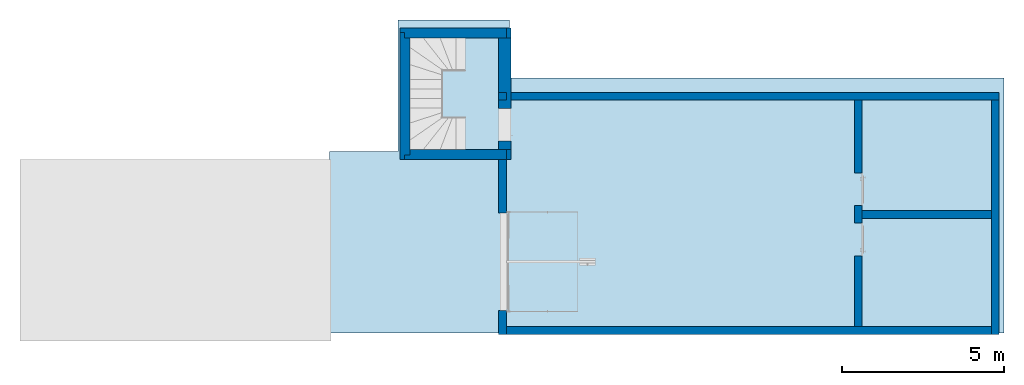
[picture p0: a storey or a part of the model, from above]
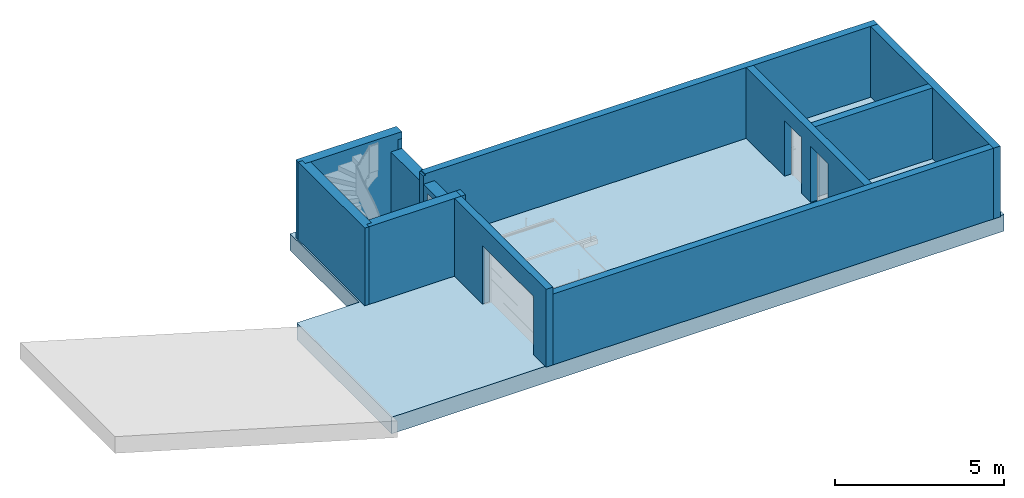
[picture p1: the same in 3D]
Properties of the parts of a building model (IFC4), part 1 of 13

# File
Description: ViewDefinition [Reference_View, SurfaceGeometryAddOnView, QuantityTakeOffAddOnView, SpaceBoundary2ndLevelAddOnView], Option [Drawing Scale: 100.000000], Option [Global Unique Identifiers (GUID): Keep existing], Option [Elements to export: Visible elements (on all stories)], Option [Partial Structure Display: Entire Model], Option [IFC Domain: All], Option [Structural Function: All Elements], Option [Convert Grid elements: On], Option [Convert IFC Annotations and ARCHICAD 2D elements: Off], Option [Convert 2D symbols of Doors and Windows: Off], Option [Explode Composite and Complex Profile elements into parts: Off], Option [Export geometries that Participates in Collision Detection only: On], Option [Triangulate Surfaces: On], Option [Use legacy geometric methods as in Coordination View 1.0: Off], Option [IFC Site Geometry: As boundary representation (BRep)], Option [IFC Site Location: At Project Origin], Option [Curtain Wall export mode: Single Element], Option [Railing export mode: Single Element], Option [Stair export mode: Single Element], Option [Properties To Export: All properties], Option [Space containment: On], Option [IFC Domain For Space Containment: All], Option [Bounding Box: Off], Option [Geometry to type objects: Off], Option [Element Properties: All], Option [Building Material Properties: On], Option [Element Parameters: All], Option [Component Parameters: All], Option [IFC Base Quantities: On], Option [Door Window Parameters: On], Option [IFC Space boundaries: On], Option [ARCHICAD Zone Categories as IFC Space classification data: On], Option [Element Classifications: On]
File name: C:\Users\andrev\sciebo\Research\Modelldummies CORE-RUB\2019-11-27_HVNL_Archicad_plaziert_AV_V15.ifc
Time: 2020-08-10T08:01:26
Author: Wegner L
Organization: Core architecture
Written by: The EXPRESS Data Manager Version 5.02.0100.09 : 26 Sep 2013
Made in: IFC file generated by GRAPHISOFT ARCHICAD-64 22.0.0 GER FULL Windows version (IFC add-on version: 7000 GER FULL).
Authorization: Wegner L

# IfcProject, Haus vom Nikolaus
Description: Büro Austauschprojekt
BauantragAllgemein - Bezeichnung des Bauvorhabens: Haus vom Nikolaus; Art des Gebäudes: 6122; Sonderbau: 23; Gebäudeklasse: 3; Art der Maßnahme: 1; Bauweise: 2

# IfcSite, Gelände
RefLatitude: 53, 33, 57, 464000; RefLongitude: 10, 5, 52, 995000; RefElevation: 16 m
BauantragGeokodierung - Flure: 0; Flurstücke: 0; Gemarkungen: keine
BaseQuantities - GrossPerimeter: 0 m; GrossArea: 0 m2

# IfcBuilding, Haus vom Nikolaus
Description: Zweifamilienhaus
BaseQuantities - GrossFloorArea: 2665.17 m2

# IfcBuildingStorey (3)
In: Haus vom Nikolaus
Name | Elevation (m) | NetHeight (m) = GrossHeight (m) = Height (m) | GrossFloorArea (m2)
-1. Geschoss | -2.8 | 2.8 | 1183.27
EG | 0 | 3.75 | 1047.56
1. OG | 3.75 | 2.55 | 434.338

# IfcSpace: Brutto-Grundfläche Regelfall (15)
Classification: Raum (ARCHICAD Klassifizierung); 0 BGFr Brutto-Grundfläche Regelfall
Pset_SpaceCommon - Category: Brutto-Grundfläche Regelfall
ArchiCADProperties - Bibliothekselement-Name: Raumstempel DIN 22; Geschützt: no; Typ: Raum; Oberfläche (Alle): Raumstempel; Deckschraffur: Misch-Schraffur 0%; Anzeigen auf Umbau-Filter: Alle relevanten Filter; Umbau-Status: Bestand; Oberfläche: Raumstempel; Einheitliche Oberfläche: yes; Raumkategorie: 0; Raumflächen-Code: 0 BGFr; ARCHICAD Klassifizierung - 22: Raum
AC_Pset_Raumstempel_DIN_22 - Textstil 1 (Grundeinstellung): 0; Markertext 1 Zeilenabstand (Standard): 1; Markertext 1 Zeichenbreite-Faktor (Standard): 1; Markertext 1 Textzeichenbreite-Faktor (Standard): 1; Schriftart 1: Arial Westlich; Wandabzugsfläche: 0; Fassaden- Abzugsfläche: 0; Stützenabzugsfläche: 0; Schraffurabzugsfläche: 0; Abzugsfläche unter Dach: 0; Gesamtabzugsfläche: 0; Raumfläche Faktor: 1; Dach Oberflächenbereich an der Oberseite: 0; Dach Oberflächenbereich an der Unterseite: 0; Decke Oberflächenbereich an der Oberseite: 0; Decke Oberflächenbereich an der Unterseite: 0; Unterzug Oberflächenbereich an der Oberseite: 0; Unterzugoberfläche unten: 0; Oberer Oberflächenbereich der Wandeinsätze: 0; Oberfläche Wandnischen hinten: 0; Seite Oberflächenbereich der Wandeinsätze: 0; Maßstab (displayScale): 1:100; Maßstab (iDisplayScale): 2; Raumname zeigen (bShowZoneNameLine1_50): yes; Raumnummer zeigen (bShowZoneNum_50): yes; Raumkategorie-Code zeigen (bShowZoneCatCode_50): no; 2. Raumnamen-Zeile zeigen (bShowZoneNameLine2_50): no; Einheitennummer zeigen (bShowApartmentID_50): yes; Einheitenname zeigen (bShowApartmentName_50): yes; Zeige Apartment Identifikation (bShowApartmentCode_50): no; Zeige Treppenhaus Identifikatoren (bShowStaircaseCode_50): no; Position zeigen (bShowPosition_50): no; Hausnummer zeigen (bShowHouseNumber_50): no; Funktion zeigen (bShowFunctions_50): no; ID zeigen (bShowID_50): no; Wandbelag zeigen (bShowWallFinish_50): no; Raumunterkante zeigen (bShowHeightZone_50): yes; Fertigfußbodenhöhe zeigen (bShowHeightFloor_50): yes; Abzugsflächen zeigen (bShowMeasuredArea_50): no; Gemessene Nettofläche zeigen (bShowMeasuredNetArea_50): yes; DIN Abzugsflächen zeigen (bShowVentArea_50): no; Reduzierte Fläche zeigen (bShowReducedArea_50): no; Berechnete Fläche (NRF) zeigen (bShowCalculatedArea_50): yes; Fensterflächen zeigen (bShowWindowArea_50): no; Raumumfang zeigen (bShowPerimeter_50): no; Raumhöhe zeigen (bShowCeilingHeight_50): yes; Raumvolumen zeigen (bShowVolume_50): no; Einordnung zeigen (bShowClassification_50): no; Eigenen Text zeigen 1 (bShowCustom1_50): no; Eigenen Text zeigen 2 (bShowCustom2_50): no; Eigenen Text zeigen 3 (bShowCustom3_50): no; Klassifizierung und Eigenschaften anzeigen (bShowAdditionalTags_50): yes; Parameter auswählen (iTnCSelectParams_50): 1; Daten darstellen nach (iTncDisplayData_50): 1; 1. Zeile Parameternamen zeigen als (iRow1CustomName_50): 1; 2. Zeile Parameternamen zeigen als (iRow2CustomName_50): 1; 3. Zeile Parameternamen zeigen als (iRow3CustomName_50): 1; 4. Zeile Parameternamen zeigen als (iRow4CustomName_50): 1; 5. Zeile Parameternamen zeigen als (iRow5CustomName_50): 1; 6. Zeile Parameternamen zeigen als (iRow6CustomName_50): 1; 7. Zeile Parameternamen zeigen als (iRow7CustomName_50): 1; 8. Zeile Parameternamen zeigen als (iRow8CustomName_50): 1; 9. Zeile Parameternamen zeigen als (iRow9CustomName_50): 1; 10. Zeile Parameternamen zeigen als (iRow10CustomName_50): 1; 11. Zeile Parameternamen zeigen als (iRow11CustomName_50): 1; 12. Zeile Parameternamen zeigen als (iRow12CustomName_50): 1; 13. Zeile Parameternamen zeigen als (iRow13CustomName_50): 1; 14. Zeile Parameternamen zeigen als (iRow14CustomName_50): 1; 15. Zeile Parameternamen zeigen als (iRow15CustomName_50): 1; 16. Zeile Parameternamen zeigen als (iRow16CustomName_50): 1; 17. Zeile Parameternamen zeigen als (iRow17CustomName_50): 1; 18. Zeile Parameternamen zeigen als (iRow18CustomName_50): 1; 19. Zeile Parameternamen zeigen als (iRow19CustomName_50): 1; 20. Zeile Parameternamen zeigen als (iRow20CustomName_50): 1; Inhalt zum Überschreiben (iContentToOverride_50): 1; Raumname Stift (penTitle_50): Elemente+Text; Raumname Stift (penTitle_50_int): 1; Überschreiben Titel 2 Textformat (bOverrideTitle2TextFormat_50): no; Raumnummer Font Größe (mm) (fontTitle2SizePaper_50): 2.5; Raumnummer Font-Stil (iTextStyleTitle2_50): 0; Raumnummer Stift (penTitle2_50_int): 1; Überschreiben Daten-Textformat (bOverrideDataTextFormat_50): no; Daten-Schrifttyp (iTextStyleData_50): 0; Daten-Stift (penData_50_int): 1; Schriftgröße (fontScaleType_50): Papiergröße; Schriftgröße (iFontScaleType_50): 2; Automat. Zeilenabstand (bAutomaticLineSpace_50): yes; Zeilenabstand in mm (lineSpacing_50): 4; Bemaßungseinheiten zeigen (bShowDimensionUnits_50): yes; Hochgestellt (bShowSuperScript_50): yes; Rahmen Stil (sFrameStyle_50): Stil 4; Rahmen Stil (iFrameStyle_50): 5; Feste Breite (bFixWidth_50): no; Breite in mm speichern (fixWidth_50): 50; Numerische Werte ausrichten (sAlignNumericalValues_50): Rechtsbündig; Numerische Werte ausrichten (iAlignNumericalValues_50): 4; Textwerte ausrichten (iAlignStringValues_50): 4; Raumnummer ausrichten (iAlignZoneNr_50): 1; Fester Radius (bFixRadius_50): no; Kreisrahmen Radius in mm (frameRadius_50): 3; Rahmen-Stift (framePen_50): Elemente+Text; Linientyp Rahmen (frameLineType_50): 1; Einheitennummer Rahmen (apartmentIdFrame_50): Oval; Einheitennummer Rahmen (iApartmentIdFrame_50): 2; Hintergrundschraffur (bBackFill_50): yes; Schraffur (fillType_50): Nur Hintergrund-Stift; Schraffur-Vordergrundstift (fillPen_50): Elemente+Text; Schraffur-Hintergrundstift (fillBackPen_50): Transparent; Einheitennummer Winkel in 1:50: 0 deg; Höhenwerte und Raumnummer Anzeigetyp (iDisplayType_50): 2; 1. (order_01_50): Raumname; 1. (iOrder_01_50): 2; 4. (order_04_50): Beläge; 4. (iOrder_04_50): 6; 12. (order_12_50): ** Leere Zeile; 12. (iOrder_12_50): 1; Raumname zeigen (bShowZoneNameLine1_100): yes; Raumnummer zeigen (bShowZoneNum_100): yes; Raumkategorie-Code zeigen (bShowZoneCatCode_100): no; Zeige Apartment Identifikation (bShowApartmentCode_100): no; Zeige Treppenhaus Identifikatoren (bShowStaircaseCode_100): no; Position zeigen (bShowPosition_100): no; Hausnummer zeigen (bShowHouseNumber_100): no; Funktion zeigen (bShowFunctions_100): no; ID zeigen (bShowID_100): no; Bodenbelag zeigen (bShowFloor_100): no; Wandbelag zeigen (bShowWallFinish_100): no; Deckenbelag zeigen (bShowCeiling_100): no; Raumunterkante zeigen (bShowHeightZone_100): no; Fertigfußbodenhöhe zeigen (bShowHeightFloor_100): no; Abzugsflächen zeigen (bShowMeasuredArea_100): no; Gemessene Nettofläche zeigen (bShowMeasuredNetArea_100): no; DIN Abzugsflächen zeigen (bShowVentArea_100): no; Reduzierte Fläche zeigen (bShowReducedArea_100): no; Berechnete Fläche (NRF) zeigen (bShowCalculatedArea_100): yes; Fensterflächen zeigen (bShowWindowArea_100): no; Raumumfang zeigen (bShowPerimeter_100): no; Raumhöhe zeigen (bShowCeilingHeight_100): no; Raumvolumen zeigen (bShowVolume_100): no; Einordnung zeigen (bShowClassification_100): no; Eigenen Text zeigen 1 (bShowCustom1_100): no; Eigenen Text zeigen 2 (bShowCustom2_100): no; Eigenen Text zeigen 3 (bShowCustom3_100): no; Parameter auswählen (iTnCSelectParams_100): 1; Daten darstellen nach (iTncDisplayData_100): 1; 1. Zeile Parameternamen zeigen als (iRow1CustomName_100): 1; 2. Zeile Parameternamen zeigen als (iRow2CustomName_100): 1; 3. Zeile Parameternamen zeigen als (iRow3CustomName_100): 1; 4. Zeile Parameternamen zeigen als (iRow4CustomName_100): 1; 5. Zeile Parameternamen zeigen als (iRow5CustomName_100): 1; 6. Zeile Parameternamen zeigen als (iRow6CustomName_100): 1; 7. Zeile Parameternamen zeigen als (iRow7CustomName_100): 1; 8. Zeile Parameternamen zeigen als (iRow8CustomName_100): 1; 9. Zeile Parameternamen zeigen als (iRow9CustomName_100): 1; 10. Zeile Parameternamen zeigen als (iRow10CustomName_100): 1; 11. Zeile Parameternamen zeigen als (iRow11CustomName_100): 1; 12. Zeile Parameternamen zeigen als (iRow12CustomName_100): 1; 13. Zeile Parameternamen zeigen als (iRow13CustomName_100): 1; 14. Zeile Parameternamen zeigen als (iRow14CustomName_100): 1; 15. Zeile Parameternamen zeigen als (iRow15CustomName_100): 1; 16. Zeile Parameternamen zeigen als (iRow16CustomName_100): 1; 17. Zeile Parameternamen zeigen als (iRow17CustomName_100): 1; 18. Zeile Parameternamen zeigen als (iRow18CustomName_100): 1; 19. Zeile Parameternamen zeigen als (iRow19CustomName_100): 1; 20. Zeile Parameternamen zeigen als (iRow20CustomName_100): 1; Inhalt zum Überschreiben (iContentToOverride_100): 1; Raumname Stift (penTitle_100): Elemente+Text; Raumname Stift (penTitle_100_int): 1; Überschreiben Titel 2 Textformat (bOverrideTitle2TextFormat_100): no; Raumnummer Font Typ (fontTitle2Type_100): Arial; Raumnummer Font Größe (mm) (fontTitle2SizePaper_100): 2.5; Raumnummer Font-Stil (iTextStyleTitle2_100): 0; Raumnummer Stift (penTitle2_100_int): 1; Überschreiben Daten-Textformat (bOverrideDataTextFormat_100): no; Daten-Schrifttyp (iTextStyleData_100): 0; Daten-Stift (penData_100_int): 1; Schriftgröße (fontScaleType_100): Papiergröße; Schriftgröße (iFontScaleType_100): 2; Automat. Zeilenabstand (bAutomaticLineSpace_100): yes; Zeilenabstand in mm (lineSpacing_100): 4; Bemaßungseinheiten zeigen (bShowDimensionUnits_100): yes; Hochgestellt (bShowSuperScript_100): yes; Rahmen Stil (sFrameStyle_100): Stil 4; Rahmen Stil (iFrameStyle_100): 5; Feste Breite (bFixWidth_100): no; Breite in mm speichern (fixWidth_100): 30; Numerische Werte ausrichten (sAlignNumericalValues_100): Rechtsbündig; Numerische Werte ausrichten (iAlignNumericalValues_100): 4; Textwerte ausrichten (iAlignStringValues_100): 4; Höhenwert ausrichten (iAlignHeightValue_100): 1; Raumnummer ausrichten (iAlignZoneNr_100): 1; Fester Radius (bFixRadius_100): no; Kreisrahmen Radius in mm (frameRadius_100): 3; Rahmen-Stift (framePen_100): Elemente+Text; Linientyp Rahmen (frameLineType_100): 1; Einheitennummer Rahmen (apartmentIdFrame_100): Oval; Einheitennummer Rahmen (iApartmentIdFrame_100): 2; Hintergrundschraffur (bBackFill_100): yes; Schraffur (fillType_100): Nur Hintergrund-Stift; Schraffur-Vordergrundstift (fillPen_100): Elemente+Text; Schraffur-Hintergrundstift (fillBackPen_100): Transparent; Einheitennummer Winkel in 1:100: 0 deg; 1. (order_01_100): Raumname; 1. (iOrder_01_100): 2; 11. (order_11_100): Klassifizierung und Eigenschaften; 11. (iOrder_11_100): 14; Raumname zeigen (bShowZoneNameLine1_200): yes; Raumnummer zeigen (bShowZoneNum_200): no; Raumkategorie-Code zeigen (bShowZoneCatCode_200): no; 2. Raumnamen-Zeile zeigen (bShowZoneNameLine2_200): no; Einheitennummer zeigen (bShowApartmentID_200): yes; Einheitenname zeigen (bShowApartmentName_200): no; Zeige Apartment Identifikation (bShowApartmentCode_200): no; Zeige Treppenhaus Identifikatoren (bShowStaircaseCode_200): no; Position zeigen (bShowPosition_200): no; Hausnummer zeigen (bShowHouseNumber_200): no; Funktion zeigen (bShowFunctions_200): no; ID zeigen (bShowID_200): no; Bodenbelag zeigen (bShowFloor_200): no; Wandbelag zeigen (bShowWallFinish_200): no; Deckenbelag zeigen (bShowCeiling_200): no; Raumunterkante zeigen (bShowHeightZone_200): no; Fertigfußbodenhöhe zeigen (bShowHeightFloor_200): no; Abzugsflächen zeigen (bShowMeasuredArea_200): no; Gemessene Nettofläche zeigen (bShowMeasuredNetArea_200): no; DIN Abzugsflächen zeigen (bShowVentArea_200): no; Reduzierte Fläche zeigen (bShowReducedArea_200): no; Berechnete Fläche (NRF) zeigen (bShowCalculatedArea_200): yes; Fensterflächen zeigen (bShowWindowArea_200): no; Raumumfang zeigen (bShowPerimeter_200): no; Raumhöhe zeigen (bShowCeilingHeight_200): no; Raumvolumen zeigen (bShowVolume_200): no; Einordnung zeigen (bShowClassification_200): no; Eigenen Text zeigen 1 (bShowCustom1_200): no; Eigenen Text zeigen 2 (bShowCustom2_200): no; Eigenen Text zeigen 3 (bShowCustom3_200): no; Klassifizierung und Eigenschaften anzeigen (bShowAdditionalTags_200): no; Parameter auswählen (iTnCSelectParams_200): 1; Daten darstellen nach (iTncDisplayData_200): 1; 1. Zeile Parameternamen zeigen als (iRow1CustomName_200): 1; 2. Zeile Parameternamen zeigen als (iRow2CustomName_200): 1; 3. Zeile Parameternamen zeigen als (iRow3CustomName_200): 1; 4. Zeile Parameternamen zeigen als (iRow4CustomName_200): 1; 5. Zeile Parameternamen zeigen als (iRow5CustomName_200): 1; 6. Zeile Parameternamen zeigen als (iRow6CustomName_200): 1; 7. Zeile Parameternamen zeigen als (iRow7CustomName_200): 1; 8. Zeile Parameternamen zeigen als (iRow8CustomName_200): 1; 9. Zeile Parameternamen zeigen als (iRow9CustomName_200): 1; 10. Zeile Parameternamen zeigen als (iRow10CustomName_200): 1; 11. Zeile Parameternamen zeigen als (iRow11CustomName_200): 1; 12. Zeile Parameternamen zeigen als (iRow12CustomName_200): 1; 13. Zeile Parameternamen zeigen als (iRow13CustomName_200): 1; 14. Zeile Parameternamen zeigen als (iRow14CustomName_200): 1; 15. Zeile Parameternamen zeigen als (iRow15CustomName_200): 1; 16. Zeile Parameternamen zeigen als (iRow16CustomName_200): 1; 17. Zeile Parameternamen zeigen als (iRow17CustomName_200): 1; 18. Zeile Parameternamen zeigen als (iRow18CustomName_200): 1; 19. Zeile Parameternamen zeigen als (iRow19CustomName_200): 1; 20. Zeile Parameternamen zeigen als (iRow20CustomName_200): 1; Inhalt zum Überschreiben (iContentToOverride_200): 1; Raumname Stift (penTitle_200): Elemente+Text; Raumname Stift (penTitle_200_int): 1; Raumnummer Font Typ (fontTitle2Type_200): Arial; Raumnummer Font-Stil (iTextStyleTitle2_200): 0; Raumnummer Stift (penTitle2_200_int): 1; Überschreiben Daten-Textformat (bOverrideDataTextFormat_200): no; Daten-Schrifttyp (iTextStyleData_200): 0; Daten-Stift (penData_200_int): 1; Schriftgröße (fontScaleType_200): Papiergröße; Schriftgröße (iFontScaleType_200): 2; Automat. Zeilenabstand (bAutomaticLineSpace_200): yes; Zeilenabstand in mm (lineSpacing_200): 4; Bemaßungseinheiten zeigen (bShowDimensionUnits_200): yes; Hochgestellt (bShowSuperScript_200): yes; Rahmen Stil (sFrameStyle_200): Keine; Rahmen Stil (iFrameStyle_200): 1; Feste Breite (bFixWidth_200): no; Breite in mm speichern (fixWidth_200): 30; Numerische Werte ausrichten (sAlignNumericalValues_200): Rechtsbündig; Numerische Werte ausrichten (iAlignNumericalValues_200): 4; Textwerte ausrichten (iAlignStringValues_200): 4; Höhenwert ausrichten (iAlignHeightValue_200): 1; Raumnummer ausrichten (iAlignZoneNr_200): 1; Fester Radius (bFixRadius_200): no; Kreisrahmen Radius in mm (frameRadius_200): 3; Rahmen-Stift (framePen_200): Elemente+Text; Linientyp Rahmen (frameLineType_200): 1; Einheitennummer Rahmen (apartmentIdFrame_200): Oval; Einheitennummer Rahmen (iApartmentIdFrame_200): 2; Hintergrundschraffur (bBackFill_200): yes; Schraffur (fillType_200): Nur Hintergrund-Stift; Schraffur-Vordergrundstift (fillPen_200): Elemente+Text; Schraffur-Hintergrundstift (fillBackPen_200): Transparent; Einheitennummer Winkel in 1:200: 0 deg; Höhenwerte und Raumnummer Anzeigetyp (iDisplayType_200): 1; 1. (order_01_200): Raumname; 1. (iOrder_01_200): 2; 11. (order_11_200): Klassifizierung und Eigenschaften; 11. (iOrder_11_200): 14; Raumname zeigen (bShowZoneNameLine1_0): yes; Raumkategorie-Code zeigen (bShowZoneCatCode_0): no; 2. Raumnamen-Zeile zeigen (bShowZoneNameLine2_0): no; Einheitennummer zeigen (bShowApartmentID_0): no; Einheitenname zeigen (bShowApartmentName_0): no; Zeige Apartment Identifikation (bShowApartmentCode_0): no; Zeige Treppenhaus Identifikatoren (bShowStaircaseCode_0): no; Position zeigen (bShowPosition_0): no; Hausnummer zeigen (bShowHouseNumber_0): no; Funktion zeigen (bShowFunctions_0): no; ID zeigen (bShowID_0): no; Bodenbelag zeigen (bShowFloor_0): no; Wandbelag zeigen (bShowWallFinish_0): no; Deckenbelag zeigen (bShowCeiling_0): no; Raumunterkante zeigen (bShowHeightZone_0): no; Fertigfußbodenhöhe zeigen (bShowHeightFloor_0): no; Abzugsflächen zeigen (bShowMeasuredArea_0): no; Gemessene Nettofläche zeigen (bShowMeasuredNetArea_0): no; DIN Abzugsflächen zeigen (bShowVentArea_0): no; Reduzierte Fläche zeigen (bShowReducedArea_0): no; Fensterflächen zeigen (bShowWindowArea_0): no; Raumumfang zeigen (bShowPerimeter_0): no; Raumvolumen zeigen (bShowVolume_0): no; Einordnung zeigen (bShowClassification_0): no; Eigenen Text zeigen 1 (bShowCustom1_0): no; Eigenen Text zeigen 2 (bShowCustom2_0): no; Eigenen Text zeigen 3 (bShowCustom3_0): no; Parameter auswählen (iTnCSelectParams_0): 1; Daten darstellen nach (iTncDisplayData_0): 1; 1. Zeile Parameternamen zeigen als (iRow1CustomName_0): 1; 2. Zeile Parameternamen zeigen als (iRow2CustomName_0): 1; 3. Zeile Parameternamen zeigen als (iRow3CustomName_0): 1; 4. Zeile Parameternamen zeigen als (iRow4CustomName_0): 1; 5. Zeile Parameternamen zeigen als (iRow5CustomName_0): 1; 6. Zeile Parameternamen zeigen als (iRow6CustomName_0): 1; 7. Zeile Parameternamen zeigen als (iRow7CustomName_0): 1; 8. Zeile Parameternamen zeigen als (iRow8CustomName_0): 1; 9. Zeile Parameternamen zeigen als (iRow9CustomName_0): 1; 10. Zeile Parameternamen zeigen als (iRow10CustomName_0): 1; 11. Zeile Parameternamen zeigen als (iRow11CustomName_0): 1; 12. Zeile Parameternamen zeigen als (iRow12CustomName_0): 1; 13. Zeile Parameternamen zeigen als (iRow13CustomName_0): 1; 14. Zeile Parameternamen zeigen als (iRow14CustomName_0): 1; 15. Zeile Parameternamen zeigen als (iRow15CustomName_0): 1; 16. Zeile Parameternamen zeigen als (iRow16CustomName_0): 1; 17. Zeile Parameternamen zeigen als (iRow17CustomName_0): 1; 18. Zeile Parameternamen zeigen als (iRow18CustomName_0): 1; 19. Zeile Parameternamen zeigen als (iRow19CustomName_0): 1; 20. Zeile Parameternamen zeigen als (iRow20CustomName_0): 1; Inhalt zum Überschreiben (iContentToOverride_0): 1; Raumname Schriftgröße (mm) (fontTitleSizePaper_0): 2.5; Raumnummer Font Größe (mm) (fontTitle2SizePaper_0): 2.5; Raumnummer Font-Stil (iTextStyleTitle2_0): 0; Raumnummer Stift (penTitle2_0_int): 1; Daten-Schrifttyp (iTextStyleData_0): 0; Daten-Stift (penData_0_int): 1; Schriftgröße (fontScaleType_0): Papiergröße; Schriftgröße (iFontScaleType_0): 2; Automat. Zeilenabstand (bAutomaticLineSpace_0): yes; Zeilenabstand in mm (lineSpacing_0): 4; Bemaßungseinheiten zeigen (bShowDimensionUnits_0): yes; Hochgestellt (bShowSuperScript_0): yes; Rahmen Stil (sFrameStyle_0): Stil 4; Rahmen Stil (iFrameStyle_0): 5; Feste Breite (bFixWidth_0): no; Numerische Werte ausrichten (iAlignNumericalValues_0): 4; Höhenwert ausrichten (iAlignHeightValue_0): 1; Raumnummer ausrichten (iAlignZoneNr_0): 1; Fester Radius (bFixRadius_0): no; Kreisrahmen Radius in mm (frameRadius_0): 3; Rahmen-Stift (framePen_0): Elemente+Text; Linientyp Rahmen (frameLineType_0): 1; Einheitennummer Rahmen (apartmentIdFrame_0): Oval; Einheitennummer Rahmen (iApartmentIdFrame_0): 2; Hintergrundschraffur (bBackFill_0): yes; Schraffur (fillType_0): Nur Hintergrund-Stift; Schraffur-Vordergrundstift (fillPen_0): Elemente+Text; Schraffur-Hintergrundstift (fillBackPen_0): Transparent; Einheitennummer Winkel: 0 deg; 1. (order_01_0): Raumname; 1. (iOrder_01_0): 2; 2. (order_02_0): Einheitennummer; 2. (iOrder_02_0): 4; 3. (order_03_0): Einheitenname; 3. (iOrder_03_0): 5; 4. (order_04_0): Beläge; 4. (iOrder_04_0): 6; 12. (order_12_0): ** Leere Zeile; 12. (iOrder_12_0): 1; Kategorie als Name verwenden: no; Position: <Position>; Hausnummer: <Hausnummer>; Bezeichnung Wandbelag: WB; Berechnet OK Fertigfußboden: yes; Eigene OK Fertigfußboden: ±0.00; Präfix OK Fertigfussboden (sPrefixFloorLevel): Marker; Präfix OK Fertigfussboden (iPrefixFloorLevel): 1; Fertigfußbodenhöhe Titel: FFB; Marker für Fertigfußboden: 1; Berechnet OK Rohfußboden: yes; Eigene Rohfußboden OK: -0.10; Höhenlage Raum Präfix (sPrefixZoneLevel): Marker; Höhenlage Raum Präfix (iPrefixZoneLevel): 1; Raumunterkante Betzeichnung: RUK; Marker für Unterboden: 3; Zeichen Schraffur: Nur Hintergrund-Stift; Zeichen Schraffur-Vordergrundstift: Elemente+Text; Untergeordneter Schraffur: Nur Vordergrund-Stift; Abzugsflächen Kürzel: AF; Reduzierte Fläche Kürzel: RF; Fensterfläche Kürzel: FF; Raumhöhe Kürzel: RH; Raumvolumen Kürzel: RV; Abzug gemäß WoFlV: no; Abzug in % (Balkone, Loggien): 0; Putzabzug: 0; Bereich: R; Flächencode Titel: Bereich; Einheiten Zuordnung: 1; Zeige Apartment Identifikation Präfix: no; Treppenhaus Zuordnung: 1; Haus Zuordnung (iHouseCode): 1; Haus Zuordnung (asAddOn_stHouseCode): <Hausnummer>; Position Zuordnung (iPositionCode): 1; Position Zuordnung (asAddOn_stPositionCode): <Position>; Preis per m2: 0; Preis per m3: 0; Preis berechnet aus gemessener Fläche: 0; Preis berechnet aus gemessener Nettofläche: 0; Preis berechnet aus Reduzierte Fläche: 0; Preis berechnet aus berechneter Fläche (NRF): 0; Preis berechnet aus Nettovolumen: 0; Preis berechnet aus Bruttovolumen: 0; Drehwinkel: 0 deg
ArchiCADQuantities - Grundriss-Durchbruch Umfang: 0 m; Anzahl der Stützen: 0; Anzahl der Lichtquelle: 0; Raumflächen Reduzierung: 1 m2; Stützenabzugsfläche: 0 m2; Schraffurabzugsfläche: 0 m2; Niedrige Abzugsfläche: 0 m2; Wandabzugsfläche: 0 m2; Gesamtabzugsfläche: 0 m2; Heizkörpernische Oberflächenbereich hinten: 0 m2; Heizkörpernische Oberflächenbereich seitlich: 0 m2; Heizkörpernische Oberflächenbereich oben: 0 m2
AC_Equantity_Raumstempel_DIN_22 - Gesamtlänge aller Bodenkanten: 0 m; Raumname Schriftgröße (modell) (fontTitleSizeModel_50): 0.25 m; X Distanz in 1:50: 0 m; Y Distanz in 1:50: 0 m; Einheitennummer Position (X) in 1:50: 0 m; Einheitennummer Position (Y) in 1:50: 0 m; Raumname Schriftgröße (modell) (fontTitleSizeModel_100): 0.25 m; X Distanz in 1:100: 0 m; Y Distanz in 1:100: 0 m; Einheitennummer Position (X) in 1:100: 0 m; Einheitennummer Position (Y) in 1:100: 0 m; Raumname Schriftgröße (modell) (fontTitleSizeModel_200): 0.25 m; X Distanz in 1:200: 0 m; Y Distanz in 1:200: 0 m; Einheitennummer Position (X) in 1:200: 0 m; Einheitennummer Position (Y) in 1:200: 0 m; Raumname Schriftgröße (modell) (fontTitleSizeModel_0): 0.25 m; X Abstand: 0 m; Y Abstand: 0 m; Einheitennummer Position (X): 0 m; Einheitennummer Position (Y): 0 m
Name | In | LongName = Zugehöriger Raumname = ArchiCADProperties, Raumname = AC_Pset_Raumstempel_DIN_22, Raumname | Element ID = Hotlink und Element-ID = Überobjekt-ID | Ebene | Kollidierende Räume | Zugehörige Raumnummer = ArchiCADProperties, Raumnummer = AC_Pset_Raumstempel_DIN_22, Raumnummer | Ursprungsgeschoss Name | Ursprungsgeschoss Nummer | Absolutes Geschoss für Oberkantenverknüpfung | Relatives Geschoss für Oberkantenverknüpfung | Geschoss für Oberkantenverknüpfung | Reduzierte Fläche = AC_Pset_Raumstempel_DIN_22, Gemessene Fläche = AC_Pset_Raumstempel_DIN_22, Gemessene Nettofläche = Reduzierte Fläche (ROOM_REDUCED_AREA) = AC_Pset_Raumstempel_DIN_22, Berechnete Fläche (NRF) = Oberer Oberflächenbereich = Unterer Oberflächenbereich = DIN berechnete Fläche = Reduzierte Fläche (room_calc_area_reduced) = GrossFloorArea (m2) = NetFloorArea (m2) = SpaceNetFloorAreaBOMA (m2) = SpaceUsableFloorAreaBOMA (m2) = GrossCeilingArea (m2) = NetCeilingArea (m2) = Fläche (m2) = ArchiCADQuantities, Berechnete Fläche (NRF) (m2) = ArchiCADQuantities, Gemessene Fläche (m2) = ArchiCADQuantities, Gemessene Nettofläche (m2) | Schriftgröße 1 (Grundeinstell.) = Raumname Schriftgröße (mm) (fontTitleSizePaper_50) = Raumname Schriftgröße (mm) (fontTitleSizePaper_100) = Raumname Schriftgröße (mm) (fontTitleSizePaper_200) | Markertext 1 Ausrichtung (Standard) = Höhenwerte und Raumnummer Anzeigetyp (iDisplayType_100) = Raumname Stift (penTitle_0_int) | Stift Text (Grundeinstellung) | Anzahl aller Raumecken = Anzahl der Ecken | Anzahl hereinragender Raumecken = Anzahl der konkaven Ecken | Oberfläche Umfassungswände | Fläche der Türen | Fläche der Fenster | Raumvolumen = GrossVolume (m3) | Begrenzung Oberflächenbereich | Maßstabsabhängig = Raumnummer zeigen (bShowZoneNum_0) | Bodenbelag zeigen (bShowFloor_50) = Deckenbelag zeigen (bShowCeiling_50) | Überschreiben Titel-Textformat (bOverrideTitleTextFormat_50) = 2. Raumnamen-Zeile zeigen (bShowZoneNameLine2_100) = Klassifizierung und Eigenschaften anzeigen (bShowAdditionalTags_100) = Überschreiben Titel-Textformat (bOverrideTitleTextFormat_100) = Überschreiben Titel-Textformat (bOverrideTitleTextFormat_200) = Überschreiben Titel 2 Textformat (bOverrideTitle2TextFormat_200) = Überschreiben Titel-Textformat (bOverrideTitleTextFormat_0) = Überschreiben Titel 2 Textformat (bOverrideTitle2TextFormat_0) = Überschreiben Daten-Textformat (bOverrideDataTextFormat_0) | Raumname Schriftart (fontTitleType_50) = Raumnummer Font Typ (fontTitle2Type_50) = Daten Schriftart (fontDataType_50) = Raumname Schriftart (fontTitleType_100) = Daten Schriftart (fontDataType_100) = Raumname Schriftart (fontTitleType_200) = Daten Schriftart (fontDataType_200) = Raumname Schriftart (fontTitleType_0) = Raumnummer Font Typ (fontTitle2Type_0) = Daten Schriftart (fontDataType_0) | Raumname Font-Stil (iTextStyleTitle_50) = Raumname Stil = Raumname Font-Stil (iTextStyleTitle_200) = Raumname Font-Stil (iTextStyleTitle_0) | Raumnummer Stift (penTitle2_50) = Daten-Stift (penData_50) = Raumnummer Stift (penTitle2_100) = Daten-Stift (penData_100) = Raumnummer Stift (penTitle2_200) = Daten-Stift (penData_200) = Raumname Stift (penTitle_0) = Raumnummer Stift (penTitle2_0) = Daten-Stift (penData_0) = Untergeordneter Schraffur-Vordergrundstift | Schriftgröße Daten (mm) (fontDataSizePaper_50) = Schriftgröße Daten (mm) (fontDataSizePaper_100) = Schriftgröße Daten (mm) (fontDataSizePaper_0) | Höhenwert ausrichten (iAlignHeightValue_50) | Anzahl der Reihen (nOrder_50) | 2. (order_02_50) | 2. (iOrder_02_50) | 3. (order_03_50) | 3. (iOrder_03_50) | 5. (order_05_50) | 5. (iOrder_05_50) | 6. (order_06_50) | 6. (iOrder_06_50) | 7. (order_07_50) | 7. (iOrder_07_50) | 8. (order_08_50) = 9. (order_09_100) = 9. (order_09_200) | 8. (iOrder_08_50) = 9. (iOrder_09_100) = 9. (iOrder_09_200) | 9. (order_09_50) = 10. (order_10_100) = 10. (order_10_200) | 9. (iOrder_09_50) = 10. (iOrder_10_100) = 10. (iOrder_10_200) | 10. (order_10_50) | 10. (iOrder_10_50) | 11. (order_11_50) = 12. (order_12_100) = 12. (order_12_200) | 11. (iOrder_11_50) = 12. (iOrder_12_100) = 12. (iOrder_12_200) | Einheitennummer zeigen (bShowApartmentID_100) | Einheitenname zeigen (bShowApartmentName_100) | 1. Zeile (sIDRow1_100) | Anzahl der Reihen (nOrder_100) | 2. (order_02_100) | 2. (iOrder_02_100) | 3. (order_03_100) | 3. (iOrder_03_100) | 4. (order_04_100) | 4. (iOrder_04_100) | 5. (order_05_100) = 5. (order_05_200) | 5. (iOrder_05_100) = 5. (iOrder_05_200) | 6. (order_06_100) = 6. (order_06_200) | 6. (iOrder_06_100) = 6. (iOrder_06_200) | 7. (order_07_100) = 7. (order_07_200) | 7. (iOrder_07_100) = 7. (iOrder_07_200) | 8. (order_08_100) = 8. (order_08_200) | 8. (iOrder_08_100) = 8. (iOrder_08_200) | Raumnummer Font Größe (mm) (fontTitle2SizePaper_200) | Schriftgröße Daten (mm) (fontDataSizePaper_200) | Anzahl der Reihen (nOrder_200) | 2. (order_02_200) | 2. (iOrder_02_200) | 3. (order_03_200) | 3. (iOrder_03_200) | 4. (order_04_200) | 4. (iOrder_04_200) | Berechnete Fläche (NRF) zeigen (bShowCalculatedArea_0) | Raumhöhe zeigen (bShowCeilingHeight_0) | Klassifizierung und Eigenschaften anzeigen (bShowAdditionalTags_0) | Breite in mm speichern (fixWidth_0) | Textwerte ausrichten (iAlignStringValues_0) | Anzahl der Reihen (nOrder_0) | Höhenwerte und Raumnummer Anzeigetyp (iDisplayType_0) | 5. (order_05_0) | 5. (iOrder_05_0) | 6. (order_06_0) | 6. (iOrder_06_0) | 7. (order_07_0) | 7. (iOrder_07_0) | 8. (order_08_0) | 8. (iOrder_08_0) | 9. (order_09_0) | 9. (iOrder_09_0) | 10. (order_10_0) | 10. (iOrder_10_0) | 11. (order_11_0) | 11. (iOrder_11_0) | ID zeigen als... | Einheitennummer = Eigene Einheiten Zuordnung | Einheitenname | Bezeichnung Erschließung = Eigene Treppenhaus Identifikation | Bodenbelag Titel | Bodenbelag | Wandbelag Material | Deckenbelag Titel | Deckenbelag | Gemessene Fläche Kürzel | Gemessene Nettofläche Kürzel | Berechnete Fläche (NRF) Kürzel | Raumumfang Kürzel | DIN abgezogene Fläche | DWG-Export Typ | Fenster/Raum (%) | Height (m) = FinishCeilingHeight (m) = ClearHeight (m) = Höhe (m) = Raumhöhe (m) | FinishFloorHeight (m) = Fußbodendicke (m) = Stärke Bodenaufbau (m) | GrossWallArea (m2) | NetWallArea (m2) = Wand-Oberflächenbereich (m2) | GrossPerimeter (m) = NetPerimeter (m) = Raumflächen Nettoumfang (m) = Raum Brutto-Umfang (m) = Raumumfang (m) = Nettoumfang (m) | NetVolume (m3) = Netto-Volumen (m3) | Höhenangabe zum Projekt-Nullpunkt (m) = Höhe zu 1. Referenzhöhe (m) = Höhe zu 2. Referenzhöhe (m) = Raum zu 0,00 (m) | Höhe zu Meereshöhe (m) | Höhe zu verknüpftem/Ursprungsgeschoss (m) = Abstand zu Ursprungsgeschoss (m) = Basislevel (m) = Höhenkote OK Rohdecke (m) | Abstand Oberkante (m) | Anzahl der Unterzüge | Anzahl der Türen | Anzahl der Objekte | Anzahl der Fenster | Anzahl der Wandelemente | Fenster-Oberflächenbereich (m2) | Türen-Oberflächenbereich (m2) | Türen Breite (m) | Fenster Breite (m) | Wand Umfang (m) = Gesamtlänge Raumumfassung (m) | Summe Öffnungsbreite Türen (m) | Summe Öffnungsbreite Fenster (m) | Raumnummer Font Größe (Modell) (fontTitle2SizeModel_50) (m) = Daten Schriftgröße (modell) (fontDataSizeModel_50) (m) = Raumnummer Font Größe (Modell) (fontTitle2SizeModel_100) (m) = Daten Schriftgröße (modell) (fontDataSizeModel_100) (m) = Raumnummer Font Größe (Modell) (fontTitle2SizeModel_200) (m) = Daten Schriftgröße (modell) (fontDataSizeModel_200) (m) = Raumnummer Font Größe (Modell) (fontTitle2SizeModel_0) (m) = Daten Schriftgröße (modell) (fontDataSizeModel_0) (m) | Kreis Temp Radius (m)
R-015 | -1. Geschoss | Fahrradstellplatz | Raum-015 | Raum Ausbauraum | Untergeschoss UG | R-015 | -1. Geschoss | -1 | Nicht verknüpft | Nicht verknüpft | Nicht verknüpft | 13.39 | 2 | 2 | Elemente+Text | 4 | 0 | 59.5059 | 2.0301 | 0 | 34.1445 | 37.4723 | yes | no | yes | Arial Westlich | 1 | Schichttrennlinien/Kontur | 2.5 | 3 | 7 | Einheitenname | 5 | Einheitennummer | 4 | Raumflächen | 9 | Umfang, Höhe, Volumen | 11 | Klassifizierung und Eigenschaften | 14 | ** Leere Zeile | 1 | ** Leere Zeile | 1 | ** Leere Zeile | 1 | ** Leere Zeile | 1 | yes | yes | IFC.PSet.Pset_BauantragRäume.istNGF | 4 | Einheitenname | 5 | Raumflächen | 9 | Klassifizierung und Eigenschaften | 14 | ** Leere Zeile | 1 | ** Leere Zeile | 1 | ** Leere Zeile | 1 | ** Leere Zeile | 1 | 1.5 | 1.5 | 2 | Raumflächen | 9 | ** Leere Zeile | 1 | ** Leere Zeile | 1 | yes | no | no | 30 | 4 | 9 | 2 | Höhenwerte und Raumnummer | 8 | Raumflächen | 9 | Fensterfläche | 10 | Umfang, Höhe, Volumen | 11 | Flächencode | 12 | ** Leere Zeile | 1 | Klassifizierung und Eigenschaften | 14 | 1 | -1.02 | Haus | <Treppenhaus> | FB | <Fertigboden> | <Wandmaterial> | DB | <Material Deckenbelag> | B | BF | NGF | RU | 3.55271e-15 | Standardraum | 0 | 2.55 | 0 | 37.4723 | 35.4421 | 14.695 | 34.1445 | -2.8 | 13.2 | 0 | -0.25 | 0 | 1 | 0 | 0 | 4 | 0 | 2.0301 | 1.01 | 0 | 25.39 | 1.01 | 0 | 0.25 | 0.3 | Pset_SpaceCommon - ConcealedCeiling: no; ConcealedFlooring: no; BauantragRäume - istNGF: yes; istNebenfläche: yes; Pset_SpaceParking - ParkingUse: Fahrradstellplatz; ParkingUnits: 6; BauantragStellplätze - Art: FAHRRAD; Anzahl: 6; ArchiCADProperties - Verbundene 3D Element(e): Raum-024; Tür-002
R-024 | -1. Geschoss | Untergeschoss UG | Raum-024 | Bauantrag | Fahrradstellplatz; Garage; Gelände; Keller; Stellplatz; Stellplatz; Tiefgaragenabfahrt; Treppenhaus | R-024 | -1. Geschoss | -1 | Nicht verknüpft | Nicht verknüpft | Nicht verknüpft | 123.479 | 2 | 2 | Elemente+Text | 7 | 1 | 12.6694 | 8.3511 | 0 | 345.742 | 131.934 | yes | no | yes | Arial Westlich | 1 | Schichttrennlinien/Kontur | 2.5 | 3 | 7 | Einheitenname | 5 | Einheitennummer | 4 | Raumflächen | 9 | Umfang, Höhe, Volumen | 11 | Klassifizierung und Eigenschaften | 14 | ** Leere Zeile | 1 | ** Leere Zeile | 1 | ** Leere Zeile | 1 | ** Leere Zeile | 1 | no | yes | IFC.PSet.Pset_BauantragRäume.istBGF | 4 | Einheitenname | 5 | Raumflächen | 9 | Klassifizierung und Eigenschaften | 14 | ** Leere Zeile | 1 | ** Leere Zeile | 1 | ** Leere Zeile | 1 | ** Leere Zeile | 1 | 1.5 | 1.5 | 2 | Raumflächen | 9 | ** Leere Zeile | 1 | ** Leere Zeile | 1 | yes | yes | no | 30 | 4 | 10 | 1 | Raumnummer | 3 | Höhenwerte | 7 | Raumflächen | 9 | Fensterfläche | 10 | Umfang, Höhe, Volumen | 11 | Flächencode | 12 | Klassifizierung und Eigenschaften | 14 | 1 | 01 | Wohnung 1 | <Treppenhaus> | FB | <Fertigboden> | <Wandmaterial> | DB | <Material Deckenbelag> | B | BF | NGF | RU | 0 | Standardraum | 0 | 2.8 | 0.1 | 21.0205 | 12.6694 | 47.1192 | 345.742 | -2.9 | 13.1 | -0.1 | 0 | 0 | 2 | 0 | 0 | 5 | 0 | 8.3511 | 4.02 | 0 | 7.985 | 4.02 | 0 | 0.25 | 0.3 | BauantragGeschoss - IstVollgeschoss: no; IstGF: yes; AC_Pset_Raumstempel_DIN_22 - 2. Zeile (sIDRow2_100): IFC.PSet.Pset_BauantragRäume.istVollgeschoss
R-023 | -1. Geschoss | Treppenhaus UG | Raum-023 | Bauantrag | Gelände; Treppenhaus | R-023 | -1. Geschoss | -1 | Nicht verknüpft | Nicht verknüpft | Nicht verknüpft | 13.192 | 2 | 2 | Elemente+Text | 7 | 1 | 30.5189 | 2.0301 | 0 | 29.0223 | 33.022 | yes | no | yes | Arial Westlich | 1 | Schichttrennlinien/Kontur | 2.5 | 3 | 7 | Einheitenname | 5 | Einheitennummer | 4 | Raumflächen | 9 | Umfang, Höhe, Volumen | 11 | Klassifizierung und Eigenschaften | 14 | ** Leere Zeile | 1 | ** Leere Zeile | 1 | ** Leere Zeile | 1 | ** Leere Zeile | 1 | no | yes | IFC.PSet.Pset_BauantragRäume.istBGF | 4 | Einheitenname | 5 | Raumflächen | 9 | Klassifizierung und Eigenschaften | 14 | ** Leere Zeile | 1 | ** Leere Zeile | 1 | ** Leere Zeile | 1 | ** Leere Zeile | 1 | 1.5 | 1.5 | 2 | Raumflächen | 9 | ** Leere Zeile | 1 | ** Leere Zeile | 1 | yes | yes | no | 30 | 4 | 10 | 1 | Raumnummer | 3 | Höhenwerte | 7 | Raumflächen | 9 | Fensterfläche | 10 | Umfang, Höhe, Volumen | 11 | Flächencode | 12 | Klassifizierung und Eigenschaften | 14 | 1 | 01 | Haus | <Treppenhaus> | FB | <Fertigboden> | <Wandmaterial> | DB | <Material Deckenbelag> | B | BF | NGF | RU | 0 | Standardraum | 0 | 2.2 | 0.1 | 32.549 | 30.5189 | 15.01 | 29.0223 | -2.9 | 13.1 | -0.1 | -0.6 | 0 | 1 | 0 | 0 | 9 | 0 | 2.0301 | 1.01 | 0 | 14.935 | 1.01 | 0 | 0.25 | 0.3 | ArchiCADProperties - Verbundene 3D Element(e): Geländer-001; Raum-003; Raum-010; Treppe-003; Wand-001; Wand-001; Wand-002; Wand-003; WandAbschl-017; BauantragGeschoss - IstVollgeschoss: no; IstGF: yes; Pset_SpaceFireSafetyRequirements - FireExit: yes
003 | -1. Geschoss | Gelände | Raum-003 | Räume | Rampe; Terrasse Wohnung2 EG; Tiefgaragenabfahrt; Treppenhaus UG; Untergeschoss UG | 003 | -1. Geschoss | -1 | EG | Ursprung + 1 | Ursprung + 1 (EG) | 740.846 | 2.5 | 1 | Schichttrennlinien/Kontur | 4 | 0 | 0 | 0 | 0 | 2963.38 | 445.4 | no | yes | no | Arial | 0 | Elemente+Text | 2 | 1 | 11 | Einheitennummer | 4 | Einheitenname | 5 | Beläge | 6 | Raumflächen | 9 | Fensterfläche | 10 | Umfang, Höhe, Volumen | 11 | Flächencode | 12 | Klassifizierung und Eigenschaften | 14 | Eigener Text | 15 | yes | no |  | 12 | Raumname | 2 | Einheitennummer | 4 | Einheitenname | 5 | Beläge | 6 | Höhenwerte | 7 | Raumflächen | 9 | Fensterfläche | 10 | 2.5 | 2 | 12 | Raumname | 2 | Einheitennummer | 4 | Einheitenname | 5 | yes | no | yes | 50 | 3 | 11 | 2 | Höhenwerte und Raumnummer | 8 | Raumflächen | 9 | Fensterfläche | 10 | Umfang, Höhe, Volumen | 11 | Flächencode | 12 | Klassifizierung und Eigenschaften | 14 | Eigener Text | 15 | 2 | <Einheitennummer> | <Einheitenname> | <Funktion> | B | <Bodenbelag> | <Wandbelag> | D | <Deckenbelag> | F | NF | NRF | U | 0 |  | 0 | 4 | 0.1 | 0 | 0 | 111.35 | 2278.41 | -4.1 | 11.9 | -1.3 | -4.44089e-16 | 0 | 0 | 0 | 0 | 0 | 0 | 0 | 0 | 0 | 0 | 0 | 0 | 0.2 | 0.15 | ArchiCADProperties - Verbundene 3D Element(e): Baum-001; Decke-012; Decke-013; Morph; Morph-020; Morph-020; Morph-020; Morph-023; Raum-016; Raum-017; Raum-020; Raum-023; Raum-024; Wand-001; Wand-003; Wand-004; Wand-004; Wand-005; WandAbschl-017; BauantragGrundstück - IstGrundstücksfläche: yes; AC_Pset_Raumstempel_DIN_22 - 1. Zeile (sIDRow1_0): IFC.Type; Raumname in 2. Zeile: <2. Raumnamen-Zeile>
EG | EG | Erdgeschoss | Raum-019 | Bauantrag | Bad; Bad; Bad; Bad; Bad; Bad; Grundfläche Gebäude Nachgezogen; Treppenhaus; Wohnen; Wohnen; Wohnen; Wohnen; Wohnen; Wohnen; Wohnen; Wohnen; Wohnen; Wohnen; Wohnen; Wohnen; Wohnung1 EG; Wohnung2 EG | EG | EG | 0 | Nicht verknüpft | Nicht verknüpft | Nicht verknüpft | 163.856 | 2 | 2 | Elemente+Text | 8 | 2 | 144.143 | 4.848 | 35.634 | 614.46 | 207.34 | yes | no | yes | Arial Westlich | 1 | Schichttrennlinien/Kontur | 2.5 | 3 | 7 | Einheitenname | 5 | Einheitennummer | 4 | Raumflächen | 9 | Umfang, Höhe, Volumen | 11 | Klassifizierung und Eigenschaften | 14 | ** Leere Zeile | 1 | ** Leere Zeile | 1 | ** Leere Zeile | 1 | ** Leere Zeile | 1 | no | no | IFC.PSet.Pset_BauantragRäume.istBGF | 4 | Einheitenname | 5 | Raumflächen | 9 | Klassifizierung und Eigenschaften | 14 | ** Leere Zeile | 1 | ** Leere Zeile | 1 | ** Leere Zeile | 1 | ** Leere Zeile | 1 | 1.5 | 1.5 | 2 | Raumflächen | 9 | ** Leere Zeile | 1 | ** Leere Zeile | 1 | no | yes | yes | 30 | 4 | 11 | 1 | Raumnummer | 3 | Höhenwerte | 7 | Raumflächen | 9 | Fensterfläche | 10 | Umfang, Höhe, Volumen | 11 | Flächencode | 12 | Klassifizierung und Eigenschaften | 14 | 1 | 01 | Wohnung 1 | <Treppenhaus> | FB | <Fertigboden> | <Wandmaterial> | DB | <Material Deckenbelag> | B | BF | NGF | RU | 2.84217e-14 | Standardraum | 21.7471 | 3.75 | 0.1 | 184.325 | 143.843 | 55.2908 | 614.46 | -0.1 | 15.9 | -0.1 | 0 | 0 | 2 | 36 | 11 | 10 | 35.634 | 4.848 | 2.02 | 15.1 | 49.8483 | 2.02 | 15.1 | 0.25 | 0.3 | BauantragGeschoss - IstVollgeschoss: yes; IstGF: yes; AC_Pset_Raumstempel_DIN_22 - 2. Zeile (sIDRow2_100): IFC.PSet.Pset_BauantragRäume.IstGebäudeHülle; 1. Zeile (sIDRow1_0): IFC.PSet.Pset_BauantragRäume.IstGebäudeHülle; 3. Zeile (sIDRow3_100): IFC.PSet.Pset_BauantragRäume.istVollgeschoss; 2. Zeile (sIDRow2_0): IFC.PSet.Pset_BauantragRäume.istBGF
R-021 | EG | Wohnung1 EG | Raum-021 | Bauantrag | Bad; Bad; Bad; Erdgeschoss; Grundfläche Gebäude Nachgezogen; Treppenhaus; Wohnen; Wohnen; Wohnen; Wohnen; Wohnen; Wohnen | R-021 | EG | 0 | Nicht verknüpft | Nicht verknüpft | Nicht verknüpft | 87.2979 | 2 | 2 | Elemente+Text | 4 | 0 | 47.1837 | 2.424 | 21.696 | 327.367 | 143.325 | yes | no | yes | Arial Westlich | 1 | Schichttrennlinien/Kontur | 2.5 | 3 | 7 | Einheitenname | 5 | Einheitennummer | 4 | Raumflächen | 9 | Umfang, Höhe, Volumen | 11 | Klassifizierung und Eigenschaften | 14 | ** Leere Zeile | 1 | ** Leere Zeile | 1 | ** Leere Zeile | 1 | ** Leere Zeile | 1 | no | yes | IFC.PSet.Pset_BauantragRäume.istBGF | 4 | Einheitenname | 5 | Raumflächen | 9 | Klassifizierung und Eigenschaften | 14 | ** Leere Zeile | 1 | ** Leere Zeile | 1 | ** Leere Zeile | 1 | ** Leere Zeile | 1 | 1.5 | 1.5 | 2 | Raumflächen | 9 | ** Leere Zeile | 1 | ** Leere Zeile | 1 | yes | yes | no | 30 | 4 | 10 | 1 | Raumnummer | 3 | Höhenwerte | 7 | Raumflächen | 9 | Fensterfläche | 10 | Umfang, Höhe, Volumen | 11 | Flächencode | 12 | Klassifizierung und Eigenschaften | 14 | 1 | 01 | Wohnung 1 | <Treppenhaus> | FB | <Fertigboden> | <Wandmaterial> | DB | <Material Deckenbelag> | B | BF | BGF | RU | 0 | Standardraum | 24.8528 | 3.75 | 0.1 | 71.3037 | 47.1837 | 38.22 | 327.367 | -0.1 | 15.9 | -0.1 | 0 | 0 | 1 | 19 | 5 | 3 | 21.696 | 2.424 | 1.01 | 9.04 | 19.11 | 1.01 | 9.04 | 0.25 | 0.3 | BauantragRäume - istGrundBA: yes; istGF: no; BauantragNutzungseinheiten - Nutzung: WOHNEINHEIT_EIGENTUMSWOHNUNG; Nutzungseinheit: Wohnung 1; BauantragBruttoflächen - IstBGF: yes; Raumumschließung: REGELFALL
R-024 | EG | Terrasse Wohnung1 EG | Raum-021 | Bauantrag | Grundfläche Gebäude Nachgezogen; Terrasse; Terrasse | R-024 | EG | 0 | Nicht verknüpft | Nicht verknüpft | Nicht verknüpft | 30.2163 | 2 | 2 | Elemente+Text | 4 | 0 | 15.6912 | 0 | 12 | 118.445 | 90.3117 | yes | no | yes | Arial Westlich | 1 | Schichttrennlinien/Kontur | 2.5 | 3 | 7 | Einheitenname | 5 | Einheitennummer | 4 | Raumflächen | 9 | Umfang, Höhe, Volumen | 11 | Klassifizierung und Eigenschaften | 14 | ** Leere Zeile | 1 | ** Leere Zeile | 1 | ** Leere Zeile | 1 | ** Leere Zeile | 1 | no | yes | IFC.PSet.Pset_BauantragRäume.istBGF | 4 | Einheitenname | 5 | Raumflächen | 9 | Klassifizierung und Eigenschaften | 14 | ** Leere Zeile | 1 | ** Leere Zeile | 1 | ** Leere Zeile | 1 | ** Leere Zeile | 1 | 1.5 | 1.5 | 2 | Raumflächen | 9 | ** Leere Zeile | 1 | ** Leere Zeile | 1 | yes | yes | no | 30 | 4 | 10 | 1 | Raumnummer | 3 | Höhenwerte | 7 | Raumflächen | 9 | Fensterfläche | 10 | Umfang, Höhe, Volumen | 11 | Flächencode | 12 | Klassifizierung und Eigenschaften | 14 | 1 | 01 | Wohnung 1 | <Treppenhaus> | FB | <Fertigboden> | <Wandmaterial> | DB | <Material Deckenbelag> | B | BF | BGF | RU | 0 | Standardraum | 39.7136 | 3.91991 | 0.1 | 27.6912 | 15.6912 | 23.0392 | 118.445 | -0.1 | 15.9 | -0.1 | 0.16991 | 0 | 0 | 1 | 1 | 3 | 12 | 0 | 0 | 5 | 7.48 | 0 | 5 | 0.25 | 0.3 | ArchiCADProperties - Verbundene 3D Element(e): Attika-Wand-005; Decke-008; Raum-002; Raum-002; Raum-002; BauantragRäume - istGrundBA: yes; istTerrasse: yes; BauantragBruttoflächen - IstBGF: yes; Raumumschließung: REGELFALL
R-000 | EG | Spielplatz | Raum-018 | Bauantrag |  | R-000 | EG | 0 | Nicht verknüpft | Nicht verknüpft | Nicht verknüpft | 100.008 | 2 | 2 | Elemente+Text | 4 | 0 | 0 | 0 | 0 | 250.02 | 100.025 | yes | no | yes | Arial Westlich | 1 | Schichttrennlinien/Kontur | 2.5 | 3 | 7 | Einheitenname | 5 | Einheitennummer | 4 | Raumflächen | 9 | Umfang, Höhe, Volumen | 11 | Klassifizierung und Eigenschaften | 14 | ** Leere Zeile | 1 | ** Leere Zeile | 1 | ** Leere Zeile | 1 | ** Leere Zeile | 1 | yes | yes | IFC.PSet.Pset_BauantragRäume.istNebenanlage | 4 | Einheitenname | 5 | Raumflächen | 9 | Klassifizierung und Eigenschaften | 14 | ** Leere Zeile | 1 | ** Leere Zeile | 1 | ** Leere Zeile | 1 | ** Leere Zeile | 1 | 1.5 | 1.5 | 2 | Raumflächen | 9 | ** Leere Zeile | 1 | ** Leere Zeile | 1 | yes | no | no | 30 | 4 | 9 | 2 | Höhenwerte und Raumnummer | 8 | Raumflächen | 9 | Fensterfläche | 10 | Umfang, Höhe, Volumen | 11 | Flächencode | 12 | ** Leere Zeile | 1 | Klassifizierung und Eigenschaften | 14 | 1 | S | Haus | <Treppenhaus> | FB | <Fertigboden> | <Wandmaterial> | DB | <Material Deckenbelag> | B | BF | NGF | RU | 0 | Standardraum | 0 | 2.5 | 0.1 | 0 | 0 | 40.0099 | 250.02 | -0.1 | 15.9 | -0.1 | 2.03 | 0 | 0 | 0 | 0 | 0 | 0 | 0 | 0 | 0 | 0 | 0 | 0 | 0.25 | 0.3 | BauantragGrundstücksflächen - IstSpielUndFreizeitfläche: yes; IstNebenanlage: yes; IstGemeinschaftsanlage: yes; IstVersiegelt: yes
R-023 | EG | Terrasse Wohnung2 EG | Raum-020 | Bauantrag | Gelände; Grundfläche Gebäude Nachgezogen; Terrasse; Terrasse | R-023 | EG | 0 | Nicht verknüpft | Nicht verknüpft | Nicht verknüpft | 11.7605 | 2 | 2 | Elemente+Text | 4 | 0 | 14.5395 | 0 | 7.272 | 48.4523 | 65.0122 | yes | no | yes | Arial Westlich | 1 | Schichttrennlinien/Kontur | 2.5 | 3 | 7 | Einheitenname | 5 | Einheitennummer | 4 | Raumflächen | 9 | Umfang, Höhe, Volumen | 11 | Klassifizierung und Eigenschaften | 14 | ** Leere Zeile | 1 | ** Leere Zeile | 1 | ** Leere Zeile | 1 | ** Leere Zeile | 1 | no | yes | IFC.PSet.Pset_BauantragRäume.istBGF | 4 | Einheitenname | 5 | Raumflächen | 9 | Klassifizierung und Eigenschaften | 14 | ** Leere Zeile | 1 | ** Leere Zeile | 1 | ** Leere Zeile | 1 | ** Leere Zeile | 1 | 1.5 | 1.5 | 2 | Raumflächen | 9 | ** Leere Zeile | 1 | ** Leere Zeile | 1 | yes | yes | no | 30 | 4 | 10 | 1 | Raumnummer | 3 | Höhenwerte | 7 | Raumflächen | 9 | Fensterfläche | 10 | Umfang, Höhe, Volumen | 11 | Flächencode | 12 | Klassifizierung und Eigenschaften | 14 | 1 | 01 | Wohnung 2 | <Treppenhaus> | FB | <Fertigboden> | <Wandmaterial> | DB | <Material Deckenbelag> | B | BF | BGF | RU | 0 | Standardraum | 61.834 | 4.11991 | 0.1 | 21.8115 | 14.5395 | 15.78 | 48.4523 | -0.3 | 15.7 | -0.3 | 0.16991 | 0 | 0 | 1 | 3 | 1 | 7.272 | 0 | 0 | 3.03 | 5.895 | 0 | 3.03 | 0.25 | 0.3 | ArchiCADProperties - Verbundene 3D Element(e): Decke-008; Decke-013; Hecke; Raum-002; Raum-003; Raum-011; Raum-011; BauantragRäume - istGrundBA: yes; istTerrasse: yes; BauantragBruttoflächen - IstBGF: yes; Raumumschließung: REGELFALL
R-000 | EG | Zuwegung | Raum-018 | Bauantrag |  | R-000 | EG | 0 | Nicht verknüpft | Nicht verknüpft | Nicht verknüpft | 38.8311 | 2 | 2 | Elemente+Text | 9 | 2 | 0 | 0 | 0 | 97.0778 | 128.809 | yes | no | yes | Arial Westlich | 1 | Schichttrennlinien/Kontur | 2.5 | 3 | 7 | Einheitenname | 5 | Einheitennummer | 4 | Raumflächen | 9 | Umfang, Höhe, Volumen | 11 | Klassifizierung und Eigenschaften | 14 | ** Leere Zeile | 1 | ** Leere Zeile | 1 | ** Leere Zeile | 1 | ** Leere Zeile | 1 | yes | yes | IFC.PSet.Pset_BauantragRäume.istNebenanlage | 4 | Einheitenname | 5 | Raumflächen | 9 | Klassifizierung und Eigenschaften | 14 | ** Leere Zeile | 1 | ** Leere Zeile | 1 | ** Leere Zeile | 1 | ** Leere Zeile | 1 | 1.5 | 1.5 | 2 | Raumflächen | 9 | ** Leere Zeile | 1 | ** Leere Zeile | 1 | yes | no | no | 30 | 4 | 9 | 2 | Höhenwerte und Raumnummer | 8 | Raumflächen | 9 | Fensterfläche | 10 | Umfang, Höhe, Volumen | 11 | Flächencode | 12 | ** Leere Zeile | 1 | Klassifizierung und Eigenschaften | 14 | 1 | S | Haus | <Treppenhaus> | FB | <Fertigboden> | <Wandmaterial> | DB | <Material Deckenbelag> | B | BF | NGF | RU | 0 | Standardraum | 0 | 2.5 | 0.1 | 5.90917 | 3.48517 | 51.5236 | 97.0778 | -0.1 | 15.9 | -0.1 | 2.03 | 0 | 1 | 0 | 0 | 1 | 0 | 2.424 | 1.01 | 0 | 0 | 0 | 0 | 0.25 | 0.3 | ArchiCADProperties - Verbundene 3D Element(e): Baum-001; Morph-023; BauantragGrundstücksflächen - IstNebenanlage: yes; IstGemeinschaftsanlage: yes; IstVersiegelt: yes
R-020 | EG | Wohnung2 EG | Raum-020 | Bauantrag | Bad; Bad; Bad; Erdgeschoss; Grundfläche Gebäude Nachgezogen; Treppenhaus; Wohnen; Wohnen; Wohnen; Wohnen; Wohnen; Wohnen | R-020 | EG | 0 | Nicht verknüpft | Nicht verknüpft | Nicht verknüpft | 63.882 | 2 | 2 | Elemente+Text | 6 | 1 | 103.454 | 4.20285 | 13.938 | 233.169 | 124.903 | yes | no | yes | Arial Westlich | 1 | Schichttrennlinien/Kontur | 2.5 | 3 | 7 | Einheitenname | 5 | Einheitennummer | 4 | Raumflächen | 9 | Umfang, Höhe, Volumen | 11 | Klassifizierung und Eigenschaften | 14 | ** Leere Zeile | 1 | ** Leere Zeile | 1 | ** Leere Zeile | 1 | ** Leere Zeile | 1 | no | yes | IFC.PSet.Pset_BauantragRäume.istBGF | 4 | Einheitenname | 5 | Raumflächen | 9 | Klassifizierung und Eigenschaften | 14 | ** Leere Zeile | 1 | ** Leere Zeile | 1 | ** Leere Zeile | 1 | ** Leere Zeile | 1 | 1.5 | 1.5 | 2 | Raumflächen | 9 | ** Leere Zeile | 1 | ** Leere Zeile | 1 | yes | yes | no | 30 | 4 | 10 | 1 | Raumnummer | 3 | Höhenwerte | 7 | Raumflächen | 9 | Fensterfläche | 10 | Umfang, Höhe, Volumen | 11 | Flächencode | 12 | Klassifizierung und Eigenschaften | 14 | 1 | 01 | Wohnung 2 | <Treppenhaus> | FB | <Fertigboden> | <Wandmaterial> | DB | <Material Deckenbelag> | B | BF | NGF | RU | 0 | Standardraum | 21.8183 | 3.65 | 0.1 | 81.0215 | 62.8807 | 34.22 | 233.169 | 0 | 16 | 0 | 0 | 0 | 2 | 16 | 6 | 9 | 13.938 | 4.20285 | 1.895 | 6.06 | 34.7668 | 1.895 | 6.06 | 0.25 | 0.3 | BauantragRäume - istGrundBA: yes; istGF: yes; BauantragNutzungseinheiten - Nutzung: WOHNEINHEIT_EIGENTUMSWOHNUNG; Nutzungseinheit: Wohnung 2; BauantragBruttoflächen - IstBGF: yes; Raumumschließung: REGELFALL
000 | EG | Grundfläche Gebäude Nachgezogen | Raum-002 | Räume |  | 000 | EG | 0 | Nicht verknüpft | Nicht verknüpft | Nicht verknüpft | 205.832 | 2.5 | 1 | Schichttrennlinien/Kontur | 16 | 6 | 141.637 | 4.848 | 30.3 | 1424.34 | 466.123 | yes | yes | no | Arial | 0 | Elemente+Text | 2 | 1 | 11 | Einheitennummer | 4 | Einheitenname | 5 | Beläge | 6 | Raumflächen | 9 | Fensterfläche | 10 | Umfang, Höhe, Volumen | 11 | Flächencode | 12 | Klassifizierung und Eigenschaften | 14 | Eigener Text | 15 | no | no |  | 12 | Raumname | 2 | Einheitennummer | 4 | Einheitenname | 5 | Beläge | 6 | Höhenwerte | 7 | Raumflächen | 9 | Fensterfläche | 10 | 2.5 | 2 | 12 | Raumname | 2 | Einheitennummer | 4 | Einheitenname | 5 | yes | no | no | 50 | 3 | 11 | 2 | Höhenwerte und Raumnummer | 8 | Raumflächen | 9 | Fensterfläche | 10 | Umfang, Höhe, Volumen | 11 | Flächencode | 12 | Klassifizierung und Eigenschaften | 14 | Eigener Text | 15 | 2 | <Einheitennummer> | <Einheitenname> | <Funktion> | B | <Bodenbelag> | <Wandbelag> | D | <Deckenbelag> | F | NF | NRF | U | 0 |  | 11.1878 | 6.91991 | 0.1 | 154.299 | 126.423 | 67.3597 | 1424.34 | -0.1 | 15.9 | -0.1 | 3.16991 | 0 | 2 | 38 | 10 | 9 | 23.028 | 4.848 | 2.02 | 10.1 | 47.7333 | 2.02 | 13.13 | 0.2 | 0.15 | AC_Pset_Raumstempel_DIN_22 - Raumname in 2. Zeile: <2. Raumnamen-Zeile>; BauantragGrundstücksflächen - IstVersiegelt: yes; BauantragGebäude - IstGebäudeBegrenzung: yes
OG | 1. OG | Obergeschoss | Raum-019 | Bauantrag | Dachterrasse; Dachterrasse; Grundfläche Gebäude Nachgezogen; Loft; Loft; Loft; Luftraum Dach; Wohnen; Wohnung1 OG; Wohnung2 OG | OG | 1. OG | 1 | Nicht verknüpft | Nicht verknüpft | Nicht verknüpft | 107.867 | 2 | 2 | Elemente+Text | 9 | 2 | 79.2695 | 0 | 26.4269 | 341.93 | 156.373 | yes | no | yes | Arial Westlich | 1 | Schichttrennlinien/Kontur | 2.5 | 3 | 7 | Einheitenname | 5 | Einheitennummer | 4 | Raumflächen | 9 | Umfang, Höhe, Volumen | 11 | Klassifizierung und Eigenschaften | 14 | ** Leere Zeile | 1 | ** Leere Zeile | 1 | ** Leere Zeile | 1 | ** Leere Zeile | 1 | no | no | IFC.PSet.Pset_BauantragRäume.istBGF | 4 | Einheitenname | 5 | Raumflächen | 9 | Klassifizierung und Eigenschaften | 14 | ** Leere Zeile | 1 | ** Leere Zeile | 1 | ** Leere Zeile | 1 | ** Leere Zeile | 1 | 1.5 | 1.5 | 2 | Raumflächen | 9 | ** Leere Zeile | 1 | ** Leere Zeile | 1 | no | yes | yes | 30 | 4 | 11 | 1 | Raumnummer | 3 | Höhenwerte | 7 | Raumflächen | 9 | Fensterfläche | 10 | Umfang, Höhe, Volumen | 11 | Flächencode | 12 | Klassifizierung und Eigenschaften | 14 | 1 | 01 | Haus | <Treppenhaus> | FB | <Fertigboden> | <Wandmaterial> | DB | <Material Deckenbelag> | B | BF | NGF | RU | 0 | Standardraum | 28.5044 | 3.16991 | 0.1 | 105.698 | 74.9515 | 49.3305 | 341.93 | 3.65 | 19.65 | -0.1 | 0 | 6 | 0 | 27 | 8 | 12 | 30.7469 | 0 | 0 | 13.343 | 42.9292 | 0 | 11.543 | 0.25 | 0.3 | BauantragGeschoss - IstVollgeschoss: no; IstGF: yes; AC_Pset_Raumstempel_DIN_22 - 2. Zeile (sIDRow2_100): IFC.PSet.Pset_BauantragRäume.IstGebäudeHülle; 1. Zeile (sIDRow1_0): IFC.PSet.Pset_BauantragRäume.IstGebäudeHülle; 3. Zeile (sIDRow3_100): IFC.PSet.Pset_BauantragRäume.istVollgeschoss; 2. Zeile (sIDRow2_0): IFC.PSet.Pset_BauantragRäume.istBGF
R-021 | 1. OG | Wohnung1 OG | Raum-021 | Bauantrag | Grundfläche Gebäude Nachgezogen; Luftraum Dach; Obergeschoss; Wohnen | R-021 | 1. OG | 1 | Nicht verknüpft | Nicht verknüpft | Nicht verknüpft | 42.7641 | 2 | 2 | Elemente+Text | 4 | 0 | 16.6719 | 0 | 4.68294 | 127.674 | 78.9098 | yes | no | yes | Arial Westlich | 1 | Schichttrennlinien/Kontur | 2.5 | 3 | 7 | Einheitenname | 5 | Einheitennummer | 4 | Raumflächen | 9 | Umfang, Höhe, Volumen | 11 | Klassifizierung und Eigenschaften | 14 | ** Leere Zeile | 1 | ** Leere Zeile | 1 | ** Leere Zeile | 1 | ** Leere Zeile | 1 | no | yes | IFC.PSet.Pset_BauantragRäume.istBGF | 4 | Einheitenname | 5 | Raumflächen | 9 | Klassifizierung und Eigenschaften | 14 | ** Leere Zeile | 1 | ** Leere Zeile | 1 | ** Leere Zeile | 1 | ** Leere Zeile | 1 | 1.5 | 1.5 | 2 | Raumflächen | 9 | ** Leere Zeile | 1 | ** Leere Zeile | 1 | yes | yes | no | 30 | 4 | 10 | 1 | Raumnummer | 3 | Höhenwerte | 7 | Raumflächen | 9 | Fensterfläche | 10 | Umfang, Höhe, Volumen | 11 | Flächencode | 12 | Klassifizierung und Eigenschaften | 14 | 1 | 01 | Wohnung 1 | <Treppenhaus> | FB | <Fertigboden> | <Wandmaterial> | DB | <Material Deckenbelag> | B | BF | BGF | RU | 0 | Standardraum | 10.9506 | 2.98553 | 0.1 | 21.3549 | 16.6719 | 26.4307 | 127.674 | 3.65 | 19.65 | -0.1 | 0 | 5 | 0 | 27 | 1 | 4 | 4.68294 | 0 | 0 | 2.483 | 13.1704 | 0 | 2.483 | 0.25 | 0.3
R-020 | 1. OG | Wohnung2 OG | Raum-020 | Bauantrag | Dachterrasse; Dachterrasse; Grundfläche Gebäude Nachgezogen; Loft; Loft; Loft; Obergeschoss | R-020 | 1. OG | 1 | Nicht verknüpft | Nicht verknüpft | Nicht verknüpft | 65.1017 | 2 | 2 | Elemente+Text | 8 | 1 | 57.3267 | 0 | 26.064 | 206.366 | 109.457 | yes | no | yes | Arial Westlich | 1 | Schichttrennlinien/Kontur | 2.5 | 3 | 7 | Einheitenname | 5 | Einheitennummer | 4 | Raumflächen | 9 | Umfang, Höhe, Volumen | 11 | Klassifizierung und Eigenschaften | 14 | ** Leere Zeile | 1 | ** Leere Zeile | 1 | ** Leere Zeile | 1 | ** Leere Zeile | 1 | no | yes | IFC.PSet.Pset_BauantragRäume.istBGF | 4 | Einheitenname | 5 | Raumflächen | 9 | Klassifizierung und Eigenschaften | 14 | ** Leere Zeile | 1 | ** Leere Zeile | 1 | ** Leere Zeile | 1 | ** Leere Zeile | 1 | 1.5 | 1.5 | 2 | Raumflächen | 9 | ** Leere Zeile | 1 | ** Leere Zeile | 1 | yes | yes | no | 30 | 4 | 10 | 1 | Raumnummer | 3 | Höhenwerte | 7 | Raumflächen | 9 | Fensterfläche | 10 | Umfang, Höhe, Volumen | 11 | Flächencode | 12 | Klassifizierung und Eigenschaften | 14 | 1 | 01 | Wohnung 2 | <Treppenhaus> | FB | <Fertigboden> | <Wandmaterial> | DB | <Material Deckenbelag> | B | BF | NGF | RU | -1.42109e-14 | Standardraum | 40.0358 | 3.16991 | 0.1 | 83.3927 | 57.3287 | 34.53 | 206.366 | 3.65 | 19.65 | -0.1 | 0 | 1 | 0 | 0 | 7 | 8 | 26.064 | 0 | 0 | 10.86 | 29.2432 | 0 | 10.86 | 0.25 | 0.3 | BauantragBruttoflächen - IstBGF: yes; Raumumschließung: REGELFALL

# IfcSpace: Verkehrsfläche (7)
Classification: Raum (ARCHICAD Klassifizierung); 9 VF Verkehrsfläche
BauantragNettoflächen - Art: VF; Raumumschließung: REGELFALL
Pset_SpaceCommon - Category: Verkehrsfläche
ArchiCADProperties - Bibliothekselement-Name: Raumstempel DIN 22; Geschützt: no; Typ: Raum; Absolutes Geschoss für Oberkantenverknüpfung: Nicht verknüpft; Relatives Geschoss für Oberkantenverknüpfung: Nicht verknüpft; Geschoss für Oberkantenverknüpfung: Nicht verknüpft; Oberfläche (Alle): Raumstempel; Deckschraffur: Misch-Schraffur 0%; Anzeigen auf Umbau-Filter: Alle relevanten Filter; Umbau-Status: Bestand; Oberfläche: Raumstempel; Einheitliche Oberfläche: yes; Raumkategorie: 0; Raumflächen-Code: 9 VF; ARCHICAD Klassifizierung - 22: Raum
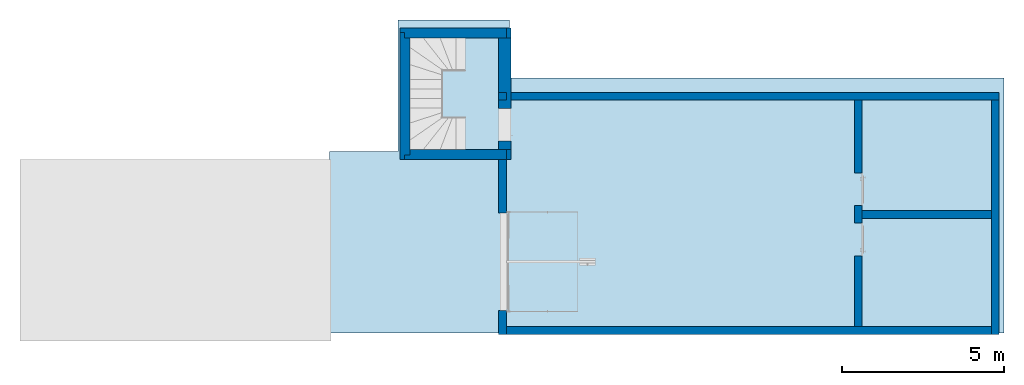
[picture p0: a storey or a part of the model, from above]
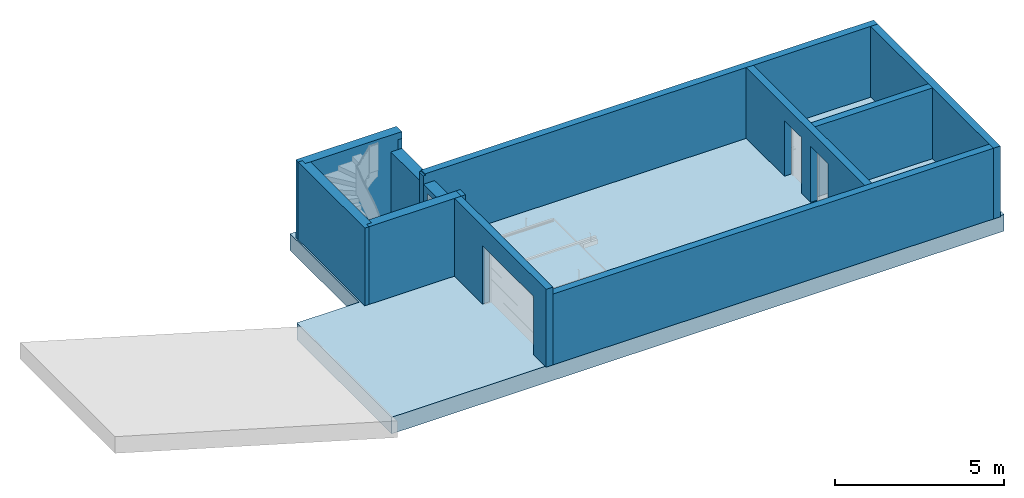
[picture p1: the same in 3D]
Properties of the parts of a building model (IFC4), part 2 of 13

# IfcSpace: Verkehrsfläche (7)
AC_Pset_Raumstempel_DIN_22 - Schriftgröße 1 (Grundeinstell.): 2; Textstil 1 (Grundeinstellung): 0; Markertext 1 Ausrichtung (Standard): 2; Markertext 1 Zeilenabstand (Standard): 1; Markertext 1 Zeichenbreite-Faktor (Standard): 1; Markertext 1 Textzeichenbreite-Faktor (Standard): 1; Schriftart 1: Arial Westlich; Stift Text (Grundeinstellung): Elemente+Text; Anzahl aller Raumecken: 4; Anzahl hereinragender Raumecken: 0; Fläche der Fenster: 0; Wandabzugsfläche: 0; Fassaden- Abzugsfläche: 0; Stützenabzugsfläche: 0; Schraffurabzugsfläche: 0; Abzugsfläche unter Dach: 0; Gesamtabzugsfläche: 0; Raumfläche Faktor: 1; Dach Oberflächenbereich an der Oberseite: 0; Dach Oberflächenbereich an der Unterseite: 0; Decke Oberflächenbereich an der Oberseite: 0; Decke Oberflächenbereich an der Unterseite: 0; Unterzug Oberflächenbereich an der Oberseite: 0; Unterzugoberfläche unten: 0; Oberer Oberflächenbereich der Wandeinsätze: 0; Oberfläche Wandnischen hinten: 0; Seite Oberflächenbereich der Wandeinsätze: 0; Maßstabsabhängig: yes; Maßstab (displayScale): 1:100; Maßstab (iDisplayScale): 2; Raumname zeigen (bShowZoneNameLine1_50): yes; Raumnummer zeigen (bShowZoneNum_50): yes; Raumkategorie-Code zeigen (bShowZoneCatCode_50): no; 2. Raumnamen-Zeile zeigen (bShowZoneNameLine2_50): no; Zeige Apartment Identifikation (bShowApartmentCode_50): no; Zeige Treppenhaus Identifikatoren (bShowStaircaseCode_50): no; Position zeigen (bShowPosition_50): no; Hausnummer zeigen (bShowHouseNumber_50): no; Funktion zeigen (bShowFunctions_50): no; ID zeigen (bShowID_50): no; Bodenbelag zeigen (bShowFloor_50): no; Wandbelag zeigen (bShowWallFinish_50): no; Deckenbelag zeigen (bShowCeiling_50): no; Raumunterkante zeigen (bShowHeightZone_50): yes; Fertigfußbodenhöhe zeigen (bShowHeightFloor_50): yes; Abzugsflächen zeigen (bShowMeasuredArea_50): no; Gemessene Nettofläche zeigen (bShowMeasuredNetArea_50): yes; DIN Abzugsflächen zeigen (bShowVentArea_50): no; Reduzierte Fläche zeigen (bShowReducedArea_50): no; Berechnete Fläche (NRF) zeigen (bShowCalculatedArea_50): yes; Fensterflächen zeigen (bShowWindowArea_50): no; Raumumfang zeigen (bShowPerimeter_50): no; Raumhöhe zeigen (bShowCeilingHeight_50): yes; Raumvolumen zeigen (bShowVolume_50): no; Einordnung zeigen (bShowClassification_50): no; Eigenen Text zeigen 1 (bShowCustom1_50): no; Eigenen Text zeigen 2 (bShowCustom2_50): no; Eigenen Text zeigen 3 (bShowCustom3_50): no; Klassifizierung und Eigenschaften anzeigen (bShowAdditionalTags_50): yes; Parameter auswählen (iTnCSelectParams_50): 1; Daten darstellen nach (iTncDisplayData_50): 1; 1. Zeile Parameternamen zeigen als (iRow1CustomName_50): 1; 2. Zeile Parameternamen zeigen als (iRow2CustomName_50): 1; 3. Zeile Parameternamen zeigen als (iRow3CustomName_50): 1; 4. Zeile Parameternamen zeigen als (iRow4CustomName_50): 1; 5. Zeile Parameternamen zeigen als (iRow5CustomName_50): 1; 6. Zeile Parameternamen zeigen als (iRow6CustomName_50): 1; 7. Zeile Parameternamen zeigen als (iRow7CustomName_50): 1; 8. Zeile Parameternamen zeigen als (iRow8CustomName_50): 1; 9. Zeile Parameternamen zeigen als (iRow9CustomName_50): 1; 10. Zeile Parameternamen zeigen als (iRow10CustomName_50): 1; 11. Zeile Parameternamen zeigen als (iRow11CustomName_50): 1; 12. Zeile Parameternamen zeigen als (iRow12CustomName_50): 1; 13. Zeile Parameternamen zeigen als (iRow13CustomName_50): 1; 14. Zeile Parameternamen zeigen als (iRow14CustomName_50): 1; 15. Zeile Parameternamen zeigen als (iRow15CustomName_50): 1; 16. Zeile Parameternamen zeigen als (iRow16CustomName_50): 1; 17. Zeile Parameternamen zeigen als (iRow17CustomName_50): 1; 18. Zeile Parameternamen zeigen als (iRow18CustomName_50): 1; 19. Zeile Parameternamen zeigen als (iRow19CustomName_50): 1; 20. Zeile Parameternamen zeigen als (iRow20CustomName_50): 1; Inhalt zum Überschreiben (iContentToOverride_50): 1; Überschreiben Titel-Textformat (bOverrideTitleTextFormat_50): yes; Raumname Schriftart (fontTitleType_50): Arial Westlich; Raumname Schriftgröße (mm) (fontTitleSizePaper_50): 2; Raumname Font-Stil (iTextStyleTitle_50): 1; Raumname Stift (penTitle_50): Elemente+Text; Raumname Stift (penTitle_50_int): 1; Überschreiben Titel 2 Textformat (bOverrideTitle2TextFormat_50): no; Raumnummer Font Typ (fontTitle2Type_50): Arial Westlich; Raumnummer Font Größe (mm) (fontTitle2SizePaper_50): 2.5; Raumnummer Font-Stil (iTextStyleTitle2_50): 0; Raumnummer Stift (penTitle2_50): Schichttrennlinien/Kontur; Raumnummer Stift (penTitle2_50_int): 1; Überschreiben Daten-Textformat (bOverrideDataTextFormat_50): no; Daten Schriftart (fontDataType_50): Arial Westlich; Schriftgröße Daten (mm) (fontDataSizePaper_50): 2.5; Daten-Schrifttyp (iTextStyleData_50): 0; Daten-Stift (penData_50): Schichttrennlinien/Kontur; Daten-Stift (penData_50_int): 1; Schriftgröße (fontScaleType_50): Papiergröße; Schriftgröße (iFontScaleType_50): 2; Automat. Zeilenabstand (bAutomaticLineSpace_50): yes; Zeilenabstand in mm (lineSpacing_50): 4; Bemaßungseinheiten zeigen (bShowDimensionUnits_50): yes; Hochgestellt (bShowSuperScript_50): yes; Rahmen Stil (sFrameStyle_50): Stil 4; Rahmen Stil (iFrameStyle_50): 5; Feste Breite (bFixWidth_50): no; Breite in mm speichern (fixWidth_50): 50; Numerische Werte ausrichten (sAlignNumericalValues_50): Rechtsbündig; Numerische Werte ausrichten (iAlignNumericalValues_50): 4; Textwerte ausrichten (iAlignStringValues_50): 4; Höhenwert ausrichten (iAlignHeightValue_50): 3; Raumnummer ausrichten (iAlignZoneNr_50): 1; Fester Radius (bFixRadius_50): no; Kreisrahmen Radius in mm (frameRadius_50): 3; Rahmen-Stift (framePen_50): Elemente+Text; Linientyp Rahmen (frameLineType_50): 1; Einheitennummer Rahmen (apartmentIdFrame_50): Oval; Einheitennummer Rahmen (iApartmentIdFrame_50): 2; Hintergrundschraffur (bBackFill_50): yes; Schraffur (fillType_50): Nur Hintergrund-Stift; Schraffur-Vordergrundstift (fillPen_50): Elemente+Text; Schraffur-Hintergrundstift (fillBackPen_50): Transparent; Einheitennummer Winkel in 1:50: 0 deg; Anzahl der Reihen (nOrder_50): 7; Höhenwerte und Raumnummer Anzeigetyp (iDisplayType_50): 2; 1. (order_01_50): Raumname; 1. (iOrder_01_50): 2; 2. (order_02_50): Einheitenname; 2. (iOrder_02_50): 5; 3. (order_03_50): Einheitennummer; 3. (iOrder_03_50): 4; 4. (order_04_50): Beläge; 4. (iOrder_04_50): 6; 5. (order_05_50): Raumflächen; 5. (iOrder_05_50): 9; 6. (order_06_50): Umfang, Höhe, Volumen; 6. (iOrder_06_50): 11; 7. (order_07_50): Klassifizierung und Eigenschaften; 7. (iOrder_07_50): 14; 8. (order_08_50): ** Leere Zeile; 8. (iOrder_08_50): 1; 9. (order_09_50): ** Leere Zeile; 9. (iOrder_09_50): 1; 10. (order_10_50): ** Leere Zeile; 10. (iOrder_10_50): 1; 11. (order_11_50): ** Leere Zeile; 11. (iOrder_11_50): 1; 12. (order_12_50): ** Leere Zeile; 12. (iOrder_12_50): 1; Raumname zeigen (bShowZoneNameLine1_100): yes; Raumnummer zeigen (bShowZoneNum_100): yes; Raumkategorie-Code zeigen (bShowZoneCatCode_100): no; 2. Raumnamen-Zeile zeigen (bShowZoneNameLine2_100): yes; Einheitennummer zeigen (bShowApartmentID_100): yes; Zeige Apartment Identifikation (bShowApartmentCode_100): no; Zeige Treppenhaus Identifikatoren (bShowStaircaseCode_100): no; Position zeigen (bShowPosition_100): no; Hausnummer zeigen (bShowHouseNumber_100): no; Funktion zeigen (bShowFunctions_100): no; ID zeigen (bShowID_100): no; Bodenbelag zeigen (bShowFloor_100): no; Wandbelag zeigen (bShowWallFinish_100): no; Deckenbelag zeigen (bShowCeiling_100): no; Raumunterkante zeigen (bShowHeightZone_100): no; Fertigfußbodenhöhe zeigen (bShowHeightFloor_100): no; Abzugsflächen zeigen (bShowMeasuredArea_100): no; Gemessene Nettofläche zeigen (bShowMeasuredNetArea_100): no; DIN Abzugsflächen zeigen (bShowVentArea_100): no; Reduzierte Fläche zeigen (bShowReducedArea_100): no; Berechnete Fläche (NRF) zeigen (bShowCalculatedArea_100): yes; Fensterflächen zeigen (bShowWindowArea_100): no; Raumumfang zeigen (bShowPerimeter_100): no; Raumhöhe zeigen (bShowCeilingHeight_100): no; Raumvolumen zeigen (bShowVolume_100): no; Einordnung zeigen (bShowClassification_100): no; Eigenen Text zeigen 1 (bShowCustom1_100): no; Eigenen Text zeigen 2 (bShowCustom2_100): no; Eigenen Text zeigen 3 (bShowCustom3_100): no; Klassifizierung und Eigenschaften anzeigen (bShowAdditionalTags_100): yes; Parameter auswählen (iTnCSelectParams_100): 1; Daten darstellen nach (iTncDisplayData_100): 1; 1. Zeile Parameternamen zeigen als (iRow1CustomName_100): 1; 2. Zeile Parameternamen zeigen als (iRow2CustomName_100): 1; 3. Zeile Parameternamen zeigen als (iRow3CustomName_100): 1; 4. Zeile Parameternamen zeigen als (iRow4CustomName_100): 1; 5. Zeile Parameternamen zeigen als (iRow5CustomName_100): 1; 6. Zeile Parameternamen zeigen als (iRow6CustomName_100): 1; 7. Zeile Parameternamen zeigen als (iRow7CustomName_100): 1; 8. Zeile Parameternamen zeigen als (iRow8CustomName_100): 1; 9. Zeile Parameternamen zeigen als (iRow9CustomName_100): 1; 10. Zeile Parameternamen zeigen als (iRow10CustomName_100): 1; 11. Zeile Parameternamen zeigen als (iRow11CustomName_100): 1; 12. Zeile Parameternamen zeigen als (iRow12CustomName_100): 1; 13. Zeile Parameternamen zeigen als (iRow13CustomName_100): 1; 14. Zeile Parameternamen zeigen als (iRow14CustomName_100): 1; 15. Zeile Parameternamen zeigen als (iRow15CustomName_100): 1; 16. Zeile Parameternamen zeigen als (iRow16CustomName_100): 1; 17. Zeile Parameternamen zeigen als (iRow17CustomName_100): 1; 18. Zeile Parameternamen zeigen als (iRow18CustomName_100): 1; 19. Zeile Parameternamen zeigen als (iRow19CustomName_100): 1; 20. Zeile Parameternamen zeigen als (iRow20CustomName_100): 1; Inhalt zum Überschreiben (iContentToOverride_100): 1; Überschreiben Titel-Textformat (bOverrideTitleTextFormat_100): yes; Raumname Schriftart (fontTitleType_100): Arial Westlich; Raumname Schriftgröße (mm) (fontTitleSizePaper_100): 2; Raumname Stil: 1; Raumname Stift (penTitle_100): Elemente+Text; Raumname Stift (penTitle_100_int): 1; Überschreiben Titel 2 Textformat (bOverrideTitle2TextFormat_100): no; Raumnummer Font Typ (fontTitle2Type_100): Arial; Raumnummer Font Größe (mm) (fontTitle2SizePaper_100): 2.5; Raumnummer Font-Stil (iTextStyleTitle2_100): 0; Raumnummer Stift (penTitle2_100): Schichttrennlinien/Kontur; Raumnummer Stift (penTitle2_100_int): 1; Überschreiben Daten-Textformat (bOverrideDataTextFormat_100): no; Daten Schriftart (fontDataType_100): Arial Westlich; Schriftgröße Daten (mm) (fontDataSizePaper_100): 2.5; Daten-Schrifttyp (iTextStyleData_100): 0; Daten-Stift (penData_100): Schichttrennlinien/Kontur; Daten-Stift (penData_100_int): 1; Schriftgröße (fontScaleType_100): Papiergröße; Schriftgröße (iFontScaleType_100): 2; Automat. Zeilenabstand (bAutomaticLineSpace_100): yes; Zeilenabstand in mm (lineSpacing_100): 4; Bemaßungseinheiten zeigen (bShowDimensionUnits_100): yes; Hochgestellt (bShowSuperScript_100): yes; Rahmen Stil (sFrameStyle_100): Stil 4; Rahmen Stil (iFrameStyle_100): 5; Feste Breite (bFixWidth_100): no; Breite in mm speichern (fixWidth_100): 30; Numerische Werte ausrichten (sAlignNumericalValues_100): Rechtsbündig; Numerische Werte ausrichten (iAlignNumericalValues_100): 4; Textwerte ausrichten (iAlignStringValues_100): 4; Höhenwert ausrichten (iAlignHeightValue_100): 1; Raumnummer ausrichten (iAlignZoneNr_100): 1; Fester Radius (bFixRadius_100): no; Kreisrahmen Radius in mm (frameRadius_100): 3; Rahmen-Stift (framePen_100): Elemente+Text; Linientyp Rahmen (frameLineType_100): 1; Einheitennummer Rahmen (apartmentIdFrame_100): Oval; Einheitennummer Rahmen (iApartmentIdFrame_100): 2; Hintergrundschraffur (bBackFill_100): yes; Schraffur (fillType_100): Nur Hintergrund-Stift; Schraffur-Vordergrundstift (fillPen_100): Elemente+Text; Schraffur-Hintergrundstift (fillBackPen_100): Transparent; Einheitennummer Winkel in 1:100: 0 deg; Anzahl der Reihen (nOrder_100): 4; Höhenwerte und Raumnummer Anzeigetyp (iDisplayType_100): 2; 1. (order_01_100): Raumname; 1. (iOrder_01_100): 2; 2. (order_02_100): Einheitenname; 2. (iOrder_02_100): 5; 3. (order_03_100): Raumflächen; 3. (iOrder_03_100): 9; 4. (order_04_100): Klassifizierung und Eigenschaften; 4. (iOrder_04_100): 14; 5. (order_05_100): ** Leere Zeile; 5. (iOrder_05_100): 1; 6. (order_06_100): ** Leere Zeile; 6. (iOrder_06_100): 1; 7. (order_07_100): ** Leere Zeile; 7. (iOrder_07_100): 1; 8. (order_08_100): ** Leere Zeile; 8. (iOrder_08_100): 1; 9. (order_09_100): ** Leere Zeile; 9. (iOrder_09_100): 1; 10. (order_10_100): ** Leere Zeile; 10. (iOrder_10_100): 1; 11. (order_11_100): Klassifizierung und Eigenschaften; 11. (iOrder_11_100): 14; 12. (order_12_100): ** Leere Zeile; 12. (iOrder_12_100): 1; Raumname zeigen (bShowZoneNameLine1_200): yes; Raumnummer zeigen (bShowZoneNum_200): no; Raumkategorie-Code zeigen (bShowZoneCatCode_200): no; 2. Raumnamen-Zeile zeigen (bShowZoneNameLine2_200): no; Einheitennummer zeigen (bShowApartmentID_200): yes; Einheitenname zeigen (bShowApartmentName_200): no; Zeige Apartment Identifikation (bShowApartmentCode_200): no; Zeige Treppenhaus Identifikatoren (bShowStaircaseCode_200): no; Position zeigen (bShowPosition_200): no; Hausnummer zeigen (bShowHouseNumber_200): no; Funktion zeigen (bShowFunctions_200): no; ID zeigen (bShowID_200): no; Bodenbelag zeigen (bShowFloor_200): no; Wandbelag zeigen (bShowWallFinish_200): no; Deckenbelag zeigen (bShowCeiling_200): no; Raumunterkante zeigen (bShowHeightZone_200): no; Fertigfußbodenhöhe zeigen (bShowHeightFloor_200): no; Abzugsflächen zeigen (bShowMeasuredArea_200): no; Gemessene Nettofläche zeigen (bShowMeasuredNetArea_200): no; DIN Abzugsflächen zeigen (bShowVentArea_200): no; Reduzierte Fläche zeigen (bShowReducedArea_200): no; Berechnete Fläche (NRF) zeigen (bShowCalculatedArea_200): yes; Fensterflächen zeigen (bShowWindowArea_200): no; Raumumfang zeigen (bShowPerimeter_200): no; Raumhöhe zeigen (bShowCeilingHeight_200): no; Raumvolumen zeigen (bShowVolume_200): no; Einordnung zeigen (bShowClassification_200): no; Eigenen Text zeigen 1 (bShowCustom1_200): no; Eigenen Text zeigen 2 (bShowCustom2_200): no; Eigenen Text zeigen 3 (bShowCustom3_200): no; Klassifizierung und Eigenschaften anzeigen (bShowAdditionalTags_200): no; Parameter auswählen (iTnCSelectParams_200): 1; Daten darstellen nach (iTncDisplayData_200): 1; 1. Zeile Parameternamen zeigen als (iRow1CustomName_200): 1; 2. Zeile Parameternamen zeigen als (iRow2CustomName_200): 1; 3. Zeile Parameternamen zeigen als (iRow3CustomName_200): 1; 4. Zeile Parameternamen zeigen als (iRow4CustomName_200): 1; 5. Zeile Parameternamen zeigen als (iRow5CustomName_200): 1; 6. Zeile Parameternamen zeigen als (iRow6CustomName_200): 1; 7. Zeile Parameternamen zeigen als (iRow7CustomName_200): 1; 8. Zeile Parameternamen zeigen als (iRow8CustomName_200): 1; 9. Zeile Parameternamen zeigen als (iRow9CustomName_200): 1; 10. Zeile Parameternamen zeigen als (iRow10CustomName_200): 1; 11. Zeile Parameternamen zeigen als (iRow11CustomName_200): 1; 12. Zeile Parameternamen zeigen als (iRow12CustomName_200): 1; 13. Zeile Parameternamen zeigen als (iRow13CustomName_200): 1; 14. Zeile Parameternamen zeigen als (iRow14CustomName_200): 1; 15. Zeile Parameternamen zeigen als (iRow15CustomName_200): 1; 16. Zeile Parameternamen zeigen als (iRow16CustomName_200): 1; 17. Zeile Parameternamen zeigen als (iRow17CustomName_200): 1; 18. Zeile Parameternamen zeigen als (iRow18CustomName_200): 1; 19. Zeile Parameternamen zeigen als (iRow19CustomName_200): 1; 20. Zeile Parameternamen zeigen als (iRow20CustomName_200): 1; Inhalt zum Überschreiben (iContentToOverride_200): 1; Überschreiben Titel-Textformat (bOverrideTitleTextFormat_200): yes; Raumname Schriftart (fontTitleType_200): Arial Westlich; Raumname Schriftgröße (mm) (fontTitleSizePaper_200): 2; Raumname Font-Stil (iTextStyleTitle_200): 1; Raumname Stift (penTitle_200): Elemente+Text; Raumname Stift (penTitle_200_int): 1; Überschreiben Titel 2 Textformat (bOverrideTitle2TextFormat_200): yes; Raumnummer Font Typ (fontTitle2Type_200): Arial; Raumnummer Font Größe (mm) (fontTitle2SizePaper_200): 1.5; Raumnummer Font-Stil (iTextStyleTitle2_200): 0; Raumnummer Stift (penTitle2_200): Schichttrennlinien/Kontur; Raumnummer Stift (penTitle2_200_int): 1; Überschreiben Daten-Textformat (bOverrideDataTextFormat_200): no; Daten Schriftart (fontDataType_200): Arial Westlich; Schriftgröße Daten (mm) (fontDataSizePaper_200): 1.5; Daten-Schrifttyp (iTextStyleData_200): 0; Daten-Stift (penData_200): Schichttrennlinien/Kontur; Daten-Stift (penData_200_int): 1; Schriftgröße (fontScaleType_200): Papiergröße; Schriftgröße (iFontScaleType_200): 2; Automat. Zeilenabstand (bAutomaticLineSpace_200): yes; Zeilenabstand in mm (lineSpacing_200): 4; Bemaßungseinheiten zeigen (bShowDimensionUnits_200): yes; Hochgestellt (bShowSuperScript_200): yes; Rahmen Stil (sFrameStyle_200): Keine; Rahmen Stil (iFrameStyle_200): 1; Feste Breite (bFixWidth_200): no; Breite in mm speichern (fixWidth_200): 30; Numerische Werte ausrichten (sAlignNumericalValues_200): Rechtsbündig; Numerische Werte ausrichten (iAlignNumericalValues_200): 4; Textwerte ausrichten (iAlignStringValues_200): 4; Höhenwert ausrichten (iAlignHeightValue_200): 1; Raumnummer ausrichten (iAlignZoneNr_200): 1; Fester Radius (bFixRadius_200): no; Kreisrahmen Radius in mm (frameRadius_200): 3; Rahmen-Stift (framePen_200): Elemente+Text; Linientyp Rahmen (frameLineType_200): 1; Einheitennummer Rahmen (apartmentIdFrame_200): Oval; Einheitennummer Rahmen (iApartmentIdFrame_200): 2; Hintergrundschraffur (bBackFill_200): yes; Schraffur (fillType_200): Nur Hintergrund-Stift; Schraffur-Vordergrundstift (fillPen_200): Elemente+Text; Schraffur-Hintergrundstift (fillBackPen_200): Transparent; Einheitennummer Winkel in 1:200: 0 deg; Anzahl der Reihen (nOrder_200): 2; Höhenwerte und Raumnummer Anzeigetyp (iDisplayType_200): 1; 1. (order_01_200): Raumname; 1. (iOrder_01_200): 2; 2. (order_02_200): Raumflächen; 2. (iOrder_02_200): 9; 3. (order_03_200): ** Leere Zeile; 3. (iOrder_03_200): 1; 4. (order_04_200): ** Leere Zeile; 4. (iOrder_04_200): 1; 5. (order_05_200): ** Leere Zeile; 5. (iOrder_05_200): 1; 6. (order_06_200): ** Leere Zeile; 6. (iOrder_06_200): 1; 7. (order_07_200): ** Leere Zeile; 7. (iOrder_07_200): 1; 8. (order_08_200): ** Leere Zeile; 8. (iOrder_08_200): 1; 9. (order_09_200): ** Leere Zeile; 9. (iOrder_09_200): 1; 10. (order_10_200): ** Leere Zeile; 10. (iOrder_10_200): 1; 11. (order_11_200): Klassifizierung und Eigenschaften; 11. (iOrder_11_200): 14; 12. (order_12_200): ** Leere Zeile; 12. (iOrder_12_200): 1; Raumname zeigen (bShowZoneNameLine1_0): yes; Raumnummer zeigen (bShowZoneNum_0): yes; Raumkategorie-Code zeigen (bShowZoneCatCode_0): no; 2. Raumnamen-Zeile zeigen (bShowZoneNameLine2_0): no; Einheitennummer zeigen (bShowApartmentID_0): no; Einheitenname zeigen (bShowApartmentName_0): no; Zeige Apartment Identifikation (bShowApartmentCode_0): no; Zeige Treppenhaus Identifikatoren (bShowStaircaseCode_0): no; Position zeigen (bShowPosition_0): no; Hausnummer zeigen (bShowHouseNumber_0): no; Funktion zeigen (bShowFunctions_0): no; ID zeigen (bShowID_0): no; Bodenbelag zeigen (bShowFloor_0): no; Wandbelag zeigen (bShowWallFinish_0): no; Deckenbelag zeigen (bShowCeiling_0): no; Raumunterkante zeigen (bShowHeightZone_0): no; Fertigfußbodenhöhe zeigen (bShowHeightFloor_0): no; Abzugsflächen zeigen (bShowMeasuredArea_0): no; Gemessene Nettofläche zeigen (bShowMeasuredNetArea_0): no; DIN Abzugsflächen zeigen (bShowVentArea_0): no; Reduzierte Fläche zeigen (bShowReducedArea_0): no; Berechnete Fläche (NRF) zeigen (bShowCalculatedArea_0): yes; Fensterflächen zeigen (bShowWindowArea_0): no; Raumumfang zeigen (bShowPerimeter_0): no; Raumhöhe zeigen (bShowCeilingHeight_0): no; Raumvolumen zeigen (bShowVolume_0): no; Einordnung zeigen (bShowClassification_0): no; Eigenen Text zeigen 1 (bShowCustom1_0): no; Eigenen Text zeigen 2 (bShowCustom2_0): no; Eigenen Text zeigen 3 (bShowCustom3_0): no; Klassifizierung und Eigenschaften anzeigen (bShowAdditionalTags_0): no; Parameter auswählen (iTnCSelectParams_0): 1; Daten darstellen nach (iTncDisplayData_0): 1; 1. Zeile Parameternamen zeigen als (iRow1CustomName_0): 1; 2. Zeile Parameternamen zeigen als (iRow2CustomName_0): 1; 3. Zeile Parameternamen zeigen als (iRow3CustomName_0): 1; 4. Zeile Parameternamen zeigen als (iRow4CustomName_0): 1; 5. Zeile Parameternamen zeigen als (iRow5CustomName_0): 1; 6. Zeile Parameternamen zeigen als (iRow6CustomName_0): 1; 7. Zeile Parameternamen zeigen als (iRow7CustomName_0): 1; 8. Zeile Parameternamen zeigen als (iRow8CustomName_0): 1; 9. Zeile Parameternamen zeigen als (iRow9CustomName_0): 1; 10. Zeile Parameternamen zeigen als (iRow10CustomName_0): 1; 11. Zeile Parameternamen zeigen als (iRow11CustomName_0): 1; 12. Zeile Parameternamen zeigen als (iRow12CustomName_0): 1; 13. Zeile Parameternamen zeigen als (iRow13CustomName_0): 1; 14. Zeile Parameternamen zeigen als (iRow14CustomName_0): 1; 15. Zeile Parameternamen zeigen als (iRow15CustomName_0): 1; 16. Zeile Parameternamen zeigen als (iRow16CustomName_0): 1; 17. Zeile Parameternamen zeigen als (iRow17CustomName_0): 1; 18. Zeile Parameternamen zeigen als (iRow18CustomName_0): 1; 19. Zeile Parameternamen zeigen als (iRow19CustomName_0): 1; 20. Zeile Parameternamen zeigen als (iRow20CustomName_0): 1; Inhalt zum Überschreiben (iContentToOverride_0): 1; Überschreiben Titel-Textformat (bOverrideTitleTextFormat_0): yes; Raumname Schriftart (fontTitleType_0): Arial Westlich; Raumname Schriftgröße (mm) (fontTitleSizePaper_0): 2.5; Raumname Font-Stil (iTextStyleTitle_0): 1; Raumname Stift (penTitle_0): Schichttrennlinien/Kontur; Raumname Stift (penTitle_0_int): 2; Überschreiben Titel 2 Textformat (bOverrideTitle2TextFormat_0): yes; Raumnummer Font Typ (fontTitle2Type_0): Arial Westlich; Raumnummer Font Größe (mm) (fontTitle2SizePaper_0): 2.5; Raumnummer Font-Stil (iTextStyleTitle2_0): 0; Raumnummer Stift (penTitle2_0): Schichttrennlinien/Kontur; Raumnummer Stift (penTitle2_0_int): 1; Überschreiben Daten-Textformat (bOverrideDataTextFormat_0): yes; Daten Schriftart (fontDataType_0): Arial Westlich; Schriftgröße Daten (mm) (fontDataSizePaper_0): 2.5; Daten-Schrifttyp (iTextStyleData_0): 0; Daten-Stift (penData_0): Schichttrennlinien/Kontur; Daten-Stift (penData_0_int): 1; Schriftgröße (fontScaleType_0): Papiergröße; Schriftgröße (iFontScaleType_0): 2; Automat. Zeilenabstand (bAutomaticLineSpace_0): yes; Zeilenabstand in mm (lineSpacing_0): 4; Bemaßungseinheiten zeigen (bShowDimensionUnits_0): yes; Hochgestellt (bShowSuperScript_0): yes; Rahmen Stil (sFrameStyle_0): Stil 4; Rahmen Stil (iFrameStyle_0): 5; Feste Breite (bFixWidth_0): no; Breite in mm speichern (fixWidth_0): 30; Numerische Werte ausrichten (iAlignNumericalValues_0): 4; Textwerte ausrichten (iAlignStringValues_0): 4; Höhenwert ausrichten (iAlignHeightValue_0): 1; Raumnummer ausrichten (iAlignZoneNr_0): 1; Fester Radius (bFixRadius_0): no; Kreisrahmen Radius in mm (frameRadius_0): 3; Rahmen-Stift (framePen_0): Elemente+Text; Linientyp Rahmen (frameLineType_0): 1; Einheitennummer Rahmen (apartmentIdFrame_0): Oval; Einheitennummer Rahmen (iApartmentIdFrame_0): 2; Hintergrundschraffur (bBackFill_0): yes; Schraffur (fillType_0): Nur Hintergrund-Stift; Schraffur-Vordergrundstift (fillPen_0): Elemente+Text; Schraffur-Hintergrundstift (fillBackPen_0): Transparent; Einheitennummer Winkel: 0 deg; Anzahl der Reihen (nOrder_0): 9; Höhenwerte und Raumnummer Anzeigetyp (iDisplayType_0): 2; 1. (order_01_0): Raumname; 1. (iOrder_01_0): 2; 2. (order_02_0): Einheitennummer; 2. (iOrder_02_0): 4; 3. (order_03_0): Einheitenname; 3. (iOrder_03_0): 5; 4. (order_04_0): Beläge; 4. (iOrder_04_0): 6; 5. (order_05_0): Höhenwerte und Raumnummer; 5. (iOrder_05_0): 8; 6. (order_06_0): Raumflächen; 6. (iOrder_06_0): 9; 7. (order_07_0): Fensterfläche; 7. (iOrder_07_0): 10; 8. (order_08_0): Umfang, Höhe, Volumen; 8. (iOrder_08_0): 11; 9. (order_09_0): Flächencode; 9. (iOrder_09_0): 12; 10. (order_10_0): ** Leere Zeile; 10. (iOrder_10_0): 1; 11. (order_11_0): Klassifizierung und Eigenschaften; 11. (iOrder_11_0): 14; 12. (order_12_0): ** Leere Zeile; 12. (iOrder_12_0): 1; Kategorie als Name verwenden: no; ID zeigen als...: 1; Position: <Position>; Hausnummer: <Hausnummer>; Bezeichnung Erschließung: <Treppenhaus>; Bodenbelag Titel: FB; Bodenbelag: <Fertigboden>; Bezeichnung Wandbelag: WB; Wandbelag Material: <Wandmaterial>; Deckenbelag Titel: DB; Deckenbelag: <Material Deckenbelag>; Berechnet OK Fertigfußboden: yes; Eigene OK Fertigfußboden: ±0.00; Präfix OK Fertigfussboden (sPrefixFloorLevel): Marker; Präfix OK Fertigfussboden (iPrefixFloorLevel): 1; Fertigfußbodenhöhe Titel: FFB; Marker für Fertigfußboden: 1; Berechnet OK Rohfußboden: yes; Eigene Rohfußboden OK: -0.10; Höhenlage Raum Präfix (sPrefixZoneLevel): Marker; Höhenlage Raum Präfix (iPrefixZoneLevel): 1; Raumunterkante Betzeichnung: RUK; Marker für Unterboden: 3; Zeichen Schraffur: Nur Hintergrund-Stift; Zeichen Schraffur-Vordergrundstift: Elemente+Text; Untergeordneter Schraffur: Nur Vordergrund-Stift; Untergeordneter Schraffur-Vordergrundstift: Schichttrennlinien/Kontur; Gemessene Fläche Kürzel: B; Gemessene Nettofläche Kürzel: BF; Abzugsflächen Kürzel: AF; Reduzierte Fläche Kürzel: RF; Berechnete Fläche (NRF) Kürzel: NGF; Fensterfläche Kürzel: FF; Raumumfang Kürzel: RU; Raumhöhe Kürzel: RH; Raumvolumen Kürzel: RV; Abzug gemäß WoFlV: no; Abzug in % (Balkone, Loggien): 0; Putzabzug: 0; Bereich: R; Flächencode Titel: Bereich; Einheiten Zuordnung: 1; Zeige Apartment Identifikation Präfix: no; Treppenhaus Zuordnung: 1; Eigene Treppenhaus Identifikation: <Treppenhaus>; Haus Zuordnung (iHouseCode): 1; Haus Zuordnung (asAddOn_stHouseCode): <Hausnummer>; Position Zuordnung (iPositionCode): 1; Position Zuordnung (asAddOn_stPositionCode): <Position>; Preis per m2: 0; Preis per m3: 0; Preis berechnet aus gemessener Fläche: 0; Preis berechnet aus gemessener Nettofläche: 0; Preis berechnet aus Reduzierte Fläche: 0; Preis berechnet aus berechneter Fläche (NRF): 0; Preis berechnet aus Nettovolumen: 0; Preis berechnet aus Bruttovolumen: 0; DWG-Export Typ: Standardraum; Drehwinkel: 0 deg
Räume - Fenster/Raum (%): 0
ArchiCADQuantities - Grundriss-Durchbruch Umfang: 0 m; Anzahl der Unterzüge: 0; Anzahl der Stützen: 0; Anzahl der Lichtquelle: 0; Anzahl der Objekte: 0; Anzahl der Fenster: 0; Fenster-Oberflächenbereich: 0 m2; Fenster Breite: 0 m; Raumflächen Reduzierung: 1 m2; Stützenabzugsfläche: 0 m2; Schraffurabzugsfläche: 0 m2; Niedrige Abzugsfläche: 0 m2; Wandabzugsfläche: 0 m2; Anzahl der konkaven Ecken: 0; Anzahl der Ecken: 4; Gesamtabzugsfläche: 0 m2; Heizkörpernische Oberflächenbereich hinten: 0 m2; Heizkörpernische Oberflächenbereich seitlich: 0 m2; Heizkörpernische Oberflächenbereich oben: 0 m2
AC_Equantity_Raumstempel_DIN_22 - Gesamtlänge aller Bodenkanten: 0 m; Summe Öffnungsbreite Fenster: 0 m; Raumname Schriftgröße (modell) (fontTitleSizeModel_50): 0.25 m; Raumnummer Font Größe (Modell) (fontTitle2SizeModel_50): 0.25 m; Daten Schriftgröße (modell) (fontDataSizeModel_50): 0.25 m; X Distanz in 1:50: 0 m; Y Distanz in 1:50: 0 m; Einheitennummer Position (X) in 1:50: 0 m; Einheitennummer Position (Y) in 1:50: 0 m; Raumname Schriftgröße (modell) (fontTitleSizeModel_100): 0.25 m; Raumnummer Font Größe (Modell) (fontTitle2SizeModel_100): 0.25 m; Daten Schriftgröße (modell) (fontDataSizeModel_100): 0.25 m; X Distanz in 1:100: 0 m; Y Distanz in 1:100: 0 m; Einheitennummer Position (X) in 1:100: 0 m; Einheitennummer Position (Y) in 1:100: 0 m; Raumname Schriftgröße (modell) (fontTitleSizeModel_200): 0.25 m; Raumnummer Font Größe (Modell) (fontTitle2SizeModel_200): 0.25 m; Daten Schriftgröße (modell) (fontDataSizeModel_200): 0.25 m; X Distanz in 1:200: 0 m; Y Distanz in 1:200: 0 m; Einheitennummer Position (X) in 1:200: 0 m; Einheitennummer Position (Y) in 1:200: 0 m; Raumname Schriftgröße (modell) (fontTitleSizeModel_0): 0.25 m; Raumnummer Font Größe (Modell) (fontTitle2SizeModel_0): 0.25 m; Daten Schriftgröße (modell) (fontDataSizeModel_0): 0.25 m; X Abstand: 0 m; Y Abstand: 0 m; Einheitennummer Position (X): 0 m; Einheitennummer Position (Y): 0 m; Kreis Temp Radius: 0.3 m
Name | In | LongName = Zugehöriger Raumname = ArchiCADProperties, Raumname = AC_Pset_Raumstempel_DIN_22, Raumname | Element ID = Hotlink und Element-ID = Überobjekt-ID | Ebene | Kollidierende Räume | Zugehörige Raumnummer = ArchiCADProperties, Raumnummer = AC_Pset_Raumstempel_DIN_22, Raumnummer | Ursprungsgeschoss Name | Ursprungsgeschoss Nummer | Reduzierte Fläche = AC_Pset_Raumstempel_DIN_22, Gemessene Nettofläche = Reduzierte Fläche (ROOM_REDUCED_AREA) = AC_Pset_Raumstempel_DIN_22, Berechnete Fläche (NRF) = Unterer Oberflächenbereich = DIN berechnete Fläche = Reduzierte Fläche (room_calc_area_reduced) = NetFloorArea (m2) = SpaceNetFloorAreaBOMA (m2) = SpaceUsableFloorAreaBOMA (m2) = NetCeilingArea (m2) = ArchiCADQuantities, Berechnete Fläche (NRF) (m2) = ArchiCADQuantities, Gemessene Nettofläche (m2) | Verbundene 3D Element(e) | AC_Pset_Raumstempel_DIN_22, Gemessene Fläche = Oberer Oberflächenbereich = GrossFloorArea (m2) = GrossCeilingArea (m2) = Fläche (m2) = ArchiCADQuantities, Gemessene Fläche (m2) | Oberfläche Umfassungswände | Fläche der Türen | Raumvolumen | Begrenzung Oberflächenbereich | Einheitennummer zeigen (bShowApartmentID_50) | Einheitenname zeigen (bShowApartmentName_50) = Einheitenname zeigen (bShowApartmentName_100) | Einheitennummer = Eigene Einheiten Zuordnung | Einheitenname | DIN abgezogene Fläche | Height (m) = FinishCeilingHeight (m) = ClearHeight (m) = Höhe (m) = Raumhöhe (m) | FinishFloorHeight (m) = Fußbodendicke (m) = Stärke Bodenaufbau (m) | GrossWallArea (m2) | NetWallArea (m2) = Wand-Oberflächenbereich (m2) | GrossPerimeter (m) = NetPerimeter (m) = Raumflächen Nettoumfang (m) = Raum Brutto-Umfang (m) = Raumumfang (m) = Nettoumfang (m) | GrossVolume (m3) | NetVolume (m3) = Netto-Volumen (m3) | Höhenangabe zum Projekt-Nullpunkt (m) = Höhe zu 1. Referenzhöhe (m) = Höhe zu 2. Referenzhöhe (m) = Raum zu 0,00 (m) | Höhe zu Meereshöhe (m) | Höhe zu verknüpftem/Ursprungsgeschoss (m) = Abstand zu Ursprungsgeschoss (m) = Basislevel (m) = Höhenkote OK Rohdecke (m) | Abstand Oberkante (m) | Anzahl der Türen | Anzahl der Wandelemente | Türen-Oberflächenbereich (m2) | Türen Breite (m) | Wand Umfang (m) = Gesamtlänge Raumumfassung (m) | Summe Öffnungsbreite Türen (m)
R-016 | -1. Geschoss | Tiefgaragenabfahrt | Raum-016 | Bauantrag | Garage; Gelände; Untergeschoss UG | R-016 | -1. Geschoss | -1 | 54.2586 | Decke-012; Raum-003; Raum-013; Raum-024; Tür-003; Wand-004; Wand-005 | 54.2586 | 30.8295 | 6.321 | 151.924 | 85.5982 | no | yes | 01 | Haus | 0 | 2.8 | 0 | 9.898 | 9.898 | 30.5708 | 151.924 | 151.924 | -2.8 | 13.2 | 0 | 0 | 0 | 2 | 0 | 0 | 13.845 | 3.01 | BauantragZufahrten - IstEinbahnstraße: no; BauantragGrundstücksflächen - IstGemeinschaftsanlage: yes; IstVersiegelt: yes
R-010 | -1. Geschoss | Treppenhaus | Raum-010 | Raum Ausbauraum | Treppenhaus UG | R-010 | -1. Geschoss | -1 | 9.4256 | Geländer-001; Raum-023; Treppe-003 | 9.4256 | 48.6459 | 2.0301 | 20.7363 | 27.192 | yes | yes | -1.04 | Haus | 2.20574e-07 | 2.2 | 0 | 27.72 | 25.6899 | 12.36 | 20.7363 | 20.7363 | -2.8 | 13.2 | 0 | -0.6 | 1 | 5 | 2.0301 | 1.01 | 27.46 | 1.01 | Pset_SpaceCommon - ConcealedCeiling: no; ConcealedFlooring: no; BauantragRäume - istNGF: yes; Pset_SpaceFireSafetyRequirements - FireExit: yes; AC_Pset_Raumstempel_DIN_22 - 1. Zeile (sIDRow1_100): IFC.PSet.Pset_BauantragRäume.istNGF; Brandschutz 4102-2 - Brandabschnitt: Fluchtweg
R-017 | -1. Geschoss | Rampe | Raum-017 | Bauantrag | Gelände | R-017 | -1. Geschoss | -1 | 0.00215475 | Raum-003 | 53.9299 | 0 | 0 | 63.0039 | 38.5116 | no | yes | 01 | Haus | 53.9278 | 2.8 | 0 | 0 | 0 | 11.2108 | 151.004 | 75.5079 | -2.8 | 13.2 | 0 | 0 | 0 | 0 | 0 | 0 | 0 | 0 | BauantragZufahrten - IstEinbahnstraße: no; BauantragGrundstücksflächen - IstGemeinschaftsanlage: yes; IstVersiegelt: yes; Pset_SpaceParkingAisle - IsOneWay: no; Räume - Bodenbelag: Estrich, unbehandelt
R-000 | -1. Geschoss | Stellplatz | Raum-018 | Bauantrag | Garage; Untergeschoss UG | R-000 | -1. Geschoss | -1 | 12.4982 | Raum-013; Raum-024 | 12.4982 | 0 | 0 | 24.9965 | 29.9978 | yes | yes | P3 | Wohnung 1 | 0 | 2 | 0.1 | 9.99921 | 9.99921 | 14.9989 | 24.9965 | 24.9965 | -2.9 | 13.1 | -0.1 | 2.03 | 0 | 1 | 0 | 0 | 0 | 0 | Pset_SpaceParking - ParkingUnits: 1; HandicapAccessible: yes; ParkingUse: PKW; BauantragStellplätze - Art: PKW; Anzahl: 1; Nutzungseinheit: Wohnung 1
R-0001 | -1. Geschoss | Stellplatz | Raum-018 | Bauantrag | Garage; Untergeschoss UG | R-0001 | -1. Geschoss | -1 | 12.4982 | Raum-013; Raum-024 | 12.4982 | 0 | 0 | 24.9965 | 29.9978 | yes | yes | P2 | Wohnung 2 | 0 | 2 | 0.1 | 9.99921 | 9.99921 | 14.9989 | 24.9965 | 24.9965 | -2.9 | 13.1 | -0.1 | 2.03 | 0 | 1 | 0 | 0 | 0 | 0 | Pset_SpaceParking - ParkingUnits: 1; HandicapAccessible: yes; ParkingUse: PKW; BauantragStellplätze - Art: PKW; Anzahl: 1; Nutzungseinheit: Wohnung 2
R-010 | EG | Treppenhaus | Raum-010 | Raum Ausbauraum | Erdgeschoss; Grundfläche Gebäude Nachgezogen; Untergeschoss UG; Wohnung1 EG; Wohnung2 EG | R-010 | EG | 0 | 9.65052 | Geländer-001; Geländer-004; Morph-014; Raum-002; Raum-019; Raum-020; Raum-021; Raum-024; Tür-001; Tür-001; Wand-001; Wand-001; Wand-002; Wand-002; Wand-003; Wand-004 | 9.65052 | 35.5373 | 1.77885 | 34.7419 | 44.9668 | yes | yes | 0.09 | Haus | 1.77636e-15 | 3.6 | 0 | 6.28218 | 4.50333 | 12.4908 | 34.7419 | 34.7419 | -0.3 | 15.7 | -0.3 | -0.45 | 1 | 2 | 1.77885 | 0.885 | 16.05 | 0.885 | Pset_SpaceCommon - ConcealedCeiling: no; ConcealedFlooring: no; BauantragRäume - istNGF: yes; Pset_SpaceFireSafetyRequirements - FireExit: yes; AC_Pset_Raumstempel_DIN_22 - 1. Zeile (sIDRow1_100): IFC.PSet.Pset_BauantragRäume.istNGF; Brandschutz 4102-2 - Brandabschnitt: Fluchtweg; Räume - Bodenbelag: Estrich, unbehandelt; Wandbelag: Farbe; Deckenbelag: Farbe
R-000 | EG | Parkplatz | Raum-018 | Bauantrag |  | R-000 | EG | 0 | 14.9981 |  | 14.9981 | 0 | 0 | 37.4952 | 42.4972 | yes | no | P1 | Haus | -3.55271e-15 | 2.5 | 0.1 | 0 | 0 | 16.9989 | 37.4952 | 37.4952 | -0.1 | 15.9 | -0.1 | 2.03 | 0 | 0 | 0 | 0 | 0 | 0 | BauantragGrundstücksflächen - IstGemeinschaftsanlage: yes; IstVersiegelt: yes; IstNebenanlage: yes; Pset_SpaceParking - ParkingUnits: 1; HandicapAccessible: yes; ParkingUse: PKW; BauantragStellplätze - Art: PKW; Anzahl: 1

# IfcSpace: Wohnen und Aufenthalt (14)
Classification: Raum (ARCHICAD Klassifizierung); 1 NUF Wohnen und Aufenthalt
Pset_SpaceCommon - Category: Wohnen und Aufenthalt
BauantragNettoflächen - Art: NUF1; Raumumschließung: REGELFALL
ArchiCADProperties - Bibliothekselement-Name: Raumstempel DIN 22; Geschützt: no; Typ: Raum; Absolutes Geschoss für Oberkantenverknüpfung: Nicht verknüpft; Relatives Geschoss für Oberkantenverknüpfung: Nicht verknüpft; Geschoss für Oberkantenverknüpfung: Nicht verknüpft; Oberfläche (Alle): Raumstempel; Deckschraffur: Misch-Schraffur 0%; Anzeigen auf Umbau-Filter: Alle relevanten Filter; Umbau-Status: Bestand; Oberfläche: Raumstempel; Einheitliche Oberfläche: yes; Raumkategorie: 0; Raumflächen-Code: 1 NUF; ARCHICAD Klassifizierung - 22: Raum
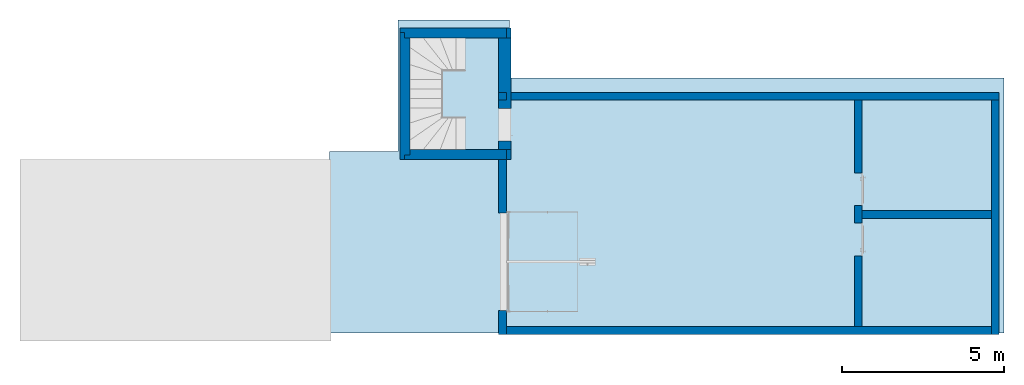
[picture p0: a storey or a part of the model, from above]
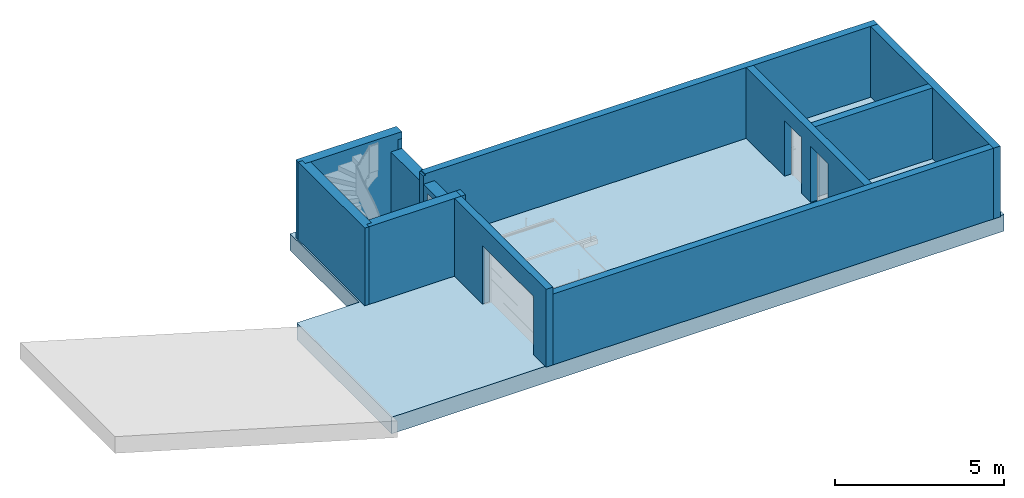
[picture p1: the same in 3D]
Properties of the parts of a building model (IFC4), part 3 of 13

# IfcSpace: Wohnen und Aufenthalt (14)
AC_Pset_Raumstempel_DIN_22 - Schriftgröße 1 (Grundeinstell.): 2; Textstil 1 (Grundeinstellung): 0; Markertext 1 Ausrichtung (Standard): 2; Markertext 1 Zeilenabstand (Standard): 1; Markertext 1 Zeichenbreite-Faktor (Standard): 1; Markertext 1 Textzeichenbreite-Faktor (Standard): 1; Schriftart 1: Arial Westlich; Stift Text (Grundeinstellung): Elemente+Text; Wandabzugsfläche: 0; Fassaden- Abzugsfläche: 0; Stützenabzugsfläche: 0; Schraffurabzugsfläche: 0; Raumfläche Faktor: 1; Dach Oberflächenbereich an der Oberseite: 0; Dach Oberflächenbereich an der Unterseite: 0; Decke Oberflächenbereich an der Oberseite: 0; Decke Oberflächenbereich an der Unterseite: 0; Unterzug Oberflächenbereich an der Oberseite: 0; Unterzugoberfläche unten: 0; Oberer Oberflächenbereich der Wandeinsätze: 0; Oberfläche Wandnischen hinten: 0; Seite Oberflächenbereich der Wandeinsätze: 0; Maßstabsabhängig: yes; Maßstab (displayScale): 1:100; Maßstab (iDisplayScale): 2; Raumname zeigen (bShowZoneNameLine1_50): yes; Raumnummer zeigen (bShowZoneNum_50): yes; Raumkategorie-Code zeigen (bShowZoneCatCode_50): no; 2. Raumnamen-Zeile zeigen (bShowZoneNameLine2_50): no; Einheitennummer zeigen (bShowApartmentID_50): yes; Einheitenname zeigen (bShowApartmentName_50): yes; Zeige Apartment Identifikation (bShowApartmentCode_50): no; Zeige Treppenhaus Identifikatoren (bShowStaircaseCode_50): no; Position zeigen (bShowPosition_50): no; Hausnummer zeigen (bShowHouseNumber_50): no; Funktion zeigen (bShowFunctions_50): no; ID zeigen (bShowID_50): no; Bodenbelag zeigen (bShowFloor_50): no; Wandbelag zeigen (bShowWallFinish_50): no; Deckenbelag zeigen (bShowCeiling_50): no; Raumunterkante zeigen (bShowHeightZone_50): yes; Fertigfußbodenhöhe zeigen (bShowHeightFloor_50): yes; Abzugsflächen zeigen (bShowMeasuredArea_50): no; Gemessene Nettofläche zeigen (bShowMeasuredNetArea_50): yes; DIN Abzugsflächen zeigen (bShowVentArea_50): no; Reduzierte Fläche zeigen (bShowReducedArea_50): no; Berechnete Fläche (NRF) zeigen (bShowCalculatedArea_50): yes; Fensterflächen zeigen (bShowWindowArea_50): no; Raumumfang zeigen (bShowPerimeter_50): no; Raumhöhe zeigen (bShowCeilingHeight_50): yes; Einordnung zeigen (bShowClassification_50): no; Eigenen Text zeigen 1 (bShowCustom1_50): no; Eigenen Text zeigen 2 (bShowCustom2_50): no; Eigenen Text zeigen 3 (bShowCustom3_50): no; Klassifizierung und Eigenschaften anzeigen (bShowAdditionalTags_50): yes; Parameter auswählen (iTnCSelectParams_50): 1; Daten darstellen nach (iTncDisplayData_50): 1; 1. Zeile Parameternamen zeigen als (iRow1CustomName_50): 1; 2. Zeile Parameternamen zeigen als (iRow2CustomName_50): 1; 3. Zeile Parameternamen zeigen als (iRow3CustomName_50): 1; 4. Zeile Parameternamen zeigen als (iRow4CustomName_50): 1; 5. Zeile Parameternamen zeigen als (iRow5CustomName_50): 1; 6. Zeile Parameternamen zeigen als (iRow6CustomName_50): 1; 7. Zeile Parameternamen zeigen als (iRow7CustomName_50): 1; 8. Zeile Parameternamen zeigen als (iRow8CustomName_50): 1; 9. Zeile Parameternamen zeigen als (iRow9CustomName_50): 1; 10. Zeile Parameternamen zeigen als (iRow10CustomName_50): 1; 11. Zeile Parameternamen zeigen als (iRow11CustomName_50): 1; 12. Zeile Parameternamen zeigen als (iRow12CustomName_50): 1; 13. Zeile Parameternamen zeigen als (iRow13CustomName_50): 1; 14. Zeile Parameternamen zeigen als (iRow14CustomName_50): 1; 15. Zeile Parameternamen zeigen als (iRow15CustomName_50): 1; 16. Zeile Parameternamen zeigen als (iRow16CustomName_50): 1; 17. Zeile Parameternamen zeigen als (iRow17CustomName_50): 1; 18. Zeile Parameternamen zeigen als (iRow18CustomName_50): 1; 19. Zeile Parameternamen zeigen als (iRow19CustomName_50): 1; 20. Zeile Parameternamen zeigen als (iRow20CustomName_50): 1; Inhalt zum Überschreiben (iContentToOverride_50): 1; Überschreiben Titel-Textformat (bOverrideTitleTextFormat_50): yes; Raumname Schriftart (fontTitleType_50): Arial Westlich; Raumname Schriftgröße (mm) (fontTitleSizePaper_50): 2; Raumname Font-Stil (iTextStyleTitle_50): 1; Raumname Stift (penTitle_50): Elemente+Text; Raumname Stift (penTitle_50_int): 1; Überschreiben Titel 2 Textformat (bOverrideTitle2TextFormat_50): no; Raumnummer Font Typ (fontTitle2Type_50): Arial Westlich; Raumnummer Font Größe (mm) (fontTitle2SizePaper_50): 2.5; Raumnummer Font-Stil (iTextStyleTitle2_50): 0; Raumnummer Stift (penTitle2_50): Schichttrennlinien/Kontur; Raumnummer Stift (penTitle2_50_int): 1; Überschreiben Daten-Textformat (bOverrideDataTextFormat_50): no; Daten Schriftart (fontDataType_50): Arial Westlich; Schriftgröße Daten (mm) (fontDataSizePaper_50): 2.5; Daten-Schrifttyp (iTextStyleData_50): 0; Daten-Stift (penData_50): Schichttrennlinien/Kontur; Daten-Stift (penData_50_int): 1; Schriftgröße (fontScaleType_50): Papiergröße; Schriftgröße (iFontScaleType_50): 2; Automat. Zeilenabstand (bAutomaticLineSpace_50): yes; Zeilenabstand in mm (lineSpacing_50): 4; Bemaßungseinheiten zeigen (bShowDimensionUnits_50): yes; Hochgestellt (bShowSuperScript_50): yes; Feste Breite (bFixWidth_50): no; Breite in mm speichern (fixWidth_50): 50; Numerische Werte ausrichten (sAlignNumericalValues_50): Rechtsbündig; Numerische Werte ausrichten (iAlignNumericalValues_50): 4; Textwerte ausrichten (iAlignStringValues_50): 4; Höhenwert ausrichten (iAlignHeightValue_50): 3; Raumnummer ausrichten (iAlignZoneNr_50): 1; Fester Radius (bFixRadius_50): no; Kreisrahmen Radius in mm (frameRadius_50): 3; Rahmen-Stift (framePen_50): Elemente+Text; Linientyp Rahmen (frameLineType_50): 1; Einheitennummer Rahmen (apartmentIdFrame_50): Oval; Einheitennummer Rahmen (iApartmentIdFrame_50): 2; Hintergrundschraffur (bBackFill_50): yes; Schraffur (fillType_50): Nur Hintergrund-Stift; Schraffur-Vordergrundstift (fillPen_50): Elemente+Text; Schraffur-Hintergrundstift (fillBackPen_50): Transparent; Einheitennummer Winkel in 1:50: 0 deg; Anzahl der Reihen (nOrder_50): 7; Höhenwerte und Raumnummer Anzeigetyp (iDisplayType_50): 2; 1. (order_01_50): Raumname; 1. (iOrder_01_50): 2; 2. (order_02_50): Einheitenname; 2. (iOrder_02_50): 5; 3. (order_03_50): Einheitennummer; 3. (iOrder_03_50): 4; 4. (order_04_50): Beläge; 4. (iOrder_04_50): 6; 5. (order_05_50): Raumflächen; 5. (iOrder_05_50): 9; 6. (order_06_50): Umfang, Höhe, Volumen; 6. (iOrder_06_50): 11; 7. (order_07_50): Klassifizierung und Eigenschaften; 7. (iOrder_07_50): 14; 8. (order_08_50): ** Leere Zeile; 8. (iOrder_08_50): 1; 9. (order_09_50): ** Leere Zeile; 9. (iOrder_09_50): 1; 10. (order_10_50): ** Leere Zeile; 10. (iOrder_10_50): 1; 11. (order_11_50): ** Leere Zeile; 11. (iOrder_11_50): 1; 12. (order_12_50): ** Leere Zeile; 12. (iOrder_12_50): 1; Raumname zeigen (bShowZoneNameLine1_100): yes; Raumnummer zeigen (bShowZoneNum_100): yes; Raumkategorie-Code zeigen (bShowZoneCatCode_100): no; 2. Raumnamen-Zeile zeigen (bShowZoneNameLine2_100): yes; Einheitennummer zeigen (bShowApartmentID_100): yes; Einheitenname zeigen (bShowApartmentName_100): yes; Zeige Apartment Identifikation (bShowApartmentCode_100): no; Zeige Treppenhaus Identifikatoren (bShowStaircaseCode_100): no; Position zeigen (bShowPosition_100): no; Hausnummer zeigen (bShowHouseNumber_100): no; Funktion zeigen (bShowFunctions_100): no; ID zeigen (bShowID_100): no; Bodenbelag zeigen (bShowFloor_100): no; Wandbelag zeigen (bShowWallFinish_100): no; Deckenbelag zeigen (bShowCeiling_100): no; Raumunterkante zeigen (bShowHeightZone_100): no; Fertigfußbodenhöhe zeigen (bShowHeightFloor_100): no; Abzugsflächen zeigen (bShowMeasuredArea_100): no; Gemessene Nettofläche zeigen (bShowMeasuredNetArea_100): no; DIN Abzugsflächen zeigen (bShowVentArea_100): no; Reduzierte Fläche zeigen (bShowReducedArea_100): no; Berechnete Fläche (NRF) zeigen (bShowCalculatedArea_100): yes; Fensterflächen zeigen (bShowWindowArea_100): no; Raumumfang zeigen (bShowPerimeter_100): no; Raumhöhe zeigen (bShowCeilingHeight_100): no; Raumvolumen zeigen (bShowVolume_100): no; Einordnung zeigen (bShowClassification_100): no; Eigenen Text zeigen 1 (bShowCustom1_100): no; Eigenen Text zeigen 2 (bShowCustom2_100): no; Eigenen Text zeigen 3 (bShowCustom3_100): no; Klassifizierung und Eigenschaften anzeigen (bShowAdditionalTags_100): yes; Parameter auswählen (iTnCSelectParams_100): 1; Daten darstellen nach (iTncDisplayData_100): 1; 1. Zeile Parameternamen zeigen als (iRow1CustomName_100): 1; 2. Zeile Parameternamen zeigen als (iRow2CustomName_100): 1; 3. Zeile Parameternamen zeigen als (iRow3CustomName_100): 1; 4. Zeile Parameternamen zeigen als (iRow4CustomName_100): 1; 5. Zeile Parameternamen zeigen als (iRow5CustomName_100): 1; 6. Zeile Parameternamen zeigen als (iRow6CustomName_100): 1; 7. Zeile Parameternamen zeigen als (iRow7CustomName_100): 1; 8. Zeile Parameternamen zeigen als (iRow8CustomName_100): 1; 9. Zeile Parameternamen zeigen als (iRow9CustomName_100): 1; 10. Zeile Parameternamen zeigen als (iRow10CustomName_100): 1; 11. Zeile Parameternamen zeigen als (iRow11CustomName_100): 1; 12. Zeile Parameternamen zeigen als (iRow12CustomName_100): 1; 13. Zeile Parameternamen zeigen als (iRow13CustomName_100): 1; 14. Zeile Parameternamen zeigen als (iRow14CustomName_100): 1; 15. Zeile Parameternamen zeigen als (iRow15CustomName_100): 1; 16. Zeile Parameternamen zeigen als (iRow16CustomName_100): 1; 17. Zeile Parameternamen zeigen als (iRow17CustomName_100): 1; 18. Zeile Parameternamen zeigen als (iRow18CustomName_100): 1; 19. Zeile Parameternamen zeigen als (iRow19CustomName_100): 1; 20. Zeile Parameternamen zeigen als (iRow20CustomName_100): 1; Inhalt zum Überschreiben (iContentToOverride_100): 1; Überschreiben Titel-Textformat (bOverrideTitleTextFormat_100): yes; Raumname Schriftart (fontTitleType_100): Arial Westlich; Raumname Schriftgröße (mm) (fontTitleSizePaper_100): 2; Raumname Stil: 1; Raumname Stift (penTitle_100): Elemente+Text; Raumname Stift (penTitle_100_int): 1; Überschreiben Titel 2 Textformat (bOverrideTitle2TextFormat_100): no; Raumnummer Font Typ (fontTitle2Type_100): Arial; Raumnummer Font Größe (mm) (fontTitle2SizePaper_100): 2.5; Raumnummer Font-Stil (iTextStyleTitle2_100): 0; Raumnummer Stift (penTitle2_100): Schichttrennlinien/Kontur; Raumnummer Stift (penTitle2_100_int): 1; Überschreiben Daten-Textformat (bOverrideDataTextFormat_100): no; Daten Schriftart (fontDataType_100): Arial Westlich; Schriftgröße Daten (mm) (fontDataSizePaper_100): 2.5; Daten-Schrifttyp (iTextStyleData_100): 0; Daten-Stift (penData_100): Schichttrennlinien/Kontur; Daten-Stift (penData_100_int): 1; Schriftgröße (fontScaleType_100): Papiergröße; Schriftgröße (iFontScaleType_100): 2; Automat. Zeilenabstand (bAutomaticLineSpace_100): yes; Zeilenabstand in mm (lineSpacing_100): 4; Bemaßungseinheiten zeigen (bShowDimensionUnits_100): yes; Hochgestellt (bShowSuperScript_100): yes; Rahmen Stil (sFrameStyle_100): Stil 4; Rahmen Stil (iFrameStyle_100): 5; Feste Breite (bFixWidth_100): no; Breite in mm speichern (fixWidth_100): 30; Numerische Werte ausrichten (sAlignNumericalValues_100): Rechtsbündig; Numerische Werte ausrichten (iAlignNumericalValues_100): 4; Textwerte ausrichten (iAlignStringValues_100): 4; Höhenwert ausrichten (iAlignHeightValue_100): 1; Raumnummer ausrichten (iAlignZoneNr_100): 1; Fester Radius (bFixRadius_100): no; Kreisrahmen Radius in mm (frameRadius_100): 3; Rahmen-Stift (framePen_100): Elemente+Text; Linientyp Rahmen (frameLineType_100): 1; Einheitennummer Rahmen (apartmentIdFrame_100): Oval; Einheitennummer Rahmen (iApartmentIdFrame_100): 2; Hintergrundschraffur (bBackFill_100): yes; Schraffur (fillType_100): Nur Hintergrund-Stift; Schraffur-Vordergrundstift (fillPen_100): Elemente+Text; Schraffur-Hintergrundstift (fillBackPen_100): Transparent; Einheitennummer Winkel in 1:100: 0 deg; Anzahl der Reihen (nOrder_100): 4; Höhenwerte und Raumnummer Anzeigetyp (iDisplayType_100): 2; 1. (order_01_100): Raumname; 1. (iOrder_01_100): 2; 2. (order_02_100): Einheitenname; 2. (iOrder_02_100): 5; 3. (order_03_100): Raumflächen; 3. (iOrder_03_100): 9; 4. (order_04_100): Klassifizierung und Eigenschaften; 4. (iOrder_04_100): 14; 5. (order_05_100): ** Leere Zeile; 5. (iOrder_05_100): 1; 6. (order_06_100): ** Leere Zeile; 6. (iOrder_06_100): 1; 7. (order_07_100): ** Leere Zeile; 7. (iOrder_07_100): 1; 8. (order_08_100): ** Leere Zeile; 8. (iOrder_08_100): 1; 9. (order_09_100): ** Leere Zeile; 9. (iOrder_09_100): 1; 10. (order_10_100): ** Leere Zeile; 10. (iOrder_10_100): 1; 11. (order_11_100): Klassifizierung und Eigenschaften; 11. (iOrder_11_100): 14; 12. (order_12_100): ** Leere Zeile; 12. (iOrder_12_100): 1; Raumname zeigen (bShowZoneNameLine1_200): yes; Raumnummer zeigen (bShowZoneNum_200): no; Raumkategorie-Code zeigen (bShowZoneCatCode_200): no; 2. Raumnamen-Zeile zeigen (bShowZoneNameLine2_200): no; Einheitennummer zeigen (bShowApartmentID_200): yes; Einheitenname zeigen (bShowApartmentName_200): no; Zeige Apartment Identifikation (bShowApartmentCode_200): no; Zeige Treppenhaus Identifikatoren (bShowStaircaseCode_200): no; Position zeigen (bShowPosition_200): no; Hausnummer zeigen (bShowHouseNumber_200): no; Funktion zeigen (bShowFunctions_200): no; ID zeigen (bShowID_200): no; Bodenbelag zeigen (bShowFloor_200): no; Wandbelag zeigen (bShowWallFinish_200): no; Deckenbelag zeigen (bShowCeiling_200): no; Raumunterkante zeigen (bShowHeightZone_200): no; Fertigfußbodenhöhe zeigen (bShowHeightFloor_200): no; Abzugsflächen zeigen (bShowMeasuredArea_200): no; Gemessene Nettofläche zeigen (bShowMeasuredNetArea_200): no; DIN Abzugsflächen zeigen (bShowVentArea_200): no; Reduzierte Fläche zeigen (bShowReducedArea_200): no; Berechnete Fläche (NRF) zeigen (bShowCalculatedArea_200): yes; Fensterflächen zeigen (bShowWindowArea_200): no; Raumumfang zeigen (bShowPerimeter_200): no; Raumhöhe zeigen (bShowCeilingHeight_200): no; Raumvolumen zeigen (bShowVolume_200): no; Einordnung zeigen (bShowClassification_200): no; Eigenen Text zeigen 1 (bShowCustom1_200): no; Eigenen Text zeigen 2 (bShowCustom2_200): no; Eigenen Text zeigen 3 (bShowCustom3_200): no; Klassifizierung und Eigenschaften anzeigen (bShowAdditionalTags_200): no; Parameter auswählen (iTnCSelectParams_200): 1; Daten darstellen nach (iTncDisplayData_200): 1; 1. Zeile Parameternamen zeigen als (iRow1CustomName_200): 1; 2. Zeile Parameternamen zeigen als (iRow2CustomName_200): 1; 3. Zeile Parameternamen zeigen als (iRow3CustomName_200): 1; 4. Zeile Parameternamen zeigen als (iRow4CustomName_200): 1; 5. Zeile Parameternamen zeigen als (iRow5CustomName_200): 1; 6. Zeile Parameternamen zeigen als (iRow6CustomName_200): 1; 7. Zeile Parameternamen zeigen als (iRow7CustomName_200): 1; 8. Zeile Parameternamen zeigen als (iRow8CustomName_200): 1; 9. Zeile Parameternamen zeigen als (iRow9CustomName_200): 1; 10. Zeile Parameternamen zeigen als (iRow10CustomName_200): 1; 11. Zeile Parameternamen zeigen als (iRow11CustomName_200): 1; 12. Zeile Parameternamen zeigen als (iRow12CustomName_200): 1; 13. Zeile Parameternamen zeigen als (iRow13CustomName_200): 1; 14. Zeile Parameternamen zeigen als (iRow14CustomName_200): 1; 15. Zeile Parameternamen zeigen als (iRow15CustomName_200): 1; 16. Zeile Parameternamen zeigen als (iRow16CustomName_200): 1; 17. Zeile Parameternamen zeigen als (iRow17CustomName_200): 1; 18. Zeile Parameternamen zeigen als (iRow18CustomName_200): 1; 19. Zeile Parameternamen zeigen als (iRow19CustomName_200): 1; 20. Zeile Parameternamen zeigen als (iRow20CustomName_200): 1; Inhalt zum Überschreiben (iContentToOverride_200): 1; Überschreiben Titel-Textformat (bOverrideTitleTextFormat_200): yes; Raumname Schriftart (fontTitleType_200): Arial Westlich; Raumname Schriftgröße (mm) (fontTitleSizePaper_200): 2; Raumname Font-Stil (iTextStyleTitle_200): 1; Raumname Stift (penTitle_200): Elemente+Text; Raumname Stift (penTitle_200_int): 1; Überschreiben Titel 2 Textformat (bOverrideTitle2TextFormat_200): yes; Raumnummer Font Typ (fontTitle2Type_200): Arial; Raumnummer Font Größe (mm) (fontTitle2SizePaper_200): 1.5; Raumnummer Font-Stil (iTextStyleTitle2_200): 0; Raumnummer Stift (penTitle2_200): Schichttrennlinien/Kontur; Raumnummer Stift (penTitle2_200_int): 1; Überschreiben Daten-Textformat (bOverrideDataTextFormat_200): no; Daten Schriftart (fontDataType_200): Arial Westlich; Schriftgröße Daten (mm) (fontDataSizePaper_200): 1.5; Daten-Schrifttyp (iTextStyleData_200): 0; Daten-Stift (penData_200): Schichttrennlinien/Kontur; Daten-Stift (penData_200_int): 1; Schriftgröße (fontScaleType_200): Papiergröße; Schriftgröße (iFontScaleType_200): 2; Automat. Zeilenabstand (bAutomaticLineSpace_200): yes; Zeilenabstand in mm (lineSpacing_200): 4; Bemaßungseinheiten zeigen (bShowDimensionUnits_200): yes; Hochgestellt (bShowSuperScript_200): yes; Rahmen Stil (sFrameStyle_200): Keine; Rahmen Stil (iFrameStyle_200): 1; Feste Breite (bFixWidth_200): no; Breite in mm speichern (fixWidth_200): 30; Numerische Werte ausrichten (sAlignNumericalValues_200): Rechtsbündig; Numerische Werte ausrichten (iAlignNumericalValues_200): 4; Textwerte ausrichten (iAlignStringValues_200): 4; Höhenwert ausrichten (iAlignHeightValue_200): 1; Raumnummer ausrichten (iAlignZoneNr_200): 1; Fester Radius (bFixRadius_200): no; Kreisrahmen Radius in mm (frameRadius_200): 3; Rahmen-Stift (framePen_200): Elemente+Text; Linientyp Rahmen (frameLineType_200): 1; Einheitennummer Rahmen (apartmentIdFrame_200): Oval; Einheitennummer Rahmen (iApartmentIdFrame_200): 2; Hintergrundschraffur (bBackFill_200): yes; Schraffur (fillType_200): Nur Hintergrund-Stift; Schraffur-Vordergrundstift (fillPen_200): Elemente+Text; Schraffur-Hintergrundstift (fillBackPen_200): Transparent; Einheitennummer Winkel in 1:200: 0 deg; Anzahl der Reihen (nOrder_200): 2; Höhenwerte und Raumnummer Anzeigetyp (iDisplayType_200): 1; 1. (order_01_200): Raumname; 1. (iOrder_01_200): 2; 2. (order_02_200): Raumflächen; 2. (iOrder_02_200): 9; 3. (order_03_200): ** Leere Zeile; 3. (iOrder_03_200): 1; 4. (order_04_200): ** Leere Zeile; 4. (iOrder_04_200): 1; 5. (order_05_200): ** Leere Zeile; 5. (iOrder_05_200): 1; 6. (order_06_200): ** Leere Zeile; 6. (iOrder_06_200): 1; 7. (order_07_200): ** Leere Zeile; 7. (iOrder_07_200): 1; 8. (order_08_200): ** Leere Zeile; 8. (iOrder_08_200): 1; 9. (order_09_200): ** Leere Zeile; 9. (iOrder_09_200): 1; 10. (order_10_200): ** Leere Zeile; 10. (iOrder_10_200): 1; 11. (order_11_200): Klassifizierung und Eigenschaften; 11. (iOrder_11_200): 14; 12. (order_12_200): ** Leere Zeile; 12. (iOrder_12_200): 1; Raumname zeigen (bShowZoneNameLine1_0): yes; Raumnummer zeigen (bShowZoneNum_0): yes; Raumkategorie-Code zeigen (bShowZoneCatCode_0): no; 2. Raumnamen-Zeile zeigen (bShowZoneNameLine2_0): no; Einheitennummer zeigen (bShowApartmentID_0): no; Einheitenname zeigen (bShowApartmentName_0): no; Zeige Apartment Identifikation (bShowApartmentCode_0): no; Zeige Treppenhaus Identifikatoren (bShowStaircaseCode_0): no; Position zeigen (bShowPosition_0): no; Hausnummer zeigen (bShowHouseNumber_0): no; Funktion zeigen (bShowFunctions_0): no; ID zeigen (bShowID_0): no; Bodenbelag zeigen (bShowFloor_0): no; Wandbelag zeigen (bShowWallFinish_0): no; Deckenbelag zeigen (bShowCeiling_0): no; Raumunterkante zeigen (bShowHeightZone_0): no; Fertigfußbodenhöhe zeigen (bShowHeightFloor_0): no; Abzugsflächen zeigen (bShowMeasuredArea_0): no; Gemessene Nettofläche zeigen (bShowMeasuredNetArea_0): no; DIN Abzugsflächen zeigen (bShowVentArea_0): no; Reduzierte Fläche zeigen (bShowReducedArea_0): no; Berechnete Fläche (NRF) zeigen (bShowCalculatedArea_0): yes; Fensterflächen zeigen (bShowWindowArea_0): no; Raumumfang zeigen (bShowPerimeter_0): no; Raumvolumen zeigen (bShowVolume_0): no; Einordnung zeigen (bShowClassification_0): no; Eigenen Text zeigen 1 (bShowCustom1_0): no; Eigenen Text zeigen 2 (bShowCustom2_0): no; Eigenen Text zeigen 3 (bShowCustom3_0): no; Klassifizierung und Eigenschaften anzeigen (bShowAdditionalTags_0): no; Parameter auswählen (iTnCSelectParams_0): 1; Daten darstellen nach (iTncDisplayData_0): 1; 1. Zeile Parameternamen zeigen als (iRow1CustomName_0): 1; 2. Zeile Parameternamen zeigen als (iRow2CustomName_0): 1; 3. Zeile Parameternamen zeigen als (iRow3CustomName_0): 1; 4. Zeile Parameternamen zeigen als (iRow4CustomName_0): 1; 5. Zeile Parameternamen zeigen als (iRow5CustomName_0): 1; 6. Zeile Parameternamen zeigen als (iRow6CustomName_0): 1; 7. Zeile Parameternamen zeigen als (iRow7CustomName_0): 1; 8. Zeile Parameternamen zeigen als (iRow8CustomName_0): 1; 9. Zeile Parameternamen zeigen als (iRow9CustomName_0): 1; 10. Zeile Parameternamen zeigen als (iRow10CustomName_0): 1; 11. Zeile Parameternamen zeigen als (iRow11CustomName_0): 1; 12. Zeile Parameternamen zeigen als (iRow12CustomName_0): 1; 13. Zeile Parameternamen zeigen als (iRow13CustomName_0): 1; 14. Zeile Parameternamen zeigen als (iRow14CustomName_0): 1; 15. Zeile Parameternamen zeigen als (iRow15CustomName_0): 1; 16. Zeile Parameternamen zeigen als (iRow16CustomName_0): 1; 17. Zeile Parameternamen zeigen als (iRow17CustomName_0): 1; 18. Zeile Parameternamen zeigen als (iRow18CustomName_0): 1; 19. Zeile Parameternamen zeigen als (iRow19CustomName_0): 1; 20. Zeile Parameternamen zeigen als (iRow20CustomName_0): 1; Inhalt zum Überschreiben (iContentToOverride_0): 1; Überschreiben Titel-Textformat (bOverrideTitleTextFormat_0): yes; Raumname Schriftart (fontTitleType_0): Arial Westlich; Raumname Schriftgröße (mm) (fontTitleSizePaper_0): 2.5; Raumname Font-Stil (iTextStyleTitle_0): 1; Raumname Stift (penTitle_0): Schichttrennlinien/Kontur; Raumname Stift (penTitle_0_int): 2; Überschreiben Titel 2 Textformat (bOverrideTitle2TextFormat_0): yes; Raumnummer Font Typ (fontTitle2Type_0): Arial Westlich; Raumnummer Font Größe (mm) (fontTitle2SizePaper_0): 2.5; Raumnummer Font-Stil (iTextStyleTitle2_0): 0; Raumnummer Stift (penTitle2_0): Schichttrennlinien/Kontur; Raumnummer Stift (penTitle2_0_int): 1; Überschreiben Daten-Textformat (bOverrideDataTextFormat_0): yes; Daten Schriftart (fontDataType_0): Arial Westlich; Schriftgröße Daten (mm) (fontDataSizePaper_0): 2.5; Daten-Schrifttyp (iTextStyleData_0): 0; Daten-Stift (penData_0): Schichttrennlinien/Kontur; Daten-Stift (penData_0_int): 1; Schriftgröße (fontScaleType_0): Papiergröße; Schriftgröße (iFontScaleType_0): 2; Automat. Zeilenabstand (bAutomaticLineSpace_0): yes; Zeilenabstand in mm (lineSpacing_0): 4; Bemaßungseinheiten zeigen (bShowDimensionUnits_0): yes; Hochgestellt (bShowSuperScript_0): yes; Rahmen Stil (sFrameStyle_0): Stil 4; Rahmen Stil (iFrameStyle_0): 5; Feste Breite (bFixWidth_0): no; Breite in mm speichern (fixWidth_0): 30; Numerische Werte ausrichten (iAlignNumericalValues_0): 4; Textwerte ausrichten (iAlignStringValues_0): 4; Höhenwert ausrichten (iAlignHeightValue_0): 1; Raumnummer ausrichten (iAlignZoneNr_0): 1; Fester Radius (bFixRadius_0): no; Kreisrahmen Radius in mm (frameRadius_0): 3; Rahmen-Stift (framePen_0): Elemente+Text; Linientyp Rahmen (frameLineType_0): 1; Einheitennummer Rahmen (apartmentIdFrame_0): Oval; Einheitennummer Rahmen (iApartmentIdFrame_0): 2; Hintergrundschraffur (bBackFill_0): yes; Schraffur (fillType_0): Nur Hintergrund-Stift; Schraffur-Vordergrundstift (fillPen_0): Elemente+Text; Schraffur-Hintergrundstift (fillBackPen_0): Transparent; Einheitennummer Winkel: 0 deg; 1. (order_01_0): Raumname; 1. (iOrder_01_0): 2; 2. (order_02_0): Einheitennummer; 2. (iOrder_02_0): 4; 3. (order_03_0): Einheitenname; 3. (iOrder_03_0): 5; 4. (order_04_0): Beläge; 4. (iOrder_04_0): 6; 11. (order_11_0): Klassifizierung und Eigenschaften; 11. (iOrder_11_0): 14; 12. (order_12_0): ** Leere Zeile; 12. (iOrder_12_0): 1; Kategorie als Name verwenden: no; ID zeigen als...: 1; Position: <Position>; Hausnummer: <Hausnummer>; Bezeichnung Erschließung: <Treppenhaus>; Bodenbelag Titel: FB; Bodenbelag: <Fertigboden>; Bezeichnung Wandbelag: WB; Wandbelag Material: <Wandmaterial>; Deckenbelag Titel: DB; Deckenbelag: <Material Deckenbelag>; Berechnet OK Fertigfußboden: yes; Eigene OK Fertigfußboden: ±0.00; Präfix OK Fertigfussboden (sPrefixFloorLevel): Marker; Präfix OK Fertigfussboden (iPrefixFloorLevel): 1; Fertigfußbodenhöhe Titel: FFB; Marker für Fertigfußboden: 1; Berechnet OK Rohfußboden: yes; Eigene Rohfußboden OK: -0.10; Höhenlage Raum Präfix (sPrefixZoneLevel): Marker; Höhenlage Raum Präfix (iPrefixZoneLevel): 1; Raumunterkante Betzeichnung: RUK; Marker für Unterboden: 3; Zeichen Schraffur: Nur Hintergrund-Stift; Zeichen Schraffur-Vordergrundstift: Elemente+Text; Untergeordneter Schraffur: Nur Vordergrund-Stift; Untergeordneter Schraffur-Vordergrundstift: Schichttrennlinien/Kontur; Gemessene Fläche Kürzel: B; Gemessene Nettofläche Kürzel: BF; Abzugsflächen Kürzel: AF; Reduzierte Fläche Kürzel: RF; Fensterfläche Kürzel: FF; Raumumfang Kürzel: RU; Raumhöhe Kürzel: RH; Raumvolumen Kürzel: RV; Abzug gemäß WoFlV: no; Abzug in % (Balkone, Loggien): 0; Putzabzug: 0; Bereich: R; Flächencode Titel: Bereich; Einheiten Zuordnung: 1; Zeige Apartment Identifikation Präfix: no; Treppenhaus Zuordnung: 1; Eigene Treppenhaus Identifikation: <Treppenhaus>; Haus Zuordnung (iHouseCode): 1; Haus Zuordnung (asAddOn_stHouseCode): <Hausnummer>; Position Zuordnung (iPositionCode): 1; Position Zuordnung (asAddOn_stPositionCode): <Position>; Preis per m2: 0; Preis per m3: 0; Preis berechnet aus gemessener Fläche: 0; Preis berechnet aus gemessener Nettofläche: 0; Preis berechnet aus Reduzierte Fläche: 0; Preis berechnet aus berechneter Fläche (NRF): 0; Preis berechnet aus Nettovolumen: 0; Preis berechnet aus Bruttovolumen: 0; DWG-Export Typ: Standardraum; Drehwinkel: 0 deg
ArchiCADQuantities - Grundriss-Durchbruch Umfang: 0 m; Anzahl der Stützen: 0; Anzahl der Lichtquelle: 0; Raumflächen Reduzierung: 1 m2; Stützenabzugsfläche: 0 m2; Schraffurabzugsfläche: 0 m2; Wandabzugsfläche: 0 m2; Heizkörpernische Oberflächenbereich hinten: 0 m2; Heizkörpernische Oberflächenbereich seitlich: 0 m2; Heizkörpernische Oberflächenbereich oben: 0 m2
AC_Equantity_Raumstempel_DIN_22 - Gesamtlänge aller Bodenkanten: 0 m; Raumname Schriftgröße (modell) (fontTitleSizeModel_50): 0.25 m; Raumnummer Font Größe (Modell) (fontTitle2SizeModel_50): 0.25 m; Daten Schriftgröße (modell) (fontDataSizeModel_50): 0.25 m; X Distanz in 1:50: 0 m; Y Distanz in 1:50: 0 m; Einheitennummer Position (X) in 1:50: 0 m; Einheitennummer Position (Y) in 1:50: 0 m; Raumname Schriftgröße (modell) (fontTitleSizeModel_100): 0.25 m; Raumnummer Font Größe (Modell) (fontTitle2SizeModel_100): 0.25 m; Daten Schriftgröße (modell) (fontDataSizeModel_100): 0.25 m; X Distanz in 1:100: 0 m; Y Distanz in 1:100: 0 m; Einheitennummer Position (X) in 1:100: 0 m; Einheitennummer Position (Y) in 1:100: 0 m; Raumname Schriftgröße (modell) (fontTitleSizeModel_200): 0.25 m; Raumnummer Font Größe (Modell) (fontTitle2SizeModel_200): 0.25 m; Daten Schriftgröße (modell) (fontDataSizeModel_200): 0.25 m; X Distanz in 1:200: 0 m; Y Distanz in 1:200: 0 m; Einheitennummer Position (X) in 1:200: 0 m; Einheitennummer Position (Y) in 1:200: 0 m; Raumname Schriftgröße (modell) (fontTitleSizeModel_0): 0.25 m; Raumnummer Font Größe (Modell) (fontTitle2SizeModel_0): 0.25 m; Daten Schriftgröße (modell) (fontDataSizeModel_0): 0.25 m; X Abstand: 0 m; Y Abstand: 0 m; Einheitennummer Position (X): 0 m; Einheitennummer Position (Y): 0 m; Kreis Temp Radius: 0.3 m
Name | In | LongName = Zugehöriger Raumname = ArchiCADProperties, Raumname = AC_Pset_Raumstempel_DIN_22, Raumname | ConcealedCeiling | ConcealedFlooring | istNGF | Element ID = Hotlink und Element-ID = Überobjekt-ID | Ebene | Kollidierende Räume | Zugehörige Raumnummer = ArchiCADProperties, Raumnummer = AC_Pset_Raumstempel_DIN_22, Raumnummer | Ursprungsgeschoss Name | Ursprungsgeschoss Nummer | Reduzierte Fläche = Reduzierte Fläche (ROOM_REDUCED_AREA) = AC_Pset_Raumstempel_DIN_22, Berechnete Fläche (NRF) = DIN berechnete Fläche = Reduzierte Fläche (room_calc_area_reduced) = NetFloorArea (m2) = SpaceNetFloorAreaBOMA (m2) = SpaceUsableFloorAreaBOMA (m2) = NetCeilingArea (m2) = ArchiCADQuantities, Berechnete Fläche (NRF) (m2) | Verbundene 3D Element(e) | AC_Pset_Raumstempel_DIN_22, Gemessene Fläche = AC_Pset_Raumstempel_DIN_22, Gemessene Nettofläche = Unterer Oberflächenbereich = GrossFloorArea (m2) = GrossCeilingArea (m2) = Fläche (m2) = ArchiCADQuantities, Gemessene Fläche (m2) = ArchiCADQuantities, Gemessene Nettofläche (m2) | Anzahl aller Raumecken = Anzahl der Ecken | Anzahl hereinragender Raumecken = Anzahl der konkaven Ecken | Oberfläche Umfassungswände | Fläche der Türen | Fläche der Fenster | Abzugsfläche unter Dach = AC_Pset_Raumstempel_DIN_22, Gesamtabzugsfläche = Niedrige Abzugsfläche (m2) = ArchiCADQuantities, Gesamtabzugsfläche (m2) | Raumvolumen | Begrenzung Oberflächenbereich | Oberer Oberflächenbereich | Raumvolumen zeigen (bShowVolume_50) | Rahmen Stil (sFrameStyle_50) | Rahmen Stil (iFrameStyle_50) | Raumhöhe zeigen (bShowCeilingHeight_0) | Anzahl der Reihen (nOrder_0) | Höhenwerte und Raumnummer Anzeigetyp (iDisplayType_0) | 5. (order_05_0) | 5. (iOrder_05_0) | 6. (order_06_0) | 6. (iOrder_06_0) | 7. (order_07_0) | 7. (iOrder_07_0) | 8. (order_08_0) | 8. (iOrder_08_0) | 9. (order_09_0) | 9. (iOrder_09_0) | 10. (order_10_0) | 10. (iOrder_10_0) | Einheitennummer = Eigene Einheiten Zuordnung | Einheitenname | Berechnete Fläche (NRF) Kürzel | DIN abgezogene Fläche | Fenster/Raum (%) | Height (m) = FinishCeilingHeight (m) = ClearHeight (m) = Höhe (m) = Raumhöhe (m) | FinishFloorHeight (m) = Fußbodendicke (m) = Stärke Bodenaufbau (m) | GrossWallArea (m2) | NetWallArea (m2) = Wand-Oberflächenbereich (m2) | GrossPerimeter (m) = NetPerimeter (m) = Raumflächen Nettoumfang (m) = Raum Brutto-Umfang (m) = Raumumfang (m) = Nettoumfang (m) | GrossVolume (m3) | NetVolume (m3) = Netto-Volumen (m3) | Höhenangabe zum Projekt-Nullpunkt (m) = Höhe zu 1. Referenzhöhe (m) = Höhe zu 2. Referenzhöhe (m) = Raum zu 0,00 (m) | Höhe zu Meereshöhe (m) | Höhe zu verknüpftem/Ursprungsgeschoss (m) = Abstand zu Ursprungsgeschoss (m) = Basislevel (m) = Höhenkote OK Rohdecke (m) | Abstand Oberkante (m) | Anzahl der Unterzüge | Anzahl der Türen | Anzahl der Objekte | Anzahl der Fenster | Anzahl der Wandelemente | Fenster-Oberflächenbereich (m2) | Türen-Oberflächenbereich (m2) | Türen Breite (m) | Fenster Breite (m) | Wand Umfang (m) = Gesamtlänge Raumumfassung (m) | Summe Öffnungsbreite Türen (m) | Summe Öffnungsbreite Fenster (m) | Nutzung | Nutzungseinheit | 1. Zeile (sIDRow1_100) | Bodenbelag
R-013 | -1. Geschoss | Garage | no | no | yes | Raum-013 | Raum Ausbauraum | Stellplatz; Stellplatz; Tiefgaragenabfahrt; Untergeschoss UG | R-013 | -1. Geschoss | -1 | 75.0631 | Raum-016; Raum-018; Raum-018; Raum-024; Tür-003 | 75.0631 | 6 | 1 | 136.847 | 12.4113 | 0 | 0 | 190.16 | 89.2448 | 71.4891 | no | Stil 4 | 5 | no | 9 | 2 | Höhenwerte und Raumnummer | 8 | Raumflächen | 9 | Fensterfläche | 10 | Umfang, Höhe, Volumen | 11 | Flächencode | 12 | ** Leere Zeile | 1 | -1.01 | Haus | NGF | 0 | 0 | 2.55 | 0 | 89.687 | 77.2757 | 35.52 | 191.411 | 190.16 | -2.8 | 13.2 | 0 | -0.25 | 0 | 4 | 0 | 0 | 7 | 0 | 12.4113 | 6.04 | 0 | 61.905 | 6.04 | 0 | BauantragRäume - istNebenanlage: no; istGarage: yes; Pset_SpaceFireSafetyRequirements - FireExit: yes
R-014 | -1. Geschoss | Keller | no | no |  | Raum-014 | Raum Ausbauraum | Untergeschoss UG | R-014 | -1. Geschoss | -1 | 13.65 | Raum-024; Tür-001 | 13.65 | 4 | 0 | 69.1299 | 2.0301 | 0 | 0 | 34.8075 | 37.8038 | 13.65 | no | Stil 4 | 5 | no | 9 | 2 | Höhenwerte und Raumnummer | 8 | Raumflächen | 9 | Fensterfläche | 10 | Umfang, Höhe, Volumen | 11 | Flächencode | 12 | ** Leere Zeile | 1 | -1.03 | Wohnung 1 | NGF | -3.55271e-15 | 0 | 2.55 | 0 | 37.8038 | 35.7737 | 14.825 | 34.8075 | 34.8075 | -2.8 | 13.2 | 0 | -0.25 | 0 | 1 | 0 | 0 | 4 | 0 | 2.0301 | 1.01 | 0 | 29.65 | 1.01 | 0 | WOHNEINHEIT_MIETWOHNUNG | Wohnung 1
R-004 | EG | Wohnen | no | no | yes | Raum-004 | Raum Ausbauraum | Erdgeschoss; Grundfläche Gebäude Nachgezogen; Wohnung2 EG | R-004 | EG | 0 | 28.386 | Küche-004; Küche-005; Küche-005; Küche-005; Küche-006; Küche-007; Küche-008; Küche-009; Küche-010; Küche-011; Raum-002; Raum-019; Raum-020 | 28.386 | 5 | 0 | 52.7049 | 3.0351 | 7.272 | 0 | 83.7387 | 63.012 | 28.386 | yes | Stil 4 | 5 | no | 9 | 2 | Höhenwerte und Raumnummer | 8 | Raumflächen | 9 | Fensterfläche | 10 | Umfang, Höhe, Volumen | 11 | Flächencode | 12 | ** Leere Zeile | 1 | 0.06 | Wohnung 2 | NGF | 0 | 25.6183 | 2.95 | 0.2 | 63.012 | 52.7049 | 21.36 | 83.7387 | 83.7387 | -2.77556e-17 | 16 | -2.77556e-17 | -0.6 | 0 | 1 | 10 | 3 | 5 | 7.272 | 3.0351 | 1.51 | 3.03 | 21.36 | 1.51 | 3.03 | WOHNEINHEIT_EIGENTUMSWOHNUNG | Wohnung 2 | IFC.PSet.Pset_BauantragRäume.istNGF | Parkett | ElevationWithFlooring: 3 m; Allgemeine Werte - Barrierefrei: yes; Räume - Wandbelag: Rauhputz; Deckenbelag: Farbe; Abgehängte Decke: 0.35 m; UK Abgehängte Decke: 2.6 m
R-002 | EG | Terrasse | no | no |  | Raum-002 | Raum Ausbauraum | Grundfläche Gebäude Nachgezogen; Terrasse Wohnung1 EG | R-002 | EG | 0 | 29.6912 | Raum-002; Raum-021 | 29.6912 | 4 | 0 | 14.0925 | 0 | 12 | 0 | 105.404 | 80.8663 | 29.6912 | no | Stil 4 | 5 | no | 9 | 2 | Höhenwerte und Raumnummer | 8 | Raumflächen | 9 | Fensterfläche | 10 | Umfang, Höhe, Volumen | 11 | Flächencode | 12 | ** Leere Zeile | 1 | 0.04 | Wohnung 1 | NGF | 0 | 40.4161 | 3.55 | 0.2 | 26.0925 | 14.0925 | 22.7792 | 105.404 | 105.404 | -5.55112e-17 | 16 | -5.55112e-17 | -1.09992e-11 | 0 | 0 | 0 | 1 | 1 | 12 | 0 | 0 | 5 | 7.35 | 0 | 5 | WOHNEINHEIT_MIETWOHNUNG | Wohnung 1 | IFC.PSet.Pset_BauantragRäume.istNGF | Parkett
R-005 | EG | Wohnen | no | no | yes | Raum-005 | Raum Ausbauraum | Erdgeschoss; Grundfläche Gebäude Nachgezogen; Wohnung1 EG | R-005 | EG | 0 | 39.786 | Küche-004; Küche-005; Küche-005; Küche-005; Küche-006; Küche-007; Küche-008; Küche-009; Küche-010; Küche-011; Raum-002; Raum-019; Raum-021 | 39.786 | 5 | 0 | 52.5049 | 3.0351 | 19.272 | 0 | 117.369 | 74.812 | 39.786 | no | Stil 4 | 5 | no | 9 | 2 | Höhenwerte und Raumnummer | 8 | Raumflächen | 9 | Fensterfläche | 10 | Umfang, Höhe, Volumen | 11 | Flächencode | 12 | ** Leere Zeile | 1 | 0.02 | Wohnung 1 | NGF | 0 | 48.4391 | 2.95 | 0.2 | 74.812 | 52.5049 | 25.36 | 117.369 | 117.369 | -2.77556e-17 | 16 | -2.77556e-17 | -0.6 | 0 | 1 | 10 | 4 | 5 | 19.272 | 3.0351 | 1.51 | 8.03 | 25.36 | 1.51 | 8.03 | WOHNEINHEIT_MIETWOHNUNG | Wohnung 1 | IFC.PSet.Pset_BauantragRäume.istNGF | Linoleum | Räume - Wandbelag: Farbe; Deckenbelag: Farbe; Abgehängte Decke: 0.35 m; UK Abgehängte Decke: 2.6 m
R-006 | EG | Wohnen | no | no | yes | Raum-006 | Raum Ausbauraum | Erdgeschoss; Grundfläche Gebäude Nachgezogen; Wohnung1 EG | R-006 | EG | 0 | 31.3955 | Geländer-003; Raum-002; Raum-019; Raum-021; Treppe-001; Tür-005 | 31.3955 | 8 | 2 | 53.7531 | 9.0168 | 9.09 | 0 | 92.6168 | 70.387 | 31.3955 | no | Stil 4 | 5 | no | 9 | 2 | Höhenwerte und Raumnummer | 8 | Raumflächen | 9 | Fensterfläche | 10 | Umfang, Höhe, Volumen | 11 | Flächencode | 12 | ** Leere Zeile | 1 | 0.01 | Wohnung 1 | NGF | 0 | 28.9532 | 2.95 | 0.2 | 65.962 | 49.634 | 23.86 | 92.6168 | 92.6168 | 1.38778e-16 | 16 | 1.38778e-16 | -0.6 | 0 | 3 | 1 | 4 | 7 | 9.09 | 7.23795 | 3.405 | 4.04 | 24.2092 | 4.29 | 4.04 | WOHNEINHEIT_MIETWOHNUNG | Wohnung 1 | IFC.PSet.Pset_BauantragRäume.istNGF | Linoleum | Pset_SpaceFireSafetyRequirements - FireExit: yes; Räume - Wandbelag: Farbe; Deckenbelag: Farbe; Abgehängte Decke: 0.35 m; UK Abgehängte Decke: 2.6 m; Pset_SpaceCommon - FloorCovering: Linoleum
R-007 | EG | Bad | no | no | yes | Raum-007 | Raum Ausbauraum | Erdgeschoss; Grundfläche Gebäude Nachgezogen; Wohnung1 EG | R-007 | EG | 0 | 2.7 | Objekt-002; Objekt-004; Objekt-006; Raum-002; Raum-019; Raum-021; Tür-001 | 2.7 | 4 | 0 | 17.6912 | 1.77885 | 0 | 0 | 7.965 | 19.47 | 2.7 | no | Stil 4 | 5 | no | 9 | 2 | Höhenwerte und Raumnummer | 8 | Raumflächen | 9 | Fensterfläche | 10 | Umfang, Höhe, Volumen | 11 | Flächencode | 12 | ** Leere Zeile | 1 | 0.03 | Wohnung 1 | NGF | -7.37115e-08 | 0 | 2.95 | 0.1 | 19.47 | 17.6912 | 6.6 | 7.965 | 7.965 | 0.1 | 16.1 | 0.1 | -0.6 | 0 | 1 | 3 | 0 | 4 | 0 | 1.77885 | 0.885 | 0 | 6.6 | 0.885 | 0 | WOHNEINHEIT_MIETWOHNUNG | Wohnung 1 | IFC.PSet.Pset_BauantragRäume.istNGF | Fliesen | Räume - Wandbelag: Farbe; Deckenbelag: Farbe; Abgehängte Decke: 0.35 m; UK Abgehängte Decke: 2.6 m
R-008 | EG | Bad | no | no | yes | Raum-008 | Raum Ausbauraum | Erdgeschoss; Grundfläche Gebäude Nachgezogen; Wohnung2 EG | R-008 | EG | 0 | 2.7 | Objekt-001; Objekt-003; Objekt-005; Raum-002; Raum-019; Raum-020; Tür-001 | 2.7 | 4 | 0 | 17.6911 | 1.77885 | 0 | 0 | 7.965 | 19.47 | 2.7 | no | Keine | 1 | no | 9 | 2 | Höhenwerte und Raumnummer | 8 | Raumflächen | 9 | Fensterfläche | 10 | Umfang, Höhe, Volumen | 11 | Flächencode | 12 | ** Leere Zeile | 1 | 0.07 | Wohnung 2 | NGF | -6.48842e-08 | 0 | 2.95 | 0.1 | 19.47 | 17.6911 | 6.6 | 7.965 | 7.965 | 0.1 | 16.1 | 0.1 | -0.6 | 0 | 1 | 3 | 0 | 4 | 0 | 1.77885 | 0.885 | 0 | 6.6 | 0.885 | 0 | WOHNEINHEIT_EIGENTUMSWOHNUNG | Wohnung 2 | IFC.PSet.Pset_BauantragRäume.istNGF | Fliesen | Räume - Wandbelag: Farbe; Deckenbelag: Farbe; Abgehängte Decke: 0.35 m; UK Abgehängte Decke: 2.6 m
R-009 | EG | Wohnen | no | no | yes | Raum-009 | Raum Ausbauraum | Erdgeschoss; Grundfläche Gebäude Nachgezogen; Wohnung2 EG | R-009 | EG | 0 | 21.5345 | Geländer-003; Raum-002; Raum-019; Raum-020; Treppe-001; Tür-005 | 21.5345 | 8 | 2 | 43.3469 | 9.0168 | 6.666 | 0 | 63.5268 | 58.587 | 21.5345 | no | Stil 4 | 5 | no | 9 | 2 | Höhenwerte und Raumnummer | 8 | Raumflächen | 9 | Fensterfläche | 10 | Umfang, Höhe, Volumen | 11 | Flächencode | 12 | ** Leere Zeile | 1 | 0.05 | Wohnung 2 | NGF | 0 | 30.9549 | 2.95 | 0.2 | 59.0297 | 43.3469 | 19.86 | 63.5268 | 63.5268 | -5.55112e-17 | 16 | -5.55112e-17 | -0.6 | 0 | 4 | 1 | 3 | 8 | 6.666 | 9.0168 | 4.29 | 3.03 | 19.86 | 4.29 | 3.03 | WOHNEINHEIT_EIGENTUMSWOHNUNG | Wohnung 2 | IFC.PSet.Pset_BauantragRäume.istNGF | Pset_SpaceFireSafetyRequirements - FireExit: yes; ElevationWithFlooring: 0 m; Räume - Abgehängte Decke: 0.35 m; UK Abgehängte Decke: 2.6 m
R-011 | EG | Terrasse |  | no | yes | Raum-011 | Raum Ausbauraum | Grundfläche Gebäude Nachgezogen; Terrasse Wohnung2 EG | R-011 | EG | 0 | 11.7605 | Hecke; Raum-002; Raum-020 | 11.7605 | 4 | 0 | 12.1815 | 0 | 7.272 | 0 | 38.8097 | 52.074 | 11.7605 | no | Stil 4 | 5 | no | 9 | 2 | Höhenwerte und Raumnummer | 8 | Raumflächen | 9 | Fensterfläche | 10 | Umfang, Höhe, Volumen | 11 | Flächencode | 12 | ** Leere Zeile | 1 | 0.08 | Wohnung 2 | NGF | 0 | 61.834 | 3.3 | 0.1 | 19.4535 | 12.1815 | 15.78 | 38.8097 | 38.8097 | 0.1 | 16.1 | 0.1 | -0.25 | 0 | 0 | 1 | 3 | 1 | 7.272 | 0 | 0 | 3.03 | 5.895 | 0 | 3.03 | WOHNEINHEIT_EIGENTUMSWOHNUNG | Wohnung 2 | IFC.PSet.Pset_BauantragRäume.istNGF | Parkett
R-001 | 1. OG | Dachterrasse |  |  |  | Raum-001 | Raum Ausbauraum | Grundfläche Gebäude Nachgezogen; Obergeschoss; Wohnung2 OG | R-001 | 1. OG | 1 | 36.2933 | Dach-008; Geländer-001; Raum-002; Raum-019; Raum-020; Sparren; Sparren; Sparren; Sparren; Sparren; Sparren; Sparren; Sparren; Unterzug-007; Unterzug-007; Unterzug-007; Unterzug-010; Unterzug-010; Wand-004 | 36.2933 | 4 | 0 | 3.35506 | 0 | 4.68294 | 0 | 85.2892 | 57.038 | 36.2933 | no | Stil 4 | 5 | no | 9 | 2 | Höhenwerte und Raumnummer | 8 | Raumflächen | 9 | Fensterfläche | 10 | Umfang, Höhe, Volumen | 11 | Flächencode | 12 | ** Leere Zeile | 1 | 1.02 | Wohnung 1 | NGF | 0 | 0 | 2.35 | 0.1 | 0 | 0 | 24.2715 | 85.2892 | 85.2892 | 3.8001 | 19.8001 | 0.0500993 | -0.2 | 6 | 0 | 0 | 0 | 0 | 0 | 0 | 0 | 0 | 5.71962 | 0 | 2.483 | WOHNEINHEIT_MIETWOHNUNG | Wohnung 1 | IFC.PSet.Pset_BauantragRäume.istNGF | Parkett
R-003 | 1. OG | Loft | no | no | yes | Raum-003 | Raum Ausbauraum | Grundfläche Gebäude Nachgezogen; Obergeschoss; Wohnung2 OG | R-003 | 1. OG | 1 | 53.5928 | Geländer-003; Raum-002; Raum-019; Raum-020 | 53.5928 | 5 | 0 | 55.5045 | 0 | 21.744 | 0 | 131.302 | 77.2485 | 53.5928 | no | Stil 4 | 5 | no | 9 | 2 | Höhenwerte und Raumnummer | 8 | Raumflächen | 9 | Fensterfläche | 10 | Umfang, Höhe, Volumen | 11 | Flächencode | 12 | ** Leere Zeile | 1 | 1.03 | Wohnung 2 | NGF | 0 | 48.6334 | 2.45 | 0.15 | 77.2485 | 51.1845 | 31.53 | 131.302 | 131.302 | 3.75 | 19.75 | 0 | -0.2 | 0 | 0 | 0 | 7 | 5 | 26.064 | 0 | 0 | 10.86 | 31.53 | 0 | 9.06 | WOHNEINHEIT_EIGENTUMSWOHNUNG | Wohnung 2 | IFC.PSet.Pset_BauantragRäume.istNGF | Linoleum | ElevationWithFlooring: 2 m; Räume - Abgehängte Decke: 0.15 m; UK Abgehängte Decke: 2.3 m; Pset_SpaceCommon - HandicapAccessible: no; SkirtingBoard: NO; WallCovering: Zementputz; BauantragRäume - istGK: yes
R-012 | 1. OG | Luftraum Dach | no | no | yes | Raum-012 | Raum Ausbauraum | Grundfläche Gebäude Nachgezogen; Obergeschoss; Wohnung1 OG | R-012 | 1. OG | 1 | 25.5174 |  | 35.0372 | 9 | 1 | 31.1782 | 0 | 4.68294 | 9.51978 | 68.1748 | 34.4987 | 5.9803 | no | Stil 4 | 5 | no | 9 | 2 | Höhenwerte und Raumnummer | 8 | Raumflächen | 9 | Fensterfläche | 10 | Umfang, Höhe, Volumen | 11 | Flächencode | 12 | ** Leere Zeile | 1 | 1.01 | Wohnung 1 | NGF | 9.51978 | 13.3656 | 2.67314 | 0.1 | 37.1623 | 32.4793 | 24.0915 | 93.6593 | 66.3643 | 3.8 | 19.8 | 0.05 | -0.2 | 5 | 0 | 21 | 1 | 8 | 4.68294 | 0 | 0 | 2.483 | 22.5757 | 0 | 2.483 | WOHNEINHEIT_MIETWOHNUNG | Wohnung 1 | IFC.PSet.Pset_BauantragRäume.istNGF | Parkett | Räume - Wandbelag: Farbe; Deckenbelag: Farbe; BauantragRäume - istGK: yes
R-023 | 1. OG | Balkon Wohnung2 |  |  |  | Raum-020 | Bauantrag |  | R-023 | 1. OG | 1 | 3.852 | Decke-017; Geländer-001 | 3.852 | 4 | 0 | 5.82061 | 0 | 0 | 0 | 11.2475 | 23.0089 | 3.852 | no | Stil 4 | 5 | yes | 10 | 1 | Raumnummer | 3 | Höhenwerte | 7 | Raumflächen | 9 | Fensterfläche | 10 | Umfang, Höhe, Volumen | 11 | Flächencode | 12 | 1,04 | Wohnung 2 | BGF | 0 | 112.15 | 2.75 | 0.1 | 5.564 | 1.244 | 7.88 | 10.593 | 10.593 | 3.5 | 19.5 | -0.25 | 0.16991 | 0 | 0 | 0 | 1 | 1 | 4.32 | 0 | 0 | 1.8 | 2.14 | 0 | 0 | WOHNEINHEIT_EIGENTUMSWOHNUNG | Wohnung 2 | IFC.PSet.Pset_BauantragRäume.istBGF | BauantragRäume - istGebäudeHülle: yes; istBbalkon: yes; BauantragGrundstücksflächen - IstNebenanlage: yes; BauantragBruttoflächen - IstBGF: yes; Raumumschließung: REGELFALL

# IfcBeam: Bauteil - Attika Mauerwerk 574 x 270 (9)
Classification: Balken / Unterzug (ARCHICAD Klassifizierung)
ArchiCADProperties - Ebene: Attika; Baustoff / Mehrschichtiger Aufbau / Profil / Schraffur: Bauteil - Attika Mauerwerk; Profil: Bauteil - Attika Mauerwerk; Geschützt: no; Typ: Wand; Absolutes Geschoss für Oberkantenverknüpfung: Nicht verknüpft; Relatives Geschoss für Oberkantenverknüpfung: Nicht verknüpft; Geschoss für Oberkantenverknüpfung: Nicht verknüpft; Struktur-Typ: Profil; Baustoffe (Alle): Holz, Brettschichtholz; MW Kalksandstein; Holz, Bauholz; Holz, Bauholz; Holz, Spanplatte; Metall, Stahl verzinkt; Dämmung, hart XPS; Dämmung, hart XPS; Verputz, Kalkzement; Neigungswinkel: 90 deg; Lage: Außen; Tragende Funktion: Tragende Elemente; Anzeigen auf Umbau-Filter: Alle relevanten Filter; Umbau-Status: Bestand; Wandkomplexität: gerade; Geometriemethode: Uni; Wand Innerer Neigungswinkel: 90 deg; Wand Äußerer Neigungswinkel: 90 deg; ARCHICAD Klassifizierung - 22: Balken / Unterzug
Brandschutz 4102-2 - Kennbuchstabe: F
Pset_BeamCommon - LoadBearing: yes; IsExternal: yes
Component Properties - Component 8, Komponenten-Typ: Andere; Component 4, Komponenten-Typ: Andere; Component 2, Komponenten-Typ: Andere; Component 1, Komponenten-Typ: Bekleidung; Component 3, Komponenten-Typ: Andere; Component 7, Komponenten-Typ: Andere; Component 9, Komponenten-Typ: Bekleidung
BaseQuantities - CrossSectionArea: 0.154806 m2
ArchiCADQuantities - Höhe: 0.269908 m; Breite: 0.573552 m; Abstand Oberkante: 0 m; Dicke: 0.573552 m; Dämmungsschichtdicke: 0 m; Anzahl der Türen: 0; Anzahl der Durchbrüche (Anzahl der leeren Öffnungen): 0; Anzahl der Fenster: 0; Anzahl der Stützen: 0; Volumen der Stützen: 0 m3; Maximale Höhe der Wandschicht an der Innenseite: 0 m; Minimale Höhe der Wandschicht an der Innenseite: 0 m; Maximale Höhe der Wand: 0.269908 m; Maximale Höhe der Wandschicht an der Außenseite: 0 m; Minimale Höhe der Wandschicht an der Außenseite: 0 m; Luftschichtdicke: 0 m; Fläche der Türen: 0 m2; Kombinierte Breite der Türen: 0 m; Wand-Schichtdicke an der Innenseite: 0 m; Wand-Schichtdicke an der Außenseite: 0 m; Fläche der Fenster: 0 m2; Kombinierte Breite der Fenster: 0 m; Analytische Oberfläche der Öffnungen an der Innenseite: 0 m2; Analytische Oberfläche der Öffnungen an der Außenseite: 0 m2; Analytisches Volumen der Öffnungen: 0 m3; Wandstärke am Ende: 0.573552 m; Oberflächenbereich der leeren Öffnungen in der Wand: 0 m2; Dämmung innen: 0.110283 m; Dämmung innen Höhe: 0.16 m; Dämmungsbreite: 0.16 m; Dämmungshöhe: 0.16 m; Höhe Außenbekleidung: 0.16 m; Höhe Wandaufbau: 0.16 m
Name | In | Material | Element ID = Hotlink und Element-ID = Überobjekt-ID | Kollidierende Räume | Zugehöriger Raumname | Zugehörige Raumnummer | Ursprungsgeschoss Name | Ursprungsgeschoss Nummer | Oberfläche (Alle) | Component 5, Enthaltenes CO2 | Component 5, Enthaltene Energie (MJ) | Component 5, Komponenten-Typ | Component 6, Enthaltenes CO2 | Component 6, Enthaltene Energie (MJ) | Component 6, Komponenten-Typ | Component 8, Enthaltenes CO2 | Component 8, Enthaltene Energie (MJ) | Component 4, Enthaltenes CO2 | Component 4, Enthaltene Energie (MJ) | Component 2, Enthaltenes CO2 | Component 2, Enthaltene Energie (MJ) | Component 1, Enthaltenes CO2 | Component 1, Enthaltene Energie (MJ) | Component 3, Enthaltenes CO2 | Component 3, Enthaltene Energie (MJ) | Component 7, Enthaltenes CO2 | Component 7, Enthaltene Energie (MJ) | Component 9, Enthaltenes CO2 | Component 9, Enthaltene Energie (MJ) | NetSurfaceAreaExtrudedSides (m2) = OuterSurfaceArea (m2) | Length (m) = Durchschnittliche Länge der Wand (m) = Länge der Wand in der Achse (m) | TotalSurfaceArea (m2) = GrossSurfaceArea (m2) | GrossVolume (m3) = NetVolume (m3) = Netto-Volumen (m3) = Konditionales Volumen (m3) | Fläche (m2) = Fläche der Wand (m2) | Höhenangabe zum Projekt-Nullpunkt (m) = Höhe zu 1. Referenzhöhe (m) = Höhe zu 2. Referenzhöhe (m) | Höhe zu Meereshöhe (m) | Höhe zu verknüpftem/Ursprungsgeschoss (m) = Abstand zu Ursprungsgeschoss (m) | Oberflächenbereich (m2) = Netto-Oberflächenbereich an der Außenseite (m2) = Konditionaler Oberflächenbereich an der Außenseite (m2) | 3D-Länge (m) | Brutto-Volumen (m3) | Grundriss-Umfang (m) | Minimale Höhe der Wand (m) | Netto-Oberflächenbereich an den Kanten (m2) | Netto-Oberflächenbereich an der Innenseite (m2) = Konditionaler Oberflächenbereich an der Innenseite (m2) | Länge der Referenzlinie (m) | Konditionale Länge an der Innenseite (m) = Wandlänge an der Innenseite (m) | Konditionale Länge an der Außenseite (m) = Wandlänge an der Außenseite (m) | Brutto-Wandoberflächenbereich an der Innenseite (m2) | Brutto-Wandoberflächenbereich an der Außenseite (m2) | Component 5, Masse (kg) | Component 5, Schicht/Komponente Oberflächenbereich (m2) | Component 5, Schicht/Komponente Querschnittsbereich (m2) | Component 5, Schicht/Komponente Volumen (m3) | Component 6, Masse (kg) | Component 6, Schicht/Komponente Oberflächenbereich (m2) | Component 6, Schicht/Komponente Querschnittsbereich (m2) | Component 6, Schicht/Komponente Volumen (m3) | Component 8, Masse (kg) | Component 8, Schicht/Komponente Querschnittsbereich (m2) | Component 8, Schicht/Komponente Volumen (m3) | Component 4, Masse (kg) | Component 4, Schicht/Komponente Querschnittsbereich (m2) | Component 4, Schicht/Komponente Volumen (m3) | Component 2, Masse (kg) | Component 2, Schicht/Komponente Querschnittsbereich (m2) | Component 2, Schicht/Komponente Volumen (m3) | Component 1, Masse (kg) | Component 1, Schicht/Komponente Querschnittsbereich (m2) | Component 1, Schicht/Komponente Volumen (m3) | Component 3, Masse (kg) | Component 3, Schicht/Komponente Höhe (rechteckig) (m) | Component 3, Schicht/Komponente Breite (rechteckig) (m) | Component 3, Schicht/Komponente Querschnittsbereich (m2) | Component 3, Schicht/Komponente Volumen (m3) | Component 7, Masse (kg) | Component 7, Schicht/Komponente Höhe (rechteckig) (m) | Component 7, Schicht/Komponente Breite (rechteckig) (m) | Component 7, Schicht/Komponente Querschnittsbereich (m2) | Component 7, Schicht/Komponente Volumen (m3) | Component 9, Masse (kg) | Component 9, Schicht/Komponente Querschnittsbereich (m2) | Component 9, Schicht/Komponente Volumen (m3) | Component 5, Schicht/Komponente Höhe (rechteckig) (m) | Component 5, Schicht/Komponente Breite (rechteckig) (m) | Component 4, Schicht/Komponente Oberflächenbereich (m2) | Component 8, Schicht/Komponente Oberflächenbereich (m2) | Component 9, Schicht/Komponente Oberflächenbereich (m2) | Component 7, Schicht/Komponente Oberflächenbereich (m2)
Attika-Wand-002 | EG | Metall, Stahl verzinkt, Holz, Spanplatte, Dämmung, hart XPS (2), Holz, Bauholz (2), Holz, Brettschichtholz, MW Kalksandstein, Verputz, Kalkzement | Attika-Wand-002 | Erdgeschoss; Grundfläche Gebäude Nachgezogen | Erdgeschoss | EG | EG | 0 | Holz Kiefer; Verputz, glatt, weiß; Metall Stahl, verzinkt; Farbe, weiß; Holzwerkstoff Spanplatte; Farbe, hellblau; Holz Brettschichtholz | 12.6384 (kgCO₂) | 289.225 | Andere | 14.4749 (kgCO₂) | 248.141 | Kern | 0.789596 (kgCO₂) | 18.9231 | 0.453947 (kgCO₂) | 10.8791 | 20.1268 (kgCO₂) | 308.271 | 44.7938 (kgCO₂) | 616.682 | 7.61994 (kgCO₂) | 194.732 | 9.68325 (kgCO₂) | 247.461 | 6.39112 (kgCO₂) | 42.1233 | 10.8801 | 3.65217 | 15.0695 | 0.449717 | 2.09471 | 3.52 | 19.52 | 3.52 | 4.06891 | 4.22572 | 0.51277 | 8.92659 | 0 | 3.13858 | 3.67262 | 3.79 | 4.22572 | 3.07862 | 4.27749 | 4.77452 | 24.3046 | 1.35051 | 0.0216038 | 0.0810154 | 206.784 | 0.5744 | 0.032 | 0.11488 | 2.72275 | 0.00137822 | 0.00544549 | 1.56533 | 0.000896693 | 0.00313067 | 25.477 | 0.0116182 | 0.0424616 | 30.6807 | 0.00107492 | 0.00393343 | 2.22805 | 0.22 | 0.110283 | 0.0242622 | 0.0795733 | 2.83136 | 0.16 | 0.16 | 0.0256 | 0.10112 | 29.0506 | 0.00439625 | 0.0181566 | Component Quantities - Component 6, Schicht/Komponente Höhe (rechteckig): 0.16 m; Component 6, Schicht/Komponente Breite (rechteckig): 0.2 m; Component 2, Schicht/Komponente Oberflächenbereich: 2.24546 m2; Component 1, Schicht/Komponente Oberflächenbereich: 2.12804 m2; Component 3, Schicht/Komponente Oberflächenbereich: 0.721538 m2
Attika-Wand-001 | EG | Metall, Stahl verzinkt, Holz, Spanplatte, Dämmung, hart XPS (2), Holz, Bauholz (2), MW Kalksandstein, Holz, Brettschichtholz, Verputz, Kalkzement | Attika-Wand-001 | Erdgeschoss; Grundfläche Gebäude Nachgezogen; Wohnung2 EG | Wohnung2 EG | R-020 | EG | 0 | Holz Kiefer; Verputz, glatt, weiß; Metall Stahl, verzinkt; Farbe, weiß; Holzwerkstoff Spanplatte; Farbe, hellblau; Holz Brettschichtholz | 11.3667 (kgCO₂) | 194.859 | Kern | 9.97725 (kgCO₂) | 228.326 | Andere | 8.09875 (kgCO₂) | 206.968 | 0.348505 (kgCO₂) | 8.3521 | 16.0981 (kgCO₂) | 246.566 | 33.6735 (kgCO₂) | 463.588 | 6.07329 (kgCO₂) | 155.206 | 0.581631 (kgCO₂) | 13.9391 | 5.00809 (kgCO₂) | 33.0079 | 8.48912 | 2.73147 | 11.6224 | 0.359726 | 1.56664 | 3.52 | 19.52 | 3.52 | 3.09189 | 3.39324 | 0.395173 | 6.84761 | 0 | 2.50932 | 2.88791 | 2.80038 | 3.01824 | 2.44469 | 3.11548 | 3.47041 | 162.382 | 0.451062 | 0.032 | 0.0902123 | 19.187 | 1.06615 | 0.0216038 | 0.0639568 | 2.36806 | 0.0256 | 0.0845735 | 1.20174 | 0.000896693 | 0.00240348 | 20.3774 | 0.0116182 | 0.0339623 | 23.0641 | 0.00107492 | 0.00295693 | 1.77582 | 0.22 | 0.110283 | 0.0242622 | 0.063422 | 2.00562 |  |  | 0.00137822 | 0.00401125 | 22.764 | 0.00439625 | 0.0142275 | 0.16 | 0.2 | Component Quantities - Component 2, Schicht/Komponente Oberflächenbereich: 1.72059 m2; Component 1, Schicht/Komponente Oberflächenbereich: 1.59817 m2; Component 3, Schicht/Komponente Oberflächenbereich: 0.575085 m2; Component 8, Schicht/Komponente Höhe (rechteckig): 0.16 m; Component 8, Schicht/Komponente Breite (rechteckig): 0.16 m
Attika-Wand-001 | EG | Verputz, Kalkzement, Holz, Bauholz (2), Dämmung, hart XPS (2), Holz, Brettschichtholz, MW Kalksandstein, Holz, Spanplatte, Metall, Stahl verzinkt | Attika-Wand-001 | Erdgeschoss; Grundfläche Gebäude Nachgezogen; Obergeschoss | Erdgeschoss | EG | EG | 0 | Holz Kiefer; Verputz, glatt, weiß; Metall Stahl, verzinkt; Farbe, weiß; Holzwerkstoff Spanplatte; Farbe, hellblau; Holz Brettschichtholz | 0.340879 (kgCO₂) | 8.16935 | Andere | 10.4847 (kgCO₂) | 179.739 | Kern | 13.9989 (kgCO₂) | 214.413 | 8.76378 (kgCO₂) | 200.556 | 0.569834 (kgCO₂) | 13.6564 | 4.58116 (kgCO₂) | 30.194 | 6.86502 (kgCO₂) | 175.439 | 5.78538 (kgCO₂) | 147.849 | 33.3363 (kgCO₂) | 458.946 | 8.097 | 2.73147 | 11.2303 | 0.323252 | 1.56664 | 3.52 | 19.52 | 3.52 | 3.03314 | 3.01824 | 0.367594 | 6.84761 | 2.50022e-13 | 2.38267 | 2.68119 | 2.80038 | 3.01824 | 2.44469 | 3.05849 | 3.41348 | 1.17545 |  | 0.000896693 | 0.00235089 | 149.782 | 0.416062 | 0.032 | 0.0832123 | 17.7201 | 0.0116182 | 0.0295335 | 16.8534 | 0.0216038 | 0.0561781 | 1.96494 | 0.00137822 | 0.00392989 | 20.8235 | 0.00439625 | 0.0130147 | 2.00732 | 0.16 | 0.16 | 0.0256 | 0.0716899 | 1.69163 | 0.22 | 0.110283 | 0.0242622 | 0.0604155 | 22.8331 | 0.00107492 | 0.00292732 |  |  | 0.936463 | 1.55764 | 1.57654 | 0.547822 | Component Quantities - Component 6, Schicht/Komponente Höhe (rechteckig): 0.16 m; Component 6, Schicht/Komponente Breite (rechteckig): 0.2 m
Attika-Wand-005 | R-024 | Verputz, Kalkzement, Holz, Bauholz (2), Dämmung, hart XPS (2), Holz, Brettschichtholz, MW Kalksandstein, Holz, Spanplatte, Metall, Stahl verzinkt | Attika-Wand-005 | Grundfläche Gebäude Nachgezogen; Terrasse Wohnung1 EG | Terrasse | R-002 | EG | 0 | Holz Kiefer; Verputz, glatt, weiß; Metall Stahl, verzinkt; Farbe, weiß; Holzwerkstoff Spanplatte; Farbe, hellblau; Holz Brettschichtholz | 29.111 (kgCO₂) | 499.046 | Kern | 0.923145 (kgCO₂) | 22.1237 | Andere | 40.4327 (kgCO₂) | 619.286 | 24.8722 (kgCO₂) | 569.19 | 1.46486 (kgCO₂) | 35.1061 | 11.4514 (kgCO₂) | 75.4749 | 18.0917 (kgCO₂) | 462.345 | 16.3099 (kgCO₂) | 416.81 | 87.8696 (kgCO₂) | 1209.71 | 21.7816 | 7.15108 | 29.9846 | 0.891744 | 4.10152 | 3.67 | 19.67 | 3.67 | 8.09772 | 7.43786 | 0.910456 | 15.6868 | 0 | 6.36323 | 7.32062 | 7.22 | 7.43786 | 6.86431 | 7.5482 | 8.42298 | 415.872 | 1.1552 | 0.032 | 0.23104 | 3.18326 |  | 0.000896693 | 0.00636652 | 51.1806 | 0.0116182 | 0.0853011 | 47.8311 | 0.0216038 | 0.159437 | 5.05123 | 0.00137822 | 0.0101025 | 52.0516 | 0.00439625 | 0.0325323 | 5.28998 | 0.16 | 0.16 | 0.0256 | 0.188928 | 4.76899 | 0.22 | 0.110283 | 0.0242622 | 0.170321 | 60.1847 | 0.00107492 | 0.00771599 | 0.16 | 0.2 | 2.65777 | 4.24131 | 4.14974 | 1.5444
Attika-Wand-005 | 000 | Verputz, Kalkzement, Holz, Bauholz (2), Dämmung, hart XPS (2), Holz, Brettschichtholz, MW Kalksandstein, Holz, Spanplatte, Metall, Stahl verzinkt | Attika-Wand-005 | Grundfläche Gebäude Nachgezogen | Wohnung1 EG | R-021 | EG | 0 | Holz Kiefer; Verputz, glatt, weiß; Metall Stahl, verzinkt; Farbe, weiß; Holzwerkstoff Spanplatte; Farbe, hellblau; Holz Brettschichtholz | 22.2349 (kgCO₂) | 381.17 | Kern | 0.719789 (kgCO₂) | 17.2501 | Andere | 30.0447 (kgCO₂) | 460.179 | 18.5853 (kgCO₂) | 425.317 | 1.15222 (kgCO₂) | 27.6136 | 9.09088 (kgCO₂) | 59.9172 | 14.0091 (kgCO₂) | 358.011 | 12.5562 (kgCO₂) | 320.88 | 69.0778 (kgCO₂) | 951.002 | 16.8685 | 5.6457 | 23.3447 | 0.681208 | 3.2381 | 3.67 | 19.67 | 3.67 | 6.33633 | 5.93248 | 0.72555 | 12.6761 | 1.09992e-11 | 4.89055 | 5.64164 | 5.71462 | 5.93248 | 5.35892 | 6.01894 | 6.71668 | 317.642 | 0.882338 | 0.032 | 0.176468 | 2.48203 |  | 0.000896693 | 0.00496406 | 38.0313 | 0.0116182 | 0.0633855 | 35.7409 | 0.0216038 | 0.119136 | 3.97318 | 0.00137822 | 0.00794635 | 41.3222 | 0.00439625 | 0.0258264 | 4.09624 | 0.16 | 0.16 | 0.0256 | 0.146294 | 3.6714 | 0.22 | 0.110283 | 0.0242622 | 0.131121 | 47.3135 | 0.00107492 | 0.00606584 | 0.16 | 0.2 | 1.98595 | 3.21976 | 3.2596 | 1.18895
Attika-Wand-009 | OG | Metall, Stahl verzinkt, Holz, Spanplatte, Dämmung, hart XPS (2), Holz, Bauholz (2), Holz, Brettschichtholz, MW Kalksandstein, Verputz, Kalkzement | Attika-Wand-009 | Grundfläche Gebäude Nachgezogen; Obergeschoss; Wohnung2 OG | Wohnung2 OG | R-020 | 1. OG | 1 | Holz Kiefer; Verputz, glatt, weiß; Metall Stahl, verzinkt; Farbe, weiß; Holzwerkstoff Spanplatte; Farbe, hellblau; Holz Brettschichtholz | 37.5946 (kgCO₂) | 860.339 | Andere | 44.3318 (kgCO₂) | 759.974 | Kern | 2.26943 (kgCO₂) | 54.3881 | 1.41675 (kgCO₂) | 33.9531 | 60.8991 (kgCO₂) | 932.758 | 135.612 (kgCO₂) | 1866.99 | 24.8244 (kgCO₂) | 634.401 | 27.8363 (kgCO₂) | 711.372 | 17.8502 (kgCO₂) | 117.649 | 33.1684 | 11.0572 | 45.8521 | 1.35927 | 6.34186 | 6.57 | 22.57 | 2.82 | 12.4622 | 11.6307 | 1.42233 | 23.7366 | 0 | 9.51107 | 11.1951 | 11.195 | 11.6307 | 10.4836 | 11.7999 | 13.1679 | 72.2974 | 4.01724 | 0.0216038 | 0.240991 | 633.312 | 1.7592 | 0.032 | 0.35184 | 7.82562 | 0.00137822 | 0.0156512 | 4.88534 | 0.000896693 | 0.00977068 | 77.0874 | 0.0116182 | 0.128479 | 92.885 | 0.00107492 | 0.0119083 | 7.25859 | 0.22 | 0.110283 | 0.0242622 | 0.259235 | 8.13926 | 0.16 | 0.16 | 0.0256 | 0.290688 | 81.1373 | 0.00439625 | 0.0507108 | Component Quantities - Component 6, Schicht/Komponente Höhe (rechteckig): 0.16 m; Component 6, Schicht/Komponente Breite (rechteckig): 0.2 m; Component 2, Schicht/Komponente Oberflächenbereich: 6.46888 m2; Component 1, Schicht/Komponente Oberflächenbereich: 6.40466 m2; Component 3, Schicht/Komponente Oberflächenbereich: 2.35064 m2
Attika-Wand-008 | OG | Metall, Stahl verzinkt, Holz, Spanplatte, Dämmung, hart XPS (2), Holz, Bauholz (2), Holz, Brettschichtholz, MW Kalksandstein, Verputz, Kalkzement | Attika-Wand-008 | Grundfläche Gebäude Nachgezogen; Obergeschoss; Wohnung1 OG; Wohnung2 OG | Wohnung2 OG | R-020 | 1. OG | 1 | Holz Kiefer; Verputz, glatt, weiß; Metall Stahl, verzinkt; Farbe, weiß; Holzwerkstoff Spanplatte; Metall, Fassade Edelstahl; Farbe, hellblau; Holz Brettschichtholz | 17.5252 (kgCO₂) | 401.057 | Andere | 20.7648 (kgCO₂) | 355.968 | Kern | 1.09393 (kgCO₂) | 26.2166 | 0.656779 (kgCO₂) | 15.74 | 28.7162 (kgCO₂) | 439.831 | 63.9264 (kgCO₂) | 880.082 | 11.2444 (kgCO₂) | 287.356 | 13.2379 (kgCO₂) | 338.301 | 8.63497 (kgCO₂) | 56.9123 | 15.5013 | 5.21217 | 21.4802 | 0.635605 | 2.98945 | 6.57 | 22.57 | 2.82 | 5.83624 | 5.78572 | 0.695269 | 12.0466 | 0 | 4.43266 | 5.2324 | 5.35 | 5.78572 | 4.63862 | 5.84007 | 6.52065 | 33.7023 | 1.87269 | 0.0216038 | 0.112341 | 296.64 | 0.824 | 0.032 | 0.1648 | 3.77217 | 0.00137822 | 0.00754434 | 2.26475 | 0.000896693 | 0.00452951 | 36.3497 | 0.0116182 | 0.0605828 | 43.7852 | 0.00107492 | 0.00561349 | 3.28783 | 0.22 | 0.110283 | 0.0242622 | 0.117422 | 3.87072 | 0.16 | 0.16 | 0.0256 | 0.13824 | 39.2499 | 0.00439625 | 0.0245312 | Component Quantities - Component 6, Schicht/Komponente Höhe (rechteckig): 0.16 m; Component 6, Schicht/Komponente Breite (rechteckig): 0.2 m; Component 2, Schicht/Komponente Oberflächenbereich: 3.1352 m2; Component 1, Schicht/Komponente Oberflächenbereich: 3.02899 m2; Component 3, Schicht/Komponente Oberflächenbereich: 1.06474 m2
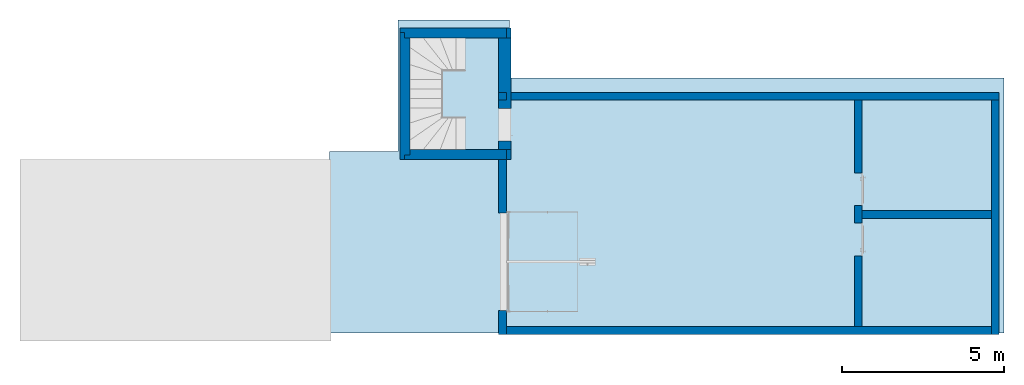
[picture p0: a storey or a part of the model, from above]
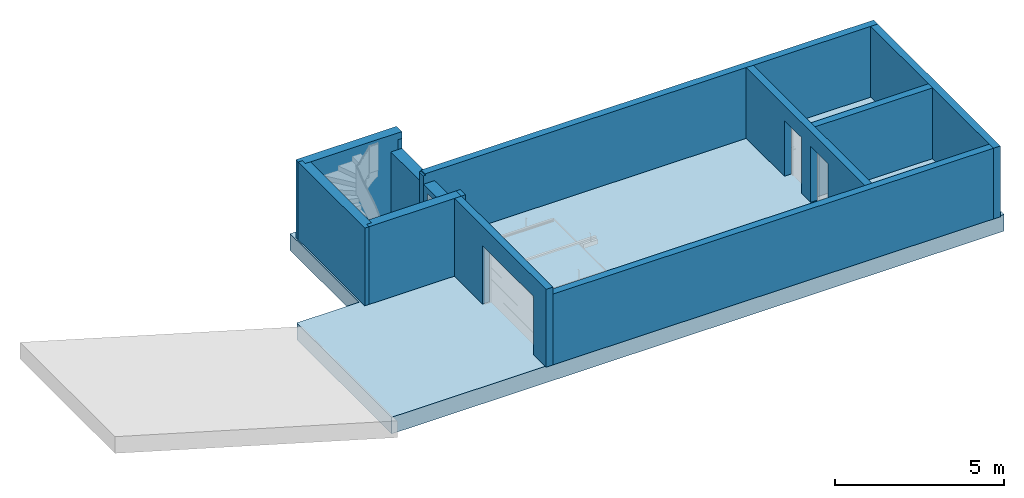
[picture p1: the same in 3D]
Properties of the parts of a building model (IFC4), part 4 of 13

# IfcBeam: Bauteil - Attika Mauerwerk 574 x 270 (9)
Name | In | Material | Element ID = Hotlink und Element-ID = Überobjekt-ID | Kollidierende Räume | Zugehöriger Raumname | Zugehörige Raumnummer | Ursprungsgeschoss Name | Ursprungsgeschoss Nummer | Oberfläche (Alle) | Component 5, Enthaltenes CO2 | Component 5, Enthaltene Energie (MJ) | Component 5, Komponenten-Typ | Component 6, Enthaltenes CO2 | Component 6, Enthaltene Energie (MJ) | Component 6, Komponenten-Typ | Component 8, Enthaltenes CO2 | Component 8, Enthaltene Energie (MJ) | Component 4, Enthaltenes CO2 | Component 4, Enthaltene Energie (MJ) | Component 2, Enthaltenes CO2 | Component 2, Enthaltene Energie (MJ) | Component 1, Enthaltenes CO2 | Component 1, Enthaltene Energie (MJ) | Component 3, Enthaltenes CO2 | Component 3, Enthaltene Energie (MJ) | Component 7, Enthaltenes CO2 | Component 7, Enthaltene Energie (MJ) | Component 9, Enthaltenes CO2 | Component 9, Enthaltene Energie (MJ) | NetSurfaceAreaExtrudedSides (m2) = OuterSurfaceArea (m2) | Length (m) = Durchschnittliche Länge der Wand (m) = Länge der Wand in der Achse (m) | TotalSurfaceArea (m2) = GrossSurfaceArea (m2) | GrossVolume (m3) = NetVolume (m3) = Netto-Volumen (m3) = Konditionales Volumen (m3) | Fläche (m2) = Fläche der Wand (m2) | Höhenangabe zum Projekt-Nullpunkt (m) = Höhe zu 1. Referenzhöhe (m) = Höhe zu 2. Referenzhöhe (m) | Höhe zu Meereshöhe (m) | Höhe zu verknüpftem/Ursprungsgeschoss (m) = Abstand zu Ursprungsgeschoss (m) | Oberflächenbereich (m2) = Netto-Oberflächenbereich an der Außenseite (m2) = Konditionaler Oberflächenbereich an der Außenseite (m2) | 3D-Länge (m) | Brutto-Volumen (m3) | Grundriss-Umfang (m) | Minimale Höhe der Wand (m) | Netto-Oberflächenbereich an den Kanten (m2) | Netto-Oberflächenbereich an der Innenseite (m2) = Konditionaler Oberflächenbereich an der Innenseite (m2) | Länge der Referenzlinie (m) | Konditionale Länge an der Innenseite (m) = Wandlänge an der Innenseite (m) | Konditionale Länge an der Außenseite (m) = Wandlänge an der Außenseite (m) | Brutto-Wandoberflächenbereich an der Innenseite (m2) | Brutto-Wandoberflächenbereich an der Außenseite (m2) | Component 5, Masse (kg) | Component 5, Schicht/Komponente Oberflächenbereich (m2) | Component 5, Schicht/Komponente Querschnittsbereich (m2) | Component 5, Schicht/Komponente Volumen (m3) | Component 6, Masse (kg) | Component 6, Schicht/Komponente Oberflächenbereich (m2) | Component 6, Schicht/Komponente Querschnittsbereich (m2) | Component 6, Schicht/Komponente Volumen (m3) | Component 8, Masse (kg) | Component 8, Schicht/Komponente Querschnittsbereich (m2) | Component 8, Schicht/Komponente Volumen (m3) | Component 4, Masse (kg) | Component 4, Schicht/Komponente Querschnittsbereich (m2) | Component 4, Schicht/Komponente Volumen (m3) | Component 2, Masse (kg) | Component 2, Schicht/Komponente Querschnittsbereich (m2) | Component 2, Schicht/Komponente Volumen (m3) | Component 1, Masse (kg) | Component 1, Schicht/Komponente Querschnittsbereich (m2) | Component 1, Schicht/Komponente Volumen (m3) | Component 3, Masse (kg) | Component 3, Schicht/Komponente Höhe (rechteckig) (m) | Component 3, Schicht/Komponente Breite (rechteckig) (m) | Component 3, Schicht/Komponente Querschnittsbereich (m2) | Component 3, Schicht/Komponente Volumen (m3) | Component 7, Masse (kg) | Component 7, Schicht/Komponente Höhe (rechteckig) (m) | Component 7, Schicht/Komponente Breite (rechteckig) (m) | Component 7, Schicht/Komponente Querschnittsbereich (m2) | Component 7, Schicht/Komponente Volumen (m3) | Component 9, Masse (kg) | Component 9, Schicht/Komponente Querschnittsbereich (m2) | Component 9, Schicht/Komponente Volumen (m3) | Component 5, Schicht/Komponente Höhe (rechteckig) (m) | Component 5, Schicht/Komponente Breite (rechteckig) (m) | Component 4, Schicht/Komponente Oberflächenbereich (m2) | Component 8, Schicht/Komponente Oberflächenbereich (m2) | Component 9, Schicht/Komponente Oberflächenbereich (m2) | Component 7, Schicht/Komponente Oberflächenbereich (m2)
Attika-Wand-004 | OG | Verputz, Kalkzement, Holz, Bauholz (2), Dämmung, hart XPS (2), Holz, Brettschichtholz, MW Kalksandstein, Holz, Spanplatte, Metall, Stahl verzinkt | Attika-Wand-004 | Grundfläche Gebäude Nachgezogen; Obergeschoss; Wohnung1 OG; Wohnung2 OG | Wohnung2 OG | R-020 | 1. OG | 1 | Holz Kiefer; Verputz, glatt, weiß; Metall Stahl, verzinkt; Farbe, weiß; Holzwerkstoff Spanplatte; Farbe, hellblau; Holz Brettschichtholz | 23.6663 (kgCO₂) | 405.708 | Kern | 0.765946 (kgCO₂) | 18.3563 | Andere | 31.9994 (kgCO₂) | 490.117 | 19.7817 (kgCO₂) | 452.696 | 1.22316 (kgCO₂) | 29.3138 | 9.64024 (kgCO₂) | 63.5379 | 14.8794 (kgCO₂) | 380.251 | 13.381 (kgCO₂) | 341.958 | 73.4316 (kgCO₂) | 1010.94 | 17.937 | 6.0007 | 24.8205 | 0.724812 | 3.44171 | 6.57 | 22.57 | 2.82 | 6.73871 | 6.28748 | 0.769154 | 13.3861 | 1.10019e-11 | 5.19605 | 6.00227 | 6.06962 | 6.28748 | 5.71392 | 6.37957 | 7.11906 | 338.09 | 0.939138 | 0.032 | 0.187828 | 2.64119 |  | 0.000896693 | 0.00528239 | 40.5056 | 0.0116182 | 0.0675093 | 38.0417 | 0.0216038 | 0.126806 | 4.21781 | 0.00137822 | 0.00843562 | 43.8193 | 0.00439625 | 0.027387 | 4.3507 | 0.16 | 0.16 | 0.0256 | 0.155382 | 3.91256 | 0.22 | 0.110283 | 0.0242622 | 0.139734 | 50.2956 | 0.00107492 | 0.00644816 | 0.16 | 0.2 | 2.1138 | 3.42224 | 3.46462 | 1.26705
Attika-Wand-004 | OG | Verputz, Kalkzement, Holz, Bauholz (2), Dämmung, hart XPS (2), Holz, Brettschichtholz, MW Kalksandstein, Holz, Spanplatte, Metall, Stahl verzinkt | Attika-Wand-004 | Grundfläche Gebäude Nachgezogen; Obergeschoss; Wohnung2 OG | Wohnung2 OG | R-020 | 1. OG | 1 | Holz Kiefer; Verputz, glatt, weiß; Metall Stahl, verzinkt; Farbe, weiß; Holzwerkstoff Spanplatte; Farbe, hellblau; Holz Brettschichtholz | 21.5712 (kgCO₂) | 369.792 | Kern | 0.664404 (kgCO₂) | 15.9228 | Andere | 30.8155 (kgCO₂) | 471.984 | 19.1094 (kgCO₂) | 437.311 | 1.11315 (kgCO₂) | 26.6772 | 8.83611 (kgCO₂) | 58.238 | 13.8998 (kgCO₂) | 355.216 | 11.5006 (kgCO₂) | 293.904 | 64.2554 (kgCO₂) | 884.613 | 15.9575 | 5.21217 | 21.9364 | 0.666962 | 2.98945 | 6.57 | 22.57 | 2.82 | 5.8922 | 5.78572 | 0.704386 | 12.0466 | 0 | 4.65826 | 5.40708 | 5.35 | 5.78572 | 4.63862 | 5.86223 | 6.54273 | 308.16 | 0.856 | 0.032 | 0.1712 | 2.29105 |  | 0.000896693 | 0.0045821 | 39.007 | 0.0116182 | 0.0650116 | 36.7488 | 0.0216038 | 0.122496 | 3.83844 | 0.00137822 | 0.00767688 | 40.1642 | 0.00439625 | 0.0251026 | 4.06426 | 0.16 | 0.16 | 0.0256 | 0.145152 | 3.36275 | 0.22 | 0.110283 | 0.0242622 | 0.120098 | 44.0106 | 0.00107492 | 0.00564238 | 0.16 | 0.2 | 2.042 | 3.29816 | 3.04973 | 1.089

# IfcBeam: Bauteil - Attika Mauerwerk Giebelwand 574 x 270, Attika-Wand-015
In: OG
Classification: Balken / Unterzug (ARCHICAD Klassifizierung); Material: Verputz, Kalkzement, Holz, Bauholz (2), Dämmung, hart XPS (2), Holz, Brettschichtholz, MW Kalksandstein, Holz, Spanplatte, Metall, Stahl verzinkt
ArchiCADProperties - Element ID: Attika-Wand-015; Hotlink und Element-ID: Attika-Wand-015; Ebene: Attika; Baustoff / Mehrschichtiger Aufbau / Profil / Schraffur: Bauteil - Attika Mauerwerk Giebelwand; Profil: Bauteil - Attika Mauerwerk Giebelwand; Kollidierende Räume: Grundfläche Gebäude Nachgezogen; Obergeschoss; Wohnung1 OG; Wohnung2 OG; Zugehöriger Raumname: Wohnung2 OG; Zugehörige Raumnummer: R-020; Geschützt: no; Ursprungsgeschoss Name: 1. OG; Ursprungsgeschoss Nummer: 1; Typ: Wand; Absolutes Geschoss für Oberkantenverknüpfung: Nicht verknüpft; Relatives Geschoss für Oberkantenverknüpfung: Nicht verknüpft; Geschoss für Oberkantenverknüpfung: Nicht verknüpft; Struktur-Typ: Profil; Überobjekt-ID: Attika-Wand-015; Baustoffe (Alle): Holz, Brettschichtholz; MW Kalksandstein; Holz, Bauholz; Holz, Bauholz; Holz, Spanplatte; Metall, Stahl verzinkt; Dämmung, hart XPS; Dämmung, hart XPS; Verputz, Kalkzement; Oberfläche (Alle): Holz Kiefer; Verputz, glatt, weiß; Metall Stahl, verzinkt; Farbe, weiß; Holzwerkstoff Spanplatte; Farbe, hellblau; Holz Brettschichtholz; Neigungswinkel: 90 deg; Lage: Außen; Tragende Funktion: Tragende Elemente; Anzeigen auf Umbau-Filter: Alle relevanten Filter; Umbau-Status: Bestand; Wandkomplexität: gerade; Geometriemethode: Uni; Wand Innerer Neigungswinkel: 90 deg; Wand Äußerer Neigungswinkel: 90 deg; ARCHICAD Klassifizierung - 22: Balken / Unterzug
Brandschutz 4102-2 - Kennbuchstabe: F
Pset_BeamCommon - LoadBearing: yes; IsExternal: yes
Component Properties - Component 4, Enthaltenes CO2: 11.5283 (kgCO₂); Component 4, Enthaltene Energie: 263.82 MJ; Component 4, Komponenten-Typ: Andere; Component 5, Enthaltenes CO2: 19.8592 (kgCO₂); Component 5, Enthaltene Energie: 340.443 MJ; Component 5, Komponenten-Typ: Kern; Component 2, Enthaltenes CO2: 0.969406 (kgCO₂); Component 2, Enthaltene Energie: 23.2323 MJ; Component 2, Komponenten-Typ: Andere; Component 6, Enthaltenes CO2: 0.643177 (kgCO₂); Component 6, Enthaltene Energie: 15.4141 MJ; Component 6, Komponenten-Typ: Andere; Component 8, Enthaltenes CO2: 26.8004 (kgCO₂); Component 8, Enthaltene Energie: 410.487 MJ; Component 8, Komponenten-Typ: Andere; Component 9, Enthaltenes CO2: 61.8512 (kgCO₂); Component 9, Enthaltene Energie: 851.513 MJ; Component 9, Komponenten-Typ: Bekleidung; Component 7, Enthaltenes CO2: 11.1872 (kgCO₂); Component 7, Enthaltene Energie: 285.895 MJ; Component 7, Komponenten-Typ: Andere; Component 3, Enthaltenes CO2: 3.92645 (kgCO₂); Component 3, Enthaltene Energie: 100.343 MJ; Component 3, Komponenten-Typ: Andere; Component 1, Enthaltenes CO2: 8.17906 (kgCO₂); Component 1, Enthaltene Energie: 53.9074 MJ; Component 1, Komponenten-Typ: Bekleidung
BaseQuantities - NetSurfaceAreaExtrudedSides: 13.9446 m2; Length: 5.05647 m; CrossSectionArea: 0.154806 m2; OuterSurfaceArea: 13.9446 m2; TotalSurfaceArea: 19.7449 m2; GrossSurfaceArea: 19.7449 m2; GrossVolume: 0.485669 m3; NetVolume: 0.485669 m3
ArchiCADQuantities - Fläche: 2.90015 m2; Höhe: 0.269908 m; Netto-Volumen: 0.485669 m3; Breite: 0.573552 m; Höhenangabe zum Projekt-Nullpunkt: 6.57 m; Höhe zu 1. Referenzhöhe: 6.57 m; Höhe zu 2. Referenzhöhe: 6.57 m; Höhe zu Meereshöhe: 22.57 m; Höhe zu verknüpftem/Ursprungsgeschoss: 2.82 m; Abstand zu Ursprungsgeschoss: 2.82 m; Abstand Oberkante: 0 m; Oberflächenbereich: 5.66123 m2; 3D-Länge: 5.34324 m; Dicke: 0.573552 m; Konditionales Volumen: 0.485669 m3; Brutto-Volumen: 0.524109 m3; Dämmungsschichtdicke: 0 m; Grundriss-Umfang: 11.4976 m; Anzahl der Türen: 0; Anzahl der Durchbrüche (Anzahl der leeren Öffnungen): 0; Anzahl der Fenster: 0; Anzahl der Stützen: 0; Volumen der Stützen: 0 m3; Maximale Höhe der Wandschicht an der Innenseite: 0 m; Minimale Höhe der Wandschicht an der Innenseite: 0 m; Maximale Höhe der Wand: 0.269908 m; Minimale Höhe der Wand: 2.19984e-11 m; Maximale Höhe der Wandschicht an der Außenseite: 0 m; Minimale Höhe der Wandschicht an der Außenseite: 0 m; Luftschichtdicke: 0 m; Fläche der Türen: 0 m2; Kombinierte Breite der Türen: 0 m; Wand-Schichtdicke an der Innenseite: 0 m; Wand-Schichtdicke an der Außenseite: 0 m; Fläche der Fenster: 0 m2; Kombinierte Breite der Fenster: 0 m; Analytische Oberfläche der Öffnungen an der Innenseite: 0 m2; Analytische Oberfläche der Öffnungen an der Außenseite: 0 m2; Durchschnittliche Länge der Wand: 5.05647 m; Netto-Oberflächenbereich an den Kanten: 3.24707 m2; Netto-Oberflächenbereich an der Innenseite: 5.03632 m2; Netto-Oberflächenbereich an der Außenseite: 5.66123 m2; Analytisches Volumen der Öffnungen: 0 m3; Länge der Referenzlinie: 5.12538 m; Konditionale Länge an der Innenseite: 5.34324 m; Konditionaler Oberflächenbereich an der Innenseite: 5.03632 m2; Konditionale Länge an der Außenseite: 4.76969 m; Konditionaler Oberflächenbereich an der Außenseite: 5.66123 m2; Brutto-Wandoberflächenbereich an der Innenseite: 5.4135 m2; Brutto-Wandoberflächenbereich an der Außenseite: 6.04134 m2; Wandstärke am Ende: 0.573552 m; Länge der Wand in der Achse: 5.05647 m; Wandlänge an der Innenseite: 5.34324 m; Wandlänge an der Außenseite: 4.76969 m; Fläche der Wand: 2.90015 m2; Oberflächenbereich der leeren Öffnungen in der Wand: 0 m2; Dämmung innen: 0.110283 m; Dämmung innen Höhe: 0.16 m; Dämmungsbreite: 0.05 m; Dämmungshöhe: 0.16 m; Höhe Außenbekleidung: 0.16 m; Höhe Wandaufbau: 0.16 m
Component Quantities - Component 4, Masse: 22.1698 kg; Component 4, Schicht/Komponente Oberflächenbereich: 1.23196 m2; Component 4, Schicht/Komponente Querschnittsbereich: 0.0150037 m2; Component 4, Schicht/Komponente Volumen: 0.0738992 m3; Component 5, Masse: 283.702 kg; Component 5, Schicht/Komponente Oberflächenbereich: 0.788062 m2; Component 5, Schicht/Komponente Höhe (rechteckig): 0.16 m; Component 5, Schicht/Komponente Breite (rechteckig): 0.2 m; Component 5, Schicht/Komponente Querschnittsbereich: 0.032 m2; Component 5, Schicht/Komponente Volumen: 0.157612 m3; Component 2, Masse: 3.34278 kg; Component 2, Schicht/Komponente Querschnittsbereich: 0.00129176 m2; Component 2, Schicht/Komponente Volumen: 0.00668556 m3; Component 6, Masse: 2.21785 kg; Component 6, Schicht/Komponente Querschnittsbereich: 0.000896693 m2; Component 6, Schicht/Komponente Volumen: 0.0044357 m3; Component 8, Masse: 33.9246 kg; Component 8, Schicht/Komponente Oberflächenbereich: 2.8837 m2; Component 8, Schicht/Komponente Querschnittsbereich: 0.0116182 m2; Component 8, Schicht/Komponente Volumen: 0.0565409 m3; Component 9, Masse: 42.3638 kg; Component 9, Schicht/Komponente Oberflächenbereich: 2.9193 m2; Component 9, Schicht/Komponente Querschnittsbereich: 0.00107492 m2; Component 9, Schicht/Komponente Volumen: 0.00543126 m3; Component 7, Masse: 3.27111 kg; Component 7, Schicht/Komponente Oberflächenbereich: 1.05932 m2; Component 7, Schicht/Komponente Höhe (rechteckig): 0.22 m; Component 7, Schicht/Komponente Breite (rechteckig): 0.110283 m; Component 7, Schicht/Komponente Querschnittsbereich: 0.0242622 m2; Component 7, Schicht/Komponente Volumen: 0.116825 m3; Component 3, Masse: 1.14809 kg; Component 3, Schicht/Komponente Höhe (rechteckig): 0.16 m; Component 3, Schicht/Komponente Breite (rechteckig): 0.05 m; Component 3, Schicht/Komponente Querschnittsbereich: 0.008 m2; Component 3, Schicht/Komponente Volumen: 0.0410031 m3; Component 1, Masse: 37.1775 kg; Component 1, Schicht/Komponente Querschnittsbereich: 0.00439625 m2; Component 1, Schicht/Komponente Volumen: 0.023236 m3

# IfcBeam: Schifter RM 22 (2)
In: OG
Classification: Balken / Unterzug (ARCHICAD Klassifizierung); Material: Holz, Bauholz
ArchiCADProperties - Element ID: Sparren; Hotlink und Element-ID: Sparren; Ebene: Dachkonstruktion; Bibliothekselement-Name: Schifter RM 22; Baustoff / Mehrschichtiger Aufbau / Profil / Schraffur: Nur Hintergrund-Stift; Schraffurtyp: Nur Hintergrund-Stift; Kollidierende Räume: Grundfläche Gebäude Nachgezogen; Luftraum Dach; Obergeschoss; Wohnung1 OG; Zugehöriger Raumname: Luftraum Dach; Zugehörige Raumnummer: R-012; Geschützt: no; Ursprungsgeschoss Name: 1. OG; Ursprungsgeschoss Nummer: 1; Typ: Objekt; Überobjekt-ID: Sparren; Baustoffe (Alle): Holz, Bauholz; Oberfläche (Alle): Holz Kiefer; Lage: Innen; Tragende Funktion: Tragende Elemente; Anzeigen auf Umbau-Filter: Alle relevanten Filter; Umbau-Status: Bestand; Drehwinkel: 180 deg; Oberfläche: Holz Brettschichtholz; ARCHICAD Klassifizierung - 22: Balken / Unterzug
AC_Pset_Schifter_RM_22 - 2D-Fixpunkte in 3D zeigen: no; Neigungswinkel: 36.8234 deg; Winkel zu First oder Querbalken: 90 deg; First oder Querbalken gedreht: no; Winkel zu vertikalem Sparren: 90 deg; Querbalken senkrecht: yes; Dachkantenwinkel (rm_iRoofEdgeAngle): 0; Unterschlag: no; Winkel des Unterschlags: 90 deg; Winkel zwischen verbundenen Elementen: 0 deg; Linientyp Achse: 6; Linienstift Achse: Elemente+Text; Sparren in 2D sichtbar: yes; Grundrissdarstellung (AC_symb_display_option): 3; Projektion zeigen (AC_symb_show_projection_to): 3; Grundrissdarstellung (gs_symb_display_option): Symbolische Darstellung; 3D Eigenschaften anwenden: no; Projektion zeigen (gs_symb_show_projection_to): Komplettes Element; Aufsichtslinien / Kontur: 1; Aufsichslinie / Konturstift: Elemente+Text; Schraffur: Nur Hintergrund-Stift; Schraffur-Vordergrundstift: Schraffurhintergrund; Schraffur-Hintergrundstift: Schraffurhintergrund; Schnittlinien: 1; Untersichtslinien: 21; Untersichtslinien-Stift: Konturstift; 2D-Symbol: no; 2D-Projektionstyp: 0; Stift in 3D: Schichttrennlinien/Kontur; Baustoff: Verband, Fischgrät, 5x15, 45°; Oberflächen überschreiben: no; Oberflächenmaterial: Holz Esche; Schnittschraffur-Stift überschreiben: 0; Schnittschraffur-Hintergrundstift: Gefahrenzeichen; Holzgröße zeigen: no; Größe für die Anzeige auswählen (displaySize): Elementlänge; Größe für die Anzeige auswählen (iDisplaySize): 1; Text-Stift: Elemente+Text; Schrifttyp: Arial; Schriftgröße: 10; Fett: no; Kursiv: no; Unterstrichen: no; Text-Ausrichtung am Symbol (typeTextRotation): Lesbar; Text-Ausrichtung am Symbol (typeTextRotation_m): 2; Lesbarer Winkel: 90 deg; Rundungswert (roundingValue): 50; Rundungswert (iRoundingValue): 3; Rundungswert (roundingValueUSA): 2; Rundungswert (iRoundingValueUSA): 5; Volumen in BDFT: 0; Preis: 0; Gruppe Typ (FM_Type): Andere; Gruppe Typ (iFMType): 25; Objektgewicht: 0; Objektgewichtseinheit: kg; Standard zeigen: 2
Brandschutz 4102-2 - Kennbuchstabe: F
Pset_BeamCommon - LoadBearing: yes; IsExternal: no
ArchiCADQuantities - Breite: 0.1 m; Höhe zu Meereshöhe: 22.417 m
AC_Equantity_Schifter_RM_22 - Profilbreite (B): 0.1 m; Obere Ebene: 0.249848 m; Profilbreite (rm_ProfileWidth): 0.1 m; Profilbreite (profileWidthHalf): 0.05 m; Profilhöhe: 0.2 m; Breite vom First oder Querbalken: 0 m; Breite vom vertikalen Sparren oder Querbalken: 0.08 m; Überstand: 0 m; Stärke der verbundenen Elemente: 0 m; Abstand des Schnitts zur Achse: 0 m; Höhe der Schnittebene: 0 m; Höhe der oberen Schnittebene: 0 m; Höhe der unteren Schnittebene: 0 m; Text Position X: 0 m; Text Position Y: 0 m; Rundungswert: 0 m; Aufgerundete Elementlänge: 0.85 m
Name | Component 1, Enthaltenes CO2 | Component 1, Enthaltene Energie (MJ) | Fläche (m2) | Höhe (m) = Absolute Höhe (m) | Netto-Volumen (m3) = Component 1, Schicht/Komponente Volumen (m3) | Höhenangabe zum Projekt-Nullpunkt (m) = Höhe zu 1. Referenzhöhe (m) = Höhe zu 2. Referenzhöhe (m) | Höhe zu verknüpftem/Ursprungsgeschoss (m) = Abstand zu Ursprungsgeschoss (m) | Oberflächenbereich (m2) | Länge (A) (m) = Horizontale Projektion (m) = Originallänge (m) | Untere Ebene (m) | Länge Struktural (rm_StructuralLength) (m) = Elementlänge (m) | Länge Struktural (structuralLength) (m) | Höhenunterschied (m) | Component 1, Masse (kg)
Sparren | 2.17192 (kgCO₂) | 52.0511 | 0.0634785 | 0.656282 | 0.0149787 | 6.41698 | 2.66698 | 0.492833 | 0.634785 | -0.406434 | 0.827871 | 0.792998 | 0.475283 | 7.48937
Sparren | 2.1773 (kgCO₂) | 52.1802 | 0.0636271 | 0.657395 | 0.0150159 | 6.41695 | 2.66695 | 0.493947 | 0.636271 | -0.407547 | 0.829727 | 0.794854 | 0.476396 | 7.50794

# IfcBeam: Sparren mit Dachkantenabschluss RM 22 (23)
In: OG
Classification: Balken / Unterzug (ARCHICAD Klassifizierung); Material: Holz, Bauholz
ArchiCADProperties - Element ID: Sparren; Hotlink und Element-ID: Sparren; Ebene: Dachkonstruktion; Bibliothekselement-Name: Sparren mit Dachkantenabschluss RM 22; Baustoff / Mehrschichtiger Aufbau / Profil / Schraffur: Nur Hintergrund-Stift; Schraffurtyp: Nur Hintergrund-Stift; Geschützt: no; Ursprungsgeschoss Name: 1. OG; Ursprungsgeschoss Nummer: 1; Typ: Objekt; Überobjekt-ID: Sparren; Baustoffe (Alle): Holz, Bauholz; Oberfläche (Alle): Holz Kiefer; Lage: Innen; Tragende Funktion: Tragende Elemente; Anzeigen auf Umbau-Filter: Alle relevanten Filter; Umbau-Status: Bestand; Oberfläche: Holz Brettschichtholz; ARCHICAD Klassifizierung - 22: Balken / Unterzug
AC_Pset_Sparren_mit_Dachkantenabschluss_RM_22 - 2D-Fixpunkte in 3D zeigen: no; Dachkantenwinkel (rm_RoofEdgeAngle): Vertikal; Dachkantenwinkel (rm_iRoofEdgeAngle): 2; Profil (rm_profileType): Rechteckig; Profil (rm_iProfileType): 1; Winkel zu verbundenen Elementen: 90 deg; Unterschlag: no; Unterschlag zu Holzgröße nutzen: no; Winkel des Unterschlags: 20 deg; Winkel zwischen verbundenen Elementen: 0 deg; Linientyp Achse: 6; Linienstift Achse: Elemente+Text; Sparren in 2D sichtbar: yes; Grundrissdarstellung (AC_symb_display_option): 3; Projektion zeigen (AC_symb_show_projection_to): 3; Grundrissdarstellung (gs_symb_display_option): Symbolische Darstellung; 3D Eigenschaften anwenden: no; Projektion zeigen (gs_symb_show_projection_to): Komplettes Element; Aufsichtslinien / Kontur: 1; Aufsichslinie / Konturstift: Elemente+Text; Schraffur: Nur Hintergrund-Stift; Schraffur-Vordergrundstift: Schraffurhintergrund; Schraffur-Hintergrundstift: Schraffurhintergrund; Schnittlinien: 1; Untersichtslinien: 21; Untersichtslinien-Stift: Konturstift; 2D-Symbol: no; 2D-Projektionstyp: 0; Stift in 3D: Schichttrennlinien/Kontur; Baustoff: Verband, Fischgrät, 5x15, 45°; Oberflächen überschreiben: no; Oberflächenmaterial: Holz Esche; Schnittschraffur-Stift überschreiben: 0; Schnittschraffur-Hintergrundstift: Gefahrenzeichen; Holzgröße zeigen: no; Größe für die Anzeige auswählen (displaySize): Elementlänge; Größe für die Anzeige auswählen (iDisplaySize): 1; Text-Stift: Elemente+Text; Schrifttyp: Arial; Schriftgröße: 10; Fett: no; Kursiv: no; Unterstrichen: no; Text-Ausrichtung am Symbol (typeTextRotation): Lesbar; Text-Ausrichtung am Symbol (typeTextRotation_m): 2; Lesbarer Winkel: 90 deg; Rundungswert (roundingValue): 50; Rundungswert (iRoundingValue): 3; Rundungswert (roundingValueUSA): 2; Rundungswert (iRoundingValueUSA): 5; Volumen in BDFT: 0; Preis: 0; Gruppe Typ (FM_Type): Andere; Gruppe Typ (iFMType): 25; Objektgewicht: 0; Objektgewichtseinheit: kg; Standard zeigen: 2
Brandschutz 4102-2 - Kennbuchstabe: F
Pset_BeamCommon - LoadBearing: yes; IsExternal: no
ArchiCADQuantities - Breite: 0.1 m
AC_Equantity_Sparren_mit_Dachkantenabschluss_RM_22 - Profilbreite (B): 0.1 m; Profilbreite (rm_ProfileWidth): 0.1 m; Profilbreite (profileWidthHalf): 0.05 m; Profilhöhe: 0.2 m; Profildicke: 0.005 m; Abstand des Schnitts zur Achse: 0 m; Höhe der Schnittebene: 0 m; Höhe der oberen Schnittebene: 0 m; Höhe der unteren Schnittebene: 0 m; Text Position X: 0 m; Text Position Y: 0 m; Rundungswert: 0 m
Name | Kollidierende Räume | Zugehöriger Raumname | Zugehörige Raumnummer | Drehwinkel (deg) | Neigungswinkel (deg) | First oder Querbalken gedreht | Fläche (m2) | Höhe (m) = Absolute Höhe (m) | Netto-Volumen (m3) | Höhenangabe zum Projekt-Nullpunkt (m) = Höhe zu 1. Referenzhöhe (m) = Höhe zu 2. Referenzhöhe (m) | Höhe zu Meereshöhe (m) | Höhe zu verknüpftem/Ursprungsgeschoss (m) = Abstand zu Ursprungsgeschoss (m) | Oberflächenbereich (m2) | Länge (A) (m) = Horizontale Projektion (m) | Untere Ebene (m) | Obere Ebene (m) | Reale Länge (rm_StructuralLength) (m) = Elementlänge (m) | Reale Länge (structuralLength) (m) | Projiziert Länge bis Drehpunkt (m) | Relative Sparrenhöhe (m) | Überstand (rm_OverHang) (m) | Überstand (overHang) (m) | Stärke der verbundenen Elemente (m) | Aufgerundete Elementlänge (m)
Sparren | Dachterrasse; Grundfläche Gebäude Nachgezogen; Luftraum Dach; Obergeschoss; Wohnung1 OG | Luftraum Dach | R-012 | 180 | 36.82 | no | 0.291 | 2.42838 | 0.0727025 | 4.23839 | 20.2384 | 0.488392 | 2.23104 | 2.91 | 0 | 2.42838 | 3.78486 | 3.63513 | 2.91 | 2.17854 | 0 | 0 | 0 | 3.8 | Component Properties - Component 1, Enthaltenes CO2: 10.5419 (kgCO₂); Component 1, Enthaltene Energie: 252.641 MJ; Component Quantities - Component 1, Masse: 36.3513 kg; Component 1, Schicht/Komponente Volumen: 0.0727025 m3
Sparren | Grundfläche Gebäude Nachgezogen; Obergeschoss; Wohnung1 OG | Wohnung1 OG | R-021 | 0 | 36.8234 | no | 0.291638 | 2.43344 | 0.0728652 | 4.31304 | 20.313 | 0.563044 | 2.23593 | 2.91638 | -0.0796519 | 2.35378 | 3.79301 | 3.51036 | 2.81 | 2.10394 | 0.106382 | 0.132897 | 0 | 3.8 | Component Properties - Component 1, Enthaltenes CO2: 10.5655 (kgCO₂); Component 1, Enthaltene Energie: 253.207 MJ; Component Quantities - Component 1, Masse: 36.4326 kg; Component 1, Schicht/Komponente Volumen: 0.0728652 m3
Sparren | Grundfläche Gebäude Nachgezogen; Obergeschoss; Wohnung1 OG | Wohnung1 OG | R-021 | 180 | 36.82 | no | 0.291 | 2.42838 | 0.0727025 | 4.23839 | 20.2384 | 0.488392 | 2.23104 | 2.91 | 0 | 2.42838 | 3.78486 | 3.63513 | 2.91 | 2.17854 | 0 | 0 | 0 | 3.8
Sparren | Grundfläche Gebäude Nachgezogen; Luftraum Dach; Obergeschoss; Wohnung1 OG | Luftraum Dach | R-012 | 180 | 36.82 | no | 0.0482424 | 0.610999 | 0.0120527 | 6.05583 | 22.0558 | 2.30583 | 0.411549 | 0.482424 | 0 | 0.610999 | 0.752364 | 0.602636 | 0.482424 | 0.361162 | 0 | 0 | 0 | 0.8 | Component Properties - Component 1, Enthaltenes CO2: 1.74765 (kgCO₂); Component 1, Enthaltene Energie: 41.8832 MJ; Component Quantities - Component 1, Masse: 6.02636 kg; Component 1, Schicht/Komponente Volumen: 0.0120527 m3
Sparren | Dachterrasse; Grundfläche Gebäude Nachgezogen; Luftraum Dach; Obergeschoss; Wohnung1 OG | Luftraum Dach | R-012 | 0 | 3.68 | no | 0.243114 | 0.356776 | 0.0487232 | 6.05575 | 22.0557 | 2.30575 | 1.50178 | 2.43114 | 0 | 0.356776 | 2.44902 | 2.43616 | 2.43114 | 0.156362 | 0 | 0 | 0 | 2.45 | Component Properties - Component 1, Enthaltenes CO2: 7.06486 (kgCO₂); Component 1, Enthaltene Energie: 169.313 MJ; Component Quantities - Component 1, Masse: 24.3616 kg; Component 1, Schicht/Komponente Volumen: 0.0487232 m3
Sparren | Dachterrasse; Grundfläche Gebäude Nachgezogen; Luftraum Dach; Obergeschoss; Wohnung1 OG | Luftraum Dach | R-012 | 0 | 3.68 | no | 0.243114 | 0.356776 | 0.0487232 | 6.05578 | 22.0558 | 2.30578 | 1.50178 | 2.43114 | 0 | 0.356776 | 2.44902 | 2.43616 | 2.43114 | 0.156362 | 0 | 0 | 0 | 2.45
Sparren | Dachterrasse; Grundfläche Gebäude Nachgezogen; Luftraum Dach; Obergeschoss; Wohnung1 OG | Luftraum Dach | R-012 | 0 | 3.68 | no | 0.241506 | 0.355741 | 0.0484009 | 6.05583 | 22.0558 | 2.30583 | 1.49211 | 2.41506 | 0 | 0.355741 | 2.43291 | 2.42005 | 2.41506 | 0.155328 | 0 | 0 | 0 | 2.45 | Component Properties - Component 1, Enthaltenes CO2: 7.01813 (kgCO₂); Component 1, Enthaltene Energie: 168.193 MJ; Component Quantities - Component 1, Masse: 24.2005 kg; Component 1, Schicht/Komponente Volumen: 0.0484009 m3
3 x Sparren | Dachterrasse; Grundfläche Gebäude Nachgezogen; Luftraum Dach; Obergeschoss; Wohnung1 OG | Luftraum Dach | R-012 | 180 | 36.82 | no | 0.291 | 2.42838 | 0.0727025 | 4.23839 | 20.2384 | 0.488392 | 2.23104 | 2.91 | 0 | 2.42838 | 3.78486 | 3.63513 | 2.91 | 2.17854 | 0 | 0 | 0 | 3.8
Sparren | Grundfläche Gebäude Nachgezogen; Luftraum Dach; Obergeschoss; Wohnung1 OG; Wohnung2 OG | Wohnung1 OG | R-021 | 180 | 36.82 | no | 0.291 | 2.42838 | 0.0727025 | 4.23839 | 20.2384 | 0.488392 | 2.23104 | 2.91 | 0 | 2.42838 | 3.78486 | 3.63513 | 2.91 | 2.17854 | 0 | 0 | 0 | 3.8
Sparren | Grundfläche Gebäude Nachgezogen; Luftraum Dach; Obergeschoss; Wohnung1 OG | Luftraum Dach | R-012 | 180 | 36.82 | no | 0.0482424 | 0.610999 | 0.0120527 | 6.05575 | 22.0557 | 2.30575 | 0.411549 | 0.482424 | 0 | 0.610999 | 0.752364 | 0.602636 | 0.482424 | 0.361162 | 0 | 0 | 0 | 0.8
Sparren | Grundfläche Gebäude Nachgezogen; Luftraum Dach; Obergeschoss; Wohnung1 OG | Luftraum Dach | R-012 | 180 | 36.82 | no | 0.0482424 | 0.610999 | 0.0120527 | 6.05578 | 22.0558 | 2.30578 | 0.411549 | 0.482424 | 0 | 0.610999 | 0.752364 | 0.602636 | 0.482424 | 0.361162 | 0 | 0 | 0 | 0.8
Sparren | Dachterrasse; Grundfläche Gebäude Nachgezogen; Luftraum Dach; Obergeschoss; Wohnung1 OG | Luftraum Dach | R-012 | 180 | 36.82 | no | 0.291 | 2.42838 | 0.0727025 | 4.23845 | 20.2384 | 0.488449 | 2.23104 | 2.91 | 0 | 2.42838 | 3.78486 | 3.63513 | 2.91 | 2.17854 | 0 | 0 | 0 | 3.8
6 x Sparren | Grundfläche Gebäude Nachgezogen; Luftraum Dach; Obergeschoss; Wohnung1 OG | Luftraum Dach | R-012 | 0 | 36.8234 | no | 0.291638 | 2.43344 | 0.0728652 | 4.31304 | 20.313 | 0.563044 | 2.23593 | 2.91638 | -0.0796519 | 2.35378 | 3.79301 | 3.51036 | 2.81 | 2.10394 | 0.106382 | 0.132897 | 0 | 3.8
Sparren | Grundfläche Gebäude Nachgezogen; Luftraum Dach; Obergeschoss; Wohnung1 OG; Wohnung2 OG | Wohnung1 OG | R-021 | 0 | 36.8234 | no | 0.291638 | 2.43344 | 0.0728652 | 4.31304 | 20.313 | 0.563044 | 2.23593 | 2.91638 | -0.0796519 | 2.35378 | 3.79301 | 3.51036 | 2.81 | 2.10394 | 0.106382 | 0.132897 | 0 | 3.8
Sparren | Grundfläche Gebäude Nachgezogen; Luftraum Dach; Obergeschoss; Wohnung1 OG | Wohnung1 OG | R-021 | 0 | 36.8234 | yes | 0.0865027 | 0.807771 | 0.0201151 | 4.31304 | 20.313 | 0.563044 | 0.648436 | 0.865027 | -0.0796519 | 0.728119 | 1.08063 | 0.912856 | 0.730729 | 0.54712 | 0.106382 | 0.132897 | 0.08 | 1.1 | Component Properties - Component 1, Enthaltenes CO2: 2.91668 (kgCO₂); Component 1, Enthaltene Energie: 69.8998 MJ; Component Quantities - Component 1, Masse: 10.0575 kg; Component 1, Schicht/Komponente Volumen: 0.0201151 m3
Sparren | Grundfläche Gebäude Nachgezogen; Luftraum Dach; Obergeschoss; Wohnung1 OG | Wohnung1 OG | R-021 | 0 | 36.8234 | yes | 0.0864203 | 0.807153 | 0.0200945 | 4.31304 | 20.313 | 0.563044 | 0.647819 | 0.864203 | -0.0796519 | 0.727502 | 1.0796 | 0.911826 | 0.729905 | 0.546503 | 0.106382 | 0.132897 | 0.08 | 1.1 | Component Properties - Component 1, Enthaltenes CO2: 2.9137 (kgCO₂); Component 1, Enthaltene Energie: 69.8282 MJ; Component Quantities - Component 1, Masse: 10.0472 kg; Component 1, Schicht/Komponente Volumen: 0.0200945 m3

# IfcBeam: Wechsel RM 22 (2)
In: OG
Classification: Balken / Unterzug (ARCHICAD Klassifizierung); Material: Holz, Bauholz
ArchiCADProperties - Element ID: Fette; Hotlink und Element-ID: Fette; Ebene: Dachkonstruktion; Bibliothekselement-Name: Wechsel RM 22; Baustoff / Mehrschichtiger Aufbau / Profil / Schraffur: Nur Hintergrund-Stift; Schraffurtyp: Nur Hintergrund-Stift; Kollidierende Räume: Grundfläche Gebäude Nachgezogen; Luftraum Dach; Obergeschoss; Wohnung1 OG; Zugehöriger Raumname: Luftraum Dach; Zugehörige Raumnummer: R-012; Geschützt: no; Ursprungsgeschoss Name: 1. OG; Ursprungsgeschoss Nummer: 1; Typ: Objekt; Überobjekt-ID: Fette; Baustoffe (Alle): Holz, Bauholz; Oberfläche (Alle): Holz Kiefer; Lage: Innen; Tragende Funktion: Tragende Elemente; Anzeigen auf Umbau-Filter: Alle relevanten Filter; Umbau-Status: Bestand; Drehwinkel: 0 deg; Oberfläche: Holz Brettschichtholz; ARCHICAD Klassifizierung - 22: Balken / Unterzug
AC_Pset_Wechsel_RM_22 - 2D-Fixpunkte in 3D zeigen: no; Neigungswinkel: 36.8234 deg; Position Pfette (rm_TrimmerPos): Senkrecht; Position Pfette (rm_iTrimmerPos): 1; Grundrissdarstellung (AC_symb_display_option): 3; Projektion zeigen (AC_symb_show_projection_to): 3; Grundrissdarstellung (gs_symb_display_option): Symbolische Darstellung; 3D Eigenschaften anwenden: no; Projektion zeigen (gs_symb_show_projection_to): Komplettes Element; Aufsichtslinien / Kontur: 1; Aufsichslinie / Konturstift: Elemente+Text; Schraffur: Nur Hintergrund-Stift; Schraffur-Vordergrundstift: Schraffurhintergrund; Schraffur-Hintergrundstift: Schraffurhintergrund; Schnittlinien: 1; Untersichtslinien: 21; Untersichtslinien-Stift: Konturstift; 2D-Symbol: no; 2D-Projektionstyp: 0; Stift in 3D: Schichttrennlinien/Kontur; Baustoff: Verband, Fischgrät, 5x15, 45°; Oberflächen überschreiben: no; Oberflächenmaterial: Holz Esche; Schnittschraffur-Stift überschreiben: 0; Schnittschraffur-Hintergrundstift: Gefahrenzeichen; Holzgröße zeigen: no; Größe für die Anzeige auswählen (displaySize): Elementlänge; Größe für die Anzeige auswählen (iDisplaySize): 1; Text-Stift: Elemente+Text; Schrifttyp: Arial; Schriftgröße: 10; Fett: no; Kursiv: no; Unterstrichen: no; Text-Ausrichtung am Symbol (typeTextRotation): Lesbar; Text-Ausrichtung am Symbol (typeTextRotation_m): 2; Lesbarer Winkel: 90 deg; Rundungswert (roundingValue): 50; Rundungswert (iRoundingValue): 3; Rundungswert (roundingValueUSA): 2; Rundungswert (iRoundingValueUSA): 5; Volumen in BDFT: 0; Preis: 0; Gruppe Typ (FM_Type): Andere; Gruppe Typ (iFMType): 25; Objektgewicht: 0; Objektgewichtseinheit: kg; Standard zeigen: 2
Brandschutz 4102-2 - Kennbuchstabe: F
Pset_BeamCommon - LoadBearing: yes; IsExternal: no
Component Properties - Component 1, Enthaltenes CO2: 4.41728 (kgCO₂); Component 1, Enthaltene Energie: 105.862 MJ
ArchiCADQuantities - Fläche: 0.380645 m2; Höhe: 0.176026 m; Netto-Volumen: 0.030464 m3; Breite: 2.38 m; Oberflächenbereich: 1.168 m2; Länge (A): 0.159935 m
AC_Equantity_Wechsel_RM_22 - Profilbreite (A): 0.159935 m; Länge Struktural (B): 2.38 m; Profilhöhe (ZZYZX): 0.176026 m; Profilbreite (rm_ProfileWidth): 0.08 m; Profilbreite (profileWidthHalf): 0.04 m; Profilhöhe (rm_ProfileHeight): 0.16 m; Profilhöhe (profileHeightHalf): 0.08 m; Länge Struktural (rm_StructuralLength): 2.38 m; Abstand der Sparren-Achsen (rm_ProjectedLength): 2.48 m; Abstand der Sparren-Achsen (projectedLengthHalf): 1.24 m; Höhe der Sparren: 0.2 m; Stärke Endsparren (rm_RafterWidth_1): 0.1 m; Stärke Endsparren (rafterWidth_1): 0.05 m; Stärke Anfangssparren (rm_RafterWidth_2): 0.1 m; Stärke Anfangssparren (rafterWidth_2): 0.05 m; Höhe der Schnittebene: 0 m; Höhe der oberen Schnittebene: 0 m; Höhe der unteren Schnittebene: 0 m; Text Position X: 0 m; Text Position Y: 0 m; Elementlänge: 2.38 m; Rundungswert: 0 m; Aufgerundete Elementlänge: 2.4 m
Component Quantities - Component 1, Masse: 15.232 kg; Component 1, Schicht/Komponente Volumen: 0.030464 m3
Name | Höhenangabe zum Projekt-Nullpunkt (m) = Höhe zu 1. Referenzhöhe (m) = Höhe zu 2. Referenzhöhe (m) | Höhe zu Meereshöhe (m) | Höhe zu verknüpftem/Ursprungsgeschoss (m) = Abstand zu Ursprungsgeschoss (m) | Untere Ebene (m) | Obere Ebene (m) | horizontaler Abstand zur Aufsetzkante (rm_PivotDistX) (m) | horizontaler Abstand zur Aufsetzkante (pivotDistX) (m) | vertikaler Abstand zur Aufsetzkante (m)
Fette | 4.02813 | 20.0281 | 0.278127 | 1.93302 | 2.10904 | 2.53243 | 2.58037 | 1.95699
Fette | 4.28638 | 20.2864 | 0.536383 | 0.59492 | 0.770946 | 0.745273 | 0.793221 | 0.618894

# IfcBuildingElementProxy: 1-Flügelfenster 22 (19)
Classification: Fenster (ARCHICAD Klassifizierung)
ArchiCADProperties - Ebene: Wand Aussen; Bibliothekselement-Name: 1-Flügelfenster 22; Baustoff / Mehrschichtiger Aufbau / Profil / Schraffur: Misch-Schraffur 0%; Schraffurtyp: Misch-Schraffur 0%; Geschützt: no; Typ: Fenster; Tragende Funktion: Nicht tragende Elemente; Anzeigen auf Umbau-Filter: Alle relevanten Filter; Umbau-Status: Bestand; Wandstruktur: WA | 2 Schichtig KS; Öffnung Bibliothekselementname: 1-Flügelfenster 22; Öffnungsseite Schraffurindex: Misch-Schraffur 0%; ARCHICAD Klassifizierung - 22: Fenster
AC_Pset_1-Flügelfenster_22 - Wandkontur (0-Keine,1-Voll,2-Seite,3-Länge): 0; Fixpunkte 0-Kein,1-2D,2-3D,3-Alle: 3; Darstellungseinstellung Grundr.: 3; Winkel Öffnungsposition: 0 deg; Loch übernimmt Oberflächenmaterial der Wandseite: yes; Öffnungsoberfläche ist gebogen in gebogenen Wänden: no; Wand-Typ: 1; Wandquerschnittstyp: 1; Eckfenster Debugfunktion: no; Einsetzmodus (1=CW,0=W): no; Eckfenster Funktion: yes; Eckwinkel: 90 deg; Unterschiedliche Wanddicken: no; Öffnungsrichtung: 0; Grundriss: 1; 3D: 8; Schnitt / Ansicht: 1; Anschlag im Grundriss zeigen: 1; Eck-Profil: no; Ecke 2: no; Eckwinkel 2: 90 deg; Unterschiedliche Wand Dicke 2: no; Ecke 1: no; Eckwinkel 1: 90 deg; Unterschiedliche Wand Dicke 1: no; Ecke Verbindungstyp 1: 1; Ecke Verbindungstyp 2: 1; Nominalmaß: 0; Rohbauöffnung als Nominalmaß einstellen: yes; Architekturlichte als Nominalmaß einstellen: no; Rahmen-Außenmaß als Nominalmaß einstellen: no; Baurichtmaß als Nominalmaß einstellen: no; Übertrage aktuelle Nominal Größe auf die Auswahl: no; Oberlicht: no; Oberlicht Geteilt: yes; Unteres Feld: no; Unteres Feld geteilt: yes; Unterschiedliche Breiten (gs_stockb): no; Unterschiedliche Breiten (gs_ver_r): no; Öffnungswinkel Hauptflügel 3D: 0 deg; Öffnungswinkel Sprossenfenster in 3D: 0 deg; Öffnungswinkel Unteres Feld in 3D: 0 deg; Hauptflügel Kategorie (gs_SashCat_1): Haupt; Hauptflügel Kategorie (gs_iSashCat_1): 1; Öffnungstyp Sprossenfenster: 1; Oberer Querriegel Kategorie (gs_SashCat_o1): Haupt; Oberer Querriegel Kategorie (gs_iSashCat_o1): 1; Öffnungstyp Unteres Feld: 1; Unterer Querriegel Kategorie (gs_SashCat_u1): Haupt; Unterer Querriegel Kategorie (gs_iSashCat_u1): 1; Öffnungswinkel Hauptflügel2 2D: 0 deg; Öffnungswinkel Hauptflügel 2D-Rechts: 0 deg; Modelldarstell. für symbolische 2D-Darstellung überschreiben: no; Öffnungslinien in 2D: yes; Öffnungslinien-Typ: 1; Nebenöffnung Linientyp in 2D: 4; Öffnungslinien-Form (or_SwingType): Gebogen; Öffnungslinien-Form (or_iSwingType): 1; Öffnungslinien-Form (or_iSlidingType): 0; 2D & 3D Öffnungslinien-Stift (or_opLinePen): Elemente+Text; 2D & 3D Öffnungslinien-Stift (or_iOpLinePen): 1; Modelldarstell. für 3D-Darstellung überschreiben: no; Öffnungslinie zeigen: yes; Linientyp Öffnungsseite (or_opLineType3dIn): Vollinie; Linientyp Öffnungsseite (or_iOpLineType3dIn): 0; Linientyp Gegenüberliegende Seite (or_opLineType3dOut): Strichlinie; Linientyp Gegenüberliegende Seite (or_iOpLineType3dOut): 1; Nebenflügel Linientyp in 3D: Strichlinie; Nebenflügel Linientyp: 1; Linien-Ausrichtung (or_oplineStyle): Griff; Linien-Ausrichtung (or_iOplineStyle): 1; Num. of Horiz.Gitter Main Sash: 0; Num. of Vert. Gitter Hauptflügel: 0; Num. of Horiz. Gitter oberes Feld: 0; Num. of Vert. Gitter oberes Feld: 0; Num. of Horiz. Gitter unteres Feld: 0; Num. of Vert. Gitter unteres Feld: 0; Bearbeitbares Gitter: no; Fensterklinke (gs_window_handle): no; Fenstergriff Typ (gs_handle_type_win): Stil 3; Fenstergriff Typ (gs_handle_type_win_m): 3; Fenstergriff Oberflächenmaterial: Metall Stahl, matt; Hauptflügel eigener Flügel: no; Oberlicht eigener Flügel: no; Unteres Feld eigener Flügel: no; Futter und Verkleidung außen: no; Futter Außen (gs_trimtype_out): Rechteckig; Futter Außen (gs_trimtype_out_int): 1; Gehäuse Kopftyp: 1; Querbalken oben: yes; Querbalken Typ oben: 1; Verkleidung (gs_trim_show_cover_out): yes; einheitliche Einfassungsbreiten (gs_trim_outside_uniform): yes; Futter Schnittlinienstift auf beiden Seiten: Elemente+Text; Schraffur Zarge außen: Nur Hintergrund-Stift; Außenverkleidung Oberflächenmaterial: Fensterrahmen; Futter und Verkleidung innen: no; Futter Innen (gs_trimtype_in): Rechteckig; Futter Innen (gs_trimtype_in_int): 1; Verkleidung (gs_trim_show_cover_in): yes; einheitliche Einfassungsbreiten (gs_trim_inside_uniform): yes; Schraffur Zarge innen: Nur Hintergrund-Stift; Innenverkleidung Oberflächenmaterial: Fensterrahmen; Fensterbank Außen: yes; Schwelle/Fenstereinfassung Übergröße: no; Fensterbank Winkel: 3 deg; Fensterbank ist gebogen in gebogenen Wänden: yes; Dämmung unter Fensterbank: yes; Wand-Dämmschicht benutzen: no; Detaillierungsgrad in 3D Rollsicht Fensterbank: 1; Fensterbank Linienstift 3D und Aufsicht (gs_sill_pen_3D): Elemente+Text; Schnittkontur-Stift Fensterbank Außen: Elemente+Text; Fensterbank Schnittschraffur: Nur Hintergrund-Stift; Kontur-Stift: Elemente+Text; Schraffur (gs_sill_fill_ins_fg): Luftschicht; Schraffur-Vordergrundstift (gs_sill_pen_ins_fg): Elemente+Text; Mauerwerksbrüstung Mörtel Oberflächenmaterial: Verputz, rauh, grau; Winkel Fensterbank Innen: 0 deg; Fensterbank Innen ist gebogen in gebogenen Wänden: yes; Fensterbank Innen in polygonalen Wänden: 2; Schnittkontur-Stift Fensterbank Innen: Elemente+Text; Fensterbank Linienstift 3D und Aufsicht (gs_board_pen_3D): Elemente+Text; Schnittschraffur Fensterbank innen: Nur Hintergrund-Stift; Rollschicht (bMasonryArch): no; Rollschicht (gs_masonry_arch_int): 2; Typ Sturz (gs_masonry_arch_structure): Verputzt; Typ Sturz (gs_masonry_arch_structure_int): 1; Sturz direkt über der Tür: yes; Nische unterm Bogen: yes; Neigungswinkel: 75 deg; Eigenes Nischen-Oberflächenmaterial: no; Bogen Schnittschraffur: Nur Hintergrund-Stift; Stift Ziegelsturz: Schichttrennlinien/Kontur; Mauerwerksbogen Stein Oberflächenmaterial: Farbe, grau; Mauerwerksbogen Mörtel Oberflächenmaterial: Verputz, rauh, grau; Mauerwerksbogen Schlusstein Oberflächenmaterial: Farbe, grau; Nischen-Oberflächenmaterial: Verputz, rauh, gelb; Oberfläche Eckstütze: Fensterrahmen; Faschen Links: no; Faschen Rechts: no; Faschen Oben: no; Faschen Unten: no; Typ Faschen: 1; Voreingestellte Faschen - rechts: yes; Voreingestellte Faschen - links: yes; Faschentiefe >= Anschlagstiefe: no; Schnittschraffur (gs_faschen_fill): Erde 1; Schnittschraffur-Vordergrundstift (gs_faschen_fg): Schichttrennlinien/Kontur; 3D-Konturstift: Konturstift; Putz Oberflächenmaterial: Verputz, rauh, grau; Stein Oberflächenmaterial: MW Ziegel, blaurot, DF, Läufer; Mörtel Oberflächenmaterial: Verputz, rauh, grau; Typ Anschlag (gs_reveal_type_new): ohne Anschlag; Typ Anschlag (gs_reveal_type_int): 2; Untere Laibung Typ (gs_reveal_type_bottom): Gleich; Untere Laibung Typ (gs_reveal_type_bottom_int): 1; Äußerer Laibungstyp: ohne Anschlag; Typ Anschlag (gs_reveal_doubleOuterTypeInt): 0; Laibungstyp Innen: ohne Anschlag; Typ Anschlag (gs_reveal_doubleInnerTypeInt): 0; Anschlagtiefe und Laibungswinkel gleich: yes; Laibung bearbeiten von (gs_reveal_angle_edit_by): Winkel und Tiefe; Laibung bearbeiten von (gs_reveal_angle_edit_by_int): 1; Winkel Seite 2: 20 deg; Winkel Seite: 20 deg; Winkel oben: 20 deg; Winkel unten: 20 deg; Außenwinkel Seite 2: 20 deg; Außenwinkel Seite: 20 deg; Außenwinkel obere Seite: 20 deg; Außenwinkel untere Seite: 20 deg; Einbaurahmen: no; Einbaurahmen Aufsichtslinien-Stift: Elemente+Text; Einbaurahmen Konturstift (gs_mountingFrame_pen_cont): Elemente+Text; Einbaurahmen Schraffur (gs_mountingFrame_fill): Nur Hintergrund-Stift; Einbaurahmen Oberflächenmaterial: Holz Esche; Schichteinzug (gs_closure_type): Kein Schichteinzug; Schichteinzug (gs_closure_type_int): 1; Schicht an Seite einziehen (gs_cavity_side): Beide; Schicht an Seite einziehen (iCavityClosureSide): 1; Einzuziehende Schichten: 1; Schichten von (gs_nTurnDir): Außenseite; Schichten von (iCavityClosureTurnDir): 1; Schichteinzug auf Seite 2: yes; Schichteinzug auf Seite 1: yes; Schichteinzug oben: no; Schichteinzug unten: no; Schichteinzug zu Schicht: 1; Schichteinzug von Seite (gs_cc_dutch_ClosureToSide): 1; Schicht einziehen zu Abschluss: no; Dichtungsband einfügen: yes; Dichtungsband zeigen: yes; Konturlinien-Typ (gs_ltJoint): 1; Schraffur (gs_fillJoint): Nur Hintergrund-Stift; Schraffur-Vordergrundstift (gs_penJointFg): Elemente+Text; Eigenes Oberflächenmaterial: no; Oberflächenmaterial: Holz Esche; Konturlinien-Typ (gs_ltPlug): 1; Schraffur (gs_fillPlug): Nur Hintergrund-Stift; Schraffur-Vordergrundstift (gs_penPlugFg): Elemente+Text; Editierte Anschlagseite: 1; Editierte Wandseite: 1; Schicht Nummer: 1; Schicht einziehen: no; Schicht als Putz ansehen: no; Einzugsdicke: 1; Ausrichtung Schraffur: 1; Trennlinie am Einzug: no; Stift Trennlinie: Elemente+Text; Letzte ausgewählte Seite: no; Abschlussart automatisch verändert: no; Wandbekleidung benutzen: no; automatischer Schichteinzug Putz innen: yes; Putzschicht innen einziehen: 0; automatischer Schichteinzug Putz außen: yes; Putzschicht außen einziehen: 0; Bemaßungsfangpunkte in 2D: no; in 3D zeigen: no; Anschluss Links: no; Anschluss Rechts: no; Anschluss Oben: no; Anschluss Unten: no; Heizkörpernische: no; Heizkörpernischen-Größe (gs_parapet_sizes_st): Automatisch; Heizkörpernischen-Größe (iParapetSize): 1; Automatische Breite und Höhe: yes; Heizkörpernische-UK zu (gs_parapet_bottom_st): Aktuelles Geschoss; Heizkörpernische-UK zu (iParapetBottom): 1; verdeckte Brüstung zeigen: yes; Linientyp verdeckte Brüstung: 1; Sturzbrett: no; Fensterbank innen ist gebogen: yes; Fensterbank in Polygonwänden: 2; 2D-Detaillierungsgrad: 2; Stift Grundriss: Elemente+Text; Linientyp Grundriss: 4; 3D Stift: Elemente+Text; Ansichts-Stift: Elemente+Text; Schnittschraffur (gs_lintelboard_fill): Misch-Schraffur 50 %; Schnittschraffur-Vordergrundstift (gs_lintelboard_pen_fg): Elemente+Text; Sturzbrett Oberflächenmaterial: Farbe, weiß; Sturzsystem: no; Hintersturz: no; autom. Hintersturzhöhe: no; Hinterer Sturz übernimmt Oberflächenmaterial der Wand: yes; Hinterer Sturz Oberflächenmaterial: Farbe, weiß; Hintersturz Schraffur (gs_hsturz_fillType): Nur Vordergrund-Stift; Schnittlinienstift Hintersturz: Konturstift; Typ (iTypeProfiledLintel): 1; Dämmung: no; Sturz übernimmt Oberflächenmaterial der Wand: yes; Sturz Oberflächenmaterial: Farbe, weiß; Schnittlinien Stift: Konturstift; Sturz Schraffur: Dämmung, hart 1; Sturz Schraffur-Vordergrundstift: Elemente+Text; Dämmung Schraffur 1: Dämmung, hart 1; Dämmung Schraffur 2: Dämmung, hart 1; Dämmung Schraffur-Vordergrundstift: Elemente+Text; Fenstereinfassung: no; 2D-Darstellung (bShowMounting2D): yes; Typ Fassung: 2; Falz: no; Pfosten: no; Befestigung Oberflächenmaterial: Fensterrahmen; Konturlinien-Stift: Elemente+Text; Kontur-Stift Sturz vorne: Elemente+Text; Kontur-Stift Sturz hinten: Elemente+Text; Schraffur-Vordergrundstift (gs_pen_sc): Elemente+Text; Schraffur Bedeckung: Nur Vordergrund-Stift; Fensterbank Schraffur: Nur Hintergrund-Stift; Schraffur (efsc2): Holz Schalung liegend, 10cm; Schraffur Sturz vorne: Nur Hintergrund-Stift; Schraffurtyp Dämmung: Dämmung, hart 1; Hintersturz Schraffur (efsc_h): Nur Vordergrund-Stift; Linientyp: 4; Sonnenschutz (bSunshade): no; Sonnenschutz-Typ: 1; Aktivierte Sonnenschutz-Typen: 254; Anzahl Lamellen: 2; Anzahl Paneelen 2: 1; Paneel-Position (gs_shutter_panelPos): Symmetrisch; Paneel-Position (gs_shutter_iPanelPos): 1; Automatische Höhenanpassung: yes; Extra Rahmen: no; Abdeckungstyp (gs_slidingShutter_cover): Z-Profil; Abdeckungstyp (gs_slidingShutter_iCover): 1; Stapelrichtung (gs_foldingShutter_stacking): Innen; Stapelrichtung (gs_foldingShutter_iStacking): 1; in 3D geöffnet: yes; 3D-Öffnungswinkel: 180 deg; 2D-Symbol zeigen: yes; Öffnungslinie im Symbol zeigen: yes; Sonnenschutz-Symbol-Linientyp: 1; Sonnenschutz-Schnittlinien-Stift: Elemente+Text; Sonnenschutz Aufsichtslinien-Stift: Elemente+Text; Sonnenschutz Schnittschraffur: Nur Hintergrund-Stift; Sonnenschutz Schnittschraffur-Vordergrundstift: Elemente+Text; Verschattung Dämmung Schraffur: Dämmung, weich; Verschattung Dämmung Schraffur-Vordergrundstift: Elemente+Text; Verschattung Dämmung Schraffur-Hintergrundstift: Elemente+Text; Fensterladen Oberflächenmaterial: Holz Esche; Fensterladenrahmen Oberflächenmaterial: Holz Esche; Rollladengehäuse Oberflächenmaterial: Metall Chrom; Rollladenlamellen Oberflächenmaterial: Lack schwarz; Rollladen Schiene Oberflächenmaterial: Lack schwarz; Jalousie Oberflächenmaterial: Metall Chrom; Jalousielamellen Oberflächenmaterial: Lack schwarz; Schiebladen Schiene Oberflächenmaterial: Metall Chrom; Paneeltyp (gs_shutPanel_iType): 1; Unterschiedliche Rahmen-Breite unten: no; Automatische Rollladenbreite: yes; Winkel Lamelle: 30 deg; Lochanzahl horizontal: 5; Lochanzahl vertikal: 8; Rollladen-Platzierung (gs_shutRoll_placement): Vor Fassade angebracht; Rollladen-Platzierung (gs_shutRoll_iPlacement): 1; Typ (gs_shutRoll_boxType): Rechteckig; Typ (gs_shutRoll_iBoxType): 1; Handlauf Position (gs_shutRoll_railPos): Auf Verkleidung; Handlauf Position (gs_shutRoll_iRailPos): 1; Verkleidung hinter Sonnenschutz zeigen (gs_shutRoll_showCasingBehind): yes; Wand hinter Kasten schneiden: yes; Höhe in Wandlochhöhe einschließen: no; Neigung Kastendach: 10 deg; Kasten–Breite (gs_shutRoll_boxDefaultSize): Architekturlichte Breite; Kasten–Breite (gs_shutRoll_iBoxDefaultSize): 1; Jalousien-Platzierung (gs_shutLam_placement): Vor Fassade angebracht; Jalousien-Platzierung (gs_shutLam_iPlacement): 1; Dämmung hinter Kasten: no; Geöffnetes Gehäuse: yes; Führungsschienen: yes; Handlauf Position (gs_shutLam_railPos): Auf Verkleidung; Handlauf Position (gs_shutLam_iRailPos): 1; Verkleidung hinter Sonnenschutz zeigen (gs_shutLam_showCasingBehind): yes; Kippwinkel (gs_shutLam_rotation): 45 deg; Kippwinkel (gs_shutLam2_rotation): 45 deg; seitliche Wandkontur (gs_wallcontour): Beide; seitliche Wandkontur (gs_wallcontour_id): 1; Wandkontur (gs_wcont_line): beide Seiten; Wandkontur (iWallContourLine): 4; Automatische Einstellungen: yes; Wandkonturlinie innen - 1:50 und tiefer: yes; Wandkonturlinie innen - 1:100 und höher: yes; Wandkonturlinien Typ innen - 1:100 und höher: 1; Wandkonturlinie außen - 1:50 und tiefer: yes; Wandkonturlinie außen - 1:100 und höher: yes; Wandkonturlinien Typ außen - 1:50 and tiefer: 4; Wandkonturlinien Typ außen - 1:100 und höher: 1; Wandkonturlinien Stift - 1:50 und tiefer: Elemente+Text; Wandkonturlinien Stift - 1:100 und höher: Elemente+Text; Konstruktionstyp: 8; Fensterrahmen Oberflächenmaterial außen: Fensterrahmen; Fensterrahmen Oberflächenmaterial innen: Fensterrahmen; Flügelrahmen Oberflächenmaterial außen: Fensterrahmen; Flügelrahmen Oberflächenmaterial innen: Fensterrahmen; Mittelpfosten - Außenfläche: Fensterrahmen; Mittelpfosten - Innenfläche: Fensterrahmen; Verglasung -Oberflächenmaterial: Glas Normalglas; Einheitliche Oberflächen Verkleidung: yes; Rahmen und Flügel - 3D und Aufsichtslinien-Stift: Schichttrennlinien/Kontur; Rahmen Schnittlinienstift: Schichttrennlinien/Kontur; Rahmen Schnittschraffur: Nur Hintergrund-Stift; Flügelrahmen-Stift: Schichttrennlinien/Kontur; Glas - 3D und Aufsichtslinien-Stift: Schichttrennlinien/Kontur; Glas Linienstift Kontur: Schichttrennlinien/Kontur; Glas Schnittschraffur: Nur Hintergrund-Stift; Rahmen Deckschraffur: Nur Hintergrund-Stift; Wandschraffur in der Öffnung: yes; Schraffur (gs_wallhole_fill): Nur Hintergrund-Stift; Schraffur-Vordergrundstift (gs_wallhole_pen_fg): Elemente+Text; Fensterbank Hintergrundschraffur: yes; Schraffur-Vordergrundstift (gs_sill_wallhole_pen_fg): Elemente+Text; Fensterbank Innen Hintergrundschraffur: no; Schraffur-Vordergrundstift (gs_board_wallhole_pen_fg): Elemente+Text; Zeige nur die Grundriss Info: yes; Grundriss Info: 3; Texteinstellung (gs_PlanViewInfos_scaleValues): Maßstababhängig (Modellgröße); Massstab (gs_PlanViewInfos_scaleValues_m): 2; Text Anschlag 1: yes; Text (gs_textll): RAF; Absatz horizontal (mm) (gs_PlanViewInfos_T1_xOffsetMM): 3; Absatz vertikal (mm) (gs_PlanViewInfos_T1_yOffsetMM): 2; Text drehen (gs_dr1): no; Text Anschlag 2: yes; Text (gs_textlr): FB; Absatz horizontal (mm) (gs_PlanViewInfos_T2_xOffsetMM): -1; Absatz vertikal (mm) (gs_PlanViewInfos_T2_yOffsetMM): 2; Text drehen (gs_dr2): no; Text Drehkippflügel: yes; Text (gs_textdrehkipp): DK; Text Drehkippflügel gespiegelt: yes; Absatz horizontal (mm) (gs_PlanViewInfos_T3_xOffsetMM): -1; Absatz vertikal (mm) (gs_PlanViewInfos_T3_yOffsetMM): 0; Text drehen (gs_dr3): no; Text Kurbel: yes; Text (gs_textkurbel): K; Text Kurbel gespiegelt: yes; Absatz horizontal (mm) (gs_PlanViewInfos_T4_xOffsetMM): 1; Absatz vertikal (mm) (gs_PlanViewInfos_T4_yOffsetMM): 0; Text drehen (gs_dr4): no; Text Elektro-Kurbel 2: no; Text (gs_PlanViewInfos_T5_customText): O; Absatz horizontal (mm) (gs_PlanViewInfos_T5_xOffsetMM): 0; Absatz vertikal (mm) (gs_PlanViewInfos_T5_yOffsetMM): -3; Text gespiegelt (gs_PlanViewInfos_T5_Mirrored): yes; Text drehen (gs_PlanViewInfos_T5_Rotate): no; Text Kurbel individuell: no; Text (gs_PlanViewInfos_T6_customText): Fest; Absatz horizontal (mm) (gs_PlanViewInfos_T6_xOffsetMM): 3; Absatz vertikal (mm) (gs_PlanViewInfos_T6_yOffsetMM): -3; Text gespiegelt (gs_PlanViewInfos_T6_Mirrored): yes; Text drehen (gs_PlanViewInfos_T6_Rotate): no; Schrifttyp (gs_zsgri): Arial; Schriftgröße (mm): 1.5; Text-Stift (gs_pengri): Elemente+Text; Stift Kurbel: Elemente+Text; Fensterkoten: yes; Sichtbarkeit Fensterbemaßung (gs_etikett): Modelldarstellungs-Optionen; Sichtbarkeit Fensterbemaßung (iEtikett): 3; Öffnung roh: 1; Text Öffnung roh: Öffnung roh; Sturz fertig: 1; Text Fertig Sturz: Sturz fertig; Brüstung fertig: 1; Text Brüstung fertig: Br. fertig; Platz für Fußboden: no; Brüstung roh: 1; Text Brüstung roh: Rohbrüstung Höhe; Texteinstellung (gs_Etikett_scaleValues): Maßstababhängig (Modellgröße); Massstab (gs_Etikett_scaleValues_m): 2; Schrifttyp (fontType): Arial; Schriftgröße (papier) (gs_Etikett_fontSize_mm): 1.5; Dimension Stift Text: Elemente+Text; X Position (m): 0; Position X (mm): 0; Y Position (m): 0; Position Y (mm): 8; Automat. Zeilenabstand: no; Zeilenabstand (papier): 1; Drehwinkel: 0 deg; Fenster-Befestigungstyp: 1; Zeige die ID im Grundriss: no; Beschriftung Fenstertyp: 1; autom. Fenster ID Nummer: yes; Eigener Text: Eigene ID; Marker spiegeln: yes; Zusätzliche Werte zeigen (Öffnungsmass 1.20/1.50): yes; Text Position X (mm): 0; Text Position Y (mm): 8; Texteinstellung (gs_IDText_scaleValues): Maßstababhängig (Modellgröße); Massstab (gs_IDText_scaleValues_m): 2; Schriftgröße (papier) (gs_IDText_fontSize_mm): 5; Schrifttyp (gs_IDText_fontType): Arial; Text-Stift (gs_IDText_fontPen): Elemente+Text; Darstellung als Oberlicht: no; Stift Wandendlinie: Elemente+Text; Linientyp Wandendlinie: 4; Sturztiefe im Grundriss zeigen: no; Sturztiefe Symbolstift: Konturstift; Typ Links: 0; Typ Rechts: 0; Automatische Maße: yes; Einbaurahmen Konturstift (gs_TolerBlin_contour_pen): Elemente+Text; Einbaurahmen Konturlinientyp: 1; Einbaurahmen Schraffur (gs_TolerBlin_fill_type): Nur Hintergrund-Stift; Einbaurahmen Schraffur-Vordergrundstift (gs_TolerBlin_fg_pen): Schichttrennlinien/Kontur; Schraffur-Stift Fugenausfüllung: Elemente+Text; Linientyp Kontur Fugenausfüllung: 1; Fugenausfüllung Schraffur: Nur Hintergrund-Stift; Fugenausfüllung Schraffur-Vordergrundstift: Schichttrennlinien/Kontur; IFC Betrieb (ifc_optypestr): Simpel; IFC Betrieb (ifc_optype): 1; Aussparung Flügelrahmen unten in Kämpferfeld: yes; Anzeige-Standards Code - 2:GER, 3:CHE, 4:AUT: 2; Preis: 0; Komplette Glasfläche: 0; Umfang der Glasfläche: 0; Selbstschließend: no; Selbstschließend Index: 2; Gruppe Typ (FM_Type): Fenster; Gruppe Typ (iFMType): 999; Objektgewicht: 0; Objektgewichtseinheit: kg; Fenster Ausrichtung Definition: 0; Breite Wert: Außen Anschlag Maß; Höhe Wert: Höhe Fensterlaibung
Brandschutz 4102-2 - Kennbuchstabe: F
ArchiCADQuantities - Wanddicke: 0.375 m; Rahmen-Stärke: 0.07 m
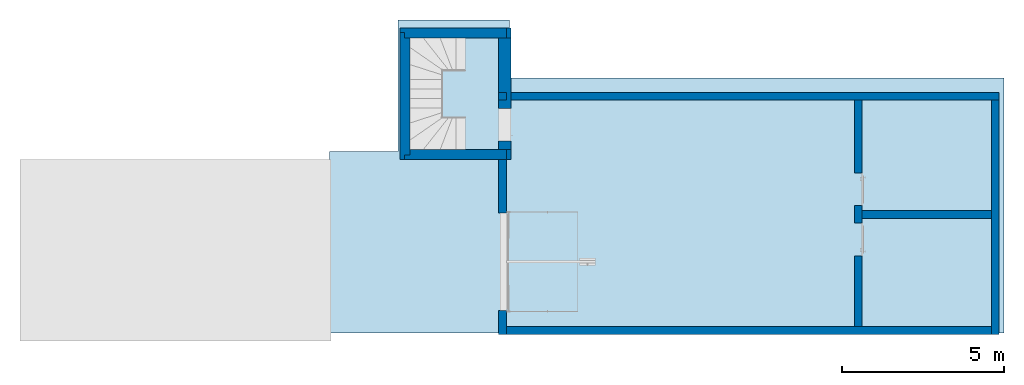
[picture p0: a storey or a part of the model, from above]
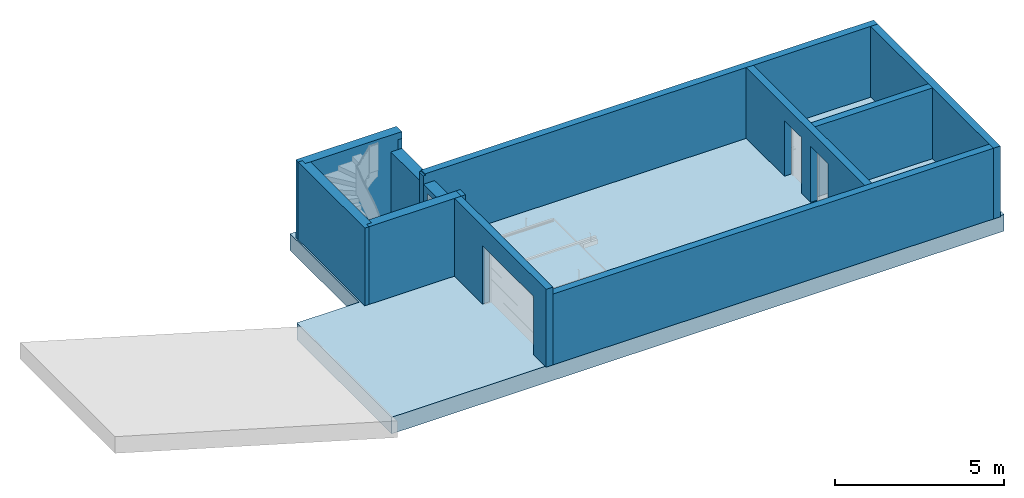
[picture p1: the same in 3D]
Properties of the parts of a building model (IFC4), part 5 of 13

# IfcBuildingElementProxy: 1-Flügelfenster 22 (19)
AC_Equantity_1-Flügelfenster_22 - Z Größe: 1 m; Untere Ebene: 1 m; Obere Ebene: 0 m; Anschließende Wanddicke: 0.3 m; Verbundene Wand Dicke 2: 0.375 m; Verbundene Wand Dicke 1: 0.375 m; Breite Eck-Profil: 0 m; Stärke Eck-Profil: 0.06 m; Versatz Eck-Profil: 0 m; Einbautoleranz links: 0 m; Einbautoleranz rechts: 0 m; Einbautoleranz oben: 0 m; Einbautoleranz unten: 0 m; Toleranz außen links: 0 m; Toleranz innen links: 0 m; Toleranz außen rechts: 0 m; Toleranz innen rechts: 0 m; Toleranz außen oben: 0 m; Toleranz innen oben: 0 m; Toleranz außen unten: 0 m; Toleranz innen unten: 0 m; Höhe Hauptflügel: 0.3 m; Rahmen-Breite: 0.08 m; Rahmen-Stärke 1:100: 0.05 m; Breite rechts: 0.08 m; Breite links: 0.08 m; Breite Oben (gs_stb_ob): 0.08 m; Breite Unten (gs_stb_u): 0.08 m; Rahmen-Stärke: 0.07 m; Flügelrahmen-Breite: 0.08 m; Breite Oben (gs_rab_ob): 0.08 m; Breite Unten (gs_rab_u): 0.08 m; Flügelrahmen-Stärke: 0.07 m; Falzbreite: 0.02 m; Falztiefe: 0.04 m; Glasstärke: 0.02 m; Gitter Breite: 0.025 m; Gitter Stärke: 0.025 m; Querbalken oben Breite: 0.02 m; Breite Seite 1 (gs_tw_right_out): 0.1 m; Breite Seite 2 (gs_tw_left_out): 0.1 m; Breite oben (gs_tw_top_out): 0.1 m; Breite unten (gs_tw_bottom_out): 0.1 m; Stärke an Wand (gs_trim_thk_out): 0.025 m; Stärke in Wandloch (gs_trim_width_out): 0.025 m; Abstand (gs_trim_offs_out): 0 m; Auskragung (gs_trim_jambext_nosing_out): 0.05 m; Oberer Überstand (gs_trimov_top_right_out): 0.1 m; Erweiterung unten (gs_trimov_bot_right_out): 0.1 m; Erweiterung unten (casingOverhangBottomSideOut): 0.05 m; Breite Seite 1 (gs_tw_right_in): 0.1 m; Breite Seite 2 (gs_tw_left_in): 0.1 m; Breite oben (gs_tw_top_in): 0.1 m; Breite unten (gs_tw_bottom_in): 0.1 m; Stärke an Wand (gs_trim_thk_in): 0.025 m; Stärke in Wandloch (gs_trim_width_in): 0.025 m; Abstand (gs_trim_offs_in): 0 m; Auskragung (gs_trim_jambext_nosing_in): 0.03 m; Oberer Überstand (gs_trimov_top_right_in): 0.1 m; Erweiterung unten (gs_trimov_bot_right_in): 0.1 m; Fensterbank Stärke (gs_sill_thk): 0.05 m; Stärke Fensterbank vorne: 0.03 m; Fensterbank Ansicht: 0 m; Stärke Fensterbankkante: 0.03 m; Fensterbank Überstand: 0.03 m; Fensterbank Stärke (gs_sill_element_thk): 0.02 m; Überhang Fensterbank Links: 0 m; Überhang Fensterbank Rechts: 0 m; Falztiefe Fensterbank: 0 m; Hintere Lochtiefe (gs_sill_holeDepthBehind): 0 m; Fensterbank obere Breite: 0.01 m; Fensterbank obere Höhe: 0.01 m; Steinbreite (gs_brick_sill_br_thk): 0.065 m; Fugenbreite (gs_brick_sill_mort_thk): 0.015 m; Stärke Fensterbank Innen: 0.025 m; Überstand Fensterbank Innen: 0.03 m; Überhang Fensterbank Innen Links: 0.03 m; Überhang Fensterbank Innen Rechts: 0.03 m; Brett Falztiefe: 0 m; Abstand zwischen Bogen und Fenster: 0 m; Sturz Überhang links: 0 m; Sturz Überhang rechts: 0 m; Sturz Bogenhöhe: 0.03 m; Projektion Sturz: 0 m; Höhe Sichtmauerwerk: 0.24 m; Tiefe Sichtmauerwerk: 0.15 m; Hintere Lochtiefe (gs_masonry_arch_rearHoleDepth): 0 m; Steinbreite (gs_masonry_arch_brick_thk): 0.065 m; Fugenbreite (gs_masonry_arch_mort_thk): 0.01 m; Keilsteinbreite: 0.1 m; Überhang Keilstein: 0 m; Projektion Keilstein: 0.01 m; Breite Links/Rechts: 0.12 m; Höhe oben: 0.25 m; Höhe unten: 0.25 m; Höhe Faschen rechts: 1.5 m; Höhe Faschen links: 1.5 m; Tiefe Faschen: 0.165 m; Steinbreite (gs_faschen_brick_thk): 0.065 m; Fugenbreite (gs_faschen_mort_thk): 0.01 m; Anschlagstiefe Seite 2: 0.05 m; Anschlagstiefe: 0.05 m; Innerer Anschlagstiefe Seite 2 (gs_reveal_splayed_innerLeft): 0.06 m; Innerer Anschlagstiefe (gs_reveal_splayed_innerRight): 0.06 m; Innerer Anschlagstiefe Seite 2 (gs_reveal_double_innerLeft): 0.06 m; Innerer Anschlagstiefe (gs_reveal_double_innerRight): 0.06 m; Tiefe des oberen Anschlags: 0.05 m; Tiefe des unteren Anschlags: 0.06 m; Tiefe Sturz Innen (gs_reveal_splayed_innerTop): 0.06 m; Tiefe Laibung Innen (gs_reveal_splayed_innerBottom): 0.06 m; Tiefe Sturz Innen (gs_reveal_double_innerTop): 0.06 m; Tiefe Laibung Innen (gs_reveal_double_innerBottom): 0 m; Tiefe äußerer Anschlag: 0.05 m; Seitenabschrägung Breite Seite 2: -1 m; Seitenabschrägung Breite Seite: -1 m; Obere Seitenabschrägung Breite: -1 m; Untere Seitenabschrägung Breite: -1 m; Außenabschrägung Breite Seite 2: -1 m; Außenabschrägung Breite Side: -1 m; Äußere Abschrägung Breite an oberer Seite: -1 m; Breite äußere Abschrägung an Unterseite: -1 m; Einbaurahmen-Stärke: 0.06 m; Einbaurahmen-Breite links: 0.06 m; Einbaurahmen-Breite rechts: 0.06 m; Einbaurahmen-Breite oben: 0.06 m; Einbaurahmen-Breite unten: 0.06 m; Abstand Schicht zu Abschluss: 0 m; Anschluss Breite: 0.038 m; Anschluss Stärke: 0.1 m; Streifen-Stärke: 0.025 m; Profilbreite: 0.075 m; Eigene Stärke: 0.015 m; Schichtüberlappung zu Rahmen-Tiefe: 0 m; Max. Putzdicke: 0.04 m; Tiefe Heizk.: 0.05 m; Breite Heizkörpernische: 1 m; Überstand Seite 1: 0 m; Überstand Seite 2: 0 m; Höhe Heizkörpernische: 0.9 m; Erweiterung unten (gs_parapet_botelev): 0 m; Sturzbrett Stärke: 0.025 m; Sturzbrett Überstand: 0.03 m; Verkleidungsbreite Links: 0 m; Verkleidungsbreite Rechts: 0 m; Verkleidungsstärke: 0.12 m; Höhe Hintersturz (gs_hsturz_height): 0.08 m; Höhe Hintersturz (gs_hhs): 0.2 m; Stärke vorne: 0.06 m; Tiefe von Wandebene: 0 m; Stärke Dämmung 1: 0.03 m; Stärke Dämmung 2: 0.03 m; Vorstand v. Fenster: 0 m; Stärke Metalplatte: 0.005 m; Breite: 0.07 m; Breite oben (efb_t1): 0.3 m; Stärke oben: 0.09 m; Breite Sturz außen: 0.06 m; Breite unten (efsu): 0.07 m; Fensterbank Breite: 0.07 m; Vorstand v. Fassade: 0.025 m; Vorstand v. Fassade Fensterbank: 0.05 m; Paneelhöhe: 1.5 m; Innerer Versatz: 0.02 m; Schließtiefe: 0 m; Extra Rahmen Breite: 0.04 m; Extra Rahmen Stärke: 0.03 m; Geländerbreite: 0.03 m; Türzapfen-Länge: 0.02 m; Türzapfen-Radius: 0.005 m; Paneel-Abstand: 0.006 m; Außen-Überhang: 0 m; Innere Paneel-Breite: 0.12 m; 3D-Öffnungslänge: 1.5 m; 3D geschlossene Länge: 0 m; 3D-Öffnungslänge 1 (gs_shutter_opLength_1): 0.56 m; 3D-Öffnungslänge 1 (gs_shutter_opLength_2): 0.14 m; 3D-Öffnungshöhe: 1.5 m; 3D geschlossene Höhe: 0 m; Paneeldicke: 0.05 m; Paneelrahmen-Breite: 0.05 m; Rahmen-Breite unten: 0.05 m; Paneel Breite: 0 m; Paneelfüllungs-Stärke: 0.01 m; Stärke Lamelle: 0.01 m; Breite Lamellen: 0.04 m; Horizontaler Rahmen Teiler-Breite: 0.05 m; Vertikaler Rahmen Teiler-Breite: 0.05 m; Durchmesser Öffnung: 0.01 m; Breite des vertikalen Bretts: 0.1 m; Z-Rahmen-Breite: 0.05 m; Z-Rahmen-Stärke: 0.025 m; Stärke der vertikalen Bretter: 0.025 m; Stärke der horizontalen Bretter: 0.025 m; Ungefähre Breite der vertikalen Bretter (gs_shutPanel_vertBoardW): 0.08 m; Ungefähre Breite der vertikalen Bretter (gs_shutPanel_horBoardW): 0.115 m; Kasten Höhe (gs_shutRoll_boxHeight): 0.2 m; Kasten Tiefe: 0.15 m; Kasten Abstand links: 0 m; Kasten Abstand recht: 0 m; Tiefe Schiene: 0.0725 m; Abstand von Wand: 0 m; Abstand oben (gs_shutRoll_distFromHead): 0 m; Rollladen-Lamellen-Höhe: 0.05 m; Kasten Höhe (gs_shutLam_boxHeight): 0.2 m; Kasten-Breite (gs_shutLam_boxWidth): 0.15 m; Abdeckungstiefe: 0.04 m; Vorstand v. Wand: 0 m; Abstand oben (gs_shutLam_distFromHead): -0.2 m; Breite einer Rollade (gs_shutLam_segmentWidth): 0.06 m; Kasten Höhe (gs_shutLam2_boxHeight): 0.06 m; Kasten-Breite (gs_shutLam2_boxWidth): 0.06 m; Abst. v. Fenster: 0.06 m; Abstand oben (gs_shutLam2_distFromHead): 0.06 m; Kasten-Achshöhe von OK: 0 m; Breite einer Rollade (gs_shutLam2_segmentWidth): 0.06 m; Horizontaler Vorsprung (gs_ah1): 0.05 m; Vertikaler Abstand (gs_av1): 0.045 m; Horizontaler Vorsprung (gs_ah2): -0.05 m; Vertikaler Abstand (gs_av2): 0.045 m; Horizontaler Vorsprung (gs_ah3): -0.05 m; Vertikaler Abstand (gs_av3): 0 m; Horizontaler Vorsprung (gs_ah4): 0.05 m; Vertikaler Abstand (gs_av4): 0 m; Horizontaler Vorsprung (gs_PlanViewInfos_T5_xOffset): 0 m; Vertikaler Abstand (gs_PlanViewInfos_T5_yOffset): -0.15 m; Horizontaler Vorsprung (gs_PlanViewInfos_T6_xOffset): 0.15 m; Vertikaler Abstand (gs_PlanViewInfos_T6_yOffset): -0.15 m; Schriftgröße (modell) (gs_sggri): 0.075 m; Eigene Kote Öffnung roh: 0 m; Eigene Kote Sturz fertig: 0 m; Eigene Koten Brüstung fertig: 0 m; Höhe Fußboden: 0.05 m; Eigene Koten Brüstung roh: 0 m; Schriftgröße (modell) (gs_lsize): 0.075 m; Position X: 0 m; Position Y: 0.4 m; Zeilenabstand (modell): 0.05 m; Feste breite in mm (0= autom.): 0 m; Text Position X: 0 m; Text Position Y: 0.4 m; Schriftgröße (modell) (gs_IDText_fontSize_model): 0.1 m; Position Links: 0 m; Position Rechts: 0 m; Breite Links: 0 m; Breite Rechts: 0 m; Tiefe Links: 0.01 m; Tiefe Rechts: 0.01 m; AC Linkes Öffnungsübermaß: 0 m; AC Rechtes Öffnungsübermaß: 0 m; AC Oberes Öffnungsübermaß: 0 m; AC Unteres Öffnungsübermaß: 0 m
Name | In | FireResistanceRating | Element ID = Hotlink und Element-ID | Kollidierende Räume | Zugehöriger Raumname = zu Raum | Zugehörige Raumnummer = Zu Raum-Nummer | Ursprungsgeschoss Name | Ursprungsgeschoss Nummer | Überobjekt-ID | Oberfläche (Alle) | Von Raum | Von Raum-Nummer | Lage | Anschlagsmaße = Größe Wandloch = Größe laut Eingabe = Nominale B x H | Nominale B x H x T | Ausrichtung = Fenster Ausrichtung = Öffnungsrichtung | 2D-Fixpunkte in 3D zeigen = Fensterbank Innen = Fenster gehört zum Raum, in den es öffnet | Wandrichtungstyp | Laibung Ankerposition | Öffnungstyp Hauptflügel | Öffnungslinien-Form (or_SlidingType) | Gehäuseunterseite außen | Typ Fensterbank | Außenkante | Fensterbank Oberflächenmaterial | Fensterbrett Oberflächenmaterial | Wärmedämmung Oberflächenmaterial | Paneeltyp (gs_shutPanel_type) | Wandkonturlinien Typ innen - 1:50 und tiefer | Rahmen Schraffur | Sturztiefe Symbol- Linientyp | AC_Pset_1-Flügelfenster_22, Breite | AC_Pset_1-Flügelfenster_22, Höhe | Wert ID Nummer | ID-Nummer | zu Raum ID innen Wert = zu Raum ID außen Wert | zu Raum ID innen | zu Raum ID außen | Fenster/Türnummer | ArchiCADQuantities, Höhe (m) = F/T Höhe der Öffnung auf der Anschlagseite (m) = F/T Höhe der Öffnung gegenüber der Anschlagseite (m) = Nominale F/T Höhe der Öffnung auf der Anschlagseite (m) = Nominale F/T Höhe der Öffnung gegenüber der Anschlagseite (m) = NominaleHöhe (m) = Rohbauöffnung Höhe (m) = Architekturlichte Höhe (m) = Rahmen Höhe (m) = Höhe Baurichtmaß (m) = Fenster/Türhöhe (m) | Netto-Volumen (m3) | ArchiCADQuantities, Breite (m) = F/T Öffnungsbreite auf der Anschlagseite (m) = F/T Öffnungsbreite gegenüber der Anschlagseite (m) = Nominale F/T Öffnungsbreite auf der Anschlagseite (m) = Nominale F/T Öffnungsbreite gegenüber der Anschlagseite (m) = NominaleBreite (m) = Rohbauöffnung Breite (m) = Architekturlichte Breite (m) = Rahmen Breite (m) = Breite Baurichtmaß (m) = Fenster/Türbreite (m) | Höhenangabe zum Projekt-Nullpunkt (m) = Höhe zu 1. Referenzhöhe (m) = Höhe zu 2. Referenzhöhe (m) | Höhe zu Meereshöhe (m) | Höhe zu verknüpftem/Ursprungsgeschoss (m) = Abstand zu Ursprungsgeschoss (m) = Brüstungshöhe zum aktuellen Geschoss (m) | Oberflächenbereich (m2) = F/T Oberfläche der Öffnung (m2) | F/T Volumen der Öffnung (m3) = F/T nominales Volumen der Öffnung (m3) | F/T Öffnung Nominaler Oberflächenbereich (m2) = F/T Oberfläche der Öffnung auf der Anschlagseite (m2) = F/T Oberfläche der Öffnung gegenüber der Anschlagseite (m2) = Nominale F/T Öffnungsoberfläche auf der Anschlagsseite (m2) = Nominale F/T Öffnungsoberfläche auf der Seite gegenüber der Anschlagsseite (m2) | Brüstungshöhe (m) = F/T nominale Brüstungs-/Schwellenhöhe (m) | F/T Brüstungs-/Schwellenhöhe auf der Anschlagseite (m) = F/T Brüstungs-/Schwellenhöhe gegenüber der Anschlagseite (m) | F/T nominale Sturzhöhe (m) | F/T Sturzhöhe auf der Anschlagseite (m) = F/T Sturzhöhe gegenüber der Anschlagseite (m) | Laibung zum Wandkern (m) | Höhe Kämpfer (m) | Überlappungshöhe Fensterbank (m) | Breite Fensterbank (m) | Rahmenbreite (m) | Anschlagtiefe (gs_wido_sill) (m) = Anschlagtiefe (AC_wido_sill) (m)
Fenster-007 | EG | F30 | Fenster-007 | Erdgeschoss; Grundfläche Gebäude Nachgezogen; Wohnung1 EG | Wohnen | R-006 | EG | 0 | Wand-004 | Glas Normalglas; Metall Stahl, verzinkt; Farbe, weiß; Fensterrahmen | Grundfläche Gebäude Nachgezogen | 000 | Nicht definiert | 1,010×1,800 | 1,010×1,800×0,375 | R | yes | 1 | 2 | 5 | Kein | no | 11 | Lotrecht | Metall Stahl, verzinkt | Farbe, weiß | Metall, Fassade Edelstahl | Typ 1 | 4 | Nur Hintergrund-Stift | 4 | 101,00 | 180,00 | 1 | Fenster-007 | Automatisch | 000 | R-006 | EG-R-006-Fenster-007 | 1.8 | 0.0686907 | 1.01 | 0.8 | 16.8 | 0.8 | 6.61808 | 0.68175 | 1.818 | 0.8 | 0.7 | 2.6 | 2.5 | 0 | 1.05 | 0.02 | 0.21 | 0.155 | 0.18 | Türen/Fenster - Schallschutzklasse: SK 3
Fenster-008 | EG |  | Fenster-008 | Erdgeschoss; Grundfläche Gebäude Nachgezogen; Wohnung1 EG | Wohnen | R-006 | EG | 0 | Wand-004 | Glas Normalglas; Metall Stahl, verzinkt; Farbe, weiß; Fensterrahmen | Grundfläche Gebäude Nachgezogen | 000 | Nicht definiert | 1,010×2,400 | 1,010×2,400×0,375 | R | yes | 1 | 2 | 5 | Kein | no | 11 | Lotrecht | Metall Stahl, verzinkt | Farbe, weiß | Metall, Fassade Edelstahl | Typ 1 | 4 | Nur Hintergrund-Stift | 4 | 101,00 | 240,00 | 1 | Fenster-008 | Automatisch | 000 | R-006 | EG-R-006-Fenster-008 | 2.4 | 0.0857907 | 1.01 | 0.2 | 16.2 | 0.2 | 8.37008 | 0.909 | 2.424 | 0.2 | 0.1 | 2.6 | 2.5 | 0 | 1.05 | 0.02 | 0.21 | 0.155 | 0.18 | Türen/Fenster - Schallschutzklasse: SK 3
Fenster-009 | EG |  | Fenster-009 | Erdgeschoss; Grundfläche Gebäude Nachgezogen; Wohnung1 EG | Wohnen | R-006 | EG | 0 | Wand-004 | Glas Normalglas; Metall Stahl, verzinkt; Farbe, weiß; Fensterrahmen | Grundfläche Gebäude Nachgezogen | 000 | Außen | 1,010×2,400 | 1,010×2,400×0,375 | L | yes | 1 | 2 | 5 | Kein | no | 11 | Lotrecht | Metall Stahl, verzinkt | Farbe, weiß | Metall, Fassade Edelstahl | Typ 1 | 4 | Nur Hintergrund-Stift | 4 | 101,00 | 240,00 | 1 | Fenster-009 | Automatisch | 000 | R-006 | EG-R-006-Fenster-009 | 2.4 | 0.0857907 | 1.01 | 0.2 | 16.2 | 0.2 | 8.37008 | 0.909 | 2.424 | 0.2 | 0.1 | 2.6 | 2.5 | 0 | 1.05 | 0.02 | 0.21 | 0.155 | 0.18 | Türen/Fenster - Schallschutzklasse: SK 3
Fenster-011 | EG |  | Fenster-011 | Erdgeschoss; Grundfläche Gebäude Nachgezogen; Wohnung1 EG | Wohnen | R-006 | EG | 0 | Wand-005 | Glas Normalglas; Metall Stahl, verzinkt; Farbe, weiß; Fensterrahmen | Wohnung1 EG | R-021 | Nicht definiert | 1,010×2,400 | 1,010×2,400×0,375 | R | yes | 1 | 1 | 5 | Kein | no | 11 | Lotrecht | Metall Stahl, verzinkt | Farbe, weiß | Metall, Fassade Edelstahl | Typ 1 | 4 | Nur Hintergrund-Stift | 4 | 101,00 | 240,00 | 1 | Fenster-011 | Automatisch | R-021 | R-006 | EG-R-006-Fenster-011 | 2.4 | 0.0857907 | 1.01 | 0.2 | 16.2 | 0.2 | 8.37008 | 0.909 | 2.424 | 0.2 | 0.1 | 2.6 | 2.5 | 0.18 | 1.05 | 0.02 | 0.21 | 0.155 | 0.18 | Türen/Fenster - Schallschutzklasse: SK 3
Fenster-012 | EG |  | Fenster-012 | Erdgeschoss; Grundfläche Gebäude Nachgezogen; Wohnung1 EG | Wohnen | R-005 | EG | 0 | Wand-005 | Glas Normalglas; Metall Stahl, verzinkt; Farbe, weiß; Fensterrahmen | Wohnung1 EG | R-021 | Nicht definiert | 1,010×2,400 | 1,010×2,400×0,375 | R | yes | 1 | 1 | 5 | Kein | no | 11 | Lotrecht | Metall Stahl, verzinkt | Farbe, weiß | Metall, Fassade Edelstahl | Typ 1 | 4 | Nur Hintergrund-Stift | 4 | 101,00 | 240,00 | 1 | Fenster-012 | Automatisch | R-021 | R-005 | EG-R-005-Fenster-012 | 2.4 | 0.0857907 | 1.01 | 0.2 | 16.2 | 0.2 | 8.37008 | 0.909 | 2.424 | 0.2 | 0.1 | 2.6 | 2.5 | 0.18 | 1.05 | 0.02 | 0.21 | 0.155 | 0.18 | Türen/Fenster - Schallschutzklasse: SK 3
Fenster-013 | EG |  | Fenster-013 | Erdgeschoss; Grundfläche Gebäude Nachgezogen; Wohnung1 EG | Wohnen | R-005 | EG | 0 | Wand-005 | Glas Normalglas; Metall Stahl, verzinkt; Farbe, weiß; Fensterrahmen | Wohnung1 EG | R-021 | Nicht definiert | 1,010×2,400 | 1,010×2,400×0,375 | R | yes | 1 | 1 | 5 | Kein | no | 11 | Lotrecht | Metall Stahl, verzinkt | Farbe, weiß | Metall, Fassade Edelstahl | Typ 1 | 4 | Nur Hintergrund-Stift | 4 | 101,00 | 240,00 | 1 | Fenster-013 | Automatisch | R-021 | R-005 | EG-R-005-Fenster-013 | 2.4 | 0.0857907 | 1.01 | 0.2 | 16.2 | 0.2 | 8.37008 | 0.909 | 2.424 | 0.2 | 0.1 | 2.6 | 2.5 | 0.18 | 1.05 | 0.02 | 0.21 | 0.155 | 0.18 | Türen/Fenster - Schallschutzklasse: SK 3
Fenster-014 | EG |  | Fenster-014 | Erdgeschoss; Grundfläche Gebäude Nachgezogen; Wohnung1 EG | Wohnen | R-005 | EG | 0 | Wand-005 | Glas Normalglas; Metall Stahl, verzinkt; Farbe, weiß; Fensterrahmen | Wohnung1 EG | R-021 | Außen | 1,010×2,400 | 1,010×2,400×0,375 | L | yes | 1 | 1 | 5 | Kein | no | 11 | Lotrecht | Metall Stahl, verzinkt | Farbe, weiß | Metall, Fassade Edelstahl | Typ 1 | 4 | Nur Hintergrund-Stift | 4 | 101,00 | 240,00 | 1 | Fenster-014 | Automatisch | R-021 | R-005 | EG-R-005-Fenster-014 | 2.4 | 0.0857907 | 1.01 | 0.2 | 16.2 | 0.2 | 8.37008 | 0.909 | 2.424 | 0.2 | 0.1 | 2.6 | 2.5 | 0.18 | 1.05 | 0.02 | 0.21 | 0.155 | 0.18 | Türen/Fenster - Schallschutzklasse: SK 3
Fenster-005 | EG | F30 | Fenster-005 | Erdgeschoss; Grundfläche Gebäude Nachgezogen; Wohnung2 EG | Wohnen | R-009 | EG | 0 | Wand-008 | Glas Normalglas; Metall Stahl, verzinkt; Farbe, weiß; Fensterrahmen | Wohnung2 EG | R-020 | Nicht definiert | 1,010×2,400 | 1,010×2,400×0,375 | R | yes | 0 | 2 | 5 | Kein | no | 11 | Lotrecht | Metall Stahl, verzinkt | Farbe, weiß | Metall, Fassade Edelstahl | Typ 1 | 4 | Nur Hintergrund-Stift | 4 | 101,00 | 240,00 | 1 | Fenster-005 | Automatisch | R-020 | R-009 | EG-R-009-Fenster-005 | 2.4 | 0.0857907 | 1.01 | 0.2 | 16.2 | 0.2 | 8.37008 | 0.909 | 2.424 | 0.2 | 0.1 | 2.6 | 2.5 | 0 | 1.05 | 0.02 | 0.21 | 0.155 | 0.18
Fenster-006 | EG | F30 | Fenster-006 | Erdgeschoss; Grundfläche Gebäude Nachgezogen; Wohnung2 EG | Wohnen | R-009 | EG | 0 | Wand-008 | Glas Normalglas; Metall Stahl, verzinkt; Farbe, weiß; Fensterrahmen | Wohnung2 EG | R-020 | Nicht definiert | 1,010×1,800 | 1,010×1,800×0,375 | R | yes | 0 | 2 | 5 | Kein | no | 11 | Lotrecht | Metall Stahl, verzinkt | Farbe, weiß | Metall, Fassade Edelstahl | Typ 1 | 4 | Nur Hintergrund-Stift | 4 | 101,00 | 180,00 | 1 | Fenster-006 | Automatisch | R-020 | R-009 | EG-R-009-Fenster-006 | 1.8 | 0.0686907 | 1.01 | 0.8 | 16.8 | 0.8 | 6.61808 | 0.68175 | 1.818 | 0.8 | 0.7 | 2.6 | 2.5 | 0 | 1.05 | 0.02 | 0.21 | 0.155 | 0.18
Fenster-015 | EG | F30 | Fenster-015 | Erdgeschoss; Grundfläche Gebäude Nachgezogen; Wohnung2 EG | Wohnen | R-009 | EG | 0 | Wand-009 | Glas Normalglas; Metall Stahl, verzinkt; Farbe, weiß; Fensterrahmen | Wohnung2 EG | R-020 | Nicht definiert | 1,010×2,400 | 1,010×2,400×0,375 | R | yes | 0 | 2 | 5 | Kein | no | 11 | Lotrecht | Metall Stahl, verzinkt | Farbe, weiß | Metall, Fassade Edelstahl | Typ 1 | 4 | Nur Hintergrund-Stift | 4 | 101,00 | 240,00 | 1 | Fenster-015 | Automatisch | R-020 | R-009 | EG-R-009-Fenster-015 | 2.4 | 0.0857907 | 1.01 | 0.2 | 16.2 | 0.2 | 8.37008 | 0.909 | 2.424 | 0.2 | 0.1 | 2.6 | 2.5 | 0 | 1.05 | 0.02 | 0.21 | 0.155 | 0.18
Fenster-002 | EG | F30 | Fenster-002 | Erdgeschoss; Grundfläche Gebäude Nachgezogen; Wohnung2 EG | Wohnen | R-004 | EG | 0 | Wand-009 | Glas Normalglas; Metall Stahl, verzinkt; Farbe, weiß; Fensterrahmen | Terrasse | R-011 | Nicht definiert | 1,010×2,400 | 1,010×2,400×0,375 | L | yes | 0 | 2 | 5 | Kein | no | 11 | Lotrecht | Metall Stahl, verzinkt | Farbe, weiß | Metall, Fassade Edelstahl | Typ 1 | 4 | Nur Hintergrund-Stift | 4 | 101,00 | 240,00 | 1 | Fenster-002 | Automatisch | R-011 | R-004 | EG-R-004-Fenster-002 | 2.4 | 0.0857907 | 1.01 | 0.2 | 16.2 | 0.2 | 8.37008 | 0.909 | 2.424 | 0.2 | 0.1 | 2.6 | 2.5 | 0 | 1.05 | 0.02 | 0.21 | 0.155 | 0.18 | Pset_DoorWindowGlazingType - IsCoated: yes
Fenster-003 | EG | F30 | Fenster-003 | Erdgeschoss; Grundfläche Gebäude Nachgezogen; Wohnung2 EG | Wohnen | R-004 | EG | 0 | Wand-009 | Glas Normalglas; Metall Stahl, verzinkt; Farbe, weiß; Fensterrahmen | Terrasse | R-011 | Nicht definiert | 1,010×2,400 | 1,010×2,400×0,375 | L | yes | 0 | 2 | 5 | Kein | no | 11 | Lotrecht | Metall Stahl, verzinkt | Farbe, weiß | Metall, Fassade Edelstahl | Typ 1 | 4 | Nur Hintergrund-Stift | 4 | 101,00 | 240,00 | 1 | Fenster-003 | Automatisch | R-011 | R-004 | EG-R-004-Fenster-003 | 2.4 | 0.0857907 | 1.01 | 0.2 | 16.2 | 0.2 | 8.37008 | 0.909 | 2.424 | 0.2 | 0.1 | 2.6 | 2.5 | 0 | 1.05 | 0.02 | 0.21 | 0.155 | 0.18
Fenster-004 | EG | F30 | Fenster-004 | Erdgeschoss; Grundfläche Gebäude Nachgezogen; Wohnung2 EG | Wohnen | R-004 | EG | 0 | Wand-009 | Glas Normalglas; Metall Stahl, verzinkt; Farbe, weiß; Fensterrahmen | Terrasse | R-011 | Außen | 1,010×2,400 | 1,010×2,400×0,375 | L | yes | 0 | 2 | 5 | Kein | no | 11 | Lotrecht | Metall Stahl, verzinkt | Farbe, weiß | Metall, Fassade Edelstahl | Typ 1 | 4 | Nur Hintergrund-Stift | 4 | 101,00 | 240,00 | 1 | Fenster-004 | Automatisch | R-011 | R-004 | EG-R-004-Fenster-004 | 2.4 | 0.0857907 | 1.01 | 0.2 | 16.2 | 0.2 | 8.37008 | 0.909 | 2.424 | 0.2 | 0.1 | 2.6 | 2.5 | 0 | 1.05 | 0.02 | 0.21 | 0.155 | 0.18
Fenster-005 | 1. OG | F30 | Fenster-005 | Grundfläche Gebäude Nachgezogen; Obergeschoss; Wohnung2 OG | Loft | R-003 | 1. OG | 1 | Wand-008 | Glas Normalglas; Metall Stahl, verzinkt; Farbe, weiß; Fensterrahmen | Wohnung2 OG | R-020 | Nicht definiert | 1,010×2,400 | 1,010×2,400×0,375 | R | yes | 0 | 2 | 5 | Kein | no | 11 | Lotrecht | Metall Stahl, verzinkt | Farbe, weiß | Metall, Fassade Edelstahl | Typ 1 | 4 | Nur Hintergrund-Stift | 4 | 101,00 | 240,00 | 1 | Fenster-005 | Automatisch | R-020 | R-003 | 1. OG-R-003-Fenster-005 | 2.4 | 0.0857907 | 1.01 | 3.9 | 19.9 | 0.15 | 8.37008 | 0.909 | 2.424 | 0.15 | 0.05 | 2.55 | 2.45 | 0 | 1.05 | 0.02 | 0.21 | 0.155 | 0.18
Fenster-015 | 1. OG | F30 | Fenster-015 | Grundfläche Gebäude Nachgezogen; Obergeschoss; Wohnung2 OG | Loft | R-003 | 1. OG | 1 | Wand-009 | Glas Normalglas; Metall Stahl, verzinkt; Farbe, weiß; Fensterrahmen | Wohnung2 OG | R-020 | Nicht definiert | 1,010×2,400 | 1,010×2,400×0,375 | R | yes | 0 | 2 | 5 | Kein | no | 11 | Lotrecht | Metall Stahl, verzinkt | Farbe, weiß | Metall, Fassade Edelstahl | Typ 1 | 4 | Nur Hintergrund-Stift | 4 | 101,00 | 240,00 | 1 | Fenster-015 | Automatisch | R-020 | R-003 | 1. OG-R-003-Fenster-015 | 2.4 | 0.0857907 | 1.01 | 3.9 | 19.9 | 0.15 | 8.37008 | 0.909 | 2.424 | 0.15 | 0.05 | 2.55 | 2.45 | 0 | 1.05 | 0.02 | 0.21 | 0.155 | 0.18
Fenster-002 | 1. OG | F30 | Fenster-002 | Grundfläche Gebäude Nachgezogen; Obergeschoss; Wohnung2 OG | Loft | R-003 | 1. OG | 1 | Wand-009 | Glas Normalglas; Metall Stahl, verzinkt; Farbe, weiß; Fensterrahmen | Wohnung2 OG | R-020 | Nicht definiert | 1,010×2,400 | 1,010×2,400×0,375 | L | yes | 0 | 2 | 5 | Kein | no | 11 | Lotrecht | Metall Stahl, verzinkt | Farbe, weiß | Metall, Fassade Edelstahl | Typ 1 | 4 | Nur Hintergrund-Stift | 4 | 101,00 | 240,00 | 1 | Fenster-002 | Automatisch | R-020 | R-003 | 1. OG-R-003-Fenster-002 | 2.4 | 0.0857907 | 1.01 | 3.9 | 19.9 | 0.15 | 8.37008 | 0.909 | 2.424 | 0.15 | 0.05 | 2.55 | 2.45 | 0 | 1.05 | 0.02 | 0.21 | 0.155 | 0.18
Fenster-003 | 1. OG | F30 | Fenster-003 | Grundfläche Gebäude Nachgezogen; Obergeschoss; Wohnung2 OG | Loft | R-003 | 1. OG | 1 | Wand-009 | Glas Normalglas; Metall Stahl, verzinkt; Farbe, weiß; Fensterrahmen | Wohnung2 OG | R-020 | Nicht definiert | 1,010×2,400 | 1,010×2,400×0,375 | L | yes | 0 | 2 | 5 | Kein | no | 11 | Lotrecht | Metall Stahl, verzinkt | Farbe, weiß | Metall, Fassade Edelstahl | Typ 1 | 4 | Nur Hintergrund-Stift | 4 | 101,00 | 240,00 | 1 | Fenster-003 | Automatisch | R-020 | R-003 | 1. OG-R-003-Fenster-003 | 2.4 | 0.0857907 | 1.01 | 3.9 | 19.9 | 0.15 | 8.37008 | 0.909 | 2.424 | 0.15 | 0.05 | 2.55 | 2.45 | 0 | 1.05 | 0.02 | 0.21 | 0.155 | 0.18
Fenster-004 | 1. OG | F30 | Fenster-004 | Grundfläche Gebäude Nachgezogen; Obergeschoss; Wohnung2 OG | Loft | R-003 | 1. OG | 1 | Wand-009 | Glas Normalglas; Metall Stahl, verzinkt; Farbe, weiß; Fensterrahmen | Wohnung2 OG | R-020 | Außen | 1,010×2,400 | 1,010×2,400×0,375 | L | yes | 0 | 2 | 5 | Kein | no | 11 | Lotrecht | Metall Stahl, verzinkt | Farbe, weiß | Metall, Fassade Edelstahl | Typ 1 | 4 | Nur Hintergrund-Stift | 4 | 101,00 | 240,00 | 1 | Fenster-004 | Automatisch | R-020 | R-003 | 1. OG-R-003-Fenster-004 | 2.4 | 0.0857907 | 1.01 | 3.9 | 19.9 | 0.15 | 8.37008 | 0.909 | 2.424 | 0.15 | 0.05 | 2.55 | 2.45 | 0 | 1.05 | 0.02 | 0.21 | 0.155 | 0.18
Fenster-011 | 1. OG | F30 | Fenster-011 | Grundfläche Gebäude Nachgezogen; Obergeschoss; Wohnung1 OG | Luftraum Dach | R-012 | 1. OG | 1 | Wand-012 | Naturstein Kalkstein; Glas Normalglas; Fensterrahmen | Luftraum Dach | R-012 | Nicht definiert | 1,970×0,600 | 1,970×0,600×0,375 |  | no | 0 | 2 | 7 | Keine | yes | 8 | Senkrecht | Naturstein Kalkstein | Holz Nussbaum | Verputz, glatt, weiß | Stil 1 | 1 | Luftschicht | 21 | 197,05 | 60,00 | 0 |  | Eigene |  |  | 1. OG-R-012-Fenster-011 | 0.6 | 0.0652012 | 1.97047 | 5.34795 | 21.348 | 1.59795 | 5.34466 | 0.443357 | 1.18228 | 1.44795 | 1.34795 | 2.04795 | 1.94795 | -0.05 | 0.89 | 0.01 | 0.16 | 0.205 | 0.13 | Türen/Fenster - Schallschutzklasse: SK 3

# IfcBuildingElementProxy: 2-Flügelfenster 22, Fenster-007
In: 1. OG
Classification: Fenster (ARCHICAD Klassifizierung)
ArchiCADProperties - Element ID: Fenster-007; Hotlink und Element-ID: Fenster-007; Ebene: Wand Aussen; Bibliothekselement-Name: 2-Flügelfenster 22; Baustoff / Mehrschichtiger Aufbau / Profil / Schraffur: Misch-Schraffur 0%; Schraffurtyp: Misch-Schraffur 0%; Kollidierende Räume: Grundfläche Gebäude Nachgezogen; Obergeschoss; Wohnung2 OG; Zugehöriger Raumname: Wohnung2 OG; Zugehörige Raumnummer: R-020; Geschützt: no; Ursprungsgeschoss Name: 1. OG; Ursprungsgeschoss Nummer: 1; Typ: Fenster; Überobjekt-ID: Wand-009; Oberfläche (Alle): Naturstein Kalkstein; Glas Normalglas; Fensterrahmen; Von Raum: Wohnung2 OG; Von Raum-Nummer: R-020; zu Raum: Loft; Zu Raum-Nummer: R-003; Lage: Nicht definiert; Tragende Funktion: Nicht definiert; Anzeigen auf Umbau-Filter: Alle relevanten Filter; Umbau-Status: Bestand; Anschlagsmaße: 1,800×2,400; Größe Wandloch: 1,800×2,400; Größe laut Eingabe: 1,800×2,400; Nominale B x H: 1,800×2,400; Nominale B x H x T: 1,800×2,400×0,375; Wandstruktur: WA | 2 Schichtig KS; Ausrichtung: L; Öffnung Bibliothekselementname: 2-Flügelfenster 22; Öffnungsseite Schraffurindex: Misch-Schraffur 0%; ARCHICAD Klassifizierung - 22: Fenster
AC_Pset_2-Flügelfenster_22 - Wandkontur (0-Keine,1-Voll,2-Seite,3-Länge): 0; Fixpunkte 0-Kein,1-2D,2-3D,3-Alle: 3; 2D-Fixpunkte in 3D zeigen: yes; Darstellungseinstellung Grundr.: 3; Winkel Öffnungsposition: 0 deg; Loch übernimmt Oberflächenmaterial der Wandseite: yes; Öffnungsoberfläche ist gebogen in gebogenen Wänden: no; Wand-Typ: 1; Wandrichtungstyp: 0; Laibung Ankerposition: 2; Wandquerschnittstyp: 1; Eckfenster Debugfunktion: no; Einsetzmodus (1=CW,0=W): no; Eckfenster Funktion: yes; Eckwinkel: 90 deg; Unterschiedliche Wanddicken: no; Öffnungsrichtung: 1; Grundriss: 1; 3D: 8; Schnitt / Ansicht: 1; Anschlag im Grundriss zeigen: 1; Eck-Profil: no; Ecke 2: no; Eckwinkel 2: 90 deg; Unterschiedliche Wand Dicke 2: no; Ecke 1: no; Eckwinkel 1: 90 deg; Unterschiedliche Wand Dicke 1: no; Ecke Verbindungstyp 1: 1; Ecke Verbindungstyp 2: 1; Nominalmaß: 0; Rohbauöffnung als Nominalmaß einstellen: yes; Architekturlichte als Nominalmaß einstellen: no; Rahmen-Außenmaß als Nominalmaß einstellen: no; Baurichtmaß als Nominalmaß einstellen: no; Übertrage aktuelle Nominal Größe auf die Auswahl: no; Oberlicht: no; Oberlicht Geteilt: yes; Unteres Feld: no; Unteres Feld geteilt: yes; Unterschiedliche Breiten (gs_stockb): no; Unterschiedliche Breiten (gs_ver_r): no; Öffnungswinkel Hauptflügel 3D: 0 deg; Öffnungswinkel Sprossenfenster in 3D: 0 deg; Öffnungswinkel Unteres Feld in 3D: 0 deg; Öffnungstyp Hauptflügel: 3; Hauptflügel Kategorie (gs_SashCat_1): Haupt; Hauptflügel Kategorie (gs_iSashCat_1): 1; Hauptflügel 2 Kategorie (gs_SashCat_2): Haupt; Hauptflügel 2 Kategorie (gs_iSashCat_2): 1; Öffnungstyp Sprossenfenster: 1; Oberer Querriegel Kategorie (gs_SashCat_o1): Haupt; Oberer Querriegel Kategorie (gs_iSashCat_o1): 1; Oberer Querriegel 2 Kategorie (gs_SashCat_o2): Haupt; Oberer Querriegel 2 Kategorie (gs_iSashCat_o2): 1; Öffnungstyp Unteres Feld: 1; Unterer Querriegel Kategorie (gs_SashCat_u1): Haupt; Unterer Querriegel Kategorie (gs_iSashCat_u1): 1; Unterer Querriegel 2 Kategorie (gs_SashCat_u2): Haupt; Unterer Querriegel 2 Kategorie (gs_iSashCat_u2): 1; Öffnungswinkel Hauptflügel 2D-Links: 0 deg; Öffnungswinkel Hauptflügel 2D-Rechts: 0 deg; Modelldarstell. für symbolische 2D-Darstellung überschreiben: no; Öffnungslinien in 2D: yes; Öffnungslinien-Typ: 1; Nebenöffnung Linientyp in 2D: 4; Öffnungslinien-Form (or_SwingType): Gebogen; Öffnungslinien-Form (or_iSwingType): 1; Öffnungslinien-Form (or_SlidingType): Keine; Öffnungslinien-Form (or_iSlidingType): 0; 2D & 3D Öffnungslinien-Stift (or_opLinePen): Elemente+Text; 2D & 3D Öffnungslinien-Stift (or_iOpLinePen): 1; Modelldarstell. für 3D-Darstellung überschreiben: no; Öffnungslinie zeigen: yes; Linientyp Öffnungsseite (or_opLineType3dIn): Vollinie; Linientyp Öffnungsseite (or_iOpLineType3dIn): 0; Linientyp Gegenüberliegende Seite (or_opLineType3dOut): Strichlinie; Linientyp Gegenüberliegende Seite (or_iOpLineType3dOut): 1; Nebenflügel Linientyp in 3D: Strichlinie; Nebenflügel Linientyp: 1; Linien-Ausrichtung (or_oplineStyle): Griff; Linien-Ausrichtung (or_iOplineStyle): 1; Num. of Horiz. Gitter Hauptflügel: 0; Num. of Vert. Gitter Hauptflügel: 0; Vertikales Gitter 2: 0; Num. of Horiz. Gitter oberes Feld: 0; Num. of Vert. Gitter oberes Feld: 0; Transom Vertikal Gitter 2: 0; Num. of Horiz. Gitter unteres Feld: 0; Num. of Vert. Gitter unteres Feld: 0; Unterer Querriegel Vertikales Gitter 2: 0; Bearbeitbares Gitter: no; Gleiche Flügelteilung: yes; Fensterklinke (gs_window_handle): no; Fenstergriff Typ (gs_handle_type_win): Stil 3; Fenstergriff Typ (gs_handle_type_win_m): 3; Fenstergriff Oberflächenmaterial: Metall Stahl, matt; Hauptflügel eigener Flügel: no; Oberlicht eigener Flügel: no; Unteres Feld eigener Flügel: no; Futter und Verkleidung außen: no; Futter Außen (gs_trimtype_out): Rechteckig; Futter Außen (gs_trimtype_out_int): 1; Gehäuse Kopftyp: 1; Querbalken oben: yes; Querbalken Typ oben: 1; Gehäuseunterseite außen: yes; Verkleidung (gs_trim_show_cover_out): yes; einheitliche Einfassungsbreiten (gs_trim_outside_uniform): yes; Futter Schnittlinienstift auf beiden Seiten: Elemente+Text; Schraffur Zarge außen: Nur Hintergrund-Stift; Außenverkleidung Oberflächenmaterial: Fensterrahmen; Futter und Verkleidung innen: no; Futter Innen (gs_trimtype_in): Rechteckig; Futter Innen (gs_trimtype_in_int): 1; Verkleidung (gs_trim_show_cover_in): yes; einheitliche Einfassungsbreiten (gs_trim_inside_uniform): yes; Schraffur Zarge innen: Nur Hintergrund-Stift; Innenverkleidung Oberflächenmaterial: Fensterrahmen; Fensterbank Außen: yes; Schwelle/Fenstereinfassung Übergröße: no; Typ Fensterbank: 8; Fensterbank Winkel: 3 deg; Außenkante: Senkrecht; Fensterbank ist gebogen in gebogenen Wänden: yes; Dämmung unter Fensterbank: yes; Wand-Dämmschicht benutzen: no; Detaillierungsgrad in 3D Rollsicht Fensterbank: 1; Fensterbank Linienstift 3D und Aufsicht (gs_sill_pen_3D): Elemente+Text; Schnittkontur-Stift Fensterbank Außen: Elemente+Text; Fensterbank Schnittschraffur: Nur Hintergrund-Stift; Kontur-Stift: Elemente+Text; Schraffur (gs_sill_fill_ins_fg): Luftschicht; Schraffur-Vordergrundstift (gs_sill_pen_ins_fg): Elemente+Text; Fensterbank Oberflächenmaterial: Naturstein Kalkstein; Mauerwerksbrüstung Mörtel Oberflächenmaterial: Verputz, rauh, grau; Fensterbank Innen: no; Winkel Fensterbank Innen: 0 deg; Fensterbank Innen ist gebogen in gebogenen Wänden: yes; Fensterbank Innen in polygonalen Wänden: 2; Schnittkontur-Stift Fensterbank Innen: Elemente+Text; Fensterbank Linienstift 3D und Aufsicht (gs_board_pen_3D): Elemente+Text; Schnittschraffur Fensterbank innen: Nur Hintergrund-Stift; Fensterbrett Oberflächenmaterial: Holz Nussbaum; Rollschicht (bMasonryArch): no; Rollschicht (gs_masonry_arch_int): 2; Typ Sturz (gs_masonry_arch_structure): Verputzt; Typ Sturz (gs_masonry_arch_structure_int): 1; Sturz direkt über der Tür: yes; Nische unterm Bogen: yes; Neigungswinkel: 75 deg; Eigenes Nischen-Oberflächenmaterial: no; Bogen Schnittschraffur: Nur Hintergrund-Stift; Stift Ziegelsturz: Schichttrennlinien/Kontur; Mauerwerksbogen Stein Oberflächenmaterial: Farbe, grau; Mauerwerksbogen Mörtel Oberflächenmaterial: Verputz, rauh, grau; Mauerwerksbogen Schlusstein Oberflächenmaterial: Farbe, grau; Nischen-Oberflächenmaterial: Verputz, rauh, gelb; Oberfläche Eckstütze: Fensterrahmen; Faschen Links: no; Faschen Rechts: no; Faschen Oben: no; Faschen Unten: no; Typ Faschen: 1; Voreingestellte Faschen - rechts: yes; Voreingestellte Faschen - links: yes; Faschentiefe >= Anschlagstiefe: no; Schnittschraffur (gs_faschen_fill): Erde 1; Schnittschraffur-Vordergrundstift (gs_faschen_fg): Schichttrennlinien/Kontur; 3D-Konturstift: Konturstift; Putz Oberflächenmaterial: Verputz, rauh, grau; Stein Oberflächenmaterial: MW Ziegel, blaurot, DF, Läufer; Mörtel Oberflächenmaterial: Verputz, rauh, grau; Typ Anschlag (gs_reveal_type_new): ohne Anschlag; Typ Anschlag (gs_reveal_type_int): 2; Untere Laibung Typ (gs_reveal_type_bottom): Gleich; Untere Laibung Typ (gs_reveal_type_bottom_int): 1; Äußerer Laibungstyp: ohne Anschlag; Typ Anschlag (gs_reveal_doubleOuterTypeInt): 0; Laibungstyp Innen: ohne Anschlag; Typ Anschlag (gs_reveal_doubleInnerTypeInt): 0; Anschlagtiefe und Laibungswinkel gleich: yes; Laibung bearbeiten von (gs_reveal_angle_edit_by): Winkel und Tiefe; Laibung bearbeiten von (gs_reveal_angle_edit_by_int): 1; Winkel Seite 2: 20 deg; Winkel Seite: 20 deg; Winkel oben: 20 deg; Winkel unten: 20 deg; Außenwinkel Seite 2: 20 deg; Außenwinkel Seite: 20 deg; Außenwinkel obere Seite: 20 deg; Außenwinkel untere Seite: 20 deg; Einbaurahmen: no; Einbaurahmen Aufsichtslinien-Stift: Elemente+Text; Einbaurahmen Konturstift (gs_mountingFrame_pen_cont): Elemente+Text; Einbaurahmen Schraffur (gs_mountingFrame_fill): Nur Hintergrund-Stift; Einbaurahmen Oberflächenmaterial: Holz Esche; Schichteinzug (gs_closure_type): Kein Schichteinzug; Schichteinzug (gs_closure_type_int): 1; Schicht an Seite einziehen (gs_cavity_side): Beide; Schicht an Seite einziehen (iCavityClosureSide): 1; Einzuziehende Schichten: 1; Schichten von (gs_nTurnDir): Außenseite; Schichten von (iCavityClosureTurnDir): 1; Schichteinzug auf Seite 2: yes; Schichteinzug auf Seite 1: yes; Schichteinzug oben: no; Schichteinzug unten: no; Schichteinzug zu Schicht: 1; Schichteinzug von Seite (gs_cc_dutch_ClosureToSide): 1; Schicht einziehen zu Abschluss: no; Dichtungsband einfügen: yes; Dichtungsband zeigen: yes; Konturlinien-Typ (gs_ltJoint): 1; Schraffur (gs_fillJoint): Nur Hintergrund-Stift; Schraffur-Vordergrundstift (gs_penJointFg): Elemente+Text; Eigenes Oberflächenmaterial: no; Oberflächenmaterial: Holz Esche; Konturlinien-Typ (gs_ltPlug): 1; Schraffur (gs_fillPlug): Nur Hintergrund-Stift; Schraffur-Vordergrundstift (gs_penPlugFg): Elemente+Text; Editierte Anschlagseite: 1; Editierte Wandseite: 1; Schicht Nummer: 1; Schicht einziehen: no; Schicht als Putz ansehen: no; Einzugsdicke: 1; Ausrichtung Schraffur: 1; Trennlinie am Einzug: no; Stift Trennlinie: Elemente+Text; Letzte ausgewählte Seite: no; Abschlussart automatisch verändert: no; Wandbekleidung benutzen: no; automatischer Schichteinzug Putz innen: yes; Putzschicht innen einziehen: 0; automatischer Schichteinzug Putz außen: yes; Putzschicht außen einziehen: 0; Bemaßungsfangpunkte in 2D: no; in 3D zeigen: no; Anschluss Links: no; Anschluss Rechts: no; Anschluss Oben: no; Anschluss Unten: no; Heizkörpernische: no; Heizkörpernischen-Größe (gs_parapet_sizes_st): Automatisch; Heizkörpernischen-Größe (iParapetSize): 1; Automatische Breite und Höhe: yes; Heizkörpernische-UK zu (gs_parapet_bottom_st): Aktuelles Geschoss; Heizkörpernische-UK zu (iParapetBottom): 1; verdeckte Brüstung zeigen: yes; Linientyp verdeckte Brüstung: 1; Sturzbrett: no; Fensterbank innen ist gebogen: yes; Fensterbank in Polygonwänden: 2; 2D-Detaillierungsgrad: 2; Stift Grundriss: Elemente+Text; Linientyp Grundriss: 4; 3D Stift: Elemente+Text; Ansichts-Stift: Elemente+Text; Schnittschraffur (gs_lintelboard_fill): Misch-Schraffur 50 %; Schnittschraffur-Vordergrundstift (gs_lintelboard_pen_fg): Elemente+Text; Sturzbrett Oberflächenmaterial: Farbe, weiß; Sturzsystem: no; Hintersturz: no; autom. Hintersturzhöhe: no; Hinterer Sturz übernimmt Oberflächenmaterial der Wand: yes; Hinterer Sturz Oberflächenmaterial: Farbe, weiß; Hintersturz Schraffur (gs_hsturz_fillType): Nur Vordergrund-Stift; Schnittlinienstift Hintersturz: Konturstift; Typ (iTypeProfiledLintel): 1; Dämmung: no; Sturz übernimmt Oberflächenmaterial der Wand: yes; Sturz Oberflächenmaterial: Farbe, weiß; Wärmedämmung Oberflächenmaterial: Verputz, glatt, weiß; Schnittlinien Stift: Konturstift; Sturz Schraffur: Dämmung, hart 1; Sturz Schraffur-Vordergrundstift: Elemente+Text; Dämmung Schraffur 1: Dämmung, hart 1; Dämmung Schraffur 2: Dämmung, hart 1; Dämmung Schraffur-Vordergrundstift: Elemente+Text; Fenstereinfassung: no; 2D-Darstellung (bShowMounting2D): yes; Typ Fassung: 2; Falz: no; Pfosten: no; Befestigung Oberflächenmaterial: Fensterrahmen; Konturlinien-Stift: Elemente+Text; Kontur-Stift Sturz vorne: Elemente+Text; Kontur-Stift Sturz hinten: Elemente+Text; Schraffur-Vordergrundstift (gs_pen_sc): Elemente+Text; Schraffur Bedeckung: Nur Vordergrund-Stift; Fensterbank Schraffur: Nur Hintergrund-Stift; Schraffur (efsc2): Holz Schalung liegend, 10cm; Schraffur Sturz vorne: Nur Hintergrund-Stift; Schraffurtyp Dämmung: Dämmung, hart 1; Hintersturz Schraffur (efsc_h): Nur Vordergrund-Stift; Linientyp: 4; Sonnenschutz (bSunshade): no; Sonnenschutz-Typ: 1; Aktivierte Sonnenschutz-Typen: 254; Anzahl Lamellen: 2; Anzahl Paneelen 2: 1; Paneel-Position (gs_shutter_panelPos): Symmetrisch; Paneel-Position (gs_shutter_iPanelPos): 1; Automatische Höhenanpassung: yes; Extra Rahmen: no; Abdeckungstyp (gs_slidingShutter_cover): Z-Profil; Abdeckungstyp (gs_slidingShutter_iCover): 1; Stapelrichtung (gs_foldingShutter_stacking): Innen; Stapelrichtung (gs_foldingShutter_iStacking): 1; in 3D geöffnet: yes; 3D-Öffnungswinkel: 180 deg; 2D-Symbol zeigen: yes; Öffnungslinie im Symbol zeigen: yes; Sonnenschutz-Symbol-Linientyp: 1; Sonnenschutz-Schnittlinien-Stift: Elemente+Text; Sonnenschutz Aufsichtslinien-Stift: Elemente+Text; Sonnenschutz Schnittschraffur: Nur Hintergrund-Stift; Sonnenschutz Schnittschraffur-Vordergrundstift: Elemente+Text; Verschattung Dämmung Schraffur: Dämmung, weich; Verschattung Dämmung Schraffur-Vordergrundstift: Elemente+Text; Verschattung Dämmung Schraffur-Hintergrundstift: Elemente+Text; Fensterladen Oberflächenmaterial: Holz Esche; Fensterladenrahmen Oberflächenmaterial: Holz Esche; Rollladengehäuse Oberflächenmaterial: Metall Chrom; Rollladenlamellen Oberflächenmaterial: Lack schwarz; Rollladen Schiene Oberflächenmaterial: Lack schwarz; Jalousie Oberflächenmaterial: Metall Chrom; Jalousielamellen Oberflächenmaterial: Lack schwarz; Schiebladen Schiene Oberflächenmaterial: Metall Chrom; Paneeltyp (gs_shutPanel_type): Stil 1; Paneeltyp (gs_shutPanel_iType): 1; Unterschiedliche Rahmen-Breite unten: no; Automatische Rollladenbreite: yes; Winkel Lamelle: 30 deg; Lochanzahl horizontal: 5; Lochanzahl vertikal: 8; Rollladen-Platzierung (gs_shutRoll_placement): Vor Fassade angebracht; Rollladen-Platzierung (gs_shutRoll_iPlacement): 1; Typ (gs_shutRoll_boxType): Rechteckig; Typ (gs_shutRoll_iBoxType): 1; Handlauf Position (gs_shutRoll_railPos): Auf Verkleidung; Handlauf Position (gs_shutRoll_iRailPos): 1; Verkleidung hinter Sonnenschutz zeigen (gs_shutRoll_showCasingBehind): yes; Wand hinter Kasten schneiden: yes; Höhe in Wandlochhöhe einschließen: no; Neigung Kastendach: 10 deg; Kasten–Breite (gs_shutRoll_boxDefaultSize): Architekturlichte Breite; Kasten–Breite (gs_shutRoll_iBoxDefaultSize): 1; Jalousien-Platzierung (gs_shutLam_placement): Vor Fassade angebracht; Jalousien-Platzierung (gs_shutLam_iPlacement): 1; Dämmung hinter Kasten: no; Geöffnetes Gehäuse: yes; Führungsschienen: yes; Handlauf Position (gs_shutLam_railPos): Auf Verkleidung; Handlauf Position (gs_shutLam_iRailPos): 1; Verkleidung hinter Sonnenschutz zeigen (gs_shutLam_showCasingBehind): yes; Kippwinkel (gs_shutLam_rotation): 45 deg; Kippwinkel (gs_shutLam2_rotation): 45 deg; seitliche Wandkontur (gs_wallcontour): Beide; seitliche Wandkontur (gs_wallcontour_id): 1; Wandkontur (gs_wcont_line): beide Seiten; Wandkontur (iWallContourLine): 4; Automatische Einstellungen: yes; Wandkonturlinie innen - 1:50 und tiefer: yes; Wandkonturlinie innen - 1:100 und höher: yes; Wandkonturlinien Typ innen - 1:50 und tiefer: 1; Wandkonturlinien Typ innen - 1:100 und höher: 1; Wandkonturlinie außen - 1:50 und tiefer: yes; Wandkonturlinie außen - 1:100 und höher: yes; Wandkonturlinien Typ außen - 1:50 and tiefer: 4; Wandkonturlinien Typ außen - 1:100 und höher: 1; Wandkonturlinien Stift - 1:50 und tiefer: Elemente+Text; Wandkonturlinien Stift - 1:100 und höher: Elemente+Text; Konstruktionstyp: 8; Fensterrahmen Oberflächenmaterial außen: Fensterrahmen; Fensterrahmen Oberflächenmaterial innen: Fensterrahmen; Flügelrahmen Oberflächenmaterial außen: Fensterrahmen; Flügelrahmen Oberflächenmaterial innen: Fensterrahmen; Mittelpfosten - Außenfläche: Fensterrahmen; Mittelpfosten - Innenfläche: Fensterrahmen; Verglasung -Oberflächenmaterial: Glas Normalglas; Einheitliche Oberflächen Verkleidung: yes; Rahmen und Flügel - 3D und Aufsichtslinien-Stift: Schichttrennlinien/Kontur; Rahmen Schnittlinienstift: Schichttrennlinien/Kontur; Rahmen Schnittschraffur: Nur Hintergrund-Stift; Flügelrahmen-Stift: Schichttrennlinien/Kontur; Rahmen Schraffur: Luftschicht; Glas - 3D und Aufsichtslinien-Stift: Schichttrennlinien/Kontur; Glas Linienstift Kontur: Schichttrennlinien/Kontur; Glas Schnittschraffur: Nur Hintergrund-Stift; Rahmen Deckschraffur: Nur Hintergrund-Stift; Wandschraffur in der Öffnung: yes; Schraffur (gs_wallhole_fill): Nur Hintergrund-Stift; Schraffur-Vordergrundstift (gs_wallhole_pen_fg): Elemente+Text; Fensterbank Hintergrundschraffur: yes; Schraffur-Vordergrundstift (gs_sill_wallhole_pen_fg): Elemente+Text; Fensterbank Innen Hintergrundschraffur: no; Schraffur-Vordergrundstift (gs_board_wallhole_pen_fg): Elemente+Text; Zeige nur die Grundriss Info: yes; Grundriss Info: 3; Texteinstellung (gs_PlanViewInfos_scaleValues): Maßstababhängig (Modellgröße); Massstab (gs_PlanViewInfos_scaleValues_m): 2; Text Anschlag 1: yes; Text (gs_textll): RAF; Absatz horizontal (mm) (gs_PlanViewInfos_T1_xOffsetMM): 3; Absatz vertikal (mm) (gs_PlanViewInfos_T1_yOffsetMM): 2; Text drehen (gs_dr1): no; Text Anschlag 2: yes; Text (gs_textlr): FB; Absatz horizontal (mm) (gs_PlanViewInfos_T2_xOffsetMM): -1; Absatz vertikal (mm) (gs_PlanViewInfos_T2_yOffsetMM): 2; Text drehen (gs_dr2): no; Text Drehkippflügel: yes; Text (gs_textdrehkipp): DK; Text Drehkippflügel gespiegelt: yes; Absatz horizontal (mm) (gs_PlanViewInfos_T3_xOffsetMM): -1; Absatz vertikal (mm) (gs_PlanViewInfos_T3_yOffsetMM): 0; Text drehen (gs_dr3): no; Text Kurbel: yes; Text (gs_textkurbel): K; Text Kurbel gespiegelt: yes; Absatz horizontal (mm) (gs_PlanViewInfos_T4_xOffsetMM): 1; Absatz vertikal (mm) (gs_PlanViewInfos_T4_yOffsetMM): 0; Text drehen (gs_dr4): no; Text Elektro-Kurbel 2: no; Text (gs_PlanViewInfos_T5_customText): O; Absatz horizontal (mm) (gs_PlanViewInfos_T5_xOffsetMM): 0; Absatz vertikal (mm) (gs_PlanViewInfos_T5_yOffsetMM): -3; Text gespiegelt (gs_PlanViewInfos_T5_Mirrored): yes; Text drehen (gs_PlanViewInfos_T5_Rotate): no; Text Kurbel individuell: no; Text (gs_PlanViewInfos_T6_customText): Fest; Absatz horizontal (mm) (gs_PlanViewInfos_T6_xOffsetMM): 3; Absatz vertikal (mm) (gs_PlanViewInfos_T6_yOffsetMM): -3; Text gespiegelt (gs_PlanViewInfos_T6_Mirrored): yes; Text drehen (gs_PlanViewInfos_T6_Rotate): no; Schrifttyp (gs_zsgri): Arial; Schriftgröße (mm): 1.5; Text-Stift (gs_pengri): Elemente+Text; Stift Kurbel: Elemente+Text; Fensterkoten: yes; Sichtbarkeit Fensterbemaßung (gs_etikett): Modelldarstellungs-Optionen; Sichtbarkeit Fensterbemaßung (iEtikett): 3; Öffnung roh: 1; Text Öffnung roh: Öffnung roh; Sturz fertig: 1; Text Fertig Sturz: Sturz fertig; Brüstung fertig: 1; Text Brüstung fertig: Br. fertig; Platz für Fußboden: no; Brüstung roh: 1; Text Brüstung roh: Rohbrüstung Höhe; Texteinstellung (gs_Etikett_scaleValues): Maßstababhängig (Modellgröße); Massstab (gs_Etikett_scaleValues_m): 2; Schrifttyp (fontType): Arial; Schriftgröße (papier) (gs_Etikett_fontSize_mm): 1.5; Dimension Stift Text: Elemente+Text; X Position (m): 0; Position X (mm): 0; Y Position (m): 0; Position Y (mm): 8; Automat. Zeilenabstand: no; Zeilenabstand (papier): 1; Drehwinkel: 0 deg; Fenster-Befestigungstyp: 1; Zeige die ID im Grundriss: no; Beschriftung Fenstertyp: 1; autom. Fenster ID Nummer: yes; Eigener Text: Eigene ID; Marker spiegeln: yes; Zusätzliche Werte zeigen (Öffnungsmass 1.20/1.50): yes; Text Position X (mm): 0; Text Position Y (mm): 8; Texteinstellung (gs_IDText_scaleValues): Maßstababhängig (Modellgröße); Massstab (gs_IDText_scaleValues_m): 2; Schriftgröße (papier) (gs_IDText_fontSize_mm): 5; Schrifttyp (gs_IDText_fontType): Arial; Text-Stift (gs_IDText_fontPen): Elemente+Text; Darstellung als Oberlicht: no; Stift Wandendlinie: Elemente+Text; Linientyp Wandendlinie: 4; Sturztiefe im Grundriss zeigen: no; Sturztiefe Symbol- Linientyp: 21; Sturztiefe Symbolstift: Konturstift; Typ Links: 0; Typ Rechts: 0; Automatische Maße: yes; Einbaurahmen Konturstift (gs_TolerBlin_contour_pen): Elemente+Text; Einbaurahmen Konturlinientyp: 1; Einbaurahmen Schraffur (gs_TolerBlin_fill_type): Nur Hintergrund-Stift; Einbaurahmen Schraffur-Vordergrundstift (gs_TolerBlin_fg_pen): Schichttrennlinien/Kontur; Schraffur-Stift Fugenausfüllung: Elemente+Text; Linientyp Kontur Fugenausfüllung: 1; Fugenausfüllung Schraffur: Nur Hintergrund-Stift; Fugenausfüllung Schraffur-Vordergrundstift: Schichttrennlinien/Kontur; IFC Betrieb (ifc_optypestr): Zweiflügelfenster - Vertikal; IFC Betrieb (ifc_optype): 2; Aussparung Flügelrahmen unten in Kämpferfeld: yes; Anzeige-Standards Code - 2:GER, 3:CHE, 4:AUT: 2; Fenster gehört zum Raum, in den es öffnet: no; Preis: 0; Komplette Glasfläche: 0; Umfang der Glasfläche: 0; Selbstschließend: no; Selbstschließend Index: 2; Gruppe Typ (FM_Type): Fenster; Gruppe Typ (iFMType): 999; Objektgewicht: 0; Objektgewichtseinheit: kg; Fenster Ausrichtung Definition: 0; Fenster Ausrichtung: L; Breite Wert: Außen Anschlag Maß; Breite: 180,00; Höhe Wert: Höhe Fensterlaibung; Höhe: 240,00; Wert ID Nummer: 0; zu Raum ID innen Wert: Eigene; zu Raum ID außen Wert: Eigene
Brandschutz 4102-2 - Kennbuchstabe: F
Türen/Fenster - Fenster/Türnummer: 1. OG-R-020-Fenster-007; Öffnungsrichtung: L; Fenster/Türbreite: 1.8 m; Fenster/Türhöhe: 2.4 m
ArchiCADQuantities - Höhe: 2.4 m; Netto-Volumen: 0.146548 m3; Breite: 1.8 m; Höhenangabe zum Projekt-Nullpunkt: 3.9 m; Höhe zu 1. Referenzhöhe: 3.9 m; Höhe zu 2. Referenzhöhe: 3.9 m; Höhe zu Meereshöhe: 19.9 m; Höhe zu verknüpftem/Ursprungsgeschoss: 0.15 m; Abstand zu Ursprungsgeschoss: 0.15 m; Oberflächenbereich: 14.4812 m2; F/T Volumen der Öffnung: 1.62 m3; F/T nominales Volumen der Öffnung: 1.62 m3; F/T Oberfläche der Öffnung: 14.4812 m2; F/T Öffnung Nominaler Oberflächenbereich: 4.32 m2; F/T Öffnungsbreite auf der Anschlagseite: 1.8 m; F/T Höhe der Öffnung auf der Anschlagseite: 2.4 m; F/T Öffnungsbreite gegenüber der Anschlagseite: 1.8 m; F/T Höhe der Öffnung gegenüber der Anschlagseite: 2.4 m; F/T Oberfläche der Öffnung auf der Anschlagseite: 4.32 m2; F/T Oberfläche der Öffnung gegenüber der Anschlagseite: 4.32 m2; Nominale F/T Öffnungsbreite auf der Anschlagseite: 1.8 m; Nominale F/T Höhe der Öffnung auf der Anschlagseite: 2.4 m; Nominale F/T Öffnungsbreite gegenüber der Anschlagseite: 1.8 m; Nominale F/T Höhe der Öffnung gegenüber der Anschlagseite: 2.4 m; Nominale F/T Öffnungsoberfläche auf der Anschlagsseite: 4.32 m2; Nominale F/T Öffnungsoberfläche auf der Seite gegenüber der Anschlagsseite: 4.32 m2; Brüstungshöhe: 0.15 m; F/T nominale Brüstungs-/Schwellenhöhe: 0.15 m; F/T Brüstungs-/Schwellenhöhe auf der Anschlagseite: 0.05 m; F/T Brüstungs-/Schwellenhöhe gegenüber der Anschlagseite: 0.05 m; F/T nominale Sturzhöhe: 2.55 m; F/T Sturzhöhe auf der Anschlagseite: 2.45 m; F/T Sturzhöhe gegenüber der Anschlagseite: 2.45 m; Wanddicke: 0.375 m; Rahmen-Stärke: 0.07 m
AC_Equantity_2-Flügelfenster_22 - NominaleBreite: 1.8 m; NominaleHöhe: 2.4 m; Z Größe: 1 m; Untere Ebene: 1 m; Obere Ebene: 0 m; Brüstungshöhe zum aktuellen Geschoss: 0.15 m; Laibung zum Wandkern: 0 m; Anschließende Wanddicke: 0.3 m; Verbundene Wand Dicke 2: 0.375 m; Verbundene Wand Dicke 1: 0.375 m; Breite Eck-Profil: 0 m; Stärke Eck-Profil: 0.06 m; Versatz Eck-Profil: 0 m; Einbautoleranz links: 0 m; Einbautoleranz rechts: 0 m; Einbautoleranz oben: 0 m; Einbautoleranz unten: 0 m; Toleranz außen links: 0 m; Toleranz innen links: 0 m; Toleranz außen rechts: 0 m; Toleranz innen rechts: 0 m; Toleranz außen oben: 0 m; Toleranz innen oben: 0 m; Toleranz außen unten: 0 m; Toleranz innen unten: 0 m; Rohbauöffnung Breite: 1.8 m; Rohbauöffnung Höhe: 2.4 m; Architekturlichte Breite: 1.8 m; Architekturlichte Höhe: 2.4 m; Rahmen Breite: 1.8 m; Rahmen Höhe: 2.4 m; Breite Baurichtmaß: 1.8 m; Höhe Baurichtmaß: 2.4 m; Höhe Kämpfer: 1.05 m; Höhe Hauptflügel: 0.3 m; Rahmen-Breite: 0.08 m; Rahmen-Stärke 1:100: 0.05 m; Breite rechts: 0.08 m; Breite links: 0.08 m; Breite Oben (gs_stb_ob): 0.08 m; Breite Unten (gs_stb_u): 0.08 m; Rahmen-Stärke: 0.07 m; Flügelrahmen-Breite: 0.08 m; Breite Oben (gs_rab_ob): 0.08 m; Breite Unten (gs_rab_u): 0.08 m; Flügelrahmen-Stärke: 0.07 m; Falzbreite: 0.02 m; Falztiefe: 0.04 m; Glasstärke: 0.02 m; Gitter Breite: 0.025 m; Gitter Stärke: 0.025 m; Breite Flügel 1: 0.6 m; Querbalken oben Breite: 0.02 m; Breite Seite 1 (gs_tw_right_out): 0.1 m; Breite Seite 2 (gs_tw_left_out): 0.1 m; Breite oben (gs_tw_top_out): 0.1 m; Breite unten (gs_tw_bottom_out): 0.1 m; Stärke an Wand (gs_trim_thk_out): 0.025 m; Stärke in Wandloch (gs_trim_width_out): 0.025 m; Abstand (gs_trim_offs_out): 0 m; Auskragung (gs_trim_jambext_nosing_out): 0.05 m; Oberer Überstand (gs_trimov_top_right_out): 0.1 m; Erweiterung unten (gs_trimov_bot_right_out): 0.1 m; Erweiterung unten (casingOverhangBottomSideOut): 0.05 m; Breite Seite 1 (gs_tw_right_in): 0.1 m; Breite Seite 2 (gs_tw_left_in): 0.1 m; Breite oben (gs_tw_top_in): 0.1 m; Breite unten (gs_tw_bottom_in): 0.1 m; Stärke an Wand (gs_trim_thk_in): 0.025 m; Stärke in Wandloch (gs_trim_width_in): 0.025 m; Abstand (gs_trim_offs_in): 0 m; Auskragung (gs_trim_jambext_nosing_in): 0.03 m; Oberer Überstand (gs_trimov_top_right_in): 0.1 m; Erweiterung unten (gs_trimov_bot_right_in): 0.1 m; Fensterbank Stärke (gs_sill_thk): 0.05 m; Stärke Fensterbank vorne: 0.03 m; Fensterbank Ansicht: 0 m; Überlappungshöhe Fensterbank: 0.01 m; Stärke Fensterbankkante: 0.03 m; Fensterbank Überstand: 0.03 m; Fensterbank Stärke (gs_sill_element_thk): 0.02 m; Überhang Fensterbank Links: 0 m; Überhang Fensterbank Rechts: 0 m; Falztiefe Fensterbank: 0 m; Hintere Lochtiefe (gs_sill_holeDepthBehind): 0 m; Breite Fensterbank: 0.21 m; Fensterbank obere Breite: 0.01 m; Fensterbank obere Höhe: 0.01 m; Steinbreite (gs_brick_sill_br_thk): 0.065 m; Fugenbreite (gs_brick_sill_mort_thk): 0.015 m; Stärke Fensterbank Innen: 0.025 m; Überstand Fensterbank Innen: 0.03 m; Überhang Fensterbank Innen Links: 0.03 m; Überhang Fensterbank Innen Rechts: 0.03 m; Brett Falztiefe: 0 m; Rahmenbreite: 0.155 m; Abstand zwischen Bogen und Fenster: 0 m; Sturz Überhang links: 0 m; Sturz Überhang rechts: 0 m; Sturz Bogenhöhe: 0.03 m; Projektion Sturz: 0 m; Höhe Sichtmauerwerk: 0.24 m; Tiefe Sichtmauerwerk: 0.15 m; Hintere Lochtiefe (gs_masonry_arch_rearHoleDepth): 0 m; Steinbreite (gs_masonry_arch_brick_thk): 0.065 m; Fugenbreite (gs_masonry_arch_mort_thk): 0.01 m; Keilsteinbreite: 0.1 m; Überhang Keilstein: 0 m; Projektion Keilstein: 0.01 m; Breite Links/Rechts: 0.12 m; Höhe oben: 0.25 m; Höhe unten: 0.25 m; Höhe Faschen rechts: 1.5 m; Höhe Faschen links: 1.5 m; Tiefe Faschen: 0.165 m; Steinbreite (gs_faschen_brick_thk): 0.065 m; Fugenbreite (gs_faschen_mort_thk): 0.01 m; Anschlagtiefe (gs_wido_sill): 0.18 m; Anschlagtiefe (AC_wido_sill): 0.18 m; Anschlagstiefe Seite 2: 0.05 m; Anschlagstiefe: 0.05 m; Innerer Anschlagstiefe Seite 2 (gs_reveal_splayed_innerLeft): 0.06 m; Innerer Anschlagstiefe (gs_reveal_splayed_innerRight): 0.06 m; Innerer Anschlagstiefe Seite 2 (gs_reveal_double_innerLeft): 0.06 m; Innerer Anschlagstiefe (gs_reveal_double_innerRight): 0.06 m; Tiefe des oberen Anschlags: 0.05 m; Tiefe des unteren Anschlags: 0.06 m; Tiefe Sturz Innen (gs_reveal_splayed_innerTop): 0.06 m; Tiefe Laibung Innen (gs_reveal_splayed_innerBottom): 0.06 m; Tiefe Sturz Innen (gs_reveal_double_innerTop): 0.06 m; Tiefe Laibung Innen (gs_reveal_double_innerBottom): 0 m; Tiefe äußerer Anschlag: 0.05 m; Seitenabschrägung Breite Seite 2: -1 m; Seitenabschrägung Breite Seite: -1 m; Obere Seitenabschrägung Breite: -1 m; Untere Seitenabschrägung Breite: -1 m; Außenabschrägung Breite Seite 2: -1 m; Außenabschrägung Breite Side: -1 m; Äußere Abschrägung Breite an oberer Seite: -1 m; Breite äußere Abschrägung an Unterseite: -1 m; Einbaurahmen-Stärke: 0.06 m; Einbaurahmen-Breite links: 0.06 m; Einbaurahmen-Breite rechts: 0.06 m; Einbaurahmen-Breite oben: 0.06 m; Einbaurahmen-Breite unten: 0.06 m; Abstand Schicht zu Abschluss: 0 m; Anschluss Breite: 0.038 m; Anschluss Stärke: 0.1 m; Streifen-Stärke: 0.025 m; Profilbreite: 0.075 m; Eigene Stärke: 0.015 m; Schichtüberlappung zu Rahmen-Tiefe: 0 m; Max. Putzdicke: 0.04 m; Tiefe Heizk.: 0.05 m; Breite Heizkörpernische: 1 m; Überstand Seite 1: 0 m; Überstand Seite 2: 0 m; Höhe Heizkörpernische: 0.9 m; Erweiterung unten (gs_parapet_botelev): 0 m; Sturzbrett Stärke: 0.025 m; Sturzbrett Überstand: 0.03 m; Verkleidungsbreite Links: 0 m; Verkleidungsbreite Rechts: 0 m; Verkleidungsstärke: 0.12 m; Höhe Hintersturz (gs_hsturz_height): 0.08 m; Höhe Hintersturz (gs_hhs): 0.2 m; Stärke vorne: 0.06 m; Tiefe von Wandebene: 0 m; Stärke Dämmung 1: 0.03 m; Stärke Dämmung 2: 0.03 m; Vorstand v. Fenster: 0 m; Stärke Metalplatte: 0.005 m; Breite: 0.07 m; Breite oben (efb_t1): 0.3 m; Stärke oben: 0.09 m; Breite Sturz außen: 0.06 m; Breite unten (efsu): 0.07 m; Fensterbank Breite: 0.07 m; Vorstand v. Fassade: 0.025 m; Vorstand v. Fassade Fensterbank: 0.05 m; Paneelhöhe: 1.5 m; Innerer Versatz: 0.02 m; Schließtiefe: 0 m; Extra Rahmen Breite: 0.04 m; Extra Rahmen Stärke: 0.03 m; Geländerbreite: 0.03 m; Türzapfen-Länge: 0.02 m; Türzapfen-Radius: 0.005 m; Paneel-Abstand: 0.006 m; Außen-Überhang: 0 m; Innere Paneel-Breite: 0.12 m; 3D-Öffnungslänge: 1.5 m; 3D geschlossene Länge: 0 m; 3D-Öffnungslänge 1 (gs_shutter_opLength_1): 0.56 m; 3D-Öffnungslänge 1 (gs_shutter_opLength_2): 0.14 m; 3D-Öffnungshöhe: 1.5 m; 3D geschlossene Höhe: 0 m; Paneeldicke: 0.05 m; Paneelrahmen-Breite: 0.05 m; Rahmen-Breite unten: 0.05 m; Paneel Breite: 0 m; Paneelfüllungs-Stärke: 0.01 m; Stärke Lamelle: 0.01 m; Breite Lamellen: 0.04 m; Horizontaler Rahmen Teiler-Breite: 0.05 m; Vertikaler Rahmen Teiler-Breite: 0.05 m; Durchmesser Öffnung: 0.01 m; Breite des vertikalen Bretts: 0.1 m; Z-Rahmen-Breite: 0.05 m; Z-Rahmen-Stärke: 0.025 m; Stärke der vertikalen Bretter: 0.025 m; Stärke der horizontalen Bretter: 0.025 m; Ungefähre Breite der vertikalen Bretter (gs_shutPanel_vertBoardW): 0.08 m; Ungefähre Breite der vertikalen Bretter (gs_shutPanel_horBoardW): 0.115 m; Kasten Höhe (gs_shutRoll_boxHeight): 0.2 m; Kasten Tiefe: 0.15 m; Kasten Abstand links: 0 m; Kasten Abstand recht: 0 m; Tiefe Schiene: 0.0725 m; Abstand von Wand: 0 m; Abstand oben (gs_shutRoll_distFromHead): 0 m; Rollladen-Lamellen-Höhe: 0.05 m; Kasten Höhe (gs_shutLam_boxHeight): 0.2 m; Kasten-Breite (gs_shutLam_boxWidth): 0.15 m; Abdeckungstiefe: 0.04 m; Vorstand v. Wand: 0 m; Abstand oben (gs_shutLam_distFromHead): -0.2 m; Breite einer Rollade (gs_shutLam_segmentWidth): 0.06 m; Kasten Höhe (gs_shutLam2_boxHeight): 0.06 m; Kasten-Breite (gs_shutLam2_boxWidth): 0.06 m; Abst. v. Fenster: 0.06 m; Abstand oben (gs_shutLam2_distFromHead): 0.06 m; Kasten-Achshöhe von OK: 0 m; Breite einer Rollade (gs_shutLam2_segmentWidth): 0.06 m; Horizontaler Vorsprung (gs_ah1): 0.05 m; Vertikaler Abstand (gs_av1): 0.045 m; Horizontaler Vorsprung (gs_ah2): -0.05 m; Vertikaler Abstand (gs_av2): 0.045 m; Horizontaler Vorsprung (gs_ah3): -0.05 m; Vertikaler Abstand (gs_av3): 0 m; Horizontaler Vorsprung (gs_ah4): 0.05 m; Vertikaler Abstand (gs_av4): 0 m; Horizontaler Vorsprung (gs_PlanViewInfos_T5_xOffset): 0 m; Vertikaler Abstand (gs_PlanViewInfos_T5_yOffset): -0.15 m; Horizontaler Vorsprung (gs_PlanViewInfos_T6_xOffset): 0.15 m; Vertikaler Abstand (gs_PlanViewInfos_T6_yOffset): -0.15 m; Schriftgröße (modell) (gs_sggri): 0.075 m; Eigene Kote Öffnung roh: 0 m; Eigene Kote Sturz fertig: 0 m; Eigene Koten Brüstung fertig: 0 m; Höhe Fußboden: 0.05 m; Eigene Koten Brüstung roh: 0 m; Schriftgröße (modell) (gs_lsize): 0.075 m; Position X: 0 m; Position Y: 0.4 m; Zeilenabstand (modell): 0.05 m; Feste breite in mm (0= autom.): 0 m; Text Position X: 0 m; Text Position Y: 0.4 m; Schriftgröße (modell) (gs_IDText_fontSize_model): 0.1 m; Position Links: 0 m; Position Rechts: 0 m; Breite Links: 0 m; Breite Rechts: 0 m; Tiefe Links: 0.01 m; Tiefe Rechts: 0.01 m; AC Linkes Öffnungsübermaß: 0 m; AC Rechtes Öffnungsübermaß: 0 m; AC Oberes Öffnungsübermaß: 0 m; AC Unteres Öffnungsübermaß: 0 m

# IfcBuildingElementProxy: 3-Flügelfenster 22, Fenster-011
In: 1. OG
Classification: Fenster (ARCHICAD Klassifizierung)
Pset_FireRatingProperties - FireResistanceRating: F30
ArchiCADProperties - Element ID: Fenster-011; Hotlink und Element-ID: Fenster-011; Ebene: Wand Aussen; Bibliothekselement-Name: 3-Flügelfenster 22; Baustoff / Mehrschichtiger Aufbau / Profil / Schraffur: Misch-Schraffur 0%; Schraffurtyp: Misch-Schraffur 0%; Kollidierende Räume: Grundfläche Gebäude Nachgezogen; Obergeschoss; Wohnung1 OG; Zugehöriger Raumname: Luftraum Dach; Zugehörige Raumnummer: R-012; Geschützt: no; Ursprungsgeschoss Name: 1. OG; Ursprungsgeschoss Nummer: 1; Typ: Fenster; Überobjekt-ID: Wand-012; Oberfläche (Alle): Holz Nussbaum; Glas Normalglas; Fensterrahmen; Von Raum: Luftraum Dach; Von Raum-Nummer: R-012; zu Raum: Wohnung1 OG; Zu Raum-Nummer: R-021; Lage: Nicht definiert; Tragende Funktion: Nicht tragende Elemente; Anzeigen auf Umbau-Filter: Alle relevanten Filter; Umbau-Status: Bestand; Anschlagsmaße: 2,483×1,886; Größe Wandloch: 2,483×1,886; Größe laut Eingabe: 2,483×1,886; Nominale B x H: 2,483×1,886; Nominale B x H x T: 2,483×1,886×0,375; Wandstruktur: WA | 2 Schichtig KS; Öffnung Bibliothekselementname: 3-Flügelfenster 22; Öffnungsseite Schraffurindex: Misch-Schraffur 0%; ARCHICAD Klassifizierung - 22: Fenster
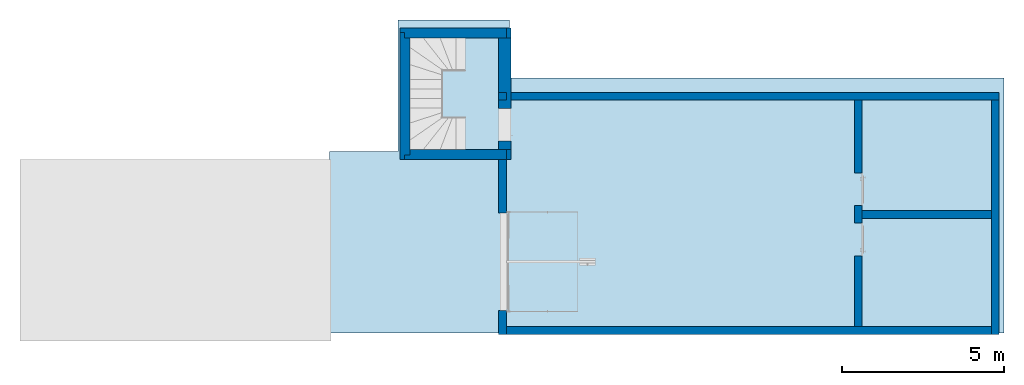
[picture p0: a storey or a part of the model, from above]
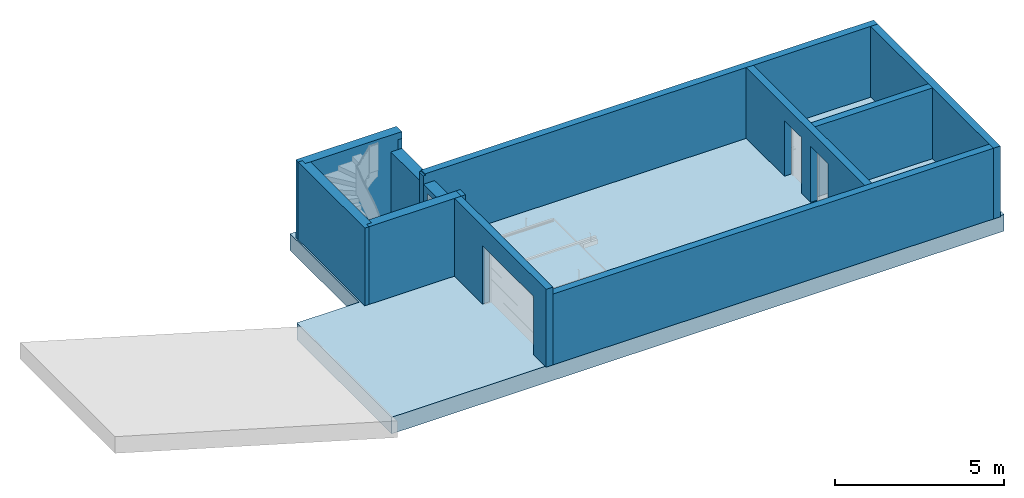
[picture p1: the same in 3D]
Properties of the parts of a building model (IFC4), part 7 of 13

# IfcBuildingElementProxy: 5-Flügelfenster 22 (2)
AC_Equantity_5-Flügelfenster_22 - NominaleHöhe: 2.4 m; Z Größe: 1 m; Untere Ebene: 1 m; Obere Ebene: 0 m; Laibung zum Wandkern: 0 m; Anschließende Wanddicke: 0.3 m; Verbundene Wand Dicke 2: 0.375 m; Verbundene Wand Dicke 1: 0.375 m; Breite Eck-Profil: 0 m; Stärke Eck-Profil: 0.06 m; Versatz Eck-Profil: 0 m; Einbautoleranz links: 0 m; Einbautoleranz rechts: 0 m; Einbautoleranz oben: 0 m; Einbautoleranz unten: 0 m; Toleranz außen links: 0 m; Toleranz innen links: 0 m; Toleranz außen rechts: 0 m; Toleranz innen rechts: 0 m; Toleranz außen oben: 0 m; Toleranz innen oben: 0 m; Toleranz außen unten: 0 m; Toleranz innen unten: 0 m; Rohbauöffnung Höhe: 2.4 m; Architekturlichte Höhe: 2.4 m; Rahmen Höhe: 2.4 m; Höhe Baurichtmaß: 2.4 m; Höhe Hauptflügel: 0.3 m; Rahmen-Breite: 0.08 m; Rahmen-Stärke 1:100: 0.05 m; Breite rechts: 0.08 m; Breite links: 0.08 m; Breite Oben (gs_stb_ob): 0.08 m; Breite Unten (gs_stb_u): 0.08 m; Rahmen-Stärke: 0.07 m; Flügelrahmen-Breite: 0.08 m; Breite Oben (gs_rab_ob): 0.08 m; Breite Unten (gs_rab_u): 0.08 m; Flügelrahmen-Stärke: 0.07 m; Falzbreite: 0.02 m; Falztiefe: 0.04 m; Glasstärke: 0.02 m; Gitter Breite: 0.025 m; Gitter Stärke: 0.025 m; Breite Flügel 1: 0.6 m; Breite Flügel 2: 0.6 m; Breite Flügel 3: 0.6 m; Flügel-Breite 4: 0.6 m; Querbalken oben Breite: 0.02 m; Breite Seite 1 (gs_tw_right_out): 0.1 m; Breite Seite 2 (gs_tw_left_out): 0.1 m; Breite oben (gs_tw_top_out): 0.1 m; Breite unten (gs_tw_bottom_out): 0.1 m; Stärke an Wand (gs_trim_thk_out): 0.025 m; Stärke in Wandloch (gs_trim_width_out): 0.025 m; Abstand (gs_trim_offs_out): 0 m; Auskragung (gs_trim_jambext_nosing_out): 0.05 m; Oberer Überstand (gs_trimov_top_right_out): 0.1 m; Erweiterung unten (gs_trimov_bot_right_out): 0.1 m; Erweiterung unten (casingOverhangBottomSideOut): 0.05 m; Breite Seite 1 (gs_tw_right_in): 0.1 m; Breite Seite 2 (gs_tw_left_in): 0.1 m; Breite oben (gs_tw_top_in): 0.1 m; Breite unten (gs_tw_bottom_in): 0.1 m; Stärke an Wand (gs_trim_thk_in): 0.025 m; Stärke in Wandloch (gs_trim_width_in): 0.025 m; Abstand (gs_trim_offs_in): 0 m; Auskragung (gs_trim_jambext_nosing_in): 0.03 m; Oberer Überstand (gs_trimov_top_right_in): 0.1 m; Erweiterung unten (gs_trimov_bot_right_in): 0.1 m; Fensterbank Stärke (gs_sill_thk): 0.05 m; Stärke Fensterbank vorne: 0.03 m; Fensterbank Ansicht: 0 m; Überlappungshöhe Fensterbank: 0.01 m; Stärke Fensterbankkante: 0.03 m; Fensterbank Überstand: 0.03 m; Fensterbank Stärke (gs_sill_element_thk): 0.02 m; Überhang Fensterbank Links: 0 m; Überhang Fensterbank Rechts: 0 m; Falztiefe Fensterbank: 0 m; Hintere Lochtiefe (gs_sill_holeDepthBehind): 0 m; Breite Fensterbank: 0.21 m; Fensterbank obere Breite: 0.01 m; Fensterbank obere Höhe: 0.01 m; Steinbreite (gs_brick_sill_br_thk): 0.065 m; Fugenbreite (gs_brick_sill_mort_thk): 0.015 m; Stärke Fensterbank Innen: 0.025 m; Überstand Fensterbank Innen: 0.03 m; Überhang Fensterbank Innen Links: 0.03 m; Überhang Fensterbank Innen Rechts: 0.03 m; Brett Falztiefe: 0 m; Rahmenbreite: 0.155 m; Abstand zwischen Bogen und Fenster: 0 m; Sturz Überhang links: 0 m; Sturz Überhang rechts: 0 m; Sturz Bogenhöhe: 0.03 m; Projektion Sturz: 0 m; Höhe Sichtmauerwerk: 0.24 m; Tiefe Sichtmauerwerk: 0.15 m; Hintere Lochtiefe (gs_masonry_arch_rearHoleDepth): 0 m; Steinbreite (gs_masonry_arch_brick_thk): 0.065 m; Fugenbreite (gs_masonry_arch_mort_thk): 0.01 m; Keilsteinbreite: 0.1 m; Überhang Keilstein: 0 m; Projektion Keilstein: 0.01 m; Breite Links/Rechts: 0.12 m; Höhe oben: 0.25 m; Höhe unten: 0.25 m; Höhe Faschen rechts: 1.5 m; Höhe Faschen links: 1.5 m; Tiefe Faschen: 0.165 m; Steinbreite (gs_faschen_brick_thk): 0.065 m; Fugenbreite (gs_faschen_mort_thk): 0.01 m; Anschlagtiefe (gs_wido_sill): 0.18 m; Anschlagtiefe (AC_wido_sill): 0.18 m; Anschlagstiefe Seite 2: 0.05 m; Anschlagstiefe: 0.05 m; Innerer Anschlagstiefe Seite 2 (gs_reveal_splayed_innerLeft): 0.06 m; Innerer Anschlagstiefe (gs_reveal_splayed_innerRight): 0.06 m; Innerer Anschlagstiefe Seite 2 (gs_reveal_double_innerLeft): 0.06 m; Innerer Anschlagstiefe (gs_reveal_double_innerRight): 0.06 m; Tiefe des oberen Anschlags: 0.05 m; Tiefe des unteren Anschlags: 0.06 m; Tiefe Sturz Innen (gs_reveal_splayed_innerTop): 0.06 m; Tiefe Laibung Innen (gs_reveal_splayed_innerBottom): 0.06 m; Tiefe Sturz Innen (gs_reveal_double_innerTop): 0.06 m; Tiefe Laibung Innen (gs_reveal_double_innerBottom): 0 m; Tiefe äußerer Anschlag: 0.05 m; Seitenabschrägung Breite Seite 2: -1 m; Seitenabschrägung Breite Seite: -1 m; Obere Seitenabschrägung Breite: -1 m; Untere Seitenabschrägung Breite: -1 m; Außenabschrägung Breite Seite 2: -1 m; Außenabschrägung Breite Side: -1 m; Äußere Abschrägung Breite an oberer Seite: -1 m; Breite äußere Abschrägung an Unterseite: -1 m; Einbaurahmen-Stärke: 0.06 m; Einbaurahmen-Breite links: 0.06 m; Einbaurahmen-Breite rechts: 0.06 m; Einbaurahmen-Breite oben: 0.06 m; Einbaurahmen-Breite unten: 0.06 m; Abstand Schicht zu Abschluss: 0 m; Anschluss Breite: 0.038 m; Anschluss Stärke: 0.1 m; Streifen-Stärke: 0.025 m; Profilbreite: 0.075 m; Eigene Stärke: 0.015 m; Schichtüberlappung zu Rahmen-Tiefe: 0 m; Max. Putzdicke: 0.04 m; Tiefe Heizk.: 0.05 m; Breite Heizkörpernische: 1 m; Überstand Seite 1: 0 m; Überstand Seite 2: 0 m; Höhe Heizkörpernische: 0.9 m; Erweiterung unten (gs_parapet_botelev): 0 m; Sturzbrett Stärke: 0.025 m; Sturzbrett Überstand: 0.03 m; Verkleidungsbreite Links: 0 m; Verkleidungsbreite Rechts: 0 m; Verkleidungsstärke: 0.12 m; Höhe Hintersturz (gs_hsturz_height): 0.08 m; Höhe Hintersturz (gs_hhs): 0.2 m; Stärke vorne: 0.06 m; Tiefe von Wandebene: 0 m; Stärke Dämmung 1: 0.03 m; Stärke Dämmung 2: 0.03 m; Vorstand v. Fenster: 0 m; Stärke Metalplatte: 0.005 m; Breite: 0.07 m; Breite oben (efb_t1): 0.3 m; Stärke oben: 0.09 m; Breite Sturz außen: 0.06 m; Breite unten (efsu): 0.07 m; Fensterbank Breite: 0.07 m; Vorstand v. Fassade: 0.025 m; Vorstand v. Fassade Fensterbank: 0.05 m; Paneelhöhe: 1.5 m; Innerer Versatz: 0.02 m; Schließtiefe: 0 m; Extra Rahmen Breite: 0.04 m; Extra Rahmen Stärke: 0.03 m; Geländerbreite: 0.03 m; Türzapfen-Länge: 0.02 m; Türzapfen-Radius: 0.005 m; Paneel-Abstand: 0.006 m; Außen-Überhang: 0 m; Innere Paneel-Breite: 0.12 m; 3D-Öffnungslänge: 1.5 m; 3D geschlossene Länge: 0 m; 3D-Öffnungslänge 1 (gs_shutter_opLength_1): 0.56 m; 3D-Öffnungslänge 1 (gs_shutter_opLength_2): 0.14 m; 3D-Öffnungshöhe: 1.5 m; 3D geschlossene Höhe: 0 m; Paneeldicke: 0.05 m; Paneelrahmen-Breite: 0.05 m; Rahmen-Breite unten: 0.05 m; Paneel Breite: 0 m; Paneelfüllungs-Stärke: 0.01 m; Stärke Lamelle: 0.01 m; Breite Lamellen: 0.04 m; Horizontaler Rahmen Teiler-Breite: 0.05 m; Vertikaler Rahmen Teiler-Breite: 0.05 m; Durchmesser Öffnung: 0.01 m; Breite des vertikalen Bretts: 0.1 m; Z-Rahmen-Breite: 0.05 m; Z-Rahmen-Stärke: 0.025 m; Stärke der vertikalen Bretter: 0.025 m; Stärke der horizontalen Bretter: 0.025 m; Ungefähre Breite der vertikalen Bretter (gs_shutPanel_vertBoardW): 0.08 m; Ungefähre Breite der vertikalen Bretter (gs_shutPanel_horBoardW): 0.115 m; Kasten Höhe (gs_shutRoll_boxHeight): 0.2 m; Kasten Tiefe: 0.15 m; Kasten Abstand links: 0 m; Kasten Abstand recht: 0 m; Tiefe Schiene: 0.0725 m; Abstand von Wand: 0 m; Abstand oben (gs_shutRoll_distFromHead): 0 m; Rollladen-Lamellen-Höhe: 0.05 m; Kasten Höhe (gs_shutLam_boxHeight): 0.2 m; Kasten-Breite (gs_shutLam_boxWidth): 0.15 m; Abdeckungstiefe: 0.04 m; Vorstand v. Wand: 0 m; Abstand oben (gs_shutLam_distFromHead): -0.2 m; Breite einer Rollade (gs_shutLam_segmentWidth): 0.06 m; Kasten Höhe (gs_shutLam2_boxHeight): 0.06 m; Kasten-Breite (gs_shutLam2_boxWidth): 0.06 m; Abst. v. Fenster: 0.06 m; Abstand oben (gs_shutLam2_distFromHead): 0.06 m; Kasten-Achshöhe von OK: 0 m; Breite einer Rollade (gs_shutLam2_segmentWidth): 0.06 m; Horizontaler Vorsprung (gs_ah1): 0.05 m; Vertikaler Abstand (gs_av1): 0.045 m; Horizontaler Vorsprung (gs_ah2): -0.05 m; Vertikaler Abstand (gs_av2): 0.045 m; Horizontaler Vorsprung (gs_ah3): -0.05 m; Vertikaler Abstand (gs_av3): 0 m; Horizontaler Vorsprung (gs_ah4): 0.05 m; Vertikaler Abstand (gs_av4): 0 m; Horizontaler Vorsprung (gs_PlanViewInfos_T5_xOffset): 0 m; Vertikaler Abstand (gs_PlanViewInfos_T5_yOffset): -0.15 m; Horizontaler Vorsprung (gs_PlanViewInfos_T6_xOffset): 0.15 m; Vertikaler Abstand (gs_PlanViewInfos_T6_yOffset): -0.15 m; Schriftgröße (modell) (gs_sggri): 0.075 m; Eigene Kote Öffnung roh: 0 m; Eigene Kote Sturz fertig: 0 m; Eigene Koten Brüstung fertig: 0 m; Höhe Fußboden: 0.05 m; Eigene Koten Brüstung roh: 0 m; Schriftgröße (modell) (gs_lsize): 0.075 m; Position X: 0 m; Position Y: 0.4 m; Zeilenabstand (modell): 0.05 m; Feste breite in mm (0= autom.): 0 m; Text Position X: 0 m; Text Position Y: 0.4 m; Schriftgröße (modell) (gs_IDText_fontSize_model): 0.1 m; Position Links: 0 m; Position Rechts: 0 m; Breite Links: 0 m; Breite Rechts: 0 m; Tiefe Links: 0.01 m; Tiefe Rechts: 0.01 m; AC Linkes Öffnungsübermaß: 0 m; AC Rechtes Öffnungsübermaß: 0 m; AC Oberes Öffnungsübermaß: 0 m; AC Unteres Öffnungsübermaß: 0 m
Name | In | Kollidierende Räume | Zugehöriger Raumname = Von Raum | Zugehörige Raumnummer = Von Raum-Nummer | Ursprungsgeschoss Name | Ursprungsgeschoss Nummer | Überobjekt-ID | zu Raum | Zu Raum-Nummer | Anschlagsmaße = Größe Wandloch = Größe laut Eingabe = Nominale B x H | Nominale B x H x T | Oberlicht | Oberlicht Geteilt | AC_Pset_5-Flügelfenster_22, Breite | Fenster/Türnummer | Netto-Volumen (m3) | ArchiCADQuantities, Breite (m) = F/T Öffnungsbreite auf der Anschlagseite (m) = F/T Öffnungsbreite gegenüber der Anschlagseite (m) = Nominale F/T Öffnungsbreite auf der Anschlagseite (m) = Nominale F/T Öffnungsbreite gegenüber der Anschlagseite (m) = NominaleBreite (m) = Rohbauöffnung Breite (m) = Architekturlichte Breite (m) = Rahmen Breite (m) = Breite Baurichtmaß (m) = Fenster/Türbreite (m) | Höhenangabe zum Projekt-Nullpunkt (m) = Höhe zu 1. Referenzhöhe (m) = Höhe zu 2. Referenzhöhe (m) | Höhe zu Meereshöhe (m) | Höhe zu verknüpftem/Ursprungsgeschoss (m) = Abstand zu Ursprungsgeschoss (m) = Brüstungshöhe (m) = F/T nominale Brüstungs-/Schwellenhöhe (m) = Brüstungshöhe zum aktuellen Geschoss (m) | Oberflächenbereich (m2) = F/T Oberfläche der Öffnung (m2) | F/T Volumen der Öffnung (m3) = F/T nominales Volumen der Öffnung (m3) | F/T Öffnung Nominaler Oberflächenbereich (m2) = F/T Oberfläche der Öffnung auf der Anschlagseite (m2) = F/T Oberfläche der Öffnung gegenüber der Anschlagseite (m2) = Nominale F/T Öffnungsoberfläche auf der Anschlagsseite (m2) = Nominale F/T Öffnungsoberfläche auf der Seite gegenüber der Anschlagsseite (m2) | F/T Brüstungs-/Schwellenhöhe auf der Anschlagseite (m) = F/T Brüstungs-/Schwellenhöhe gegenüber der Anschlagseite (m) | F/T nominale Sturzhöhe (m) | F/T Sturzhöhe auf der Anschlagseite (m) = F/T Sturzhöhe gegenüber der Anschlagseite (m) | Höhe Kämpfer (m)
Fenster-010 | EG | Erdgeschoss; Grundfläche Gebäude Nachgezogen; Wohnung1 EG | Terrasse | R-002 | EG | 0 | Wand-005 | Wohnen | R-005 | 5,000×2,400 | 5,000×2,400×0,375 | no | yes | 500,00 | EG-R-002-Fenster-010 | 0.359495 | 5 | 0.2 | 16.2 | 0.2 | 38.2492 | 4.5 | 12 | 0.1 | 2.6 | 2.5 | 1.05
Fenster-010 | 1. OG | Grundfläche Gebäude Nachgezogen; Obergeschoss; Wohnung2 OG | Wohnung2 OG | R-020 | 1. OG | 1 | Wand-004 | Loft | R-003 | 4,010×2,400 | 4,010×2,400×0,375 | yes | no | 401,00 | 1. OG-R-020-Fenster-010 | 0.343527 | 4.01 | 3.9 | 19.9 | 0.15 | 33.7674 | 3.609 | 9.624 | 0.05 | 2.55 | 2.45 | 1.8

# IfcBuildingElementProxy: Arbeitsplatte 22 (2)
In: EG
Classification: Möbel (ARCHICAD Klassifizierung)
ArchiCADProperties - Element ID: Küche-010; Hotlink und Element-ID: Küche-010; Ebene: Möblierung; Bibliothekselement-Name: Arbeitsplatte 22; Baustoff / Mehrschichtiger Aufbau / Profil / Schraffur: Nur Hintergrund-Stift; Schraffurtyp: Nur Hintergrund-Stift; Zugehöriger Raumname: Wohnen; Geschützt: no; Ursprungsgeschoss Name: EG; Ursprungsgeschoss Nummer: 0; Typ: Objekt; Überobjekt-ID: Küche-010; Oberfläche (Alle): Naturstein Schiefer; Metall Stahl, poliert; Farbe, weiß; Lage: Innen; Tragende Funktion: Nicht definiert; Anzeigen auf Umbau-Filter: Alle relevanten Filter; Umbau-Status: Bestand; Oberfläche: Kunststoff PE, weiss; ARCHICAD Klassifizierung - 22: Möbel
AC_Pset_Arbeitsplatte_22 - 2D-Fixpunkte in 3D zeigen: no; Vordefinierte Werte: 0; Programm einstellen: no; Schrank Höhe: 4; Schrank Tiefe: 7; Rechte Kante: 1; Rechter Kantenwinkel: 45 deg; Linke Kante: 1; Linker Kantenwinkel: 45 deg; Vordere Blende: yes; Außenseite hinten: no; Linke Blende: no; Rechte Blende: yes; Blenden-Querbalken: 1; Linker Spritzschutz: no; Rechter Spritzschutz: no; Spritzschutz (bBackSplash): yes; Anzahl Spülbecken: 1; Spülbecken Typ: 4; Spülenmontage: 1; Spülensymbol: 1; Spülen-Positionierung: 3; Hahn-Typ (tapGroup): Einhebelmischer; Hahn-Typ (iTapGroup): 1; Zapfentyp (gs_tap_type): Stil 3; Zapfentyp (gs_tap_type_m): 7; Typ Stopfen-Symbol (TapSymbol): Detailliert; Typ Stopfen-Symbol (TapSymbol_m): 2; 2D-Detaillierungsgrad: 1; Arbeistplatten-Linien an seitlichen Kanten: 4; Arbeistplatten Schraffur: yes; Spüle Konturlinien-Stift: Konturstift; Konturstift: Konturstift; Schraffur: Nur Hintergrund-Stift; Schraffur-Vordergrundstift: Fenster Hintergrund; Schraffur-Hintergrundstift: Transparent; 3D-Detaillierungsgrad: 1; Auflösung: 12; Schatten: yes; 3D-Konturstift: Konturstift; Arbeitsplatte: Naturstein Schiefer; Spritzschutz (splashSurface): Naturstein Schiefer; Blende: Naturstein Schiefer; Spüle: Farbe, weiß; Wasserhahn: Metall Stahl, poliert; Anschluss: Metall Stahl, poliert; System Oberflächenmaterial benutzen: no; System Oberflächenmaterial: 0; Warmwasseranschluss (ConStatus_1): yes; Werkzeug-Typ (ConToolType_1): 2; HKLSE System (ConSystem_1): Undefiniert; Form-Typ (ConType_1): Kreis; Kaltwasseranschluss 1: yes; Werkzeug-Typ (ConToolType_2): 2; HKLSE System (ConSystem_2): Undefiniert; Form-Typ (ConType_2): Kreis; Abwasseranschluss 1: yes; Werkzeug-Typ (ConToolType_3): 2; HKLSE System (ConSystem_3): Undefiniert; Form-Typ (ConType_3): Kreis; Warmwasseranschluss (ConStatus_4): yes; Werkzeug-Typ (ConToolType_4): 2; HKLSE System (ConSystem_4): Undefiniert; Form-Typ (ConType_4): Kreis; Kaltwasseranschluss 2: yes; Werkzeug-Typ (ConToolType_5): 2; HKLSE System (ConSystem_5): Undefiniert; Form-Typ (ConType_5): Kreis; Abwasseranschluss 2: yes; Werkzeug-Typ (ConToolType_6): 2; HKLSE System (ConSystem_6): Undefiniert; Form-Typ (ConType_6): Kreis; Anzahl Arbeistplatte: 1; Anzahl Blende: 2; Anzahl Spritzschut: 1; IFC-Subtype: 0; IFC vordefinierter Typ: 0; Fläche: 0; Volumen: 0; Preis: 0; Gruppe Typ (FM_Type): HKLSE Ausstattung; Gruppe Typ (iFMType): 12; Objektgewicht: 0; Objektgewichtseinheit: kg; Anschlussanzahl: 6
ArchiCADQuantities - Fläche: 2.27986 m2; Höhe: 0.2 m; Netto-Volumen: 0.0656046 m3; Breite: 0.6 m; Oberflächenbereich: 6.44047 m2; Länge (A): 3.79977 m
AC_Equantity_Arbeitsplatte_22 - Maß 1: 3.79977 m; Maß 2: 0.6 m; Höhe: 0.2 m; Untere Ebene: 0.7 m; Obere Ebene: 0.9 m; Schrank Höhe: 0.9 m; Tiefe Arbeitsplatte: 0.6 m; Breite Arbeitsplatte: 3.79977 m; Stärke Arbeitsplatte: 0.03 m; Abstand zu rechter Ecke: 0 m; Abstand zu linker Ecke: 0 m; Blende Höhe: 0.06 m; Blende Dicke: 0.02 m; Blende Versatz: 0.01 m; Spritzschutz Höhe: 0.05 m; Spritzschutz Dicke: 0.02 m; Becken-Breite: 0.8 m; Tiefe Spülbecken: 0.55 m; Abstand Spüle zur Mitte: 1.09988 m; Spülenabstand von rechter Ecke (sinkDistX_Right): 0.8 m; Spülenabstand von linker Ecke (sinkDistX_Left): 2.99977 m; Spülenabstand vertikal: -0.02 m; Spülenabstand von rechter Ecke (rightSink_XDist): 0.508 m; Spülenabstand von linker Ecke (leftSink_XDist): 0.508 m; Hahn-Höhe: 0.508 m; Nominale Tiefe (ConNominalDepth_1): 0.025 m; Außendurchmesser (ConWidth_1): 0.027 m; Außentiefe (ConDepth_1): 0.027 m; Wanddicke (ConWallThickness_1): 0.001 m; Anschluss-Länge (ConLength_1): 0.02 m; Anschluss Durchmesser (ConConnectorWidth_1): 0.04 m; Anschluss-Tiefe (ConConnectorDepth_1): 0 m; Anschluss-Breite (ConConnectorWidth2_1): 0.005 m; Anschluss-Position X (ConPosX_1): -0.1 m; Anschluss-Position Y (ConPosY_1): -0.0135 m; Anschluss-Position Z (ConPosZ_1): -0.025 m; Nominale Tiefe (ConNominalDepth_2): 0.025 m; Außendurchmesser (ConWidth_2): 0.027 m; Außentiefe (ConDepth_2): 0.027 m; Wanddicke (ConWallThickness_2): 0.001 m; Anschluss-Länge (ConLength_2): 0.02 m; Anschluss Durchmesser (ConConnectorWidth_2): 0.04 m; Anschluss-Tiefe (ConConnectorDepth_2): 0 m; Anschluss-Breite (ConConnectorWidth2_2): 0.005 m; Anschluss-Position X (ConPosX_2): 0.1 m; Anschluss-Position Y (ConPosY_2): -0.0135 m; Anschluss-Position Z (ConPosZ_2): -0.025 m; Nominale Tiefe (ConNominalDepth_3): 0.04 m; Außendurchmesser (ConWidth_3): 0.042 m; Außentiefe (ConDepth_3): 0.042 m; Wanddicke (ConWallThickness_3): 0.001 m; Anschluss-Länge (ConLength_3): 0.02 m; Anschluss Durchmesser (ConConnectorWidth_3): 0.042 m; Anschluss-Tiefe (ConConnectorDepth_3): 0 m; Anschluss-Breite (ConConnectorWidth2_3): 0.005 m; Anschluss-Position X (ConPosX_3): 0 m; Anschluss-Position Y (ConPosY_3): -0.158908 m; Anschluss-Position Z (ConPosZ_3): -0.167 m; Nominale Tiefe (ConNominalDepth_4): 0.025 m; Außendurchmesser (ConWidth_4): 0.027 m; Außentiefe (ConDepth_4): 0.027 m; Wanddicke (ConWallThickness_4): 0.001 m; Anschluss-Länge (ConLength_4): 0.02 m; Anschluss Durchmesser (ConConnectorWidth_4): 0.04 m; Anschluss-Tiefe (ConConnectorDepth_4): 0 m; Anschluss-Breite (ConConnectorWidth2_4): 0.005 m; Anschluss-Position X (ConPosX_4): -0.1 m; Anschluss-Position Y (ConPosY_4): -0.0135 m; Anschluss-Position Z (ConPosZ_4): -0.025 m; Nominale Tiefe (ConNominalDepth_5): 0.025 m; Außendurchmesser (ConWidth_5): 0.027 m; Außentiefe (ConDepth_5): 0.027 m; Wanddicke (ConWallThickness_5): 0.001 m; Anschluss-Länge (ConLength_5): 0.02 m; Anschluss Durchmesser (ConConnectorWidth_5): 0.04 m; Anschluss-Tiefe (ConConnectorDepth_5): 0 m; Anschluss-Breite (ConConnectorWidth2_5): 0.005 m; Anschluss-Position X (ConPosX_5): 0.1 m; Anschluss-Position Y (ConPosY_5): -0.0135 m; Anschluss-Position Z (ConPosZ_5): -0.025 m; Nominale Tiefe (ConNominalDepth_6): 0.04 m; Außendurchmesser (ConWidth_6): 0.042 m; Außentiefe (ConDepth_6): 0.042 m; Wanddicke (ConWallThickness_6): 0.001 m; Anschluss-Länge (ConLength_6): 0.02 m; Anschluss Durchmesser (ConConnectorWidth_6): 0.042 m; Anschluss-Tiefe (ConConnectorDepth_6): 0 m; Anschluss-Breite (ConConnectorWidth2_6): 0.005 m; Anschluss-Position X (ConPosX_6): 0 m; Anschluss-Position Y (ConPosY_6): -0.158908 m; Anschluss-Position Z (ConPosZ_6): -0.167 m
Component Quantities - Component 1, Schicht/Komponente Volumen: 0.0656046 m3
Name | Kollidierende Räume | Zugehörige Raumnummer | Drehwinkel (deg) | Zugehörigkeit | Höhenangabe zum Projekt-Nullpunkt (m) = Höhe zu 1. Referenzhöhe (m) = Höhe zu 2. Referenzhöhe (m) = Höhe zu verknüpftem/Ursprungsgeschoss (m) = Abstand zu Ursprungsgeschoss (m) | Höhe zu Meereshöhe (m)
Küche-010 | Erdgeschoss; Grundfläche Gebäude Nachgezogen; Wohnen; Wohnung2 EG | R-004 | 180 | EG-R-004-Wohnen | 0.2422 | 16.2422
Küche-010 | Erdgeschoss; Grundfläche Gebäude Nachgezogen; Wohnen; Wohnung1 EG | R-005 | 0 | EG-R-005-Wohnen | 0.241991 | 16.242

# IfcBuildingElementProxy: Baum detailliert 22, Baum-001
In: R-000
Classification: Geländegeometrie (ARCHICAD Klassifizierung)
ArchiCADProperties - Element ID: Baum-001; Hotlink und Element-ID: Baum-001; Ebene: Grundstück; Bibliothekselement-Name: Baum detailliert 22; Baustoff / Mehrschichtiger Aufbau / Profil / Schraffur: Nur Hintergrund-Stift; Schraffurtyp: Nur Hintergrund-Stift; Kollidierende Räume: Gelände; Zuwegung; Geschützt: no; Ursprungsgeschoss Name: EG; Ursprungsgeschoss Nummer: 0; Typ: Objekt; Überobjekt-ID: Baum-001; Oberfläche (Alle): Holz Nussbaum; Natur Gras 3; Lage: Außen; Tragende Funktion: Nicht definiert; Anzeigen auf Umbau-Filter: Alle relevanten Filter; Umbau-Status: Bestand; Drehwinkel: 180 deg; Oberfläche: Kunststoff PE, weiss; ARCHICAD Klassifizierung - 22: Geländegeometrie
AC_Pset_Baum_detailliert_22 - 2D-Fixpunkte in 3D zeigen: yes; 3D-Detaillierungsgrad: 1; Schatten: no; Standard Baumform: 1; Äste: yes; Allgemein Auflösung des Stamms: 3; Laubtyp: 1; Laubdichte in %: 50; Auflösung Laub: 8; Auflösung Blätter: 3; Laubtyp automatisch: yes; Stamm und Äste (trmat): Holz Nussbaum; Blätter - Laub detailiert: Natur Gras 3; Laub abstrakt: Natur Gras 3; Laub als Ellipsoid: Natur Gras 3; Symboltyp: 1; Individuelles Bild benutzen: no; Konturstift: Elemente+Text; Schraffur: Nur Vordergrund-Stift; Schraffur-Vordergrundstift: Schraffurhintergrund; Schraffur-Hintergrundstift: Schraffurhintergrund; Baumnamen zeigen: no; Text-Stift: Konturstift; Schrifttyp: Arial; Schriftgröße (mm): 7.8; Schriftgröße (Punkt): 221.102; Fett: no; Kursiv: no; Unterstrichen: no; Text-Ausrichtung am Symbol: 1; Preis: 0; Typ (FM_Type): Andere; Typ (iFMType): 25; Bezeichnung Wert: Bibliothekselementname; Zusätzliche Beschreibung (gs_onorm_name): Baum detailliert 23; DIM Durchmesser: 350,00; DIM Höhe: 700,00; ID-Nummer: Baum-001
ArchiCADQuantities - Fläche: 12.25 m2; Höhe: 7 m; Netto-Volumen: 10.2467 m3; Breite: 3.5 m; Höhenangabe zum Projekt-Nullpunkt: -0.0622597 m; Höhe zu 1. Referenzhöhe: -0.0622597 m; Höhe zu 2. Referenzhöhe: -0.0622597 m; Höhe zu Meereshöhe: 15.9377 m; Höhe zu verknüpftem/Ursprungsgeschoss: -0.0622597 m; Abstand zu Ursprungsgeschoss: -0.0622597 m; Oberflächenbereich: 75.7406 m2; Länge (A): 3.5 m
AC_Equantity_Baum_detailliert_22 - Maß 1: 3.5 m; Maß 2: 3.5 m; Höhe: 7 m; Untere Ebene: 1 m; Obere Ebene: 0 m; Halb A: 1.75 m; Halb B: 1.75 m; Höhe Stamm: 1 m; Stammdurchmesser in 3D: 0.34 m; Durchmesser Laubkugel Teile: 0.8 m; Durchmesser Blätter: 0.6 m; Reichweite Laub detailiert: 30 m; Reichweite Laub abstrakt: 70 m; Text Position X: 0 m; Text Position Y: 0 m
Component Quantities - Component 1, Schicht/Komponente Volumen: 10.2467 m3

# IfcBuildingElementProxy: Beton, Stahlbeton C20/25, Morph-022
In: -1. Geschoss
Classification: Rampe (ARCHICAD Klassifizierung); Material: Beton, Stahlbeton C20/25
ArchiCADProperties - Element ID: Morph-022; Hotlink und Element-ID: Morph-022; Ebene: Decken Roh; Baustoff / Mehrschichtiger Aufbau / Profil / Schraffur: Beton, Stahlbeton C20/25; Baustoff: Beton, Stahlbeton C20/25; Zugehöriger Raumname: Rampe; Zugehörige Raumnummer: R-017; Geschützt: no; Ursprungsgeschoss Name: -1. Geschoss; Ursprungsgeschoss Nummer: -1; Typ: Morph; Überobjekt-ID: Morph-022; Baustoffe (Alle): Beton, Stahlbeton C20/25; Oberfläche (Alle): Beton, Sichtbeton 2; Lage: Außen; Tragende Funktion: Tragende Elemente; Anzeigen auf Umbau-Filter: Alle relevanten Filter; Klassifizierung nach DIN 277: Nicht definiert; Umbau-Status: Bestand; wirft Schatten: yes; empfängt Schatten: yes; Oberfläche: Beton, Sichtbeton 2; ARCHICAD Klassifizierung - 22: Rampe
Brandschutz 4102-2 - Kennbuchstabe: F
Component Properties - Component 1, Enthaltenes CO2: 7312.9 (kgCO₂); Component 1, Enthaltene Energie: 50478.4 MJ; Component 1, Komponenten-Typ: Keine
ArchiCADQuantities - Fläche: 53.9299 m2; Netto-Volumen: 32.358 m3; Höhenangabe zum Projekt-Nullpunkt: -3.4 m; Höhe zu 1. Referenzhöhe: -3.4 m; Höhe zu 2. Referenzhöhe: -3.4 m; Höhe zu Meereshöhe: 12.6 m; Höhe zu verknüpftem/Ursprungsgeschoss: -0.6 m; Abstand zu Ursprungsgeschoss: -0.6 m; Oberflächenbereich: 130.606 m2; Grundriss-Umfang: 30.4535 m
Component Quantities - Component 1, Masse: 64715.9 kg; Component 1, Schicht/Komponente Volumen: 32.358 m3

# IfcBuildingElementProxy: Boden, Pflaster, Morph-023
In: R-000
Classification: Geländegeometrie (ARCHICAD Klassifizierung); Material: Boden, Pflaster
Pset_SiteCommon - TotalArea: 38.83 m2
ArchiCADProperties - Element ID: Morph-023; Hotlink und Element-ID: Morph-023; Ebene: Grundstück; Baustoff / Mehrschichtiger Aufbau / Profil / Schraffur: Boden, Pflaster; Baustoff: Boden, Pflaster; Kollidierende Räume: Gelände; Zuwegung; Zugehöriger Raumname: Spielplatz; Zugehörige Raumnummer: R-000; Geschützt: no; Ursprungsgeschoss Name: EG; Ursprungsgeschoss Nummer: 0; Typ: Morph; Überobjekt-ID: Morph-023; Baustoffe (Alle): Boden, Pflaster; Oberfläche (Alle): Pflaster, Betonstein; Lage: Nicht definiert; Tragende Funktion: Nicht definiert; Anzeigen auf Umbau-Filter: Alle relevanten Filter; Klassifizierung nach DIN 277: Nicht definiert; Umbau-Status: Bestand; wirft Schatten: yes; empfängt Schatten: yes; Oberfläche: Pflaster, Betonstein; ARCHICAD Klassifizierung - 22: Geländegeometrie
Component Properties - Component 1, Enthaltenes CO2: 917.38 (kgCO₂); Component 1, Enthaltene Energie: 7644.83 MJ; Component 1, Komponenten-Typ: Keine
ArchiCADQuantities - Fläche: 38.8311 m2; Netto-Volumen: 2.91232 m3; Höhenangabe zum Projekt-Nullpunkt: -0.0600045 m; Höhe zu 1. Referenzhöhe: -0.0600045 m; Höhe zu 2. Referenzhöhe: -0.0600045 m; Höhe zu Meereshöhe: 15.94 m; Höhe zu verknüpftem/Ursprungsgeschoss: -0.0600045 m; Abstand zu Ursprungsgeschoss: -0.0600045 m; Oberflächenbereich: 81.5265 m2; Grundriss-Umfang: 51.5236 m
Component Quantities - Component 1, Masse: 5096.55 kg; Component 1, Schicht/Komponente Volumen: 2.91232 m3

# IfcBuildingElementProxy: Duschwanne 1 22 (2)
In: EG
Classification: Möbel (ARCHICAD Klassifizierung)
ArchiCADProperties - Ebene: Möblierung; Bibliothekselement-Name: Duschwanne 1 22; Baustoff / Mehrschichtiger Aufbau / Profil / Schraffur: Nur Hintergrund-Stift; Schraffurtyp: Nur Hintergrund-Stift; Zugehöriger Raumname: Bad; Geschützt: no; Ursprungsgeschoss Name: EG; Ursprungsgeschoss Nummer: 0; Typ: Objekt; Oberfläche (Alle): Metall Chrom; Kunststoff PE, weiss; Lage: Nicht definiert; Tragende Funktion: Nicht definiert; Anzeigen auf Umbau-Filter: Alle relevanten Filter; Umbau-Status: Bestand; Oberfläche: Kunststoff PE, weiss; ARCHICAD Klassifizierung - 22: Möbel
AC_Pset_Duschwanne_1_22 - 2D-Fixpunkte in 3D zeigen: no; Programm einstellen: no; Stil (stStyle): Rechteck; Stil (iStyle): 1; 3D-Detaillierungsgrad: 1; Abwasser Anschluss: yes; Werkzeug-Typ: 2; HKLSE System: Undefiniert; Form-Typ: Kreis; Auflösung: 32; Schatten: yes; Symboltyp (gs_symbol_type): Typ 2; Symboltyp (iSymbolType): 2; 2D-Detaillierungsgrad: 1; Konturstift: Elemente+Text; Schraffur: Nur Hintergrund-Stift; Schraffur-Vordergrundstift: Schraffurhintergrund; Schraffur-Hintergrundstift: Schraffurhintergrund; Duschwanne: Kunststoff PE, weiss; Seite: Kunststoff PE, weiss; Abfluss: Metall Chrom; Anschluss: Metall Stahl, poliert; System Oberflächenmaterial benutzen: no; System Oberflächenmaterial: Farbe, grau; Anschlussanzahl: 1; Preis: 0; Gruppe Typ (FM_Type): Sanitäre Anlagen; Gruppe Typ (iFMType): 13; Fläche: 0; Volumen: 0; Objektgewicht: 0; Objektgewichtseinheit: kg; Dimensionen B/T/H: 80,00/80,00/10,00; Montagehöhe Wert: Automatisch; Montagehöhe: 20,00
ArchiCADQuantities - Fläche: 0.64 m2; Höhe: 0.1 m; Netto-Volumen: 0.00153268 m3; Breite: 0.8 m; Höhenangabe zum Projekt-Nullpunkt: 0.2 m; Höhe zu 1. Referenzhöhe: 0.2 m; Höhe zu 2. Referenzhöhe: 0.2 m; Höhe zu Meereshöhe: 16.2 m; Höhe zu verknüpftem/Ursprungsgeschoss: 0.2 m; Abstand zu Ursprungsgeschoss: 0.2 m; Oberflächenbereich: 2.1576 m2; Länge (A): 0.8 m
AC_Equantity_Duschwanne_1_22 - Breite: 0.8 m; Tiefe: 0.8 m; Höhe: 0.1 m; Untere Ebene: 1 m; Obere Ebene: 0 m; Ablage Höhe: 0.09 m; Seite 1: 0.45 m; Seite 2: 0.45 m; Nominale Tiefe: 0 m; Außendurchmesser: 0.042 m; Außentiefe: 0.042 m; Wanddicke: 0.001 m; Anschluss-Länge: 0.02 m; Anschluss Durchmesser: 0.042 m; Anschluss-Tiefe: 0 m; Anschluss-Breite: 0.002 m; Anschluss-Position X: 0.175 m; Anschluss-Position Y: 0.175 m; Anschluss-Position Z: 0 m; Min. Platzbedarf Breite (MSFront): 1.2 m; Min. Platzbedarf vorne: 1 m; Min. Platzbedarf Länge: 1 m; Min. Platzbedarf extra Länge: 0.3 m; Min. Platzbedarf Breite (MSWidth): 0.3 m
Name | Element ID = Hotlink und Element-ID = Überobjekt-ID = ID-Nummer | Kollidierende Räume | Zugehörige Raumnummer | Drehwinkel (deg) | Zugehörigkeit
Objekt-003 | Objekt-003 | Bad; Erdgeschoss; Grundfläche Gebäude Nachgezogen; Wohnung2 EG | R-008 | 90 | EG-R-008-Bad | Component Quantities - Component 1, Schicht/Komponente Volumen: 0.00153268 m3
Objekt-004 | Objekt-004 | Bad; Erdgeschoss; Grundfläche Gebäude Nachgezogen; Wohnung1 EG | R-007 | 180 | EG-R-007-Bad

# IfcBuildingElementProxy: Einbau Kochfeld 22 (2)
In: EG
Classification: Möbel (ARCHICAD Klassifizierung)
ArchiCADProperties - Element ID: Küche-011; Hotlink und Element-ID: Küche-011; Ebene: Möblierung; Bibliothekselement-Name: Einbau Kochfeld 22; Baustoff / Mehrschichtiger Aufbau / Profil / Schraffur: Nur Hintergrund-Stift; Schraffurtyp: Nur Hintergrund-Stift; Zugehöriger Raumname: Wohnen; Geschützt: no; Ursprungsgeschoss Name: EG; Ursprungsgeschoss Nummer: 0; Typ: Objekt; Überobjekt-ID: Küche-011; Oberfläche (Alle): Naturstein Schiefer; Farbe, blau; Metall Stahl, matt; Lage: Innen; Tragende Funktion: Nicht definiert; Anzeigen auf Umbau-Filter: Alle relevanten Filter; Umbau-Status: Bestand; Oberfläche: Kunststoff PE, weiss; ARCHICAD Klassifizierung - 22: Möbel
AC_Pset_Einbau_Kochfeld_22 - 3D-Detaillierungsgrad: 1; 2D-Fixpunkte in 3D zeigen: no; Kochplatte: Typ 7; Kochplattentyp: 7; Arbeitsplatte (gs_count_type): Rechteckig; Typ Arbeitsplatte: 1; Gedopp. Deckplatte: no; Spritzschutz (bBacksplash): no; Kanten sichtbar im 3D (side_vis): Keine; Kanten sichtbar im 3D (side_vis_m): 1; Kanten sichtbar im 3D (side_vis_mirror): Keine; 2D-Detaillierungsgrad: 1; Elektrisches Symbol 2D: no; Symboltyp: Stil 1; Symbol-Stift: Konturstift; Symbolschraffur: Nur Vordergrund-Stift; Kanten sichtbar im 2D (side_vis2D): Keine; Kanten sichtbar im 2D (side_vis2D_m): 1; Kanten sichtbar im 2D (side_vis2D_mirror): Keine; Konturstift: Elemente+Text; Schraffur: Nur Hintergrund-Stift; Schraffur-Vordergrundstift: Schraffurhintergrund; Schraffur-Hintergrundstift: Schraffurhintergrund; Auflösung: 12; Schatten: yes; Arbeitsplatte (count_mat): Naturstein Schiefer; Spritzschutz (bs_mat): Metall Chrom; Oben: Metall Stahl, matt; Kochelement: Farbe, blau; Brenner 1: Metall Chrom; Brenner 2: Metall Chrom; Schalter: Metall Chrom; Preis: 0; Volt: 0; Gruppe Typ (FM_Type): Elektrische Ausstattung; Gruppe Typ (iFMType): 8; Objektgewicht: 0; Objektgewichtseinheit: kg; Leistungsaufnahme in Watt: 0; Stromverbrauch in kWh: 0; Dimensionen B/T/H: 60,00/60,00/1,30; Montagehöhe Wert: Automatisch; ID-Nummer: Küche-011
ArchiCADQuantities - Fläche: 0.36 m2; Höhe: 0.013 m; Netto-Volumen: 0.0041731 m3; Breite: 0.6 m; Oberflächenbereich: 1.34658 m2; Länge (A): 0.6 m
AC_Equantity_Einbau_Kochfeld_22 - Breite Arbeitsplatte: 0.6 m; Tiefe Arbeitsplatte: 0.6 m; Höhe Arbeitsplatte (ZZYZX): 0.013 m; Höhe Arbeitsplatte (hCountertop): 0.9 m; Untere Ebene: 0.89 m; Obere Ebene: 0.903 m; Breite Kochplatte: 0.58 m; Tiefe Kochplatte: 0.49 m; Kochplatte X Abst. von Mitte: 0 m; Kochplatte Y Abst. von Mitte: 0 m; Stärke Arbeitsplatte: 0.01 m; Spritzschutz Höhe: 0.01 m; Min. Platzbedarf vorne: 0.9 m; Min. Platzbedarf auf Seite 1: 0 m; Min. Platzbedarf auf Seite 2: 0 m; Minimaler Platzbedarf: 0.9 m; Rückwärtiger minimaler Platzbedarf Seite 1: 0 m; Rückwärtiger minimaler Platzbedarf Seite 2: 0 m
Component Quantities - Component 1, Schicht/Komponente Volumen: 0.0041731 m3
Name | Kollidierende Räume | Zugehörige Raumnummer | Drehwinkel (deg) | Montagehöhe | Zugehörigkeit | Höhenangabe zum Projekt-Nullpunkt (m) = Höhe zu 1. Referenzhöhe (m) = Höhe zu 2. Referenzhöhe (m) = Höhe zu verknüpftem/Ursprungsgeschoss (m) = Abstand zu Ursprungsgeschoss (m) | Höhe zu Meereshöhe (m)
Küche-011 | Erdgeschoss; Grundfläche Gebäude Nachgezogen; Wohnen; Wohnung2 EG | R-004 | 180 | 24,22 | EG-R-004-Wohnen | 0.2422 | 16.2422
Küche-011 | Erdgeschoss; Grundfläche Gebäude Nachgezogen; Wohnen; Wohnung1 EG | R-005 | 0 | 24,20 | EG-R-005-Wohnen | 0.241991 | 16.242

# IfcBuildingElementProxy: Eingangstür 01 22 (2)
In: -1. Geschoss
Classification: Tür (ARCHICAD Klassifizierung)
Pset_ConcreteElementGeneral - FireRating: T 30
Pset_FireRatingProperties - FireResistanceRating: T 30
ArchiCADProperties - Ebene: Wand Innen; Bibliothekselement-Name: Eingangstür 01 22; Baustoff / Mehrschichtiger Aufbau / Profil / Schraffur: Misch-Schraffur 0%; Schraffurtyp: Misch-Schraffur 0%; Geschützt: no; Ursprungsgeschoss Name: -1. Geschoss; Ursprungsgeschoss Nummer: -1; Typ: Tür; Überobjekt-ID: Wand-006; Oberfläche (Alle): Metall Stahl, matt; Fensterrahmen; Von Raum: Garage; Von Raum-Nummer: R-013; Lage: Nicht definiert; Tragende Funktion: Nicht tragende Elemente; Anzeigen auf Umbau-Filter: Alle relevanten Filter; Umbau-Status: Bestand; Anschlagsmaße: 1,010×2,010; Größe Wandloch: 1,010×2,010; Größe laut Eingabe: 1,010×2,010; Größe Ausgang: 0,810×1,910; Türblatt-Maß: 0,870×1,940; Nominale B x H: 1,010×2,010; Nominale B x H x T: 1,010×2,010×0,240; Wandstruktur: WA | Stahlbeton 24cm; Öffnung Bibliothekselementname: Eingangstür 01 22; Öffnungsseite Schraffurindex: Misch-Schraffur 0%; ARCHICAD Klassifizierung - 22: Tür
AC_Pset_Eingangstür_01_22 - Wandkontur (0-Keine,1-Voll,2-Seite,3-Länge): 0; Fixpunkte 0-Kein,1-2D,2-3D,3-Alle: 3; 2D-Fixpunkte in 3D zeigen: yes; Darstellungseinstellung Grundr.: 3; Winkel Öffnungsposition: 0 deg; Loch übernimmt Oberflächenmaterial der Wandseite: yes; Öffnungsoberfläche ist gebogen in gebogenen Wänden: no; Wand-Typ: 1; Wandrichtungstyp: 0; Laibung Ankerposition: 2; Wandquerschnittstyp: 1; Öffnungsrichtung: 1; Heizkörpernische: 2; Spiegeln: no; Nominalmaß: 1; Rohbauöffnung als Nominalmaß einstellen: yes; Architekturlichte als Nominalmaß einstellen: no; Rahmen-Außenmaß als Nominalmaß einstellen: no; Baurichtmaß als Nominalmaß einstellen: no; Freies Öffnungsmaß als Nominalmaß einstellen: no; Türblattmaß als Nominalmaß einstellen: no; Übertrage aktuelle Nominal Größe auf die Auswahl: yes; Türblatt: 1; Sprossen - horizontal: 3; Sprossen - vertical: 2; Klinkentyp innen (gs_handle_type): Klinke 3; Klinkentyp innen (gs_handle_type_m): 10; Klinkentyp außen (gs_handle_type_out): Knopf 1; Klinkentyp außen (gs_handle_type_out_m): 2; Oberlicht (gs_kamp): no; Rahmentyp (gs_frame_type): Standard; Rahmentyp (iFrameType): 1; Unterschiedliche Breiten: no; Seite Laibung: yes; Rahmen: Fensterrahmen; Paneel: Fensterrahmen; Glas: Glas Normalglas; Metallteile: Metall Stahl, matt; Türfüllung: Farbe, grau; Sprossen: Fensterrahmen; Griff: Metall Stahl, matt; Griff Zubehör: Metall Stahl, matt; Schwelle Oberflächenmaterial: Holz Esche; Schwelle Metallmaterial: Metall Stahl, gebürstet; Blindschwelle Oberflächenmaterial: Holz Esche; Einheitliche Oberflächen Verkleidung: yes; Innenverkleidung Oberflächenmaterial: Fensterrahmen; Außenverkleidung Oberflächenmaterial: Fensterrahmen; Schwelle (bThreshold): no; Schwellentyp (thresholdType): Normal; Schwelle (iThresholdType): 1; Standard-Schwelle Typ: 1; Blindschwelle: no; Schwelle in 2D: no; Stift Schwelle: Elemente+Text; Linientyp Schwelle: 1; Wandöffnung unter Schwelle (holeUnderThreshold): Wandöffnung zu Wandunterkante; Wandöffnung unter Schwelle (iHoleUnderThreshold): 2; Schwellensymbol nach SIA (showSIASymbol): Maßstababhängig; Schwellensymbol nach SIA (iShowSIASymbol): 0; Editierbare Schwellenhöhe im Symbol: no; Schwellentyp (SIASymbolType): Typ 1; Schwellentyp (iSIASymbolType): 1; Position Schwellensymbol (SIASymbolSide): Rechts; Position Schwellensymbol (iSIASymbolSide): 1; Stift Text: Elemente+Text; Symbol-Stift: Elemente+Text; Marker-Text: Arial; Schriftgröße: 1; Außenverkleidung: no; Futter Außen (gs_trimtype_out): Rechteckig; Futter Außen (gs_trimtype_out_int): 1; Gehäuse Kopftyp: 1; Querbalken oben: yes; Querbalken Typ oben: 1; Verkleidung (gs_trim_show_cover_out): yes; einheitliche Einfassungsbreiten (gs_trim_outside_uniform): yes; Futter Schnittlinienstift auf beiden Seiten: Elemente+Text; Schraffur Zarge außen: Nur Hintergrund-Stift; Innenverkleidung: no; Futter Innen (gs_trimtype_in): Rechteckig; Futter Innen (gs_trimtype_in_int): 1; Verkleidung (gs_trim_show_cover_in): yes; einheitliche Einfassungsbreiten (gs_trim_inside_uniform): yes; Schraffur Zarge innen: Nur Hintergrund-Stift; Fensterbank Außen: no; Schwelle/Türeinfassung Übergröße: no; Fensterbanktyp: 8; Schwelle Winkel: 3 deg; Fensterbank ist gebogen in gebogenen Wänden: yes; Dämmung unter Fensterbank: yes; Wand-Dämmschicht benutzen: no; Rollschicht-Fensterbank 3D-Detaillierungsgrad: 1; Fensterbank Stift für 3D und Aufsicht: Elemente+Text; Fensterbank Schnitt Konturstift: Elemente+Text; Fensterbank Schnittschraffur: Nur Hintergrund-Stift; Dämmung Schnittlinien-Stift: Elemente+Text; Dämmung Schnittschraffur: Dämmung, hart 1; Dämmung Schnittschraffur-Vordergrundstift: Elemente+Text; Fensterbank Oberflächenmaterial: MW Ziegel, rotbraun, DF; Mauerwerksbrüstung Mörtel Oberflächenmaterial: Verputz, glatt, rot; Rollschicht (bMasonryArch): no; Rollschicht (gs_masonry_arch_int): 5; Typ Sturz (gs_masonry_arch_structure): Verputzt; Typ Sturz (gs_masonry_arch_structure_int): 1; Sturz direkt über der Tür: yes; Nische unterm Bogen: yes; Neigungswinkel: 75 deg; Eigenes Nischen-Oberflächenmaterial: no; Bogen Schnittschraffur: Erde 1; Bogen Schnittschraffur-Vordergrundstift: Konturstift; Bogen Schnittschraffur-Hintergrundstift: Schraffurhintergrund; Stift Ziegelsturz: Schraffur; Mauerwerksbogen Stein Oberflächenmaterial: MW Ziegel, blaurot, DF, Läufer; Mauerwerksbogen Mörtel Oberflächenmaterial: Verputz, rauh, grau; Mauerwerksbogen Schlusstein Oberflächenmaterial: Naturstein Kalkstein; Nischen-Oberflächenmaterial: Verputz, rauh, gelb; Typ Anschlag (gs_reveal_type_new): Anschlag; Typ Anschlag (gs_reveal_type_int): 3; Untere Laibung Typ (gs_reveal_type_bottom): ohne Anschlag; Untere Laibung Typ (gs_reveal_type_bottom_int): 2; Äußerer Laibungstyp: ohne Anschlag; Typ Anschlag (gs_reveal_doubleOuterTypeInt): 0; Laibungstyp Innen: ohne Anschlag; Typ Anschlag (gs_reveal_doubleInnerTypeInt): 0; Anschlagtiefe und Laibungswinkel gleich: yes; Laibung bearbeiten von (gs_reveal_angle_edit_by): Winkel und Tiefe; Laibung bearbeiten von (gs_reveal_angle_edit_by_int): 1; Winkel Seite 2: 20 deg; Winkel Seite: 20 deg; Winkel oben: 20 deg; Winkel unten: 0 deg; Außenwinkel Seite 2: 20 deg; Außenwinkel Seite: 20 deg; Außenwinkel obere Seite: 20 deg; Außenwinkel untere Seite: 0 deg; Einbaurahmen: no; Einbaurahmen Aufsichtslinien-Stift: Elemente+Text; Einbaurahmen Konturstift (gs_mountingFrame_pen_cont): Elemente+Text; Einbaurahmen Schraffur (gs_mountingFrame_fill): Nur Hintergrund-Stift; Einbaurahmen Oberflächenmaterial: Holz Esche; Wandbekleidung benutzen: no; automatischer Schichteinzug Putz innen: yes; Putzschicht innen einziehen: 0; automatischer Schichteinzug Putz außen: yes; Putzschicht außen einziehen: 0; Bemaßungsfangpunkte in 2D: no; in 3D zeigen: no; Schichteinzug (gs_closure_type): Kein Schichteinzug; Schichteinzug (gs_closure_type_int): 1; Schicht an Seite einziehen (gs_cavity_side): Beide; Schicht an Seite einziehen (iCavityClosureSide): 1; Einzuziehende Schichten: 1; Schichten von (gs_nTurnDir): Außenseite; Schichten von (iCavityClosureTurnDir): 1; Schichteinzug auf Seite 2: yes; Schichteinzug auf Seite 1: yes; Schichteinzug oben: no; Schichteinzug unten: no; Schichteinzug zu Schicht: 1; Schichteinzug von Seite (gs_cc_dutch_ClosureToSide): 1; Schicht einziehen zu Abschluss: no; Dichtungsband einfügen: yes; Dichtungsband zeigen: yes; Konturlinien-Typ (gs_ltJoint): 1; Schraffur (gs_fillJoint): Nur Hintergrund-Stift; Schraffur-Vordergrundstift (gs_penJointFg): Elemente+Text; Eigenes Oberflächenmaterial: no; Oberflächenmaterial: Holz Esche; Konturlinien-Typ (gs_ltPlug): 1; Schraffur (gs_fillPlug): Nur Hintergrund-Stift; Schraffur-Vordergrundstift (gs_penPlugFg): Elemente+Text; Editierte Anschlagseite: 1; Editierte Wandseite: 1; Schicht Nummer: 1; Schicht einziehen: no; Schicht als Putz ansehen: no; Einzugsdicke: 1; Ausrichtung Schraffur: 1; Trennlinie am Einzug: no; Stift Trennlinie: Elemente+Text; Letzte ausgewählte Seite: no; Abschlussart automatisch verändert: no; Anschluss Links: no; Anschluss Rechts: no; Anschluss Oben: no; Sturzbrett: no; Fensterbank innen ist gebogen in gebogenen Wänden: yes; Fensterbank in Polygonwänden: 2; 2D-Detaillierungsgrad: 2; Stift Grundriss: Elemente+Text; Linientyp Grundriss: 4; 3D Stift: Elemente+Text; Ansichts-Stift: Elemente+Text; Schnittschraffur: Misch-Schraffur 50 %; Schnittschraffur-Vordergrundstift: Elemente+Text; Sturzbrett Oberflächenmaterial: Farbe, weiß; Sturzsystem: no; Hintersturz: no; autom. Hintersturzhöhe: no; Hinterer Sturz übernimmt Oberflächenmaterial der Wand: yes; Hinterer Sturz Oberflächenmaterial: Farbe, weiß; Hintersturz Schraffur (gs_hsturz_fillType): Nur Hintergrund-Stift; Hintersturz Schraffur-Vordergrundstift: Elemente+Text; Schnittlinienstift Hintersturz: Elemente+Text; Typ (iTypeProfiledLintel): 1; Dämmung (gs_zd): yes; Sturz übernimmt Oberflächenmaterial der Wand: yes; Sturz Oberflächenmaterial: Farbe, weiß; Wärmedämmung Oberflächenmaterial: Farbe, weiß; Schnittlinien Stift: Konturstift; Sturz Schraffur: Nur Hintergrund-Stift; Sturz Schraffur-Vordergrundstift: Elemente+Text; Dämmung Schraffur 1: Nur Hintergrund-Stift; Dämmung Schraffur 2: Nur Hintergrund-Stift; Dämmung Schraffur-Vordergrundstift: Elemente+Text; Türeinfassung: no; 2D-Darstellung (bShowMounting2D): yes; Typ Fassung: 2; Falz: no; Pfosten: no; Befestigung Oberflächenmaterial: Fensterrahmen; Konturlinien-Stift: Elemente+Text; Kontur-Stift Sturz vorne: Elemente+Text; Kontur-Stift Sturz hinten: Elemente+Text; Schraffur-Vordergrundstift (gs_pen_sc): Elemente+Text; Schraffur-Hintergrundstift (gs_pen_h): Elemente+Text; Bedeckung Schraffur: Nur Vordergrund-Stift; Schwelle Schraffur: Nur Hintergrund-Stift; Schraffur (efsc2): Luftschicht; Schraffur Sturz vorne: Nur Hintergrund-Stift; Dämmung Schraffur: Nur Hintergrund-Stift; Hintersturz Schraffur (efsc_h): Nur Hintergrund-Stift; Linientyp: 1; Sonnenschutz: no; Sonnenschutz-Typ: 1; Aktivierte Sonnenschutz-Typen: 254; Anzahl Lamellen: 2; Anzahl Paneelen 2: 1; Paneel-Position (gs_shutter_panelPos): Symmetrisch; Paneel-Position (gs_shutter_iPanelPos): 1; Automatische Höhenanpassung: yes; Extra Rahmen: no; Abdeckungstyp (gs_slidingShutter_cover): Z-Profil; Abdeckungstyp (gs_slidingShutter_iCover): 1; Stapelrichtung (gs_foldingShutter_stacking): Innen; Stapelrichtung (gs_foldingShutter_iStacking): 1; in 3D geöffnet: yes; 3D-Öffnungswinkel: 180 deg; 2D-Symbol zeigen: yes; Öffnungslinie im Symbol zeigen: yes; Sonnenschutz-Symbol-Linientyp: 1; Sonnenschutz-Schnittlinien-Stift: Elemente+Text; Sonnenschutz Aufsichtslinien-Stift: Elemente+Text; Sonnenschutz Schnittschraffur: Nur Hintergrund-Stift; Sonnenschutz Schnittschraffur-Vordergrundstift: Elemente+Text; Verschattung Dämmung Schraffur: Dämmung, weich; Verschattung Dämmung Schraffur-Vordergrundstift: Elemente+Text; Verschattung Dämmung Schraffur-Hintergrundstift: Elemente+Text; Fensterladen Oberflächenmaterial: Holz Esche; Fensterladenrahmen Oberflächenmaterial: Holz Esche; Rollladengehäuse Oberflächenmaterial: Metall Chrom; Rollladenlamellen Oberflächenmaterial: Lack schwarz; Rollladen Schiene Oberflächenmaterial: Holz Parkett 1; Jalousie Oberflächenmaterial: Metall Chrom; Jalousielamellen Oberflächenmaterial: Lack schwarz; Schiebladen Schiene Oberflächenmaterial: Metall Chrom; Paneeltyp (gs_shutPanel_type): Typ 1; Paneeltyp (gs_shutPanel_iType): 1; Unterschiedliche Rahmen-Breite unten: no; Rollladen Breite: yes; Winkel Lamelle: 30 deg; Lochanzahl horizontal: 5; Lochanzahl vertikal: 8; Rollladen-Platzierung (gs_shutRoll_placement): Vor Fassade angebracht; Rollladen-Platzierung (gs_shutRoll_iPlacement): 1; Typ (gs_shutRoll_boxType): Rechteckig; Typ (gs_shutRoll_iBoxType): 1; Handlauf Position (gs_shutRoll_railPos): Auf Verkleidung; Handlauf Position (gs_shutRoll_iRailPos): 1; Verkleidung hinter Sonnenschutz zeigen (gs_shutRoll_showCasingBehind): yes; Wand hinter Kasten schneiden: yes; Höhe in Wandlochhöhe einschließen: no; Neigung Kastendach: 10 deg; Kasten–Breite (gs_shutRoll_boxDefaultSize): Architekturlichte Breite; Kasten–Breite (gs_shutRoll_iBoxDefaultSize): 1; Jalousien-Platzierung (gs_shutLam_placement): Vor Fassade angebracht; Jalousien-Platzierung (gs_shutLam_iPlacement): 1; Dämmung hinter Kasten: no; Geöffnetes Gehäuse: yes; Führungsschienen: yes; Handlauf Position (gs_shutLam_railPos): Auf Verkleidung; Handlauf Position (gs_shutLam_iRailPos): 1; Verkleidung hinter Sonnenschutz zeigen (gs_shutLam_showCasingBehind): yes; Kippwinkel (gs_shutLam_rotation): 45 deg; Kippwinkel (gs_shutLam2_rotation): 45 deg; Rahmen-Stift: Schichttrennlinien/Kontur; Rahmen Schnittschraffur: Nur Hintergrund-Stift; Türblatt-Stift: Schichttrennlinien/Kontur; Türblatt Schnittschraffur: Luftschicht; Glas Linienstift Kontur: Schichttrennlinien/Kontur; Glas Schnittschraffur: Nur Hintergrund-Stift; Glas Aufsichtslinien-Stift: Schichttrennlinien/Kontur; Rahmen Aufsichtslinien-Stift: Schichttrennlinien/Kontur; Rahmen Deckschraffur: Nur Hintergrund-Stift; Symbol ausrichten: 2; Öffnungswinkel in 2D: 90 deg; Öffnungswinkel in 3D: 0 deg; Modelldarstell. für symbolische 2D-Darstellung überschreiben: no; 2D-Öffnungslinien zeigen: yes; Öffnungslinien-Typ: 1; Nebenöffnung Linientyp in 2D: 4; Öffnungslinien-Form (or_SwingType): Gebogen; Öffnungslinien-Form (or_iSwingType): 1; Öffnungslinien-Form (or_SlidingType): Kein; Öffnungslinien-Form (or_iSlidingType): 0; 2D & 3D Öffnungslinien-Stift (or_opLinePen): Elemente+Text; 2D & 3D Öffnungslinien-Stift (or_iOpLinePen): 1; Modelldarstell. für 3D-Darstellung überschreiben: no; Öffnungslinie zeigen: yes; Linientyp Öffnungsseite (or_opLineType3dIn): Vollinie; Linientyp Öffnungsseite (or_iOpLineType3dIn): 0; Linientyp Gegenüberliegende Seite (or_opLineType3dOut): Strichlinie; Linientyp Gegenüberliegende Seite (or_iOpLineType3dOut): 1; Standflügel Linientyp in 3D: Strichlinie; Standflügel Linientyp: 1; Linien-Ausrichtung (or_oplineStyle): Griff; Linien-Ausrichtung (or_iOplineStyle): 1; Grundriss: 1; 3D: 8; Schnitt / Ansicht: 1; Anschlag im Grundriss zeigen: 1; Wandschraffur in der Öffnung: no; Schraffur (gs_wallhole_fill): Nur Hintergrund-Stift; Schraffur-Vordergrundstift (gs_wallhole_pen_fg): Elemente+Text; Schraffur-Hintergrundstift (gs_wallhole_pen_bg): Schraffurhintergrund; Türkoten: yes; Sichtbarkeit Türbemaßung (gs_etikett): Modelldarstellungs-Optionen; Sichtbarkeit Türbemaßung (iEtikett): 3; Öffnung roh: 1; Text Öffnung roh: Öffnung roh; Sturz fertig: 1; Text Fertig Sturz: Sturz fertig; OK Schwelle: 1; Text Schwelle Fertig: OK Schwelle; Schwelle (iDWDimRawParapet): 1; Text Schwelle: Schwelle; Texteinstellung (gs_Etikett_scaleValues): Maßstababhängig (Modellgröße); Massstab (gs_Etikett_scaleValues_m): 2; Schrifttyp (fontType): Arial; Schriftgröße (papier) (gs_Etikett_fontSize_mm): 0.75; Dimension Stift Text: Elemente+Text; X Position (m): 0; Position X (mm): 0; Y Position (m): 0; Position Y (mm): 4; Automat. Zeilenabstand: no; Zeilenabstand (papier): 0.5; Drehwinkel: 0 deg; Zeige die ID im Grundriss: no; Beschriftung Türtyp: 1; Automatische Tür ID: yes; Eigener Text: Eigene ID; Marker spiegeln: yes; Zusätzliche Werte zeigen (Öffnungsmass 1.20/1.50): yes; Text Position X (mm): 0; Text Position Y (mm): 4; Texteinstellung (gs_IDText_scaleValues): Maßstababhängig (Modellgröße); Massstab (gs_IDText_scaleValues_m): 2; Schriftgröße (papier) (gs_IDText_fontSize_mm): 1; Schrifttyp (gs_IDText_fontType): Arial; Text-Stift: Elemente+Text; Sturztiefe im Grundriss zeigen: no; Sturztiefe Symbol- Linientyp: 4; Sturztiefe Symbolstift: Konturstift; Öffnungstyp: 0; seitliche Wandkontur (gs_wallcontour): Beide; seitliche Wandkontur (gs_wallcontour_id): 1; Wandkontur (gs_wcont_line): beide Seiten; Wandkontur (iWallContourLine): 4; Automatische Einstellungen: yes; Wandkonturlinie innen - 1:50 und tiefer: yes; Wandkonturlinie innen - 1:100 und höher: yes; Wandkonturlinien Typ innen - 1:50 und tiefer: 1; Wandkonturlinien Typ innen - 1:100 und höher: 1; Wandkonturlinie außen - 1:50 und tiefer: yes; Wandkonturlinie außen - 1:100 und höher: yes; Wandkonturlinien Typ außen - 1:50 and tiefer: 1; Wandkonturlinien Typ außen - 1:100 und höher: 1; Wandkonturlinien Stift - 1:50 und tiefer: Elemente+Text; Wandkonturlinien Stift - 1:100 und höher: Elemente+Text; Typ Links: 0; Typ Rechts: 0; Automatische Maße: yes; Einbaurahmen Konturstift (gs_TolerBlin_contour_pen): Elemente+Text; Einbaurahmen Konturlinientyp: 1; Einbaurahmen Schraffur (gs_TolerBlin_fill_type): Nur Hintergrund-Stift; Einbaurahmen Schraffur-Vordergrundstift (gs_TolerBlin_fg_pen): Schichttrennlinien/Kontur; Schraffur-Stift Fugenausfüllung: Elemente+Text; Linientyp Kontur Fugenausfüllung: 1; Fugenausfüllung Schraffur: Nur Vordergrund-Stift; Fugenausfüllung Schraffur-Vordergrundstift: Schichttrennlinien/Kontur; Bearbeitende Fixpunkte zeigen: yes; IFC Betrieb (ifc_optypestr): Einflügeltür; IFC Betrieb (ifc_optype): 1; Linkes Seitenfeld: no; Rechtes Seitenfeld: no; Oberlicht (gs_door_transom): no; Bilder: 2; Tür gehört zum Raum, in den sie öffnet: yes; Preis: 0; Komplette Glasfläche: 0; Umfang der Glasfläche: 0; Dämmung (gs_list_bInsulation): no; Selbstschließend: no; Rauchschutz Tür: no; Rauchprobe Temperatur: 200; Dämmung Index: 2; Gruppe Typ (FM_Type): Türe; Gruppe Typ (iFMType): 999; Objektgewicht: 0; Objektgewichtseinheit: kg; Türausrichtungsdefinition: 0; Breite Wert: Durchgangslichte Breite; Breite: 81,00; Höhe Wert: Durchgangslichte Höhe; Höhe: 191,00; Wert ID Nummer: 1; zu Raum ID innen Wert: Eigene; zu Raum ID außen Wert: Eigene
Brandschutz 4102-2 - Feuerwiderstand 4102-2: T 30; Minuten (4102-2): 30; Baustoffklasse: A; Kennbuchstabe: T
Türen/Fenster - Schallschutzklasse: SK 3; Fenster/Türbreite: 1.01 m; Fenster/Türhöhe: 2.01 m
ArchiCADQuantities - Höhe: 2.01 m; Netto-Volumen: 0.0886408 m3; Breite: 1.01 m; Höhenangabe zum Projekt-Nullpunkt: -2.8 m; Höhe zu 1. Referenzhöhe: -2.8 m; Höhe zu 2. Referenzhöhe: -2.8 m; Höhe zu Meereshöhe: 13.2 m; Höhe zu verknüpftem/Ursprungsgeschoss: 0 m; Abstand zu Ursprungsgeschoss: 0 m; Oberflächenbereich: 5.95 m2; F/T Volumen der Öffnung: 0.487224 m3; F/T nominales Volumen der Öffnung: 0.487224 m3; F/T Oberfläche der Öffnung: 5.95 m2; F/T Öffnung Nominaler Oberflächenbereich: 2.0301 m2; F/T Öffnungsbreite auf der Anschlagseite: 1.01 m; F/T Höhe der Öffnung auf der Anschlagseite: 2.01 m; F/T Öffnungsbreite gegenüber der Anschlagseite: 1.01 m; F/T Höhe der Öffnung gegenüber der Anschlagseite: 2.01 m; F/T Oberfläche der Öffnung auf der Anschlagseite: 2.0301 m2; F/T Oberfläche der Öffnung gegenüber der Anschlagseite: 2.0301 m2; Nominale F/T Öffnungsbreite auf der Anschlagseite: 1.01 m; Nominale F/T Höhe der Öffnung auf der Anschlagseite: 2.01 m; Nominale F/T Öffnungsbreite gegenüber der Anschlagseite: 1.01 m; Nominale F/T Höhe der Öffnung gegenüber der Anschlagseite: 2.01 m; Nominale F/T Öffnungsoberfläche auf der Anschlagsseite: 2.0301 m2; Nominale F/T Öffnungsoberfläche auf der Seite gegenüber der Anschlagsseite: 2.0301 m2; Brüstungshöhe: 0 m; F/T nominale Brüstungs-/Schwellenhöhe: 0 m; F/T Brüstungs-/Schwellenhöhe auf der Anschlagseite: 0 m; F/T Brüstungs-/Schwellenhöhe gegenüber der Anschlagseite: 0 m; F/T nominale Sturzhöhe: 2.01 m; F/T Sturzhöhe auf der Anschlagseite: 2.01 m; F/T Sturzhöhe gegenüber der Anschlagseite: 2.01 m; Wanddicke: 0.24 m; Rahmen-Stärke: 0.05 m
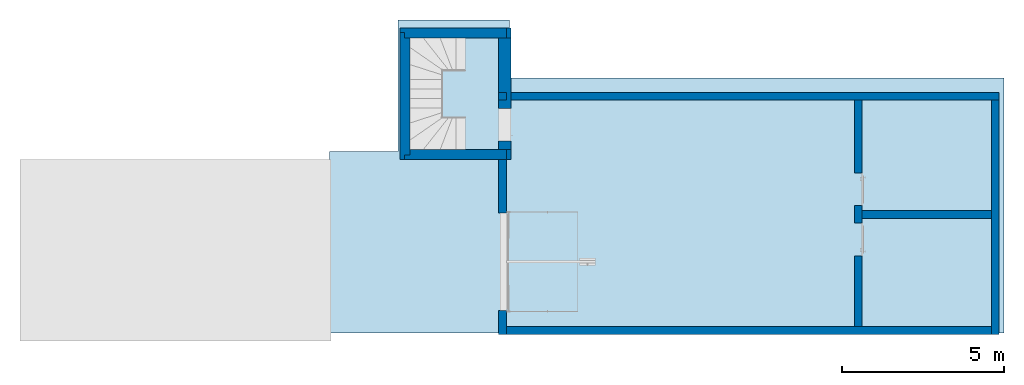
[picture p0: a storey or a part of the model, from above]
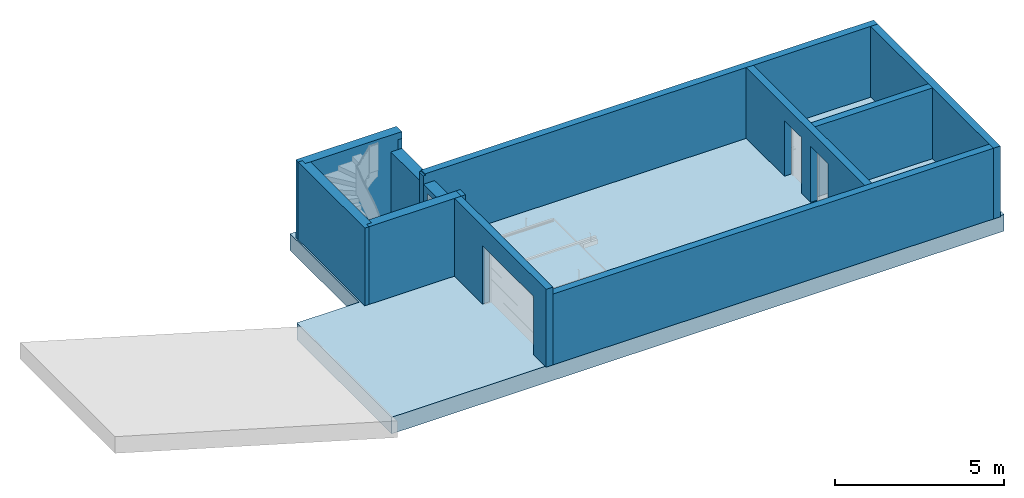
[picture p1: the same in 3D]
Properties of the parts of a building model (IFC4), part 8 of 13

# IfcBuildingElementProxy: Eingangstür 01 22 (2)
AC_Equantity_Eingangstür_01_22 - NominaleBreite: 1.01 m; NominaleHöhe: 2.01 m; Z-Achse: 1 m; Untere Ebene: 1 m; Obere Ebene: 0 m; Brüstungshöhe zum aktuellen Geschoss: 0 m; Laibung zum Wandkern: -0.03 m; Einbautoleranz links: 0 m; Einbautoleranz rechts: 0 m; Einbautoleranz oben: 0 m; Einbautoleranz unten: 0 m; Toleranz außen links: 0 m; Toleranz innen links: 0 m; Toleranz außen rechts: 0 m; Toleranz innen rechts: 0 m; Toleranz außen oben: 0 m; Toleranz innen oben: 0 m; Toleranz außen unten: 0 m; Toleranz innen unten: 0 m; Rohbauöffnung Breite: 1.01 m; Rohbauöffnung Höhe (ac_wallhole_height): 2.01 m; Rohbauöffnung Höhe (ac_wallhole_height_original): 2.01 m; Architekturlichte Breite: 1.01 m; Architekturlichte Höhe (ac_reveal_height): 2.01 m; Architekturlichte Höhe (ac_reveal_height_original): 2.01 m; Rahmen Breite: 1.01 m; Rahmen Höhe: 2.01 m; Breite Baurichtmaß: 1.01 m; Höhe Baurichtmaß: 2.01 m; Durchgangslichte Breite: 0.81 m; Durchgangslichte Höhe: 1.91 m; Nominale Türblatt Breite: 0.87 m; Nominale Türblatt Höhe: 1.94 m; Spalt unter Türblatt: 0 m; Türblatt Stärke: 0.04 m; Falzbreite: 0.03 m; Falztiefe: 0.03 m; Stärke Türfüllung: 0.02 m; Rahmen-Breite links: 0.1 m; Rahmen-Breite rechts: 0.1 m; Rahmen-Breite unten (leafFrWidthBottom): 0.9 m; Rahmen-Breite oben: 0.1 m; Sprossenbreite: 0.025 m; Sprossentiefe: 0.025 m; Radius Türfüllung: 0.2 m; Abstand Mittelpunkt - links: 0.3 m; Abstand Mittelpunkt - rechts: 1.02 m; Abstand Mittelpunkt - unten: 1.4 m; Abstand Mittelpunkt - oben: 0.61 m; Blatt Thk - Unten Extra: 0 m; Griff-Höhe: 1.05 m; Klinkeposition: 0.06 m; Höhe Kämpfer (gs_am): 0.76 m; Rahmen-Breite: 0.1 m; Rahmenbreite Seite 1: 0.1 m; Rahmenbreite Seite 2: 0.1 m; Mittlerer Rahmen Seite 1: 0.1 m; Mittlerer Rahmen Seite 2: 0.1 m; Oberer Rahmen Breite: 0.1 m; Querbalkenrahmen Breite: 0.1 m; Seitenfeld Querbalkenrahmen Breite: 0.1 m; Seitenfeld oberer Rahmen Breite: 0.1 m; Untere Rahmenbreite: 0.1 m; Rahmen-Stärke: 0.05 m; Block Breite: 0.04 m; Block Stärke: 0.05 m; Mörtel: 0.01 m; Überstand 1: 0.01 m; Überstand 2: 0.01 m; Schwellenhöhe (thresholdHeight3D): 0.02 m; Schwellenhöhe (thresholdHeight1): 0.02 m; Schwellenhöhe (b): 0.02 m; Schwellenhöhe (c): 0.02 m; Eigene Wandöffnung Übergröße: 0.05 m; Position Schwelle (thresholdPos1): 0 m; Position Schwelle (thresholdPos2): 0 m; Position Schwelle (thresholdPos3): 0 m; Querbalken oben Breite: 0.02 m; Breite Seite 1 (gs_tw_right_out): 0.05 m; Breite Seite 2 (gs_tw_left_out): 0.05 m; Breite oben (gs_tw_top_out): 0.05 m; Stärke der Wand (gs_trim_thk_out): 0.019 m; Stärke des Wandlochs (gs_trim_width_out): 0.025 m; Abstand (gs_trim_offs_out): 0 m; Auskragung (gs_trim_jambext_nosing_out): 0.05 m; Oberer Überstand (gs_trimov_top_right_out): 0.1 m; Breite Seite 1 (gs_tw_right_in): 0.05 m; Breite Seite 2 (gs_tw_left_in): 0.05 m; Breite oben (gs_tw_top_in): 0.05 m; Stärke der Wand (gs_trim_thk_in): 0.019 m; Stärke des Wandlochs (gs_trim_width_in): 0.025 m; Abstand (gs_trim_offs_in): 0 m; Auskragung (gs_trim_jambext_nosing_in): 0.03 m; Oberer Überstand (gs_trimov_top_right_in): 0.1 m; Fensterbankbreite: 0 m; Fensterbank obere Breite: 0.01 m; Fensterbank obere Höhe: 0.01 m; Schwellendicke: 0.025 m; Fensterbank Vorderseite Stärke: 0.015 m; Schwelle Ansicht: 0.005 m; Fensterbank Tropfüberhang: 0.02 m; Stärke Fensterbankkante: 0.03 m; Schwelle Überstand: 0.03 m; Fensterbank Überhang links: 0 m; Fensterbank Überhang rechts: 0 m; Fensterbank Einschub Tiefe: 0.02 m; Fensterbank Einschub von Wand: 0 m; Hintere Lochtiefe (gs_sill_holeDepthBehind): 0 m; Steinbreite (gs_brick_sill_br_thk): 0.065 m; Fugenbreite (gs_brick_sill_mort_thk): 0.015 m; Distanz zwischen Bogen und Tür: 0 m; Sturz Überhang links: 0 m; Sturz Überhang rechts: 0 m; Sturz Bogenhöhe: 0.03 m; Projektion Sturz: 0 m; Höhe Sichtmauerwerk: 0.24 m; Tiefe Sichtmauerwerk: 0.115 m; Hintere Lochtiefe (gs_masonry_arch_rearHoleDepth): 0 m; Steinbreite (gs_masonry_arch_brick_thk): 0.052 m; Fugenbreite (gs_masonry_arch_mort_thk): 0.01 m; Keilsteinbreite: 0.1 m; Überhang Keilstein: 0 m; Projektion Keilstein: 0.01 m; Anschlagtiefe (gs_wido_sill): -0.03 m; Anschlagtiefe (AC_wido_sill): -0.03 m; Anschlagstiefe Seite 2: 0.05 m; Anschlagstiefe: 0.05 m; Innerer Anschlagstiefe Seite 2 (gs_reveal_splayed_innerLeft): 0.06 m; Innerer Anschlagstiefe (gs_reveal_splayed_innerRight): 0.06 m; Innerer Anschlagstiefe Seite 2 (gs_reveal_double_innerLeft): 0.06 m; Innerer Anschlagstiefe (gs_reveal_double_innerRight): 0.06 m; Tiefe des oberen Anschlags: 0.05 m; Tiefe des unteren Anschlags: 0.06 m; Tiefe Sturz Innen (gs_reveal_splayed_innerTop): 0.06 m; Tiefe Laibung Innen (gs_reveal_splayed_innerBottom): 0 m; Tiefe Sturz Innen (gs_reveal_double_innerTop): 0.06 m; Tiefe Laibung Innen (gs_reveal_double_innerBottom): 0 m; Tiefe äußerer Anschlag: 0.05 m; Seitenabschrägung Breite Seite 2: -1 m; Seitenabschrägung Breite Seite: -1 m; Obere Seitenabschrägung Breite: -1 m; Untere Seitenabschrägung Breite: -1 m; Außenabschrägung Breite Seite 2: -1 m; Außenabschrägung Breite Seite: -1 m; Äußere Abschrägung Breite an oberer Seite: -1 m; Breite äußere Abschrägung an Unterseite: -1 m; Einbaurahmen-Stärke: 0.06 m; Einbaurahmen-Breite links: 0.06 m; Einbaurahmen-Breite rechts: 0.06 m; Einbaurahmen-Breite oben: 0.06 m; Einbaurahmen-Breite unten: 0.06 m; Max. Putzdicke: 0.04 m; Abstand Schicht zu Abschluss: 0 m; Anschluss Breite: 0.038 m; Anschluss Stärke: 0.1 m; Streifen-Stärke: 0.025 m; Profilbreite: 0.075 m; Eigene Stärke: 0.015 m; Schichtüberlappung zu Rahmen-Tiefe: 0 m; Sturzbrett Stärke: 0.025 m; Sturzbrett Überstand: 0.03 m; Verkleidungsbreite Links: 0 m; Verkleidungsbreite Rechts: 0 m; Verkleidungsdicke: 0.28 m; Höhe Hintersturz (gs_hsturz_height): 0.08 m; Höhe Hintersturz (gs_hhs): 0.2 m; Stärke vorne: 0.06 m; Tiefe von Wandebene: 0 m; Stärke Dämmung 1: 0.03 m; Stärke Dämmung 2: 0.03 m; Versatz vom Fensterrahmen: 0 m; Stärke Metalplatte: 0.005 m; Breite: 0.07 m; Breite oben (efb_t1): 0.3 m; Stärke oben: 0.06 m; Breite Sturz außen: 0.06 m; Breite unten: 0.07 m; Schwellenbreite: 0.07 m; Vorstand v. Fassade: 0.025 m; Vorstand v. Fassade Fensterbank Außen: 0.05 m; Paneelhöhe: 1.5 m; Innerer Versatz: 0.02 m; Schließtiefe: 0 m; Extra Rahmen Breite: 0.04 m; Extra Rahmen Stärke: 0.03 m; Geländerbreite: 0.03 m; Türzapfen-Länge: 0.02 m; Türzapfen-Radius: 0.005 m; Paneel-Abstand: 0.006 m; Außen-Überhang: 0 m; Innere Paneel-Breite: 0.12 m; 3D-Öffnungslänge: 1.5 m; 3D geschlossene Länge: 0 m; 3D-Öffnungslänge 1 (gs_shutter_opLength_1): 0.56 m; 3D-Öffnungslänge 1 (gs_shutter_opLength_2): 0.14 m; 3D-Öffnungshöhe: 1.5 m; 3D geschlossene Höhe: 0 m; Paneeldicke: 0.05 m; Paneelrahmen-Breite: 0.05 m; Rahmen-Breite unten (gs_shutPanel_frameWidthBottom): 0.05 m; Paneelbreite: 0 m; Paneelfüllungs-Stärke: 0.01 m; Stärke Lamelle: 0.01 m; Breite Lamellen: 0.04 m; Horizontaler Rahmen Teiler-Breite: 0.05 m; Vertikaler Rahmen Teiler-Breite: 0.05 m; Durchmesser Öffnung: 0.01 m; Breite des vertikalen Bretts: 0.1 m; Z-Rahmen-Breite: 0.05 m; Z-Rahmen-Stärke: 0.025 m; Stärke der vertikalen Bretter: 0.025 m; Stärke der horizontalen Bretter: 0.025 m; Ungefähre Breite der vertikalen Bretter (gs_shutPanel_vertBoardW): 0.08 m; Ungefähre Breite der vertikalen Bretter (gs_shutPanel_horBoardW): 0.115 m; Kasten Höhe (gs_shutRoll_boxHeight): 0.2 m; Kasten Tiefe: 0.15 m; Kasten Abstand links: 0 m; Kasten Abstand recht: 0 m; Tiefe Schiene: 0.0725 m; Abstand von Wand: 0 m; Abstand oben (gs_shutRoll_distFromHead): 0 m; Rollladen-Lamellen-Höhe: 0.05 m; Kasten Höhe (gs_shutLam_boxHeight): 0.2 m; Kasten-Breite (gs_shutLam_boxWidth): 0.15 m; Abdeckungstiefe: 0.04 m; Vorstand v. Wand: 0 m; Abstand oben (gs_shutLam_distFromHead): -0.2 m; Breite einer Rollade (gs_shutLam_segmentWidth): 0.06 m; Kasten Höhe (gs_shutLam2_boxHeight): 0.06 m; Kasten-Breite (gs_shutLam2_boxWidth): 0.06 m; Abst. v. Fenster: 0.06 m; Abstand oben (gs_shutLam2_distFromHead): 0.06 m; Kasten-Achshöhe von OK: 0 m; Breite einer Rollade (gs_shutLam2_segmentWidth): 0.06 m; Eigene Kote Öffnung roh: 0 m; Eigene Kote Brüstung fertig: 0 m; Eigene Kote Schwelle fertig: 0 m; Eigene Kote Schwelle: 0 m; Schriftgröße (modell) (gs_lsize): 0.075 m; Position X: 0 m; Position Y: 0.4 m; Zeilenabstand (modell): 0.05 m; Feste breite in mm (0= autom.): 0 m; Text Position X: 0 m; Text Position Y: 0.4 m; Schriftgröße (modell) (gs_IDText_fontSize_model): 0.1 m; Öffnungsseite Breite 2: 0.1 m; Öffnungsseite Breite 1: 0.1 m; Öffnungsseite Tiefe: 2 m; Gegenüberliegende Seite Breite 2: 0.1 m; Gegenüberliegende Seite Breite 1: 0.1 m; Gegenüberliegende Seite Tiefe: 1.2 m; Position Links: 0 m; Position Rechts: 0 m; Breite Links: 0 m; Breite Rechts: 0 m; Tiefe Links: 0.01 m; Tiefe Rechts: 0.01 m; AC Linkes Öffnungsübermaß: 0 m; AC Rechtes Öffnungsübermaß: 0 m; AC Oberes Öffnungsübermaß: 0 m; AC Unteres Öffnungsübermaß: 0 m; Seitenfeld Breite (gs_sidelight_width_left): 0 m; Seitenfeld Breite (gs_sidelight_width_right): 0 m; Höhe Kämpfer (gs_transom_height): 0 m
Name | Element ID = Hotlink und Element-ID = ID-Nummer | Kollidierende Räume | Zugehöriger Raumname = zu Raum | Zugehörige Raumnummer = Zu Raum-Nummer | Ausrichtung = Türausrichtung = Öffnungsrichtung | Fenster/Türnummer
Tür-001 | Tür-001 | Keller; Untergeschoss UG | Keller | R-014 | L | -1. Geschoss-R-014-Tür-001
Tür-002 | Tür-002 | Fahrradstellplatz; Untergeschoss UG | Fahrradstellplatz | R-015 | R | -1. Geschoss-R-015-Tür-002

# IfcBuildingElementProxy: Eingangstür 02 1 22 (3)
Classification: Tür (ARCHICAD Klassifizierung)
ArchiCADProperties - Ebene: Wand Aussen; Bibliothekselement-Name: Eingangstür 02 1 22; Baustoff / Mehrschichtiger Aufbau / Profil / Schraffur: Misch-Schraffur 0%; Schraffurtyp: Misch-Schraffur 0%; Geschützt: no; Typ: Tür; Tragende Funktion: Nicht tragende Elemente; Anzeigen auf Umbau-Filter: Alle relevanten Filter; Umbau-Status: Bestand; Öffnung Bibliothekselementname: Eingangstür 02 1 22; Öffnungsseite Schraffurindex: Misch-Schraffur 0%; ARCHICAD Klassifizierung - 22: Tür
AC_Pset_Eingangstür_02_1_22 - Wandkontur (0-Keine,1-Voll,2-Seite,3-Länge): 0; Fixpunkte 0-Kein,1-2D,2-3D,3-Alle: 3; 2D-Fixpunkte in 3D zeigen: yes; Darstellungseinstellung Grundr.: 3; Winkel Öffnungsposition: 0 deg; Loch übernimmt Oberflächenmaterial der Wandseite: yes; Öffnungsoberfläche ist gebogen in gebogenen Wänden: no; Wand-Typ: 1; Wandquerschnittstyp: 1; Öffnungsrichtung: 0; Heizkörpernische: 3; Nominalmaß: 0; Rohbauöffnung als Nominalmaß einstellen: no; Architekturlichte als Nominalmaß einstellen: yes; Rahmen-Außenmaß als Nominalmaß einstellen: no; Baurichtmaß als Nominalmaß einstellen: no; Freies Öffnungsmaß als Nominalmaß einstellen: no; Türblattmaß als Nominalmaß einstellen: no; Übertrage aktuelle Nominal Größe auf die Auswahl: yes; Türblatt: 1; Sprossen - horizontal: 3; Sprossen - vertical: 2; Klinketyp (gs_handle_type): Vertikaler Stab 1; Klinketyp (gs_handle_type_m): 20; Oberlicht (gs_kamp): yes; Rahmentyp (gs_frame_type): Standard; Rahmentyp (iFrameType): 1; Unterschiedliche Breiten: no; Seite Laibung: yes; Rahmen: Fensterrahmen; Paneel: Fensterrahmen; Glas: Glas Normalglas; Metallteile: Metall Stahl, matt; Türfüllung: Farbe, grau; Sprossen: Fensterrahmen; Griff: Metall Stahl, matt; Griff Zubehör: Metall Stahl, matt; Schwelle Oberflächenmaterial: Holz Esche; Schwelle Metallmaterial: Metall Stahl, gebürstet; Blindschwelle Oberflächenmaterial: Holz Esche; Einheitliche Oberflächen Verkleidung: yes; Innenverkleidung Oberflächenmaterial: Fensterrahmen; Außenverkleidung Oberflächenmaterial: Fensterrahmen; Standard-Schwelle Typ: 1; Blindschwelle: no; Schwelle in 2D: no; Stift Schwelle: Elemente+Text; Linientyp Schwelle: 1; Schwellensymbol nach SIA (showSIASymbol): Maßstabsabhängig; Schwellensymbol nach SIA (iShowSIASymbol): 0; Editierbare Schwellenhöhe im Symbol: no; Schwellentyp (SIASymbolType): Typ 1; Schwellentyp (iSIASymbolType): 1; Position Schwellensymbol (SIASymbolSide): Rechts; Position Schwellensymbol (iSIASymbolSide): 1; Stift Text: Elemente+Text; Symbol-Stift: Elemente+Text; Marker-Text: Arial; Schriftgröße: 1; Außenverkleidung: no; Futter Außen (gs_trimtype_out): Rechteckig; Futter Außen (gs_trimtype_out_int): 1; Gehäuse Kopftyp: 1; Querbalken oben: yes; Querbalken Typ oben: 1; Verkleidung (gs_trim_show_cover_out): yes; einheitliche Einfassungsbreiten (gs_trim_outside_uniform): yes; Futter Schnittlinienstift auf beiden Seiten: Elemente+Text; Schraffur Zarge außen: Nur Hintergrund-Stift; Innenverkleidung: no; Futter Innen (gs_trimtype_in): Rechteckig; Futter Innen (gs_trimtype_in_int): 1; Verkleidung (gs_trim_show_cover_in): yes; einheitliche Einfassungsbreiten (gs_trim_inside_uniform): yes; Schraffur Zarge innen: Nur Hintergrund-Stift; Fensterbank Außen: no; Schwelle/Türeinfassung Übergröße: no; Fensterbanktyp: 2; Schwelle Winkel: 3 deg; Fensterbank ist gebogen in gebogenen Wänden: yes; Dämmung unter Fensterbank: yes; Wand-Dämmschicht benutzen: no; Rollschicht-Fensterbank 3D-Detaillierungsgrad: 1; Fensterbank Stift für 3D und Aufsicht: Elemente+Text; Fensterbank Schnitt Konturstift: Elemente+Text; Fensterbank Schnittschraffur: Nur Hintergrund-Stift; Dämmung Schnittlinien-Stift: Elemente+Text; Dämmung Schnittschraffur: Dämmung, hart 1; Dämmung Schnittschraffur-Vordergrundstift: Elemente+Text; Fensterbank Oberflächenmaterial: MW Ziegel, rotbraun, DF; Mauerwerksbrüstung Mörtel Oberflächenmaterial: Verputz, glatt, rot; Rollschicht (bMasonryArch): no; Rollschicht (gs_masonry_arch_int): 2; Typ Sturz (gs_masonry_arch_structure): Verputzt; Typ Sturz (gs_masonry_arch_structure_int): 1; Sturz direkt über der Tür: yes; Nische unterm Bogen: yes; Neigungswinkel: 75 deg; Eigenes Nischen-Oberflächenmaterial: no; Bogen Schnittschraffur: Erde 1; Bogen Schnittschraffur-Vordergrundstift: Konturstift; Bogen Schnittschraffur-Hintergrundstift: Schraffurhintergrund; Stift Ziegelsturz: Schraffur; Mauerwerksbogen Stein Oberflächenmaterial: MW Ziegel, blaurot, DF, Läufer; Mauerwerksbogen Mörtel Oberflächenmaterial: Verputz, rauh, grau; Mauerwerksbogen Schlusstein Oberflächenmaterial: Naturstein Kalkstein; Nischen-Oberflächenmaterial: Verputz, rauh, gelb; Typ Anschlag (gs_reveal_type_new): ohne Anschlag; Typ Anschlag (gs_reveal_type_int): 2; Untere Laibung Typ (gs_reveal_type_bottom): Gleich; Untere Laibung Typ (gs_reveal_type_bottom_int): 1; Laibungstyp Innen: ohne Anschlag; Anschlagtiefe und Laibungswinkel gleich: yes; Laibung bearbeiten von (gs_reveal_angle_edit_by): Winkel und Tiefe; Laibung bearbeiten von (gs_reveal_angle_edit_by_int): 1; Winkel Seite 2: 20 deg; Winkel Seite: 20 deg; Winkel oben: 20 deg; Winkel unten: 0 deg; Außenwinkel Seite 2: 20 deg; Außenwinkel Seite: 20 deg; Außenwinkel obere Seite: 20 deg; Außenwinkel untere Seite: 0 deg; Einbaurahmen: no; Einbaurahmen Aufsichtslinien-Stift: Elemente+Text; Einbaurahmen Konturstift (gs_mountingFrame_pen_cont): Elemente+Text; Einbaurahmen Schraffur (gs_mountingFrame_fill): Nur Hintergrund-Stift; Einbaurahmen Oberflächenmaterial: Holz Esche; Wandbekleidung benutzen: no; Putzschicht innen einziehen: 0; Putzschicht außen einziehen: 0; Bemaßungsfangpunkte in 2D: no; in 3D zeigen: no; Schichteinzug (gs_closure_type): Kein Schichteinzug; Schichteinzug (gs_closure_type_int): 1; Schicht an Seite einziehen (gs_cavity_side): Beide; Schicht an Seite einziehen (iCavityClosureSide): 1; Schichten von (gs_nTurnDir): Außenseite; Schichten von (iCavityClosureTurnDir): 1; Schichteinzug auf Seite 2: yes; Schichteinzug auf Seite 1: yes; Schichteinzug oben: no; Schichteinzug unten: no; Schichteinzug zu Schicht: 1; Schicht einziehen zu Abschluss: no; Dichtungsband zeigen: yes; Konturlinien-Typ (gs_ltJoint): 1; Schraffur (gs_fillJoint): Nur Hintergrund-Stift; Schraffur-Vordergrundstift (gs_penJointFg): Elemente+Text; Eigenes Oberflächenmaterial: no; Oberflächenmaterial: Holz Esche; Konturlinien-Typ (gs_ltPlug): 1; Schraffur (gs_fillPlug): Nur Hintergrund-Stift; Schraffur-Vordergrundstift (gs_penPlugFg): Elemente+Text; Editierte Anschlagseite: 1; Editierte Wandseite: 1; Schicht Nummer: 1; Schicht als Putz ansehen: no; Ausrichtung Schraffur: 1; Trennlinie am Einzug: no; Stift Trennlinie: Elemente+Text; Letzte ausgewählte Seite: no; Abschlussart automatisch verändert: no; Anschluss Links: no; Anschluss Rechts: no; Anschluss Oben: no; Sturzbrett: no; Fensterbank innen ist gebogen in gebogenen Wänden: yes; Fensterbank in Polygonwänden: 2; 2D-Detaillierungsgrad: 2; Stift Grundriss: Elemente+Text; Linientyp Grundriss: 4; 3D Stift: Elemente+Text; Ansichts-Stift: Elemente+Text; Schnittschraffur: Misch-Schraffur 50 %; Schnittschraffur-Vordergrundstift: Elemente+Text; Sturzbrett Oberflächenmaterial: Farbe, weiß; Sturzsystem: no; Hintersturz: no; autom. Hintersturzhöhe: no; Hinterer Sturz übernimmt Oberflächenmaterial der Wand: yes; Hinterer Sturz Oberflächenmaterial: Farbe, weiß; Hintersturz Schraffur (gs_hsturz_fillType): Nur Hintergrund-Stift; Hintersturz Schraffur-Vordergrundstift: Elemente+Text; Schnittlinienstift Hintersturz: Elemente+Text; Typ (iTypeProfiledLintel): 1; Dämmung (gs_zd): no; Sturz übernimmt Oberflächenmaterial der Wand: yes; Sturz Oberflächenmaterial: Farbe, weiß; Wärmedämmung Oberflächenmaterial: Farbe, weiß; Schnittlinien Stift: Konturstift; Sturz Schraffur: Nur Hintergrund-Stift; Sturz Schraffur-Vordergrundstift: Elemente+Text; Dämmung Schraffur 1: Nur Hintergrund-Stift; Dämmung Schraffur 2: Nur Hintergrund-Stift; Dämmung Schraffur-Vordergrundstift: Elemente+Text; 2D-Darstellung (bShowMounting2D): yes; Typ Fassung: 2; Falz: no; Pfosten: no; Befestigung Oberflächenmaterial: Fensterrahmen; Konturlinien-Stift: Elemente+Text; Kontur-Stift Sturz vorne: Elemente+Text; Kontur-Stift Sturz hinten: Elemente+Text; Schraffur-Vordergrundstift (gs_pen_sc): Elemente+Text; Schraffur-Hintergrundstift (gs_pen_h): Elemente+Text; Bedeckung Schraffur: Nur Vordergrund-Stift; Schwelle Schraffur: Nur Hintergrund-Stift; Schraffur (efsc2): Luftschicht; Schraffur Sturz vorne: Nur Hintergrund-Stift; Dämmung Schraffur: Nur Hintergrund-Stift; Hintersturz Schraffur (efsc_h): Nur Hintergrund-Stift; Linientyp: 1; Sonnenschutz: no; Sonnenschutz-Typ: 1; Aktivierte Sonnenschutz-Typen: 254; Anzahl Lamellen: 2; Anzahl Paneelen 2: 1; Paneel-Position (gs_shutter_panelPos): Symmetrisch; Paneel-Position (gs_shutter_iPanelPos): 1; Automatische Höhenanpassung: yes; Extra Rahmen: no; Abdeckungstyp (gs_slidingShutter_cover): Z-Profil; Abdeckungstyp (gs_slidingShutter_iCover): 1; Stapelrichtung (gs_foldingShutter_stacking): Innen; Stapelrichtung (gs_foldingShutter_iStacking): 1; in 3D geöffnet: yes; 3D-Öffnungswinkel: 180 deg; 2D-Symbol zeigen: yes; Öffnungslinie im Symbol zeigen: yes; Sonnenschutz-Symbol-Linientyp: 1; Sonnenschutz-Schnittlinien-Stift: Elemente+Text; Sonnenschutz Aufsichtslinien-Stift: Elemente+Text; Sonnenschutz Schnittschraffur: Nur Hintergrund-Stift; Sonnenschutz Schnittschraffur-Vordergrundstift: Elemente+Text; Verschattung Dämmung Schraffur: Dämmung, weich; Verschattung Dämmung Schraffur-Vordergrundstift: Elemente+Text; Verschattung Dämmung Schraffur-Hintergrundstift: Elemente+Text; Fensterladen Oberflächenmaterial: Holz Esche; Fensterladenrahmen Oberflächenmaterial: Holz Esche; Rollladengehäuse Oberflächenmaterial: Metall Chrom; Rollladenlamellen Oberflächenmaterial: Lack schwarz; Rollladen Schiene Oberflächenmaterial: Holz Parkett 1; Jalousie Oberflächenmaterial: Lack schwarz; Jalousielamellen Oberflächenmaterial: Lack schwarz; Schiebladen Schiene Oberflächenmaterial: Metall Chrom; Paneeltyp (gs_shutPanel_type): Stil 1; Paneeltyp (gs_shutPanel_iType): 1; Unterschiedliche Rahmen-Breite unten: no; Rollladen Breite: yes; Winkel Lamelle: 30 deg; Lochanzahl horizontal: 5; Lochanzahl vertikal: 8; Rollladen-Platzierung (gs_shutRoll_placement): Vor Fassade angebracht; Rollladen-Platzierung (gs_shutRoll_iPlacement): 1; Typ (gs_shutRoll_boxType): Rechteckig; Typ (gs_shutRoll_iBoxType): 1; Handlauf Position (gs_shutRoll_railPos): Auf Verkleidung; Handlauf Position (gs_shutRoll_iRailPos): 1; Verkleidung hinter Sonnenschutz zeigen (gs_shutRoll_showCasingBehind): yes; Wand hinter Kasten schneiden: yes; Höhe in Wandlochhöhe einschließen: no; Neigung Kastendach: 10 deg; Kasten–Breite (gs_shutRoll_boxDefaultSize): Architekturlichte Breite; Kasten–Breite (gs_shutRoll_iBoxDefaultSize): 1; Jalousien-Platzierung (gs_shutLam_placement): Vor Fassade angebracht; Jalousien-Platzierung (gs_shutLam_iPlacement): 1; Dämmung hinter Kasten: no; Geöffnetes Gehäuse: yes; Führungsschienen: yes; Handlauf Position (gs_shutLam_railPos): Auf Verkleidung; Handlauf Position (gs_shutLam_iRailPos): 1; Verkleidung hinter Sonnenschutz zeigen (gs_shutLam_showCasingBehind): yes; Kippwinkel (gs_shutLam_rotation): 45 deg; Kippwinkel (gs_shutLam2_rotation): 45 deg; Rahmen-Stift: Schichttrennlinien/Kontur; Rahmen Schnittschraffur: Nur Hintergrund-Stift; Türblatt-Stift: Schichttrennlinien/Kontur; Türblatt Schnittschraffur: Luftschicht; Glas Linienstift Kontur: Schichttrennlinien/Kontur; Glas Schnittschraffur: Nur Hintergrund-Stift; Glas Aufsichtslinien-Stift: Schichttrennlinien/Kontur; Rahmen Aufsichtslinien-Stift: Schichttrennlinien/Kontur; Rahmen Deckschraffur: Nur Hintergrund-Stift; Symbol ausrichten: 2; Öffnungswinkel in 2D: 90 deg; Öffnungswinkel in 3D: 0 deg; Modelldarstell. für symbolische 2D-Darstellung überschreiben: no; 2D-Öffnungslinien zeigen: yes; Öffnungslinien-Typ: 1; Nebenöffnung Linientyp in 2D: 4; Öffnungslinien-Form (or_SwingType): Gebogen; Öffnungslinien-Form (or_iSwingType): 1; Öffnungslinien-Form (or_SlidingType): Keine; Öffnungslinien-Form (or_iSlidingType): 0; 2D & 3D Öffnungslinien-Stift (or_opLinePen): Elemente+Text; 2D & 3D Öffnungslinien-Stift (or_iOpLinePen): 1; Modelldarstell. für 3D-Darstellung überschreiben: no; Öffnungslinie zeigen: yes; Linientyp Öffnungsseite (or_opLineType3dIn): Vollinie; Linientyp Öffnungsseite (or_iOpLineType3dIn): 0; Linientyp Gegenüberliegende Seite (or_opLineType3dOut): Strichlinie; Linientyp Gegenüberliegende Seite (or_iOpLineType3dOut): 1; Standflügel Linientyp in 3D: Strichlinie; Standflügel Linientyp: 1; Linien-Ausrichtung (or_oplineStyle): Griff; Linien-Ausrichtung (or_iOplineStyle): 1; Grundriss: 1; 3D: 8; Schnitt / Ansicht: 1; Anschlag im Grundriss zeigen: 1; Wandschraffur in der Öffnung: no; Schraffur (gs_wallhole_fill): Nur Hintergrund-Stift; Schraffur-Vordergrundstift (gs_wallhole_pen_fg): Elemente+Text; Schraffur-Hintergrundstift (gs_wallhole_pen_bg): Schraffurhintergrund; Türkoten: yes; Sichtbarkeit Türbemaßung (gs_etikett): Modelldarstellungs-Optionen; Sichtbarkeit Türbemaßung (iEtikett): 3; Öffnung roh: 1; Text Öffnung roh: Öffnung roh; Sturz fertig: 1; Text Fertig Sturz: Sturz fertig; OK Schwelle: 1; Text Schwelle Fertig: OK Schwelle; Schwelle (iDWDimRawParapet): 1; Text Schwelle: Schwelle; Texteinstellung (gs_Etikett_scaleValues): Maßstababhängig (Modellgröße); Massstab (gs_Etikett_scaleValues_m): 2; Schrifttyp (fontType): Arial; Schriftgröße (papier) (gs_Etikett_fontSize_mm): 0.75; Dimension Stift Text: Elemente+Text; X Position (m): 0; Position X (mm): 0; Y Position (m): 0; Position Y (mm): 4; Automat. Zeilenabstand: no; Zeilenabstand (papier): 0.5; Drehwinkel: 0 deg; Zeige die ID im Grundriss: no; Beschriftung Türtyp: 1; Automatische Tür ID: yes; Eigener Text: Eigene ID; Marker spiegeln: yes; Zusätzliche Werte zeigen (Öffnungsmass 1.20/1.50): yes; Text Position X (mm): 0; Text Position Y (mm): 4; Texteinstellung (gs_IDText_scaleValues): Maßstababhängig (Modellgröße); Massstab (gs_IDText_scaleValues_m): 2; Schriftgröße (papier) (gs_IDText_fontSize_mm): 1; Schrifttyp (gs_IDText_fontType): Arial; Text-Stift: Elemente+Text; Sturztiefe im Grundriss zeigen: no; Sturztiefe Symbol- Linientyp: 21; Sturztiefe Symbolstift: Konturstift; Öffnungstyp: 0; seitliche Wandkontur (gs_wallcontour): Beide; seitliche Wandkontur (gs_wallcontour_id): 1; Wandkontur (gs_wcont_line): beide Seiten; Wandkontur (iWallContourLine): 4; Automatische Einstellungen: yes; Wandkonturlinie innen - 1:50 und tiefer: yes; Wandkonturlinie innen - 1:100 und höher: yes; Wandkonturlinien Typ innen - 1:50 und tiefer: 1; Wandkonturlinien Typ innen - 1:100 und höher: 1; Wandkonturlinie außen - 1:50 und tiefer: yes; Wandkonturlinie außen - 1:100 und höher: yes; Wandkonturlinien Typ außen - 1:50 and tiefer: 1; Wandkonturlinien Typ außen - 1:100 und höher: 1; Wandkonturlinien Stift - 1:50 und tiefer: Elemente+Text; Wandkonturlinien Stift - 1:100 und höher: Elemente+Text; Typ Links: 0; Typ Rechts: 0; Automatische Maße: yes; Einbaurahmen Konturstift (gs_TolerBlin_contour_pen): Elemente+Text; Einbaurahmen Konturlinientyp: 1; Einbaurahmen Schraffur (gs_TolerBlin_fill_type): Nur Hintergrund-Stift; Einbaurahmen Schraffur-Vordergrundstift (gs_TolerBlin_fg_pen): Schichttrennlinien/Kontur; Schraffur-Stift Fugenausfüllung: Elemente+Text; Linientyp Kontur Fugenausfüllung: 1; Fugenausfüllung Schraffur: Nur Vordergrund-Stift; Fugenausfüllung Schraffur-Vordergrundstift: Schichttrennlinien/Kontur; Bearbeitende Fixpunkte zeigen: yes; IFC Betrieb (ifc_optypestr): Einflügeltür; IFC Betrieb (ifc_optype): 1; Linkes Seitenfeld: no; Rechtes Seitenfeld: no; Oberlicht (gs_door_transom): no; Bilder: 2; Tür gehört zum Raum, in den sie öffnet: yes; Preis: 0; Komplette Glasfläche: 0; Umfang der Glasfläche: 0; Dämmung (gs_list_bInsulation): no; Selbstschließend: no; Rauchschutz Tür: no; Rauchprobe Temperatur: 200; Dämmung Index: 2; Gruppe Typ (FM_Type): Türe; Gruppe Typ (iFMType): 999; Objektgewicht: 0; Objektgewichtseinheit: kg; Türausrichtungsdefinition: 0; Breite Wert: Durchgangslichte Breite; Breite: 81,00; Höhe Wert: Durchgangslichte Höhe; Wert ID Nummer: 0; zu Raum ID innen Wert: Eigene; zu Raum ID außen Wert: Eigene
Brandschutz 4102-2 - Kennbuchstabe: T
ArchiCADQuantities - Breite: 1.01 m; F/T Öffnungsbreite auf der Anschlagseite: 1.01 m; F/T Öffnungsbreite gegenüber der Anschlagseite: 1.01 m; Nominale F/T Öffnungsbreite auf der Anschlagseite: 1.01 m; Nominale F/T Öffnungsbreite gegenüber der Anschlagseite: 1.01 m; Rahmen-Stärke: 0.05 m
AC_Equantity_Eingangstür_02_1_22 - NominaleBreite: 1.01 m; Z-Achse: 1 m; Untere Ebene: 1 m; Obere Ebene: 0 m; Einbautoleranz links: 0 m; Einbautoleranz rechts: 0 m; Einbautoleranz oben: 0 m; Einbautoleranz unten: 0 m; Toleranz außen links: 0 m; Toleranz innen links: 0 m; Toleranz außen rechts: 0 m; Toleranz innen rechts: 0 m; Toleranz außen oben: 0 m; Toleranz innen oben: 0 m; Toleranz außen unten: 0 m; Toleranz innen unten: 0 m; Rohbauöffnung Breite: 1.01 m; Architekturlichte Breite: 1.01 m; Rahmen Breite: 1.01 m; Breite Baurichtmaß: 1.01 m; Durchgangslichte Breite: 0.81 m; Nominale Türblatt Breite: 0.81 m; Spalt unter Türblatt: 0 m; Türblatt Stärke: 0.04 m; Falzbreite: 0.01 m; Falztiefe: 0.02 m; Stärke Türfüllung: 0.02 m; Rahmen-Breite links: 0.1 m; Rahmen-Breite rechts: 0.1 m; Rahmen-Breite unten (leafFrWidthBottom): 0.9 m; Rahmen-Breite oben: 0.1 m; Sprossenbreite: 0.025 m; Sprossentiefe: 0.025 m; Radius Türfüllung: 0.2 m; Abstand Mittelpunkt - links: 0.5 m; Abstand Mittelpunkt - rechts: 0.4 m; Abstand Mittelpunkt - unten: 1.4 m; Abstand Mittelpunkt - oben: 0.6 m; Blatt Thk - Unten Extra: 0 m; Griff-Höhe: 1.05 m; Klinkeposition: 0.06 m; Höhe Kämpfer (gs_am): 0.5 m; Rahmen-Breite: 0.1 m; Rahmenbreite Seite 1: 0.1 m; Rahmenbreite Seite 2: 0.1 m; Mittlerer Rahmen Seite 1: 0.1 m; Mittlerer Rahmen Seite 2: 0.1 m; Oberer Rahmen Breite: 0.1 m; Querbalkenrahmen Breite: 0.1 m; Seitenfeld Querbalkenrahmen Breite: 0.1 m; Seitenfeld oberer Rahmen Breite: 0.1 m; Untere Rahmenbreite: 0.1 m; Rahmen-Stärke: 0.05 m; Block Breite: 0.04 m; Block Stärke: 0.05 m; Mörtel: 0.01 m; Überstand 1: 0.01 m; Überstand 2: 0.01 m; Schwellenhöhe (thresholdHeight3D): 0.02 m; Schwellenhöhe (thresholdHeight1): 0.02 m; Schwellenhöhe (b): 0.02 m; Schwellenhöhe (c): 0.02 m; Eigene Wandöffnung Übergröße: 0.05 m; Position Schwelle (thresholdPos1): 0 m; Position Schwelle (thresholdPos2): 0 m; Position Schwelle (thresholdPos3): 0 m; Querbalken oben Breite: 0.02 m; Breite Seite 1 (gs_tw_right_out): 0.05 m; Breite Seite 2 (gs_tw_left_out): 0.05 m; Breite oben (gs_tw_top_out): 0.05 m; Stärke der Wand (gs_trim_thk_out): 0.019 m; Stärke des Wandlochs (gs_trim_width_out): 0.025 m; Abstand (gs_trim_offs_out): 0 m; Auskragung (gs_trim_jambext_nosing_out): 0.05 m; Oberer Überstand (gs_trimov_top_right_out): 0.1 m; Breite Seite 1 (gs_tw_right_in): 0.05 m; Breite Seite 2 (gs_tw_left_in): 0.05 m; Breite oben (gs_tw_top_in): 0.05 m; Stärke der Wand (gs_trim_thk_in): 0.019 m; Stärke des Wandlochs (gs_trim_width_in): 0.025 m; Abstand (gs_trim_offs_in): 0 m; Auskragung (gs_trim_jambext_nosing_in): 0.03 m; Oberer Überstand (gs_trimov_top_right_in): 0.1 m; Fensterbankbreite: 0 m; Fensterbank obere Breite: 0.01 m; Fensterbank obere Höhe: 0.01 m; Schwellendicke: 0.025 m; Fensterbank Vorderseite Stärke: 0.015 m; Schwelle Ansicht: 0.005 m; Fensterbank Tropfüberhang: 0.02 m; Stärke Fensterbankkante: 0.03 m; Schwelle Überstand: 0.03 m; Fensterbank Überhang links: 0 m; Fensterbank Überhang rechts: 0 m; Fensterbank Einschub Tiefe: 0.02 m; Fensterbank Einschub von Wand: 0 m; Hintere Lochtiefe (gs_sill_holeDepthBehind): 0 m; Steinbreite (gs_brick_sill_br_thk): 0.065 m; Fugenbreite (gs_brick_sill_mort_thk): 0.015 m; Distanz zwischen Bogen und Tür: 0 m; Sturz Überhang links: 0 m; Sturz Überhang rechts: 0 m; Sturz Bogenhöhe: 0.03 m; Projektion Sturz: 0 m; Höhe Sichtmauerwerk: 0.24 m; Tiefe Sichtmauerwerk: 0.115 m; Hintere Lochtiefe (gs_masonry_arch_rearHoleDepth): 0 m; Steinbreite (gs_masonry_arch_brick_thk): 0.052 m; Fugenbreite (gs_masonry_arch_mort_thk): 0.01 m; Keilsteinbreite: 0.1 m; Überhang Keilstein: 0 m; Projektion Keilstein: 0.01 m; Innerer Anschlagstiefe Seite 2 (gs_reveal_splayed_innerLeft): 0.06 m; Innerer Anschlagstiefe (gs_reveal_splayed_innerRight): 0.06 m; Tiefe Sturz Innen (gs_reveal_splayed_innerTop): 0.06 m; Tiefe Laibung Innen (gs_reveal_splayed_innerBottom): 0 m; Tiefe Laibung Innen (gs_reveal_double_innerBottom): 0 m; Tiefe äußerer Anschlag: 0.05 m; Seitenabschrägung Breite Seite 2: -1 m; Seitenabschrägung Breite Seite: -1 m; Obere Seitenabschrägung Breite: -1 m; Untere Seitenabschrägung Breite: -1 m; Außenabschrägung Breite Seite 2: -1 m; Außenabschrägung Breite Seite: -1 m; Äußere Abschrägung Breite an oberer Seite: -1 m; Breite äußere Abschrägung an Unterseite: -1 m; Einbaurahmen-Stärke: 0.06 m; Einbaurahmen-Breite links: 0.06 m; Einbaurahmen-Breite rechts: 0.06 m; Einbaurahmen-Breite oben: 0.06 m; Einbaurahmen-Breite unten: 0.06 m; Max. Putzdicke: 0.04 m; Anschluss Breite: 0.038 m; Anschluss Stärke: 0.1 m; Streifen-Stärke: 0.025 m; Profilbreite: 0.075 m; Schichtüberlappung zu Rahmen-Tiefe: 0 m; Sturzbrett Stärke: 0.025 m; Sturzbrett Überstand: 0.03 m; Verkleidungsbreite Links: 0 m; Verkleidungsbreite Rechts: 0 m; Verkleidungsdicke: 0.28 m; Höhe Hintersturz (gs_hsturz_height): 0.08 m; Höhe Hintersturz (gs_hhs): 0.2 m; Stärke vorne: 0.06 m; Tiefe von Wandebene: 0 m; Stärke Dämmung 1: 0.03 m; Stärke Dämmung 2: 0.03 m; Versatz vom Fensterrahmen: 0 m; Stärke Metalplatte: 0.005 m; Breite: 0.07 m; Breite oben (efb_t1): 0.3 m; Stärke oben: 0.06 m; Breite Sturz außen: 0.06 m; Breite unten: 0.07 m; Schwellenbreite: 0.07 m; Vorstand v. Fassade Fensterbank Außen: 0.05 m; Paneelhöhe: 1.5 m; Innerer Versatz: 0.02 m; Schließtiefe: 0 m; Extra Rahmen Breite: 0.04 m; Extra Rahmen Stärke: 0.03 m; Geländerbreite: 0.03 m; Türzapfen-Länge: 0.02 m; Türzapfen-Radius: 0.005 m; Paneel-Abstand: 0.006 m; Außen-Überhang: 0 m; Innere Paneel-Breite: 0.12 m; 3D-Öffnungslänge: 1.5 m; 3D geschlossene Länge: 0 m; 3D-Öffnungslänge 1 (gs_shutter_opLength_1): 0.56 m; 3D-Öffnungslänge 1 (gs_shutter_opLength_2): 0.14 m; 3D-Öffnungshöhe: 1.5 m; 3D geschlossene Höhe: 0 m; Paneeldicke: 0.05 m; Paneelrahmen-Breite: 0.05 m; Rahmen-Breite unten (gs_shutPanel_frameWidthBottom): 0.05 m; Paneelbreite: 0 m; Paneelfüllungs-Stärke: 0.01 m; Stärke Lamelle: 0.01 m; Breite Lamellen: 0.04 m; Horizontaler Rahmen Teiler-Breite: 0.05 m; Vertikaler Rahmen Teiler-Breite: 0.05 m; Durchmesser Öffnung: 0.01 m; Breite des vertikalen Bretts: 0.1 m; Z-Rahmen-Breite: 0.05 m; Z-Rahmen-Stärke: 0.025 m; Stärke der vertikalen Bretter: 0.025 m; Stärke der horizontalen Bretter: 0.025 m; Ungefähre Breite der vertikalen Bretter (gs_shutPanel_vertBoardW): 0.08 m; Ungefähre Breite der vertikalen Bretter (gs_shutPanel_horBoardW): 0.115 m; Kasten Höhe (gs_shutRoll_boxHeight): 0.2 m; Kasten Tiefe: 0.15 m; Kasten Abstand links: 0 m; Kasten Abstand recht: 0 m; Tiefe Schiene: 0.0725 m; Abstand von Wand: 0 m; Abstand oben (gs_shutRoll_distFromHead): 0 m; Rollladen-Lamellen-Höhe: 0.05 m; Kasten Höhe (gs_shutLam_boxHeight): 0.2 m; Kasten-Breite (gs_shutLam_boxWidth): 0.15 m; Abdeckungstiefe: 0.04 m; Vorstand v. Wand: 0 m; Abstand oben (gs_shutLam_distFromHead): -0.2 m; Breite einer Rollade (gs_shutLam_segmentWidth): 0.06 m; Kasten Höhe (gs_shutLam2_boxHeight): 0.06 m; Kasten-Breite (gs_shutLam2_boxWidth): 0.06 m; Abst. v. Fenster: 0.06 m; Abstand oben (gs_shutLam2_distFromHead): 0.06 m; Kasten-Achshöhe von OK: 0 m; Breite einer Rollade (gs_shutLam2_segmentWidth): 0.06 m; Eigene Kote Öffnung roh: 0 m; Eigene Kote Brüstung fertig: 0 m; Eigene Kote Schwelle fertig: 0 m; Eigene Kote Schwelle: 0 m; Schriftgröße (modell) (gs_lsize): 0.075 m; Position X: 0 m; Position Y: 0.4 m; Zeilenabstand (modell): 0.05 m; Feste breite in mm (0= autom.): 0 m; Text Position X: 0 m; Text Position Y: 0.4 m; Schriftgröße (modell) (gs_IDText_fontSize_model): 0.1 m; Öffnungsseite Breite 2: 0.3 m; Öffnungsseite Breite 1: 0.1 m; Öffnungsseite Tiefe: 2 m; Gegenüberliegende Seite Breite 2: 0.25 m; Gegenüberliegende Seite Breite 1: 0.1 m; Gegenüberliegende Seite Tiefe: 1.2 m; Position Links: 0 m; Position Rechts: 0 m; Breite Rechts: 0 m; Tiefe Links: 0.01 m; Tiefe Rechts: 0.01 m; AC Linkes Öffnungsübermaß: 0 m; AC Rechtes Öffnungsübermaß: 0 m; AC Oberes Öffnungsübermaß: 0 m; AC Unteres Öffnungsübermaß: 0 m; Seitenfeld Breite (gs_sidelight_width_left): 0 m; Seitenfeld Breite (gs_sidelight_width_right): 0 m; Höhe Kämpfer (gs_transom_height): 0 m
Türen/Fenster - Fenster/Türbreite: 1.01 m
Name | In | FireRating = Feuerwiderstand 4102-2 | FireResistanceRating | Element ID = Hotlink und Element-ID | Kollidierende Räume | Zugehöriger Raumname = zu Raum | Zugehörige Raumnummer = Zu Raum-Nummer | Ursprungsgeschoss Name | Ursprungsgeschoss Nummer | Überobjekt-ID | Oberfläche (Alle) | Von Raum | Von Raum-Nummer | Lage | Anschlagsmaße = Größe Wandloch = Größe laut Eingabe = Nominale B x H | Größe Ausgang = Türblatt-Maß | Nominale B x H x T | Wandstruktur | Ausrichtung = Türausrichtung | Wandrichtungstyp | Laibung Ankerposition | Schwelle (bThreshold) = automatischer Schichteinzug Putz innen = automatischer Schichteinzug Putz außen = Dichtungsband einfügen | Schwellentyp (thresholdType) | Schwelle (iThresholdType) | Wandöffnung unter Schwelle (holeUnderThreshold) | Wandöffnung unter Schwelle (iHoleUnderThreshold) | Äußerer Laibungstyp | Typ Anschlag (gs_reveal_doubleOuterTypeInt) | Typ Anschlag (gs_reveal_doubleInnerTypeInt) | Einzuziehende Schichten | Schichteinzug von Seite (gs_cc_dutch_ClosureToSide) = Einzugsdicke | Schicht einziehen = Türeinfassung | AC_Pset_Eingangstür_02_1_22, Höhe | Minuten (4102-2) | Baustoffklasse | Schallschutzklasse | Fenster/Türnummer | Öffnungsrichtung | ArchiCADQuantities, Höhe (m) = F/T Höhe der Öffnung auf der Anschlagseite (m) = F/T Höhe der Öffnung gegenüber der Anschlagseite (m) = Nominale F/T Höhe der Öffnung auf der Anschlagseite (m) = Nominale F/T Höhe der Öffnung gegenüber der Anschlagseite (m) = NominaleHöhe (m) = Rohbauöffnung Höhe (ac_wallhole_height) (m) = Rohbauöffnung Höhe (ac_wallhole_height_original) (m) = Architekturlichte Höhe (ac_reveal_height) (m) = Architekturlichte Höhe (ac_reveal_height_original) (m) = Rahmen Höhe (m) = Höhe Baurichtmaß (m) = Fenster/Türhöhe (m) | Netto-Volumen (m3) | Höhenangabe zum Projekt-Nullpunkt (m) = Höhe zu 1. Referenzhöhe (m) = Höhe zu 2. Referenzhöhe (m) | Höhe zu Meereshöhe (m) | Höhe zu verknüpftem/Ursprungsgeschoss (m) = Abstand zu Ursprungsgeschoss (m) = Brüstungshöhe (m) = F/T nominale Brüstungs-/Schwellenhöhe (m) = F/T Brüstungs-/Schwellenhöhe auf der Anschlagseite (m) = F/T Brüstungs-/Schwellenhöhe gegenüber der Anschlagseite (m) = Brüstungshöhe zum aktuellen Geschoss (m) | Oberflächenbereich (m2) = F/T Oberfläche der Öffnung (m2) | F/T Volumen der Öffnung (m3) = F/T nominales Volumen der Öffnung (m3) | F/T Öffnung Nominaler Oberflächenbereich (m2) = F/T Oberfläche der Öffnung auf der Anschlagseite (m2) = F/T Oberfläche der Öffnung gegenüber der Anschlagseite (m2) = Nominale F/T Öffnungsoberfläche auf der Anschlagsseite (m2) = Nominale F/T Öffnungsoberfläche auf der Seite gegenüber der Anschlagsseite (m2) | F/T nominale Sturzhöhe (m) = F/T Sturzhöhe auf der Anschlagseite (m) = F/T Sturzhöhe gegenüber der Anschlagseite (m) | Wanddicke (m) | Laibung zum Wandkern (m) | Durchgangslichte Höhe (m) = Nominale Türblatt Höhe (m) | Anschlagtiefe (gs_wido_sill) (m) = Anschlagtiefe (AC_wido_sill) (m) | Anschlagstiefe Seite 2 (m) = Anschlagstiefe (m) = Tiefe des oberen Anschlags (m) | Innerer Anschlagstiefe Seite 2 (gs_reveal_double_innerLeft) (m) = Innerer Anschlagstiefe (gs_reveal_double_innerRight) (m) = Tiefe Sturz Innen (gs_reveal_double_innerTop) (m) | Tiefe des unteren Anschlags (m) | Abstand Schicht zu Abschluss (m) | Eigene Stärke (m) | Vorstand v. Fassade (m) | Breite Links (m)
Tür-004 | -1. Geschoss | T 30 | T 30 | Tür-004 | Untergeschoss UG | Garage | R-013 | -1. Geschoss | -1 | Wand-003 | Metall Stahl, matt; Fensterrahmen; Farbe, hellblau | Treppenhaus | R-010 | Innen | 1,010×2,010 | 0,810×1,910 | 1,010×2,010×0,380 | WA / StB Kellerwand + WD | R | 0 | 1 | no | Normal | 1 | Wandöffnung zum aktuellen Geschoss | 1 | Anschlag | 3 | 2 | 0 | 2 | yes | 191,00 | 30 | A | SK 3 | -1. Geschoss-R-013-Tür-004 | R | 2.01 | 0.199947 | -2.8 | 13.2 | 0 | 13.5796 | 0.771438 | 2.0301 | 2.01 | 0.38 | 0.33 | 1.91 | 0.33 | 0.065 | 0 | 0.065 | 0.012 | 0.025 | 0 | 0.05 | AC_Pset_Eingangstür_02_1_22 - Schichteinzug von Seite (gs_cc_dutch_ClosureToSide_str): Innenseite
Tür-003 | EG | T 30 | F60 | Tür-003 | Erdgeschoss; Grundfläche Gebäude Nachgezogen; Wohnung1 EG | Wohnen | R-006 | EG | 0 | Wand-005 | Holz Esche; Metall Stahl, matt; Metall Stahl, gebürstet; Fensterrahmen | Wohnung1 EG | R-021 | Außen | 1,010×2,400 | 0,810×2,300 | 1,010×2,400×0,375 | WA / 2 Schichtig KS | R | 1 | 1 | yes | Schwellenbreite = Wandstärke | 5 | Keine Wandöffnung | 0 | ohne Anschlag | 0 | 0 | 1 | 1 | no | 230,00 | 30 | A | SK 3 | EG-R-006-Tür-003 | R | 2.4 | 0.11046 | 0.2 | 16.2 | 0.2 | 7.90518 | 0.909 | 2.424 | 2.6 | 0.375 | 0.18 | 2.3 | 0.18 | 0.05 | 0.06 | 0.06 | 0 | 0.015 | 0.025 | 0
Tür-003 | EG |  | F60 | Tür-003 | Erdgeschoss; Grundfläche Gebäude Nachgezogen; Wohnung2 EG | Wohnen | R-009 | EG | 0 | Wand-009 | Holz Esche; Metall Stahl, matt; Metall Stahl, gebürstet; Fensterrahmen | Wohnung2 EG | R-020 | Außen | 1,010×2,400 | 0,810×2,300 | 1,010×2,400×0,375 | WA / 2 Schichtig KS | L | 0 | 2 | yes | Bis Türblatt | 2 | Keine Wandöffnung | 0 | ohne Anschlag | 0 | 0 | 1 | 1 | no | 230,00 |  |  |  | EG-R-009-Tür-003 | Links | 2.4 | 0.107178 | 0.2 | 16.2 | 0.2 | 7.53133 | 0.909 | 2.424 | 2.6 | 0.375 | 0 | 2.3 | 0.18 | 0.05 | 0.06 | 0.06 | 0 | 0.015 | 0.025 | 0

# IfcBuildingElementProxy: Eingangstür 02 2 22 (2)
In: EG
Classification: Tür (ARCHICAD Klassifizierung)
ArchiCADProperties - Element ID: Tür-005; Hotlink und Element-ID: Tür-005; Ebene: Wand Innen; Bibliothekselement-Name: Eingangstür 02 2 22; Baustoff / Mehrschichtiger Aufbau / Profil / Schraffur: Misch-Schraffur 0%; Schraffurtyp: Misch-Schraffur 0%; Zugehöriger Raumname: Wohnen; Geschützt: no; Ursprungsgeschoss Name: EG; Ursprungsgeschoss Nummer: 0; Typ: Tür; Überobjekt-ID: Wand-006; Oberfläche (Alle): Metall Stahl, matt; Fensterrahmen; Von Raum: Wohnen; zu Raum: Wohnen; Lage: Innen; Tragende Funktion: Nicht tragende Elemente; Anzeigen auf Umbau-Filter: Alle relevanten Filter; Umbau-Status: Bestand; Anschlagsmaße: 1,510×2,010; Größe Wandloch: 1,510×2,010; Größe laut Eingabe: 1,510×2,010; Größe Ausgang: 1,410×1,960; Türblatt-Maß: 1,410×1,960; Nominale B x H: 1,510×2,010; Nominale B x H x T: 1,510×2,010×0,175; Wandstruktur: WI | MW_tr; Öffnung Bibliothekselementname: Eingangstür 02 2 22; Öffnungsseite Schraffurindex: Misch-Schraffur 0%; ARCHICAD Klassifizierung - 22: Tür
AC_Pset_Eingangstür_02_2_22 - Wandkontur (0-Keine,1-Voll,2-Seite,3-Länge): 0; Fixpunkte 0-Kein,1-2D,2-3D,3-Alle: 3; 2D-Fixpunkte in 3D zeigen: yes; Darstellungseinstellung Grundr.: 3; Winkel Öffnungsposition: 0 deg; Loch übernimmt Oberflächenmaterial der Wandseite: yes; Öffnungsoberfläche ist gebogen in gebogenen Wänden: no; Wand-Typ: 1; Laibung Ankerposition: 1; Wandquerschnittstyp: 1; Öffnungsrichtung: 1; Heizkörpernische: 2; Nominalmaß: 0; Rohbauöffnung als Nominalmaß einstellen: no; Architekturlichte als Nominalmaß einstellen: yes; Rahmen-Außenmaß als Nominalmaß einstellen: no; Baurichtmaß als Nominalmaß einstellen: no; Freies Öffnungsmaß als Nominalmaß einstellen: no; Türblattmaß als Nominalmaß einstellen: no; Übertrage aktuelle Nominal Größe auf die Auswahl: yes; Einheitliche Panele pro Blatt 1: no; Einheitliche Panele pro Blatt 2: no; Türblatt: 1; Türblatt 2: 1; Sprossen - horizontal: 3; Sprossen - horizontal 2: 3; Sprossen - vertical: 2; Sprossen - vertikal 2: 2; Symmetrische Teilung: yes; Klinketyp (gs_handle_type): Vertikaler Stab 1; Klinketyp (gs_handle_type_m): 20; Klinkentyp 2: 20; Oberlicht (gs_kamp): yes; Rahmentyp (gs_frame_type): Umfassungszarge; Rahmentyp (iFrameType): 4; Unterschiedliche Breiten: no; Seite Laibung: yes; Rahmen: Fensterrahmen; Paneel: Fensterrahmen; Glas: Glas Normalglas; Metallteile: Metall Stahl, matt; Türfüllung: Farbe, grau; Sprossen: Fensterrahmen; Griff: Metall Stahl, matt; Griff Zubehör: Metall Stahl, matt; Schwelle Oberflächenmaterial: Holz Esche; Schwelle Metallmaterial: Metall Stahl, gebürstet; Blindschwelle Oberflächenmaterial: Holz Esche; Einheitliche Oberflächen Verkleidung: yes; Innenverkleidung Oberflächenmaterial: Fensterrahmen; Außenverkleidung Oberflächenmaterial: Fensterrahmen; Schwelle (bThreshold): no; Standard-Schwelle Typ: 1; Blindschwelle: no; Schwelle in 2D: no; Stift Schwelle: Elemente+Text; Linientyp Schwelle: 1; Wandöffnung unter Schwelle (holeUnderThreshold): Keine Wandöffnung; Wandöffnung unter Schwelle (iHoleUnderThreshold): 0; Schwellensymbol nach SIA (showSIASymbol): Maßstabsabhängig; Schwellensymbol nach SIA (iShowSIASymbol): 0; Editierbare Schwellenhöhe im Symbol: no; Schwellentyp (SIASymbolType): Typ 1; Schwellentyp (iSIASymbolType): 1; Position Schwellensymbol (SIASymbolSide): Rechts; Position Schwellensymbol (iSIASymbolSide): 1; Stift Text: Elemente+Text; Symbol-Stift: Elemente+Text; Marker-Text: Arial; Schriftgröße: 1; Außenverkleidung: no; Futter Außen (gs_trimtype_out): Rechteckig; Futter Außen (gs_trimtype_out_int): 1; Gehäuse Kopftyp: 1; Querbalken oben: yes; Querbalken Typ oben: 1; Verkleidung (gs_trim_show_cover_out): yes; einheitliche Einfassungsbreiten (gs_trim_outside_uniform): yes; Futter Schnittlinienstift auf beiden Seiten: Elemente+Text; Schraffur Zarge außen: Nur Hintergrund-Stift; Innenverkleidung: no; Futter Innen (gs_trimtype_in): Rechteckig; Futter Innen (gs_trimtype_in_int): 1; Verkleidung (gs_trim_show_cover_in): yes; einheitliche Einfassungsbreiten (gs_trim_inside_uniform): yes; Schraffur Zarge innen: Nur Hintergrund-Stift; Fensterbank Außen: no; Schwelle/Türeinfassung Übergröße: no; Schwelle Winkel: 3 deg; Fensterbank ist gebogen in gebogenen Wänden: yes; Dämmung unter Fensterbank: yes; Wand-Dämmschicht benutzen: no; Rollschicht-Fensterbank 3D-Detaillierungsgrad: 1; Fensterbank Stift für 3D und Aufsicht: Elemente+Text; Fensterbank Schnitt Konturstift: Elemente+Text; Fensterbank Schnittschraffur: Nur Hintergrund-Stift; Dämmung Schnittlinien-Stift: Elemente+Text; Dämmung Schnittschraffur: Dämmung, hart 1; Dämmung Schnittschraffur-Vordergrundstift: Elemente+Text; Fensterbank Oberflächenmaterial: MW Ziegel, rotbraun, DF; Mauerwerksbrüstung Mörtel Oberflächenmaterial: Verputz, glatt, rot; Rollschicht (bMasonryArch): no; Rollschicht (gs_masonry_arch_int): 2; Typ Sturz (gs_masonry_arch_structure): Verputzt; Typ Sturz (gs_masonry_arch_structure_int): 1; Sturz direkt über der Tür: yes; Nische unterm Bogen: yes; Neigungswinkel: 75 deg; Eigenes Nischen-Oberflächenmaterial: no; Bogen Schnittschraffur: Erde 1; Bogen Schnittschraffur-Vordergrundstift: Konturstift; Bogen Schnittschraffur-Hintergrundstift: Schraffurhintergrund; Stift Ziegelsturz: Schraffur; Mauerwerksbogen Stein Oberflächenmaterial: MW Ziegel, blaurot, DF, Läufer; Mauerwerksbogen Mörtel Oberflächenmaterial: Verputz, rauh, grau; Mauerwerksbogen Schlusstein Oberflächenmaterial: Naturstein Kalkstein; Nischen-Oberflächenmaterial: Verputz, rauh, gelb; Typ Anschlag (gs_reveal_type_new): Keine Laibung - Ecke; Typ Anschlag (gs_reveal_type_int): 1; Untere Laibung Typ (gs_reveal_type_bottom): ohne Anschlag; Untere Laibung Typ (gs_reveal_type_bottom_int): 2; Äußerer Laibungstyp: ohne Anschlag; Typ Anschlag (gs_reveal_doubleOuterTypeInt): 0; Laibungstyp Innen: ohne Anschlag; Typ Anschlag (gs_reveal_doubleInnerTypeInt): 0; Anschlagtiefe und Laibungswinkel gleich: yes; Laibung bearbeiten von (gs_reveal_angle_edit_by): Winkel und Tiefe; Laibung bearbeiten von (gs_reveal_angle_edit_by_int): 1; Winkel Seite 2: 20 deg; Winkel Seite: 20 deg; Winkel oben: 20 deg; Winkel unten: 0 deg; Außenwinkel Seite 2: 20 deg; Außenwinkel Seite: 20 deg; Außenwinkel obere Seite: 20 deg; Außenwinkel untere Seite: 0 deg; Einbaurahmen: no; Einbaurahmen Aufsichtslinien-Stift: Elemente+Text; Einbaurahmen Konturstift (gs_mountingFrame_pen_cont): Elemente+Text; Einbaurahmen Schraffur (gs_mountingFrame_fill): Nur Hintergrund-Stift; Einbaurahmen Oberflächenmaterial: Holz Esche; Wandbekleidung benutzen: no; automatischer Schichteinzug Putz innen: yes; Putzschicht innen einziehen: 0; automatischer Schichteinzug Putz außen: yes; Putzschicht außen einziehen: 0; Bemaßungsfangpunkte in 2D: no; in 3D zeigen: no; Schichteinzug (gs_closure_type): Kein Schichteinzug; Schichteinzug (gs_closure_type_int): 1; Schicht an Seite einziehen (gs_cavity_side): Beide; Schicht an Seite einziehen (iCavityClosureSide): 1; Einzuziehende Schichten: 1; Schichten von (gs_nTurnDir): Außenseite; Schichten von (iCavityClosureTurnDir): 1; Schichteinzug auf Seite 2: yes; Schichteinzug auf Seite 1: yes; Schichteinzug oben: no; Schichteinzug unten: no; Schichteinzug zu Schicht: 1; Schichteinzug von Seite (gs_cc_dutch_ClosureToSide): 1; Schicht einziehen zu Abschluss: no; Dichtungsband einfügen: yes; Dichtungsband zeigen: yes; Konturlinien-Typ (gs_ltJoint): 1; Schraffur (gs_fillJoint): Nur Hintergrund-Stift; Schraffur-Vordergrundstift (gs_penJointFg): Elemente+Text; Eigenes Oberflächenmaterial: no; Oberflächenmaterial: Holz Esche; Konturlinien-Typ (gs_ltPlug): 1; Schraffur (gs_fillPlug): Nur Hintergrund-Stift; Schraffur-Vordergrundstift (gs_penPlugFg): Elemente+Text; Editierte Anschlagseite: 1; Editierte Wandseite: 1; Schicht Nummer: 1; Schicht einziehen: no; Schicht als Putz ansehen: no; Einzugsdicke: 1; Ausrichtung Schraffur: 1; Trennlinie am Einzug: no; Stift Trennlinie: Elemente+Text; Letzte ausgewählte Seite: no; Abschlussart automatisch verändert: no; Anschluss Links: no; Anschluss Rechts: no; Anschluss Oben: no; Sturzbrett: no; Fensterbank innen ist gebogen in gebogenen Wänden: yes; Fensterbank in Polygonwänden: 2; 2D-Detaillierungsgrad: 2; Stift Grundriss: Elemente+Text; Linientyp Grundriss: 4; 3D Stift: Elemente+Text; Ansichts-Stift: Elemente+Text; Schnittschraffur: Misch-Schraffur 50 %; Schnittschraffur-Vordergrundstift: Elemente+Text; Sturzbrett Oberflächenmaterial: Farbe, weiß; Sturzsystem: no; Hintersturz: no; autom. Hintersturzhöhe: no; Hinterer Sturz übernimmt Oberflächenmaterial der Wand: yes; Hinterer Sturz Oberflächenmaterial: Farbe, weiß; Hintersturz Schraffur (gs_hsturz_fillType): Nur Hintergrund-Stift; Hintersturz Schraffur-Vordergrundstift: Elemente+Text; Schnittlinienstift Hintersturz: Elemente+Text; Typ (iTypeProfiledLintel): 1; Dämmung (gs_zd): no; Sturz übernimmt Oberflächenmaterial der Wand: yes; Sturz Oberflächenmaterial: Farbe, weiß; Wärmedämmung Oberflächenmaterial: Farbe, weiß; Schnittlinien Stift: Konturstift; Sturz Schraffur: Nur Hintergrund-Stift; Sturz Schraffur-Vordergrundstift: Elemente+Text; Dämmung Schraffur 1: Nur Hintergrund-Stift; Dämmung Schraffur 2: Nur Hintergrund-Stift; Dämmung Schraffur-Vordergrundstift: Elemente+Text; Türeinfassung: no; 2D-Darstellung (bShowMounting2D): yes; Typ Fassung: 2; Falz: no; Pfosten: no; Befestigung Oberflächenmaterial: Fensterrahmen; Konturlinien-Stift: Elemente+Text; Kontur-Stift Sturz vorne: Elemente+Text; Kontur-Stift Sturz hinten: Elemente+Text; Schraffur-Vordergrundstift (gs_pen_sc): Elemente+Text; Schraffur-Hintergrundstift (gs_pen_h): Elemente+Text; Bedeckung Schraffur: Nur Vordergrund-Stift; Schwelle Schraffur: Nur Hintergrund-Stift; Schraffur (efsc2): Luftschicht; Schraffur Sturz vorne: Nur Hintergrund-Stift; Dämmung Schraffur: Nur Hintergrund-Stift; Hintersturz Schraffur (efsc_h): Nur Hintergrund-Stift; Linientyp: 1; Sonnenschutz: no; Sonnenschutz-Typ: 1; Aktivierte Sonnenschutz-Typen: 254; Anzahl Lamellen: 2; Anzahl Paneelen 2: 1; Paneel-Position (gs_shutter_panelPos): Symmetrisch; Paneel-Position (gs_shutter_iPanelPos): 1; Automatische Höhenanpassung: yes; Extra Rahmen: no; Abdeckungstyp (gs_slidingShutter_cover): Z-Profil; Abdeckungstyp (gs_slidingShutter_iCover): 1; Stapelrichtung (gs_foldingShutter_stacking): Innen; Stapelrichtung (gs_foldingShutter_iStacking): 1; in 3D geöffnet: yes; 3D-Öffnungswinkel: 180 deg; 2D-Symbol zeigen: yes; Öffnungslinie im Symbol zeigen: yes; Sonnenschutz-Symbol-Linientyp: 1; Sonnenschutz-Schnittlinien-Stift: Elemente+Text; Sonnenschutz Aufsichtslinien-Stift: Elemente+Text; Sonnenschutz Schnittschraffur: Nur Hintergrund-Stift; Sonnenschutz Schnittschraffur-Vordergrundstift: Elemente+Text; Verschattung Dämmung Schraffur: Dämmung, weich; Verschattung Dämmung Schraffur-Vordergrundstift: Elemente+Text; Verschattung Dämmung Schraffur-Hintergrundstift: Elemente+Text; Fensterladen Oberflächenmaterial: Holz Esche; Fensterladenrahmen Oberflächenmaterial: Holz Esche; Rollladengehäuse Oberflächenmaterial: Metall Chrom; Rollladenlamellen Oberflächenmaterial: Lack schwarz; Rollladen Schiene Oberflächenmaterial: Holz Parkett 1; Jalousie Oberflächenmaterial: Lack schwarz; Jalousielamellen Oberflächenmaterial: Lack schwarz; Schiebladen Schiene Oberflächenmaterial: Metall Chrom; Paneeltyp (gs_shutPanel_type): Stil 1; Paneeltyp (gs_shutPanel_iType): 1; Unterschiedliche Rahmen-Breite unten: no; Rollladen Breite: yes; Winkel Lamelle: 30 deg; Lochanzahl horizontal: 5; Lochanzahl vertikal: 8; Rollladen-Platzierung (gs_shutRoll_placement): Vor Fassade angebracht; Rollladen-Platzierung (gs_shutRoll_iPlacement): 1; Typ (gs_shutRoll_boxType): Rechteckig; Typ (gs_shutRoll_iBoxType): 1; Handlauf Position (gs_shutRoll_railPos): Auf Verkleidung; Handlauf Position (gs_shutRoll_iRailPos): 1; Verkleidung hinter Sonnenschutz zeigen (gs_shutRoll_showCasingBehind): yes; Wand hinter Kasten schneiden: yes; Höhe in Wandlochhöhe einschließen: no; Neigung Kastendach: 10 deg; Kasten–Breite (gs_shutRoll_boxDefaultSize): Architekturlichte Breite; Kasten–Breite (gs_shutRoll_iBoxDefaultSize): 1; Jalousien-Platzierung (gs_shutLam_placement): Vor Fassade angebracht; Jalousien-Platzierung (gs_shutLam_iPlacement): 1; Dämmung hinter Kasten: no; Geöffnetes Gehäuse: yes; Führungsschienen: yes; Handlauf Position (gs_shutLam_railPos): Auf Verkleidung; Handlauf Position (gs_shutLam_iRailPos): 1; Verkleidung hinter Sonnenschutz zeigen (gs_shutLam_showCasingBehind): yes; Kippwinkel (gs_shutLam_rotation): 45 deg; Kippwinkel (gs_shutLam2_rotation): 45 deg; Rahmen-Stift: Schichttrennlinien/Kontur; Rahmen Schnittschraffur: Nur Hintergrund-Stift; Türblatt-Stift: Schichttrennlinien/Kontur; Türblatt Schnittschraffur: Luftschicht; Glas Linienstift Kontur: Schichttrennlinien/Kontur; Glas Schnittschraffur: Nur Hintergrund-Stift; Glas Aufsichtslinien-Stift: Schichttrennlinien/Kontur; Rahmen Aufsichtslinien-Stift: Schichttrennlinien/Kontur; Rahmen Deckschraffur: Nur Hintergrund-Stift; Symbol ausrichten: 2; Öffnungswinkel für Durchgangsflügel in 2D: 90 deg; Öffnungswinkel für Standflügel in 2D: 90 deg; Öffnungswinkel für Durchgangsflügel in 3D: 90 deg; Öffnungswinkel für Standflügel in 3D: 90 deg; Gleicher Linientyp für Türblätter: yes; Modelldarstell. für symbolische 2D-Darstellung überschreiben: no; 2D-Öffnungslinien zeigen: yes; Öffnungslinien-Typ: 1; Nebenöffnung Linientyp in 2D: 4; Öffnungslinien-Form (or_SwingType): Gebogen; Öffnungslinien-Form (or_iSwingType): 1; Öffnungslinien-Form (or_SlidingType): Keine; Öffnungslinien-Form (or_iSlidingType): 0; 2D & 3D Öffnungslinien-Stift (or_opLinePen): Elemente+Text; 2D & 3D Öffnungslinien-Stift (or_iOpLinePen): 1; Modelldarstell. für 3D-Darstellung überschreiben: no; Öffnungslinie zeigen: yes; Linientyp Öffnungsseite (or_opLineType3dIn): Vollinie; Linientyp Öffnungsseite (or_iOpLineType3dIn): 0; Linientyp Gegenüberliegende Seite (or_opLineType3dOut): Strichlinie; Linientyp Gegenüberliegende Seite (or_iOpLineType3dOut): 1; Standflügel Linientyp in 3D: Strichlinie; Standflügel Linientyp: 1; Linien-Ausrichtung (or_oplineStyle): Griff; Linien-Ausrichtung (or_iOplineStyle): 1; Grundriss: 1; 3D: 8; Schnitt / Ansicht: 1; Anschlag im Grundriss zeigen: 1; Wandschraffur in der Öffnung: no; Schraffur (gs_wallhole_fill): Nur Hintergrund-Stift; Schraffur-Vordergrundstift (gs_wallhole_pen_fg): Elemente+Text; Schraffur-Hintergrundstift (gs_wallhole_pen_bg): Schraffurhintergrund; Türkoten: yes; Sichtbarkeit Türbemaßung (gs_etikett): Modelldarstellungs-Optionen; Sichtbarkeit Türbemaßung (iEtikett): 3; Öffnung roh: 1; Text Öffnung roh: Öffnung roh; Sturz fertig: 1; Text Fertig Sturz: Sturz fertig; OK Schwelle: 1; Text Schwelle Fertig: OK Schwelle; Schwelle (iDWDimRawParapet): 1; Text Schwelle: Schwelle; Texteinstellung (gs_Etikett_scaleValues): Maßstababhängig (Modellgröße); Massstab (gs_Etikett_scaleValues_m): 2; Schrifttyp (fontType): Arial; Schriftgröße (papier) (gs_Etikett_fontSize_mm): 0.75; Dimension Stift Text: Elemente+Text; X Position (m): 0; Position X (mm): 0; Y Position (m): 0; Position Y (mm): 4; Automat. Zeilenabstand: no; Zeilenabstand (papier): 0.5; Drehwinkel: 0 deg; Zeige die ID im Grundriss: no; Beschriftung Türtyp: 1; Automatische Tür ID: yes; Eigener Text: Eigene ID; Marker spiegeln: yes; Zusätzliche Werte zeigen (Öffnungsmass 1.20/1.50): yes; Text Position X (mm): 0; Text Position Y (mm): 4; Texteinstellung (gs_IDText_scaleValues): Maßstababhängig (Modellgröße); Massstab (gs_IDText_scaleValues_m): 2; Schriftgröße (papier) (gs_IDText_fontSize_mm): 1; Schrifttyp (gs_IDText_fontType): Arial; Text-Stift: Elemente+Text; Sturztiefe im Grundriss zeigen: no; Sturztiefe Symbol- Linientyp: 21; Sturztiefe Symbolstift: Konturstift; Öffnungstyp: 0; seitliche Wandkontur (gs_wallcontour): Beide; seitliche Wandkontur (gs_wallcontour_id): 1; Wandkontur (gs_wcont_line): beide Seiten; Wandkontur (iWallContourLine): 4; Automatische Einstellungen: yes; Wandkonturlinie innen - 1:50 und tiefer: yes; Wandkonturlinie innen - 1:100 und höher: yes; Wandkonturlinien Typ innen - 1:50 und tiefer: 1; Wandkonturlinien Typ innen - 1:100 und höher: 1; Wandkonturlinie außen - 1:50 und tiefer: yes; Wandkonturlinie außen - 1:100 und höher: yes; Wandkonturlinien Typ außen - 1:50 and tiefer: 1; Wandkonturlinien Typ außen - 1:100 und höher: 1; Wandkonturlinien Stift - 1:50 und tiefer: Elemente+Text; Wandkonturlinien Stift - 1:100 und höher: Elemente+Text; Typ Links: 0; Typ Rechts: 0; Automatische Maße: yes; Einbaurahmen Konturstift (gs_TolerBlin_contour_pen): Elemente+Text; Einbaurahmen Konturlinientyp: 1; Einbaurahmen Schraffur (gs_TolerBlin_fill_type): Nur Hintergrund-Stift; Einbaurahmen Schraffur-Vordergrundstift (gs_TolerBlin_fg_pen): Schichttrennlinien/Kontur; Schraffur-Stift Fugenausfüllung: Elemente+Text; Linientyp Kontur Fugenausfüllung: 1; Fugenausfüllung Schraffur: Nur Vordergrund-Stift; Fugenausfüllung Schraffur-Vordergrundstift: Schichttrennlinien/Kontur; Bearbeitende Fixpunkte zeigen: yes; IFC Betrieb (ifc_optypestr): Zweiflügeltür - Öffnungsflügel; IFC Betrieb (ifc_optype): 2; Linkes Seitenfeld: no; Rechtes Seitenfeld: no; Oberlicht (gs_door_transom): no; Bilder: 2; Tür gehört zum Raum, in den sie öffnet: yes; Preis: 0; Komplette Glasfläche: 0; Umfang der Glasfläche: 0; Dämmung (gs_list_bInsulation): no; Selbstschließend: no; Rauchschutz Tür: no; Rauchprobe Temperatur: 200; Dämmung Index: 2; Gruppe Typ (FM_Type): Türe; Gruppe Typ (iFMType): 999; Objektgewicht: 0; Objektgewichtseinheit: kg; Türausrichtungsdefinition: 0; Breite Wert: Durchgangslichte Breite; Breite: 141,00; Höhe Wert: Durchgangslichte Höhe; Höhe: 196,00; Wert ID Nummer: 0; zu Raum ID innen Wert: Eigene; zu Raum ID außen Wert: Eigene
Brandschutz 4102-2 - Kennbuchstabe: T
ArchiCADQuantities - Höhe: 2.01 m; Netto-Volumen: 0.166561 m3; Breite: 1.51 m; Höhenangabe zum Projekt-Nullpunkt: 0.2 m; Höhe zu 1. Referenzhöhe: 0.2 m; Höhe zu 2. Referenzhöhe: 0.2 m; Höhe zu Meereshöhe: 16.2 m; Höhe zu verknüpftem/Ursprungsgeschoss: 0.2 m; Abstand zu Ursprungsgeschoss: 0.2 m; Oberflächenbereich: 10.0784 m2; F/T Volumen der Öffnung: 0.531142 m3; F/T nominales Volumen der Öffnung: 0.531142 m3; F/T Oberfläche der Öffnung: 10.0784 m2; F/T Öffnung Nominaler Oberflächenbereich: 3.0351 m2; F/T Öffnungsbreite auf der Anschlagseite: 1.51 m; F/T Höhe der Öffnung auf der Anschlagseite: 2.01 m; F/T Öffnungsbreite gegenüber der Anschlagseite: 1.51 m; F/T Höhe der Öffnung gegenüber der Anschlagseite: 2.01 m; F/T Oberfläche der Öffnung auf der Anschlagseite: 3.0351 m2; F/T Oberfläche der Öffnung gegenüber der Anschlagseite: 3.0351 m2; Nominale F/T Öffnungsbreite auf der Anschlagseite: 1.51 m; Nominale F/T Höhe der Öffnung auf der Anschlagseite: 2.01 m; Nominale F/T Öffnungsbreite gegenüber der Anschlagseite: 1.51 m; Nominale F/T Höhe der Öffnung gegenüber der Anschlagseite: 2.01 m; Nominale F/T Öffnungsoberfläche auf der Anschlagsseite: 3.0351 m2; Nominale F/T Öffnungsoberfläche auf der Seite gegenüber der Anschlagsseite: 3.0351 m2; Brüstungshöhe: 0.2 m; F/T nominale Brüstungs-/Schwellenhöhe: 0.2 m; F/T Brüstungs-/Schwellenhöhe auf der Anschlagseite: 0.2 m; F/T Brüstungs-/Schwellenhöhe gegenüber der Anschlagseite: 0.2 m; F/T nominale Sturzhöhe: 2.21 m; F/T Sturzhöhe auf der Anschlagseite: 2.21 m; F/T Sturzhöhe gegenüber der Anschlagseite: 2.21 m; Wanddicke: 0.175 m; Rahmen-Stärke: 0.195 m
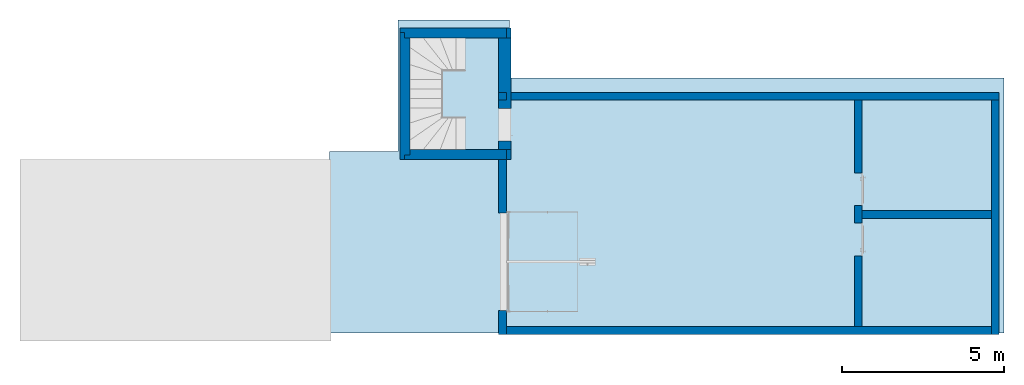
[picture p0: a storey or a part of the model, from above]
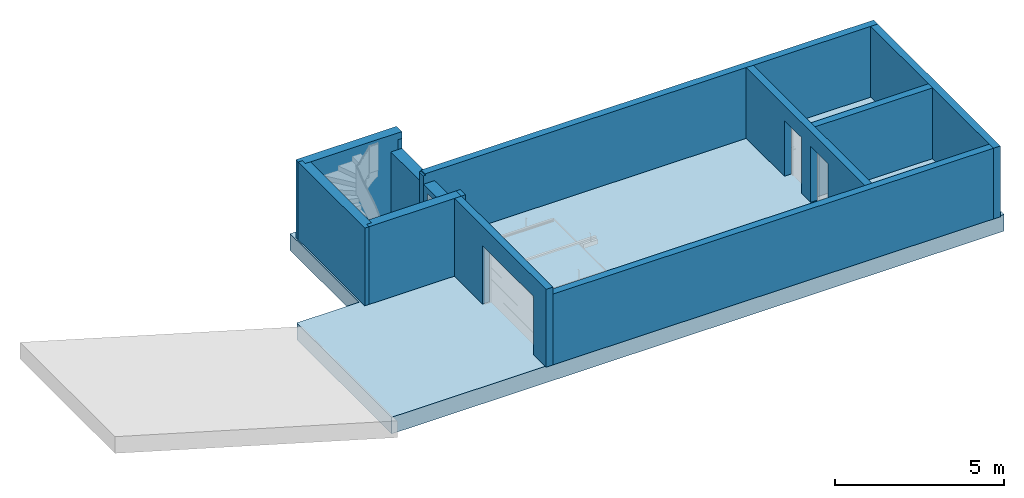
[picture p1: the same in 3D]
Properties of the parts of a building model (IFC4), part 9 of 13

# IfcBuildingElementProxy: Eingangstür 02 2 22 (2)
AC_Equantity_Eingangstür_02_2_22 - NominaleBreite: 1.51 m; NominaleHöhe: 2.01 m; Z-Achse: 1 m; Untere Ebene: 1 m; Obere Ebene: 0 m; Brüstungshöhe zum aktuellen Geschoss: 0.2 m; Laibung zum Wandkern: 0 m; Einbautoleranz links: 0 m; Einbautoleranz rechts: 0 m; Einbautoleranz oben: 0 m; Einbautoleranz unten: 0 m; Toleranz außen links: 0 m; Toleranz innen links: 0 m; Toleranz außen rechts: 0 m; Toleranz innen rechts: 0 m; Toleranz außen oben: 0 m; Toleranz innen oben: 0 m; Toleranz außen unten: 0 m; Toleranz innen unten: 0 m; Rohbauöffnung Breite: 1.51 m; Rohbauöffnung Höhe (ac_wallhole_height): 2.01 m; Rohbauöffnung Höhe (ac_wallhole_height_original): 2.01 m; Architekturlichte Breite: 1.51 m; Architekturlichte Höhe (ac_reveal_height): 2.01 m; Architekturlichte Höhe (ac_reveal_height_original): 2.01 m; Rahmen Breite: 1.51 m; Rahmen Höhe: 2.01 m; Breite Baurichtmaß: 1.51 m; Höhe Baurichtmaß: 2.01 m; Durchgangslichte Breite: 1.41 m; Durchgangslichte Höhe: 1.96 m; Nominale Türblatt Breite: 1.41 m; Nominale Türblatt Höhe: 1.96 m; Spalt unter Türblatt: 0 m; Türblatt Stärke: 0.04 m; Falzbreite: 0.01 m; Falztiefe: 0.02 m; Stärke Türfüllung: 0.02 m; Stärke Türfüllung 2: 0.02 m; Rahmen-Breite links: 0.1 m; Rahmen-Breite links 2: 0.1 m; Rahmen-Breite rechts: 0.1 m; Rahmenbreite rechts 2: 0.1 m; Rahmen-Breite unten (leafFrWidthBottom): 0.9 m; Rahmen-Breite unten 2: 0.9 m; Rahmen-Breite oben: 0.1 m; Rahmenbreite oben 2: 0.1 m; Sprossenbreite: 0.025 m; Sprossenbreite 2: 0.025 m; Sprossentiefe: 0.025 m; Sprossentiefe 2: 0.025 m; Radius Türfüllung: 0.2 m; Radius Türfüllung Radius 2: 0.2 m; Abstand Mittelpunkt - links: 0.5 m; Abstand Mittelpunkt - links 2: 0.5 m; Abstand Mittelpunkt - rechts: 1.3 m; Abstand Mittelpunkt - rechts 2: 1.3 m; Abstand Mittelpunkt - unten: 1.4 m; Abstand Mittelpunkt - unten 2: 1.4 m; Abstand Mittelpunkt - oben: 0.6 m; Abstand Mittelpunkt - oben 2: 0.6 m; Blatt Thk - Unten Extra: 0 m; Türblatt-Breite 1: 0.755 m; Griff-Höhe: 1.05 m; Klinkenhöhe 2: 1.05 m; Klinkeposition: 0.06 m; Klinkeposition 2: 0.06 m; Höhe Kämpfer (gs_am): 0.5 m; Rahmen-Breite: 0.05 m; Rahmenbreite Seite 1: 0.1 m; Rahmenbreite Seite 2: 0.1 m; Mittlerer Rahmen Seite 1: 0.1 m; Mittlerer Rahmen Seite 2: 0.1 m; Oberer Rahmen Breite: 0.1 m; Querbalkenrahmen Breite: 0.1 m; Seitenfeld Querbalkenrahmen Breite: 0.1 m; Seitenfeld oberer Rahmen Breite: 0.1 m; Untere Rahmenbreite: 0.1 m; Rahmen-Stärke: 0.195 m; Block Breite: 0.04 m; Block Stärke: 0.05 m; Mörtel: 0.01 m; Überstand 1: 0.01 m; Überstand 2: 0.01 m; Schwellenhöhe (thresholdHeight3D): 0.02 m; Schwellenhöhe (thresholdHeight1): 0.02 m; Schwellenhöhe (b): 0.02 m; Schwellenhöhe (c): 0.02 m; Eigene Wandöffnung Übergröße: 0.05 m; Position Schwelle (thresholdPos1): 0 m; Position Schwelle (thresholdPos2): 0 m; Position Schwelle (thresholdPos3): 0 m; Querbalken oben Breite: 0.02 m; Breite Seite 1 (gs_tw_right_out): 0.05 m; Breite Seite 2 (gs_tw_left_out): 0.05 m; Breite oben (gs_tw_top_out): 0.05 m; Stärke der Wand (gs_trim_thk_out): 0.019 m; Stärke des Wandlochs (gs_trim_width_out): 0.025 m; Abstand (gs_trim_offs_out): 0 m; Auskragung (gs_trim_jambext_nosing_out): 0.05 m; Oberer Überstand (gs_trimov_top_right_out): 0.1 m; Breite Seite 1 (gs_tw_right_in): 0.05 m; Breite Seite 2 (gs_tw_left_in): 0.05 m; Breite oben (gs_tw_top_in): 0.05 m; Stärke der Wand (gs_trim_thk_in): 0.019 m; Stärke des Wandlochs (gs_trim_width_in): 0.025 m; Abstand (gs_trim_offs_in): 0 m; Auskragung (gs_trim_jambext_nosing_in): 0.03 m; Oberer Überstand (gs_trimov_top_right_in): 0.1 m; Fensterbankbreite: 0 m; Fensterbank obere Breite: 0.01 m; Fensterbank obere Höhe: 0.01 m; Schwellendicke: 0.025 m; Fensterbank Vorderseite Stärke: 0.015 m; Schwelle Ansicht: 0.005 m; Fensterbank Tropfüberhang: 0.02 m; Stärke Fensterbankkante: 0.03 m; Schwelle Überstand: 0.03 m; Fensterbank Überhang links: 0 m; Fensterbank Überhang rechts: 0 m; Fensterbank Einschub Tiefe: 0.02 m; Fensterbank Einschub von Wand: 0 m; Hintere Lochtiefe (gs_sill_holeDepthBehind): 0 m; Steinbreite (gs_brick_sill_br_thk): 0.065 m; Fugenbreite (gs_brick_sill_mort_thk): 0.015 m; Distanz zwischen Bogen und Tür: 0 m; Sturz Überhang links: 0 m; Sturz Überhang rechts: 0 m; Sturz Bogenhöhe: 0.03 m; Projektion Sturz: 0 m; Höhe Sichtmauerwerk: 0.24 m; Tiefe Sichtmauerwerk: 0.115 m; Hintere Lochtiefe (gs_masonry_arch_rearHoleDepth): 0 m; Steinbreite (gs_masonry_arch_brick_thk): 0.052 m; Fugenbreite (gs_masonry_arch_mort_thk): 0.01 m; Keilsteinbreite: 0.1 m; Überhang Keilstein: 0 m; Projektion Keilstein: 0.01 m; Anschlagtiefe (gs_wido_sill): 0 m; Anschlagtiefe (AC_wido_sill): 0 m; Anschlagstiefe Seite 2: 0.05 m; Anschlagstiefe: 0.05 m; Innerer Anschlagstiefe Seite 2 (gs_reveal_splayed_innerLeft): 0.06 m; Innerer Anschlagstiefe (gs_reveal_splayed_innerRight): 0.06 m; Innerer Anschlagstiefe Seite 2 (gs_reveal_double_innerLeft): 0.06 m; Innerer Anschlagstiefe (gs_reveal_double_innerRight): 0.06 m; Tiefe des oberen Anschlags: 0.05 m; Tiefe des unteren Anschlags: 0.06 m; Tiefe Sturz Innen (gs_reveal_splayed_innerTop): 0.06 m; Tiefe Laibung Innen (gs_reveal_splayed_innerBottom): 0 m; Tiefe Sturz Innen (gs_reveal_double_innerTop): 0.06 m; Tiefe Laibung Innen (gs_reveal_double_innerBottom): 0 m; Tiefe äußerer Anschlag: 0.05 m; Seitenabschrägung Breite Seite 2: -1 m; Seitenabschrägung Breite Seite: -1 m; Obere Seitenabschrägung Breite: -1 m; Untere Seitenabschrägung Breite: -1 m; Außenabschrägung Breite Seite 2: -1 m; Außenabschrägung Breite Seite: -1 m; Äußere Abschrägung Breite an oberer Seite: -1 m; Breite äußere Abschrägung an Unterseite: -1 m; Einbaurahmen-Stärke: 0.06 m; Einbaurahmen-Breite links: 0.06 m; Einbaurahmen-Breite rechts: 0.06 m; Einbaurahmen-Breite oben: 0.06 m; Einbaurahmen-Breite unten: 0.06 m; Max. Putzdicke: 0.04 m; Abstand Schicht zu Abschluss: 0 m; Anschluss Breite: 0.038 m; Anschluss Stärke: 0.1 m; Streifen-Stärke: 0.025 m; Profilbreite: 0.075 m; Eigene Stärke: 0.015 m; Schichtüberlappung zu Rahmen-Tiefe: 0 m; Sturzbrett Stärke: 0.025 m; Sturzbrett Überstand: 0.03 m; Verkleidungsbreite Links: 0 m; Verkleidungsbreite Rechts: 0 m; Verkleidungsdicke: 0.28 m; Höhe Hintersturz (gs_hsturz_height): 0.08 m; Höhe Hintersturz (gs_hhs): 0.2 m; Stärke vorne: 0.06 m; Tiefe von Wandebene: 0 m; Stärke Dämmung 1: 0.03 m; Stärke Dämmung 2: 0.03 m; Versatz vom Fensterrahmen: 0 m; Stärke Metalplatte: 0.005 m; Breite: 0.07 m; Breite oben (efb_t1): 0.3 m; Stärke oben: 0.06 m; Breite Sturz außen: 0.06 m; Breite unten: 0.07 m; Schwellenbreite: 0.07 m; Vorstand v. Fassade: 0.025 m; Vorstand v. Fassade Fensterbank Außen: 0.05 m; Paneelhöhe: 1.5 m; Innerer Versatz: 0.02 m; Schließtiefe: 0 m; Extra Rahmen Breite: 0.04 m; Extra Rahmen Stärke: 0.03 m; Geländerbreite: 0.03 m; Türzapfen-Länge: 0.02 m; Türzapfen-Radius: 0.005 m; Paneel-Abstand: 0.006 m; Außen-Überhang: 0 m; Innere Paneel-Breite: 0.12 m; 3D-Öffnungslänge: 1.5 m; 3D geschlossene Länge: 0 m; 3D-Öffnungslänge 1 (gs_shutter_opLength_1): 0.56 m; 3D-Öffnungslänge 1 (gs_shutter_opLength_2): 0.14 m; 3D-Öffnungshöhe: 1.5 m; 3D geschlossene Höhe: 0 m; Paneeldicke: 0.05 m; Paneelrahmen-Breite: 0.05 m; Rahmen-Breite unten (gs_shutPanel_frameWidthBottom): 0.05 m; Paneelbreite: 0 m; Paneelfüllungs-Stärke: 0.01 m; Stärke Lamelle: 0.01 m; Breite Lamellen: 0.04 m; Horizontaler Rahmen Teiler-Breite: 0.05 m; Vertikaler Rahmen Teiler-Breite: 0.05 m; Durchmesser Öffnung: 0.01 m; Breite des vertikalen Bretts: 0.1 m; Z-Rahmen-Breite: 0.05 m; Z-Rahmen-Stärke: 0.025 m; Stärke der vertikalen Bretter: 0.025 m; Stärke der horizontalen Bretter: 0.025 m; Ungefähre Breite der vertikalen Bretter (gs_shutPanel_vertBoardW): 0.08 m; Ungefähre Breite der vertikalen Bretter (gs_shutPanel_horBoardW): 0.115 m; Kasten Höhe (gs_shutRoll_boxHeight): 0.2 m; Kasten Tiefe: 0.15 m; Kasten Abstand links: 0 m; Kasten Abstand recht: 0 m; Tiefe Schiene: 0.0725 m; Abstand von Wand: 0 m; Abstand oben (gs_shutRoll_distFromHead): 0 m; Rollladen-Lamellen-Höhe: 0.05 m; Kasten Höhe (gs_shutLam_boxHeight): 0.2 m; Kasten-Breite (gs_shutLam_boxWidth): 0.15 m; Abdeckungstiefe: 0.04 m; Vorstand v. Wand: 0 m; Abstand oben (gs_shutLam_distFromHead): -0.2 m; Breite einer Rollade (gs_shutLam_segmentWidth): 0.06 m; Kasten Höhe (gs_shutLam2_boxHeight): 0.06 m; Kasten-Breite (gs_shutLam2_boxWidth): 0.06 m; Abst. v. Fenster: 0.06 m; Abstand oben (gs_shutLam2_distFromHead): 0.06 m; Kasten-Achshöhe von OK: 0 m; Breite einer Rollade (gs_shutLam2_segmentWidth): 0.06 m; Eigene Kote Öffnung roh: 0 m; Eigene Kote Brüstung fertig: 0 m; Eigene Kote Schwelle fertig: 0 m; Eigene Kote Schwelle: 0 m; Schriftgröße (modell) (gs_lsize): 0.075 m; Position X: 0 m; Position Y: 0.4 m; Zeilenabstand (modell): 0.05 m; Feste breite in mm (0= autom.): 0 m; Text Position X: 0 m; Text Position Y: 0.4 m; Schriftgröße (modell) (gs_IDText_fontSize_model): 0.1 m; Öffnungsseite Breite 2: 0.1 m; Öffnungsseite Breite 1: 0.1 m; Öffnungsseite Tiefe: 2 m; Gegenüberliegende Seite Breite 2: 0.1 m; Gegenüberliegende Seite Breite 1: 0.1 m; Gegenüberliegende Seite Tiefe: 1.2 m; Position Links: 0 m; Position Rechts: 0 m; Breite Links: 0 m; Breite Rechts: 0 m; Tiefe Links: 0.01 m; Tiefe Rechts: 0.01 m; AC Linkes Öffnungsübermaß: 0 m; AC Rechtes Öffnungsübermaß: 0 m; AC Oberes Öffnungsübermaß: 0 m; AC Unteres Öffnungsübermaß: 0 m; Seitenfeld Breite (gs_sidelight_width_left): 0 m; Seitenfeld Breite (gs_sidelight_width_right): 0 m; Höhe Kämpfer (gs_transom_height): 0 m
Türen/Fenster - Fenster/Türbreite: 1.51 m; Fenster/Türhöhe: 2.01 m
Name | Kollidierende Räume | Zugehörige Raumnummer = Zu Raum-Nummer | Von Raum-Nummer | Ausrichtung = Türausrichtung | Wandrichtungstyp | Schwellentyp (thresholdType) | Schwelle (iThresholdType) | Fensterbanktyp | Fenster/Türnummer | Öffnungsrichtung
Tür-005 | Erdgeschoss; Grundfläche Gebäude Nachgezogen; Wohnen; Wohnung2 EG | R-004 | R-009 | R | 0 | Normal | 1 | 2 | EG-R-004-Tür-005 | Links
Tür-005 | Erdgeschoss; Grundfläche Gebäude Nachgezogen; Wohnen; Wohnung1 EG | R-005 | R-006 | L | 1 | Schwellenbreite = Wandstärke | 5 | 8 | EG-R-005-Tür-005 | L | Pset_ConcreteElementGeneral - FireRating: T 30; Pset_FireRatingProperties - FireResistanceRating: T 30; Brandschutz 4102-2 - Feuerwiderstand 4102-2: T 30; Minuten (4102-2): 30; Baustoffklasse: A; Türen/Fenster - Schallschutzklasse: SK 3

# IfcBuildingElementProxy: Hecke 22, Hecke
In: EG
Classification: Geländegeometrie (ARCHICAD Klassifizierung)
ArchiCADProperties - Element ID: Hecke; Hotlink und Element-ID: Hecke; Ebene: Möblierung; Bibliothekselement-Name: Hecke 22; Baustoff / Mehrschichtiger Aufbau / Profil / Schraffur: Nur Hintergrund-Stift; Schraffurtyp: Nur Hintergrund-Stift; Kollidierende Räume: Erdgeschoss; Grundfläche Gebäude Nachgezogen; Terrasse; Terrasse; Terrasse Wohnung2 EG; Wohnung2 EG; Zugehöriger Raumname: Terrasse; Zugehörige Raumnummer: R-011; Geschützt: no; Ursprungsgeschoss Name: EG; Ursprungsgeschoss Nummer: 0; Typ: Objekt; Überobjekt-ID: Hecke; Oberfläche (Alle): Natur Gras 3; Lage: Außen; Tragende Funktion: Nicht definiert; Anzeigen auf Umbau-Filter: Alle relevanten Filter; Umbau-Status: Bestand; Drehwinkel: 270 deg; Oberfläche: Kunststoff PE, weiss; ARCHICAD Klassifizierung - 22: Geländegeometrie
AC_Pset_Hecke_22 - Hecken-Elementtyp: 1; Krümmungswinkel: 90 deg; Winkel (>0): 5; Polygon Blätter zufällig: no; Kippwinkel Blätter: 20 deg; Anzahl Blätter: 1200; 3D-Detaillierungsgrad: 1; Schatten: yes; 2D-Fixpunkte in 3D zeigen: yes; Konturstift: Elemente+Text; Schraffur: Nur Vordergrund-Stift; Schraffur-Vordergrundstift: Schraffurhintergrund; Schraffur-Hintergrundstift: Schraffurhintergrund; Blätter: Natur Gras 3; Preis: 0; Gruppe Typ (FM_Type): Andere; Gruppe Typ (iFMType): 25; Bezeichnung Wert: Bibliothekselementname; Zusätzliche Beschreibung (gs_onorm_name): Hecke 23; DIM Durchmesser: 199,50; DIM Höhe: 240,00; ID-Nummer: Hecke
ArchiCADQuantities - Fläche: 0.9975 m2; Höhe: 2.4 m; Netto-Volumen: 0 m3; Breite: 0.5 m; Höhenangabe zum Projekt-Nullpunkt: 0.2 m; Höhe zu 1. Referenzhöhe: 0.2 m; Höhe zu 2. Referenzhöhe: 0.2 m; Höhe zu Meereshöhe: 16.2 m; Höhe zu verknüpftem/Ursprungsgeschoss: 0.2 m; Abstand zu Ursprungsgeschoss: 0.2 m; Oberflächenbereich: 16.0498 m2; Länge (A): 1.995 m
AC_Equantity_Hecke_22 - Höhe: 2.4 m; Breite Hecke: 0.5 m; Radius innen (>0): 1 m; Durchmesser Blätter: 0.15 m; Untere Ebene: 1 m; Obere Ebene: 0 m
Component Quantities - Component 1, Schicht/Komponente Volumen: 0 m3

# IfcBuildingElementProxy: Hochschrank Einzeltür 22 (2)
In: EG
Classification: Möbel (ARCHICAD Klassifizierung)
ArchiCADProperties - Element ID: Küche-009; Hotlink und Element-ID: Küche-009; Ebene: Möblierung; Bibliothekselement-Name: Hochschrank Einzeltür 22; Baustoff / Mehrschichtiger Aufbau / Profil / Schraffur: Nur Hintergrund-Stift; Schraffurtyp: Nur Hintergrund-Stift; Zugehöriger Raumname: Wohnen; Geschützt: no; Ursprungsgeschoss Name: EG; Ursprungsgeschoss Nummer: 0; Typ: Objekt; Überobjekt-ID: Küche-009; Oberfläche (Alle): Metall Chrom; Farbe, weiß; Lage: Innen; Tragende Funktion: Nicht definiert; Anzeigen auf Umbau-Filter: Alle relevanten Filter; Umbau-Status: Bestand; Oberfläche: Kunststoff PE, weiss; ARCHICAD Klassifizierung - 22: Möbel
AC_Pset_Hochschrank_Einzeltür_22 - 3D-Detaillierungsgrad: 1; Oberschrank: yes; Fuß (bToeOn): yes; Sockel/Fußtyp (gs_toe_type): Komplett; Sockel/Fußtyp (gs_toe_type_m): 1; Anzahl Fachböden: 2; Arbeitsplattenkante sichtbar in 3D (side_vis): Beide; Seiten sichtbar: 3; Arbeitsplattenkante sichtbar in 3D (side_vis_mirror): Beide; Tür: Stil 1; Fronttyp: 1; Obere Tür: yes; Untere Tür: yes; Eckfase: no; Tür-Öffnungswinkel: 0 deg; Anz. der vertikalen unteren Türaufteilungen: 1; Anz. der horizontalen unteren Türaufteilungen: 2; Anz. der vertikalen oberen Türaufteilungen: 1; Anz. der horizontalen oberen Türaufteilungen: 1; Knöpfe (bKnob): yes; Knöpfe (gs_knob_type): Stil 1; Knopftyp: 1; Einbau: 0; Fuß und Paneel abhängig: 0; Linkes Abschlusspaneel (left_panel): no; Linkes Abschlusspaneel hat Unterschrankgröße: yes; Rechtes Abschlusspaneel (right_panel): no; Rechtes Abschlusspaneel hat Unterschrankgröße: yes; Linkes Abschlusspaneel (left_panel_mirror): no; Rechtes Abschlusspaneel (right_panel_mirror): no; Hinteres Abschlusspaneel: no; Hinteres Abschlusspaneel hat Unterschrankgröße: yes; Abschlusspaneel-Typ: Stil 1; 2D-Symbol Typ: Typ 1; Kanten sichtbar im 2D (side_vis2D): Beide; Kanten sichtbar im 2D (side_vis2D_m): 3; Kanten sichtbar im 2D (side_vis2D_mirror): Beide; Verdeckte 2D Kanten: 0; Konturstift: Konturstift; Schraffur: Nur Hintergrund-Stift; Auflösung: 16; Schatten: yes; Extra Fixpunkte verwenden: yes; Schrank (gs_cabinet_mat): Farbe, weiß; Fuß (toe_mat): Metall Chrom; Tür (Rahmen): Farbe, weiß; Tür (Verglasung): Glas Normalglas; Abschlusspaneel: Farbe, weiß; Knöpfe (gs_knob_mat): Metall Chrom; Fachböden: Farbe, weiß; 2D-Fixpunkte in 3D zeigen: no; Preis: 0; Gruppe Typ (FM_Type): Möbel; Gruppe Typ (iFMType): 16; Objektgewicht: 0; Objektgewichtseinheit: kg
ArchiCADQuantities - Fläche: 0.36 m2; Höhe: 2.1 m; Netto-Volumen: 0.155774 m3; Breite: 0.6 m; Höhenangabe zum Projekt-Nullpunkt: 0.2 m; Höhe zu 1. Referenzhöhe: 0.2 m; Höhe zu 2. Referenzhöhe: 0.2 m; Höhe zu Meereshöhe: 16.2 m; Höhe zu verknüpftem/Ursprungsgeschoss: 0.2 m; Abstand zu Ursprungsgeschoss: 0.2 m; Oberflächenbereich: 13.8614 m2; Länge (A): 0.6 m
AC_Equantity_Hochschrank_Einzeltür_22 - Schrank Breite: 0.6 m; Schrank Tiefe: 0.6 m; Schrank Höhe: 2.1 m; Höhe obere Tür: 0.6 m; Höhe unterer Schrank: 1.5 m; Fußhöhe: 0.09 m; Fuß Rücksprung: 0 m; Türdicke: 0.02 m; Türrahmen Breite (doorframe_w): 0.09 m; Oberer Knopf Horizontale Position: 0.05 m; Oberer Knopf Vertikale Position: 0.05 m; Unterer Knopf Horizontale Position: 0.05 m; Unterer Knopff Vertikale Position: 0.75 m; Knopfgröße: 0.1 m; Individueller Griff Länge: 0.1 m; Individueller Griff Höhe: 0.015 m; Individueller Griff Tiefe: 0.02 m; Linkes Abschlusspaneel Dicke: 0.02 m; Rechtes Abschlusspaneel Dicke: 0.02 m; Hinteres Abschlusspaneel Dicke: 0.02 m; Türrahmen Breite (doorframe_w_end): 0.09 m; Min. Platzbedarf vorne: 0.9 m; Untere Ebene: 1 m; Obere Ebene: 0 m; Höhe Türblatt: 0 m
Component Quantities - Component 1, Schicht/Komponente Volumen: 0.155774 m3
Name | Kollidierende Räume | Zugehörige Raumnummer | Drehwinkel (deg) | Zugehörigkeit
Küche-009 | Erdgeschoss; Grundfläche Gebäude Nachgezogen; Wohnen; Wohnung2 EG | R-004 | 180 | EG-R-004-Wohnen
Küche-009 | Erdgeschoss; Grundfläche Gebäude Nachgezogen; Wohnen; Wohnung1 EG | R-005 | 0 | EG-R-005-Wohnen

# IfcBuildingElementProxy: Hochschrank Einzeltür mit Backofen 22 (2)
In: EG
Classification: Möbel (ARCHICAD Klassifizierung)
ArchiCADProperties - Element ID: Küche-008; Hotlink und Element-ID: Küche-008; Ebene: Möblierung; Bibliothekselement-Name: Hochschrank Einzeltür mit Backofen 22; Baustoff / Mehrschichtiger Aufbau / Profil / Schraffur: Nur Hintergrund-Stift; Schraffurtyp: Nur Hintergrund-Stift; Zugehöriger Raumname: Wohnen; Geschützt: no; Ursprungsgeschoss Name: EG; Ursprungsgeschoss Nummer: 0; Typ: Objekt; Überobjekt-ID: Küche-008; Oberfläche (Alle): Metall Chrom; Glas Normalglas; Metall Stahl, matt; Farbe, weiß; Lage: Innen; Tragende Funktion: Nicht definiert; Anzeigen auf Umbau-Filter: Alle relevanten Filter; Umbau-Status: Bestand; Oberfläche: Kunststoff PE, weiss; ARCHICAD Klassifizierung - 22: Möbel
AC_Pset_Hochschrank_Einzeltür_mit_Backofen_22 - 3D-Detaillierungsgrad: 1; Oberschrank: yes; Fuß (bToeOn): yes; Sockel/Fußtyp (gs_toe_type): Komplett; Sockel/Fußtyp (gs_toe_type_m): 1; Anzahl Fachböden: 2; Arbeitsplattenkante sichtbar in 3D (side_vis): Beide; Seiten sichtbar: 3; Arbeitsplattenkante sichtbar in 3D (side_vis_mirror): Beide; Vorrichtungen: yes; Gerät-Typ (ApplType): Einfacher Ofen; Gerät-Typ (ApplType_m): 2; Stil Ofentür (OvenDoorStyle): Stil 1; Stil Ofentür (ApplStyle_m): 1; Tür: Stil 1; Fronttyp: 1; Obere Tür: yes; Untere Tür: yes; Eckfase: no; Tür-Öffnungswinkel: 0 deg; Anz. der vertikalen unteren Türaufteilungen: 1; Anz. der horizontalen unteren Türaufteilungen: 2; Anz. der vertikalen oberen Türaufteilungen: 1; Anz. der horizontalen oberen Türaufteilungen: 1; Knöpfe (bKnob): yes; Knöpfe (gs_knob_type): Stil 1; Knopftyp: 1; Einbau: 0; Fuß und Paneel abhängig: 0; Linkes Abschlusspaneel (left_panel): no; Linkes Abschlusspaneel hat Unterschrankgröße: yes; Rechtes Abschlusspaneel (right_panel): no; Rechtes Abschlusspaneel hat Unterschrankgröße: yes; Linkes Abschlusspaneel (left_panel_mirror): no; Rechtes Abschlusspaneel (right_panel_mirror): no; Hinteres Abschlusspaneel: no; Hinteres Abschlusspaneel hat Unterschrankgröße: yes; Abschlusspaneel-Typ: Stil 1; Gerät in 2D: no; Geräte-Linientyp: 21; Kanten sichtbar im 2D (side_vis2D): Beide; Kanten sichtbar im 2D (side_vis2D_m): 3; Kanten sichtbar im 2D (side_vis2D_mirror): Beide; Verdeckte 2D Kanten: 0; Konturstift: Konturstift; Schraffur: Nur Hintergrund-Stift; Auflösung: 16; Schatten: yes; Extra Fixpunkte verwenden: yes; Schrank (gs_cabinet_mat): Farbe, weiß; Fuß (toe_mat): Metall Chrom; Tür (Rahmen): Farbe, weiß; Tür (Verglasung): Glas Normalglas; Abschlusspaneel: Farbe, weiß; Knöpfe (gs_knob_mat): Metall Chrom; Fachböden: Farbe, weiß; Ofentür 1: Metall Chrom; Ofentür 2: Metall Stahl, matt; Ofenfenster: Glas Normalglas; Griff: Metall Chrom; Schalter: Metall Stahl, matt; 2D-Fixpunkte in 3D zeigen: no; Preis: 0; Gruppe Typ (FM_Type): Möbel; Gruppe Typ (iFMType): 16; Objektgewicht: 0; Objektgewichtseinheit: kg
ArchiCADQuantities - Fläche: 0.36 m2; Höhe: 2.1 m; Netto-Volumen: 0.162311 m3; Breite: 0.6 m; Höhenangabe zum Projekt-Nullpunkt: 0.2 m; Höhe zu 1. Referenzhöhe: 0.2 m; Höhe zu 2. Referenzhöhe: 0.2 m; Höhe zu Meereshöhe: 16.2 m; Höhe zu verknüpftem/Ursprungsgeschoss: 0.2 m; Abstand zu Ursprungsgeschoss: 0.2 m; Oberflächenbereich: 14.8551 m2; Länge (A): 0.6 m
AC_Equantity_Hochschrank_Einzeltür_mit_Backofen_22 - Schrank Breite: 0.6 m; Schrank Tiefe: 0.6 m; Schrank Höhe: 2.1 m; Höhe obere Tür: 0.7 m; Höhe unterer Schrank: 0.9 m; Fußhöhe: 0.09 m; Fuß Rücksprung: 0 m; Höhe: 0.5 m; Türdicke: 0.02 m; Türrahmen Breite (doorframe_w): 0.09 m; Oberer Knopf Horizontale Position: 0.05 m; Oberer Knopf Vertikale Position: 0.05 m; Unterer Knopf Horizontale Position: 0.05 m; Unterer Knopff Vertikale Position: 0.75 m; Knopfgröße: 0.1 m; Individueller Griff Länge: 0.1 m; Individueller Griff Höhe: 0.015 m; Individueller Griff Tiefe: 0.02 m; Linkes Abschlusspaneel Dicke: 0.02 m; Rechtes Abschlusspaneel Dicke: 0.02 m; Hinteres Abschlusspaneel Dicke: 0.02 m; Türrahmen Breite (doorframe_w_end): 0.09 m; Min. Platzbedarf vorne: 0.9 m; Min. Platzbedarf auf Seite 1: 0 m; Min. Platzbedarf auf Seite 2: 0 m; Untere Ebene: 1 m; Obere Ebene: 0 m; Höhe Türblatt: 0 m
Component Quantities - Component 1, Schicht/Komponente Volumen: 0.162311 m3
Name | Kollidierende Räume | Zugehörige Raumnummer | Drehwinkel (deg) | Zugehörigkeit
Küche-008 | Erdgeschoss; Grundfläche Gebäude Nachgezogen; Wohnen; Wohnung1 EG | R-005 | 0 | EG-R-005-Wohnen
Küche-008 | Erdgeschoss; Grundfläche Gebäude Nachgezogen; Wohnen; Wohnung2 EG | R-004 | 180 | EG-R-004-Wohnen

# IfcBuildingElementProxy: Sektionaltor 22, Tür-003
In: -1. Geschoss
Classification: Tür (ARCHICAD Klassifizierung)
Pset_FireRatingProperties - FireResistanceRating: F60
ArchiCADProperties - Element ID: Tür-003; Hotlink und Element-ID: Tür-003; Ebene: Wand Aussen; Bibliothekselement-Name: Sektionaltor 22; Baustoff / Mehrschichtiger Aufbau / Profil / Schraffur: Misch-Schraffur 0%; Schraffurtyp: Misch-Schraffur 0%; Kollidierende Räume: Garage; Tiefgaragenabfahrt; Untergeschoss UG; Zugehöriger Raumname: Garage; Zugehörige Raumnummer: R-013; Geschützt: no; Ursprungsgeschoss Name: -1. Geschoss; Ursprungsgeschoss Nummer: -1; Typ: Tür; Überobjekt-ID: Wand-004; Oberfläche (Alle): Metall Stahl, poliert; Metall Aluminium, matt; Von Raum: Untergeschoss UG; Von Raum-Nummer: R-024; zu Raum: Garage; Zu Raum-Nummer: R-013; Lage: Außen; Tragende Funktion: Nicht tragende Elemente; Anzeigen auf Umbau-Filter: Alle relevanten Filter; Umbau-Status: Bestand; Anschlagsmaße: 3,010×2,100; Größe Wandloch: 3,010×2,100; Größe laut Eingabe: 3,130×2,160; Größe Ausgang: 2,890×2,040; Türblatt-Maß: 2,950×2,160; Nominale B x H: 3,010×2,100; Nominale B x H x T: 3,010×2,100×0,240; Wandstruktur: Beton, WU-Beton; Ausrichtung: L; Öffnung Bibliothekselementname: Sektionaltor 22; Öffnungsseite Schraffurindex: Misch-Schraffur 0%; ARCHICAD Klassifizierung - 22: Tür
AC_Pset_Sektionaltor_22 - Wandkontur (0-Keine,1-Voll,2-Seite,3-Länge): 0; Fixpunkte 0-Kein,1-2D,2-3D,3-Alle: 3; 2D-Fixpunkte in 3D zeigen: yes; Darstellungseinstellung Grundr.: 3; Winkel Öffnungsposition: 0 deg; Loch übernimmt Oberflächenmaterial der Wandseite: yes; Öffnungsoberfläche ist gebogen in gebogenen Wänden: no; Wand-Typ: 1; Wandrichtungstyp: 1; Laibung Ankerposition: 2; Wandquerschnittstyp: 1; Öffnungsrichtung: 0; Heizkörpernische: 1; Spiegeln (ac_wido_flip_once): no; Spiegeln (ac_wido_flip_disable): 1; Einbaumethode (installMethod): Auf der Innenseite der Wand; Einbaumethode (iInstallMethod): 1; Wandverbindung (connectElement): Einfach im Wandloch; Wandverbindung (iConnectElement): 1; Nominalmaß: 0; Rohbauöffnung als Nominalmaß einstellen: no; Architekturlichte als Nominalmaß einstellen: yes; Rahmen-Außenmaß als Nominalmaß einstellen: no; Baurichtmaß als Nominalmaß einstellen: no; Freies Öffnungsmaß als Nominalmaß einstellen: no; Türblattmaß als Nominalmaß einstellen: no; Übertrage aktuelle Nominal Größe auf die Auswahl: yes; Geneigte Decke: no; Decke Winkel: 30 deg; Oberlicht (gs_kamp): no; Rohrmontiert: yes; Fassadenpaneel auf Blatt: no; Abdeckung Toleranzspalt: no; Rahmentyp (gs_frame_type): Standard; Seite Laibung: yes; Anzahl der Paneele vertikal: 7; Motor Position (stMotorPosition): Unten; Motor Position (iMotorPosition): 2; Halterung: yes; Türblatttyp: 1; Anzahl der Paneele horizontal: 1; Sprossen - horizontal: 3; Sprossen - vertical: 2; Rahmen: Metall Aluminium, matt; Türblatt (gs_leaf_mat): Metall Aluminium, matt; Bodenabschluss: Metall Stahl, poliert; Fassadenpaneel: Holz Esche; Abdeckungsprofil: Verputz, rauh, grau; Glas: Glas Normalglas; Metallteile: Metall Stahl, matt; Türfüllung: Farbe, grau; Sprossen: Fensterrahmen; Griff: Metall Stahl, matt; Griff Zubehör: Metall Stahl, matt; Schwelle Oberflächenmaterial: Holz Esche; Schwelle Metallmaterial: Metall Stahl, gebürstet; Blindschwelle Oberflächenmaterial: Holz Esche; Einheitliche Oberflächen Verkleidung: yes; Innenverkleidung Oberflächenmaterial: Fensterrahmen; Außenverkleidung Oberflächenmaterial: Fensterrahmen; Schwelle (bThreshold): no; Schwellentyp (thresholdType): Schwellenbreite = Wandstärke; Schwelle (iThresholdType): 5; Standard-Schwelle Typ: 1; Blindschwelle: no; Schwelle in 2D: no; Stift Schwelle: Elemente+Text; Linientyp Schwelle: 1; Wandöffnung unter Schwelle (holeUnderThreshold): Wandöffnung zum aktuellen Geschoss; Wandöffnung unter Schwelle (iHoleUnderThreshold): 1; Schwellensymbol nach SIA (showSIASymbol): Maßstabsabhängig; Schwellensymbol nach SIA (iShowSIASymbol): 0; Editierbare Schwellenhöhe im Symbol: no; Schwellentyp (SIASymbolType): Typ 1; Schwellentyp (iSIASymbolType): 1; Position Schwellensymbol (SIASymbolSide): Rechts; Position Schwellensymbol (iSIASymbolSide): 1; Stift Text: Elemente+Text; Symbol-Stift: Elemente+Text; Marker-Text: Arial; Schriftgröße: 1; Außenverkleidung: no; Futter Außen (gs_trimtype_out): Einfach; Futter Außen (gs_trimtype_out_int): 1; Gehäuse Kopftyp: 1; Querbalken oben: yes; Querbalken Typ oben: 1; Verkleidung (gs_trim_show_cover_out): yes; einheitliche Einfassungsbreiten (gs_trim_outside_uniform): yes; Futter Schnittlinienstift auf beiden Seiten: Elemente+Text; Schraffur Zarge außen: Nur Hintergrund-Stift; Innenverkleidung: no; Futter Innen (gs_trimtype_in): Einfach; Futter Innen (gs_trimtype_in_int): 1; Verkleidung (gs_trim_show_cover_in): yes; einheitliche Einfassungsbreiten (gs_trim_inside_uniform): yes; Schraffur Zarge innen: Nur Hintergrund-Stift; Fensterbank Außen: no; Übergröße Fensterbank Außen: no; Fensterbanktyp: 1; Schwelle Winkel: 3 deg; Fensterbank ist gebogen in gebogenen Wänden: yes; Dämmung unter Fensterbank: yes; Wand-Dämmschicht benutzen: no; Rollschicht-Fensterbank 3D-Detaillierungsgrad: 1; Fensterbank Stift für 3D und Aufsicht: Elemente+Text; Fensterbank Schnitt Konturstift: Elemente+Text; Fensterbank Schnittschraffur: Nur Hintergrund-Stift; Dämmung Schnittlinien-Stift: Elemente+Text; Dämmung Schnittschraffur: Dämmung, hart 1; Dämmung Schnittschraffur-Vordergrundstift: Elemente+Text; Fensterbank Oberflächenmaterial: MW Ziegel, rotbraun, DF; Mauerwerksbrüstung Mörtel Oberflächenmaterial: Verputz, glatt, rot; Rollschicht (bMasonryArch): no; Rollschicht (gs_masonry_arch_int): 2; Typ Sturz (gs_masonry_arch_structure): Verputzt; Typ Sturz (gs_masonry_arch_structure_int): 1; Sturz direkt über der Tür: yes; Nische unterm Bogen: yes; Neigungswinkel: 75 deg; Eigenes Nischen-Oberflächenmaterial: no; Bogen Schnittschraffur: Erde 1; Bogen Schnittschraffur-Vordergrundstift: Schichttrennlinien/Kontur; Bogen Schnittschraffur-Hintergrundstift: Schraffurhintergrund; Stift Ziegelsturz: Schraffur; Mauerwerksbogen Stein Oberflächenmaterial: MW Ziegel, blaurot, DF, Läufer; Mauerwerksbogen Mörtel Oberflächenmaterial: Verputz, rauh, grau; Mauerwerksbogen Schlusstein Oberflächenmaterial: Naturstein Kalkstein; Nischen-Oberflächenmaterial: Verputz, rauh, gelb; Typ Anschlag (gs_reveal_type_new): Keine Laibung - Ecke; Typ Anschlag (gs_reveal_type_int): 1; Untere Laibung Typ (gs_reveal_type_bottom): ohne Anschlag; Untere Laibung Typ (gs_reveal_type_bottom_int): 2; Äußerer Laibungstyp: ohne Anschlag; Typ Anschlag (gs_reveal_doubleOuterTypeInt): 0; Laibungstyp Innen: ohne Anschlag; Typ Anschlag (gs_reveal_doubleInnerTypeInt): 0; Anschlagtiefe und Laibungswinkel gleich: no; Laibung bearbeiten von (gs_reveal_angle_edit_by): Winkel und Tiefe; Laibung bearbeiten von (gs_reveal_angle_edit_by_int): 1; Winkel Seite 2: 20 deg; Winkel Seite: 20 deg; Winkel oben: 20 deg; Winkel unten: 0 deg; Außenwinkel Seite 2: 20 deg; Außenwinkel Seite: 20 deg; Außenwinkel obere Seite: 20 deg; Außenwinkel untere Seite: 0 deg; Wandbekleidung benutzen: no; automatischer Schichteinzug Putz innen: yes; Putzschicht innen einziehen: 0; automatischer Schichteinzug Putz außen: yes; Putzschicht außen einziehen: 0; Bemaßungsfangpunkte in 2D: no; in 3D zeigen: no; Schichteinzug (gs_closure_type): Kein Schichteinzug; Schichteinzug (gs_closure_type_int): 1; Schicht an Seite einziehen (gs_cavity_side): Beide; Schicht an Seite einziehen (iCavityClosureSide): 1; Einzuziehende Schichten: 1; Schichten von (gs_nTurnDir): Außenseite; Schichten von (iCavityClosureTurnDir): 1; Schichteinzug auf Seite 2: yes; Schichteinzug auf Seite 1: yes; Schichteinzug oben: no; Schichteinzug unten: no; Schichteinzug zu Schicht: 1; Schichteinzug von Seite (gs_cc_dutch_ClosureToSide): 1; Schicht einziehen zu Abschluss: no; Dichtungsband einfügen: yes; Dichtungsband zeigen: yes; Konturlinien-Typ (gs_ltJoint): 1; Schraffur (gs_fillJoint): Nur Hintergrund-Stift; Schraffur-Vordergrundstift (gs_penJointFg): Elemente+Text; Eigenes Oberflächenmaterial: no; Oberflächenmaterial: Holz Esche; Konturlinien-Typ (gs_ltPlug): 1; Schraffur (gs_fillPlug): Nur Hintergrund-Stift; Schraffur-Vordergrundstift (gs_penPlugFg): Elemente+Text; Editierte Anschlagseite: 1; Editierte Wandseite: 1; Schicht Nummer: 1; Schicht einziehen: no; Schicht als Putz ansehen: no; Einzugsdicke: 1; Ausrichtung Schraffur: 1; Trennlinie am Einzug: no; Stift Trennlinie: Elemente+Text; Letzte ausgewählte Seite: no; Abschlussart automatisch verändert: no; Anschluss Links: no; Anschluss Rechts: no; Anschluss Oben: no; Sturzbrett: no; Fensterbank innen ist gebogen in gebogenen Wänden: yes; Fensterbank in Polygonwänden: 2; 2D-Detaillierungsgrad (iLintelBoardDetail2D): 2; Stift Grundriss: Elemente+Text; Linientyp Grundriss: 4; 3D Stift: Elemente+Text; Ansichts-Stift: Elemente+Text; Schnittschraffur: Misch-Schraffur 50 %; Schnittschraffur-Vordergrundstift: Elemente+Text; Sturzbrett Oberflächenmaterial: Farbe, weiß; Sturzsystem: no; Hintersturz: no; autom. Hintersturzhöhe: yes; Hinterer Sturz übernimmt Oberflächenmaterial der Wand: yes; Hinterer Sturz Oberflächenmaterial: Farbe, weiß; Hintersturz Schraffur (gs_hsturz_fillType): Nur Hintergrund-Stift; Hintersturz Schraffur-Vordergrundstift: Elemente+Text; Schnittlinienstift Hintersturz: Elemente+Text; Typ (iTypeProfiledLintel): 1; Dämmung (gs_zd): yes; Sturz übernimmt Oberflächenmaterial der Wand: yes; Sturz Oberflächenmaterial: Farbe, weiß; Wärmedämmung Oberflächenmaterial: Farbe, weiß; Schnittlinien Stift: Konturstift; Sturz Schraffur: Nur Hintergrund-Stift; Sturz Schraffur-Vordergrundstift: Elemente+Text; Dämmung Schraffur 1: Nur Hintergrund-Stift; Dämmung Schraffur 2: Nur Hintergrund-Stift; Dämmung Schraffur-Vordergrundstift: Elemente+Text; Türeinfassung: no; 2D-Darstellung (bShowMounting2D): yes; Typ Fassung: 2; Falz: no; Pfosten: no; Befestigung Oberflächenmaterial: Fensterrahmen; Konturlinien-Stift: Elemente+Text; Kontur-Stift Sturz vorne: Elemente+Text; Kontur-Stift Sturz hinten: Elemente+Text; Schraffur-Vordergrundstift (gs_pen_sc): Elemente+Text; Bedeckung Schraffur: Nur Vordergrund-Stift; Schwelle Schraffur: Nur Hintergrund-Stift; Schraffur (efsc2): Luftschicht; Schraffur Sturz vorne: Nur Hintergrund-Stift; Dämmung Schraffur: Nur Hintergrund-Stift; Hintersturz Schraffur (efsc_h): Nur Hintergrund-Stift; Linientyp: 4; Sonnenschutz: no; Sonnenschutz-Typ: -1; Aktivierte Sonnenschutz-Typen: 0; Anzahl Lamellen: 2; Anzahl Paneelen 2: 1; Paneel-Position (gs_shutter_panelPos): Symmetrisch; Paneel-Position (gs_shutter_iPanelPos): 1; Automatische Höhenanpassung: yes; Extra Rahmen: no; Abdeckungstyp (gs_slidingShutter_cover): Z-Profil; Abdeckungstyp (gs_slidingShutter_iCover): 1; Stapelrichtung (gs_foldingShutter_stacking): Innen; Stapelrichtung (gs_foldingShutter_iStacking): 1; in 3D geöffnet: yes; 3D-Öffnungswinkel: 180 deg; 2D-Symbol zeigen: yes; Öffnungslinie im Symbol zeigen: yes; Sonnenschutz-Symbol-Linientyp: 1; Sonnenschutz-Schnittlinien-Stift: Elemente+Text; Sonnenschutz Aufsichtslinien-Stift: Elemente+Text; Sonnenschutz Schnittschraffur: Nur Hintergrund-Stift; Sonnenschutz Schnittschraffur-Vordergrundstift: Elemente+Text; Verschattung Dämmung Schraffur: Dämmung, weich; Verschattung Dämmung Schraffur-Vordergrundstift: Elemente+Text; Verschattung Dämmung Schraffur-Hintergrundstift: Elemente+Text; Fensterladen Oberflächenmaterial: Holz Esche; Fensterladenrahmen Oberflächenmaterial: Holz Esche; Rollladengehäuse Oberflächenmaterial: Metall Chrom; Rollladenlamellen Oberflächenmaterial: Lack schwarz; Rollladen Schiene Oberflächenmaterial: Holz Parkett 1; Jalousie Oberflächenmaterial: Lack schwarz; Jalousielamellen Oberflächenmaterial: Lack schwarz; Schiebladen Schiene Oberflächenmaterial: Metall Chrom; Paneeltyp (gs_shutPanel_type): Stil 1; Paneeltyp (gs_shutPanel_iType): 1; Unterschiedliche Rahmen-Breite unten: no; Rollladen Breite: yes; Winkel Lamelle: 30 deg; Lochanzahl horizontal: 5; Lochanzahl vertikal: 8; Rollladen-Platzierung (gs_shutRoll_placement): Vor Fassade angebracht; Rollladen-Platzierung (gs_shutRoll_iPlacement): 1; Typ (gs_shutRoll_boxType): Rechteckig; Typ (gs_shutRoll_iBoxType): 1; Handlauf Position (gs_shutRoll_railPos): Auf Verkleidung; Handlauf Position (gs_shutRoll_iRailPos): 1; Verkleidung hinter Sonnenschutz zeigen (gs_shutRoll_showCasingBehind): yes; Wand hinter Kasten schneiden: yes; Neigung Kastendach: 10 deg; Kasten–Breite (gs_shutRoll_boxDefaultSize): Architekturlichte Breite; Kasten–Breite (gs_shutRoll_iBoxDefaultSize): 1; Jalousien-Platzierung (gs_shutLam_placement): Vor Fassade angebracht; Jalousien-Platzierung (gs_shutLam_iPlacement): 1; Dämmung hinter Kasten: no; Geöffnetes Gehäuse: yes; Führungsschienen: yes; Handlauf Position (gs_shutLam_railPos): Auf Verkleidung; Handlauf Position (gs_shutLam_iRailPos): 1; Verkleidung hinter Sonnenschutz zeigen (gs_shutLam_showCasingBehind): yes; Kippwinkel (gs_shutLam_rotation): 45 deg; Kippwinkel (gs_shutLam2_rotation): 45 deg; Rahmen-Stift: Schichttrennlinien/Kontur; Rahmen Schnittschraffur: Nur Hintergrund-Stift; Türblatt-Stift: Schichttrennlinien/Kontur; Türblatt Schnittschraffur: Luftschicht; Fassadenpaneel Stift: Elemente+Text; Fassadenpaneel Schraffur: Luftschicht; Glas Linienstift Kontur: Schichttrennlinien/Kontur; Glas Schnittschraffur: Nur Hintergrund-Stift; Glas Aufsichtslinien-Stift: Schichttrennlinien/Kontur; Rahmen Aufsichtslinien-Stift: Schichttrennlinien/Kontur; Rahmen Deckschraffur: Nur Hintergrund-Stift; Symbol ausrichten: 2; Geschlossen: yes; Öffnungslinien-Typ (gs_opline_type_2D): 4; Öffnungswinkel in 2D: 90 deg; Öffnungswinkel in 3D: 0 deg; Modelldarstell. für symbolische 2D-Darstellung überschreiben: no; 2D-Öffnungslinien zeigen: yes; Öffnungslinien-Typ (or_swingLineType): 1; Nebenöffnung Linientyp in 2D: 4; Öffnungslinien-Form (or_SwingType): Gebogen; Öffnungslinien-Form (or_iSwingType): 1; Öffnungslinien-Form (or_SlidingType): Keine; Öffnungslinien-Form (or_iSlidingType): 0; 2D & 3D Öffnungslinien-Stift (or_opLinePen): Elemente+Text; 2D & 3D Öffnungslinien-Stift (or_iOpLinePen): 1; Modelldarstell. für 3D-Darstellung überschreiben: no; Öffnungslinie zeigen: yes; Linientyp Öffnungsseite (or_opLineType3dIn): Vollinie; Linientyp Öffnungsseite (or_iOpLineType3dIn): 0; Linientyp Gegenüberliegende Seite (or_opLineType3dOut): Strichlinie; Linientyp Gegenüberliegende Seite (or_iOpLineType3dOut): 1; Standflügel Linientyp in 3D: Strichlinie; Standflügel Linientyp: 1; Linien-Ausrichtung (or_oplineStyle): Griff; Linien-Ausrichtung (or_iOplineStyle): 1; Klinketyp: Griff 1; 2D-Detaillierungsgrad (iDWDet2D): 1; 3D-Detaillierungsgrad: 8; Schnitt / Ansicht: 1; Anschlag im Grundriss zeigen: 1; Wandschraffur in der Öffnung: no; Schraffur (gs_wallhole_fill): Nur Hintergrund-Stift; Schraffur-Vordergrundstift (gs_wallhole_pen_fg): Elemente+Text; Schraffur-Hintergrundstift (gs_wallhole_pen_bg): Schraffurhintergrund; Türkoten: yes; Sichtbarkeit Türbemaßung (gs_etikett): Modelldarstellungs-Optionen; Sichtbarkeit Türbemaßung (iEtikett): 3; Öffnung roh: 1; Text Öffnung roh: Öffnung roh; Sturz fertig: 1; Text Fertig Sturz: Sturz fertig; OK Schwelle: 1; Text Schwelle Fertig: OK Schwelle; Schwelle (iDWDimRawParapet): 1; Text Schwelle: Schwelle; Texteinstellung (gs_Etikett_scaleValues): Maßstababhängig (Modellgröße); Massstab (gs_Etikett_scaleValues_m): 2; Schrifttyp (fontType): Arial; Schriftgröße (papier) (gs_Etikett_fontSize_mm): 1.5; Dimension Stift Text: Elemente+Text; X Position (m): 0; Position X (mm): 0; Y Position (m): 0; Position Y (mm): 2; Automat. Zeilenabstand: no; Zeilenabstand (papier): 1; Drehwinkel: 0 deg; Zeige die ID im Grundriss: no; Beschriftung Türtyp: 1; Automatische Tür ID: yes; Eigener Text: Eigene ID; Marker spiegeln: yes; Zusätzliche Werte zeigen (Öffnungsmass 1.20/1.50): yes; Text Position X (mm): 0; Text Position Y (mm): 8; Texteinstellung (gs_IDText_scaleValues): Maßstababhängig (Modellgröße); Massstab (gs_IDText_scaleValues_m): 2; Schriftgröße (papier) (gs_IDText_fontSize_mm): 2; Schrifttyp (gs_IDText_fontType): Arial; Text-Stift: Elemente+Text; Sturztiefe im Grundriss zeigen: no; Sturztiefe Symbol- Linientyp: 21; Sturztiefe Symbolstift: Konturstift; Ladebrücke: no; Ladebrücke in 2D zeigen: yes; Plattform-Drehung: 0 deg; Ladebrücken-Rahmenmaterial: 1; Dock Leveler Oberflächenmaterial: Metall Stahl, gebürstet; Ladebrücken-Stift: Elemente+Text; Ladebrücken-Linientyp: 1; Puffer: no; Puffer in 2D zeigen: yes; Puffer Oberflächenmaterial: Verputz, glatt, gelb; Puffer-Stift: Elemente+Text; Puffer-Linientyp: 1; Ladeplattformschutzdach: no; Ladeplattformschutzdach in 2D zeigen: yes; Dock Schutzwand Oberflächenmaterial: Verputz, glatt, weiß; Schutzdach-Stift: Elemente+Text; Schutzdach-Vorhänge: yes; Dock Schutzvorhang Oberflächenmaterial: Asphalt; Schutzdach Wandschraffur: MW Kalksandstein; Schutzdach Wandschraffur-Vordergrundstift: Elemente+Text; Schutzdach WandsSchraffur-Hintergrundstift: Transparent; Wandlinie des Kastens: 1; 2D-Öffnungslinien-Typ des Kastens: 4; Schutzdach-Vorhang Linientyp 2D: 2; Öffnungstyp: 0; seitliche Wandkontur (gs_wallcontour): Beide; seitliche Wandkontur (gs_wallcontour_id): 1; Wandkontur (gs_wcont_line): beide Seiten; Wandkontur (iWallContourLine): 4; Automatische Einstellungen: yes; Wandkonturlinie innen - 1:50 und tiefer: yes; Wandkonturlinie innen - 1:100 und höher: yes; Wandkonturlinien Typ innen - 1:50 und tiefer: 1; Wandkonturlinien Typ innen - 1:100 und höher: 1; Wandkonturlinie außen - 1:50 und tiefer: yes; Wandkonturlinie außen - 1:100 und höher: yes; Wandkonturlinien Typ außen - 1:50 and tiefer: 1; Wandkonturlinien Typ außen - 1:100 und höher: 1; Wandkonturlinien Stift - 1:50 und tiefer: Elemente+Text; Wandkonturlinien Stift - 1:100 und höher: Elemente+Text; Typ Links: 0; Typ Rechts: 0; Automatische Maße: yes; Einbaurahmen Konturstift: Elemente+Text; Einbaurahmen Konturlinientyp: 1; Einbaurahmen Schraffur: Nur Hintergrund-Stift; Einbaurahmen Schraffur-Vordergrundstift: Schichttrennlinien/Kontur; Schraffur-Stift Fugenausfüllung: Elemente+Text; Linientyp Kontur Fugenausfüllung: 1; Fugenausfüllung Schraffur: Nur Vordergrund-Stift; Fugenausfüllung Schraffur-Vordergrundstift: Schichttrennlinien/Kontur; Bearbeitende Fixpunkte zeigen: yes; IFC Betrieb (ifc_optypestr): Andere; IFC Betrieb (ifc_optype): 12; Linkes Seitenfeld: no; Rechtes Seitenfeld: no; Oberlicht (gs_door_transom): no; Bilder: 6; Rahmentyp (iFrameType): 0; Tür gehört zum Raum, in den sie öffnet: yes; Preis: 0; Komplette Glasfläche: 0; Umfang der Glasfläche: 0; Dämmung (gs_list_bInsulation): no; Selbstschließend: no; Rauchschutz Tür: no; Rauchprobe Temperatur: 200; Dämmung Index: 2; Gruppe Typ (FM_Type): Türe; Gruppe Typ (iFMType): 999; Objektgewicht: 0; Objektgewichtseinheit: kg; Türausrichtungsdefinition: 1; Türausrichtung: L; Breite Wert: Durchgangslichte Breite; Breite: 289,00; Höhe Wert: Durchgangslichte Höhe; Höhe: 204,00; Wert ID Nummer: 0; zu Raum ID innen Wert: Eigene; zu Raum ID außen Wert: Eigene
Brandschutz 4102-2 - Kennbuchstabe: T
Türen/Fenster - Fenster/Türnummer: -1. Geschoss-R-013-Tür-003; Öffnungsrichtung: L; Fenster/Türbreite: 3.01 m; Fenster/Türhöhe: 2.1 m
ArchiCADQuantities - Höhe: 2.1 m; Netto-Volumen: 0.435466 m3; Breite: 3.01 m; Höhenangabe zum Projekt-Nullpunkt: -2.8 m; Höhe zu 1. Referenzhöhe: -2.8 m; Höhe zu 2. Referenzhöhe: -2.8 m; Höhe zu Meereshöhe: 13.2 m; Höhe zu verknüpftem/Ursprungsgeschoss: 0 m; Abstand zu Ursprungsgeschoss: 0 m; Oberflächenbereich: 27.3181 m2; F/T Volumen der Öffnung: 1.51704 m3; F/T nominales Volumen der Öffnung: 1.51704 m3; F/T Oberfläche der Öffnung: 27.3181 m2; F/T Öffnung Nominaler Oberflächenbereich: 6.321 m2; F/T Öffnungsbreite auf der Anschlagseite: 3.01 m; F/T Höhe der Öffnung auf der Anschlagseite: 2.1 m; F/T Öffnungsbreite gegenüber der Anschlagseite: 3.01 m; F/T Höhe der Öffnung gegenüber der Anschlagseite: 2.1 m; F/T Oberfläche der Öffnung auf der Anschlagseite: 6.321 m2; F/T Oberfläche der Öffnung gegenüber der Anschlagseite: 6.321 m2; Nominale F/T Öffnungsbreite auf der Anschlagseite: 3.01 m; Nominale F/T Höhe der Öffnung auf der Anschlagseite: 2.1 m; Nominale F/T Öffnungsbreite gegenüber der Anschlagseite: 3.01 m; Nominale F/T Höhe der Öffnung gegenüber der Anschlagseite: 2.1 m; Nominale F/T Öffnungsoberfläche auf der Anschlagsseite: 6.321 m2; Nominale F/T Öffnungsoberfläche auf der Seite gegenüber der Anschlagsseite: 6.321 m2; Brüstungshöhe: 0 m; F/T nominale Brüstungs-/Schwellenhöhe: 0 m; F/T Brüstungs-/Schwellenhöhe auf der Anschlagseite: 0 m; F/T Brüstungs-/Schwellenhöhe gegenüber der Anschlagseite: 0 m; F/T nominale Sturzhöhe: 2.1 m; F/T Sturzhöhe auf der Anschlagseite: 2.1 m; F/T Sturzhöhe gegenüber der Anschlagseite: 2.1 m; Wanddicke: 0.24 m; Rahmen-Stärke: 0.12 m
AC_Equantity_Sektionaltor_22 - NominaleBreite: 3.01 m; NominaleHöhe: 2.1 m; Z-Achse: 1 m; Untere Ebene: 1 m; Obere Ebene: 0 m; Brüstungshöhe zum aktuellen Geschoss: 0 m; Laibung zum Wandkern: 0 m; Einbautoleranz links: 0 m; Einbautoleranz rechts: 0 m; Einbautoleranz oben: 0 m; Einbautoleranz unten: 0 m; Toleranz außen links: 0 m; Toleranz innen links: 0 m; Toleranz außen rechts: 0 m; Toleranz innen rechts: 0 m; Toleranz außen oben: 0 m; Toleranz innen oben: 0 m; Toleranz außen unten: 0 m; Toleranz innen unten: 0 m; Rohbauöffnung Breite: 3.01 m; Rohbauöffnung Höhe (ac_wallhole_height): 2.1 m; Rohbauöffnung Höhe (ac_wallhole_height_original): 2.1 m; Architekturlichte Breite: 3.01 m; Architekturlichte Höhe (ac_reveal_height): 2.1 m; Architekturlichte Höhe (ac_reveal_height_original): 2.1 m; Rahmen Breite: 3.13 m; Rahmen Höhe: 2.16 m; Breite Baurichtmaß: 3.01 m; Höhe Baurichtmaß: 2.1 m; Durchgangslichte Breite: 2.89 m; Durchgangslichte Höhe: 2.04 m; Nominale Türblatt Breite: 2.95 m; Nominale Türblatt Höhe: 2.16 m; Abstand von der Laibung zu max. inneren Höhe: 0.32 m; Kopfraum: 0.22 m; Konstruktionshöhe: 2.32 m; Lichte Durchgangshöhe: 2.1 m; Höhe Kämpfer (gs_am): 0.5 m; Rohrbreite: 0.06 m; Rohrdicke: 0.2 m; Rahmen-Breite: 0.12 m; Rahmen-Stärke: 0.12 m; Anschlagtiefe (AC_wido_sill): 0 m; Anschlagtiefe (gs_wido_sill): 0 m; Alte Laibungstiefe: 0.16 m; Seitliche Einfassung Breite Seite 1: 0.05 m; Seitliche Einfassung Breite Seite 2: 0.05 m; Einfassungshöhe oben: 0.2 m; Fassadenpaneel Stärke: 0.04 m; Spalt zwischen Laibung und Fassadenpaneel: 0.025 m; Abdeckungsprofil Höhe: 0.3 m; Abdeckungsprofil Überhang: 0.1 m; Flächenbündig Paneelhöhe: 0.25 m; Flächenbündig Paneelüberhang: 0.05 m; Paneeldicke (ps): 0.05 m; Block Breite: 0.06 m; Block Stärke: 0.08 m; Mörtel: 0.01 m; Überstand 1: 0.01 m; Überstand 2: 0.02 m; Raumhöhe: 2.55 m; Dist. zw. Decke u. Halterung: 0.68 m; Abstand von Elementoberkante zu Deckenunterkante: 0.23 m; Türblatt Stärke: 0.05 m; Spalt unter Türblatt: 0 m; Falzbreite: 0.03 m; Falztiefe: 0.02 m; Stärke Türfüllung: 0.02 m; Rahmen-Breite links: 0.1 m; Rahmen-Breite rechts: 0.1 m; Rahmen-Breite unten (leafFrWidthBottom): 0.9 m; Rahmen-Breite oben: 0.1 m; Sprossenbreite: 0.025 m; Sprossentiefe: 0.025 m; Radius Türfüllung: 0.2 m; Abstand Mittelpunkt - links: 0.5 m; Abstand Mittelpunkt - rechts: 0 m; Abstand Mittelpunkt - unten: 1.4 m; Abstand Mittelpunkt - oben: 0 m; Schwellenhöhe (thresholdHeight3D): 0.02 m; Schwellenhöhe (thresholdHeight1): 0.02 m; Schwellenhöhe (b): 0.02 m; Schwellenhöhe (c): 0.02 m; Eigene Wandöffnung Übergröße: 0.05 m; Position Schwelle (thresholdPos1): 0 m; Position Schwelle (thresholdPos2): 0 m; Position Schwelle (thresholdPos3): 0 m; Querbalken oben Breite: 0.02 m; Breite Seite 1 (gs_tw_right_out): 0.05 m; Breite Seite 2 (gs_tw_left_out): 0.05 m; Breite oben (gs_tw_top_out): 0.05 m; Stärke der Wand (gs_trim_thk_out): 0.019 m; Stärke des Wandlochs (gs_trim_width_out): 0.025 m; Abstand (gs_trim_offs_out): 0 m; Auskragung (gs_trim_jambext_nosing_out): 0.05 m; Oberer Überstand (gs_trimov_top_right_out): 0.1 m; Breite Seite 1 (gs_tw_right_in): 0.05 m; Breite Seite 2 (gs_tw_left_in): 0.05 m; Breite oben (gs_tw_top_in): 0.05 m; Stärke der Wand (gs_trim_thk_in): 0.019 m; Stärke des Wandlochs (gs_trim_width_in): 0.025 m; Abstand (gs_trim_offs_in): 0 m; Auskragung (gs_trim_jambext_nosing_in): 0.03 m; Oberer Überstand (gs_trimov_top_right_in): 0.1 m; Fensterbankbreite: 0 m; Fensterbank obere Breite: 0.01 m; Fensterbank obere Höhe: 0.01 m; Schwellendicke: 0.025 m; Fensterbank Vorderseite Stärke: 0.015 m; Schwelle Ansicht: 0.005 m; Fensterbank Tropfüberhang: 0.02 m; Stärke Fensterbankkante: 0.03 m; Schwelle Überstand: 0.03 m; Fensterbank Überhang links: 0 m; Fensterbank Überhang rechts: 0 m; Fensterbank Einschub Tiefe: 0.02 m; Fensterbank Einschub von Wand: 0 m; Hintere Lochtiefe (gs_sill_holeDepthBehind): 0 m; Steinbreite (gs_brick_sill_br_thk): 0.065 m; Fugenbreite (gs_brick_sill_mort_thk): 0.015 m; Distanz zwischen Bogen und Tür: 0 m; Sturz Überhang links: 0 m; Sturz Überhang rechts: 0 m; Sturz Bogenhöhe: 0.03 m; Projektion Sturz: 0 m; Höhe Sichtmauerwerk: 0.24 m; Tiefe Sichtmauerwerk: 0.115 m; Hintere Lochtiefe (gs_masonry_arch_rearHoleDepth): 0 m; Steinbreite (gs_masonry_arch_brick_thk): 0.0525 m; Fugenbreite (gs_masonry_arch_mort_thk): 0.01 m; Keilsteinbreite: 0.1 m; Überhang Keilstein: 0 m; Projektion Keilstein: 0.01 m; Innerer Anschlagstiefe Seite 2 (gs_reveal_splayed_innerLeft): 0.06 m; Innerer Anschlagstiefe (gs_reveal_splayed_innerRight): 0.06 m; Innerer Anschlagstiefe Seite 2 (gs_reveal_double_innerLeft): 0.06 m; Innerer Anschlagstiefe (gs_reveal_double_innerRight): 0.06 m; Tiefe des unteren Anschlags: 0.06 m; Tiefe Sturz Innen (gs_reveal_splayed_innerTop): 0.06 m; Tiefe Laibung Innen (gs_reveal_splayed_innerBottom): 0 m; Tiefe Sturz Innen (gs_reveal_double_innerTop): 0.06 m; Tiefe Laibung Innen (gs_reveal_double_innerBottom): 0 m; Tiefe äußerer Anschlag: 0.05 m; Seitenabschrägung Breite Seite 2: -1 m; Seitenabschrägung Breite Seite: -1 m; Obere Seitenabschrägung Breite: -1 m; Untere Seitenabschrägung Breite: -1 m; Außenabschrägung Breite Seite 2: -1 m; Außenabschrägung Breite Seite: -1 m; Äußere Abschrägung Breite an oberer Seite: -1 m; Breite äußere Abschrägung an Unterseite: -1 m; Max. Putzdicke: 0.04 m; Abstand Schicht zu Abschluss: 0 m; Anschluss Breite: 0.038 m; Anschluss Stärke: 0.1 m; Streifen-Stärke: 0.025 m; Profilbreite: 0.075 m; Eigene Stärke: 0.015 m; Schichtüberlappung zu Rahmen-Tiefe: 0 m; Sturzbrett Stärke: 0.025 m; Sturzbrett Überstand: 0.03 m; Verkleidungsbreite Links: 0 m; Verkleidungsbreite Rechts: 0 m; Verkleidungsdicke: 0.33 m; Höhe Hintersturz (gs_hsturz_height): 0.08 m; Höhe Hintersturz (gs_hhs): 0.2 m; Stärke vorne: 0.06 m; Tiefe von Wandebene: 0 m; Stärke Dämmung 1: 0.03 m; Stärke Dämmung 2: 0.03 m; Versatz vom Fensterrahmen: 0 m; Stärke Metalplatte: 0.005 m; Breite: 0.07 m; Breite oben (efb_t1): 0.3 m; Stärke oben: 0.06 m; Breite Sturz außen: 0.06 m; Breite unten: 0.07 m; Schwellenbreite: 0.07 m; Vorstand v. Fassade: 0.025 m; Vorstand v. Fassade Fensterbank Außen: 0.05 m; Paneelhöhe: 1.5 m; Innerer Versatz: 0.02 m; Schließtiefe: 0 m; Extra Rahmen Breite: 0.04 m; Extra Rahmen Stärke: 0.03 m; Geländerbreite: 0.03 m; Türzapfen-Länge: 0.02 m; Türzapfen-Radius: 0.005 m; Paneel-Abstand: 0.006 m; Außen-Überhang: 0 m; Innere Paneel-Breite: 0.12 m; 3D-Öffnungslänge: 1.5 m; 3D geschlossene Länge: 0 m; 3D-Öffnungslänge 1 (gs_shutter_opLength_1): 0.56 m; 3D-Öffnungslänge 1 (gs_shutter_opLength_2): 0.14 m; 3D-Öffnungshöhe: 1.5 m; 3D geschlossene Höhe: 0 m; Paneeldicke (gs_shutPanel_Thk): 0.05 m; Paneelrahmen-Breite: 0.05 m; Rahmen-Breite unten (gs_shutPanel_frameWidthBottom): 0.05 m; Paneelbreite: 0 m; Paneelfüllungs-Stärke: 0.01 m; Stärke Lamelle: 0.01 m; Breite Lamellen: 0.04 m; Horizontaler Rahmen Teiler-Breite: 0.05 m; Vertikaler Rahmen Teiler-Breite: 0.05 m; Durchmesser Öffnung: 0.01 m; Breite des vertikalen Bretts: 0.1 m; Z-Rahmen-Breite: 0.05 m; Z-Rahmen-Stärke: 0.025 m; Stärke der vertikalen Bretter: 0.025 m; Stärke der horizontalen Bretter: 0.025 m; Ungefähre Breite der vertikalen Bretter (gs_shutPanel_vertBoardW): 0.08 m; Ungefähre Breite der vertikalen Bretter (gs_shutPanel_horBoardW): 0.115 m; Kasten Höhe (gs_shutRoll_boxHeight): 0.2 m; Kasten Tiefe: 0.15 m; Kasten Abstand links: 0 m; Kasten Abstand recht: 0 m; Tiefe Schiene: 0.0725 m; Abstand von Wand: 0 m; Abstand oben (gs_shutRoll_distFromHead): 0 m; Rollladen-Lamellen-Höhe: 0.05 m; Kasten Höhe (gs_shutLam_boxHeight): 0.2 m; Kasten-Breite (gs_shutLam_boxWidth): 0.15 m; Abdeckungstiefe: 0.04 m; Vorstand v. Wand: 0 m; Abstand oben (gs_shutLam_distFromHead): -0.2 m; Breite einer Rollade (gs_shutLam_segmentWidth): 0.06 m; Kasten Höhe (gs_shutLam2_boxHeight): 0.06 m; Kasten-Breite (gs_shutLam2_boxWidth): 0.06 m; Abst. v. Fenster: 0.06 m; Abstand oben (gs_shutLam2_distFromHead): 0.06 m; Kasten-Achshöhe von OK: 0 m; Breite einer Rollade (gs_shutLam2_segmentWidth): 0.06 m; Öffnung: 0 m; Eigene Kote Öffnung roh: 0 m; Eigene Kote Brüstung fertig: 0 m; Eigene Kote Schwelle fertig: 0 m; Eigene Kote Schwelle: 0 m; Schriftgröße (modell) (gs_lsize): 0.075 m; Position X: 0 m; Position Y: 0.4 m; Zeilenabstand (modell): 0.05 m; Feste breite in mm (0= autom.): 0 m; Text Position X: 0 m; Text Position Y: 0.4 m; Schriftgröße (modell) (gs_IDText_fontSize_model): 0.1 m; Ladebrücken-Breite: 2.26 m; Ladebrücken-Länge: 2.5 m; Ladebrücken-Höhe: 0.7 m; Puffer-Breite: 0.25 m; Puffer-Tiefe: 0.4 m; Puffer-Höhe: 0.5 m; Innere Breite des Kastens: 3.45 m; Innere Tiefe des Kastens: 0.95 m; Innere Höhe des Kastens: 4.5 m; Versatz des Kastens: 0.02 m; Schutzdach-Wanddicke: 0.2 m; Schutzdach untere Wandübergröße: 1.16 m; Vorhang-Höhe: 3.6 m; Seitenvorhang-Breite: 0.6 m; Oberer Vorhang Länge: 1 m; Öffnungsseite Breite 2: 0.1 m; Öffnungsseite Breite 1: 0.1 m; Öffnungsseite Tiefe: 1.2 m; Gegenüberliegende Seite Breite 2: 0.1 m; Gegenüberliegende Seite Breite 1: 0.1 m; Gegenüberliegende Seite Tiefe: 1.8 m; Position Links: 0 m; Position Rechts: 0 m; Breite Links: 0 m; Breite Rechts: 0 m; Tiefe Links: 0.01 m; Tiefe Rechts: 0.01 m; AC Linkes Öffnungsübermaß: 0 m; AC Rechtes Öffnungsübermaß: 0 m; AC Oberes Öffnungsübermaß: 0 m; AC Unteres Öffnungsübermaß: 0 m; Seitenfeld Breite (gs_sidelight_width_left): 0 m; Seitenfeld Breite (gs_sidelight_width_right): 0 m; Höhe Kämpfer (gs_transom_height): 0 m

# IfcBuildingElementProxy: Treppentyp (3)
Classification: Treppe (ARCHICAD Klassifizierung)
ArchiCADProperties - Ebene: Treppen; Geschützt: no; Typ: Treppen; Absolutes Geschoss für Oberkantenverknüpfung: Nicht verknüpft; Relatives Geschoss für Oberkantenverknüpfung: Nicht verknüpft; Geschoss für Oberkantenverknüpfung: Nicht verknüpft; Lage: Innen; Anzeigen auf Umbau-Filter: Alle relevanten Filter; Umbau-Status: Bestand; Standard-Setzstufen-Neigungswinkel: 90 deg; ARCHICAD Klassifizierung - 22: Treppe
ArchiCADQuantities - Erforderliche Kopffreiheit Höhe: 2.2 m; Maximaler Auftritt (nach Regel): 0.35 m; Minimale Steigungshöhe (nach Regel): 0.15 m
Name | In | Material | Element ID = Hotlink und Element-ID = Überobjekt-ID | Kollidierende Räume | Zugehöriger Raumname | Zugehörige Raumnummer | Ursprungsgeschoss Name | Ursprungsgeschoss Nummer | Baustoffe (Alle) | Oberfläche (Alle) | Tragende Funktion | Treppenneigung (deg) | Fläche (m2) | Höhe (m) | Netto-Volumen (m3) | Höhenangabe zum Projekt-Nullpunkt (m) = Höhe zu 1. Referenzhöhe (m) = Höhe zu 2. Referenzhöhe (m) | Höhe zu Meereshöhe (m) | Höhe zu verknüpftem/Ursprungsgeschoss (m) = Abstand zu Ursprungsgeschoss (m) | Abstand Oberkante (m) | Standard-Auftrittstiefe (m) | Standard-Steigungshöhe (m) | Standard-Treppenbreite (m) | Treppe Oberfläche Front (m2) | Anzahl der Trittstufen nach Treppenläufen = Anzahl der Trittstufen (gesamt) | Anzahl der Setzstufen nach Treppenläufen = Anzahl der Setzstufen (gesamt) | Lauflinien-Länge (m) | Component 1 in Trittstufe-007, Enthaltenes CO2 = Component 1 in Trittstufe-011, Enthaltenes CO2 | Component 1 in Trittstufe-007, Enthaltene Energie (MJ) = Component 1 in Trittstufe-011, Enthaltene Energie (MJ) | Component 1 in Lauf-001, Enthaltenes CO2 | Component 1 in Lauf-001, Enthaltene Energie (MJ) | Component 1 in Trittstufe-007, Masse (kg) = Component 1 in Trittstufe-011, Masse (kg) | Component 1 in Trittstufe-007, Schicht/Komponente Volumen (m3) = Component 1 in Trittstufe-011, Schicht/Komponente Volumen (m3) | Component 1 in Lauf-001, Masse (kg) | Component 1 in Lauf-001, Schicht/Komponente Volumen (m3)
Treppe-003 | R-010 | ALLGEMEIN - BAUTEIL | Treppe-003 | Treppenhaus; Treppenhaus UG | Treppenhaus | R-010 | -1. Geschoss | -1 | ALLGEMEIN - BAUTEIL | Farbe, weiß | Tragende Elemente | 29.3228 | 4.88 | 2.5 | 1.54684 | -2.8 | 13.2 | 0 | 0 | 0.29672 | 0.166667 | 1 | 3.36695 | 15 | 15 | 4.4508 | Component Properties - Component 1, Enthaltenes CO2: 494.987 (kgCO₂); Component 1, Enthaltene Energie: 10131.8 MJ; ArchiCADQuantities - Minimaler Auftritt (nach Regel): 0.25 m; Maximale Steigungshöhe (nach Regel): 0.2 m; Component Quantities - Component 1, Masse: 773.418 kg; Component 1, Schicht/Komponente Volumen: 1.54684 m3
Treppe-001 | EG | Metall, Stahl lackiert, Holz, Treppenstufe (16) | Treppe-001 | Erdgeschoss; Grundfläche Gebäude Nachgezogen; Wohnen; Wohnen; Wohnen; Wohnung2 EG | Wohnen | R-009 | EG | 0 | Holz, Treppenstufe; Metall, Stahl lackiert | Holz Eiche; Lack schwarz; Metall Stahl, lackiert | Nicht tragende Elemente | 48.8604 | 3.98354 | 3.7 | 0.333915 | 0.2 | 16.2 | 0.2 | 0.15 | 0.190131 | 0.217647 | 1.2 | 4.6762 | 16 | 17 | 3.04209 | 2.36487 (kgCO₂) | 54.1191 | 814.231 (kgCO₂) | 11209.6 | 4.54783 | 0.0151594 | 557.693 | 0.071499
Treppe-001 | EG | Metall, Stahl lackiert, Holz, Treppenstufe (16) | Treppe-001 | Erdgeschoss; Grundfläche Gebäude Nachgezogen; Wohnen; Wohnen; Wohnen; Wohnung1 EG | Wohnen | R-006 | EG | 0 | Holz, Treppenstufe; Metall, Stahl lackiert | Holz Eiche; Lack schwarz; Metall Stahl, lackiert | Nicht tragende Elemente | 48.8604 | 3.98354 | 3.7 | 0.333915 | 0.2 | 16.2 | 0.2 | 0.15 | 0.190131 | 0.217647 | 1.2 | 4.6762 | 16 | 17 | 3.04209 | 2.36487 (kgCO₂) | 54.1191 | 814.231 (kgCO₂) | 11209.6 | 4.54783 | 0.0151594 | 557.693 | 0.071499

# IfcBuildingElementProxy: Tür Ol 1-Fl 22 (4)
In: EG
Classification: Tür (ARCHICAD Klassifizierung)
Pset_ConcreteElementGeneral - FireRating: T 30
Pset_FireRatingProperties - FireResistanceRating: T 30
ArchiCADProperties - Element ID: Tür-001; Hotlink und Element-ID: Tür-001; Bibliothekselement-Name: Tür Ol 1-Fl 22; Baustoff / Mehrschichtiger Aufbau / Profil / Schraffur: Misch-Schraffur 0%; Schraffurtyp: Misch-Schraffur 0%; Geschützt: no; Ursprungsgeschoss Name: EG; Ursprungsgeschoss Nummer: 0; Typ: Tür; Lage: Innen; Tragende Funktion: Nicht tragende Elemente; Anzeigen auf Umbau-Filter: Alle relevanten Filter; Umbau-Status: Bestand; Größe laut Eingabe: 0,885×2,010; Größe Ausgang: 0,845×1,990; Türblatt-Maß: 0,875×2,000; Nominale B x H: 0,885×2,010; Öffnung Bibliothekselementname: Tür Ol 1-Fl 22; Öffnungsseite Schraffurindex: Misch-Schraffur 0%; ARCHICAD Klassifizierung - 22: Tür
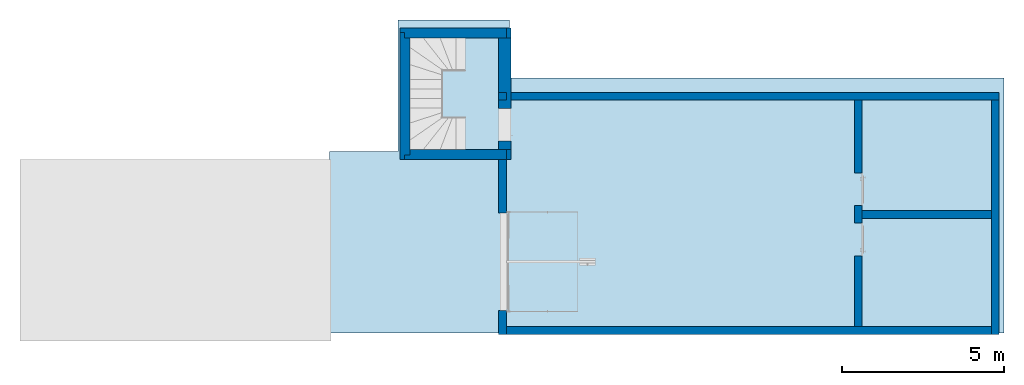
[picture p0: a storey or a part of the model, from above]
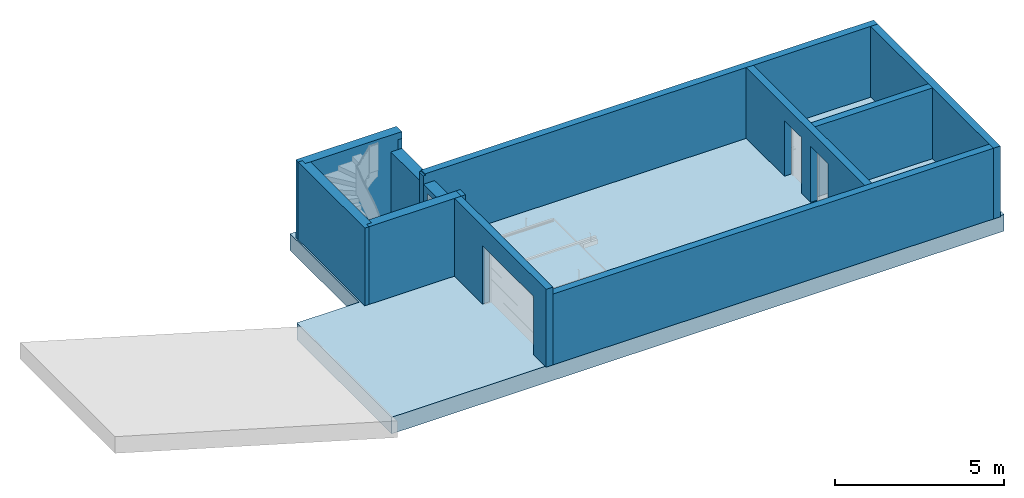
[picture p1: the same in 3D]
Properties of the parts of a building model (IFC4), part 10 of 13

# IfcBuildingElementProxy: Tür Ol 1-Fl 22 (4)
AC_Pset_Tür_Ol_1-Fl_22 - Wandkontur (0-Keine,1-Voll,2-Seite,3-Länge): 0; Fixpunkte 0-Kein,1-2D,2-3D,3-Alle: 3; 2D-Fixpunkte in 3D zeigen: yes; Darstellungseinstellung Grundr.: 3; Winkel Öffnungsposition: 0 deg; Loch übernimmt Oberflächenmaterial der Wandseite: yes; Öffnungsoberfläche ist gebogen in gebogenen Wänden: no; Wand-Typ: 1; Laibung Ankerposition: 2; Wandquerschnittstyp: 1; Nominalmaß: 0; Rohbauöffnung als Nominalmaß einstellen: no; Architekturlichte als Nominalmaß einstellen: yes; Rahmen-Außenmaß als Nominalmaß einstellen: no; Baurichtmaß als Nominalmaß einstellen: no; Freies Öffnungsmaß als Nominalmaß einstellen: no; Türblattmaß als Nominalmaß einstellen: no; Übertrage aktuelle Nominal Größe auf die Auswahl: yes; Sprossen horizontal: 3; Sprossen vertical: 2; Klinketyp (gs_handle_type): Klinke 3; Klinketyp (gs_handle_type_m): 10; Oberlicht (gs_kamp): no; Rahmentyp (gs_frame_type): Umfassungszarge; Rahmentyp (iFrameType): 4; Unterschiedliche Breiten: no; Seite Laibung: yes; Rahmen: Fensterrahmen; Paneel: Fensterrahmen; Glas: Glas Normalglas; Metallteile: Metall Kupfer; Türfüllung: Farbe, grau; Sprossen: Fensterrahmen; Griff: Metall Kupfer; Griff Zubehör: Metall Stahl, matt; Schwelle Oberflächenmaterial: Holz Esche; Schwelle Metallmaterial: Metall Stahl, gebürstet; Blindschwelle Oberflächenmaterial: Holz Esche; Einheitliche Oberflächen Verkleidung: yes; Innenverkleidung Oberflächenmaterial: Fensterrahmen; Außenverkleidung Oberflächenmaterial: Fensterrahmen; Schwelle (bThreshold): no; Schwellentyp (thresholdType): Normal; Schwelle (iThresholdType): 1; Standard-Schwelle Typ: 1; Blindschwelle: no; Schwelle in 2D: no; Stift Schwelle: Elemente+Text; Linientyp Schwelle: 1; Schwellensymbol nach SIA (showSIASymbol): Maßstababhängig; Schwellensymbol nach SIA (iShowSIASymbol): 0; Editierbare Schwellenhöhe im Symbol: no; Schwellentyp (SIASymbolType): Typ 1; Schwellentyp (iSIASymbolType): 1; Position Schwellensymbol (SIASymbolSide): Rechts; Position Schwellensymbol (iSIASymbolSide): 1; Stift Text: Elemente+Text; Symbol-Stift: Elemente+Text; Marker-Text: Arial; Schriftgröße: 1; Außenverkleidung: no; Türfutter außen (gs_trimtype_out): Rechteckig; Türfutter außen (gs_trimtype_out_int): 1; Gehäuse Kopftyp: 1; Querbalken oben: yes; Querbalken Typ oben: 1; Verkleidung (gs_trim_show_cover_out): yes; einheitliche Einfassungsbreiten (gs_trim_outside_uniform): yes; Futter Schnittlinienstift auf beiden Seiten: Elemente+Text; Schraffur Zarge außen: Nur Hintergrund-Stift; Innenverkleidung: no; Türfutter innen (gs_trimtype_in): Rechteckig; Türfutter innen (gs_trimtype_in_int): 1; Verkleidung (gs_trim_show_cover_in): yes; einheitliche Einfassungsbreiten (gs_trim_inside_uniform): yes; Schraffur Zarge innen: Nur Hintergrund-Stift; Fensterbank Außen: no; Übergröße Fensterbank Außen: no; Fensterbanktyp: 8; Schwelle Winkel: 3 deg; Fensterbank ist gebogen in gebogenen Wänden: yes; Dämmung unter Fensterbank: yes; Wand-Dämmschicht benutzen: no; Rollschicht 3D Detaillierungsgrad: 1; Fensterbank Stift für 3D und Aufsicht: Elemente+Text; Fensterbank Schnitt Konturstift: Elemente+Text; Fensterbank Schnittschraffur: Nur Hintergrund-Stift; Dämmung Schnittlinien-Stift: Elemente+Text; Dämmung Schnittschraffur: Dämmung, hart 1; Dämmung Schnittschraffur-Vordergrundstift: Elemente+Text; Fensterbank Oberflächenmaterial: MW Ziegel, rotbraun, DF; Mauerwerksbrüstung Mörtel Oberflächenmaterial: Verputz, glatt, rot; Rollschicht (bMasonryArch): no; Rollschicht (gs_masonry_arch_int): 2; Typ Sturz (gs_masonry_arch_structure): Verputzt; Typ Sturz (gs_masonry_arch_structure_int): 1; Sturz direkt über der Tür: yes; Nische unterm Bogen: yes; Neigungswinkel: 75 deg; Eigenes Nischen-Oberflächenmaterial: no; Bogen Schnittschraffur: Erde 1; Bogen Schnittschraffur-Vordergrundstift: Konturstift; Bogen Schnittschraffur-Hintergrundstift: Schraffurhintergrund; Stift Ziegelsturz: Schraffur; Mauerwerksbogen Stein Oberflächenmaterial: MW Ziegel, blaurot, DF, Läufer; Mauerwerksbogen Mörtel Oberflächenmaterial: Verputz, rauh, grau; Mauerwerksbogen Schlusstein Oberflächenmaterial: Naturstein Kalkstein; Nischen-Oberflächenmaterial: Verputz, rauh, gelb; Typ Anschlag (gs_reveal_type_new): Keine Laibung - Ecke; Typ Anschlag (gs_reveal_type_int): 1; Äußerer Laibungstyp: ohne Anschlag; Typ Anschlag (gs_reveal_doubleOuterTypeInt): 0; Laibungstyp Innen: ohne Anschlag; Typ Anschlag (gs_reveal_doubleInnerTypeInt): 0; Anschlagtiefe und Laibungswinkel gleich: yes; Laibung bearbeiten von (gs_reveal_angle_edit_by): Winkel und Tiefe; Laibung bearbeiten von (gs_reveal_angle_edit_by_int): 1; Winkel Seite 2: 20 deg; Winkel Seite: 20 deg; Winkel oben: 20 deg; Winkel unten: 0 deg; Außenwinkel Seite 2: 20 deg; Außenwinkel Seite: 20 deg; Außenwinkel obere Seite: 20 deg; Außenwinkel untere Seite: 0 deg; Wandbekleidung benutzen: no; automatischer Schichteinzug Putz innen: yes; Putzschicht innen einziehen: 0; automatischer Schichteinzug Putz außen: yes; Putzschicht außen einziehen: 0; Bemaßungsfangpunkte in 2D: no; in 3D zeigen: no; Schichteinzug (gs_closure_type): Kein Schichteinzug; Schichteinzug (gs_closure_type_int): 1; Schicht an Seite einziehen (gs_cavity_side): Beide; Schicht an Seite einziehen (iCavityClosureSide): 1; Einzuziehende Schichten: 1; Schichten von (gs_nTurnDir): Außenseite; Schichten von (iCavityClosureTurnDir): 1; Schichteinzug auf Seite 2: yes; Schichteinzug auf Seite 1: yes; Schichteinzug oben: no; Schichteinzug unten: no; Schichteinzug zu Schicht: 1; Schichteinzug von Seite (gs_cc_dutch_ClosureToSide): 1; Schicht einziehen zu Abschluss: no; Dichtungsband einfügen: yes; Dichtungsband zeigen: yes; Konturlinien-Typ (gs_ltJoint): 1; Schraffur (gs_fillJoint): Nur Hintergrund-Stift; Schraffur-Vordergrundstift (gs_penJointFg): Elemente+Text; Eigenes Oberflächenmaterial: no; Oberflächenmaterial: Holz Esche; Konturlinien-Typ (gs_ltPlug): 1; Schraffur (gs_fillPlug): Nur Hintergrund-Stift; Schraffur-Vordergrundstift (gs_penPlugFg): Elemente+Text; Editierte Anschlagseite: 1; Editierte Wandseite: 1; Schicht Nummer: 1; Schicht einziehen: no; Schicht als Putz ansehen: no; Einzugsdicke: 1; Ausrichtung Schraffur: 1; Trennlinie am Einzug: no; Stift Trennlinie: Elemente+Text; Letzte ausgewählte Seite: no; Abschlussart automatisch verändert: no; Anschluss Links: no; Anschluss Rechts: no; Anschluss Oben: no; Rahmen Aufsichtslinien-Stift: Schichttrennlinien/Kontur; Rahmen-Stift: Schichttrennlinien/Kontur; Rahmen Schnittschraffur: Nur Hintergrund-Stift; Türblatt-Stift: Schichttrennlinien/Kontur; Türblatt Schnittschraffur: Luftschicht; Glas Linienstift Kontur: Schichttrennlinien/Kontur; Glas Schnittschraffur: Nur Hintergrund-Stift; Glas Aufsichtslinien-Stift: Schichttrennlinien/Kontur; Rahmen Deckschraffur: Nur Hintergrund-Stift; Symbol ausrichten: 2; Öffnungswinkel in 2D: 90 deg; Öffnungswinkel in 3D: 0 deg; Modelldarstell. für symbolische 2D-Darstellung überschreiben: no; Öffnungslinien in 2D: yes; Öffnungslinien-Typ: 1; Nebenöffnung Linientyp in 2D: 4; Öffnungslinien-Form (or_SwingType): Gebogen; Öffnungslinien-Form (or_iSwingType): 1; Öffnungslinien-Form (or_SlidingType): Kein; Öffnungslinien-Form (or_iSlidingType): 0; 2D & 3D Öffnungslinien-Stift (or_opLinePen): Elemente+Text; 2D & 3D Öffnungslinien-Stift (or_iOpLinePen): 1; Modelldarstell. für 3D-Darstellung überschreiben: no; Öffnungslinie zeigen: yes; Linientyp Öffnungsseite (or_opLineType3dIn): Vollinie; Linientyp Öffnungsseite (or_iOpLineType3dIn): 0; Linientyp Gegenüberliegende Seite (or_opLineType3dOut): Strichlinie; Linientyp Gegenüberliegende Seite (or_iOpLineType3dOut): 1; Standflügel Linientyp in 3D: Strichlinie; Standflügel Linientyp: 1; Linien-Ausrichtung (or_oplineStyle): Griff; Linien-Ausrichtung (or_iOplineStyle): 1; Grundriss: 1; 3D: 8; Schnitt / Ansicht: 1; Anschlag im Grundriss zeigen: 1; Wandschraffur in der Öffnung: no; Schraffur (gs_wallhole_fill): Nur Hintergrund-Stift; Schraffur-Vordergrundstift (gs_wallhole_pen_fg): Elemente+Text; Schraffur-Hintergrundstift (gs_wallhole_pen_bg): Schraffurhintergrund; Türkoten: no; Sichtbarkeit Türbemaßung (gs_etikett): Modelldarstellungs-Optionen; Sichtbarkeit Türbemaßung (iEtikett): 3; Öffnung roh: 1; Text Öffnung roh: Öffnung roh; Sturz fertig: 1; Text Fertig Sturz: Sturz fertig; OK Schwelle: 1; Text Schwelle Fertig: OK Schwelle; Schwelle (iDWDimRawParapet): 1; Text Schwelle: Schwelle; Texteinstellung (gs_Etikett_scaleValues): Maßstababhängig (Modellgröße); Massstab (gs_Etikett_scaleValues_m): 2; Schrifttyp (fontType): Arial; Schriftgröße (papier) (gs_Etikett_fontSize_mm): 1.5; Dimension Stift Text: Elemente+Text; X Position (m): 0; Position X (mm): 0; Y Position (m): 0; Position Y (mm): 2; Automat. Zeilenabstand: no; Zeilenabstand (papier): 1; Drehwinkel: 0 deg; Zeige die ID im Grundriss: no; Beschriftung Türtyp: 1; Automatische Tür ID: yes; Eigener Text: Eigene ID; Marker spiegeln: yes; Zusätzliche Werte zeigen (Öffnungsmass 1.20/1.50): yes; Text Position X (mm): 0; Text Position Y (mm): 8; Texteinstellung (gs_IDText_scaleValues): Maßstababhängig (Modellgröße); Massstab (gs_IDText_scaleValues_m): 2; Schriftgröße (papier) (gs_IDText_fontSize_mm): 2; Schrifttyp (gs_IDText_fontType): Arial; Text-Stift: Elemente+Text; Sturztiefe im Grundriss zeigen: no; Sturztiefe Symbol- Linientyp: 4; Sturztiefe Symbolstift: Konturstift; Öffnungstyp: 0; seitliche Wandkontur (gs_wallcontour): Beide; seitliche Wandkontur (gs_wallcontour_id): 1; Wandkontur (gs_wcont_line): beide Seiten; Wandkontur (iWallContourLine): 4; Automatische Einstellungen: yes; Wandkonturlinie innen - 1:50 und tiefer: yes; Wandkonturlinie innen - 1:100 und höher: yes; Wandkonturlinien Typ innen - 1:50 und tiefer: 1; Wandkonturlinien Typ innen - 1:100 und höher: 1; Wandkonturlinie außen - 1:50 und tiefer: yes; Wandkonturlinie außen - 1:100 und höher: yes; Wandkonturlinien Typ außen - 1:50 and tiefer: 1; Wandkonturlinien Typ außen - 1:100 und höher: 1; Wandkonturlinien Stift - 1:50 und tiefer: Elemente+Text; Wandkonturlinien Stift - 1:100 und höher: Elemente+Text; Typ Links: 0; Typ Rechts: 0; Automatische Maße: yes; Konturlinie-Stift Einbaurahmen: Elemente+Text; Linientyp Kontur Einbaurahmen: 1; Einbaurahmen Schraffur: Nur Hintergrund-Stift; Einbaurahmen Schraffur-Vordergrundstift: Schichttrennlinien/Kontur; Schraffur-Stift Fugenausfüllung: Elemente+Text; Linientyp Kontur Fugenausfüllung: 1; Fugenausfüllung Schraffur: Nur Vordergrund-Stift; Fugenausfüllung Schraffur-Vordergrundstift: Schichttrennlinien/Kontur; Bearbeitende Fixpunkte: yes; IFC Betrieb (ifc_optypestr): Einflügeltür; IFC Betrieb (ifc_optype): 1; Linkes Seitenfeld: no; Rechtes Seitenfeld: no; Oberlicht (gs_door_transom): no; Bilder: 2; Tür gehört zum Raum, in den sie öffnet: yes; Preis: 0; Komplette Glasfläche: 0; Umfang der Glasfläche: 0; Dämmung: no; Selbstschließend: no; Rauchschutz Tür: no; Rauchprobe Temperatur: 200; Dämmung Index: 2; Gruppe Typ (FM_Type): Türe; Gruppe Typ (iFMType): 999; Objektgewicht: 0; Objektgewichtseinheit: kg; Türausrichtungsdefinition: 0; Breite Wert: Durchgangslichte Breite; Breite: 84,50; Höhe Wert: Durchgangslichte Höhe; Höhe: 199,00; Wert ID Nummer: 1; ID-Nummer: Tür-001; zu Raum ID innen Wert: Automatisch; zu Raum ID außen Wert: Automatisch
Brandschutz 4102-2 - Feuerwiderstand 4102-2: T 30; Minuten (4102-2): 30; Baustoffklasse: A; Kennbuchstabe: T
Türen/Fenster - Schallschutzklasse: SK 3; Fenster/Türbreite: 0.885 m; Fenster/Türhöhe: 2.01 m
ArchiCADQuantities - Höhe: 2.01 m; Breite: 0.885 m; F/T Öffnung Nominaler Oberflächenbereich: 1.77885 m2; F/T Öffnungsbreite auf der Anschlagseite: 0.885 m; F/T Öffnungsbreite gegenüber der Anschlagseite: 0.885 m; Nominale F/T Öffnungsbreite auf der Anschlagseite: 0.885 m; Nominale F/T Höhe der Öffnung auf der Anschlagseite: 2.01 m; Nominale F/T Öffnungsbreite gegenüber der Anschlagseite: 0.885 m; Nominale F/T Höhe der Öffnung gegenüber der Anschlagseite: 2.01 m; Nominale F/T Öffnungsoberfläche auf der Anschlagsseite: 1.77885 m2; Nominale F/T Öffnungsoberfläche auf der Seite gegenüber der Anschlagsseite: 1.77885 m2
AC_Equantity_Tür_Ol_1-Fl_22 - NominaleBreite: 0.885 m; NominaleHöhe: 2.01 m; Z-Achse: 1 m; Untere Ebene: 1 m; Obere Ebene: 0 m; Laibung zum Wandkern: 0 m; Einbautoleranz links: 0 m; Einbautoleranz rechts: 0 m; Einbautoleranz oben: 0 m; Einbautoleranz unten: 0 m; Toleranz außen links: 0 m; Toleranz innen links: 0 m; Toleranz außen rechts: 0 m; Toleranz innen rechts: 0 m; Toleranz außen oben: 0 m; Toleranz innen oben: 0 m; Toleranz außen unten: 0 m; Toleranz innen unten: 0 m; Rohbauöffnung Breite: 0.885 m; Rohbauöffnung Höhe (ac_wallhole_height_original): 2.01 m; Architekturlichte Breite: 0.885 m; Architekturlichte Höhe (ac_reveal_height_original): 2.01 m; Rahmen Breite: 0.885 m; Rahmen Höhe: 2.01 m; Breite Baurichtmaß: 0.885 m; Durchgangslichte Breite: 0.845 m; Durchgangslichte Höhe: 1.99 m; Nominale Türblatt Breite: 0.875 m; Nominale Türblatt Höhe: 2 m; Spalt unter Türblatt: 0.005 m; Türblatt Stärke: 0.04 m; Falzbreite: 0.015 m; Falztiefe: 0.02 m; Stärke Türfüllung: 0.02 m; Rahmenbreite links: 0.1 m; Rahmenbreite rechts: 0.1 m; Rahmenbreite unten: 0.9 m; Rahmenbreite oben: 0.1 m; Sprossenbreite: 0.025 m; Sprossentiefe: 0.025 m; Radius Türfüllung: 0.2 m; Abstand Mittelpunkt - links: 0.4 m; Abstand Mittelpunkt - rechts: 0.6 m; Abstand Mittelpunkt - unten: 1.4 m; Abstand Mittelpunkt - oben: 1.1 m; Griff-Höhe: 1.05 m; Klinkeposition: 0.06 m; Höhe Kämpfer (gs_am): 0.5 m; Rahmen-Breite: 0.02 m; Rahmenbreite Seite 1: 0.1 m; Rahmenbreite Seite 2: 0.1 m; Mittlerer Rahmen Seite 1: 0.1 m; Mittlerer Rahmen Seite 2: 0.1 m; Oberer Rahmen Breite: 0.1 m; Querbalkenrahmen Breite: 0.1 m; Seitenfeld Querbalkenrahmen Breite: 0.1 m; Seitenfeld oberer Rahmen Breite: 0.1 m; Untere Rahmenbreite: 0.1 m; Block Breite: 0.05 m; Block Stärke: 0.06 m; Mörtel: 0.01 m; Überstand 1: 0.01 m; Überstand 2: 0.01 m; Schwellenhöhe (thresholdHeight3D): 0.02 m; Schwellenhöhe (thresholdHeight1): 0.02 m; Schwellenhöhe (b): 0.02 m; Schwellenhöhe (c): 0.02 m; Eigene Wandöffnung Übergröße: 0.05 m; Position Schwelle (thresholdPos1): 0 m; Position Schwelle (thresholdPos2): 0 m; Position Schwelle (thresholdPos3): 0 m; Querbalken oben Breite: 0.02 m; Breite Seite 1 (gs_tw_right_out): 0.05 m; Breite Seite 2 (gs_tw_left_out): 0.05 m; Breite oben (gs_tw_top_out): 0.05 m; Stärke der Wand (gs_trim_thk_out): 0.019 m; Stärke des Wandlochs (gs_trim_width_out): 0.025 m; Abstand (gs_trim_offs_out): 0 m; Auskragung (gs_trim_jambext_nosing_out): 0.05 m; Oberer Überstand (gs_trimov_top_right_out): 0.1 m; Breite Seite 1 (gs_tw_right_in): 0.05 m; Breite Seite 2 (gs_tw_left_in): 0.05 m; Breite oben (gs_tw_top_in): 0.05 m; Stärke der Wand (gs_trim_thk_in): 0.019 m; Stärke des Wandlochs (gs_trim_width_in): 0.025 m; Abstand (gs_trim_offs_in): 0 m; Auskragung (gs_trim_jambext_nosing_in): 0.03 m; Oberer Überstand (gs_trimov_top_right_in): 0.1 m; Fensterbankbreite: 0 m; Fensterbank obere Breite: 0.01 m; Fensterbank obere Höhe: 0.01 m; Schwellendicke: 0.025 m; Fensterbank Vorderseite Stärke: 0.015 m; Schwelle Ansicht: 0.005 m; Fensterbank Tropfüberhang: 0.02 m; Stärke Fensterbankkante: 0.03 m; Schwelle Überstand: 0.03 m; Fensterbank Überhang links: 0 m; Fensterbank Überhang rechts: 0 m; Fensterbank Einschub Tiefe: 0.02 m; Fensterbank Einschub von Wand: 0 m; Hintere Lochtiefe (gs_sill_holeDepthBehind): 0 m; Steinbreite (gs_brick_sill_br_thk): 0.065 m; Fugenbreite (gs_brick_sill_mort_thk): 0.015 m; Distanz zwischen Bogen und Tür: 0 m; Sturz Überhang links: 0 m; Sturz Überhang rechts: 0 m; Sturz Bogenhöhe: 0.03 m; Projektion Sturz: 0 m; Höhe Sichtmauerwerk: 0.24 m; Tiefe Sichtmauerwerk: 0.115 m; Hintere Lochtiefe (gs_masonry_arch_rearHoleDepth): 0 m; Steinbreite (gs_masonry_arch_brick_thk): 0.052 m; Fugenbreite (gs_masonry_arch_mort_thk): 0.01 m; Keilsteinbreite: 0.1 m; Überhang Keilstein: 0 m; Projektion Keilstein: 0.01 m; Anschlagtiefe (gs_wido_sill): 0 m; Anschlagtiefe (AC_wido_sill): 0 m; Anschlagstiefe Seite 2: 0.05 m; Anschlagstiefe: 0.05 m; Innerer Anschlagstiefe Seite 2 (gs_reveal_splayed_innerLeft): 0.06 m; Innerer Anschlagstiefe (gs_reveal_splayed_innerRight): 0.06 m; Innerer Anschlagstiefe Seite 2 (gs_reveal_double_innerLeft): 0.06 m; Innerer Anschlagstiefe (gs_reveal_double_innerRight): 0.06 m; Tiefe des oberen Anschlags: 0.05 m; Tiefe des unteren Anschlags: 0.06 m; Tiefe Sturz Innen (gs_reveal_splayed_innerTop): 0.06 m; Tiefe Laibung Innen (gs_reveal_splayed_innerBottom): 0 m; Tiefe Sturz Innen (gs_reveal_double_innerTop): 0.06 m; Tiefe Laibung Innen (gs_reveal_double_innerBottom): 0 m; Tiefe äußerer Anschlag: 0.05 m; Seitenabschrägung Breite Seite 2: -1 m; Seitenabschrägung Breite Seite: -1 m; Obere Seitenabschrägung Breite: -1 m; Untere Seitenabschrägung Breite: -1 m; Außenabschrägung Breite Seite 2: -1 m; Außenabschrägung Breite Seite: -1 m; Äußere Abschrägung Breite an oberer Seite: -1 m; Breite äußere Abschrägung an Unterseite: -1 m; Max. Putzdicke: 0.04 m; Abstand Schicht zu Abschluss: 0 m; Anschluss Breite: 0.038 m; Anschluss Stärke: 0.1 m; Streifen-Stärke: 0.025 m; Profilbreite: 0.075 m; Eigene Stärke: 0.015 m; Schichtüberlappung zu Rahmen-Tiefe: 0 m; Eigene Kote Rohöffnung: 0 m; Eigene Kote Schwelle fertig (gs_n): 0 m; Eigene Kote Schwelle fertig (gs_q): 0 m; Eigene Kote Schwelle: 0 m; Schriftgröße (modell) (gs_lsize): 0.075 m; Position X: 0 m; Position Y: 0.4 m; Zeilenabstand (modell): 0.05 m; Feste breite in mm (0= autom.): 0 m; Text Position X: 0 m; Text Position Y: 0.4 m; Schriftgröße (modell) (gs_IDText_fontSize_model): 0.1 m; Öffnungsseite Breite 2: 0.3 m; Öffnungsseite Breite 1: 0.1 m; Öffnungsseite Tiefe: 1.8 m; Gegenüberliegende Seite Breite 2: 0.25 m; Gegenüberliegende Seite Breite 1: 0.1 m; Gegenüberliegende Seite Tiefe: 1.2 m; Position Links: 0 m; Position Rechts: 0 m; Breite Links: 0 m; Breite Rechts: 0 m; Tiefe Links: 0.01 m; Tiefe Rechts: 0.01 m; AC Linkes Öffnungsübermaß: 0 m; AC Rechtes Öffnungsübermaß: 0 m; AC Oberes Öffnungsübermaß: 0 m; AC Unteres Öffnungsübermaß: 0 m; Seitenfeld Breite (gs_sidelight_width_left): 0 m; Seitenfeld Breite (gs_sidelight_width_right): 0 m; Höhe Kämpfer (gs_transom_height): 0 m
Name | Ebene | Kollidierende Räume | Zugehöriger Raumname = zu Raum | Zugehörige Raumnummer = Zu Raum-Nummer = zu Raum ID innen | Überobjekt-ID | Oberfläche (Alle) | Von Raum | Von Raum-Nummer = zu Raum ID außen | Anschlagsmaße = Größe Wandloch | Nominale B x H x T | Wandstruktur | Ausrichtung = Türausrichtung = Türen/Fenster, Öffnungsrichtung | Wandrichtungstyp | AC_Pset_Tür_Ol_1-Fl_22, Öffnungsrichtung | Heizkörpernische | Türblatt = Untere Laibung Typ (gs_reveal_type_bottom_int) | Wandöffnung unter Schwelle (holeUnderThreshold) | Wandöffnung unter Schwelle (iHoleUnderThreshold) | Untere Laibung Typ (gs_reveal_type_bottom) | Fenster/Türnummer | Netto-Volumen (m3) | Höhenangabe zum Projekt-Nullpunkt (m) = Höhe zu 1. Referenzhöhe (m) = Höhe zu 2. Referenzhöhe (m) = Höhe zu verknüpftem/Ursprungsgeschoss (m) = Abstand zu Ursprungsgeschoss (m) | Höhe zu Meereshöhe (m) | Oberflächenbereich (m2) = F/T Oberfläche der Öffnung (m2) | F/T Volumen der Öffnung (m3) | F/T nominales Volumen der Öffnung (m3) | F/T Höhe der Öffnung auf der Anschlagseite (m) = F/T Höhe der Öffnung gegenüber der Anschlagseite (m) = Rohbauöffnung Höhe (ac_wallhole_height) (m) = Architekturlichte Höhe (ac_reveal_height) (m) = Höhe Baurichtmaß (m) | F/T Oberfläche der Öffnung auf der Anschlagseite (m2) = F/T Oberfläche der Öffnung gegenüber der Anschlagseite (m2) | Brüstungshöhe (m) = F/T nominale Brüstungs-/Schwellenhöhe (m) = F/T Brüstungs-/Schwellenhöhe auf der Anschlagseite (m) = F/T Brüstungs-/Schwellenhöhe gegenüber der Anschlagseite (m) | F/T nominale Sturzhöhe (m) = F/T Sturzhöhe auf der Anschlagseite (m) = F/T Sturzhöhe gegenüber der Anschlagseite (m) | Wanddicke (m) | ArchiCADQuantities, Rahmen-Stärke (m) = AC_Equantity_Tür_Ol_1-Fl_22, Rahmen-Stärke (m) | Brüstungshöhe zum aktuellen Geschoss (m)
Tür-001 | Wand Innen | Erdgeschoss; Grundfläche Gebäude Nachgezogen; Treppenhaus; Wohnung2 EG | Wohnen | R-009 | Wand-003 | Metall Kupfer; Glas Normalglas; Fensterrahmen | Treppenhaus | R-010 | 0,885×2,210 | 0,885×2,010×0,175 | WI / MW_tr | L | 0 | 1 | 2 | 2 | Wandöffnung zu Wandunterkante | 2 | ohne Anschlag | EG-R-009-Tür-001 | 0.0543956 | -0.3002 | 15.6998 | 6.53592 | 0.342243 | 0.311299 | 2.2098 | 1.95567 | 0.1998 | 2.2098 | 0.175 | 0.195 | 2.4998
Tür-001 | Wand Innen | Erdgeschoss; Grundfläche Gebäude Nachgezogen; Treppenhaus; Untergeschoss UG; Wohnung1 EG | Treppenhaus | R-010 | Wand-003 | Metall Kupfer; Glas Normalglas; Fensterrahmen | Treppenhaus | R-010 | 0,885×2,210 | 0,885×2,010×0,175 | WI / MW_tr | R | 0 | 1 | 2 | 2 | Wandöffnung zu Wandunterkante | 2 | ohne Anschlag | EG-R-010-Tür-001 | 0.0543956 | -0.3002 | 15.6998 | 6.53592 | 0.342243 | 0.311299 | 2.2098 | 1.95567 | 0.1998 | 2.2098 | 0.175 | 0.195 | 2.4998
Tür-001 | Wand Innen Ausbau | Bad; Erdgeschoss; Grundfläche Gebäude Nachgezogen; Wohnung2 EG | Bad | R-008 | Wand-013 | Metall Kupfer; Fensterrahmen | Wohnen | R-009 | 0,885×2,010 | 0,885×2,010×0,125 | WI / GK 12 2-lagig | L | 1 | 0 | 3 | 1 | Keine Wandöffnung | 0 | Gleich | EG-R-008-Tür-001 | 0.0836873 | 0.2 | 16.2 | 5.83451 | 0.222356 | 0.222356 | 2.01 | 1.77885 | 0.2 | 2.21 | 0.125 | 0.145 | 0.2
Tür-001 | Wand Innen Ausbau | Bad; Erdgeschoss; Grundfläche Gebäude Nachgezogen; Wohnung1 EG | Bad | R-007 | Wand-013 | Metall Kupfer; Fensterrahmen | Wohnen | R-006 | 0,885×2,010 | 0,885×2,010×0,125 | WI / GK 12 2-lagig | R | 0 | 0 | 3 | 1 | Keine Wandöffnung | 0 | Gleich | EG-R-007-Tür-001 | 0.0836873 | 0.2 | 16.2 | 5.83451 | 0.222356 | 0.222356 | 2.01 | 1.77885 | 0.2 | 2.21 | 0.125 | 0.145 | 0.2

# IfcBuildingElementProxy: Unterschrank Einzeltür mit Spüle 22 (2)
In: EG
Classification: Möbel (ARCHICAD Klassifizierung)
ArchiCADProperties - Element ID: Küche-004; Hotlink und Element-ID: Küche-004; Ebene: Möblierung; Bibliothekselement-Name: Unterschrank Einzeltür mit Spüle 22; Baustoff / Mehrschichtiger Aufbau / Profil / Schraffur: Nur Hintergrund-Stift; Schraffurtyp: Nur Hintergrund-Stift; Zugehöriger Raumname: Wohnen; Geschützt: no; Ursprungsgeschoss Name: EG; Ursprungsgeschoss Nummer: 0; Typ: Objekt; Überobjekt-ID: Küche-004; Oberfläche (Alle): Metall Chrom; Farbe, weiß; Lage: Innen; Tragende Funktion: Nicht definiert; Anzeigen auf Umbau-Filter: Alle relevanten Filter; Umbau-Status: Bestand; Oberfläche: Kunststoff PE, weiss; ARCHICAD Klassifizierung - 22: Möbel
AC_Pset_Unterschrank_Einzeltür_mit_Spüle_22 - 3D-Detaillierungsgrad: 1; 2D-Fixpunkte in 3D zeigen: no; Programm einstellen: no; 'A' 'B' Größe =: Arbeitsplatte; 'A' 'B' Größe=Schrankgröße: no; Fuß (bToeOn): yes; Sockel/Fußtyp (gs_toe_type): Komplett; Sockel/Fußtyp (gs_toe_type_m): 1; Anzahl Böden: 1; Arbeitsplattenkante sichtbar in 3D (side_vis): Keine; Arbeitsplattenkante sichtbar in 3D (side_vis_mirror): Keine; Seiten sichtbar: 0; Tür (bDoor): yes; Tür (gs_door_type): Stil 1; Fronttyp: 1; Eckfase: no; Tür-Öffnungswinkel: 0 deg; Anz. der vertikalen Türaufteilung: 1; Anz. der horizontalen Türaufteilung: 2; Schublade (bDrawer): yes; Gleiche Schubladenfront wie Tür: yes; Knopf (bKnob): yes; Knopf (gs_knob_type): Stil 1; Knopftyp: 1; Einbau: 0; Doppelseitig: no; Fuß und Paneel abhängig: 0; Linkes Abschlusspaneel (left_panel): no; Linkes Abschlusspaneel hat Unterschrankgröße: yes; Rechtes Abschlusspaneel (right_panel): no; Rechtes Abschlusspaneel hat Unterschrankgröße: yes; Linkes Abschlusspaneel (left_panel_mirror): no; Rechtes Abschlusspaneel (right_panel_mirror): no; Hinteres Abschlusspaneel: no; Hinteres Abschlusspaneel hat Unterschrankgröße: yes; Abschlusspaneel-Typ: Stil 1; Arbeitsplatte (bCounter): no; Typ Counter (gs_count_type): Rechteckig; Typ Counter (gs_count_type_m): 1; Spüle (bSink): yes; Spülbecken Typ: Stil 1; Spülbeckentyp: 1; Becken untergebaut: no; Wasserhahn (bTap): yes; Hahn-Typ: Stil 1; Zapfentyp: 1; Warmwasseranschluss: yes; Werkzeug-Typ (ConToolType_1): 2; HKLSE System (ConSystem_1): Undefiniert; Form-Typ (ConType_1): Kreis; Kaltwasseranschluss: yes; Werkzeug-Typ (ConToolType_2): 2; HKLSE System (ConSystem_2): Undefiniert; Form-Typ (ConType_2): Kreis; Abwasser Anschluss: yes; Werkzeug-Typ (ConToolType_3): 2; HKLSE System (ConSystem_3): Undefiniert; Form-Typ (ConType_3): Kreis; 2D-Detaillierungsgrad: 1; Schrank Symboltyp: Typ 1; Kanten sichtbar im 2D (side_vis2D): Keine; Kanten sichtbar im 2D (side_vis2D_m): 0; Kanten sichtbar im 2D (side_vis2D_mirror): Keine; Verdeckte 2D Kanten: 0; Überstand Linien-Stift: Konturstift; Überstand Line: 4; Spühlbecken-Symboltyp (SinkSymbol): Detailliert; Spühlbecken-Symboltyp (SinkSymbol_m): 2; Typ Stopfen-Symbol (TapSymbol): Detailliert; Typ Stopfen-Symbol (TapSymbol_m): 2; Konturstift: Konturstift; Schraffur: Nur Hintergrund-Stift; Auflösung: 16; Schatten: yes; Extra Fixpunkte verwenden: yes; Schrank (gs_cabinet_mat): Farbe, weiß; Arbeitsplatte (count_mat): Holzwerkstoff MDF, schwarz; Spritzschutz: Metall Chrom; Fuß (toe_mat): Metall Chrom; Tür (Rahmen): Farbe, weiß; Tür (Verglasung): Glas Normalglas; Schublade (DrawerMat): Farbe, weiß; Abschlusspaneel: Farbe, weiß; Knopf (gs_knob_mat): Metall Chrom; Fachböden: Farbe, weiß; Spüle (gs_sink_mat): Metall Chrom; Wasserhahn (gs_tap_mat): Metall Chrom; Anschluss: Metall Stahl, poliert; System Oberflächenmaterial benutzen: no; System Oberflächenmaterial: Farbe, grau; Anschlussanzahl: 3; Preis: 0; Fläche: 0; Volumen: 0; Gruppe Typ (FM_Type): HKLSE Ausstattung; Gruppe Typ (iFMType): 12; Objektgewicht: 0; Objektgewichtseinheit: kg
ArchiCADQuantities - Fläche: 0.36 m2; Höhe: 0.9 m; Netto-Volumen: 0.0873338 m3; Breite: 0.6 m; Höhenangabe zum Projekt-Nullpunkt: 0.2 m; Höhe zu 1. Referenzhöhe: 0.2 m; Höhe zu 2. Referenzhöhe: 0.2 m; Höhe zu Meereshöhe: 16.2 m; Höhe zu verknüpftem/Ursprungsgeschoss: 0.2 m; Abstand zu Ursprungsgeschoss: 0.2 m; Oberflächenbereich: 7.06561 m2; Länge (A): 0.6 m
AC_Equantity_Unterschrank_Einzeltür_mit_Spüle_22 - Schrank Breite: 0.6 m; Schrank Tiefe: 0.6 m; Höhe Arbeitsplatte: 0.9 m; Untere Ebene: 1 m; Obere Ebene: 0 m; Fuß Rücksprung: 0 m; Fußhöhe: 0.09 m; Breite Tür: 0.6 m; Türdicke: 0.02 m; Türrahmen Breite (doorframe_w): 0.09 m; Schubladenhöhe: 0.13 m; Horizontale Knopfposition: 0.05 m; Vertikale Knopfposition: 0.55 m; Knopfgröße: 0.1 m; Individueller Griff Länge: 0.1 m; Individueller Griff Höhe: 0.015 m; Individueller Griff Tiefe: 0.02 m; Linkes Abschlusspaneel Dicke: 0.02 m; Rechtes Abschlusspaneel Dicke: 0.02 m; Hinteres Abschlusspaneel Dicke: 0.02 m; Türrahmen Breite (doorframe_w_end): 0.09 m; Stärke Arbeitsplatte: 0.05 m; Höhe Spritzschutz 0-keine: 0 m; Überhang zur Front des Schranks: 0.05 m; Überhang zur Rückseite des Schranks: 0 m; Überhang zur linken Seite des Schranks (left_cab): 0 m; Überhang zur rechten Seite des Schranks (right_cab): 0 m; Überhang zur linken Seite des Schranks (left_cab_mirror): 0 m; Überhang zur rechten Seite des Schranks (right_cab_mirror): 0 m; Spüle X Abstand zur Mitte: 0 m; Spüle Y Abstand zur Mitte: 0 m; Armatur Versatz X: 0 m; Nominale Tiefe (ConNominalDepth_1): 0.025 m; Außendurchmesser (ConWidth_1): 0.027 m; Außentiefe (ConDepth_1): 0.027 m; Wanddicke (ConWallThickness_1): 0.001 m; Anschluss-Länge (ConLength_1): 0.02 m; Anschluss Durchmesser (ConConnectorWidth_1): 0.04 m; Anschluss-Tiefe (ConConnectorDepth_1): 0 m; Anschluss-Breite (ConConnectorWidth2_1): 0.005 m; Anschluss-Position X (ConPosX_1): 0.2 m; Anschluss-Position Y (ConPosY_1): 0.6 m; Anschluss-Position Z (ConPosZ_1): 0.8 m; Nominale Tiefe (ConNominalDepth_2): 0.025 m; Außendurchmesser (ConWidth_2): 0.027 m; Außentiefe (ConDepth_2): 0.027 m; Wanddicke (ConWallThickness_2): 0.001 m; Anschluss-Länge (ConLength_2): 0.02 m; Anschluss Durchmesser (ConConnectorWidth_2): 0.04 m; Anschluss-Tiefe (ConConnectorDepth_2): 0 m; Anschluss-Breite (ConConnectorWidth2_2): 0.005 m; Anschluss-Position X (ConPosX_2): 0.40005 m; Anschluss-Position Y (ConPosY_2): 0.6 m; Anschluss-Position Z (ConPosZ_2): 0.8 m; Nominale Tiefe (ConNominalDepth_3): 0.04 m; Außendurchmesser (ConWidth_3): 0.042 m; Außentiefe (ConDepth_3): 0.042 m; Wanddicke (ConWallThickness_3): 0.001 m; Anschluss-Länge (ConLength_3): 0.02 m; Anschluss Durchmesser (ConConnectorWidth_3): 0.042 m; Anschluss-Tiefe (ConConnectorDepth_3): 0 m; Anschluss-Breite (ConConnectorWidth2_3): 0.005 m; Anschluss-Position X (ConPosX_3): 0.3 m; Anschluss-Position Y (ConPosY_3): 0.6 m; Anschluss-Position Z (ConPosZ_3): 0.6 m; Min. Platzbedarf vorne: 0.9 m; Min. Platzbedarf auf Seite 1: 0 m; Min. Platzbedarf auf Seite 2: 0 m; Minimaler Platzbedarf: 0.9 m; Rückwärtiger minimaler Platzbedarf Seite 1: 0 m; Rückwärtiger minimaler Platzbedarf Seite 2: 0 m; Höhe Türblatt: 0.68 m
Component Quantities - Component 1, Schicht/Komponente Volumen: 0.0873338 m3
Name | Kollidierende Räume | Zugehörige Raumnummer | Drehwinkel (deg) | Zugehörigkeit
Küche-004 | Erdgeschoss; Grundfläche Gebäude Nachgezogen; Wohnen; Wohnung2 EG | R-004 | 180 | EG-R-004-Wohnen
Küche-004 | Erdgeschoss; Grundfläche Gebäude Nachgezogen; Wohnen; Wohnung1 EG | R-005 | 0 | EG-R-005-Wohnen

# IfcBuildingElementProxy: Unterschrank Mehrfach-Schublade 22 (8)
In: EG
Classification: Möbel (ARCHICAD Klassifizierung)
ArchiCADProperties - Ebene: Möblierung; Bibliothekselement-Name: Unterschrank Mehrfach-Schublade 22; Baustoff / Mehrschichtiger Aufbau / Profil / Schraffur: Nur Hintergrund-Stift; Schraffurtyp: Nur Hintergrund-Stift; Zugehöriger Raumname: Wohnen; Geschützt: no; Ursprungsgeschoss Name: EG; Ursprungsgeschoss Nummer: 0; Typ: Objekt; Oberfläche (Alle): Metall Chrom; Farbe, weiß; Lage: Innen; Tragende Funktion: Nicht definiert; Anzeigen auf Umbau-Filter: Alle relevanten Filter; Umbau-Status: Bestand; Oberfläche: Kunststoff PE, weiss; ARCHICAD Klassifizierung - 22: Möbel
AC_Pset_Unterschrank_Mehrfach-Schublade_22 - 3D-Detaillierungsgrad: 1; 'A' 'B' Größe=: Arbeitsplatte; 'A' 'B' Größe=Schrankgröße: no; Fuß (bToeOn): yes; Sockel/Fußtyp (gs_toe_type): Komplett; Sockel/Fußtyp (gs_toe_type_m): 1; Arbeitsplattenkante sichtbar in 3D (side_vis): Keine; Seiten sichtbar: 0; Arbeitsplattenkante sichtbar in 3D (side_vis_mirror): Keine; Schubladenfront: yes; Schema (gs_drawerScheme): Schema 1; Schema (gs_drawerScheme_m): 1; Anzahl Schubladen: 4; Schubladentyp (gs_door_type): Stil 1; Schubladentyp (gs_door_type_m): 1; Eckfase: no; Anz. der vertikalen Schubladen-Aufteilungen: 1; Anz. der horizontalen Schubladen-Aufteilungen: 1; Knöpfe (bKnob): yes; Knöpfe (gs_knob_type): Stil 1; Knopftyp: 1; Doppelgriff an Schubladen: no; Vertikale Knopfposition (sKnobVertPos): Oben; Vertikale Knopfposition (iKnobVertPos): 1; Fuß und Paneel abhängig: 0; Linkes Abschlusspaneel (left_panel): no; Linkes Abschlusspaneel hat Unterschrankgröße: yes; Rechtes Abschlusspaneel (right_panel): no; Rechtes Abschlusspaneel hat Unterschrankgröße: yes; Linkes Abschlusspaneel (left_panel_mirror): no; Rechtes Abschlusspaneel (right_panel_mirror): no; Hinteres Abschlusspaneel: no; Hinteres Abschlusspaneel hat Unterschrankgröße: yes; Abschlusspaneel-Typ: Stil 1; Arbeitsplatte (bCounter): no; Typ Arbeitsplatte (gs_count_type): Rechteckig; Typ Arbeitsplatte (gs_count_type_m): 1; Schubladen in 2D: no; Schubladen-Linienlänge verringern: no; Kanten sichtbar im 2D (side_vis2D): Keine; Kanten sichtbar im 2D (side_vis2D_m): 0; Kanten sichtbar im 2D (side_vis2D_mirror): Keine; Verdeckte 2D Kanten: 0; Überstand Linien-Stift: Konturstift; Überstand Line: 4; Konturstift: Konturstift; Schraffur: Nur Hintergrund-Stift; Auflösung: 16; Schatten: yes; Extra Fixpunkte verwenden: no; Fuß (toe_mat): Metall Chrom; Arbeitsplatte (count_mat): Holzwerkstoff MDF, schwarz; Spritzschutz: Metall Chrom; Schrank (gs_cabinet_mat): Farbe, weiß; Obere Schublade: Farbe, weiß; Schublade (doorframe_mat): Farbe, weiß; Glas: Glas Normalglas; Abschlusspaneel: Farbe, weiß; Knöpfe (gs_knob_mat): Metall Chrom; 2D-Fixpunkte in 3D zeigen: no; Keine Spüle: 0; Keine Armatur: 0; Türwinkel: 0 deg; Preis: 0; Gruppe Typ (FM_Type): Möbel; Gruppe Typ (iFMType): 16; Objektgewicht: 0; Objektgewichtseinheit: kg
ArchiCADQuantities - Höhe: 0.9 m; Breite: 0.6 m; Höhenangabe zum Projekt-Nullpunkt: 0.2 m; Höhe zu 1. Referenzhöhe: 0.2 m; Höhe zu 2. Referenzhöhe: 0.2 m; Höhe zu Meereshöhe: 16.2 m; Höhe zu verknüpftem/Ursprungsgeschoss: 0.2 m; Abstand zu Ursprungsgeschoss: 0.2 m
AC_Equantity_Unterschrank_Mehrfach-Schublade_22 - Schrank Tiefe: 0.6 m; Höhe Arbeitsplatte: 0.9 m; Fußhöhe: 0.09 m; Fuß Rücksprung: 0 m; Schubladendicke: 0.02 m; Schubladenhöhe oben: 0.04 m; Höhe Untere Schublade: 0.04 m; Schubladenhöhe 1: 0.132 m; Schubladenhöhe 2: 0.132 m; Schubladenhöhe 3: 0.132 m; Schubladenhöhe 4: 0.133 m; Schubladenhöhe 5: 0 m; Schubladenhöhe 6: 0 m; Breite Rahmen Füße: 0.03 m; Breite Tür: 0.6 m; Knopfgröße: 0.1 m; Griffabstand zur Seite: 0.2 m; Horizontale Knopfposition: 0 m; Individueller Griff Länge: 0.1 m; Individueller Griff Höhe: 0.015 m; Individueller Griff Tiefe: 0.02 m; Linkes Abschlusspaneel Dicke: 0.02 m; Rechtes Abschlusspaneel Dicke: 0.02 m; Hinteres Abschlusspaneel Dicke: 0.02 m; Abschlusspaneel Rahmenbreite: 0.09 m; Stärke Arbeitsplatte: 0.05 m; Höhe Spritzschutz 0-keine: 0 m; Überhang zur Front des Schranks: 0.05 m; Überhang zur Rückseite des Schranks: 0 m; Überhang zur linken Seite des Schranks (left_cab): 0 m; Überhang zur rechten Seite des Schranks (right_cab): 0 m; Überhang zur linken Seite des Schranks (left_cab_mirror): 0 m; Überhang zur rechten Seite des Schranks (right_cab_mirror): 0 m; Min. Platzbedarf vorne: 0.9 m; Untere Ebene: 1 m; Obere Ebene: 0 m; Keine Spüle: 0 m
Name | Element ID = Hotlink und Element-ID = Überobjekt-ID | Kollidierende Räume | Zugehörige Raumnummer | Drehwinkel (deg) | Zugehörigkeit | Fläche (m2) | Netto-Volumen (m3) | Oberflächenbereich (m2) | Länge (A) (m) = Schrank Breite (m) | Höhe Türblatt (m)
Küche-005 | Küche-005 | Erdgeschoss; Grundfläche Gebäude Nachgezogen; Wohnen; Wohnung1 EG | R-005 | 0 | EG-R-005-Wohnen | 0.36 | 0.0929962 | 7.72547 | 0.6 | 0.68 | Component Quantities - Component 1, Schicht/Komponente Volumen: 0.0929962 m3
Küche-005 | Küche-005 | Erdgeschoss; Grundfläche Gebäude Nachgezogen; Wohnen; Wohnung2 EG | R-004 | 180 | EG-R-004-Wohnen | 0.36 | 0.0929962 | 7.72547 | 0.6 | 0.68 | Component Quantities - Component 1, Schicht/Komponente Volumen: 0.0929962 m3
Küche-005 | Küche-005 | Erdgeschoss; Grundfläche Gebäude Nachgezogen; Wohnen; Wohnung2 EG | R-004 | 180 | EG-R-004-Wohnen | 0.48 | 0.119168 | 9.71667 | 0.8 | 0.635 | Component Quantities - Component 1, Schicht/Komponente Volumen: 0.119168 m3
Küche-006 | Küche-006 | Erdgeschoss; Grundfläche Gebäude Nachgezogen; Wohnen; Wohnung1 EG | R-005 | 0 | EG-R-005-Wohnen | 0.36 | 0.0929962 | 7.72547 | 0.6 | 0.68
Küche-006 | Küche-006 | Erdgeschoss; Grundfläche Gebäude Nachgezogen; Wohnen; Wohnung2 EG | R-004 | 180 | EG-R-004-Wohnen | 0.36 | 0.0929962 | 7.72547 | 0.6 | 0.68
Küche-005 | Küche-005 | Erdgeschoss; Grundfläche Gebäude Nachgezogen; Wohnen; Wohnung1 EG | R-005 | 0 | EG-R-005-Wohnen | 0.36 | 0.0929962 | 7.72547 | 0.6 | 0.635
Küche-005 | Küche-005 | Erdgeschoss; Grundfläche Gebäude Nachgezogen; Wohnen; Wohnung2 EG | R-004 | 180 | EG-R-004-Wohnen | 0.36 | 0.0929962 | 7.72547 | 0.6 | 0.635
Küche-005 | Küche-005 | Erdgeschoss; Grundfläche Gebäude Nachgezogen; Wohnen; Wohnung1 EG | R-005 | 0 | EG-R-005-Wohnen | 0.48 | 0.119168 | 9.71667 | 0.8 | 0.635 | Component Quantities - Component 1, Schicht/Komponente Volumen: 0.119168 m3

# IfcBuildingElementProxy: Unterschrank Spülmaschine 22 (2)
In: EG
Classification: Möbel (ARCHICAD Klassifizierung)
ArchiCADProperties - Element ID: Küche-007; Hotlink und Element-ID: Küche-007; Ebene: Möblierung; Bibliothekselement-Name: Unterschrank Spülmaschine 22; Baustoff / Mehrschichtiger Aufbau / Profil / Schraffur: Nur Hintergrund-Stift; Schraffurtyp: Nur Hintergrund-Stift; Zugehöriger Raumname: Wohnen; Geschützt: no; Ursprungsgeschoss Name: EG; Ursprungsgeschoss Nummer: 0; Typ: Objekt; Überobjekt-ID: Küche-007; Oberfläche (Alle): Metall Chrom; Farbe, weiß; Lage: Innen; Tragende Funktion: Nicht definiert; Anzeigen auf Umbau-Filter: Alle relevanten Filter; Umbau-Status: Bestand; Oberfläche: Kunststoff PE, weiss; ARCHICAD Klassifizierung - 22: Möbel
AC_Pset_Unterschrank_Spülmaschine_22 - 2D-Fixpunkte in 3D zeigen: no; Programm einstellen: no; 3D-Detaillierungsgrad: 1; 'A' 'B' Größe=: Arbeitsplatte; 'A' 'B' Größe=Schrankgröße: no; Fuß (bToeOn): yes; Sockel/Fußtyp (gs_toe_type): Komplett; Sockel/Fußtyp (gs_toe_type_m): 1; Arbeitsplattenkante sichtbar in 3D (side_vis): Keine; Seiten sichtbar: 0; Arbeitsplattenkante sichtbar in 3D (side_vis_mirror): Keine; Paneel (bControl): yes; Bedienfeld-Typ: 1; Tür: Stil 1; Fronttyp: 1; Eckfase: no; Schublade: yes; Tür-Öffnungswinkel: 0 deg; Anz. der vertikalen Türaufteilung: 1; Anz. der horizontalen Türaufteilung: 2; Knopf (bKnob): yes; Knopf (gs_knob_type): Stil 1; Knopftyp: 1; Doppelseitig: no; Fuß und Paneel abhängig: 0; Linkes Abschlusspaneel (left_panel): no; Linkes Abschlusspaneel hat Unterschrankgröße: yes; Rechtes Abschlusspaneel (right_panel): no; Rechtes Abschlusspaneel hat Unterschrankgröße: yes; Linkes Abschlusspaneel (left_panel_mirror): no; Rechtes Abschlusspaneel (right_panel_mirror): no; Hinteres Abschlusspaneel: no; Hinteres Abschlusspaneel hat Unterschrankgröße: yes; Abschlusspaneel-Typ: Stil 1; Arbeitsplatte (bCounter): no; Arbeitsplatte (gs_count_type): Rechteckig; Kaltwasseranschluss: yes; Werkzeug-Typ (ConToolType_1): 2; HKLSE System (ConSystem_1): Undefiniert; Form-Typ (ConType_1): Kreis; Abwasser Anschluss: yes; Werkzeug-Typ (ConToolType_2): 2; HKLSE System (ConSystem_2): Undefiniert; Form-Typ (ConType_2): Kreis; Kanten sichtbar im 2D (side_vis2D): Keine; Kanten sichtbar im 2D (side_vis2D_m): 0; Kanten sichtbar im 2D (side_vis2D_mirror): Keine; Verdeckte 2D Kanten: 0; Überstand Linien-Stift: Konturstift; Überstand Line: 4; Symbolisch 2D: no; Symboltyp (gs_dw_symbol_type): Stil 2; Symboltyp (iDwSymbolType): 2; Symbol-Stift: Elemente+Text; Spülmaschine Symbolschraffur: Nur Vordergrund-Stift; Konturstift: Konturstift; Schraffur: Nur Hintergrund-Stift; Darstellung Text: yes; Text: GS; Text-Stift: Elemente+Text; Schrifttyp: Arial; Schriftgröße (mm): 12; Schriftgröße (Punkt): 34.0157; Fett: no; Kursiv: no; Unterstrichen: no; Text-Ausrichtung am Symbol (typeTextRotation): Lesbar; Text-Ausrichtung am Symbol (typeTextRotation_m): 2; Auflösung: 10; Schatten: yes; Extra Fixpunkte verwenden: yes; Schrank (gs_cabinet_mat): Farbe, weiß; Arbeitsplatte (count_mat): Holzwerkstoff MDF, schwarz; Spritzschutz: Metall Chrom; Fuß (toe_mat): Metall Chrom; Tür (Rahmen): Farbe, weiß; Tür (Einsatz ): Metall Stahl, matt; Abschlusspaneel: Farbe, weiß; Knopf (gs_knob_mat): Metall Chrom; Paneel (ControlPanelMat): Metall Chrom; Griff 1: Metall Chrom; Griff 2: Metall Chrom; Schalter: Metall Chrom; Anschluss: Metall Stahl, poliert; System Oberflächenmaterial benutzen: no; System Oberflächenmaterial: Farbe, grau; Typ Counter: 1; Anschlussanzahl: 2; Preis: 0; Fläche: 0; Volumen: 0; Gruppe Typ (FM_Type): HKLSE Ausstattung; Gruppe Typ (iFMType): 12; Objektgewicht: 0; Objektgewichtseinheit: kg
ArchiCADQuantities - Fläche: 0.36 m2; Höhe: 0.9 m; Netto-Volumen: 0.0758868 m3; Breite: 0.6 m; Höhenangabe zum Projekt-Nullpunkt: 0.2 m; Höhe zu 1. Referenzhöhe: 0.2 m; Höhe zu 2. Referenzhöhe: 0.2 m; Höhe zu Meereshöhe: 16.2 m; Höhe zu verknüpftem/Ursprungsgeschoss: 0.2 m; Abstand zu Ursprungsgeschoss: 0.2 m; Oberflächenbereich: 5.91937 m2; Länge (A): 0.6 m
AC_Equantity_Unterschrank_Spülmaschine_22 - Schrank Breite: 0.6 m; Schrank Tiefe: 0.6 m; Höhe Arbeitsplatte: 0.9 m; Untere Ebene: 1 m; Obere Ebene: 0 m; Fußhöhe: 0.09 m; Fuß Rücksprung: 0 m; Türdicke: 0.02 m; Türrahmen Breite (doorframe_w): 0.09 m; Horizontale Position: 0.3 m; Vertikale Position: 0.8 m; Knopfgröße: 0.1 m; Individueller Griff Länge: 0.1 m; Individueller Griff Höhe: 0.015 m; Individueller Griff Tiefe: 0.02 m; Linkes Abschlusspaneel Dicke: 0.02 m; Rechtes Abschlusspaneel Dicke: 0.02 m; Hinteres Abschlusspaneel Dicke: 0.02 m; Türrahmen Breite (doorframe_w_end): 0.09 m; Stärke Arbeitsplatte: 0.05 m; Höhe Spritzschutz 0-keine: 0 m; Überhang zur Front des Schranks: 0.05 m; Überhang zur Rückseite des Schranks: 0 m; Überhang zur linken Seite des Schranks (left_cab): 0 m; Überhang zur rechten Seite des Schranks (right_cab): 0 m; Überhang zur linken Seite des Schranks (left_cab_mirror): 0 m; Überhang zur rechten Seite des Schranks (right_cab_mirror): 0 m; Nominale Tiefe (ConNominalDepth_1): 0.025 m; Außendurchmesser (ConWidth_1): 0.027 m; Außentiefe (ConDepth_1): 0.027 m; Wanddicke (ConWallThickness_1): 0.001 m; Anschluss-Länge (ConLength_1): 0.02 m; Anschluss Durchmesser (ConConnectorWidth_1): 0.04 m; Anschluss-Tiefe (ConConnectorDepth_1): 0 m; Anschluss-Breite (ConConnectorWidth2_1): 0.005 m; Anschluss-Position X (ConPosX_1): 0.2 m; Anschluss-Position Y (ConPosY_1): 0.6 m; Anschluss-Position Z (ConPosZ_1): 0.68 m; Nominale Tiefe (ConNominalDepth_2): 0.04 m; Außendurchmesser (ConWidth_2): 0.042 m; Außentiefe (ConDepth_2): 0.042 m; Wanddicke (ConWallThickness_2): 0.001 m; Anschluss-Länge (ConLength_2): 0.02 m; Anschluss Durchmesser (ConConnectorWidth_2): 0.042 m; Anschluss-Tiefe (ConConnectorDepth_2): 0 m; Anschluss-Breite (ConConnectorWidth2_2): 0.005 m; Anschluss-Position X (ConPosX_2): 0.4 m; Anschluss-Position Y (ConPosY_2): 0.6 m; Anschluss-Position Z (ConPosZ_2): 0.68 m; Text Position X: 0 m; Text Position Y: 0 m; Min. Platzbedarf vorne: 0.9 m; Min. Platzbedarf auf Seite 1: 0 m; Min. Platzbedarf auf Seite 2: 0 m; Minimaler Platzbedarf: 0.9 m; Rückwärtiger minimaler Platzbedarf Seite 1: 0 m; Rückwärtiger minimaler Platzbedarf Seite 2: 0 m; Höhe Türblatt: 0.68 m; Breite Tür: 0.6 m
Component Quantities - Component 1, Schicht/Komponente Volumen: 0.0758868 m3
Name | Kollidierende Räume | Zugehörige Raumnummer | Drehwinkel (deg) | Zugehörigkeit
Küche-007 | Erdgeschoss; Grundfläche Gebäude Nachgezogen; Wohnen; Wohnung1 EG | R-005 | 0 | EG-R-005-Wohnen
Küche-007 | Erdgeschoss; Grundfläche Gebäude Nachgezogen; Wohnen; Wohnung2 EG | R-004 | 180 | EG-R-004-Wohnen

# IfcBuildingElementProxy: Wand WC 22 (2)
In: EG
Classification: Möbel (ARCHICAD Klassifizierung)
ArchiCADProperties - Ebene: Möblierung; Bibliothekselement-Name: Wand WC 22; Baustoff / Mehrschichtiger Aufbau / Profil / Schraffur: Nur Hintergrund-Stift; Schraffurtyp: Nur Hintergrund-Stift; Zugehöriger Raumname: Bad; Geschützt: no; Ursprungsgeschoss Name: EG; Ursprungsgeschoss Nummer: 0; Typ: Objekt; Oberfläche (Alle): Kunststoff PE, weiss; Lage: Nicht definiert; Tragende Funktion: Nicht definiert; Anzeigen auf Umbau-Filter: Alle relevanten Filter; Umbau-Status: Bestand; Drehwinkel: 270 deg; Oberfläche: Kunststoff PE, weiss; ARCHICAD Klassifizierung - 22: Möbel
AC_Pset_Wand_WC_22 - 2D Hotspots in 3D zeigen: yes; Programm einstellen: no; 3D-Detaillierungsgrad: 1; Produkt: Typ 2; WC-Sitze: yes; WC-Sitze offen: no; Wasser Anschluss: yes; Werkzeug Typ (ConToolType_1): 2; HKLSE System (ConSystem_1): Undefiniert; Form Typ (ConType_1): Kreis; Anschlusstyp (ConConnectorType_1): Geschweißt; Abwasser Anschluss: yes; Werkzeug Typ (ConToolType_2): 2; HKLSE System (ConSystem_2): Undefiniert; Form Typ (ConType_2): Kreis; Anschlusstyp (ConConnectorType_2): Geschweißt; 2D-Detaillierungsgrad: 1; Stift Kontur: Elemente+Text; Grundschraffur: yes; Ausfüllmuster: Nur Hintergrund-Stift; Stift Schraffur: Schraffurhintergrund; Stift Hintergrundschraffur: Schraffurhintergrund; 3D Linien: yes; System-Material anwenden: no; Material System: Fliesen, terrakotta; Zeige in 3D: yes; Becken: Kunststoff PE, weiss; Metall: Metall Kupfer; Sitze: Kunststoff PE, weiss; Anschluss: Metall Stahl, poliert; IFC Subtype: 33; IFC Enumeration: 9; Aktueller Anschluss auf dem UI: 1; Aktuelle UI Seite: 1; Version: 4; Anzahl Anschlüsse: 2; Preis: 0; Gruppe (FM_Type): HLS Ausstattung; Gruppe (iFMType): 999; Fläche: 0; Volumen: 0; ERP Code: 0; Bestellnummer: 0; Gewicht: 0; Gewichteinheit: Kg; Dimensionen B/T/H: 38,00/56,50/40,00; Montagehöhe Wert: Automatisch; Montagehöhe: 20,00
ArchiCADQuantities - Fläche: 0.2147 m2; Höhe: 0.4 m; Netto-Volumen: 0.00471106 m3; Breite: 0.565 m; Höhenangabe zum Projekt-Nullpunkt: 0.2 m; Höhe zu 1. Referenzhöhe: 0.2 m; Höhe zu 2. Referenzhöhe: 0.2 m; Höhe zu Meereshöhe: 16.2 m; Höhe zu verknüpftem/Ursprungsgeschoss: 0.2 m; Abstand zu Ursprungsgeschoss: 0.2 m; Oberflächenbereich: 2.10876 m2; Länge (A): 0.38 m
AC_Equantity_Wand_WC_22 - Höhe: 0.4 m; Untere Ebene: 1 m; Obere Ebene: 0 m; Nominal Tiefe (ConNominalDepth_1): 0 m; Durchmesser Außen (ConWidth_1): 0.032 m; Tiefe Außen (ConDepth_1): 0.032 m; Wandstärke (ConWallThickness_1): 0.001 m; Anschlusslänge (ConLength_1): 0.02 m; Anschluss Durchmesser (ConConnectorWidth_1): 0.04 m; Anschluss Tiefe (ConConnectorDepth_1): 0 m; Anschluss Breite (ConConnectorWidth2_1): 0.005 m; Anschluss Position X (ConPosX_1): 0 m; Anschluss Position Y (ConPosY_1): 0 m; Anschluss Position Z (ConPosZ_1): 0.35 m; Nominal Tiefe (ConNominalDepth_2): 0 m; Durchmesser Außen (ConWidth_2): 0.114 m; Tiefe Außen (ConDepth_2): 0.114 m; Wandstärke (ConWallThickness_2): 0.002 m; Anschlusslänge (ConLength_2): 0.02 m; Anschluss Durchmesser (ConConnectorWidth_2): 0.12 m; Anschluss Tiefe (ConConnectorDepth_2): 0 m; Anschluss Breite (ConConnectorWidth2_2): 0.005 m; Anschluss Position X (ConPosX_2): 0 m; Anschluss Position Y (ConPosY_2): 0 m; Anschluss Position Z (ConPosZ_2): 0.195 m; Min. Platzbedarf vorne: 1.2 m; Min. Platzbedarf auf Seite 1: 0.2 m; Min. Platzbedarf auf Seite 2: 0.6 m
Name | Element ID = Hotlink und Element-ID = Überobjekt-ID = ID-Nummer | Kollidierende Räume | Zugehörige Raumnummer | Zugehörigkeit
Objekt-005 | Objekt-005 | Bad; Erdgeschoss; Grundfläche Gebäude Nachgezogen; Wohnung2 EG | R-008 | EG-R-008-Bad | Component Quantities - Component 1, Schicht/Komponente Volumen: 0.00471106 m3
Objekt-006 | Objekt-006 | Bad; Erdgeschoss; Grundfläche Gebäude Nachgezogen; Wohnung1 EG | R-007 | EG-R-007-Bad

# IfcBuildingElementProxy: Waschbecken 1 22 (2)
In: EG
Classification: Möbel (ARCHICAD Klassifizierung)
ArchiCADProperties - Ebene: Möblierung; Bibliothekselement-Name: Waschbecken 1 22; Baustoff / Mehrschichtiger Aufbau / Profil / Schraffur: Nur Hintergrund-Stift; Schraffurtyp: Nur Hintergrund-Stift; Zugehöriger Raumname: Bad; Geschützt: no; Ursprungsgeschoss Name: EG; Ursprungsgeschoss Nummer: 0; Typ: Objekt; Oberfläche (Alle): Farbe, grau; Farbe, weiß; Lage: Nicht definiert; Tragende Funktion: Nicht definiert; Anzeigen auf Umbau-Filter: Alle relevanten Filter; Umbau-Status: Bestand; Oberfläche: Kunststoff PE, weiss; ARCHICAD Klassifizierung - 22: Möbel
AC_Pset_Waschbecken_1_22 - Becken-Typ (stStyle): Rechteckig; Becken-Typ (iStyle): 6; 2D-Fixpunkte in 3D zeigen: no; Programm einstellen: no; 3D-Detaillierungsgrad: 1; Befestigung (suptyp): Keine; Befestigung (iSuptyp): 0; Hahn-Typ (tapGroup): Einhebelmischer; Hahn-Typ (iTapGroup): 1; Zapfentyp (gs_tap_type): Stil 1; Zapfentyp (gs_tap_type_m): 1; Warmwasseranschluss: yes; Werkzeug-Typ (ConToolType_1): 2; HKLSE System (ConSystem_1): Undefiniert; Form-Typ (ConType_1): Kreis; Anschluss-Typ (ConConnectorType_1): Schweissverbindung; Kaltwasseranschluss: yes; Werkzeug-Typ (ConToolType_2): 2; HKLSE System (ConSystem_2): Undefiniert; Form-Typ (ConType_2): Kreis; Anschluss-Typ (ConConnectorType_2): Schweissverbindung; Abwasser Anschluss: yes; Werkzeug-Typ (ConToolType_3): 2; HKLSE System (ConSystem_3): Undefiniert; Form-Typ (ConType_3): Kreis; Anschluss-Typ (ConConnectorType_3): Schweissverbindung; Auflösung: 12; Anschluss-Auflösung: 8; Schatten: yes; Symboltyp (gs_symbol_type): Projiziert; Symboltyp (iSymbolType): 1; Aktiviere Symboltypen: no; 2D-Detaillierungsgrad: 1; Typ Stopfen-Symbol (TapSymbol): Detailliert; Typ Stopfen-Symbol (TapSymbol_m): 2; Konturstift: Elemente+Text; Schraffur: Nur Hintergrund-Stift; Schraffur-Vordergrundstift: Schraffurhintergrund; Schraffur-Hintergrundstift: Schraffurhintergrund; Waschbecken: Farbe, weiß; Wasserhahn: Farbe, weiß; Abfluss: Farbe, grau; Anschluss: Metall Stahl, poliert; System Oberflächenmaterial benutzen: no; System Oberflächenmaterial: Farbe, grau; Anschlussanzahl: 3; Preis: 0; Gruppe Typ (FM_Type): Sanitäre Anlagen; Gruppe Typ (iFMType): 13; Fläche: 0; Volumen: 0; Objektgewicht: 0; Objektgewichtseinheit: kg; Dimensionen B/T/H: 36,50/26,00/13,50; Montagehöhe Wert: Automatisch; Montagehöhe: 20,00
ArchiCADQuantities - Fläche: 0.0949 m2; Höhe: 0.135 m; Netto-Volumen: 0.0109962 m3; Breite: 0.26 m; Höhenangabe zum Projekt-Nullpunkt: 0.2 m; Höhe zu 1. Referenzhöhe: 0.2 m; Höhe zu 2. Referenzhöhe: 0.2 m; Höhe zu Meereshöhe: 16.2 m; Höhe zu verknüpftem/Ursprungsgeschoss: 0.2 m; Abstand zu Ursprungsgeschoss: 0.2 m; Oberflächenbereich: 0.619963 m2; Länge (A): 0.365 m
AC_Equantity_Waschbecken_1_22 - Breite Waschbecke: 0.365 m; Tiefe Waschbecke: 0.26 m; Höhe: 0.135 m; Obere Höhe: 1 m; Untere Ebene: 0.865 m; Obere Ebene: 1 m; Hahn-Höhe: 1.1 m; Hahn X-Position: 0 m; Hahn Y-Position: 0 m; Hahn Z-Position: 0 m; Nominale Tiefe (ConNominalDepth_1): 0.025 m; Außendurchmesser (ConWidth_1): 0.027 m; Außentiefe (ConDepth_1): 0.027 m; Wanddicke (ConWallThickness_1): 0.001 m; Anschluss-Länge (ConLength_1): 0.02 m; Anschluss Durchmesser (ConConnectorWidth_1): 0.04 m; Anschluss-Tiefe (ConConnectorDepth_1): 0 m; Anschluss-Breite (ConConnectorWidth2_1): 0.005 m; Anschluss-Position X (ConPosX_1): -0.1 m; Anschluss-Position Y (ConPosY_1): 0 m; Anschluss-Position Z (ConPosZ_1): 0.093 m; Nominale Tiefe (ConNominalDepth_2): 0.025 m; Außendurchmesser (ConWidth_2): 0.027 m; Außentiefe (ConDepth_2): 0.027 m; Wanddicke (ConWallThickness_2): 0.001 m; Anschluss-Länge (ConLength_2): 0.02 m; Anschluss Durchmesser (ConConnectorWidth_2): 0.04 m; Anschluss-Tiefe (ConConnectorDepth_2): 0 m; Anschluss-Breite (ConConnectorWidth2_2): 0.005 m; Anschluss-Position X (ConPosX_2): 0.1 m; Anschluss-Position Y (ConPosY_2): 0 m; Anschluss-Position Z (ConPosZ_2): 0.093 m; Nominale Tiefe (ConNominalDepth_3): 0.04 m; Außendurchmesser (ConWidth_3): 0.042 m; Außentiefe (ConDepth_3): 0.042 m; Wanddicke (ConWallThickness_3): 0.001 m; Anschluss-Länge (ConLength_3): 0.02 m; Anschluss Durchmesser (ConConnectorWidth_3): 0.042 m; Anschluss-Tiefe (ConConnectorDepth_3): 0 m; Anschluss-Breite (ConConnectorWidth2_3): 0.005 m; Anschluss-Position X (ConPosX_3): 0 m; Anschluss-Position Y (ConPosY_3): -0.215 m; Anschluss-Position Z (ConPosZ_3): 0 m; Min. Platzbedarf vorne: 1.2 m; Min. Platzbedarf auf Seite 1: 0.25 m; Min. Platzbedarf auf Seite 2: 0.35 m
Name | Element ID = Hotlink und Element-ID = Überobjekt-ID = ID-Nummer | Kollidierende Räume | Zugehörige Raumnummer | Drehwinkel (deg) | Zugehörigkeit
Objekt-002 | Objekt-002 | Bad; Erdgeschoss; Grundfläche Gebäude Nachgezogen; Wohnung1 EG | R-007 | 0 | EG-R-007-Bad | Component Quantities - Component 1, Schicht/Komponente Volumen: 0.0109962 m3
Objekt-001 | Objekt-001 | Bad; Erdgeschoss; Grundfläche Gebäude Nachgezogen; Wohnung2 EG | R-008 | 180 | EG-R-008-Bad

# IfcCovering: Belag, Fliesen weiß 50 (2)
In: EG
Type - PredefinedType: FLOORING
Classification: Fußbodenaufbau (ARCHICAD Klassifizierung); Material: Belag, Fliesen weiß
Pset_CoveringCommon - Material: Belag, Fliesen weiß
ArchiCADProperties - Element ID: Decke-008; Hotlink und Element-ID: Decke-008; Ebene: Decken Ausbau; Baustoff / Mehrschichtiger Aufbau / Profil / Schraffur: Belag, Fliesen weiß; Baustoff: Belag, Fliesen weiß; Geschützt: no; Ursprungsgeschoss Name: EG; Ursprungsgeschoss Nummer: 0; Typ: Decke; Struktur-Typ: Einfach; Überobjekt-ID: Decke-008; Baustoffe (Alle): Belag, Fliesen weiß; Oberfläche (Alle): Fliesen, weiß; Deckschraffur: Misch-Schraffur 25 %; Lage: Innen; Tragende Funktion: Nicht tragende Elemente; Anzeigen auf Umbau-Filter: Alle relevanten Filter; Umbau-Status: Bestand; Oberfläche unten: Fliesen, weiß; Oberfläche Kante: Fliesen, weiß; Lage der Referenzebene: Oben; Oberfläche oben: Fliesen, weiß; ARCHICAD Klassifizierung - 22: Fußbodenaufbau
Brandschutz 4102-2 - Kennbuchstabe: F
Component Properties - Component 1, Enthaltenes CO2: 42.525 (kgCO₂); Component 1, Enthaltene Energie: 354.375 MJ; Component 1, Komponenten-Typ: Keine
BaseQuantities - GrossArea: 2.7 m2; NetArea: 2.7 m2
ArchiCADQuantities - Fläche: 2.7 m2; Höhe: 0.05 m; Netto-Volumen: 0.135 m3; Höhenangabe zum Projekt-Nullpunkt: 0.2 m; Höhe zu 1. Referenzhöhe: 0.2 m; Höhe zu 2. Referenzhöhe: 0.2 m; Höhe zu Meereshöhe: 16.2 m; Höhe zu verknüpftem/Ursprungsgeschoss: 0.2 m; Abstand zu Ursprungsgeschoss: 0.2 m; Oberflächenbereich: 2.7 m2; Dicke: 0.05 m; Konditionales Volumen: 0.135 m3; Brutto-Volumen: 0.135 m3; Grundriss-Umfang: 6.6 m; Grundriss-Durchbruch Umfang: 0 m; Höhenwert Unterkante: 0.15 m; Oberflächenbereich Unterseite: 2.7 m2; Konditionaler Oberflächenbereich der Unterseite: 2.7 m2; Konditionaler Oberflächenbereich der Oberseite: 2.7 m2; Kante Oberflächenbereich: 0.33 m2; Brutto-Oberflächenbereich der Deckenunterseite: 2.7 m2; Brutto-Oberflächenbereich der Deckenunterseite mit Löchern: 2.7 m2; Brutto-Oberflächenbereich der Deckenkanten: 0.33 m2; Brutto-Oberflächenbereich der Deckenkanten mit Löchern: 0.33 m2; Brutto-Oberfläche der Deckenoberseite: 2.7 m2; Brutto-Oberflächenbereich der Deckenoberseite mit Löchern: 2.7 m2; Löcher Oberflächenbereich: 0 m2; Höhenwert Oberkante: 0.2 m; Oberflächenbereich Oberseite: 2.7 m2
Component Quantities - Component 1, Masse: 236.25 kg; Component 1, Schicht/Komponente Oberflächenbereich: 2.7 m2; Component 1, Schichtdicke: 0.05 m; Component 1, Schicht/Komponente Volumen: 0.135 m3
Name | Kollidierende Räume
Decke-008 | Bad; Erdgeschoss; Grundfläche Gebäude Nachgezogen; Wohnung2 EG
Decke-008 | Bad; Erdgeschoss; Grundfläche Gebäude Nachgezogen; Wohnung1 EG

# IfcCovering: Belag, Kunststoff 50, Decke-008
In: EG
Type - PredefinedType: FLOORING
Classification: Fußbodenaufbau (ARCHICAD Klassifizierung); Material: Belag, Kunststoff
Pset_CoveringCommon - TotalThickness: 0.2 m; Material: Belag, Kunststoff
ArchiCADProperties - Element ID: Decke-008; Hotlink und Element-ID: Decke-008; Ebene: Decken Ausbau; Baustoff / Mehrschichtiger Aufbau / Profil / Schraffur: Belag, Kunststoff; Baustoff: Belag, Kunststoff; Kollidierende Räume: Erdgeschoss; Grundfläche Gebäude Nachgezogen; Wohnen; Wohnen; Wohnung1 EG; Geschützt: no; Ursprungsgeschoss Name: EG; Ursprungsgeschoss Nummer: 0; Typ: Decke; Struktur-Typ: Einfach; Überobjekt-ID: Decke-008; Baustoffe (Alle): Belag, Kunststoff; Oberfläche (Alle): Farbe, weiß; Deckschraffur: Misch-Schraffur 25 %; Lage: Innen; Tragende Funktion: Nicht tragende Elemente; Anzeigen auf Umbau-Filter: Alle relevanten Filter; Umbau-Status: Bestand; Oberfläche unten: Farbe, weiß; Oberfläche Kante: Farbe, weiß; Lage der Referenzebene: Oben; Oberfläche oben: Farbe, weiß; ARCHICAD Klassifizierung - 22: Fußbodenaufbau
Brandschutz 4102-2 - Kennbuchstabe: F
Component Properties - Component 1, Enthaltenes CO2: 14732.1 (kgCO₂); Component 1, Enthaltene Energie: 366877 MJ; Component 1, Komponenten-Typ: Keine
BaseQuantities - GrossArea: 71.7095 m2; NetArea: 68.3782 m2
ArchiCADQuantities - Fläche: 68.3782 m2; Höhe: 0.05 m; Netto-Volumen: 3.41891 m3; Höhenangabe zum Projekt-Nullpunkt: 0.2 m; Höhe zu 1. Referenzhöhe: 0.2 m; Höhe zu 2. Referenzhöhe: 0.2 m; Höhe zu Meereshöhe: 16.2 m; Höhe zu verknüpftem/Ursprungsgeschoss: 0.2 m; Abstand zu Ursprungsgeschoss: 0.2 m; Oberflächenbereich: 68.3782 m2; Dicke: 0.05 m; Konditionales Volumen: 3.58547 m3; Brutto-Volumen: 3.73433 m3; Grundriss-Umfang: 43.39 m; Grundriss-Durchbruch Umfang: 7.35 m; Höhenwert Unterkante: 0.15 m; Oberflächenbereich Unterseite: 68.3782 m2; Konditionaler Oberflächenbereich der Unterseite: 68.3782 m2; Konditionaler Oberflächenbereich der Oberseite: 68.3782 m2; Kante Oberflächenbereich: 0.423483 m2; Brutto-Oberflächenbereich der Deckenunterseite: 74.6866 m2; Brutto-Oberflächenbereich der Deckenunterseite mit Löchern: 71.3554 m2; Brutto-Oberflächenbereich der Deckenkanten: 1.802 m2; Brutto-Oberflächenbereich der Deckenkanten mit Löchern: 2.1695 m2; Brutto-Oberfläche der Deckenoberseite: 74.6866 m2; Brutto-Oberflächenbereich der Deckenoberseite mit Löchern: 71.3554 m2; Löcher Oberflächenbereich: 3.33125 m2; Höhenwert Oberkante: 0.2 m; Oberflächenbereich Oberseite: 68.3782 m2
Component Quantities - Component 1, Masse: 4752.29 kg; Component 1, Schicht/Komponente Oberflächenbereich: 68.3782 m2; Component 1, Schichtdicke: 0.05 m; Component 1, Schicht/Komponente Volumen: 3.41891 m3

# IfcCovering: Belag, Parkett 50 (2)
In: OG
PredefinedType: FLOORING; Classification: Abgehängte Decke (ARCHICAD Klassifizierung); Material: Belag, Parkett
Pset_CoveringCommon - TotalThickness: 0.15 m; Material: Belag, Parkett
ArchiCADProperties - Ebene: Decken Ausbau; Baustoff / Mehrschichtiger Aufbau / Profil / Schraffur: Belag, Parkett; Baustoff: Belag, Parkett; Geschützt: no; Ursprungsgeschoss Name: 1. OG; Ursprungsgeschoss Nummer: 1; Typ: Decke; Struktur-Typ: Einfach; Baustoffe (Alle): Belag, Parkett; Oberfläche (Alle): Holz Parkett 2; Deckschraffur: Misch-Schraffur 25 %; Lage: Innen; Tragende Funktion: Nicht tragende Elemente; Anzeigen auf Umbau-Filter: Alle relevanten Filter; Umbau-Status: Bestand; Oberfläche unten: Holz Parkett 2; Oberfläche Kante: Holz Parkett 2; Lage der Referenzebene: Oben; Oberfläche oben: Holz Parkett 2; ARCHICAD Klassifizierung - 22: Abgehängte Decke
Brandschutz 4102-2 - Kennbuchstabe: F
Component Properties - Component 1, Komponenten-Typ: Keine
ArchiCADQuantities - Höhe: 0.05 m; Höhenangabe zum Projekt-Nullpunkt: 3.9 m; Höhe zu 1. Referenzhöhe: 3.9 m; Höhe zu 2. Referenzhöhe: 3.9 m; Höhe zu Meereshöhe: 19.9 m; Höhe zu verknüpftem/Ursprungsgeschoss: 0.15 m; Abstand zu Ursprungsgeschoss: 0.15 m; Dicke: 0.05 m; Grundriss-Durchbruch Umfang: 0 m; Höhenwert Unterkante: 3.85 m; Löcher Oberflächenbereich: 0 m2; Höhenwert Oberkante: 3.9 m
Component Quantities - Component 1, Schichtdicke: 0.05 m
Name | Element ID = Hotlink und Element-ID = Überobjekt-ID | Kollidierende Räume | Component 1, Enthaltenes CO2 | Component 1, Enthaltene Energie (MJ) | GrossArea (m2) = NetArea (m2) = Fläche (m2) = Oberflächenbereich (m2) = Oberflächenbereich Unterseite (m2) = Konditionaler Oberflächenbereich der Unterseite (m2) = Konditionaler Oberflächenbereich der Oberseite (m2) = Oberflächenbereich Oberseite (m2) = Component 1, Schicht/Komponente Oberflächenbereich (m2) | Netto-Volumen (m3) = Konditionales Volumen (m3) = Component 1, Schicht/Komponente Volumen (m3) | Brutto-Volumen (m3) | Grundriss-Umfang (m) | Kante Oberflächenbereich (m2) | Brutto-Oberflächenbereich der Deckenunterseite (m2) = Brutto-Oberflächenbereich der Deckenunterseite mit Löchern (m2) = Brutto-Oberfläche der Deckenoberseite (m2) = Brutto-Oberflächenbereich der Deckenoberseite mit Löchern (m2) | Brutto-Oberflächenbereich der Deckenkanten (m2) = Brutto-Oberflächenbereich der Deckenkanten mit Löchern (m2) | Component 1, Masse (kg)
Decke-014 | Decke-014 | Grundfläche Gebäude Nachgezogen; Loft; Obergeschoss; Wohnung2 OG | 1449.35 (kgCO₂) | 24155.8 | 49.5503 | 2.47751 | 2.49936 | 31.6476 | 0.478269 | 49.9871 | 1.58238 | 1610.38
Decke-008 | Decke-008 | Grundfläche Gebäude Nachgezogen; Obergeschoss; Wohnen; Wohnung1 OG | 901.462 (kgCO₂) | 15024.4 | 30.8192 | 1.54096 | 1.56012 | 24.2485 | 0.231762 | 31.2024 | 1.21243 | 1001.62

# IfcCovering: Belag, Parkett 50, Decke-008
In: EG
Type - PredefinedType: FLOORING
Classification: Fußbodenaufbau (ARCHICAD Klassifizierung); Material: Belag, Parkett
Pset_CoveringCommon - TotalThickness: 0.2 m; Material: Belag, Parkett
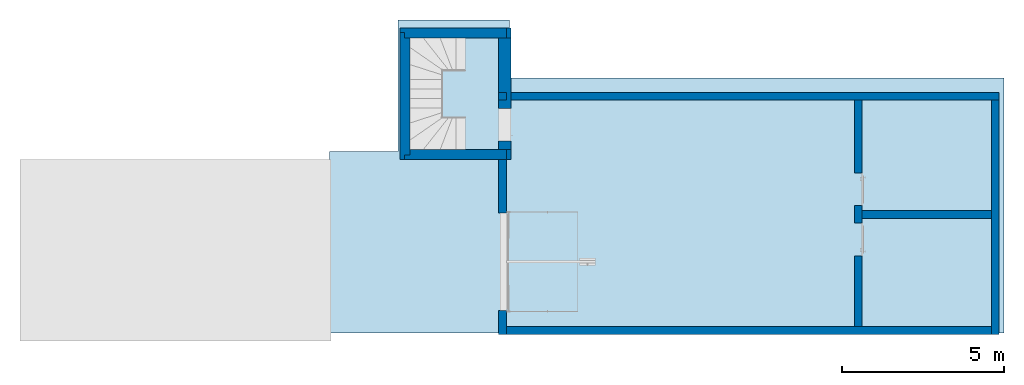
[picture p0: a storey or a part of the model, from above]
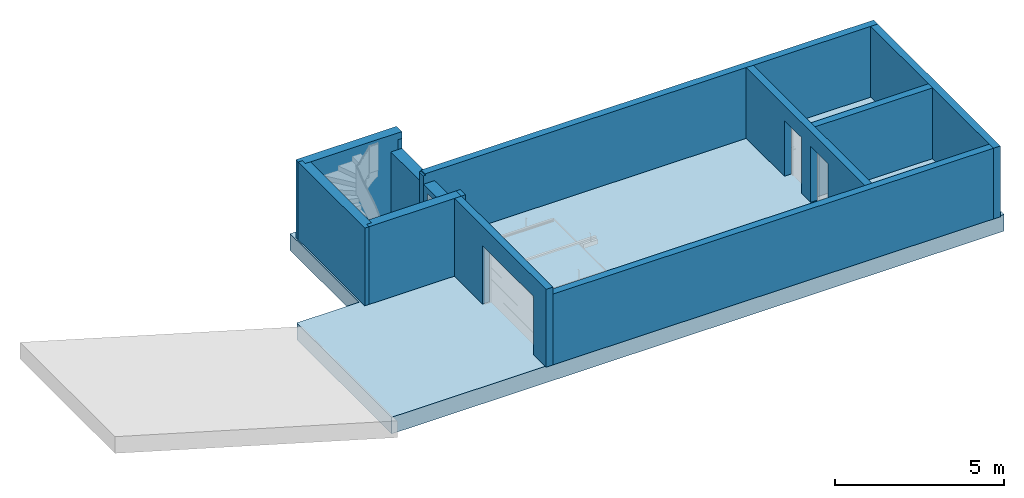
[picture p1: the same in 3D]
Properties of the parts of a building model (IFC4), part 11 of 13

# IfcCovering: Belag, Parkett 50, Decke-008
ArchiCADProperties - Element ID: Decke-008; Hotlink und Element-ID: Decke-008; Ebene: Decken Ausbau; Baustoff / Mehrschichtiger Aufbau / Profil / Schraffur: Belag, Parkett; Baustoff: Belag, Parkett; Kollidierende Räume: Erdgeschoss; Grundfläche Gebäude Nachgezogen; Wohnen; Wohnen; Wohnung2 EG; Geschützt: no; Ursprungsgeschoss Name: EG; Ursprungsgeschoss Nummer: 0; Typ: Decke; Struktur-Typ: Einfach; Überobjekt-ID: Decke-008; Baustoffe (Alle): Belag, Parkett; Oberfläche (Alle): Holz Parkett 2; Deckschraffur: Misch-Schraffur 25 %; Lage: Innen; Tragende Funktion: Nicht tragende Elemente; Anzeigen auf Umbau-Filter: Alle relevanten Filter; Umbau-Status: Bestand; Oberfläche unten: Holz Parkett 2; Oberfläche Kante: Holz Parkett 2; Lage der Referenzebene: Oben; Oberfläche oben: Holz Parkett 2; ARCHICAD Klassifizierung - 22: Fußbodenaufbau
Brandschutz 4102-2 - Kennbuchstabe: F
Component Properties - Component 1, Enthaltenes CO2: 1378.19 (kgCO₂); Component 1, Enthaltene Energie: 22969.8 MJ; Component 1, Komponenten-Typ: Keine
BaseQuantities - GrossArea: 47.1175 m2; NetArea: 47.1175 m2
ArchiCADQuantities - Fläche: 47.1175 m2; Höhe: 0.05 m; Netto-Volumen: 2.35587 m3; Höhenangabe zum Projekt-Nullpunkt: 0.2 m; Höhe zu 1. Referenzhöhe: 0.2 m; Höhe zu 2. Referenzhöhe: 0.2 m; Höhe zu Meereshöhe: 16.2 m; Höhe zu verknüpftem/Ursprungsgeschoss: 0.2 m; Abstand zu Ursprungsgeschoss: 0.2 m; Oberflächenbereich: 47.1175 m2; Dicke: 0.05 m; Konditionales Volumen: 2.35587 m3; Brutto-Volumen: 2.40451 m3; Grundriss-Umfang: 34.94 m; Grundriss-Durchbruch Umfang: 0 m; Höhenwert Unterkante: 0.15 m; Oberflächenbereich Unterseite: 47.1175 m2; Konditionaler Oberflächenbereich der Unterseite: 47.1175 m2; Konditionaler Oberflächenbereich der Oberseite: 47.1175 m2; Kante Oberflächenbereich: 0.77 m2; Brutto-Oberflächenbereich der Deckenunterseite: 48.0903 m2; Brutto-Oberflächenbereich der Deckenunterseite mit Löchern: 48.0903 m2; Brutto-Oberflächenbereich der Deckenkanten: 1.747 m2; Brutto-Oberflächenbereich der Deckenkanten mit Löchern: 1.747 m2; Brutto-Oberfläche der Deckenoberseite: 48.0903 m2; Brutto-Oberflächenbereich der Deckenoberseite mit Löchern: 48.0903 m2; Löcher Oberflächenbereich: 0 m2; Höhenwert Oberkante: 0.2 m; Oberflächenbereich Oberseite: 47.1175 m2
Component Quantities - Component 1, Masse: 1531.32 kg; Component 1, Schicht/Komponente Oberflächenbereich: 47.1175 m2; Component 1, Schichtdicke: 0.05 m; Component 1, Schicht/Komponente Volumen: 2.35587 m3

# IfcCovering: Dachrandabschluss 50 x 280 (12)
Type - PredefinedType: ROOFING
Classification: Dachdeckung (ARCHICAD Klassifizierung); Material: Metall, Stahl verzinkt
Pset_CoveringCommon - Material: Dachrandabschluss
ArchiCADProperties - Ebene: Dach; Baustoff / Mehrschichtiger Aufbau / Profil / Schraffur: Dachrandabschluss; Profil: Dachrandabschluss; Geschützt: no; Ursprungsgeschoss Name: 1. OG; Ursprungsgeschoss Nummer: 1; Typ: Unterzug; Struktur-Typ: Profil; Baustoffe (Alle): Metall, Stahl verzinkt; Lage: Außen; Tragende Funktion: Nicht tragende Elemente; Anzeigen auf Umbau-Filter: Alle relevanten Filter; Umbau-Status: Bestand; Unterzug Querschnitt: Profiliert; ARCHICAD Klassifizierung - 22: Dachdeckung
Brandschutz 4102-2 - Kennbuchstabe: F
Component Properties - Component 1, Komponenten-Typ: Kern
ArchiCADQuantities - Höhe: 0.28 m; Breite: 0.05 m; Anzahl Durchbruch: 0; Oberflächenbereich der Lochkanten: 0 m2; Löcher Oberflächenbereich: 0 m2; Durchbruch Volumen: 0 m3; Versatz: 0 m; Absatzhöhe: 0.27 m; Kopfplattenbreite: 0.04 m
Component Quantities - Component 1, Schicht/Komponente Querschnittsbereich: 0.0032 m2
Name | In | Element ID = Hotlink und Element-ID = Überobjekt-ID | Kollidierende Räume | Zugehöriger Raumname | Zugehörige Raumnummer | Oberfläche (Alle) | Neigungswinkel (deg) = Unterzug Neigungswinkel (deg) | Component 1, Enthaltenes CO2 | Component 1, Enthaltene Energie (MJ) | GrossArea (m2) = NetArea (m2) = Oberflächenbereich Unterseite (m2) | Fläche (m2) | Netto-Volumen (m3) = Konditionales Volumen (m3) = Component 1, Schicht/Komponente Volumen (m3) | Höhenangabe zum Projekt-Nullpunkt (m) = Höhe zu 1. Referenzhöhe (m) = Höhe zu 2. Referenzhöhe (m) | Höhe zu Meereshöhe (m) | Höhe zu verknüpftem/Ursprungsgeschoss (m) = Abstand zu Ursprungsgeschoss (m) | Oberflächenbereich (m2) | 3D-Länge (m) | Ende Oberflächenbereich (m2) | Linke Seite Oberflächenbereich (m2) | Länge Links (m) = Länge Rechts (m) | Rechet Seite Oberflächenbereich (m2) | Oberflächenbereich Oberseite (m2) | Component 1, Masse (kg)
Unterzug-010 | OG | Unterzug-010 | Dachterrasse; Grundfläche Gebäude Nachgezogen; Obergeschoss; Wohnung1 OG | Dachterrasse | R-001 | Metall Stahl, verzinkt; Beton, Sichtbeton 2 | 3.62894 | 82.114 (kgCO₂) | 1130.47 | 0.115933 | 0.118894 | 0.00721057 | 6.34844 | 22.3484 | 2.59844 | 1.49438 | 2.384 | 0.00382008 | 0.625751 | 2.38265 | 0.625751 | 0.119133 | 56.2424
Unterzug-007 | OG | Unterzug-007 | Dachterrasse; Grundfläche Gebäude Nachgezogen; Obergeschoss; Wohnung2 OG | Dachterrasse | R-001 | Metall Stahl, verzinkt | 0 | 80.0643 (kgCO₂) | 1102.25 | 0.109853 | 0.109853 | 0.00703058 | 4.55699 | 20.557 | 0.806991 | 1.45646 | 2.19706 | 0.0064 | 0.615176 | 2.19706 | 0.615176 | 0.109853 | 54.8386
Unterzug-010 | OG | Unterzug-010 | Dachterrasse; Grundfläche Gebäude Nachgezogen; Obergeschoss; Wohnung1 OG | Dachterrasse | R-001 | Metall Stahl, verzinkt; Beton, Sichtbeton 2 | 3.62353 | 82.2429 (kgCO₂) | 1132.25 | 0.116111 | 0.119072 | 0.00722189 | 6.34844 | 22.3484 | 2.59844 | 1.49671 | 2.38755 | 0.00382006 | 0.626741 | 2.3862 | 0.626741 | 0.11931 | 56.3308
Unterzug-010 | OG | Unterzug-010 | Grundfläche Gebäude Nachgezogen; Obergeschoss; Wohnung1 OG | Luftraum Dach | R-012 | Metall Stahl, verzinkt; Beton, Sichtbeton 2 | -3.41 | 40.3011 (kgCO₂) | 554.83 | 0.059611 | 0.0638529 | 0.00353891 | 6.17426 | 22.1743 | 2.42426 | 0.738056 | 1.29601 | 0.00341569 | 0.302816 | 1.27932 | 0.302816 | 0.0639662 | 27.6035
Unterzug-007 | OG | Unterzug-007 | Grundfläche Gebäude Nachgezogen; Obergeschoss; Wohnung1 OG | Luftraum Dach | R-012 | Metall Stahl, verzinkt | 0 | 86.3478 (kgCO₂) | 1188.76 | 0.119071 | 0.119071 | 0.00758235 | 6.09795 | 22.098 | 2.34795 | 1.57601 | 2.4 | 9.57218e-07 | 0.665608 | 2.3 | 0.66585 | 0.115 | 59.1423
Unterzug-010 | OG | Unterzug-010 | Grundfläche Gebäude Nachgezogen; Obergeschoss; Wohnung1 OG | Luftraum Dach | R-012 | Metall Stahl, verzinkt; Beton, Sichtbeton 2 | -3.41141 | 40.2914 (kgCO₂) | 554.697 | 0.059597 | 0.0638529 | 0.00353806 | 6.17406 | 22.1741 | 2.42406 | 0.737893 | 1.29602 | 0.00340609 | 0.302738 | 1.27933 | 0.302738 | 0.0639663 | 27.5969
Unterzug-002 | 1. OG | Unterzug-002 |  |  |  | Metall Stahl, verzinkt | -36.7598 | 132.488 (kgCO₂) | 1823.99 | 0.181175 | 0.145819 | 0.011634 | 6.73305 | 22.7331 | 2.98305 | 2.41025 | 3.8494 | 0.00618376 | 1.01923 | 3.64024 | 1.01704 | 0.182012 | 90.7455
Unterzug-007 | 1. OG | Unterzug-007 | Grundfläche Gebäude Nachgezogen | Dachterrasse | R-001 | Metall Stahl, verzinkt | 0 | 27.3645 (kgCO₂) | 376.73 | 0.0119687 | 0.0119686 | 0.00240292 | 6.5344 | 22.5344 | 2.7844 | 1.31038 | 3.2 | 0 | 0.642073 | 3.12 | 0 | 0 | 18.7428
Unterzug-002 | 1. OG | Unterzug-002 |  |  |  | Metall Stahl, verzinkt | -36.82 | 132.436 (kgCO₂) | 1823.27 | 0.181212 | 0.145502 | 0.0116295 | 6.73304 | 22.733 | 2.98304 | 2.40702 | 3.84475 | 0.00758558 | 1.01777 | 3.63513 | 1.01787 | 0.181756 | 90.7098
Unterzug-007 | 1. OG | Unterzug-007 | Grundfläche Gebäude Nachgezogen |  |  | Metall Stahl, verzinkt | 0 | 301.176 (kgCO₂) | 4146.32 | 0.413231 | 0.41323 | 0.0264468 | 4.55699 | 20.557 | 0.806991 | 5.46104 | 8.26461 | 0.0064 | 2.31409 | 8.26461 | 2.31409 | 0.413231 | 206.285
Unterzug-007 | R-001 | Unterzug-007 | Dachterrasse; Grundfläche Gebäude Nachgezogen | Dachterrasse | R-001 | Metall Stahl, verzinkt | 0 | 49.3302 (kgCO₂) | 679.135 | 0.067684 | 0.067684 | 0.00433177 | 4.55699 | 20.557 | 0.806991 | 0.899828 | 1.35368 | 0.0064 | 0.37903 | 1.35368 | 0.37903 | 0.067684 | 33.7878
Unterzug-007 | R-001 | Unterzug-007 | Dachterrasse; Grundfläche Gebäude Nachgezogen | Dachterrasse | R-001 | Metall Stahl, verzinkt | 0 | 48.5328 (kgCO₂) | 668.157 | 0.0665934 | 0.0665934 | 0.00426175 | 4.55699 | 20.557 | 0.806991 | 0.88539 | 1.33198 | 0.0032 | 0.372908 | 1.33202 | 0.372895 | 0.0665934 | 33.2416

# IfcCovering: Holz, Brettschichtholz 50 (3)
Type - PredefinedType: FLOORING
Classification: Fußbodenaufbau (ARCHICAD Klassifizierung); Material: Holz, Brettschichtholz
Pset_CoveringCommon - Material: Holz, Brettschichtholz
ArchiCADProperties - Element ID: Decke-008; Hotlink und Element-ID: Decke-008; Ebene: Decken Ausbau; Baustoff / Mehrschichtiger Aufbau / Profil / Schraffur: Holz, Brettschichtholz; Baustoff: Holz, Brettschichtholz; Geschützt: no; Typ: Decke; Struktur-Typ: Einfach; Überobjekt-ID: Decke-008; Baustoffe (Alle): Holz, Brettschichtholz; Oberfläche (Alle): Holz Brettschichtholz; Deckschraffur: Misch-Schraffur 25 %; Lage: Außen; Tragende Funktion: Nicht tragende Elemente; Anzeigen auf Umbau-Filter: Alle relevanten Filter; Umbau-Status: Bestand; Oberfläche unten: Holz Brettschichtholz; Oberfläche Kante: Holz Brettschichtholz; Lage der Referenzebene: Oben; Oberfläche oben: Holz Brettschichtholz; ARCHICAD Klassifizierung - 22: Fußbodenaufbau
Brandschutz 4102-2 - Kennbuchstabe: F
Component Properties - Component 1, Komponenten-Typ: Keine
ArchiCADQuantities - Höhe: 0.05 m; Dicke: 0.05 m; Grundriss-Durchbruch Umfang: 0 m; Löcher Oberflächenbereich: 0 m2
Component Quantities - Component 1, Schichtdicke: 0.05 m
Name | In | Kollidierende Räume | Ursprungsgeschoss Name | Ursprungsgeschoss Nummer | Component 1, Enthaltenes CO2 | Component 1, Enthaltene Energie (MJ) | GrossArea (m2) = NetArea (m2) = Fläche (m2) = Oberflächenbereich (m2) = Oberflächenbereich Unterseite (m2) = Konditionaler Oberflächenbereich der Unterseite (m2) = Konditionaler Oberflächenbereich der Oberseite (m2) = Oberflächenbereich Oberseite (m2) = Component 1, Schicht/Komponente Oberflächenbereich (m2) | Netto-Volumen (m3) = Konditionales Volumen (m3) = Component 1, Schicht/Komponente Volumen (m3) | Höhenangabe zum Projekt-Nullpunkt (m) = Höhe zu 1. Referenzhöhe (m) = Höhe zu 2. Referenzhöhe (m) = Höhenwert Oberkante (m) | Höhe zu Meereshöhe (m) | Höhe zu verknüpftem/Ursprungsgeschoss (m) = Abstand zu Ursprungsgeschoss (m) | Brutto-Volumen (m3) | Grundriss-Umfang (m) | Höhenwert Unterkante (m) | Kante Oberflächenbereich (m2) | Brutto-Oberflächenbereich der Deckenunterseite (m2) = Brutto-Oberflächenbereich der Deckenunterseite mit Löchern (m2) = Brutto-Oberfläche der Deckenoberseite (m2) = Brutto-Oberflächenbereich der Deckenoberseite mit Löchern (m2) | Brutto-Oberflächenbereich der Deckenkanten (m2) = Brutto-Oberflächenbereich der Deckenkanten mit Löchern (m2) | Component 1, Masse (kg) | TotalThickness (m)
Decke-008 | EG | Erdgeschoss; Grundfläche Gebäude Nachgezogen; Terrasse; Terrasse Wohnung2 EG; Wohnung2 EG | EG | 0 | 92.6517 (kgCO₂) | 2120.3 | 11.8784 | 0.593921 | 0.2 | 16.2 | 0.2 | 0.593921 | 15.82 | 0.15 | 0.791 | 11.8784 | 0.791 | 178.176
Decke-008 | EG | Erdgeschoss; Grundfläche Gebäude Nachgezogen; Terrasse; Terrasse Wohnung1 EG; Wohnung1 EG | EG | 0 | 232.71 (kgCO₂) | 5325.49 | 29.8347 | 1.49173 | 0.2 | 16.2 | 0.2 | 1.49191 | 22.8192 | 0.15 | 1.13121 | 29.8382 | 1.14096 | 447.52 | 0.2
Decke-008 | 1. OG | Dachterrasse; Grundfläche Gebäude Nachgezogen | 1. OG | 1 | 282.254 (kgCO₂) | 6459.28 | 36.1864 | 1.80932 | 3.9001 | 19.9001 | 0.150099 | 1.80932 | 24.2315 | 3.8501 | 1.21157 | 36.1864 | 1.21157 | 542.796 | 0.15

# IfcCovering: Verputz, Kalkzement 50 (7)
PredefinedType: CEILING; Classification: Abgehängte Decke (ARCHICAD Klassifizierung); Material: Verputz, Kalkzement
Pset_CoveringCommon - Material: Verputz, Kalkzement
ArchiCADProperties - Ebene: Decken Ausbau; Baustoff / Mehrschichtiger Aufbau / Profil / Schraffur: Verputz, Kalkzement; Baustoff: Verputz, Kalkzement; Geschützt: no; Typ: Decke; Struktur-Typ: Einfach; Baustoffe (Alle): Verputz, Kalkzement; Oberfläche (Alle): Verputz, glatt, weiß; Deckschraffur: Misch-Schraffur 25 %; Lage: Innen; Tragende Funktion: Nicht tragende Elemente; Anzeigen auf Umbau-Filter: Alle relevanten Filter; Umbau-Status: Bestand; Oberfläche unten: Verputz, glatt, weiß; Oberfläche Kante: Verputz, glatt, weiß; Oberfläche oben: Verputz, glatt, weiß; ARCHICAD Klassifizierung - 22: Abgehängte Decke
Brandschutz 4102-2 - Kennbuchstabe: F
Component Properties - Component 1, Komponenten-Typ: Keine
ArchiCADQuantities - Höhe: 0.05 m; Dicke: 0.05 m; Grundriss-Durchbruch Umfang: 0 m; Löcher Oberflächenbereich: 0 m2
Component Quantities - Component 1, Schichtdicke: 0.05 m
Name | In | TotalThickness (m) | Element ID = Hotlink und Element-ID = Überobjekt-ID | Kollidierende Räume | Ursprungsgeschoss Name | Ursprungsgeschoss Nummer | Lage der Referenzebene | Component 1, Enthaltenes CO2 | Component 1, Enthaltene Energie (MJ) | GrossArea (m2) = NetArea (m2) = Fläche (m2) = Oberflächenbereich (m2) = Oberflächenbereich Unterseite (m2) = Konditionaler Oberflächenbereich der Unterseite (m2) = Konditionaler Oberflächenbereich der Oberseite (m2) = Oberflächenbereich Oberseite (m2) = Component 1, Schicht/Komponente Oberflächenbereich (m2) | Netto-Volumen (m3) = Konditionales Volumen (m3) = Component 1, Schicht/Komponente Volumen (m3) | Höhenangabe zum Projekt-Nullpunkt (m) = Höhe zu 1. Referenzhöhe (m) = Höhe zu 2. Referenzhöhe (m) | Höhe zu Meereshöhe (m) | Höhe zu verknüpftem/Ursprungsgeschoss (m) = Abstand zu Ursprungsgeschoss (m) | Brutto-Volumen (m3) | Grundriss-Umfang (m) | Höhenwert Unterkante (m) | Kante Oberflächenbereich (m2) | Brutto-Oberflächenbereich der Deckenunterseite (m2) = Brutto-Oberflächenbereich der Deckenunterseite mit Löchern (m2) = Brutto-Oberfläche der Deckenoberseite (m2) = Brutto-Oberflächenbereich der Deckenoberseite mit Löchern (m2) | Brutto-Oberflächenbereich der Deckenkanten (m2) = Brutto-Oberflächenbereich der Deckenkanten mit Löchern (m2) | Höhenwert Oberkante (m) | Component 1, Masse (kg)
Decke-014 | EG | 0.35 | Decke-014 | Erdgeschoss; Grundfläche Gebäude Nachgezogen; Wohnen; Wohnung1 EG | EG | 0 | Unten | 704.704 (kgCO₂) | 4644.64 | 40.04 | 2.002 | 3.15 | 19.15 | 3.15 | 2.002 | 25.44 | 3.15 | 1.272 | 40.04 | 1.272 | 3.2 | 3203.2
Decke-008 | EG | 0.35 | Decke-008 | Erdgeschoss; Grundfläche Gebäude Nachgezogen; Wohnen; Wohnung2 EG | EG | 0 | Unten | 309.217 (kgCO₂) | 2038.02 | 17.5691 | 0.878456 | 3.15 | 19.15 | 3.15 | 0.878502 | 19.9008 | 3.15 | 0.87725 | 17.57 | 0.995038 | 3.2 | 1405.53
Decke-008 | EG | 0.35 | Decke-008 | Bad; Erdgeschoss; Grundfläche Gebäude Nachgezogen; Wohnung2 EG | EG | 0 | Unten | 47.52 (kgCO₂) | 313.2 | 2.7 | 0.135 | 3.15 | 19.15 | 3.15 | 0.135 | 6.6 | 3.15 | 0.33 | 2.7 | 0.33 | 3.2 | 216
Decke-014 | EG | 0.35 | Decke-014 | Erdgeschoss; Grundfläche Gebäude Nachgezogen; Wohnen; Wohnung2 EG | EG | 0 | Oben | 503.36 (kgCO₂) | 3317.6 | 28.6 | 1.43 | 3.2 | 19.2 | 3.2 | 1.43 | 21.44 | 3.15 | 1.072 | 28.6 | 1.072 | 3.2 | 2288
Decke-008 | EG | 0.35 | Decke-008 | Bad; Erdgeschoss; Grundfläche Gebäude Nachgezogen; Wohnung1 EG | EG | 0 | Unten | 47.52 (kgCO₂) | 313.2 | 2.7 | 0.135 | 3.15 | 19.15 | 3.15 | 0.135 | 6.6 | 3.15 | 0.33 | 2.7 | 0.33 | 3.2 | 216
Decke-008 | EG | 0.35 | Decke-008 | Erdgeschoss; Grundfläche Gebäude Nachgezogen; Wohnen; Wohnung1 EG | EG | 0 | Unten | 486.43 (kgCO₂) | 3206.02 | 27.6381 | 1.3819 | 3.15 | 19.15 | 3.15 | 1.38197 | 23.8985 | 3.15 | 0.969955 | 27.6393 | 1.19493 | 3.2 | 2211.05
Decke-014 | OG | 0.15 | Decke-014 | Grundfläche Gebäude Nachgezogen; Loft; Obergeschoss; Wohnung2 OG | 1. OG | 1 | Unten | 954.36 (kgCO₂) | 6290.1 | 54.225 | 2.71125 | 6.35 | 22.35 | 2.6 | 2.71125 | 31.69 | 6.35 | 1.5845 | 54.225 | 1.5845 | 6.4 | 4338

# IfcRailing: Geländerart (6)
Classification: Geländer (ARCHICAD Klassifizierung)
ArchiCADProperties - Ebene: Geländer; Geschützt: no; Typ: Geländer; Anzeigen auf Umbau-Filter: Alle relevanten Filter; Umbau-Status: Bestand; ARCHICAD Klassifizierung - 22: Geländer
ArchiCADQuantities - Höhe: 1 m; Anzahl der zweiten Handläufe: 0
Name | In | Material | Height (m) | Element ID = Hotlink und Element-ID = Überobjekt-ID | Kollidierende Räume | Zugehöriger Raumname | Zugehörige Raumnummer | Ursprungsgeschoss Name | Ursprungsgeschoss Nummer | Baustoffe (Alle) | Oberfläche (Alle) | Lage | Tragende Funktion | Component 1 in Geländer-Pfosten-001, Enthaltenes CO2 | Component 1 in Geländer-Pfosten-001, Enthaltene Energie (MJ) | Component 1 in Geländer-Handlauf-001, Enthaltenes CO2 | Component 1 in Geländer-Handlauf-001, Enthaltene Energie (MJ) | Component 1 in Geländer-Paneel-001, Enthaltenes CO2 | Component 1 in Geländer-Paneel-001, Enthaltene Energie (MJ) | GrossVolume (m3) = NetVolume (m3) = Netto-Volumen (m3) | Length (m) = 3D-Länge (m) | Fläche (m2) | Höhenangabe zum Projekt-Nullpunkt (m) = Höhe zu 1. Referenzhöhe (m) = Höhe zu 2. Referenzhöhe (m) | Höhe zu Meereshöhe (m) | Höhe zu verknüpftem/Ursprungsgeschoss (m) = Abstand zu Ursprungsgeschoss (m) | Anzahl der Geländerstäbe | Anzahl der Innenpfosten | Anzahl der Paneele | Anzahl der Pfosten | Anzahl der Gurte | Anzahl der oberen Handläufe | Referenzlinie Horizontale Länge (m) | Component 1 in Geländer-Pfosten-001, Masse (kg) | Component 1 in Geländer-Pfosten-001, Schicht/Komponente Volumen (m3) | Component 1 in Geländer-Handlauf-001, Masse (kg) | Component 1 in Geländer-Handlauf-001, Schicht/Komponente Volumen (m3) | Component 1 in Geländer-Paneel-001, Masse (kg) | Component 1 in Geländer-Paneel-001, Schicht/Komponente Volumen (m3)
Geländer-001 | R-010 | Metall, Stahl lackiert (9), Glas, Normalglas (4) | 1 | Geländer-001 | Erdgeschoss; Grundfläche Gebäude Nachgezogen; Treppenhaus; Treppenhaus; Treppenhaus UG | Treppenhaus | R-010 | -1. Geschoss | -1 | Glas, Normalglas; Metall, Stahl lackiert | Glas Normalglas; Metall Stahl, lackiert | Nicht definiert | Nicht definiert | 7.6869 (kgCO₂) | 105.826 | 6.29718 (kgCO₂) | 86.6941 | 0.257197 (kgCO₂) | 10.9309 | 0.0675242 | 3.98749 | 0.146116 | -2.8 | 13.2 | 0 | 0 | 0 | 4 | 5 | 0 | 5 | 2.88 | 5.265 | 0.000675 | 4.31314 | 0.000552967 | 12.8598 | 0.00584538
Geländer-003 | EG | Metall, Stahl lackiert (5), Glas, Normalglas (2) | 1 | Geländer-003 | Erdgeschoss; Grundfläche Gebäude Nachgezogen; Loft; Loft; Obergeschoss; Wohnen; Wohnen; Wohnung2 EG; Wohnung2 OG | Wohnen | R-009 | EG | 0 | Glas, Normalglas; Metall, Stahl lackiert | Glas Normalglas; Metall Stahl, lackiert | Nicht definiert | Nicht tragende Elemente | 7.6869 (kgCO₂) | 105.826 | 17.5778 (kgCO₂) | 241.996 | 1.12684 (kgCO₂) | 47.8907 | 0.0461696 | 4.3066 | 0.0951979 | 0.2 | 16.2 | 0.2 | 0 | 0 | 2 | 3 | 0 | 3 | 2.09962 | 5.265 | 0.000675 | 12.0396 | 0.00154354 | 56.342 | 0.02561
Geländer-004 | EG | Metall, Stahl lackiert (3), Glas, Normalglas | 1 | Geländer-004 | Erdgeschoss; Grundfläche Gebäude Nachgezogen; Treppenhaus | Treppenhaus | R-010 | EG | 0 | Glas, Normalglas; Metall, Stahl lackiert | Glas Normalglas; Metall Stahl, lackiert | Innen | Nicht tragende Elemente | 7.6869 (kgCO₂) | 105.826 | 18.756 (kgCO₂) | 258.217 | 2.11499 (kgCO₂) | 89.8872 | 0.051065 | 2.44 | 0.110475 | -0.3 | 15.7 | -0.3 | 0 | 0 | 1 | 2 | 0 | 1 | 2.44 | 5.265 | 0.000675 | 12.8466 | 0.001647 | 105.75 | 0.048068 | Pset_RailingCommon - IsExternal: no
Geländer-003 | EG | Metall, Stahl lackiert (5), Glas, Normalglas (2) | 1 | Geländer-003 | Erdgeschoss; Grundfläche Gebäude Nachgezogen; Luftraum Dach; Obergeschoss; Wohnen; Wohnen; Wohnen; Wohnung1 EG; Wohnung1 OG | Wohnen | R-006 | EG | 0 | Glas, Normalglas; Metall, Stahl lackiert | Glas Normalglas; Metall Stahl, lackiert | Nicht definiert | Nicht tragende Elemente | 7.6869 (kgCO₂) | 105.826 | 17.5778 (kgCO₂) | 241.996 | 1.12684 (kgCO₂) | 47.8907 | 0.0465414 | 4.3066 | 0.095206 | 0.2 | 16.2 | 0.2 | 0 | 0 | 2 | 3 | 0 | 3 | 2.09962 | 5.265 | 0.000675 | 12.0396 | 0.00154354 | 56.342 | 0.02561
Geländer-001 | OG | Metall, Stahl lackiert (68), Holz, Geländer (5), Metall, Aluminium (3), Metall, Edelstahl (4) | 1.15 | Geländer-001 | Balkon Wohnung2; Erdgeschoss; Grundfläche Gebäude Nachgezogen; Obergeschoss; Wohnung2 EG; Wohnung2 OG | Balkon Wohnung2 | R-023 | 1. OG | 1 | Metall, Aluminium; Metall, Edelstahl; Metall, Stahl lackiert; Holz, Geländer | Holz Eiche; Metall Aluminium, matt; Metall, Fassade Edelstahl; Metall Stahl, lackiert | Außen | Nicht tragende Elemente | 8.75538 (kgCO₂) | 120.536 | 0.540936 (kgCO₂) | 12.3791 |  |  | 0.0649121 | 5.46 | 0.282675 | 3.85 | 19.85 | 0.1 | 57 | 4 | 0 | 4 | 3 | 3 | 5.46 | 5.99683 | 0.000768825 | 1.04026 | 0.00346754 | Pset_RailingCommon - IsExternal: yes; PredefinedType: BALUSTRADE; Component Properties - Component 2 in Geländer-Handlauf-001, Enthaltenes CO2: 0.25648 (kgCO₂); Component 2 in Geländer-Handlauf-001, Enthaltene Energie: 4.34 MJ; Component 1 in Geländer-Gurt-001, Enthaltenes CO2: 12.6892 (kgCO₂); Component 1 in Geländer-Gurt-001, Enthaltene Energie: 174.693 MJ; Component 1 in Geländer-Innenpfosten-001, Enthaltenes CO2: 4.12973 (kgCO₂); Component 1 in Geländer-Innenpfosten-001, Enthaltene Energie: 38.074 MJ; Component 2 in Geländer-Innenpfosten-001, Enthaltenes CO2: 8.75538 (kgCO₂); Component 2 in Geländer-Innenpfosten-001, Enthaltene Energie: 120.536 MJ; Component, Enthaltenes CO2: 8.75538 (kgCO₂); Component, Enthaltene Energie: 120.536 MJ; Component Quantities - Component 2 in Geländer-Handlauf-001, Masse: 0.028 kg; Component 2 in Geländer-Handlauf-001, Schicht/Komponente Volumen: 0.00001 m3; Component 1 in Geländer-Gurt-001, Masse: 8.6912 kg; Component 1 in Geländer-Gurt-001, Schicht/Komponente Volumen: 0.00111426 m3; Component 1 in Geländer-Innenpfosten-001, Masse: 0.6715 kg; Component 1 in Geländer-Innenpfosten-001, Schicht/Komponente Volumen: 0.000085 m3; Component 2 in Geländer-Innenpfosten-001, Masse: 5.99683 kg; Component 2 in Geländer-Innenpfosten-001, Schicht/Komponente Volumen: 0.000768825 m3; Component, Masse: 5.99683 kg; Component, Schicht/Komponente Volumen: 0.000768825 m3
Geländer-001 | OG | Metall, Stahl lackiert (133), Holz, Geländer (4), Metall, Aluminium (2), Metall, Edelstahl (11) | 1.15 | Geländer-001 | Dachterrasse; Dachterrasse; Grundfläche Gebäude Nachgezogen; Obergeschoss; Wohnung2 OG | Dachterrasse | R-001 | 1. OG | 1 | Metall, Aluminium; Metall, Edelstahl; Metall, Stahl lackiert; Holz, Geländer | Holz Eiche; Metall Aluminium, matt; Metall, Fassade Edelstahl; Metall Stahl, lackiert | Außen | Nicht tragende Elemente | 8.75538 (kgCO₂) | 120.536 | 1.59035 (kgCO₂) | 36.3945 |  |  | 0.132571 | 12.0359 | 0.597969 | 4.05 | 20.05 | 0.3 | 117 | 11 | 0 | 3 | 2 | 2 | 12.0359 | 5.99683 | 0.000768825 | 3.05836 | 0.0101945 | Pset_RailingCommon - IsExternal: yes; PredefinedType: BALUSTRADE; Component Properties - Component 2 in Geländer-Handlauf-001, Enthaltenes CO2: 0.769682 (kgCO₂); Component 2 in Geländer-Handlauf-001, Enthaltene Energie: 13.0241 MJ; Component 1 in Geländer-Gurt-001, Enthaltenes CO2: 37.4326 (kgCO₂); Component 1 in Geländer-Gurt-001, Enthaltene Energie: 515.339 MJ; Component 1 in Geländer-Innenpfosten-001, Enthaltenes CO2: 4.12978 (kgCO₂); Component 1 in Geländer-Innenpfosten-001, Enthaltene Energie: 38.0746 MJ; Component 2 in Geländer-Innenpfosten-001, Enthaltenes CO2: 8.75538 (kgCO₂); Component 2 in Geländer-Innenpfosten-001, Enthaltene Energie: 120.536 MJ; Component, Enthaltenes CO2: 8.75538 (kgCO₂); Component, Enthaltene Energie: 120.536 MJ; Component Quantities - Component 2 in Geländer-Handlauf-001, Masse: 0.0840265 kg; Component 2 in Geländer-Handlauf-001, Schicht/Komponente Volumen: 0.0000300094 m3; Component 1 in Geländer-Gurt-001, Masse: 25.6388 kg; Component 1 in Geländer-Gurt-001, Schicht/Komponente Volumen: 0.00328702 m3; Component 1 in Geländer-Innenpfosten-001, Masse: 0.671509 kg; Component 1 in Geländer-Innenpfosten-001, Schicht/Komponente Volumen: 0.0000850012 m3; Component 2 in Geländer-Innenpfosten-001, Masse: 5.99683 kg; Component 2 in Geländer-Innenpfosten-001, Schicht/Komponente Volumen: 0.000768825 m3; Component, Masse: 5.99683 kg; Component, Schicht/Komponente Volumen: 0.000768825 m3

# IfcSlab: Beton, Stahlbeton C20/25 150, Decke-005
In: OG
Type - PredefinedType: FLOOR
Classification: Decke (ARCHICAD Klassifizierung); Material: Beton, Stahlbeton C20/25
ArchiCADProperties - Element ID: Decke-005; Hotlink und Element-ID: Decke-005; Ebene: Decken Roh; Baustoff / Mehrschichtiger Aufbau / Profil / Schraffur: Beton, Stahlbeton C20/25; Baustoff: Beton, Stahlbeton C20/25; Kollidierende Räume: Grundfläche Gebäude Nachgezogen; Obergeschoss; Wohnung2 OG; Geschützt: no; Ursprungsgeschoss Name: 1. OG; Ursprungsgeschoss Nummer: 1; Typ: Decke; Struktur-Typ: Einfach; Überobjekt-ID: Decke-005; Baustoffe (Alle): Beton, Stahlbeton C20/25; Oberfläche (Alle): Beton, Sichtbeton 2; Deckschraffur: Misch-Schraffur 25 %; Lage: Außen; Tragende Funktion: Tragende Elemente; Anzeigen auf Umbau-Filter: Alle relevanten Filter; Umbau-Status: Bestand; Oberfläche unten: Beton, Sichtbeton 2; Oberfläche Kante: Beton, Sichtbeton 2; Lage der Referenzebene: Unten; Oberfläche oben: Beton, Sichtbeton 2; ARCHICAD Klassifizierung - 22: Decke
Brandschutz 4102-2 - Kennbuchstabe: F
Pset_SlabCommon - LoadBearing: yes; IsExternal: yes
Component Properties - Component 1, Enthaltenes CO2: 2030.38 (kgCO₂); Component 1, Enthaltene Energie: 14015 MJ; Component 1, Komponenten-Typ: Keine
BaseQuantities - Width: 0.15 m; Perimeter: 33.0908 m; GrossArea: 59.8933 m2; NetArea: 59.8933 m2; GrossVolume: 8.98399 m3; NetVolume: 8.98399 m3
ArchiCADQuantities - Fläche: 59.8933 m2; Höhe: 0.15 m; Netto-Volumen: 8.98399 m3; Höhenangabe zum Projekt-Nullpunkt: 6.5 m; Höhe zu 1. Referenzhöhe: 6.5 m; Höhe zu 2. Referenzhöhe: 6.5 m; Höhe zu Meereshöhe: 22.5 m; Höhe zu verknüpftem/Ursprungsgeschoss: 2.75 m; Abstand zu Ursprungsgeschoss: 2.75 m; Oberflächenbereich: 59.8933 m2; Dicke: 0.15 m; Konditionales Volumen: 8.98399 m3; Brutto-Volumen: 8.9843 m3; Grundriss-Umfang: 33.0908 m; Grundriss-Durchbruch Umfang: 0 m; Höhenwert Unterkante: 6.5 m; Oberflächenbereich Unterseite: 59.8933 m2; Konditionaler Oberflächenbereich der Unterseite: 59.8933 m2; Konditionaler Oberflächenbereich der Oberseite: 59.8933 m2; Kante Oberflächenbereich: 4.161 m2; Brutto-Oberflächenbereich der Deckenunterseite: 59.8953 m2; Brutto-Oberflächenbereich der Deckenunterseite mit Löchern: 59.8953 m2; Brutto-Oberflächenbereich der Deckenkanten: 4.96362 m2; Brutto-Oberflächenbereich der Deckenkanten mit Löchern: 4.96362 m2; Brutto-Oberfläche der Deckenoberseite: 59.8953 m2; Brutto-Oberflächenbereich der Deckenoberseite mit Löchern: 59.8953 m2; Löcher Oberflächenbereich: 0 m2; Höhenwert Oberkante: 6.65 m; Oberflächenbereich Oberseite: 59.8933 m2
Component Quantities - Component 1, Masse: 17968 kg; Component 1, Schicht/Komponente Oberflächenbereich: 59.8933 m2; Component 1, Schichtdicke: 0.15 m; Component 1, Schicht/Komponente Volumen: 8.98399 m3

# IfcSlab: Beton, Stahlbeton C20/25 200, Decke-013
In: R-023
Type - PredefinedType: BASESLAB
Classification: Bodenplatte / Flachgründung (ARCHICAD Klassifizierung); Material: Beton, Stahlbeton C20/25
ArchiCADProperties - Element ID: Decke-013; Hotlink und Element-ID: Decke-013; Ebene: Decken Roh; Baustoff / Mehrschichtiger Aufbau / Profil / Schraffur: Beton, Stahlbeton C20/25; Baustoff: Beton, Stahlbeton C20/25; Kollidierende Räume: Gelände; Terrasse Wohnung2 EG; Geschützt: no; Ursprungsgeschoss Name: EG; Ursprungsgeschoss Nummer: 0; Typ: Decke; Struktur-Typ: Einfach; Überobjekt-ID: Decke-013; Baustoffe (Alle): Beton, Stahlbeton C20/25; Oberfläche (Alle): Beton, Sichtbeton 2; Deckschraffur: Misch-Schraffur 25 %; Lage: Außen; Tragende Funktion: Tragende Elemente; Anzeigen auf Umbau-Filter: Alle relevanten Filter; Umbau-Status: Bestand; Oberfläche unten: Beton, Sichtbeton 2; Oberfläche Kante: Beton, Sichtbeton 2; Lage der Referenzebene: Oben; Oberfläche oben: Beton, Sichtbeton 2; ARCHICAD Klassifizierung - 22: Bodenplatte / Flachgründung
Pset_SlabCommon - LoadBearing: yes; IsExternal: yes
Component Properties - Component 1, Enthaltenes CO2: 536.905 (kgCO₂); Component 1, Enthaltene Energie: 3706.07 MJ; Component 1, Komponenten-Typ: Keine
BaseQuantities - Width: 0.2 m; Perimeter: 15.82 m; GrossArea: 11.8784 m2; NetArea: 11.8784 m2; GrossVolume: 2.37568 m3; NetVolume: 2.37568 m3
ArchiCADQuantities - Fläche: 11.8784 m2; Höhe: 0.2 m; Netto-Volumen: 2.37568 m3; Höhenangabe zum Projekt-Nullpunkt: 0 m; Höhe zu 1. Referenzhöhe: 0 m; Höhe zu 2. Referenzhöhe: 0 m; Höhe zu Meereshöhe: 16 m; Höhe zu verknüpftem/Ursprungsgeschoss: 0 m; Abstand zu Ursprungsgeschoss: 0 m; Oberflächenbereich: 11.8784 m2; Dicke: 0.2 m; Konditionales Volumen: 2.37568 m3; Brutto-Volumen: 2.37568 m3; Grundriss-Umfang: 15.82 m; Grundriss-Durchbruch Umfang: 0 m; Höhenwert Unterkante: -0.2 m; Oberflächenbereich Unterseite: 11.8784 m2; Konditionaler Oberflächenbereich der Unterseite: 11.8784 m2; Konditionaler Oberflächenbereich der Oberseite: 11.8784 m2; Kante Oberflächenbereich: 3.164 m2; Brutto-Oberflächenbereich der Deckenunterseite: 11.8784 m2; Brutto-Oberflächenbereich der Deckenunterseite mit Löchern: 11.8784 m2; Brutto-Oberflächenbereich der Deckenkanten: 3.164 m2; Brutto-Oberflächenbereich der Deckenkanten mit Löchern: 3.164 m2; Brutto-Oberfläche der Deckenoberseite: 11.8784 m2; Brutto-Oberflächenbereich der Deckenoberseite mit Löchern: 11.8784 m2; Löcher Oberflächenbereich: 0 m2; Höhenwert Oberkante: 0 m; Oberflächenbereich Oberseite: 11.8784 m2
Component Quantities - Component 1, Masse: 4751.37 kg; Component 1, Schicht/Komponente Oberflächenbereich: 11.8784 m2; Component 1, Schichtdicke: 0.2 m; Component 1, Schicht/Komponente Volumen: 2.37568 m3

# IfcSlab: Beton, Stahlbeton C20/25 250, Decke-012
In: EG
Type - PredefinedType: BASESLAB
Classification: Bodenplatte / Flachgründung (ARCHICAD Klassifizierung); Material: Beton, Stahlbeton C20/25
ArchiCADProperties - Element ID: Decke-012; Hotlink und Element-ID: Decke-012; Ebene: Decken Roh; Baustoff / Mehrschichtiger Aufbau / Profil / Schraffur: Beton, Stahlbeton C20/25; Baustoff: Beton, Stahlbeton C20/25; Kollidierende Räume: Untergeschoss UG; Geschützt: no; Ursprungsgeschoss Name: EG; Ursprungsgeschoss Nummer: 0; Typ: Decke; Struktur-Typ: Einfach; Überobjekt-ID: Decke-012; Baustoffe (Alle): Beton, Stahlbeton C20/25; Oberfläche (Alle): Beton, Sichtbeton 2; Deckschraffur: Misch-Schraffur 25 %; Lage: Nicht definiert; Tragende Funktion: Tragende Elemente; Anzeigen auf Umbau-Filter: Alle relevanten Filter; Umbau-Status: Bestand; Oberfläche unten: Beton, Sichtbeton 2; Oberfläche Kante: Beton, Sichtbeton 2; Lage der Referenzebene: Oben; Oberfläche oben: Beton, Sichtbeton 2; ARCHICAD Klassifizierung - 22: Bodenplatte / Flachgründung
Pset_SlabCommon - LoadBearing: yes
Component Properties - Component 1, Enthaltenes CO2: 3175.14 (kgCO₂); Component 1, Enthaltene Energie: 21916.9 MJ; Component 1, Komponenten-Typ: Keine
BaseQuantities - Width: 0.25 m; Perimeter: 36.7788 m; GrossArea: 56.0729 m2; NetArea: 56.0729 m2; GrossVolume: 14.0493 m3; NetVolume: 14.0493 m3
ArchiCADQuantities - Fläche: 56.6939 m2; Höhe: 0.25 m; Netto-Volumen: 14.0493 m3; Höhenangabe zum Projekt-Nullpunkt: 0 m; Höhe zu 1. Referenzhöhe: 0 m; Höhe zu 2. Referenzhöhe: 0 m; Höhe zu Meereshöhe: 16 m; Höhe zu verknüpftem/Ursprungsgeschoss: 0 m; Abstand zu Ursprungsgeschoss: 0 m; Oberflächenbereich: 56.6939 m2; Dicke: 0.25 m; Konditionales Volumen: 14.0493 m3; Brutto-Volumen: 14.1983 m3; Grundriss-Umfang: 36.7788 m; Grundriss-Durchbruch Umfang: 0 m; Höhenwert Unterkante: -0.25 m; Oberflächenbereich Unterseite: 56.0729 m2; Konditionaler Oberflächenbereich der Unterseite: 56.0729 m2; Konditionaler Oberflächenbereich der Oberseite: 56.6939 m2; Kante Oberflächenbereich: 7.92356 m2; Brutto-Oberflächenbereich der Deckenunterseite: 56.7932 m2; Brutto-Oberflächenbereich der Deckenunterseite mit Löchern: 56.7932 m2; Brutto-Oberflächenbereich der Deckenkanten: 9.19469 m2; Brutto-Oberflächenbereich der Deckenkanten mit Löchern: 9.19469 m2; Brutto-Oberfläche der Deckenoberseite: 56.7932 m2; Brutto-Oberflächenbereich der Deckenoberseite mit Löchern: 56.7932 m2; Löcher Oberflächenbereich: 0 m2; Höhenwert Oberkante: 0 m; Oberflächenbereich Oberseite: 56.6939 m2
Component Quantities - Component 1, Masse: 28098.6 kg; Component 1, Schicht/Komponente Oberflächenbereich: 56.6939 m2; Component 1, Schichtdicke: 0.25 m; Component 1, Schicht/Komponente Volumen: 14.0493 m3

# IfcSlab: Beton, Stahlbeton C20/25 250 (3)
Type - PredefinedType: FLOOR
Classification: Decke (ARCHICAD Klassifizierung); Material: Beton, Stahlbeton C20/25
ArchiCADProperties - Ebene: Decken Roh; Baustoff / Mehrschichtiger Aufbau / Profil / Schraffur: Beton, Stahlbeton C20/25; Baustoff: Beton, Stahlbeton C20/25; Geschützt: no; Typ: Decke; Struktur-Typ: Einfach; Baustoffe (Alle): Beton, Stahlbeton C20/25; Oberfläche (Alle): Beton, Sichtbeton 2; Deckschraffur: Misch-Schraffur 25 %; Tragende Funktion: Tragende Elemente; Anzeigen auf Umbau-Filter: Alle relevanten Filter; Umbau-Status: Bestand; Oberfläche unten: Beton, Sichtbeton 2; Oberfläche Kante: Beton, Sichtbeton 2; Lage der Referenzebene: Oben; Oberfläche oben: Beton, Sichtbeton 2; ARCHICAD Klassifizierung - 22: Decke
Brandschutz 4102-2 - Kennbuchstabe: F
Pset_SlabCommon - LoadBearing: yes
Component Properties - Component 1, Komponenten-Typ: Keine
BaseQuantities - Width: 0.25 m
ArchiCADQuantities - Höhe: 0.25 m; Höhe zu verknüpftem/Ursprungsgeschoss: 0 m; Abstand zu Ursprungsgeschoss: 0 m; Dicke: 0.25 m; Grundriss-Durchbruch Umfang: 0 m; Löcher Oberflächenbereich: 0 m2
Component Quantities - Component 1, Schichtdicke: 0.25 m
Name | In | Element ID = Hotlink und Element-ID = Überobjekt-ID | Kollidierende Räume | Ursprungsgeschoss Name | Ursprungsgeschoss Nummer | Lage | Component 1, Enthaltenes CO2 | Component 1, Enthaltene Energie (MJ) | Perimeter (m) = Grundriss-Umfang (m) | GrossArea (m2) = NetArea (m2) = Oberflächenbereich Unterseite (m2) = Konditionaler Oberflächenbereich der Unterseite (m2) | GrossVolume (m3) = NetVolume (m3) = Netto-Volumen (m3) = Konditionales Volumen (m3) = Component 1, Schicht/Komponente Volumen (m3) | Fläche (m2) = Oberflächenbereich (m2) = Konditionaler Oberflächenbereich der Oberseite (m2) = Oberflächenbereich Oberseite (m2) = Component 1, Schicht/Komponente Oberflächenbereich (m2) | Höhenangabe zum Projekt-Nullpunkt (m) = Höhe zu 1. Referenzhöhe (m) = Höhe zu 2. Referenzhöhe (m) = Höhenwert Oberkante (m) | Höhe zu Meereshöhe (m) | Brutto-Volumen (m3) | Höhenwert Unterkante (m) | Kante Oberflächenbereich (m2) | Brutto-Oberflächenbereich der Deckenunterseite (m2) = Brutto-Oberflächenbereich der Deckenunterseite mit Löchern (m2) = Brutto-Oberfläche der Deckenoberseite (m2) = Brutto-Oberflächenbereich der Deckenoberseite mit Löchern (m2) | Brutto-Oberflächenbereich der Deckenkanten (m2) = Brutto-Oberflächenbereich der Deckenkanten mit Löchern (m2) | Component 1, Masse (kg)
Decke-012 | EG | Decke-012 | Gelände; Tiefgaragenabfahrt; Untergeschoss UG | EG | 0 | Nicht definiert | 6225.14 (kgCO₂) | 42970 | 49.478 | 110.12 | 27.5449 | 110.418 | 0 | 16 | 27.8658 | -0.25 | 10.4761 | 111.463 | 12.3695 | 55089.7
Decke-005 | 1. OG | Decke-005 | Erdgeschoss; Grundfläche Gebäude Nachgezogen; Wohnung1 EG | 1. OG | 1 | Nicht definiert | 4377.19 (kgCO₂) | 30214.2 | 37.09 | 77.4724 | 19.3681 | 77.4724 | 3.75 | 19.75 | 19.3765 | 3.5 | 7.39106 | 77.5059 | 9.2725 | 38736.2
Decke-005 | 1. OG | Decke-005 | Erdgeschoss; Grundfläche Gebäude Nachgezogen; Wohnung2 EG | 1. OG | 1 | Innen | 3102.68 (kgCO₂) | 21416.7 | 33.0908 | 54.9147 | 13.7287 | 54.9147 | 3.75 | 19.75 | 13.7292 | 3.5 | 6.935 | 54.9167 | 8.27269 | 27457.3 | Pset_SlabCommon - IsExternal: no

# IfcSlab: Beton, Stahlbeton C20/25 250 (2)
In: EG
Type - PredefinedType: LANDING
Classification: Treppen Podest (ARCHICAD Klassifizierung); Material: Beton, Stahlbeton C20/25
ArchiCADProperties - Element ID: Decke-007; Hotlink und Element-ID: Decke-007; Ebene: Decken Roh; Baustoff / Mehrschichtiger Aufbau / Profil / Schraffur: Beton, Stahlbeton C20/25; Baustoff: Beton, Stahlbeton C20/25; Kollidierende Räume: Untergeschoss UG; Geschützt: no; Ursprungsgeschoss Name: EG; Ursprungsgeschoss Nummer: 0; Typ: Decke; Struktur-Typ: Einfach; Überobjekt-ID: Decke-007; Baustoffe (Alle): Beton, Stahlbeton C20/25; Oberfläche (Alle): Beton, Sichtbeton 2; Deckschraffur: Misch-Schraffur 25 %; Tragende Funktion: Tragende Elemente; Anzeigen auf Umbau-Filter: Alle relevanten Filter; Umbau-Status: Bestand; Oberfläche unten: Beton, Sichtbeton 2; Oberfläche Kante: Beton, Sichtbeton 2; Lage der Referenzebene: Oben; Oberfläche oben: Beton, Sichtbeton 2; ARCHICAD Klassifizierung - 22: Treppen Podest
Pset_SlabCommon - LoadBearing: yes
Component Properties - Component 1, Komponenten-Typ: Keine
BaseQuantities - Width: 0.25 m
ArchiCADQuantities - Höhe: 0.25 m; Höhenangabe zum Projekt-Nullpunkt: -0.05 m; Höhe zu 1. Referenzhöhe: -0.05 m; Höhe zu 2. Referenzhöhe: -0.05 m; Höhe zu Meereshöhe: 15.95 m; Höhe zu verknüpftem/Ursprungsgeschoss: -0.05 m; Abstand zu Ursprungsgeschoss: -0.05 m; Dicke: 0.25 m; Grundriss-Durchbruch Umfang: 0 m; Höhenwert Unterkante: -0.3 m; Löcher Oberflächenbereich: 0 m2; Höhenwert Oberkante: -0.05 m
Component Quantities - Component 1, Schichtdicke: 0.25 m
Name | Lage | IsExternal | Component 1, Enthaltenes CO2 | Component 1, Enthaltene Energie (MJ) | Perimeter (m) = Grundriss-Umfang (m) | GrossArea (m2) = NetArea (m2) = Oberflächenbereich Unterseite (m2) = Konditionaler Oberflächenbereich der Unterseite (m2) | GrossVolume (m3) = NetVolume (m3) = Netto-Volumen (m3) = Konditionales Volumen (m3) = Component 1, Schicht/Komponente Volumen (m3) | Fläche (m2) = Oberflächenbereich (m2) = Konditionaler Oberflächenbereich der Oberseite (m2) = Oberflächenbereich Oberseite (m2) = Component 1, Schicht/Komponente Oberflächenbereich (m2) | Brutto-Volumen (m3) | Kante Oberflächenbereich (m2) | Brutto-Oberflächenbereich der Deckenunterseite (m2) = Brutto-Oberflächenbereich der Deckenunterseite mit Löchern (m2) = Brutto-Oberfläche der Deckenoberseite (m2) = Brutto-Oberflächenbereich der Deckenoberseite mit Löchern (m2) | Brutto-Oberflächenbereich der Deckenkanten (m2) = Brutto-Oberflächenbereich der Deckenkanten mit Löchern (m2) | Component 1, Masse (kg)
Decke-007 | Innen | no | 33.669 (kgCO₂) | 232.405 | 7.42876 | 0.595911 | 0.148978 | 0.595911 | 0.162759 | 1.65594 | 0.651036 | 1.85719 | 297.956
Decke-007 | Außen | yes | 51.5927 (kgCO₂) | 356.127 | 11.0767 | 0.891013 | 0.228286 | 0.918678 | 0.243468 | 2.474 | 0.973871 | 2.76917 | 456.573

# IfcSlab: Beton, Stahlbeton C20/25 300 (2)
In: EG
Type - PredefinedType: FLOOR
Classification: Decke (ARCHICAD Klassifizierung); Material: Beton, Stahlbeton C20/25
ArchiCADProperties - Ebene: Decken Roh; Baustoff / Mehrschichtiger Aufbau / Profil / Schraffur: Beton, Stahlbeton C20/25; Baustoff: Beton, Stahlbeton C20/25; Geschützt: no; Ursprungsgeschoss Name: EG; Ursprungsgeschoss Nummer: 0; Typ: Decke; Struktur-Typ: Einfach; Baustoffe (Alle): Beton, Stahlbeton C20/25; Oberfläche (Alle): Beton, Sichtbeton 2; Deckschraffur: Misch-Schraffur 25 %; Tragende Funktion: Tragende Elemente; Anzeigen auf Umbau-Filter: Alle relevanten Filter; Umbau-Status: Bestand; Oberfläche unten: Beton, Sichtbeton 2; Oberfläche Kante: Beton, Sichtbeton 2; Oberfläche oben: Beton, Sichtbeton 2; ARCHICAD Klassifizierung - 22: Decke
Brandschutz 4102-2 - Kennbuchstabe: F
Pset_SlabCommon - LoadBearing: yes
Component Properties - Component 1, Komponenten-Typ: Keine
BaseQuantities - Width: 0.3 m
ArchiCADQuantities - Höhe: 0.3 m; Dicke: 0.3 m; Grundriss-Durchbruch Umfang: 0 m; Löcher Oberflächenbereich: 0 m2
Component Quantities - Component 1, Schichtdicke: 0.3 m
Name | Element ID = Hotlink und Element-ID = Überobjekt-ID | Kollidierende Räume | Lage | Lage der Referenzebene | IsExternal | Component 1, Enthaltenes CO2 | Component 1, Enthaltene Energie (MJ) | Perimeter (m) = Grundriss-Umfang (m) | GrossArea (m2) = NetArea (m2) = Fläche (m2) = Oberflächenbereich (m2) = Oberflächenbereich Unterseite (m2) = Konditionaler Oberflächenbereich der Unterseite (m2) = Konditionaler Oberflächenbereich der Oberseite (m2) = Oberflächenbereich Oberseite (m2) = Component 1, Schicht/Komponente Oberflächenbereich (m2) | GrossVolume (m3) = NetVolume (m3) = Netto-Volumen (m3) = Konditionales Volumen (m3) = Component 1, Schicht/Komponente Volumen (m3) | Höhenangabe zum Projekt-Nullpunkt (m) = Höhe zu 1. Referenzhöhe (m) = Höhe zu 2. Referenzhöhe (m) = Höhe zu verknüpftem/Ursprungsgeschoss (m) = Abstand zu Ursprungsgeschoss (m) | Höhe zu Meereshöhe (m) | Brutto-Volumen (m3) | Höhenwert Unterkante (m) | Kante Oberflächenbereich (m2) | Brutto-Oberflächenbereich der Deckenunterseite (m2) = Brutto-Oberflächenbereich der Deckenunterseite mit Löchern (m2) = Brutto-Oberfläche der Deckenoberseite (m2) = Brutto-Oberflächenbereich der Deckenoberseite mit Löchern (m2) | Brutto-Oberflächenbereich der Deckenkanten (m2) = Brutto-Oberflächenbereich der Deckenkanten mit Löchern (m2) | Höhenwert Oberkante (m) | Component 1, Masse (kg)
Decke-010 | Decke-010 | Erdgeschoss; Grundfläche Gebäude Nachgezogen; Wohnung1 EG; Wohnung2 EG | Außen | Unten | yes | 810.814 (kgCO₂) | 5596.77 | 13.8908 | 11.9589 | 3.58767 | 3.3 | 19.3 | 3.58767 | 3.3 | 4.16723 | 11.9589 | 4.16723 | 3.6 | 7175.34
Decke-006 | Decke-006 | Untergeschoss UG | Innen | Oben | no | 828.121 (kgCO₂) | 5716.24 | 19.0979 | 12.2142 | 3.66425 | -0.3 | 15.7 | 3.82857 | -0.6 | 4.71214 | 12.7619 | 5.72937 | -0.3 | 7328.51

# IfcSlab: Beton, Stahlbeton C20/25 600, Decke-001
In: -1. Geschoss
Type - PredefinedType: BASESLAB
Classification: Bodenplatte / Flachgründung (ARCHICAD Klassifizierung); Material: Beton, Stahlbeton C20/25
ArchiCADProperties - Element ID: Decke-001; Hotlink und Element-ID: Decke-001; Ebene: Decken Roh; Baustoff / Mehrschichtiger Aufbau / Profil / Schraffur: Beton, Stahlbeton C20/25; Baustoff: Beton, Stahlbeton C20/25; Geschützt: no; Ursprungsgeschoss Name: -1. Geschoss; Ursprungsgeschoss Nummer: -1; Typ: Decke; Struktur-Typ: Einfach; Überobjekt-ID: Decke-001; Baustoffe (Alle): Beton, Stahlbeton C20/25; Oberfläche (Alle): Beton, Sichtbeton 2; Deckschraffur: Misch-Schraffur 25 %; Lage: Außen; Tragende Funktion: Tragende Elemente; Anzeigen auf Umbau-Filter: Alle relevanten Filter; Umbau-Status: Bestand; Oberfläche unten: Beton, Sichtbeton 2; Oberfläche Kante: Beton, Sichtbeton 2; Lage der Referenzebene: Oben; Oberfläche oben: Beton, Sichtbeton 2; ARCHICAD Klassifizierung - 22: Bodenplatte / Flachgründung
Pset_SlabCommon - LoadBearing: yes; IsExternal: yes
Component Properties - Component 1, Enthaltenes CO2: 22470 (kgCO₂); Component 1, Enthaltene Energie: 155103 MJ; Component 1, Komponenten-Typ: Keine
BaseQuantities - Width: 0.6 m; Perimeter: 61.07 m; GrossArea: 165.708 m2; NetArea: 165.708 m2; GrossVolume: 99.4249 m3; NetVolume: 99.4249 m3
ArchiCADQuantities - Fläche: 165.708 m2; Höhe: 0.6 m; Netto-Volumen: 99.4249 m3; Höhenangabe zum Projekt-Nullpunkt: -2.8 m; Höhe zu 1. Referenzhöhe: -2.8 m; Höhe zu 2. Referenzhöhe: -2.8 m; Höhe zu Meereshöhe: 13.2 m; Höhe zu verknüpftem/Ursprungsgeschoss: 0 m; Abstand zu Ursprungsgeschoss: 0 m; Oberflächenbereich: 165.708 m2; Dicke: 0.6 m; Konditionales Volumen: 99.4249 m3; Brutto-Volumen: 99.4249 m3; Grundriss-Umfang: 61.07 m; Grundriss-Durchbruch Umfang: 0 m; Höhenwert Unterkante: -3.4 m; Oberflächenbereich Unterseite: 165.708 m2; Konditionaler Oberflächenbereich der Unterseite: 165.708 m2; Konditionaler Oberflächenbereich der Oberseite: 165.708 m2; Kante Oberflächenbereich: 36.642 m2; Brutto-Oberflächenbereich der Deckenunterseite: 165.708 m2; Brutto-Oberflächenbereich der Deckenunterseite mit Löchern: 165.708 m2; Brutto-Oberflächenbereich der Deckenkanten: 36.642 m2; Brutto-Oberflächenbereich der Deckenkanten mit Löchern: 36.642 m2; Brutto-Oberfläche der Deckenoberseite: 165.708 m2; Brutto-Oberflächenbereich der Deckenoberseite mit Löchern: 165.708 m2; Löcher Oberflächenbereich: 0 m2; Höhenwert Oberkante: -2.8 m; Oberflächenbereich Oberseite: 165.708 m2
Component Quantities - Component 1, Masse: 198850 kg; Component 1, Schicht/Komponente Oberflächenbereich: 165.708 m2; Component 1, Schichtdicke: 0.6 m; Component 1, Schicht/Komponente Volumen: 99.4249 m3

# IfcSlab: Beton, Stahlbeton Fertigteil 150, Decke-017
In: R-023
Type - PredefinedType: FLOOR
Classification: Decke (ARCHICAD Klassifizierung); Material: Beton, Stahlbeton Fertigteil
ArchiCADProperties - Element ID: Decke-017; Hotlink und Element-ID: Decke-017; Ebene: Decken Roh; Baustoff / Mehrschichtiger Aufbau / Profil / Schraffur: Beton, Stahlbeton Fertigteil; Baustoff: Beton, Stahlbeton Fertigteil; Kollidierende Räume: Balkon Wohnung2; Erdgeschoss; Grundfläche Gebäude Nachgezogen; Wohnung2 EG; Geschützt: no; Ursprungsgeschoss Name: 1. OG; Ursprungsgeschoss Nummer: 1; Typ: Decke; Struktur-Typ: Einfach; Überobjekt-ID: Decke-017; Baustoffe (Alle): Beton, Stahlbeton Fertigteil; Oberfläche (Alle): Beton, Sichtbeton 2; Deckschraffur: Misch-Schraffur 25 %; Lage: Nicht definiert; Tragende Funktion: Nicht definiert; Anzeigen auf Umbau-Filter: Alle relevanten Filter; Umbau-Status: Bestand; Oberfläche unten: Beton, Sichtbeton 2; Oberfläche Kante: Beton, Sichtbeton 2; Lage der Referenzebene: Unten; Oberfläche oben: Beton, Sichtbeton 2; ARCHICAD Klassifizierung - 22: Decke
Brandschutz 4102-2 - Kennbuchstabe: F
Component Properties - Component 1, Enthaltenes CO2: 101.115 (kgCO₂); Component 1, Enthaltene Energie: 699.3 MJ; Component 1, Komponenten-Typ: Keine
BaseQuantities - Width: 0.15 m; Perimeter: 7.5 m; GrossArea: 3.5 m2; NetArea: 3.5 m2; GrossVolume: 0.525 m3; NetVolume: 0.525 m3
ArchiCADQuantities - Fläche: 3.5 m2; Höhe: 0.15 m; Netto-Volumen: 0.525 m3; Höhenangabe zum Projekt-Nullpunkt: 3.6 m; Höhe zu 1. Referenzhöhe: 3.6 m; Höhe zu 2. Referenzhöhe: 3.6 m; Höhe zu Meereshöhe: 19.6 m; Höhe zu verknüpftem/Ursprungsgeschoss: -0.15 m; Abstand zu Ursprungsgeschoss: -0.15 m; Oberflächenbereich: 3.5 m2; Dicke: 0.15 m; Konditionales Volumen: 0.525 m3; Brutto-Volumen: 0.525 m3; Grundriss-Umfang: 7.5 m; Grundriss-Durchbruch Umfang: 0 m; Höhenwert Unterkante: 3.6 m; Oberflächenbereich Unterseite: 3.5 m2; Konditionaler Oberflächenbereich der Unterseite: 3.5 m2; Konditionaler Oberflächenbereich der Oberseite: 3.5 m2; Kante Oberflächenbereich: 1.125 m2; Brutto-Oberflächenbereich der Deckenunterseite: 3.5 m2; Brutto-Oberflächenbereich der Deckenunterseite mit Löchern: 3.5 m2; Brutto-Oberflächenbereich der Deckenkanten: 1.125 m2; Brutto-Oberflächenbereich der Deckenkanten mit Löchern: 1.125 m2; Brutto-Oberfläche der Deckenoberseite: 3.5 m2; Brutto-Oberflächenbereich der Deckenoberseite mit Löchern: 3.5 m2; Löcher Oberflächenbereich: 0 m2; Höhenwert Oberkante: 3.75 m; Oberflächenbereich Oberseite: 3.5 m2
Component Quantities - Component 1, Masse: 945 kg; Component 1, Schicht/Komponente Oberflächenbereich: 3.5 m2; Component 1, Schichtdicke: 0.15 m; Component 1, Schicht/Komponente Volumen: 0.525 m3

# IfcSlab: DA | Komplett Stehfalz-Kopie 130 (4)
In: OG
Type - PredefinedType: ROOF
Classification: Dach (ARCHICAD Klassifizierung); Material: Dach, Stehfalz, Dämmung, hart Mineralwolle, Holz, Bauholz
ArchiCADProperties - Ebene: Dach; Baustoff / Mehrschichtiger Aufbau / Profil / Schraffur: DA | Komplett Stehfalz-Kopie; Mehrschichtige Bauteile: DA | Komplett Stehfalz-Kopie; Zugehöriger Raumname: Luftraum Dach; Zugehörige Raumnummer: R-012; Geschützt: no; Ursprungsgeschoss Name: 1. OG; Ursprungsgeschoss Nummer: 1; Typ: Dach; Struktur-Typ: Mehrschicht; Baustoffe (Alle): Dach, Stehfalz; Dämmung, hart Mineralwolle; Luftschicht vertikal; Holz, Bauholz; Oberfläche (Alle): Holz Kiefer; Farbe, gelb; Metall Stehfalz; Unsichtbar; Deckschraffur: Misch-Schraffur 0%; Lage: Außen; Tragende Funktion: Tragende Elemente; Anzeigen auf Umbau-Filter: Alle relevanten Filter; Umbau-Status: Bestand; Oberfläche unten: Holz Kiefer; Geometriemethode: Einzelfläche; Dach-Stufe: 1; Oberfläche oben: Metall Stehfalz; Trimm-Körper: Konturen nach unten; ARCHICAD Klassifizierung - 22: Dach
Brandschutz 4102-2 - Kennbuchstabe: F
Pset_SlabCommon - LoadBearing: yes; IsExternal: yes
Component Properties - Component 1, Komponenten-Typ: Kern; Component 2, Komponenten-Typ: Andere; Component 3, Komponenten-Typ: Andere
BaseQuantities - Width: 0.13 m
ArchiCADQuantities - Höhe: 0.13 m; Dicke: 0.13 m; Trauf-Länge: 0 m; Wandende Verbindungslänge: 0 m; Ortgang-Länge: 0 m; Grat-Länge: 0 m; Löcher Oberflächenbereich: 0 m2; Konkave Verbindungslänge: 0 m; Anzahl der Löcher: 0; Anzahl der Dachfenster: 0; Oberflächenbereich der Öffnungen: 0 m2; Pultdachfirst-Länge: 0 m; Seitenwand Verbindungslänge: 0 m; Kehlen-Länge: 0 m
Component Quantities - Component 1, Schichtdicke: 0.025 m; Component 2, Schichtdicke: 0.05 m; Component 3, Schichtdicke: 0.03 m
Name | Element ID = Hotlink und Element-ID = Überobjekt-ID | Kollidierende Räume | Neigung (deg) | Neigung in Prozent | Component 1, Enthaltenes CO2 | Component 1, Enthaltene Energie (MJ) | Component 2, Enthaltenes CO2 | Component 2, Enthaltene Energie (MJ) | Component 3, Enthaltenes CO2 | Component 3, Enthaltene Energie (MJ) | Perimeter (m) | GrossArea (m2) = NetArea (m2) = Oberflächenbereich (m2) = Konditionaler Oberflächenbereich oben (m2) = Netto-Oberflächenbereich Oberseite (m2) = Dach-/Schalenoberfläche (netto) (m2) = Dach-/Schalenoberfläche (konditional) (m2) | GrossVolume (m3) = NetVolume (m3) | Höhenangabe zum Projekt-Nullpunkt (m) = Höhe zu 1. Referenzhöhe (m) = Höhe zu 2. Referenzhöhe (m) | Höhe zu Meereshöhe (m) | Höhe zu verknüpftem/Ursprungsgeschoss (m) = Abstand zu Ursprungsgeschoss (m) | Konditionaler Oberflächenbereich unten (m2) = Netto-Oberflächenbereich Unterseite (m2) | Kuppel-Verbindungslänge (m) | Brutto-Oberflächenbereich an der Unterseite (m2) | Brutto-Oberflächenbereich der Dachkanten (m2) | Brutto-Oberflächenbereich an der Oberseite (m2) | Netto-Oberflächenbereich der Kante (m2) | First-Länge (m) | Vertikal Dicke (m) | Component 1, Masse (kg) | Component 1, Schicht/Komponente Oberflächenbereich (m2) | Component 1, Schicht/Komponente Volumen (m3) | Component 2, Masse (kg) | Component 2, Schicht/Komponente Oberflächenbereich (m2) | Component 2, Schicht/Komponente Volumen (m3) | Component 3, Masse (kg) | Component 3, Schicht/Komponente Oberflächenbereich (m2) | Component 3, Schicht/Komponente Volumen (m3)
Dach-008 | Dach-008 | Grundfläche Gebäude Nachgezogen; Obergeschoss; Wohnung1 OG; Wohnung2 OG | 36.82 | 74.864 | 8503.72 (kgCO₂) | 128580 | 255.42 (kgCO₂) | 3234.31 | 113.845 (kgCO₂) | 2728.35 | 23.7903 | 26.3382 | 3.41087 | 4.3946 | 20.3946 | 0.644597 | 26.0898 | 0 | 26.0898 | 3.62788 | 26.7953 | 3.62788 | 0 | 0.162394 | 5122.72 | 26.4928 | 0.656759 | 151.136 | 26.7294 | 1.31423 | 392.568 | 26.4381 | 0.785136
Dach-006 | Dach-006 | Grundfläche Gebäude Nachgezogen; Obergeschoss; Wohnung1 OG | 3.68 | 6.43166 | 2455.89 (kgCO₂) | 37134.2 | 68.3805 (kgCO₂) | 865.883 | 28.6592 (kgCO₂) | 686.831 | 7.97271 | 7.63633 | 0.90351 | 6.20371 | 22.2037 | 2.45371 | 6.52902 | 2.38635 | 7.76305 | 1.44054 | 7.79571 | 0.644859 | 1.6 | 0.130269 | 1479.45 | 7.63633 | 0.189673 | 40.4618 | 7.14594 | 0.351842 | 98.8247 | 6.65377 | 0.197649
Dach-008 | Dach-008 | Dachterrasse; Grundfläche Gebäude Nachgezogen; Obergeschoss; Wohnung1 OG; Wohnung2 OG | 36.82 | 74.864 | 6657.61 (kgCO₂) | 100666 | 200.018 (kgCO₂) | 2532.77 | 88.9792 (kgCO₂) | 2132.43 | 20.5903 | 20.644 | 2.66889 | 4.3946 | 20.3946 | 0.644597 | 20.3628 | 0 | 20.3628 | 3.10822 | 21.1614 | 3.10822 | 0 | 0.162394 | 4010.61 | 20.7387 | 0.51418 | 118.354 | 20.9262 | 1.02916 | 306.825 | 20.6608 | 0.613649
Dach-006 | Dach-006 | Grundfläche Gebäude Nachgezogen; Obergeschoss; Wohnung1 OG | -3.68 | -6.43166 | 971.756 (kgCO₂) | 14693.4 | 28.9572 (kgCO₂) | 366.677 | 13.3955 (kgCO₂) | 321.029 | 4.9394 | 3.04568 | 0.393094 | 6.0665 | 22.0665 | 2.3165 | 3.02703 | 1.2797 | 3.15764 | 0.67979 | 3.61164 | 0.64037 | 1.19 | 0.130269 | 585.395 | 3.04951 | 0.0750507 | 17.1344 | 3.07486 | 0.148995 | 46.1913 | 3.1364 | 0.0923826

# IfcWall: Beton, WU-Beton 240, Wand-004
In: R-016
Classification: Wand (ARCHICAD Klassifizierung); Material: Beton, WU-Beton
ArchiCADProperties - Element ID: Wand-004; Hotlink und Element-ID: Wand-004; Ebene: Wand Aussen; Baustoff / Mehrschichtiger Aufbau / Profil / Schraffur: Beton, WU-Beton; Baustoff: Beton, WU-Beton; Kollidierende Räume: Gelände; Tiefgaragenabfahrt; Untergeschoss UG; Zugehöriger Raumname: Garage; Zugehörige Raumnummer: R-013; Geschützt: no; Ursprungsgeschoss Name: -1. Geschoss; Ursprungsgeschoss Nummer: -1; Typ: Wand; Absolutes Geschoss für Oberkantenverknüpfung: Nicht verknüpft; Relatives Geschoss für Oberkantenverknüpfung: Nicht verknüpft; Geschoss für Oberkantenverknüpfung: Nicht verknüpft; Struktur-Typ: Einfach; Überobjekt-ID: Wand-004; Baustoffe (Alle): Beton, WU-Beton; Oberfläche (Alle): Beton, Sichtbeton 2; Neigungswinkel: 90 deg; Lage: Außen; Tragende Funktion: Tragende Elemente; Anzeigen auf Umbau-Filter: Alle relevanten Filter; Umbau-Status: Bestand; Wandkomplexität: gerade; Geometriemethode: Uni; Lage der Referenzlinie: Innen; Oberfläche Kante: Beton, Sichtbeton 2; Innenseite Oberfläche: Beton, Sichtbeton 2; Außenseite Oberfläche: Beton, Sichtbeton 2; Wand Innerer Neigungswinkel: 90 deg; Wand Äußerer Neigungswinkel: 90 deg; ARCHICAD Klassifizierung - 22: Wand
Brandschutz 4102-2 - Kennbuchstabe: F
Pset_WallCommon - LoadBearing: yes; IsExternal: yes
Component Properties - Component 1, Enthaltenes CO2: 642.15 (kgCO₂); Component 1, Enthaltene Energie: 4281 MJ; Component 1, Komponenten-Typ: Keine
BaseQuantities - Length: 5.405 m; Height: 2.8 m; Width: 0.24 m; GrossFootprintArea: 1.2972 m2; NetFootprintArea: 1.2972 m2; GrossSideArea: 15.134 m2; NetSideArea: 8.813 m2; GrossVolume: 3.63216 m3; NetVolume: 2.11512 m3
ArchiCADQuantities - Fläche: 1.2972 m2; Höhe: 2.8 m; Netto-Volumen: 2.11512 m3; Breite: 0.24 m; Höhenangabe zum Projekt-Nullpunkt: -2.8 m; Höhe zu 1. Referenzhöhe: -2.8 m; Höhe zu 2. Referenzhöhe: -2.8 m; Höhe zu Meereshöhe: 13.2 m; Höhe zu verknüpftem/Ursprungsgeschoss: 0 m; Abstand zu Ursprungsgeschoss: 0 m; Abstand Oberkante: 0 m; Oberflächenbereich: 8.813 m2; 3D-Länge: 5.405 m; Dicke: 0.24 m; Konditionales Volumen: 2.11512 m3; Brutto-Volumen: 3.84384 m3; Dämmungsschichtdicke: 0 m; Grundriss-Umfang: 11.29 m; Anzahl der Türen: 1; Anzahl der Durchbrüche (Anzahl der leeren Öffnungen): 0; Anzahl der Fenster: 0; Anzahl der Stützen: 0; Volumen der Stützen: 0 m3; Maximale Höhe der Wandschicht an der Innenseite: 0 m; Minimale Höhe der Wandschicht an der Innenseite: 0 m; Maximale Höhe der Wand: 2.8 m; Minimale Höhe der Wand: 0 m; Maximale Höhe der Wandschicht an der Außenseite: 0 m; Minimale Höhe der Wandschicht an der Außenseite: 0 m; Luftschichtdicke: 0 m; Fläche der Türen: 6.321 m2; Kombinierte Breite der Türen: 3.01 m; Wand-Schichtdicke an der Innenseite: 0 m; Wand-Schichtdicke an der Außenseite: 0 m; Fläche der Fenster: 0 m2; Kombinierte Breite der Fenster: 0 m; Analytische Oberfläche der Öffnungen an der Innenseite: 6.321 m2; Analytische Oberfläche der Öffnungen an der Außenseite: 6.321 m2; Durchschnittliche Länge der Wand: 5.405 m; Netto-Oberflächenbereich an den Kanten: 2.544 m2; Netto-Oberflächenbereich an der Innenseite: 8.813 m2; Netto-Oberflächenbereich an der Außenseite: 8.813 m2; Analytisches Volumen der Öffnungen: 1.51704 m3; Länge der Referenzlinie: 5.72 m; Konditionale Länge an der Innenseite: 2.395 m; Konditionaler Oberflächenbereich an der Innenseite: 8.813 m2; Konditionale Länge an der Außenseite: 2.395 m; Konditionaler Oberflächenbereich an der Außenseite: 8.813 m2; Brutto-Wandoberflächenbereich an der Innenseite: 16.016 m2; Brutto-Wandoberflächenbereich an der Außenseite: 16.016 m2; Wandstärke am Ende: 0.24 m; Länge der Wand in der Achse: 5.405 m; Wandlänge an der Innenseite: 5.405 m; Wandlänge an der Außenseite: 5.405 m; Fläche der Wand: 1.2972 m2; Oberflächenbereich der leeren Öffnungen in der Wand: 0 m2
Component Quantities - Component 1, Masse: 4864.78 kg; Component 1, Schicht/Komponente Oberflächenbereich: 8.813 m2; Component 1, Schichtdicke: 0.24 m; Component 1, Schicht/Komponente Höhe (rechteckig): 2.8 m; Component 1, Schicht/Komponente Breite (rechteckig): 0.24 m; Component 1, Schicht/Komponente Querschnittsbereich: 0.672 m2; Component 1, Schicht/Komponente Volumen: 2.11512 m3

# IfcWall: WA | 2 Schichtig KS 375 (20)
Classification: Wand (ARCHICAD Klassifizierung)
ArchiCADProperties - Ebene: Wand Aussen; Baustoff / Mehrschichtiger Aufbau / Profil / Schraffur: WA | 2 Schichtig KS; Mehrschichtige Bauteile: WA | 2 Schichtig KS; Geschützt: no; Typ: Wand; Absolutes Geschoss für Oberkantenverknüpfung: Nicht verknüpft; Relatives Geschoss für Oberkantenverknüpfung: Nicht verknüpft; Geschoss für Oberkantenverknüpfung: Nicht verknüpft; Struktur-Typ: Mehrschicht; Baustoffe (Alle): Verputz, Zement; Dämmung, weich Mineralwolle 2; MW Kalksandstein; Verputz, Zement; Neigungswinkel: 90 deg; Lage: Außen; Tragende Funktion: Tragende Elemente; Anzeigen auf Umbau-Filter: Alle relevanten Filter; Umbau-Status: Bestand; Wandkomplexität: gerade; Geometriemethode: Uni; Innenseite Oberfläche: Verputz, glatt, weiß; Außenseite Oberfläche: Verputz, glatt, weiß; Wand Innerer Neigungswinkel: 90 deg; Wand Äußerer Neigungswinkel: 90 deg; ARCHICAD Klassifizierung - 22: Wand
Brandschutz 4102-2 - Kennbuchstabe: F
Pset_WallCommon - LoadBearing: yes; IsExternal: yes
Component Properties - Component 4, Komponenten-Typ: Bekleidung; Component 1, Komponenten-Typ: Bekleidung
BaseQuantities - Width: 0.375 m
ArchiCADQuantities - Breite: 0.375 m; Dicke: 0.375 m; Dämmungsschichtdicke: 0 m; Anzahl der Durchbrüche (Anzahl der leeren Öffnungen): 0; Anzahl der Stützen: 0; Volumen der Stützen: 0 m3; Minimale Höhe der Wand: 0 m; Luftschichtdicke: 0 m; Wand-Schichtdicke an der Innenseite: 0.02 m; Wand-Schichtdicke an der Außenseite: 0.02 m; Wandstärke am Ende: 0.375 m; Oberflächenbereich der leeren Öffnungen in der Wand: 0 m2
Component Quantities - Component 4, Schichtdicke: 0.02 m; Component 4, Schicht/Komponente Breite (rechteckig): 0.02 m; Component 1, Schichtdicke: 0.02 m; Component 1, Schicht/Komponente Breite (rechteckig): 0.02 m
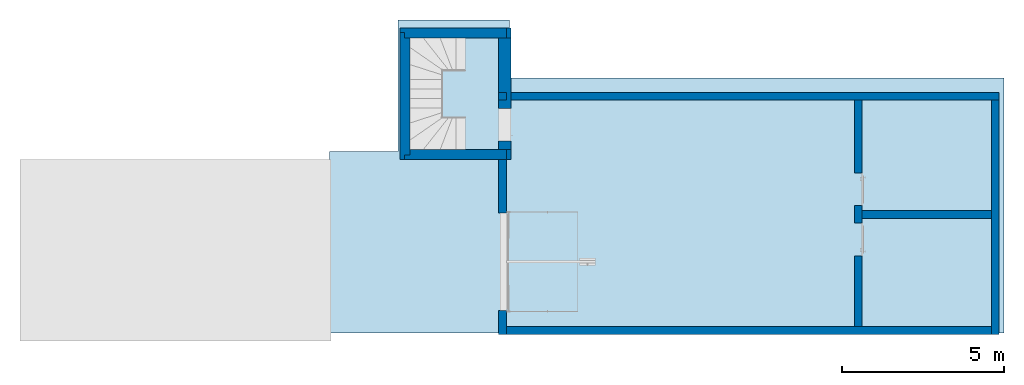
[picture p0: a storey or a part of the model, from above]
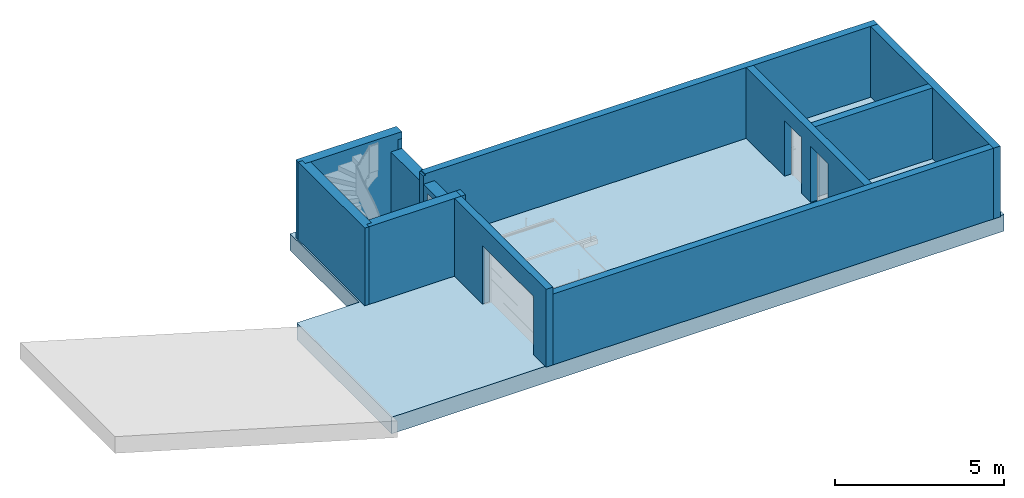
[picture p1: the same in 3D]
Properties of the parts of a building model (IFC4), part 12 of 13

# IfcWall: WA | 2 Schichtig KS 375 (20)
Name | In | Material | Element ID = Hotlink und Element-ID = Überobjekt-ID | Kollidierende Räume | Zugehöriger Raumname | Zugehörige Raumnummer | Ursprungsgeschoss Name | Ursprungsgeschoss Nummer | Oberfläche (Alle) | Lage der Referenzlinie | Component 4, Enthaltenes CO2 | Component 4, Enthaltene Energie (MJ) | Component 3, Enthaltenes CO2 | Component 3, Enthaltene Energie (MJ) | Component 3, Komponenten-Typ | Component 2, Enthaltenes CO2 | Component 2, Enthaltene Energie (MJ) | Component 2, Komponenten-Typ | Component 1, Enthaltenes CO2 | Component 1, Enthaltene Energie (MJ) | Length (m) = Durchschnittliche Länge der Wand (m) = Länge der Wand in der Achse (m) | Height (m) = Maximale Höhe der Wand (m) | GrossFootprintArea (m2) = NetFootprintArea (m2) = Fläche (m2) = Fläche der Wand (m2) | GrossSideArea (m2) | NetSideArea (m2) | GrossVolume (m3) | NetVolume (m3) = Netto-Volumen (m3) | Höhe (m) = Component 4, Schicht/Komponente Höhe (rechteckig) (m) = Component 3, Schicht/Komponente Höhe (rechteckig) (m) = Component 2, Schicht/Komponente Höhe (rechteckig) (m) = Component 1, Schicht/Komponente Höhe (rechteckig) (m) | Höhenangabe zum Projekt-Nullpunkt (m) = Höhe zu 1. Referenzhöhe (m) = Höhe zu 2. Referenzhöhe (m) | Höhe zu Meereshöhe (m) | Höhe zu verknüpftem/Ursprungsgeschoss (m) = Abstand zu Ursprungsgeschoss (m) | Abstand Oberkante (m) | Oberflächenbereich (m2) = Netto-Oberflächenbereich an der Außenseite (m2) | 3D-Länge (m) | Konditionales Volumen (m3) | Brutto-Volumen (m3) | Grundriss-Umfang (m) | Anzahl der Türen | Anzahl der Fenster | Maximale Höhe der Wandschicht an der Innenseite (m) | Minimale Höhe der Wandschicht an der Innenseite (m) | Maximale Höhe der Wandschicht an der Außenseite (m) | Minimale Höhe der Wandschicht an der Außenseite (m) | Fläche der Türen (m2) | Kombinierte Breite der Türen (m) | Fläche der Fenster (m2) | Kombinierte Breite der Fenster (m) | Wand-Schichtvolumen an der Innenseite (m3) | Wand-Schichtvolumen an der Außenseite (m3) | Analytische Oberfläche der Öffnungen an der Innenseite (m2) | Analytische Oberfläche der Öffnungen an der Außenseite (m2) | Netto-Oberflächenbereich an den Kanten (m2) | Netto-Oberflächenbereich an der Innenseite (m2) | Analytisches Volumen der Öffnungen (m3) | Länge der Referenzlinie (m) | Konditionale Länge an der Innenseite (m) | Konditionaler Oberflächenbereich an der Innenseite (m2) | Konditionale Länge an der Außenseite (m) | Konditionaler Oberflächenbereich an der Außenseite (m2) | Konditionales Wand-Schichtvolumen an der Innenseite (m3) | Konditionales Schichtvolumen an der Außenseite (m3) | Brutto-Wandoberflächenbereich an der Innenseite (m2) | Brutto-Wandoberflächenbereich an der Außenseite (m2) | Wandlänge an der Innenseite (m) | Wandlänge an der Außenseite (m) | Component 4, Masse (kg) | Component 4, Schicht/Komponente Oberflächenbereich (m2) | Component 4, Schicht/Komponente Querschnittsbereich (m2) = Component 1, Schicht/Komponente Querschnittsbereich (m2) | Component 4, Schicht/Komponente Volumen (m3) | Component 3, Masse (kg) | Component 3, Schicht/Komponente Oberflächenbereich (m2) | Component 3, Schichtdicke (m) = Component 3, Schicht/Komponente Breite (rechteckig) (m) | Component 3, Schicht/Komponente Querschnittsbereich (m2) | Component 3, Schicht/Komponente Volumen (m3) | Component 2, Masse (kg) | Component 2, Schicht/Komponente Oberflächenbereich (m2) | Component 2, Schichtdicke (m) = Component 2, Schicht/Komponente Breite (rechteckig) (m) | Component 2, Schicht/Komponente Querschnittsbereich (m2) | Component 2, Schicht/Komponente Volumen (m3) | Component 1, Masse (kg) | Component 1, Schicht/Komponente Oberflächenbereich (m2) | Component 1, Schicht/Komponente Volumen (m3)
Wand-001 | EG | Verputz, Zement (2), MW Kalksandstein, Dämmung, weich Mineralwolle 2 | Wand-001 | Erdgeschoss; Grundfläche Gebäude Nachgezogen; Treppenhaus; Wohnung1 EG | Wohnen | R-006 | EG | 0 | Verputz, glatt, weiß; Farbe, weiß; Mineralwolle | Innen | 82.2656 (kgCO₂) | 517.54 | 475.14 (kgCO₂) | 6426.75 | Andere | 216.841 (kgCO₂) | 3717.28 | Kern | 71.0268 (kgCO₂) | 446.835 | 2.98011 | 3.6 | 1.11754 | 9.99559 | 9.99559 | 3.83733 | 3.83733 | 3.6 | 0 | 16 | 0 | 0 | 10.7284 | 3.3351 | 3.83733 | 4.5294 | 7.02087 | 0 | 0 | 3.6 | 0 | 3.6 | 0 | 0 | 0 | 0 | 0 | 0.185255 | 0.214569 | 0 | 0 | 1.65084 | 9.26275 | 0 | 2.9801 | 2.9801 | 9.26275 | 2.98012 | 10.7284 | 0.185255 | 0.214569 | 12.0784 | 12.0784 | 2.9801 | 2.98012 | 386.224 | 10.7284 | 0.072 | 0.214569 | 274.647 | 10.7284 | 0.16 | 0.576 | 1.71655 | 3097.73 | 9.83437 | 0.175 | 0.63 | 1.72096 | 333.459 | 9.26275 | 0.185255
Wand-001 | EG | Verputz, Zement (2), Dämmung, weich Mineralwolle 2, MW Kalksandstein | Wand-001 | Erdgeschoss; Grundfläche Gebäude Nachgezogen; Treppenhaus; Wohnung2 EG | Wohnen | R-009 | EG | 0 | Verputz, glatt, weiß; Farbe, weiß; Mineralwolle | Innen | 70.9886 (kgCO₂) | 446.595 | 216.868 (kgCO₂) | 3717.73 | Kern | 475.183 (kgCO₂) | 6427.33 | Andere | 82.2729 (kgCO₂) | 517.585 | 2.98038 | 3.6 | 1.11764 | 9.99358 | 9.99358 | 3.83762 | 3.83762 | 3.6 | 0 | 16 | 0 | 0 | 10.7294 | 3.16038 | 3.83762 | 4.52977 | 7.02143 | 0 | 0 | 3.3 | 0 | 3.6 | 0 | 0 | 0 | 0 | 0 | 0.185155 | 0.214588 | 0 | 0 | 1.65061 | 9.25777 | 0 | 2.98038 | 2.98038 | 9.25777 | 2.98038 | 10.7294 | 0.185155 | 0.214588 | 12.0794 | 12.0794 | 2.98038 | 2.98038 | 333.28 | 9.25777 | 0.072 | 0.185155 | 3098.11 | 9.83527 | 0.175 | 0.63 | 1.72117 | 274.672 | 10.7294 | 0.16 | 0.576 | 1.7167 | 386.258 | 10.7294 | 0.214588
Wand-002 | EG | Verputz, Zement (2), Dämmung, weich Mineralwolle 2, MW Kalksandstein | Wand-002 | Erdgeschoss; Grundfläche Gebäude Nachgezogen; Treppenhaus | Treppenhaus | R-010 | EG | 0 | Verputz, glatt, weiß; Farbe, weiß; Mineralwolle | Innen | 86.541 (kgCO₂) | 544.437 | 263.045 (kgCO₂) | 4509.35 | Kern | 629.775 (kgCO₂) | 8518.35 | Andere | 114.008 (kgCO₂) | 717.232 | 3.775 | 3.6 | 1.41562 | 13.077 | 13.077 | 4.88594 | 4.88594 | 3.6 | 0 | 16 | 0 | 0 | 14.868 | 4.13 | 4.88594 | 5.6025 | 8.61066 | 0 | 0 | 3.3 | 0 | 3.6 | 0 | 0 | 0 | 0 | 0 | 0.22572 | 0.29736 | 0 | 0 | 2.13022 | 11.286 | 0 | 3.4 | 3.4 | 11.286 | 4.15 | 14.868 | 0.22572 | 0.29736 | 14.94 | 14.94 | 3.4 | 4.15 | 406.296 | 11.286 | 0.072 | 0.22572 | 3757.79 | 11.9295 | 0.175 | 0.63 | 2.08766 | 364.032 | 14.22 | 0.16 | 0.576 | 2.2752 | 535.248 | 14.868 | 0.29736
Wand-004 | EG | Verputz, Zement (2), MW Kalksandstein, Dämmung, weich Mineralwolle 2 | Wand-004 | Erdgeschoss; Grundfläche Gebäude Nachgezogen; Wohnung1 EG | Wohnen | R-006 | EG | 0 | Verputz, glatt, weiß; Farbe, weiß; Mineralwolle | Innen | 106.891 (kgCO₂) | 672.457 | 617.234 (kgCO₂) | 8348.72 | Andere | 281.088 (kgCO₂) | 4818.64 | Kern | 96.128 (kgCO₂) | 604.749 | 5.48 | 3.74993 | 2.055 | 19.9044 | 13.2384 | 7.49002 | 4.99027 | 3.75 | 0 | 16 | 0 | 0 | 13.9398 | 5.85498 | 4.99027 | 8.23359 | 12.0206 | 0 | 3 | 3.74993 | 0 | 3.74993 | 0 | 0 | 0 | 6.666 | 3.03 | 0.250725 | 0.278797 | 6.666 | 6.666 | 2.055 | 12.537 | 2.49975 | 5.48 | 3.46 | 19.203 | 5.48 | 20.6058 | 0.384045 | 0.412117 | 21.9562 | 21.9562 | 5.48 | 5.48 | 501.834 | 13.9398 | 0.075 | 0.278797 | 356.783 | 13.9368 | 0.16 | 0.6 | 2.22989 | 4015.54 | 13.9129 | 0.175 | 0.65625 | 2.23085 | 451.305 | 12.537 | 0.250725
Wand-005 | EG | Verputz, Zement (2), Dämmung, weich Mineralwolle 2, MW Kalksandstein | Wand-005 | Erdgeschoss; Grundfläche Gebäude Nachgezogen; Wohnung1 EG | Terrasse | R-002 | EG | 0 | Verputz, glatt, weiß; Farbe, weiß; Mineralwolle | Innen | 92.6371 (kgCO₂) | 582.787 | 290.095 (kgCO₂) | 4973.06 | Kern | 689.232 (kgCO₂) | 9322.56 | Andere | 121.183 (kgCO₂) | 762.373 | 7.3425 | 3.75 | 2.75344 | 25.9424 | 13.9424 | 9.85004 | 5.35004 | 3.75 | 0 | 16 | 0 | 0 | 15.8037 | 7.51 | 5.35004 | 10.5891 | 15.5903 | 0 | 1 | 3.5 | 0 | 3.75 | 0 | 0 | 0 | 12 | 5 | 0.24162 | 0.316075 | 12 | 12 | 5.4095 | 12.081 | 4.5 | 7.155 | 7.155 | 12.081 | 2.53 | 15.8037 | 0.48162 | 0.556075 | 28.2375 | 28.2375 | 7.155 | 7.53 | 434.916 | 12.081 | 0.075 | 0.24162 | 4144.22 | 13.1562 | 0.175 | 0.65625 | 2.30234 | 398.4 | 15.5625 | 0.16 | 0.6 | 2.49 | 568.935 | 15.8037 | 0.316075
Wand-005 | EG | Verputz, Zement (2), MW Kalksandstein, Dämmung, weich Mineralwolle 2 | Wand-005 | Erdgeschoss; Grundfläche Gebäude Nachgezogen; Wohnung1 EG | Wohnen | R-005 | EG | 0 | Verputz, glatt, weiß; Farbe, weiß; Mineralwolle | Innen | 238.752 (kgCO₂) | 1502.01 | 1349.07 (kgCO₂) | 18247.5 | Andere | 583.222 (kgCO₂) | 9998.09 | Kern | 188.911 (kgCO₂) | 1188.46 | 11.18 | 3.75 | 4.1925 | 39.9993 | 27.8793 | 15.163 | 10.618 | 3.75 | 0 | 16 | 0 | 0 | 31.1362 | 11.535 | 10.618 | 16.2492 | 23.4206 | 1 | 4 | 3.5 | 0 | 3.75 | 0 | 2.424 | 1.01 | 9.696 | 4.04 | 0.492726 | 0.622724 | 12.12 | 12.12 | 6.23649 | 24.6225 | 4.545 | 10.805 | 5.755 | 36.7425 | 11.555 | 43.2562 | 0.735126 | 0.865124 | 43.3313 | 43.3312 | 10.805 | 11.555 | 1120.9 | 31.1362 | 0.075 | 0.622724 | 779.807 | 30.4612 | 0.16 | 0.6 | 4.87379 | 8331.74 | 26.45 | 0.175 | 0.65625 | 4.62875 | 886.907 | 24.869 | 0.492726
Wand-008 | EG | Verputz, Zement (2), Dämmung, weich Mineralwolle 2, MW Kalksandstein | Wand-008 | Erdgeschoss; Grundfläche Gebäude Nachgezogen; Wohnung2 EG | Wohnen | R-009 | EG | 0 | Verputz, glatt, weiß; Farbe, weiß; Mineralwolle | Innen | 62.6974 (kgCO₂) | 394.434 | 193.649 (kgCO₂) | 3319.69 | Kern | 417.957 (kgCO₂) | 5653.29 | Andere | 68.5232 (kgCO₂) | 431.085 | 3.48 | 3.75 | 1.305 | 12.7984 | 8.55638 | 4.97986 | 3.38911 | 3.75 | 0 | 16 | 0 | -8.32667e-17 | 8.93625 | 3.855 | 3.38911 | 5.42109 | 8.02066 | 0 | 2 | 3.75 | 0 | 3.75 | 0 | 0 | 0 | 4.242 | 2.02 | 0.16353 | 0.178725 | 4.242 | 4.242 | 2.276 | 8.1765 | 1.59075 | 3.48 | 3.48 | 12.4185 | 2.47 | 13.1782 | 0.24837 | 0.263565 | 14.4562 | 14.4562 | 3.48 | 3.48 | 294.354 | 8.1765 | 0.075 | 0.16353 | 2766.41 | 8.78225 | 0.175 | 0.65625 | 1.53689 | 241.594 | 9.43725 | 0.16 | 0.6 | 1.50996 | 321.705 | 8.93625 | 0.178725
Wand-009 | EG | Verputz, Zement (2), Dämmung, weich Mineralwolle 2, MW Kalksandstein | Wand-009 | Erdgeschoss; Grundfläche Gebäude Nachgezogen; Wohnung2 EG | Wohnen | R-004 | EG | 0 | Verputz, glatt, weiß; Farbe, weiß; Mineralwolle | Innen | 188.806 (kgCO₂) | 1187.79 | 583.223 (kgCO₂) | 9998.1 | Kern | 1349.07 (kgCO₂) | 18247.5 | Andere | 234.189 (kgCO₂) | 1473.3 | 11.18 | 3.75 | 4.1925 | 39.702 | 27.582 | 15.1508 | 10.6058 | 3.75 | 0 | 16 | 0 | 0 | 30.5415 | 11.535 | 10.6058 | 16.2492 | 23.4207 | 1 | 4 | 3.5 | 0 | 3.75 | 0 | 2.424 | 1.01 | 9.696 | 4.04 | 0.492451 | 0.610823 | 12.12 | 12.12 | 6.1965 | 24.6225 | 4.545 | 10.805 | 10.805 | 36.7425 | 6.505 | 42.6615 | 0.73485 | 0.85323 | 43.3313 | 43.3313 | 10.805 | 11.555 | 886.412 | 24.6225 | 0.075 | 0.492451 | 8331.75 | 26.45 | 0.175 | 0.65625 | 4.62875 | 779.808 | 30.4613 | 0.16 | 0.6 | 4.8738 | 1099.48 | 30.5415 | 0.610823
Wand-004 | EG | Verputz, Zement (2), Dämmung, weich Mineralwolle 2, MW Kalksandstein | Wand-004 | Erdgeschoss; Grundfläche Gebäude Nachgezogen; Wohnung2 EG | Wohnen | R-004 | EG | 0 | Verputz, glatt, weiß; Farbe, weiß; Mineralwolle | Innen | 131.744 (kgCO₂) | 828.811 | 385.875 (kgCO₂) | 6615 | Kern | 888.528 (kgCO₂) | 12018.2 | Andere | 158.44 (kgCO₂) | 996.759 | 5.255 | 3.75 | 1.97062 | 18.9217 | 18.9217 | 7.02937 | 7.02937 | 3.75 | 0 | 16 | 0 | 0 | 20.6625 | 5.51 | 7.02937 | 7.77656 | 11.4542 | 0 | 0 | 3.5 | 0 | 3.75 | 0 | 0 | 0 | 0 | 0 | 0.34362 | 0.41325 | 0 | 0 | 2.907 | 17.181 | 0 | 5.155 | 4.98 | 17.181 | 5.53 | 20.6625 | 0.34362 | 0.41325 | 20.7375 | 20.7375 | 4.98 | 5.53 | 618.516 | 17.181 | 0.075 | 0.34362 | 5512.5 | 17.5 | 0.175 | 0.65625 | 3.0625 | 513.6 | 20.0625 | 0.16 | 0.6 | 3.21 | 743.85 | 20.6625 | 0.41325
Wand-008 | EG | Verputz, Zement (2), MW Kalksandstein, Dämmung, weich Mineralwolle 2 | Wand-008 | Erdgeschoss; Grundfläche Gebäude Nachgezogen; Wohnung1 EG; Wohnung2 EG | Wohnung2 EG | R-020 | EG | 0 | Verputz, glatt, weiß; Farbe, weiß; Mineralwolle | Außen | 3.9973 (kgCO₂) | 25.1473 | 25.1776 (kgCO₂) | 340.553 | Andere | 12.5354 (kgCO₂) | 214.892 | Kern | 4.35924 (kgCO₂) | 27.4243 | 3.79 | 0.15 | 1.42125 | 0.544897 | 0.544897 | 0.212243 | 0.212243 | 0.15 | 3.6 | 19.6 | 3.6 | 0 | 0.521296 | 3.79 | 0.212243 | 0.213187 | 8.33 | 0 | 0 | 0.15 | 0.148597 | 0.15 | 0 | 0 | 0 | 0 | 0 | 0.01137 | 0.0104259 | 0 | 0 | 2.93768 | 0.568498 | 0 | 3.79 | 3.79 | 0.568498 | 3.79 | 0.521296 | 0.01137 | 0.0104259 | 0.5685 | 0.5685 | 3.79 | 3.79 | 18.7667 | 0.521296 | 0.003 | 0.0104259 | 14.5536 | 0.568498 | 0.16 | 0.024 | 0.0909597 | 179.077 | 0.568498 | 0.175 | 0.02625 | 0.0994872 | 20.4659 | 0.568498 | 0.01137
Wand-008 | OG | Verputz, Zement (2), Dämmung, weich Mineralwolle 2, MW Kalksandstein | Wand-008 | Grundfläche Gebäude Nachgezogen; Obergeschoss; Wohnung1 OG; Wohnung2 OG | Loft | R-003 | 1. OG | 1 | Verputz, glatt, weiß; Farbe, weiß; Mineralwolle | Innen | 84.9308 (kgCO₂) | 534.306 | 270.961 (kgCO₂) | 4645.05 | Kern | 606.746 (kgCO₂) | 8206.85 | Andere | 105.941 (kgCO₂) | 666.484 | 5.28 | 2.9 | 1.98 | 14.87 | 12.446 | 5.74933 | 4.84033 | 2.9 | 3.75 | 19.75 | 0 | 0 | 13.816 | 5.6 | 4.84033 | 6.09 | 11.5495 | 0 | 1 | 2.75 | 0 | 2.9 | 0 | 0 | 0 | 2.424 | 1.01 | 0.22152 | 0.27632 | 2.424 | 2.424 | 3.03945 | 11.076 | 0.909 | 4.96 | 4.96 | 13.5 | 4.59 | 16.24 | 0.27 | 0.3248 | 16.24 | 16.24 | 4.96 | 5.6 | 398.736 | 11.076 | 0.058 | 0.22152 | 3870.88 | 12.2885 | 0.175 | 0.5075 | 2.15049 | 350.72 | 13.7 | 0.16 | 0.464 | 2.192 | 497.376 | 13.816 | 0.27632
Wand-004 | OG | Verputz, Zement (2), Dämmung, weich Mineralwolle 2, MW Kalksandstein | Wand-004 | Grundfläche Gebäude Nachgezogen; Obergeschoss; Wohnung2 OG | Loft | R-003 | 1. OG | 1 | Verputz, glatt, weiß; Farbe, weiß; Mineralwolle | Innen | 28.893 (kgCO₂) | 181.768 | 90.9783 (kgCO₂) | 1559.63 | Kern | 260.901 (kgCO₂) | 3528.94 | Andere | 52.2881 (kgCO₂) | 328.949 | 5.335 | 2.9 | 2.00062 | 14.9175 | 5.2935 | 5.48535 | 1.87635 | 2.9 | 3.75 | 19.75 | 0 | 0 | 6.819 | 5.67 | 1.87635 | 6.20962 | 11.7307 | 0 | 1 | 2.75 | 0 | 2.9 | 0 | 0 | 0 | 9.624 | 4.01 | 0.07536 | 0.13638 | 9.624 | 9.624 | 2.913 | 3.768 | 3.609 | 4.96 | 4.96 | 3.768 | 1.7 | 6.819 | 0.26784 | 0.32886 | 16.559 | 16.559 | 4.96 | 5.71 | 135.648 | 3.768 | 0.058 | 0.07536 | 1299.69 | 4.126 | 0.175 | 0.5075 | 0.72205 | 150.81 | 5.891 | 0.16 | 0.464 | 0.94256 | 245.484 | 6.819 | 0.13638
Wand-004 | OG | Verputz, Zement (2), MW Kalksandstein, Dämmung, weich Mineralwolle 2 | Wand-004 | Dachterrasse; Dachterrasse; Grundfläche Gebäude Nachgezogen; Obergeschoss; Wohnung1 OG; Wohnung2 OG | Dachterrasse | R-001 | 1. OG | 1 | Verputz, glatt, weiß; Farbe, weiß; Mineralwolle | Innen | 138.962 (kgCO₂) | 874.22 | 800.102 (kgCO₂) | 10822.2 | Andere | 368.046 (kgCO₂) | 6309.37 | Kern | 122.04 (kgCO₂) | 767.76 | 6.06212 | 2.9 | 2.27329 | 17.0181 | 17.0181 | 6.4923 | 6.4923 | 2.9 | 3.75 | 19.75 | 0 | 0 | 18.1207 | 6.24962 | 6.4923 | 6.79646 | 13.0296 | 0 | 0 | 2.75 | 0 | 2.9 | 0 | 0 | 0 | 0 | 0 | 0.318309 | 0.362446 | 0 | 0 | 4.48079 | 15.9155 | 0 | 5.87462 | 5.87462 | 15.9155 | 6.24962 | 18.1207 | 0.318308 | 0.362447 | 18.1239 | 18.1239 | 5.87462 | 6.24962 | 652.403 | 18.1239 | 0.058 | 0.362446 | 462.487 | 18.0659 | 0.16 | 0.464 | 2.89054 | 5257.8 | 16.6914 | 0.175 | 0.5075 | 2.921 | 572.955 | 15.9155 | 0.318309 | Pset_ConcreteElementGeneral - FireRating: F 90; Pset_WallCommon - FireRating: F 90; Pset_FireRatingProperties - FireResistanceRating: F 90; Brandschutz 4102-2 - Feuerwiderstand 4102-2: F 90; Brandwand: yes; Minuten (4102-2): 90; Baustoffklasse: A
Wand-009 | OG | Verputz, Zement (2), Dämmung, weich Mineralwolle 2, MW Kalksandstein | Wand-009 | Grundfläche Gebäude Nachgezogen; Obergeschoss; Wohnung2 OG | Loft | R-003 | 1. OG | 1 | Verputz, glatt, weiß; Farbe, weiß; Mineralwolle | Innen | 116.64 (kgCO₂) | 733.794 | 359.172 (kgCO₂) | 6157.23 | Kern | 837.641 (kgCO₂) | 11329.9 | Andere | 149.031 (kgCO₂) | 937.569 | 11.18 | 2.9 | 4.1925 | 31.3395 | 17.3235 | 11.8257 | 6.56967 | 2.9 | 3.75 | 19.75 | 0 | 0 | 19.4355 | 11.535 | 6.56967 | 12.5661 | 23.4207 | 0 | 5 | 2.75 | 0 | 2.9 | 0 | 0 | 0 | 14.016 | 5.84 | 0.304226 | 0.38871 | 14.016 | 14.016 | 6.24 | 15.2115 | 5.256 | 10.805 | 10.805 | 24.9075 | 5.715 | 29.1315 | 0.584541 | 0.669041 | 33.5095 | 33.5095 | 10.805 | 11.555 | 547.607 | 15.2115 | 0.058 | 0.304226 | 5131.02 | 16.289 | 0.175 | 0.5075 | 2.85057 | 484.186 | 18.9135 | 0.16 | 0.464 | 3.02616 | 699.678 | 19.4355 | 0.38871
Wand-012 | OG | Verputz, Zement (2), MW Kalksandstein, Dämmung, weich Mineralwolle 2 | Wand-012 | Grundfläche Gebäude Nachgezogen; Luftraum Dach; Obergeschoss; Wohnung1 OG | Luftraum Dach | R-012 | 1. OG | 1 | Verputz, glatt, weiß; Farbe, weiß; Metall, Fassade Edelstahl; Mineralwolle | Innen | 10.9891 (kgCO₂) | 69.1335 | 68.7859 (kgCO₂) | 930.399 | Andere | 36.5652 (kgCO₂) | 626.832 | Kern | 12.4296 (kgCO₂) | 78.1953 | 1.82535 | 0.985237 | 0.684507 | 1.52571 | 1.52571 | 0.599786 | 0.599786 | 1.14763 | 3.75 | 19.75 | 4.44089e-16 | 0 | 1.41805 | 2.01285 | 0.599786 | 0.637722 | 4.55603 | 0 | 0 | 0.985237 | 0 | 0.71947 | 0 | 0 | 0 | 0 | 0 | 0.0324193 | 0.0286623 | 0 | 0 | 1.92054 | 1.63338 | 0 | 1.63785 | 1.63785 | 1.63338 | 2.01285 | 1.41805 | 0.0324193 | 0.0286623 | 1.98314 | 1.41805 | 1.63785 | 2.01285 | 51.5922 | 1.44819 | 0.0229526 | 0.0286623 | 39.7606 | 1.6725 | 0.16 | 0.183621 | 0.248504 | 522.36 | 1.77835 | 0.175 | 0.200835 | 0.2902 | 58.3547 | 1.63338 | 0.0324193
Wand-012 | OG | Verputz, Zement (2), Dämmung, weich Mineralwolle 2, MW Kalksandstein | Wand-012 | Grundfläche Gebäude Nachgezogen; Obergeschoss; Wohnung1 OG | Luftraum Dach | R-012 | 1. OG | 1 | Verputz, glatt, weiß; Farbe, weiß; Metall, Fassade Edelstahl; Mineralwolle | Innen | 71.6952 (kgCO₂) | 451.04 | 207.028 (kgCO₂) | 3549.05 | Kern | 429.843 (kgCO₂) | 5814.06 | Andere | 76.3347 (kgCO₂) | 480.228 | 5.28537 | 2.82314 | 1.98202 | 9.65245 | 9.65245 | 3.58208 | 3.58208 | 2.98304 | 3.75 | 19.75 | 0 | 0 | 9.95497 | 5.62037 | 3.58208 | 3.74379 | 11.6314 | 0 | 0 | 2.82314 | 0 | 2.82314 | 0 | 0 | 0 | 0 | 0 | 0.186998 | 0.199099 | 0 | 0 | 4.32966 | 9.34992 | 0 | 4.91038 | 4.91038 | 9.34992 | 5.66037 | 9.95497 | 0.186998 | 0.199099 | 9.98346 | 9.98344 | 4.91038 | 5.66037 | 336.597 | 9.34992 | 0.0596608 | 0.186998 | 2957.54 | 9.38903 | 0.175 | 0.522032 | 1.64308 | 248.464 | 9.70563 | 0.16 | 0.477287 | 1.5529 | 358.379 | 9.95497 | 0.199099
Wand-012 | OG | Verputz, Zement (2), MW Kalksandstein, Dämmung, weich Mineralwolle 2 | Wand-012 | Grundfläche Gebäude Nachgezogen; Obergeschoss; Wohnung1 OG | Luftraum Dach | R-012 | 1. OG | 1 | Verputz, glatt, weiß; Farbe, weiß; Metall, Fassade Edelstahl; Mineralwolle | Innen | 27.9884 (kgCO₂) | 176.077 | 175.744 (kgCO₂) | 2377.11 | Andere | 83.2034 (kgCO₂) | 1426.34 | Kern | 27.4282 (kgCO₂) | 172.553 | 3.125 | 2.70863 | 1.17187 | 8.29643 | 3.6135 | 3.1959 | 1.4398 | 2.7844 | 3.75 | 19.75 | 0 | 0 | 3.65209 | 3.2 | 1.4398 | 3.26749 | 7.02889 | 0 | 1 | 2.58186 | 0 | 2.6047 | 0 | 0 | 0 | 4.68294 | 2.483 | 0.0715393 | 0.0730006 | 4.68294 | 4.68294 | 1.2 | 3.57491 | 1.7561 | 3.2 | 3.05 | 3.57491 | 3.2 | 3.65209 | 0.165198 | 0.166659 | 8.6747 | 8.75188 | 3.05 | 3.2 | 131.401 | 3.65209 | 0.055688 | 0.0730006 | 101.586 | 3.98466 | 0.16 | 0.445504 | 0.634912 | 1188.62 | 3.7914 | 0.175 | 0.48727 | 0.660344 | 128.771 | 3.57902 | 0.0715393
Wand-012 | OG | Verputz, Zement (2), Dämmung, weich Mineralwolle 2, MW Kalksandstein | Wand-012 | Erdgeschoss; Grundfläche Gebäude Nachgezogen; Obergeschoss; Wohnung1 EG; Wohnung1 OG | Luftraum Dach | R-012 | 1. OG | 1 | Verputz, glatt, weiß; Farbe, weiß; Metall, Fassade Edelstahl; Mineralwolle | Innen | 53.621 (kgCO₂) | 337.334 | 146.166 (kgCO₂) | 2505.71 | Kern | 258.406 (kgCO₂) | 3495.21 | Andere | 40.9797 (kgCO₂) | 257.807 | 7.32251 | 0.985004 | 2.74594 | 6.16721 | 6.16721 | 2.34034 | 2.34034 | 1.29067 | 3.74993 | 19.7499 | -0.0000713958 | 0 | 5.28803 | 7.51 | 2.34034 | 2.37833 | 15.5503 | 0 | 0 | 0.985004 | 0 | 0.71925 | 4.44089e-16 | 0 | 0 | 0 | 0 | 0.139857 | 0.106885 | 0 | 0 | 5.64804 | 7.0464 | 0 | 7.13502 | 7.13502 | 7.0464 | 7.51 | 5.28803 | 0.139857 | 0.106885 | 7.39641 | 5.28803 | 7.13502 | 7.51 | 251.742 | 7.04641 | 0.0258133 | 0.139857 | 2088.09 | 7.10935 | 0.175 | 0.225867 | 1.16005 | 149.368 | 6.28327 | 0.16 | 0.206507 | 0.933549 | 192.393 | 5.40048 | 0.106885
Wand-012 | OG | Verputz, Zement (2), MW Kalksandstein, Dämmung, weich Mineralwolle 2 | Wand-012 | Grundfläche Gebäude Nachgezogen; Obergeschoss; Wohnung1 OG | Luftraum Dach | R-012 | 1. OG | 1 | Verputz, glatt, weiß; Farbe, weiß; Metall, Fassade Edelstahl; Mineralwolle | Innen | 12.5413 (kgCO₂) | 78.8981 | 79.9795 (kgCO₂) | 1081.8 | Andere | 46.2269 (kgCO₂) | 792.462 | Kern | 17.2226 (kgCO₂) | 108.349 | 2.29715 | 0.985237 | 0.861431 | 1.94079 | 1.94079 | 0.733455 | 0.733455 | 2.09796 | 3.75 | 19.75 | -4.44089e-16 | 0 | 1.61833 | 2.31715 | 0.733455 | 0.890959 | 5.3443 | 0 | 0 | 0.985237 | 0 | 0.71947 | 0 | 0 | 0 | 0 | 0 | 0.0449208 | 0.0327106 | 0 | 0 | 1.95259 | 2.26324 | 0 | 2.56215 | 2.29715 | 2.26324 | 2.29715 | 1.61833 | 0.0449208 | 0.0327106 | 2.77063 | 1.98115 | 2.29715 | 2.29715 | 58.8792 | 1.65273 | 0.0419592 | 0.0327106 | 46.2309 | 1.94467 | 0.16 | 0.335674 | 0.288943 | 660.385 | 2.24825 | 0.175 | 0.367143 | 0.36688 | 80.8574 | 2.26324 | 0.0449208
Wand-012 | OG | Verputz, Zement (2), Dämmung, weich Mineralwolle 2, MW Kalksandstein | Wand-012 | Grundfläche Gebäude Nachgezogen; Obergeschoss; Wohnung1 OG | Luftraum Dach | R-012 | 1. OG | 1 | Verputz, glatt, weiß; Farbe, weiß; Metall, Fassade Edelstahl | Innen | 5.76172 (kgCO₂) | 36.2475 | 20.0698 (kgCO₂) | 344.054 | Kern | 52.3928 (kgCO₂) | 708.665 | Andere | 9.82401 (kgCO₂) | 61.8036 | 2.23 | 1.08637 | 0.83625 | 2.05652 | 0.99246 | 0.830208 | 0.389216 | 2.6344 | 3.9 | 19.9 | 0.15 | 0 | 1.24981 | 2.38 | 0.830208 | 2.3512 | 5.26777 | 0 | 1 | 1.08637 | 0.265767 | 1.06354 | 0 | 0 | 0 | 1.18228 | 1.97047 | 0.015028 | 0.0256234 | 1.18228 | 0.945828 | 0 | 0.735112 | 0.440992 | 2.38 | 2.08 | 1.9174 | 2.38 | 2.19564 | 0.0386737 | 0.0469045 | 6.26987 | 6.26987 | 2.08 | 2.38 | 27.0503 | 0.770747 | 0.052688 | 0.015028 | 286.712 | 1.07949 | 0.175 | 0.46102 | 0.159284 | 30.2848 | 1.33779 | 0.16 | 0.421504 | 0.18928 | 46.1221 | 1.34893 | 0.0256234

# IfcWall: WA | 2 Schichtig KS Giebelwand 265, Wand-015
In: OG
Classification: Wand (ARCHICAD Klassifizierung); Material: Verputz, Zement (2), Dämmung, weich Mineralwolle 2, MW Kalksandstein
Pset_ConcreteElementGeneral - FireRating: F 90
Pset_WallCommon - FireRating: F 90; LoadBearing: yes; IsExternal: yes
Pset_FireRatingProperties - FireResistanceRating: F 90
ArchiCADProperties - Element ID: Wand-015; Hotlink und Element-ID: Wand-015; Ebene: Wand Aussen; Baustoff / Mehrschichtiger Aufbau / Profil / Schraffur: WA | 2 Schichtig KS Giebelwand; Mehrschichtige Bauteile: WA | 2 Schichtig KS Giebelwand; Kollidierende Räume: Grundfläche Gebäude Nachgezogen; Obergeschoss; Wohnung1 OG; Wohnung2 OG; Zugehöriger Raumname: Loft; Zugehörige Raumnummer: R-003; Geschützt: no; Ursprungsgeschoss Name: 1. OG; Ursprungsgeschoss Nummer: 1; Typ: Wand; Absolutes Geschoss für Oberkantenverknüpfung: Nicht verknüpft; Relatives Geschoss für Oberkantenverknüpfung: Nicht verknüpft; Geschoss für Oberkantenverknüpfung: Nicht verknüpft; Struktur-Typ: Mehrschicht; Überobjekt-ID: Wand-015; Baustoffe (Alle): Verputz, Zement; Dämmung, weich Mineralwolle 2; MW Kalksandstein; Verputz, Zement; Oberfläche (Alle): Verputz, glatt, weiß; Farbe, weiß; Mineralwolle; Neigungswinkel: 90 deg; Lage: Außen; Tragende Funktion: Tragende Elemente; Anzeigen auf Umbau-Filter: Alle relevanten Filter; Umbau-Status: Bestand; Wandkomplexität: gerade; Geometriemethode: Uni; Lage der Referenzlinie: Innen; Innenseite Oberfläche: Verputz, glatt, weiß; Außenseite Oberfläche: Verputz, glatt, weiß; Wand Innerer Neigungswinkel: 90 deg; Wand Äußerer Neigungswinkel: 90 deg; ARCHICAD Klassifizierung - 22: Wand
Brandschutz 4102-2 - Feuerwiderstand 4102-2: F 90; Brandwand: yes; Minuten (4102-2): 90; Baustoffklasse: A; Kennbuchstabe: F
Component Properties - Component 1, Enthaltenes CO2: 117.532 (kgCO₂); Component 1, Enthaltene Energie: 739.404 MJ; Component 1, Komponenten-Typ: Bekleidung; Component 2, Enthaltenes CO2: 205.712 (kgCO₂); Component 2, Enthaltene Energie: 2782.47 MJ; Component 2, Komponenten-Typ: Andere; Component 3, Enthaltenes CO2: 300.179 (kgCO₂); Component 3, Enthaltene Energie: 5145.93 MJ; Component 3, Komponenten-Typ: Kern; Component 4, Enthaltenes CO2: 102.077 (kgCO₂); Component 4, Enthaltene Energie: 642.177 MJ; Component 4, Komponenten-Typ: Bekleidung
BaseQuantities - Length: 5.11788 m; Height: 2.9 m; Width: 0.265 m; GrossFootprintArea: 1.35624 m2; NetFootprintArea: 1.35624 m2; GrossSideArea: 14.3198 m2; NetSideArea: 14.3198 m2; GrossVolume: 3.69835 m3; NetVolume: 3.69835 m3
ArchiCADQuantities - Fläche: 1.35624 m2; Höhe: 2.9 m; Netto-Volumen: 3.69835 m3; Breite: 0.265 m; Höhenangabe zum Projekt-Nullpunkt: 3.75 m; Höhe zu 1. Referenzhöhe: 3.75 m; Höhe zu 2. Referenzhöhe: 3.75 m; Höhe zu Meereshöhe: 19.75 m; Höhe zu verknüpftem/Ursprungsgeschoss: 0 m; Abstand zu Ursprungsgeschoss: 0 m; Abstand Oberkante: 0 m; Oberflächenbereich: 15.3276 m2; 3D-Länge: 5.28538 m; Dicke: 0.265 m; Konditionales Volumen: 3.69835 m3; Brutto-Volumen: 4.07719 m3; Dämmungsschichtdicke: 0 m; Grundriss-Umfang: 10.96 m; Anzahl der Türen: 0; Anzahl der Durchbrüche (Anzahl der leeren Öffnungen): 0; Anzahl der Fenster: 0; Anzahl der Stützen: 0; Volumen der Stützen: 0 m3; Maximale Höhe der Wandschicht an der Innenseite: 2.75 m; Minimale Höhe der Wandschicht an der Innenseite: 0 m; Maximale Höhe der Wand: 2.9 m; Minimale Höhe der Wand: 0 m; Maximale Höhe der Wandschicht an der Außenseite: 2.9 m; Minimale Höhe der Wandschicht an der Außenseite: 0 m; Luftschichtdicke: 0 m; Fläche der Türen: 0 m2; Kombinierte Breite der Türen: 0 m; Wand-Schichtdicke an der Innenseite: 0.02 m; Wand-Schichtdicke an der Außenseite: 0.02 m; Fläche der Fenster: 0 m2; Kombinierte Breite der Fenster: 0 m; Wand-Schichtvolumen an der Innenseite: 0.266242 m3; Wand-Schichtvolumen an der Außenseite: 0.306552 m3; Analytische Oberfläche der Öffnungen an der Innenseite: 0 m2; Analytische Oberfläche der Öffnungen an der Außenseite: 0 m2; Durchschnittliche Länge der Wand: 5.11788 m; Netto-Oberflächenbereich an den Kanten: 2.42713 m2; Netto-Oberflächenbereich an der Innenseite: 13.312 m2; Netto-Oberflächenbereich an der Außenseite: 15.3276 m2; Analytisches Volumen der Öffnungen: 0 m3; Länge der Referenzlinie: 4.93038 m; Konditionale Länge an der Innenseite: 4.93038 m; Konditionaler Oberflächenbereich an der Innenseite: 13.312 m2; Konditionale Länge an der Außenseite: 5.30538 m; Konditionaler Oberflächenbereich an der Außenseite: 15.3276 m2; Konditionales Wand-Schichtvolumen an der Innenseite: 0.266241 m3; Konditionales Schichtvolumen an der Außenseite: 0.306552 m3; Brutto-Wandoberflächenbereich an der Innenseite: 15.3856 m2; Brutto-Wandoberflächenbereich an der Außenseite: 15.3856 m2; Wandstärke am Ende: 0.265 m; Länge der Wand in der Achse: 5.11788 m; Wandlänge an der Innenseite: 4.93038 m; Wandlänge an der Außenseite: 5.30538 m; Fläche der Wand: 1.35624 m2; Oberflächenbereich der leeren Öffnungen in der Wand: 0 m2
Component Quantities - Component 1, Masse: 551.794 kg; Component 1, Schicht/Komponente Oberflächenbereich: 15.3276 m2; Component 1, Schichtdicke: 0.02 m; Component 1, Schicht/Komponente Höhe (rechteckig): 2.9 m; Component 1, Schicht/Komponente Breite (rechteckig): 0.02 m; Component 1, Schicht/Komponente Querschnittsbereich: 0.058 m2; Component 1, Schicht/Komponente Volumen: 0.306552 m3; Component 2, Masse: 118.909 kg; Component 2, Schicht/Komponente Oberflächenbereich: 14.8636 m2; Component 2, Schichtdicke: 0.05 m; Component 2, Schicht/Komponente Höhe (rechteckig): 2.9 m; Component 2, Schicht/Komponente Breite (rechteckig): 0.05 m; Component 2, Schicht/Komponente Querschnittsbereich: 0.145 m2; Component 2, Schicht/Komponente Volumen: 0.743181 m3; Component 3, Masse: 4288.27 kg; Component 3, Schicht/Komponente Oberflächenbereich: 13.6136 m2; Component 3, Schichtdicke: 0.175 m; Component 3, Schicht/Komponente Höhe (rechteckig): 2.9 m; Component 3, Schicht/Komponente Breite (rechteckig): 0.175 m; Component 3, Schicht/Komponente Querschnittsbereich: 0.5075 m2; Component 3, Schicht/Komponente Volumen: 2.38237 m3; Component 4, Masse: 479.236 kg; Component 4, Schicht/Komponente Oberflächenbereich: 13.312 m2; Component 4, Schichtdicke: 0.02 m; Component 4, Schicht/Komponente Höhe (rechteckig): 2.9 m; Component 4, Schicht/Komponente Breite (rechteckig): 0.02 m; Component 4, Schicht/Komponente Querschnittsbereich: 0.058 m2; Component 4, Schicht/Komponente Volumen: 0.266242 m3

# IfcWall: WA | StB Kellerwand + WD 380, Wand-003
In: R-024
Classification: Wand (ARCHICAD Klassifizierung); Material: Dämmung, hart XPS, Beton, WU-Beton
Pset_ConcreteElementGeneral - FireRating: F 90
Pset_WallCommon - FireRating: F 90; LoadBearing: yes; IsExternal: yes
Pset_FireRatingProperties - FireResistanceRating: F 90
ArchiCADProperties - Element ID: Wand-003; Hotlink und Element-ID: Wand-003; Ebene: Wand Aussen; Baustoff / Mehrschichtiger Aufbau / Profil / Schraffur: WA | StB Kellerwand + WD; Mehrschichtige Bauteile: WA | StB Kellerwand + WD; Kollidierende Räume: Gelände; Treppenhaus UG; Untergeschoss UG; Zugehöriger Raumname: Treppenhaus; Zugehörige Raumnummer: R-010; Geschützt: no; Ursprungsgeschoss Name: -1. Geschoss; Ursprungsgeschoss Nummer: -1; Typ: Wand; Absolutes Geschoss für Oberkantenverknüpfung: Nicht verknüpft; Relatives Geschoss für Oberkantenverknüpfung: Nicht verknüpft; Geschoss für Oberkantenverknüpfung: Nicht verknüpft; Struktur-Typ: Mehrschicht; Überobjekt-ID: Wand-003; Baustoffe (Alle): Dämmung, hart XPS; Beton, WU-Beton; Oberfläche (Alle): Beton, Sichtbeton 2; Farbe, hellblau; Neigungswinkel: 90 deg; Lage: Außen; Tragende Funktion: Tragende Elemente; Anzeigen auf Umbau-Filter: Alle relevanten Filter; Umbau-Status: Bestand; Wandkomplexität: gerade; Geometriemethode: Uni; Lage der Referenzlinie: Kern Außen; Innenseite Oberfläche: Beton, Sichtbeton 2; Außenseite Oberfläche: Farbe, hellblau; Wand Innerer Neigungswinkel: 90 deg; Wand Äußerer Neigungswinkel: 90 deg; ARCHICAD Klassifizierung - 22: Wand
Brandschutz 4102-2 - Feuerwiderstand 4102-2: F 90; Brandwand: yes; Minuten (4102-2): 90; Baustoffklasse: A; Kennbuchstabe: F
Component Properties - Component 1, Enthaltenes CO2: 84.5662 (kgCO₂); Component 1, Enthaltene Energie: 2161.14 MJ; Component 1, Komponenten-Typ: Andere; Component 2, Enthaltenes CO2: 365.041 (kgCO₂); Component 2, Enthaltene Energie: 2433.61 MJ; Component 2, Komponenten-Typ: Kern
BaseQuantities - Length: 3.44 m; Height: 2.2 m; Width: 0.38 m; GrossFootprintArea: 1.3072 m2; NetFootprintArea: 1.3072 m2; GrossSideArea: 7.689 m2; NetSideArea: 5.6589 m2; GrossVolume: 2.85692 m3; NetVolume: 2.08548 m3
ArchiCADQuantities - Fläche: 1.3072 m2; Höhe: 2.2 m; Netto-Volumen: 2.08548 m3; Breite: 0.38 m; Höhenangabe zum Projekt-Nullpunkt: -2.8 m; Höhe zu 1. Referenzhöhe: -2.8 m; Höhe zu 2. Referenzhöhe: -2.8 m; Höhe zu Meereshöhe: 13.2 m; Höhe zu verknüpftem/Ursprungsgeschoss: 0 m; Abstand zu Ursprungsgeschoss: 0 m; Abstand Oberkante: 0 m; Oberflächenbereich: 6.3079 m2; 3D-Länge: 3.79 m; Dicke: 0.38 m; Konditionales Volumen: 2.08548 m3; Brutto-Volumen: 3.45532 m3; Dämmungsschichtdicke: 0.14 m; Grundriss-Umfang: 7.64 m; Anzahl der Türen: 1; Anzahl der Durchbrüche (Anzahl der leeren Öffnungen): 0; Anzahl der Fenster: 0; Anzahl der Stützen: 0; Volumen der Stützen: 0 m3; Maximale Höhe der Wandschicht an der Innenseite: 2.2 m; Minimale Höhe der Wandschicht an der Innenseite: 0 m; Maximale Höhe der Wand: 2.2 m; Minimale Höhe der Wand: 0 m; Maximale Höhe der Wandschicht an der Außenseite: 2.2 m; Minimale Höhe der Wandschicht an der Außenseite: 0 m; Luftschichtdicke: 0 m; Fläche der Türen: 2.0301 m2; Kombinierte Breite der Türen: 1.01 m; Wand-Schichtdicke an der Innenseite: 0.24 m; Wand-Schichtdicke an der Außenseite: 0.14 m; Fläche der Fenster: 0 m2; Kombinierte Breite der Fenster: 0 m; Wand-Schichtvolumen an der Innenseite: 1.20238 m3; Wand-Schichtvolumen an der Außenseite: 0.883106 m3; Analytische Oberfläche der Öffnungen an der Innenseite: 2.0301 m2; Analytische Oberfläche der Öffnungen an der Außenseite: 2.0301 m2; Durchschnittliche Länge der Wand: 3.44 m; Netto-Oberflächenbereich an den Kanten: 2.2134 m2; Netto-Oberflächenbereich an der Innenseite: 5.0099 m2; Netto-Oberflächenbereich an der Außenseite: 6.3079 m2; Analytisches Volumen der Öffnungen: 0.771438 m3; Länge der Referenzlinie: 3.44 m; Konditionale Länge an der Innenseite: 2.43 m; Konditionaler Oberflächenbereich an der Innenseite: 7.04 m2; Konditionale Länge an der Außenseite: 2.43 m; Konditionaler Oberflächenbereich an der Außenseite: 8.338 m2; Konditionales Wand-Schichtvolumen an der Innenseite: 1.6896 m3; Konditionales Schichtvolumen an der Außenseite: 1.16732 m3; Brutto-Wandoberflächenbereich an der Innenseite: 9.174 m2; Brutto-Wandoberflächenbereich an der Außenseite: 8.954 m2; Wandstärke am Ende: 0.38 m; Länge der Wand in der Achse: 3.44 m; Wandlänge an der Innenseite: 3.44 m; Wandlänge an der Außenseite: 3.44 m; Fläche der Wand: 1.3072 m2; Oberflächenbereich der leeren Öffnungen in der Wand: 0 m2
Component Quantities - Component 1, Masse: 24.727 kg; Component 1, Schicht/Komponente Oberflächenbereich: 6.3079 m2; Component 1, Schichtdicke: 0.14 m; Component 1, Schicht/Komponente Höhe (rechteckig): 2.2 m; Component 1, Schicht/Komponente Breite (rechteckig): 0.14 m; Component 1, Schicht/Komponente Querschnittsbereich: 0.308 m2; Component 1, Schicht/Komponente Volumen: 0.883106 m3; Component 2, Masse: 2765.46 kg; Component 2, Schicht/Komponente Oberflächenbereich: 5.0099 m2; Component 2, Schichtdicke: 0.24 m; Component 2, Schicht/Komponente Höhe (rechteckig): 2.2 m; Component 2, Schicht/Komponente Breite (rechteckig): 0.24 m; Component 2, Schicht/Komponente Querschnittsbereich: 0.528 m2; Component 2, Schicht/Komponente Volumen: 1.20238 m3

# IfcWall: WA | StB Kellerwand 17 + WD 315 (3)
Classification: Wand (ARCHICAD Klassifizierung)
ArchiCADProperties - Ebene: Wand Aussen; Baustoff / Mehrschichtiger Aufbau / Profil / Schraffur: WA | StB Kellerwand 17 + WD; Mehrschichtige Bauteile: WA | StB Kellerwand 17 + WD; Zugehöriger Raumname: Treppenhaus; Zugehörige Raumnummer: R-010; Geschützt: no; Ursprungsgeschoss Name: -1. Geschoss; Ursprungsgeschoss Nummer: -1; Typ: Wand; Absolutes Geschoss für Oberkantenverknüpfung: Nicht verknüpft; Relatives Geschoss für Oberkantenverknüpfung: Nicht verknüpft; Geschoss für Oberkantenverknüpfung: Nicht verknüpft; Struktur-Typ: Mehrschicht; Baustoffe (Alle): Dämmung, hart XPS; Beton, WU-Beton; Oberfläche (Alle): Beton, Sichtbeton 2; Farbe, hellblau; Neigungswinkel: 90 deg; Lage: Außen; Tragende Funktion: Tragende Elemente; Anzeigen auf Umbau-Filter: Alle relevanten Filter; Umbau-Status: Bestand; Wandkomplexität: gerade; Geometriemethode: Uni; Lage der Referenzlinie: Innen; Innenseite Oberfläche: Beton, Sichtbeton 2; Außenseite Oberfläche: Farbe, hellblau; Wand Innerer Neigungswinkel: 90 deg; Wand Äußerer Neigungswinkel: 90 deg; ARCHICAD Klassifizierung - 22: Wand
Brandschutz 4102-2 - Kennbuchstabe: F
Pset_WallCommon - LoadBearing: yes; IsExternal: yes
BaseQuantities - Height: 2.8 m; Width: 0.315 m
ArchiCADQuantities - Höhe: 2.8 m; Breite: 0.315 m; Höhenangabe zum Projekt-Nullpunkt: -2.8 m; Höhe zu 1. Referenzhöhe: -2.8 m; Höhe zu 2. Referenzhöhe: -2.8 m; Höhe zu Meereshöhe: 13.2 m; Höhe zu verknüpftem/Ursprungsgeschoss: 0 m; Abstand zu Ursprungsgeschoss: 0 m; Abstand Oberkante: 0 m; Dicke: 0.315 m; Dämmungsschichtdicke: 0.14 m; Anzahl der Türen: 0; Anzahl der Durchbrüche (Anzahl der leeren Öffnungen): 0; Anzahl der Stützen: 0; Volumen der Stützen: 0 m3; Maximale Höhe der Wandschicht an der Innenseite: 2.8 m; Minimale Höhe der Wandschicht an der Innenseite: 0 m; Maximale Höhe der Wand: 2.8 m; Minimale Höhe der Wand: 0 m; Maximale Höhe der Wandschicht an der Außenseite: 2.8 m; Minimale Höhe der Wandschicht an der Außenseite: 0 m; Luftschichtdicke: 0 m; Fläche der Türen: 0 m2; Kombinierte Breite der Türen: 0 m; Wand-Schichtdicke an der Innenseite: 0.175 m; Wand-Schichtdicke an der Außenseite: 0.14 m; Wandstärke am Ende: 0.315 m; Oberflächenbereich der leeren Öffnungen in der Wand: 0 m2
Component Quantities - Component 2, Schicht/Komponente Höhe (rechteckig): 2.8 m; Component 1, Schicht/Komponente Höhe (rechteckig): 2.8 m
Name | In | Material | Element ID = Hotlink und Element-ID = Überobjekt-ID | Kollidierende Räume | Component 2, Enthaltenes CO2 | Component 2, Enthaltene Energie (MJ) | Component 2, Komponenten-Typ | Component 1, Enthaltenes CO2 | Component 1, Enthaltene Energie (MJ) | Component 1, Komponenten-Typ | Length (m) = Durchschnittliche Länge der Wand (m) = Länge der Wand in der Achse (m) | GrossFootprintArea (m2) = NetFootprintArea (m2) = Fläche (m2) = Fläche der Wand (m2) | GrossSideArea (m2) | NetSideArea (m2) | GrossVolume (m3) = Konditionales Volumen (m3) | NetVolume (m3) = Netto-Volumen (m3) | Oberflächenbereich (m2) = Netto-Oberflächenbereich an der Außenseite (m2) | 3D-Länge (m) | Brutto-Volumen (m3) | Grundriss-Umfang (m) | Anzahl der Fenster | Fläche der Fenster (m2) | Kombinierte Breite der Fenster (m) | Wand-Schichtvolumen an der Innenseite (m3) | Wand-Schichtvolumen an der Außenseite (m3) | Analytische Oberfläche der Öffnungen an der Innenseite (m2) | Analytische Oberfläche der Öffnungen an der Außenseite (m2) | Netto-Oberflächenbereich an den Kanten (m2) | Netto-Oberflächenbereich an der Innenseite (m2) | Analytisches Volumen der Öffnungen (m3) | Länge der Referenzlinie (m) = Konditionale Länge an der Innenseite (m) = Wandlänge an der Innenseite (m) | Konditionaler Oberflächenbereich an der Innenseite (m2) | Konditionale Länge an der Außenseite (m) = Wandlänge an der Außenseite (m) | Konditionaler Oberflächenbereich an der Außenseite (m2) | Konditionales Wand-Schichtvolumen an der Innenseite (m3) | Konditionales Schichtvolumen an der Außenseite (m3) | Brutto-Wandoberflächenbereich an der Innenseite (m2) = Brutto-Wandoberflächenbereich an der Außenseite (m2) | Component 2, Masse (kg) | Component 2, Schicht/Komponente Oberflächenbereich (m2) | Component 2, Schichtdicke (m) = Component 2, Schicht/Komponente Breite (rechteckig) (m) | Component 2, Schicht/Komponente Querschnittsbereich (m2) | Component 2, Schicht/Komponente Volumen (m3) | Component 1, Masse (kg) | Component 1, Schicht/Komponente Oberflächenbereich (m2) | Component 1, Schichtdicke (m) = Component 1, Schicht/Komponente Breite (rechteckig) (m) | Component 1, Schicht/Komponente Querschnittsbereich (m2) | Component 1, Schicht/Komponente Volumen (m3)
Wand-001 | R-024 | Beton, WU-Beton, Dämmung, hart XPS | Wand-001 | Treppenhaus UG; Untergeschoss UG | 118.432 (kgCO₂) | 3026.6 | Andere | 443.317 (kgCO₂) | 2955.44 | Kern | 3.2775 | 1.03241 | 8.827 | 8.589 | 2.76654 | 2.69696 | 8.834 | 3.155 | 3.02967 | 7.31548 | 1 | 0.14 | 0.14 | 1.4602 | 1.23676 | 0.084 | 0.392 | 1.9264 | 8.344 | 0.06958 | 3.12 | 8.428 | 3.435 | 9.226 | 1.4749 | 1.29164 | 9.618 | 34.6293 | 8.834 | 0.14 | 0.392 | 1.23676 | 3358.46 | 8.344 | 0.175 | 0.49 | 1.4602
Wand-001 | R-023 | Dämmung, hart XPS, Beton, WU-Beton | Wand-001 | Gelände; Treppenhaus UG | 471.21 (kgCO₂) | 3141.4 | Kern | 124.157 (kgCO₂) | 3172.89 | Andere | 3.2775 | 1.03241 | 9.268 | 9.065 | 2.90717 | 2.84862 | 9.261 | 3.435 | 3.02967 | 7.31548 | 1 | 0.357 | 0.14 | 1.55208 | 1.29654 | 0.049 | 0.357 | 2.1497 | 8.869 | 0.058555 | 3.12 | 8.918 | 3.435 | 9.618 | 1.56065 | 1.34652 | 9.618 | 3569.77 | 8.869 | 0.175 | 0.49 | 1.55208 | 36.3031 | 9.261 | 0.14 | 0.392 | 1.29654
Wand-002 | R-023 | Dämmung, hart XPS, Beton, WU-Beton | Wand-002 | Treppenhaus; Treppenhaus UG | 537.782 (kgCO₂) | 3585.21 | Kern | 147.524 (kgCO₂) | 3770.06 | Andere | 3.755 | 1.18283 | 10.563 | 10.563 | 3.31191 | 3.31191 | 11.004 | 3.93 | 3.58974 | 8.40095 | 0 | 0 | 0 | 1.77135 | 1.54056 | 0 | 0 | 2.36565 | 10.122 | 0 | 3.44 | 10.122 | 4.07 | 11.004 | 1.77135 | 1.54056 | 11.396 | 4074.11 | 10.122 | 0.175 | 0.49 | 1.77135 | 43.1357 | 11.004 | 0.14 | 0.392 | 1.54056

# IfcWall: WA | Stahlbeton 24cm 240 (5)
Classification: Wand (ARCHICAD Klassifizierung); Material: Beton, WU-Beton
ArchiCADProperties - Baustoff / Mehrschichtiger Aufbau / Profil / Schraffur: WA | Stahlbeton 24cm; Mehrschichtige Bauteile: WA | Stahlbeton 24cm; Geschützt: no; Ursprungsgeschoss Name: -1. Geschoss; Ursprungsgeschoss Nummer: -1; Typ: Wand; Absolutes Geschoss für Oberkantenverknüpfung: Nicht verknüpft; Relatives Geschoss für Oberkantenverknüpfung: Nicht verknüpft; Geschoss für Oberkantenverknüpfung: Nicht verknüpft; Struktur-Typ: Mehrschicht; Baustoffe (Alle): Beton, WU-Beton; Neigungswinkel: 90 deg; Anzeigen auf Umbau-Filter: Alle relevanten Filter; Umbau-Status: Bestand; Wandkomplexität: gerade; Geometriemethode: Uni; Lage der Referenzlinie: Außen; Innenseite Oberfläche: Beton, Sichtbeton 2; Außenseite Oberfläche: Beton, Sichtbeton 2; Wand Innerer Neigungswinkel: 90 deg; Wand Äußerer Neigungswinkel: 90 deg; ARCHICAD Klassifizierung - 22: Wand
Brandschutz 4102-2 - Kennbuchstabe: F
Component Properties - Component 1, Komponenten-Typ: Kern
BaseQuantities - Height: 2.55 m; Width: 0.24 m
ArchiCADQuantities - Höhe: 2.55 m; Breite: 0.24 m; Höhenangabe zum Projekt-Nullpunkt: -2.8 m; Höhe zu 1. Referenzhöhe: -2.8 m; Höhe zu 2. Referenzhöhe: -2.8 m; Höhe zu Meereshöhe: 13.2 m; Höhe zu verknüpftem/Ursprungsgeschoss: 0 m; Abstand zu Ursprungsgeschoss: 0 m; Dicke: 0.24 m; Dämmungsschichtdicke: 0 m; Anzahl der Durchbrüche (Anzahl der leeren Öffnungen): 0; Anzahl der Fenster: 0; Anzahl der Stützen: 0; Volumen der Stützen: 0 m3; Maximale Höhe der Wandschicht an der Innenseite: 2.55 m; Minimale Höhe der Wandschicht an der Innenseite: 0 m; Maximale Höhe der Wand: 2.55 m; Minimale Höhe der Wand: 0 m; Maximale Höhe der Wandschicht an der Außenseite: 2.55 m; Minimale Höhe der Wandschicht an der Außenseite: 0 m; Luftschichtdicke: 0 m; Wand-Schichtdicke an der Innenseite: 0.24 m; Wand-Schichtdicke an der Außenseite: 0.24 m; Fläche der Fenster: 0 m2; Kombinierte Breite der Fenster: 0 m; Wandstärke am Ende: 0.24 m; Oberflächenbereich der leeren Öffnungen in der Wand: 0 m2
Component Quantities - Component 1, Schichtdicke: 0.24 m; Component 1, Schicht/Komponente Höhe (rechteckig): 2.55 m; Component 1, Schicht/Komponente Breite (rechteckig): 0.24 m; Component 1, Schicht/Komponente Querschnittsbereich: 0.612 m2
Name | In | Element ID = Hotlink und Element-ID = Überobjekt-ID | Ebene | Kollidierende Räume | Zugehöriger Raumname | Zugehörige Raumnummer | Oberfläche (Alle) | Lage | Tragende Funktion | LoadBearing = IsExternal | Component 1, Enthaltenes CO2 | Component 1, Enthaltene Energie (MJ) | Length (m) = Durchschnittliche Länge der Wand (m) = Länge der Wand in der Achse (m) | GrossFootprintArea (m2) = NetFootprintArea (m2) = Fläche (m2) = Fläche der Wand (m2) | GrossSideArea (m2) = Konditionaler Oberflächenbereich an der Innenseite (m2) = Konditionaler Oberflächenbereich an der Außenseite (m2) | NetSideArea (m2) = Oberflächenbereich (m2) = Netto-Oberflächenbereich an der Innenseite (m2) = Netto-Oberflächenbereich an der Außenseite (m2) = Component 1, Schicht/Komponente Oberflächenbereich (m2) | GrossVolume (m3) = Konditionales Volumen (m3) = Konditionales Wand-Schichtvolumen an der Innenseite (m3) = Konditionales Schichtvolumen an der Außenseite (m3) | NetVolume (m3) = Netto-Volumen (m3) = Wand-Schichtvolumen an der Innenseite (m3) = Wand-Schichtvolumen an der Außenseite (m3) = Component 1, Schicht/Komponente Volumen (m3) | Abstand Oberkante (m) | 3D-Länge (m) | Brutto-Volumen (m3) | Grundriss-Umfang (m) | Anzahl der Türen | Fläche der Türen (m2) = Analytische Oberfläche der Öffnungen an der Innenseite (m2) = Analytische Oberfläche der Öffnungen an der Außenseite (m2) | Kombinierte Breite der Türen (m) | Netto-Oberflächenbereich an den Kanten (m2) | Analytisches Volumen der Öffnungen (m3) | Länge der Referenzlinie (m) = Wandlänge an der Außenseite (m) | Konditionale Länge an der Innenseite (m) | Konditionale Länge an der Außenseite (m) | Brutto-Wandoberflächenbereich an der Innenseite (m2) = Brutto-Wandoberflächenbereich an der Außenseite (m2) | Wandlänge an der Innenseite (m) | Component 1, Masse (kg)
Wand-005 | R-016 | Wand-005 | Wand Aussen | Gelände; Tiefgaragenabfahrt; Untergeschoss UG | Garage | R-013 | Beton, Sichtbeton 2 | Außen | Tragende Elemente | yes | 2787.05 (kgCO₂) | 18580.3 | 15 | 3.6 | 38.25 | 38.25 | 9.18 | 9.18 | -0.25 | 15 | 9.47376 | 30.48 | 0 | 0 | 0 | 7.2 | 0 | 15 | 15 | 15 | 39.474 | 15 | 21114
Wand-004 | R-024 | Wand-004 | Wand Aussen | Treppenhaus; Untergeschoss UG | Treppenhaus | R-010 | Beton, Sichtbeton 2; Metall, Fassade Edelstahl | Außen | Tragende Elemente | yes | 2853.56 (kgCO₂) | 19023.7 | 15.36 | 3.6864 | 39.1628 | 39.1628 | 9.39906 | 9.39906 | -0.25 | 15.48 | 9.47376 | 31.2994 | 0 | 0 | 0 | 7.98129 | 0 | 15.24 | 15.48 | 15.24 | 39.474 | 15.48 | 21617.8
Wand-007 | R-024 | Wand-007 | Wand Innen | Untergeschoss UG | Keller | R-014 | Beton, Sichtbeton 2 | Innen | Nicht tragende Elemente | no | 743.213 (kgCO₂) | 4954.75 | 4 | 0.96 | 10.2 | 10.2 | 2.448 | 2.448 | -0.25 | 4 | 2.74176 | 8.48 | 0 | 0 | 0 | 1.92 | 0 | 4 | 4 | 4 | 11.424 | 4 | 5630.4
Wand-004 | R-024 | Wand-004 | Wand Aussen | Gelände; Untergeschoss UG | Keller | R-014 | Beton, Sichtbeton 2 | Außen | Tragende Elemente | yes | 1345.22 (kgCO₂) | 8968.1 | 7.36 | 1.7664 | 18.462 | 18.462 | 4.43088 | 4.43088 | -4 | 7.24 | 4.57776 | 15.2994 | 0 | 0 | 0 | 4.0872 | 0 | 7.24 | 7.48 | 7.24 | 19.074 | 7.48 | 10191
Wand-006 | R-024 | Wand-006 | Wand Innen | Untergeschoss UG | Garage | R-013 | Beton, Sichtbeton 2 | Innen | Nicht tragende Elemente | no | 1004.78 (kgCO₂) | 6698.53 | 7 | 1.68 | 17.85 | 13.7898 | 4.284 | 3.30955 | -0.25 | 7 | 4.57776 | 14.48 | 2 | 4.0602 | 2.02 | 2.8752 | 0.974448 | 7 | 4.98 | 4.98 | 19.074 | 7 | 7611.97

# IfcWall: WA | Wärmedämmung+Putz 180 (2)
In: EG
Classification: Wand (ARCHICAD Klassifizierung)
ArchiCADProperties - Element ID: Wand-010; Hotlink und Element-ID: Wand-010; Baustoff / Mehrschichtiger Aufbau / Profil / Schraffur: WA | Wärmedämmung+Putz; Mehrschichtige Bauteile: WA | Wärmedämmung+Putz; Geschützt: no; Ursprungsgeschoss Name: EG; Ursprungsgeschoss Nummer: 0; Typ: Wand; Absolutes Geschoss für Oberkantenverknüpfung: Nicht verknüpft; Relatives Geschoss für Oberkantenverknüpfung: Nicht verknüpft; Geschoss für Oberkantenverknüpfung: Nicht verknüpft; Struktur-Typ: Mehrschicht; Überobjekt-ID: Wand-010; Baustoffe (Alle): Verputz, Kalkzement; Dämmung, weich Mineralwolle 2; Oberfläche (Alle): Verputz, glatt, weiß; Mineralwolle; Neigungswinkel: 90 deg; Tragende Funktion: Nicht tragende Elemente; Anzeigen auf Umbau-Filter: Alle relevanten Filter; Umbau-Status: Bestand; Wandkomplexität: gerade; Geometriemethode: Uni; Lage der Referenzlinie: Außen; Innenseite Oberfläche: Mineralwolle; Außenseite Oberfläche: Verputz, glatt, weiß; Wand Innerer Neigungswinkel: 90 deg; Wand Äußerer Neigungswinkel: 90 deg; ARCHICAD Klassifizierung - 22: Wand
Pset_WallCommon - LoadBearing: no
BaseQuantities - Length: 0.05 m; Width: 0.18 m; GrossFootprintArea: 0.009 m2; NetFootprintArea: 0.009 m2
ArchiCADQuantities - Fläche: 0.009 m2; Breite: 0.18 m; 3D-Länge: 0.05 m; Dicke: 0.18 m; Dämmungsschichtdicke: 0 m; Grundriss-Umfang: 0.46 m; Anzahl der Türen: 0; Anzahl der Durchbrüche (Anzahl der leeren Öffnungen): 0; Anzahl der Fenster: 0; Anzahl der Stützen: 0; Volumen der Stützen: 0 m3; Luftschichtdicke: 0 m; Fläche der Türen: 0 m2; Kombinierte Breite der Türen: 0 m; Wand-Schichtdicke an der Innenseite: 0.16 m; Wand-Schichtdicke an der Außenseite: 0.02 m; Fläche der Fenster: 0 m2; Kombinierte Breite der Fenster: 0 m; Analytische Oberfläche der Öffnungen an der Innenseite: 0 m2; Analytische Oberfläche der Öffnungen an der Außenseite: 0 m2; Durchschnittliche Länge der Wand: 0.05 m; Analytisches Volumen der Öffnungen: 0 m3; Länge der Referenzlinie: 0.05 m; Konditionale Länge an der Innenseite: 0.05 m; Konditionale Länge an der Außenseite: 0.05 m; Wandstärke am Ende: 0.18 m; Länge der Wand in der Achse: 0.05 m; Wandlänge an der Innenseite: 0.05 m; Wandlänge an der Außenseite: 0.05 m; Fläche der Wand: 0.009 m2; Oberflächenbereich der leeren Öffnungen in der Wand: 0 m2
Name | Material | Ebene | Kollidierende Räume | Zugehöriger Raumname | Zugehörige Raumnummer | Lage | Kennbuchstabe | IsExternal | Component 2, Enthaltenes CO2 | Component 2, Enthaltene Energie (MJ) | Component 2, Komponenten-Typ | Component 1, Enthaltenes CO2 | Component 1, Enthaltene Energie (MJ) | Component 1, Komponenten-Typ | Height (m) = Höhe (m) = Maximale Höhe der Wandschicht an der Innenseite (m) = Minimale Höhe der Wandschicht an der Innenseite (m) = Maximale Höhe der Wand (m) = Minimale Höhe der Wand (m) = Maximale Höhe der Wandschicht an der Außenseite (m) = Minimale Höhe der Wandschicht an der Außenseite (m) = Component 2, Schicht/Komponente Höhe (rechteckig) (m) = Component 1, Schicht/Komponente Höhe (rechteckig) (m) | GrossSideArea (m2) = NetSideArea (m2) = Oberflächenbereich (m2) = Netto-Oberflächenbereich an der Innenseite (m2) = Netto-Oberflächenbereich an der Außenseite (m2) = Konditionaler Oberflächenbereich an der Innenseite (m2) = Konditionaler Oberflächenbereich an der Außenseite (m2) = Brutto-Wandoberflächenbereich an der Innenseite (m2) = Brutto-Wandoberflächenbereich an der Außenseite (m2) = Component 2, Schicht/Komponente Oberflächenbereich (m2) = Component 1, Schicht/Komponente Oberflächenbereich (m2) | GrossVolume (m3) = NetVolume (m3) = Netto-Volumen (m3) = Konditionales Volumen (m3) = Brutto-Volumen (m3) | Höhenangabe zum Projekt-Nullpunkt (m) = Höhe zu 1. Referenzhöhe (m) = Höhe zu 2. Referenzhöhe (m) = Höhe zu verknüpftem/Ursprungsgeschoss (m) = Abstand zu Ursprungsgeschoss (m) | Höhe zu Meereshöhe (m) | Abstand Oberkante (m) | Wand-Schichtvolumen an der Innenseite (m3) = Konditionales Wand-Schichtvolumen an der Innenseite (m3) | Wand-Schichtvolumen an der Außenseite (m3) = Konditionales Schichtvolumen an der Außenseite (m3) | Netto-Oberflächenbereich an den Kanten (m2) | Component 2, Masse (kg) | Component 2, Schichtdicke (m) = Component 2, Schicht/Komponente Breite (rechteckig) (m) | Component 2, Schicht/Komponente Querschnittsbereich (m2) | Component 2, Schicht/Komponente Volumen (m3) | Component 1, Masse (kg) | Component 1, Schichtdicke (m) = Component 1, Schicht/Komponente Breite (rechteckig) (m) | Component 1, Schicht/Komponente Querschnittsbereich (m2) | Component 1, Schicht/Komponente Volumen (m3)
Wand-010 | Dämmung, weich Mineralwolle 2, Verputz, Kalkzement | Wand Aussen | Erdgeschoss; Grundfläche Gebäude Nachgezogen; Wohnung1 EG; Wohnung2 EG | Wohnung2 EG | R-020 | Außen | W | yes | 1.32 (kgCO₂) | 8.7 | Bekleidung | 8.304 (kgCO₂) | 112.32 | Andere | 3.75 | 0.1875 | 0.03375 | 0 | 16 | 0 | 0.03 | 0.00375 | 1.368 | 6 | 0.02 | 0.075 | 0.00375 | 4.8 | 0.16 | 0.6 | 0.03
Wand-010 | Verputz, Kalkzement, Dämmung, weich Mineralwolle 2 | Wand Innen | Erdgeschoss; Grundfläche Gebäude Nachgezogen; Untergeschoss UG; Wohnung1 EG; Wohnung2 EG | Treppenhaus | R-010 | Innen | F | no | 7.97184 (kgCO₂) | 107.827 | Andere | 1.2672 (kgCO₂) | 8.352 | Bekleidung | 3.6 | 0.18 | 0.0324 | -0.3 | 15.7 | -0.45 | 0.0288 | 0.0036 | 1.314 | 4.608 | 0.16 | 0.576 | 0.0288 | 5.76 | 0.02 | 0.072 | 0.0036

# IfcWall: WI | GK 12 2-lagig 125 (6)
In: EG
Classification: Wand (ARCHICAD Klassifizierung); Material: Gipskarton (4), Dämmung, weich Glaswolle
ArchiCADProperties - Ebene: Wand Innen Ausbau; Baustoff / Mehrschichtiger Aufbau / Profil / Schraffur: WI | GK 12 2-lagig; Mehrschichtige Bauteile: WI | GK 12 2-lagig; Geschützt: no; Ursprungsgeschoss Name: EG; Ursprungsgeschoss Nummer: 0; Typ: Wand; Absolutes Geschoss für Oberkantenverknüpfung: Nicht verknüpft; Relatives Geschoss für Oberkantenverknüpfung: Nicht verknüpft; Geschoss für Oberkantenverknüpfung: Nicht verknüpft; Struktur-Typ: Mehrschicht; Baustoffe (Alle): Gipskarton; Gipskarton; Dämmung, weich Glaswolle; Gipskarton; Gipskarton; Oberfläche (Alle): Farbe, weiß; Mineralwolle; Neigungswinkel: 90 deg; Lage: Innen; Tragende Funktion: Nicht tragende Elemente; Anzeigen auf Umbau-Filter: Alle relevanten Filter; Umbau-Status: Bestand; Wandkomplexität: gerade; Geometriemethode: Uni; Innenseite Oberfläche: Farbe, weiß; Außenseite Oberfläche: Farbe, weiß; Wand Innerer Neigungswinkel: 90 deg; Wand Äußerer Neigungswinkel: 90 deg; ARCHICAD Klassifizierung - 22: Wand
Brandschutz 4102-2 - Brandwand: no; Kennbuchstabe: F
Pset_WallCommon - LoadBearing: no; IsExternal: no
Component Properties - Component 1, Komponenten-Typ: Kern; Component 2, Komponenten-Typ: Kern; Component 3, Komponenten-Typ: Kern; Component 4, Komponenten-Typ: Kern; Component 5, Komponenten-Typ: Kern
BaseQuantities - Height: 3.5 m; Width: 0.125 m
ArchiCADQuantities - Höhe: 3.75 m; Breite: 0.125 m; Höhenangabe zum Projekt-Nullpunkt: 0 m; Höhe zu 1. Referenzhöhe: 0 m; Höhe zu 2. Referenzhöhe: 0 m; Höhe zu Meereshöhe: 16 m; Höhe zu verknüpftem/Ursprungsgeschoss: 0 m; Abstand zu Ursprungsgeschoss: 0 m; Abstand Oberkante: 0 m; Dicke: 0.125 m; Dämmungsschichtdicke: 0.075 m; Anzahl der Durchbrüche (Anzahl der leeren Öffnungen): 0; Anzahl der Fenster: 0; Anzahl der Stützen: 0; Volumen der Stützen: 0 m3; Maximale Höhe der Wandschicht an der Innenseite: 3.5 m; Minimale Höhe der Wandschicht an der Innenseite: 0 m; Maximale Höhe der Wand: 3.5 m; Minimale Höhe der Wand: 0 m; Maximale Höhe der Wandschicht an der Außenseite: 3.5 m; Minimale Höhe der Wandschicht an der Außenseite: 0 m; Luftschichtdicke: 0 m; Wand-Schichtdicke an der Innenseite: 0.0125 m; Wand-Schichtdicke an der Außenseite: 0.0125 m; Fläche der Fenster: 0 m2; Kombinierte Breite der Fenster: 0 m; Wandstärke am Ende: 0.125 m; Oberflächenbereich der leeren Öffnungen in der Wand: 0 m2
Component Quantities - Component 1, Schichtdicke: 0.0125 m; Component 1, Schicht/Komponente Höhe (rechteckig): 3.75 m; Component 1, Schicht/Komponente Breite (rechteckig): 0.0125 m; Component 1, Schicht/Komponente Querschnittsbereich: 0.046875 m2; Component 2, Schichtdicke: 0.0125 m; Component 2, Schicht/Komponente Höhe (rechteckig): 3.75 m; Component 2, Schicht/Komponente Breite (rechteckig): 0.0125 m; Component 2, Schicht/Komponente Querschnittsbereich: 0.046875 m2; Component 3, Schichtdicke: 0.075 m; Component 3, Schicht/Komponente Höhe (rechteckig): 3.75 m; Component 3, Schicht/Komponente Breite (rechteckig): 0.075 m; Component 3, Schicht/Komponente Querschnittsbereich: 0.28125 m2; Component 4, Schichtdicke: 0.0125 m; Component 4, Schicht/Komponente Höhe (rechteckig): 3.75 m; Component 4, Schicht/Komponente Breite (rechteckig): 0.0125 m; Component 4, Schicht/Komponente Querschnittsbereich: 0.046875 m2; Component 5, Schichtdicke: 0.0125 m; Component 5, Schicht/Komponente Höhe (rechteckig): 3.75 m; Component 5, Schicht/Komponente Breite (rechteckig): 0.0125 m; Component 5, Schicht/Komponente Querschnittsbereich: 0.046875 m2
Name | Element ID = Hotlink und Element-ID = Überobjekt-ID | Kollidierende Räume | Zugehöriger Raumname | Zugehörige Raumnummer | Lage der Referenzlinie | Component 1, Enthaltenes CO2 | Component 1, Enthaltene Energie (MJ) | Component 2, Enthaltenes CO2 | Component 2, Enthaltene Energie (MJ) | Component 3, Enthaltenes CO2 | Component 3, Enthaltene Energie (MJ) | Component 4, Enthaltenes CO2 | Component 4, Enthaltene Energie (MJ) | Component 5, Enthaltenes CO2 | Component 5, Enthaltene Energie (MJ) | Length (m) = Durchschnittliche Länge der Wand (m) = Länge der Wand in der Achse (m) | GrossFootprintArea (m2) = NetFootprintArea (m2) = Fläche (m2) = Fläche der Wand (m2) | GrossSideArea (m2) | NetSideArea (m2) | GrossVolume (m3) = Konditionales Volumen (m3) | NetVolume (m3) = Netto-Volumen (m3) | Oberflächenbereich (m2) = Netto-Oberflächenbereich an der Außenseite (m2) | 3D-Länge (m) | Brutto-Volumen (m3) | Grundriss-Umfang (m) | Anzahl der Türen | Fläche der Türen (m2) = Analytische Oberfläche der Öffnungen an der Innenseite (m2) = Analytische Oberfläche der Öffnungen an der Außenseite (m2) | Kombinierte Breite der Türen (m) | Wand-Schichtvolumen an der Innenseite (m3) | Wand-Schichtvolumen an der Außenseite (m3) | Netto-Oberflächenbereich an den Kanten (m2) | Netto-Oberflächenbereich an der Innenseite (m2) | Analytisches Volumen der Öffnungen (m3) | Länge der Referenzlinie (m) | Konditionale Länge an der Innenseite (m) = Wandlänge an der Innenseite (m) | Konditionaler Oberflächenbereich an der Innenseite (m2) | Konditionale Länge an der Außenseite (m) = Wandlänge an der Außenseite (m) | Konditionaler Oberflächenbereich an der Außenseite (m2) | Konditionales Wand-Schichtvolumen an der Innenseite (m3) | Konditionales Schichtvolumen an der Außenseite (m3) | Brutto-Wandoberflächenbereich an der Innenseite (m2) = Brutto-Wandoberflächenbereich an der Außenseite (m2) | Component 1, Masse (kg) | Component 1, Schicht/Komponente Oberflächenbereich (m2) | Component 1, Schicht/Komponente Volumen (m3) | Component 2, Masse (kg) | Component 2, Schicht/Komponente Oberflächenbereich (m2) | Component 2, Schicht/Komponente Volumen (m3) | Component 3, Masse (kg) | Component 3, Schicht/Komponente Oberflächenbereich (m2) | Component 3, Schicht/Komponente Volumen (m3) | Component 4, Masse (kg) | Component 4, Schicht/Komponente Oberflächenbereich (m2) | Component 4, Schicht/Komponente Volumen (m3) | Component 5, Masse (kg) | Component 5, Schicht/Komponente Oberflächenbereich (m2) | Component 5, Schicht/Komponente Volumen (m3)
Wand-011 | Wand-011 | Erdgeschoss; Grundfläche Gebäude Nachgezogen; Wohnung1 EG | Wohnen | R-006 | Innen | 31.4803 (kgCO₂) | 544.852 | 31.0964 (kgCO₂) | 538.207 | 9.555 (kgCO₂) | 191.1 | 28.4091 (kgCO₂) | 491.695 | 28.0252 (kgCO₂) | 485.051 | 1.925 | 0.240625 | 6.78125 | 6.78125 | 0.864062 | 0.864062 | 7.175 | 2.05 | 0.960938 | 4.20355 | 0 | 0 | 0 | 0.0798438 | 0.0896875 | 0.246875 | 6.3875 | 0 | 2.05 | 1.8 | 6.3875 | 2.05 | 7.175 | 0.0798438 | 0.0896875 | 7.6875 | 80.7188 | 7.175 | 0.0896875 | 79.7344 | 7.0875 | 0.0885937 | 7.35 | 7 | 0.525 | 72.8438 | 6.475 | 0.0809375 | 71.8594 | 6.3875 | 0.0798438
Wand-013 | Wand-013 | Erdgeschoss; Grundfläche Gebäude Nachgezogen; Wohnung2 EG | Bad | R-008 | Außen | 15.2297 (kgCO₂) | 263.59 | 15.4216 (kgCO₂) | 266.913 | 4.85756 (kgCO₂) | 97.1511 | 16.7653 (kgCO₂) | 290.169 | 16.9572 (kgCO₂) | 293.491 | 1.5625 | 0.195312 | 5.44687 | 3.66802 | 0.672656 | 0.4503 | 3.8649 | 1.6125 | 0.84375 | 3.42678 | 1 | 1.77885 | 0.885 | 0.0433894 | 0.0483112 | 0.192187 | 3.47115 | 0.222356 | 1.675 | 1.5 | 5.25 | 1.625 | 5.64375 | 0.065625 | 0.0705469 | 6.75 | 39.0504 | 3.47115 | 0.0433894 | 39.5426 | 3.5149 | 0.0439362 | 3.73658 | 3.55865 | 0.266899 | 42.9879 | 3.82115 | 0.0477644 | 43.4801 | 3.8649 | 0.0483112
Wand-012 | Wand-012 | Erdgeschoss; Grundfläche Gebäude Nachgezogen; Wohnung2 EG | Wohnen | R-004 | Außen | 23.0344 (kgCO₂) | 398.672 | 23.2263 (kgCO₂) | 401.994 | 7.28569 (kgCO₂) | 145.714 | 24.57 (kgCO₂) | 425.25 | 24.762 (kgCO₂) | 428.572 | 1.5625 | 0.195312 | 5.44688 | 5.44688 | 0.672656 | 0.672656 | 5.64375 | 1.6125 | 0.761719 | 3.42678 | 0 | 0 | 0 | 0.065625 | 0.0705469 | 0.629687 | 5.25 | 0 | 1.5 | 1.5 | 5.25 | 1.625 | 5.64375 | 0.065625 | 0.0705469 | 6.09375 | 59.0625 | 5.25 | 0.065625 | 59.5547 | 5.29375 | 0.0661719 | 5.60438 | 5.3375 | 0.400313 | 63 | 5.6 | 0.07 | 63.4922 | 5.64375 | 0.0705469
Wand-011 | Wand-011 | Erdgeschoss; Grundfläche Gebäude Nachgezogen; Wohnung2 EG | Bad | R-008 | Innen | 28.0252 (kgCO₂) | 485.051 | 28.4091 (kgCO₂) | 491.695 | 9.555 (kgCO₂) | 191.1 | 31.0964 (kgCO₂) | 538.207 | 31.4803 (kgCO₂) | 544.852 | 1.925 | 0.240625 | 6.78125 | 6.78125 | 0.864062 | 0.864062 | 7.175 | 2.05 | 0.960938 | 4.20355 | 0 | 0 | 0 | 0.0798438 | 0.0896875 | 0.246875 | 6.3875 | 0 | 2.05 | 1.8 | 6.3875 | 2.05 | 7.175 | 0.0798438 | 0.0896875 | 7.6875 | 71.8594 | 6.3875 | 0.0798438 | 72.8438 | 6.475 | 0.0809375 | 7.35 | 7 | 0.525 | 79.7344 | 7.0875 | 0.0885937 | 80.7188 | 7.175 | 0.0896875
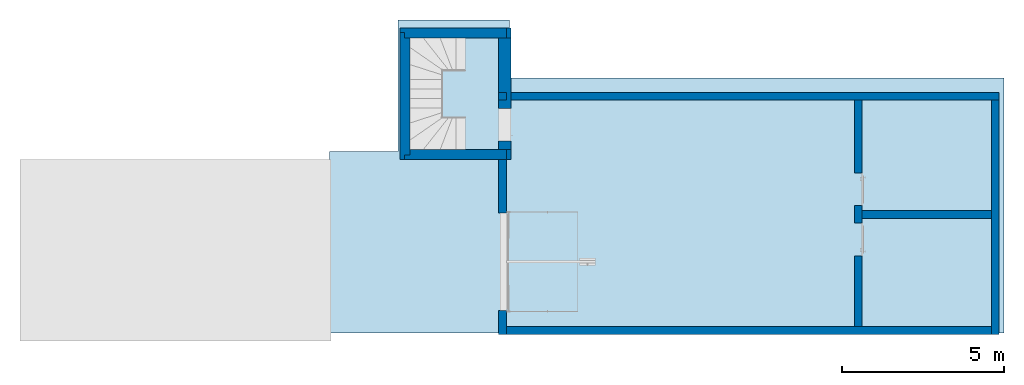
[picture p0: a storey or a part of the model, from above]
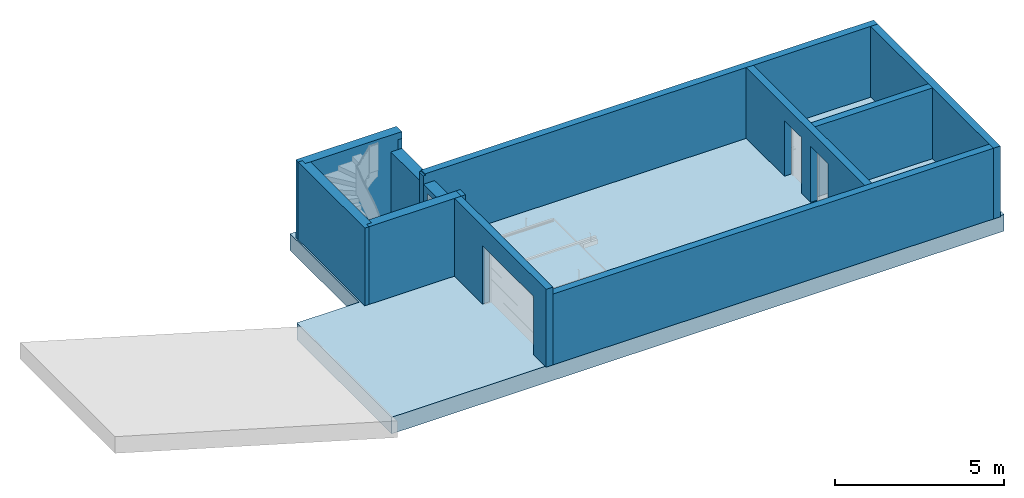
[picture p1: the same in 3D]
Properties of the parts of a building model (IFC4), part 13 of 13

# IfcWall: WI | GK 12 2-lagig 125 (6)
Name | Element ID = Hotlink und Element-ID = Überobjekt-ID | Kollidierende Räume | Zugehöriger Raumname | Zugehörige Raumnummer | Lage der Referenzlinie | Component 1, Enthaltenes CO2 | Component 1, Enthaltene Energie (MJ) | Component 2, Enthaltenes CO2 | Component 2, Enthaltene Energie (MJ) | Component 3, Enthaltenes CO2 | Component 3, Enthaltene Energie (MJ) | Component 4, Enthaltenes CO2 | Component 4, Enthaltene Energie (MJ) | Component 5, Enthaltenes CO2 | Component 5, Enthaltene Energie (MJ) | Length (m) = Durchschnittliche Länge der Wand (m) = Länge der Wand in der Achse (m) | GrossFootprintArea (m2) = NetFootprintArea (m2) = Fläche (m2) = Fläche der Wand (m2) | GrossSideArea (m2) | NetSideArea (m2) | GrossVolume (m3) = Konditionales Volumen (m3) | NetVolume (m3) = Netto-Volumen (m3) | Oberflächenbereich (m2) = Netto-Oberflächenbereich an der Außenseite (m2) | 3D-Länge (m) | Brutto-Volumen (m3) | Grundriss-Umfang (m) | Anzahl der Türen | Fläche der Türen (m2) = Analytische Oberfläche der Öffnungen an der Innenseite (m2) = Analytische Oberfläche der Öffnungen an der Außenseite (m2) | Kombinierte Breite der Türen (m) | Wand-Schichtvolumen an der Innenseite (m3) | Wand-Schichtvolumen an der Außenseite (m3) | Netto-Oberflächenbereich an den Kanten (m2) | Netto-Oberflächenbereich an der Innenseite (m2) | Analytisches Volumen der Öffnungen (m3) | Länge der Referenzlinie (m) | Konditionale Länge an der Innenseite (m) = Wandlänge an der Innenseite (m) | Konditionaler Oberflächenbereich an der Innenseite (m2) | Konditionale Länge an der Außenseite (m) = Wandlänge an der Außenseite (m) | Konditionaler Oberflächenbereich an der Außenseite (m2) | Konditionales Wand-Schichtvolumen an der Innenseite (m3) | Konditionales Schichtvolumen an der Außenseite (m3) | Brutto-Wandoberflächenbereich an der Innenseite (m2) = Brutto-Wandoberflächenbereich an der Außenseite (m2) | Component 1, Masse (kg) | Component 1, Schicht/Komponente Oberflächenbereich (m2) | Component 1, Schicht/Komponente Volumen (m3) | Component 2, Masse (kg) | Component 2, Schicht/Komponente Oberflächenbereich (m2) | Component 2, Schicht/Komponente Volumen (m3) | Component 3, Masse (kg) | Component 3, Schicht/Komponente Oberflächenbereich (m2) | Component 3, Schicht/Komponente Volumen (m3) | Component 4, Masse (kg) | Component 4, Schicht/Komponente Oberflächenbereich (m2) | Component 4, Schicht/Komponente Volumen (m3) | Component 5, Masse (kg) | Component 5, Schicht/Komponente Oberflächenbereich (m2) | Component 5, Schicht/Komponente Volumen (m3)
Wand-012 | Wand-012 | Erdgeschoss; Grundfläche Gebäude Nachgezogen; Wohnung1 EG | Wohnen | R-005 | Außen | 24.762 (kgCO₂) | 428.572 | 24.57 (kgCO₂) | 425.25 | 7.28569 (kgCO₂) | 145.714 | 23.2263 (kgCO₂) | 401.994 | 23.0344 (kgCO₂) | 398.672 | 1.5625 | 0.195312 | 5.44688 | 5.44688 | 0.672656 | 0.672656 | 5.64375 | 1.6125 | 0.84375 | 3.42678 | 0 | 0 | 0 | 0.065625 | 0.0705469 | 0.192188 | 5.25 | 0 | 1.5 | 1.5 | 5.25 | 1.625 | 5.64375 | 0.065625 | 0.0705469 | 6.75 | 63.4922 | 5.64375 | 0.0705469 | 63 | 5.6 | 0.07 | 5.60438 | 5.3375 | 0.400313 | 59.5547 | 5.29375 | 0.0661719 | 59.0625 | 5.25 | 0.065625
Wand-013 | Wand-013 | Erdgeschoss; Grundfläche Gebäude Nachgezogen; Wohnung1 EG | Wohnen | R-006 | Außen | 16.9572 (kgCO₂) | 293.491 | 16.7653 (kgCO₂) | 290.169 | 4.85756 (kgCO₂) | 97.1511 | 15.4216 (kgCO₂) | 266.913 | 15.2297 (kgCO₂) | 263.59 | 1.5625 | 0.195312 | 5.44688 | 3.66803 | 0.672656 | 0.4503 | 3.8649 | 1.6125 | 0.84375 | 3.42678 | 1 | 1.77885 | 0.885 | 0.0433894 | 0.0483113 | 0.192188 | 3.47115 | 0.222356 | 1.5 | 1.5 | 5.25 | 1.625 | 5.64375 | 0.065625 | 0.0705469 | 6.75 | 43.4801 | 3.8649 | 0.0483113 | 42.9879 | 3.82115 | 0.0477644 | 3.73658 | 3.55865 | 0.266899 | 39.5426 | 3.5149 | 0.0439363 | 39.0504 | 3.47115 | 0.0433894

# IfcWall: WI | GK 15 2-lagig 150 (4)
In: OG
Classification: Wand (ARCHICAD Klassifizierung); Material: Gipskarton (4), Dämmung, weich Glaswolle
ArchiCADProperties - Element ID: Wand-012; Hotlink und Element-ID: Wand-012; Ebene: Wand Aussen; Baustoff / Mehrschichtiger Aufbau / Profil / Schraffur: WI | GK 15 2-lagig; Mehrschichtige Bauteile: WI | GK 15 2-lagig; Kollidierende Räume: Grundfläche Gebäude Nachgezogen; Obergeschoss; Wohnung1 OG; Zugehöriger Raumname: Luftraum Dach; Zugehörige Raumnummer: R-012; Geschützt: no; Ursprungsgeschoss Name: 1. OG; Ursprungsgeschoss Nummer: 1; Typ: Wand; Absolutes Geschoss für Oberkantenverknüpfung: Nicht verknüpft; Relatives Geschoss für Oberkantenverknüpfung: Nicht verknüpft; Geschoss für Oberkantenverknüpfung: Nicht verknüpft; Struktur-Typ: Mehrschicht; Überobjekt-ID: Wand-012; Baustoffe (Alle): Gipskarton; Gipskarton; Dämmung, weich Glaswolle; Gipskarton; Gipskarton; Oberfläche (Alle): Farbe, weiß; Metall, Fassade Edelstahl; Mineralwolle; Neigungswinkel: 90 deg; Lage: Außen; Tragende Funktion: Tragende Elemente; Anzeigen auf Umbau-Filter: Alle relevanten Filter; Umbau-Status: Bestand; Wandkomplexität: gerade; Geometriemethode: Uni; Lage der Referenzlinie: Innen; Innenseite Oberfläche: Farbe, weiß; Außenseite Oberfläche: Farbe, weiß; Wand Innerer Neigungswinkel: 90 deg; Wand Äußerer Neigungswinkel: 90 deg; ARCHICAD Klassifizierung - 22: Wand
Brandschutz 4102-2 - Kennbuchstabe: F
Pset_WallCommon - LoadBearing: yes; IsExternal: yes
Component Properties - Component 1, Komponenten-Typ: Kern; Component 2, Komponenten-Typ: Kern; Component 3, Komponenten-Typ: Kern; Component 4, Komponenten-Typ: Kern; Component 5, Komponenten-Typ: Kern
BaseQuantities - Width: 0.15 m
ArchiCADQuantities - Breite: 0.15 m; Höhenangabe zum Projekt-Nullpunkt: 3.75 m; Höhe zu 1. Referenzhöhe: 3.75 m; Höhe zu 2. Referenzhöhe: 3.75 m; Höhe zu Meereshöhe: 19.75 m; Höhe zu verknüpftem/Ursprungsgeschoss: 0 m; Abstand zu Ursprungsgeschoss: 0 m; Abstand Oberkante: 0 m; Dicke: 0.15 m; Dämmungsschichtdicke: 0.1 m; Anzahl der Türen: 0; Anzahl der Durchbrüche (Anzahl der leeren Öffnungen): 0; Anzahl der Fenster: 0; Anzahl der Stützen: 0; Volumen der Stützen: 0 m3; Minimale Höhe der Wand: 0 m; Luftschichtdicke: 0 m; Fläche der Türen: 0 m2; Kombinierte Breite der Türen: 0 m; Wand-Schichtdicke an der Innenseite: 0.0125 m; Wand-Schichtdicke an der Außenseite: 0.0125 m; Fläche der Fenster: 0 m2; Kombinierte Breite der Fenster: 0 m; Analytische Oberfläche der Öffnungen an der Innenseite: 0 m2; Analytische Oberfläche der Öffnungen an der Außenseite: 0 m2; Analytisches Volumen der Öffnungen: 0 m3; Wandstärke am Ende: 0.15 m; Oberflächenbereich der leeren Öffnungen in der Wand: 0 m2
Component Quantities - Component 1, Schichtdicke: 0.0125 m; Component 1, Schicht/Komponente Breite (rechteckig): 0.0125 m; Component 2, Schichtdicke: 0.0125 m; Component 2, Schicht/Komponente Breite (rechteckig): 0.0125 m; Component 3, Schichtdicke: 0.1 m; Component 3, Schicht/Komponente Breite (rechteckig): 0.1 m; Component 4, Schichtdicke: 0.0125 m; Component 4, Schicht/Komponente Breite (rechteckig): 0.0125 m; Component 5, Schichtdicke: 0.0125 m; Component 5, Schicht/Komponente Breite (rechteckig): 0.0125 m
Name | Component 1, Enthaltenes CO2 = Component 2, Enthaltenes CO2 = Component 4, Enthaltenes CO2 = Component 5, Enthaltenes CO2 | Component 1, Enthaltene Energie (MJ) = Component 2, Enthaltene Energie (MJ) = Component 4, Enthaltene Energie (MJ) = Component 5, Enthaltene Energie (MJ) | Component 3, Enthaltenes CO2 | Component 3, Enthaltene Energie (MJ) | Length (m) = Durchschnittliche Länge der Wand (m) = Länge der Wand in der Achse (m) | Height (m) = Maximale Höhe der Wandschicht an der Innenseite (m) = Maximale Höhe der Wand (m) = Maximale Höhe der Wandschicht an der Außenseite (m) | GrossFootprintArea (m2) = NetFootprintArea (m2) = Fläche (m2) = Fläche der Wand (m2) | GrossSideArea (m2) = NetSideArea (m2) = Oberflächenbereich (m2) = Netto-Oberflächenbereich an der Innenseite (m2) = Netto-Oberflächenbereich an der Außenseite (m2) = Konditionaler Oberflächenbereich an der Innenseite (m2) = Konditionaler Oberflächenbereich an der Außenseite (m2) = Component 1, Schicht/Komponente Oberflächenbereich (m2) = Component 2, Schicht/Komponente Oberflächenbereich (m2) = Component 3, Schicht/Komponente Oberflächenbereich (m2) = Component 4, Schicht/Komponente Oberflächenbereich (m2) = Component 5, Schicht/Komponente Oberflächenbereich (m2) | GrossVolume (m3) = NetVolume (m3) = Netto-Volumen (m3) = Konditionales Volumen (m3) | Höhe (m) = Component 1, Schicht/Komponente Höhe (rechteckig) (m) = Component 2, Schicht/Komponente Höhe (rechteckig) (m) = Component 3, Schicht/Komponente Höhe (rechteckig) (m) = Component 4, Schicht/Komponente Höhe (rechteckig) (m) = Component 5, Schicht/Komponente Höhe (rechteckig) (m) | 3D-Länge (m) = Länge der Referenzlinie (m) = Konditionale Länge an der Außenseite (m) = Wandlänge an der Außenseite (m) | Brutto-Volumen (m3) | Grundriss-Umfang (m) | Minimale Höhe der Wandschicht an der Innenseite (m) | Minimale Höhe der Wandschicht an der Außenseite (m) | Wand-Schichtvolumen an der Innenseite (m3) = Component 1, Schicht/Komponente Volumen (m3) | Wand-Schichtvolumen an der Außenseite (m3) = Konditionales Schichtvolumen an der Außenseite (m3) = Component 2, Schicht/Komponente Volumen (m3) = Component 4, Schicht/Komponente Volumen (m3) = Component 5, Schicht/Komponente Volumen (m3) | Netto-Oberflächenbereich an den Kanten (m2) | Konditionale Länge an der Innenseite (m) = Wandlänge an der Innenseite (m) | Konditionales Wand-Schichtvolumen an der Innenseite (m3) | Brutto-Wandoberflächenbereich an der Innenseite (m2) = Brutto-Wandoberflächenbereich an der Außenseite (m2) | Component 1, Masse (kg) | Component 1, Schicht/Komponente Querschnittsbereich (m2) = Component 2, Schicht/Komponente Querschnittsbereich (m2) = Component 4, Schicht/Komponente Querschnittsbereich (m2) = Component 5, Schicht/Komponente Querschnittsbereich (m2) | Component 2, Masse (kg) = Component 4, Masse (kg) = Component 5, Masse (kg) | Component 3, Masse (kg) | Component 3, Schicht/Komponente Querschnittsbereich (m2) | Component 3, Schicht/Komponente Volumen (m3)
Wand-012 | 8.21934 (kgCO₂) | 142.258 | 3.4095 (kgCO₂) | 68.1901 | 1.97258 | 1.75149 | 0.295886 | 1.87335 | 0.281003 | 2.75 | 1.97258 | 0.936647 | 4.24515 | 0 | 3.93025e-09 | 0.0234169 | 0.0234169 | 0.0234222 | 1.97258 | 0.023417 | 6.24431 | 21.0752 | 0.034375 | 21.0752 | 2.6227 | 0.275 | 0.187335
Wand-012 | 8.21934 (kgCO₂) | 142.258 | 3.4095 (kgCO₂) | 68.1901 | 2.16008 | 1.75149 | 0.324011 | 1.87335 | 0.281003 | 2.75 | 1.97258 | 0.936647 | 4.87404 | 1.81798e-10 | 0 | 0.0234169 | 0.0234169 | 0.0234222 | 2.34758 | 0.0234169 | 6.24431 | 21.0752 | 0.034375 | 21.0752 | 2.6227 | 0.275 | 0.187335
Wand-012 | 1.96703 (kgCO₂) | 34.0447 | 0.815951 (kgCO₂) | 16.319 | 1.08956 | 0.868996 | 0.163434 | 0.448325 | 0.0672487 | 2.7844 | 0.902059 | 0.524939 | 2.73301 | 0 | 0 | 0.00560406 | 0.00560406 | 0.0290518 | 1.27706 | 0.00560406 | 3.49959 | 5.04365 | 0.034805 | 5.04365 | 0.627655 | 0.27844 | 0.0448325
Wand-012 | 1.96703 (kgCO₂) | 34.0447 | 0.815951 (kgCO₂) | 16.319 | 1.08956 | 0.868996 | 0.163434 | 0.448325 | 0.0672487 | 2.7844 | 0.902059 | 0.524939 | 2.73301 | 0 | 0 | 0.00560407 | 0.00560406 | 0.0290518 | 1.27706 | 0.00560407 | 3.49959 | 5.04366 | 0.034805 | 5.04365 | 0.627655 | 0.27844 | 0.0448325

# IfcWall: WI | MW_tr 175 (6)
In: EG
Classification: Wand (ARCHICAD Klassifizierung); Material: MW Kalksandstein
Pset_WallCommon - LoadBearing: yes
ArchiCADProperties - Baustoff / Mehrschichtiger Aufbau / Profil / Schraffur: WI | MW_tr; Mehrschichtige Bauteile: WI | MW_tr; Geschützt: no; Ursprungsgeschoss Name: EG; Ursprungsgeschoss Nummer: 0; Typ: Wand; Absolutes Geschoss für Oberkantenverknüpfung: Nicht verknüpft; Relatives Geschoss für Oberkantenverknüpfung: Nicht verknüpft; Geschoss für Oberkantenverknüpfung: Nicht verknüpft; Struktur-Typ: Mehrschicht; Baustoffe (Alle): MW Kalksandstein; Oberfläche (Alle): Farbe, weiß; Neigungswinkel: 90 deg; Tragende Funktion: Tragende Elemente; Anzeigen auf Umbau-Filter: Alle relevanten Filter; Umbau-Status: Bestand; Wandkomplexität: gerade; Geometriemethode: Uni; Lage der Referenzlinie: Außen; Innenseite Oberfläche: Farbe, weiß; Außenseite Oberfläche: Farbe, weiß; Wand Innerer Neigungswinkel: 90 deg; Wand Äußerer Neigungswinkel: 90 deg; ARCHICAD Klassifizierung - 22: Wand
Brandschutz 4102-2 - Kennbuchstabe: F
Component Properties - Component 1, Komponenten-Typ: Kern
BaseQuantities - Width: 0.175 m
ArchiCADQuantities - Breite: 0.175 m; Dicke: 0.175 m; Dämmungsschichtdicke: 0 m; Anzahl der Durchbrüche (Anzahl der leeren Öffnungen): 0; Anzahl der Fenster: 0; Anzahl der Stützen: 0; Volumen der Stützen: 0 m3; Minimale Höhe der Wandschicht an der Innenseite: 0 m; Minimale Höhe der Wand: 0 m; Minimale Höhe der Wandschicht an der Außenseite: 0 m; Luftschichtdicke: 0 m; Wand-Schichtdicke an der Innenseite: 0.175 m; Wand-Schichtdicke an der Außenseite: 0.175 m; Fläche der Fenster: 0 m2; Kombinierte Breite der Fenster: 0 m; Wandstärke am Ende: 0.175 m; Oberflächenbereich der leeren Öffnungen in der Wand: 0 m2
Component Quantities - Component 1, Schichtdicke: 0.175 m; Component 1, Schicht/Komponente Breite (rechteckig): 0.175 m
Name | Pset_ConcreteElementGeneral, FireRating = Pset_WallCommon, FireRating = FireResistanceRating = Feuerwiderstand 4102-2 | IsExternal | Element ID = Hotlink und Element-ID = Überobjekt-ID | Ebene | Kollidierende Räume | Zugehöriger Raumname | Zugehörige Raumnummer | Lage | Brandwand | Minuten (4102-2) | Baustoffklasse | Component 1, Enthaltenes CO2 | Component 1, Enthaltene Energie (MJ) | Length (m) = Durchschnittliche Länge der Wand (m) = Länge der Wand in der Achse (m) | Height (m) = Maximale Höhe der Wandschicht an der Innenseite (m) = Maximale Höhe der Wand (m) = Maximale Höhe der Wandschicht an der Außenseite (m) | GrossFootprintArea (m2) = NetFootprintArea (m2) = Fläche (m2) = Fläche der Wand (m2) | GrossSideArea (m2) | NetSideArea (m2) = Oberflächenbereich (m2) = Netto-Oberflächenbereich an der Außenseite (m2) | GrossVolume (m3) | NetVolume (m3) = Netto-Volumen (m3) = Wand-Schichtvolumen an der Innenseite (m3) = Wand-Schichtvolumen an der Außenseite (m3) = Component 1, Schicht/Komponente Volumen (m3) | Höhe (m) = Component 1, Schicht/Komponente Höhe (rechteckig) (m) | Höhenangabe zum Projekt-Nullpunkt (m) = Höhe zu 1. Referenzhöhe (m) = Höhe zu 2. Referenzhöhe (m) = Höhe zu verknüpftem/Ursprungsgeschoss (m) = Abstand zu Ursprungsgeschoss (m) | Höhe zu Meereshöhe (m) | Abstand Oberkante (m) | 3D-Länge (m) | Konditionales Volumen (m3) = Konditionales Wand-Schichtvolumen an der Innenseite (m3) = Konditionales Schichtvolumen an der Außenseite (m3) | Brutto-Volumen (m3) | Grundriss-Umfang (m) | Anzahl der Türen | Fläche der Türen (m2) | Kombinierte Breite der Türen (m) | Analytische Oberfläche der Öffnungen an der Innenseite (m2) = Analytische Oberfläche der Öffnungen an der Außenseite (m2) | Netto-Oberflächenbereich an den Kanten (m2) | Netto-Oberflächenbereich an der Innenseite (m2) = Component 1, Schicht/Komponente Oberflächenbereich (m2) | Analytisches Volumen der Öffnungen (m3) | Länge der Referenzlinie (m) = Wandlänge an der Innenseite (m) | Konditionale Länge an der Innenseite (m) | Konditionaler Oberflächenbereich an der Innenseite (m2) | Konditionale Länge an der Außenseite (m) | Konditionaler Oberflächenbereich an der Außenseite (m2) | Brutto-Wandoberflächenbereich an der Innenseite (m2) = Brutto-Wandoberflächenbereich an der Außenseite (m2) | Wandlänge an der Außenseite (m) | Component 1, Masse (kg) | Component 1, Schicht/Komponente Querschnittsbereich (m2)
Wand-003 | F 90 | no | Wand-003 | Wand Innen | Erdgeschoss; Grundfläche Gebäude Nachgezogen; Untergeschoss UG; Wohnung2 EG | Wohnen | R-009 | Innen | yes | 90 | A | 95.3294 (kgCO₂) | 1634.22 | 1.6075 | 3.6 | 0.281312 | 6.102 | 4.32333 | 1.06785 | 0.756582 | 3.8 | -0.5 | 15.5 | 0 | 1.695 | 1.06785 | 1.15474 | 3.63749 | 1 | 1.77885 | 0.885 | 1.77867 | 0.296625 | 4.32333 | 0.311268 | 1.695 | 1.695 | 6.102 | 1.52 | 6.102 | 6.5985 | 1.52 | 1361.85 | 0.665
Wand-004 | F 90 | yes | Wand-004 | Wand Aussen | Erdgeschoss; Grundfläche Gebäude Nachgezogen; Wohnung1 EG | Wohnen | R-005 | Außen | yes | 90 | A | 847.99 (kgCO₂) | 14537 | 10.825 | 3.75 | 1.89438 | 38.4576 | 38.4576 | 6.73008 | 6.73008 | 3.75 | 0 | 16 | 0 | 10.845 | 6.73008 | 7.35 | 22 | 0 | 0 | 0 | 0 | 2.90419 | 38.4576 | 0 | 10.825 | 10.825 | 38.4576 | 10.825 | 38.4576 | 42 | 10.825 | 12114.1 | 0.65625
Wand-006 |  | no | Wand-006 | Wand Innen | Erdgeschoss; Grundfläche Gebäude Nachgezogen; Wohnung2 EG | Wohnen | R-004 | Innen | no |  |  | 193.542 (kgCO₂) | 3317.86 | 3.355 | 3.5 | 0.587125 | 11.8125 | 8.7774 | 2.06719 | 1.53604 | 3.75 | 0 | 16 | 0 | 3.375 | 1.53604 | 2.44781 | 7.06 | 1 | 3.0351 | 1.51 | 3.0351 | 1.20312 | 8.7774 | 0.531142 | 3.355 | 1.845 | 8.7774 | 1.845 | 8.7774 | 13.9875 | 3.355 | 2764.88 | 0.65625 | Pset_WallCommon - ExtendToStructure: yes
Wand-004 | F 90 | yes | Wand-004 | Wand Aussen | Erdgeschoss; Grundfläche Gebäude Nachgezogen; Wohnung2 EG | Wohnen | R-004 | Außen | yes | 90 | A | 861.496 (kgCO₂) | 14768.5 | 11.1 | 3.75 | 1.9425 | 39.0701 | 39.0701 | 6.83727 | 6.83727 | 3.75 | 0 | 16 | 0 | 11.02 | 6.83727 | 7.45106 | 22.8613 | 0 | 0 | 0 | 0 | 2.27857 | 39.0701 | 0 | 10.825 | 10.825 | 39.0701 | 11.375 | 39.0701 | 42.5775 | 11.375 | 12307.1 | 0.65625
Wand-003 | F 90 | no | Wand-003 | Wand Innen | Erdgeschoss; Grundfläche Gebäude Nachgezogen; Treppenhaus; Untergeschoss UG; Wohnung1 EG | Treppenhaus | R-010 | Innen | yes | 90 | A | 95.1436 (kgCO₂) | 1631.03 | 1.6951 | 3.6 | 0.296642 | 6.09357 | 4.3149 | 1.06638 | 0.755108 | 3.8 | -0.5 | 15.5 | -0.45 | 1.6951 | 1.06638 | 1.12724 | 3.74019 | 1 | 1.77885 | 0.885 | 1.77867 | 1.49539 | 4.31491 | 0.311268 | 1.6951 | 1.6951 | 6.09358 | 1.6951 | 6.09357 | 6.44137 | 1.6951 | 1359.19 | 0.665
Wand-006 |  | no | Wand-006 | Wand Innen | Erdgeschoss; Grundfläche Gebäude Nachgezogen; Wohnung1 EG | Wohnen | R-005 | Innen | no |  | B | 347.892 (kgCO₂) | 5963.86 | 5.355 | 3.5 | 0.937125 | 18.8125 | 15.7774 | 3.29219 | 2.76104 | 3.75 | 0 | 16 | 0 | 5.375 | 2.76104 | 3.76031 | 11.06 | 1 | 3.0351 | 1.51 | 3.0351 | 1.55312 | 15.7774 | 0.531142 | 5.355 | 3.845 | 15.7774 | 3.845 | 15.7774 | 21.4875 | 5.355 | 4969.88 | 0.65625

# IfcWall: Wandabschluss 2 22 (2)
In: -1. Geschoss
Classification: Wand (ARCHICAD Klassifizierung); Material: Dämmung, hart XPS
ArchiCADProperties - Ebene: Wand Aussen; Bibliothekselement-Name: Wandabschluss 2 22; Baustoff / Mehrschichtiger Aufbau / Profil / Schraffur: Misch-Schraffur 100 %; Schraffurtyp: Misch-Schraffur 100 %; Geschützt: no; Ursprungsgeschoss Name: -1. Geschoss; Ursprungsgeschoss Nummer: -1; Typ: Wandabschluss; Überobjekt-ID: Wand-001; Baustoffe (Alle): Dämmung, hart XPS; Oberfläche (Alle): Farbe, hellblau; Tragende Funktion: Nicht tragende Elemente; Anzeigen auf Umbau-Filter: Alle relevanten Filter; Umbau-Status: Bestand; Wandstruktur: WA | StB Kellerwand 17 + WD; Ausrichtung: L; Öffnung Bibliothekselementname: Wandabschluss 2 22; Öffnungsseite Schraffurindex: Misch-Schraffur 100 %; ARCHICAD Klassifizierung - 22: Wand
AC_Pset_Wandabschluss_2_22 - Fixpunkte 0-Kein,1-2D,2-3D,3-Alle: 0; 2D-Fixpunkte in 3D zeigen: yes; Loch übernimmt das Oberflächenmaterial der Wandseite: no; Öffnungsoberfläche ist gebogen in gebogenen Wänden: no; 3D-Darstellung (b3DRepresentation): yes; Wenderichtung spiegeln: yes; Einzuziehende Schichten: 3; Schicht 1 an Innenseite erweitern: no; Schicht 2 an Innenseite erweitern: no; Schicht 3 an Innenseite erweitern: no; Schicht 4 an Innenseite erweitern: no; Konturstift: Elemente+Text; Schraffur: Nur Hintergrund-Stift; Linie zwischen gleichen Schraffuren: no; Preis: 0; Gruppe Typ (FM_Type): Andere; Gruppe Typ (iFMType): 25; Objektgewicht: 0; Objektgewichtseinheit: kg
Pset_WallCommon - LoadBearing: no
BaseQuantities - Width: 0.14 m
ArchiCADQuantities - Breite: 0.14 m; Höhenangabe zum Projekt-Nullpunkt: -2.8 m; Höhe zu 1. Referenzhöhe: -2.8 m; Höhe zu 2. Referenzhöhe: -2.8 m; Höhe zu Meereshöhe: 13.2 m; Höhe zu verknüpftem/Ursprungsgeschoss: 0 m; Abstand zu Ursprungsgeschoss: 0 m; F/T Öffnungsbreite auf der Anschlagseite: 0.14 m; F/T Öffnungsbreite gegenüber der Anschlagseite: 0.14 m; Nominale F/T Öffnungsbreite auf der Anschlagseite: 0.14 m; Nominale F/T Öffnungsbreite gegenüber der Anschlagseite: 0.14 m; Brüstungshöhe: 0 m; F/T nominale Brüstungs-/Schwellenhöhe: 0 m; F/T Brüstungs-/Schwellenhöhe auf der Anschlagseite: 0 m; F/T Brüstungs-/Schwellenhöhe gegenüber der Anschlagseite: 0 m; Wanddicke: 0.315 m; Rahmen-Stärke: 0.315 m
AC_Equantity_Wandabschluss_2_22 - Untere Ebene: 1 m; Obere Ebene: 0 m; Abschnittsbreite: 0.14 m
Name | Element ID = Hotlink und Element-ID | Kollidierende Räume | Lage | Nominale B x H | Nominale B x H x T | An Wandhöhe anpassen | Kennbuchstabe | IsExternal | Height (m) = F/T Höhe der Öffnung auf der Anschlagseite (m) = F/T Höhe der Öffnung gegenüber der Anschlagseite (m) | GrossSideArea (m2) = NetSideArea (m2) = F/T Oberfläche der Öffnung auf der Anschlagseite (m2) = F/T Oberfläche der Öffnung gegenüber der Anschlagseite (m2) | GrossVolume (m3) = NetVolume (m3) = Netto-Volumen (m3) = F/T Volumen der Öffnung (m3) | Höhe (m) = Nominale F/T Höhe der Öffnung auf der Anschlagseite (m) = Nominale F/T Höhe der Öffnung gegenüber der Anschlagseite (m) = F/T nominale Sturzhöhe (m) = F/T Sturzhöhe auf der Anschlagseite (m) = F/T Sturzhöhe gegenüber der Anschlagseite (m) | Oberflächenbereich (m2) = F/T Oberfläche der Öffnung (m2) | F/T nominales Volumen der Öffnung (m3) | F/T Öffnung Nominaler Oberflächenbereich (m2) = Nominale F/T Öffnungsoberfläche auf der Anschlagsseite (m2) = Nominale F/T Öffnungsoberfläche auf der Seite gegenüber der Anschlagsseite (m2)
WandAbschl-013 | WandAbschl-013 | Untergeschoss UG | Innen | 0,140×1,000 | 0,140×1,000×0,315 | yes | F | no | 2.8 | 0.392 | 0.12348 | 1 | 2.6362 | 0.0441 | 0.14
WandAbschl-017 | WandAbschl-017 | Gelände; Treppenhaus UG | Außen | 0,140×2,550 | 0,140×2,550×0,315 | no | W | yes | 2.55 | 0.357 | 0.112455 | 2.55 | 2.4087 | 0.112455 | 0.357

# Material: Beton, Stahlbeton C20/25
Pset_MaterialThermal - ThermalConductivity: 1.35; SpecificHeatCapacity: 1000 J/kg/K
Pset_MaterialCommon - MassDensity: 2000 kg/m3
AC_Pset_MaterialCustom - Embodied Energy: 0.78 (MJ/kg); Embodied Carbon: 0.113 (kgCO₂/kg); Participates in Collision Detection: yes

# Material: Beton, WU-Beton
Pset_MaterialThermal - ThermalConductivity: 1.7; SpecificHeatCapacity: 800 J/kg/K
Pset_MaterialCommon - MassDensity: 2300 kg/m3
AC_Pset_MaterialCustom - Embodied Energy: 0.88 (MJ/kg); Embodied Carbon: 0.132 (kgCO₂/kg); Participates in Collision Detection: yes

# Material: Metall, Stahl lackiert
Pset_MaterialThermal - ThermalConductivity: 50; SpecificHeatCapacity: 450 J/kg/K
Pset_MaterialCommon - MassDensity: 7800 kg/m3
AC_Pset_MaterialCustom - Embodied Energy: 20.1 (MJ/kg); Embodied Carbon: 1.46 (kgCO₂/kg); Participates in Collision Detection: yes

# Material: Glas, Normalglas
Pset_MaterialThermal - ThermalConductivity: 1.4; SpecificHeatCapacity: 750 J/kg/K
Pset_MaterialCommon - MassDensity: 2200 kg/m3
AC_Pset_MaterialCustom - Embodied Energy: 0.85 (MJ/kg); Embodied Carbon: 0.02 (kgCO₂/kg); Participates in Collision Detection: yes

# Material: ALLGEMEIN - BAUTEIL
Pset_MaterialThermal - ThermalConductivity: 0.13; SpecificHeatCapacity: 1600 J/kg/K
Pset_MaterialCommon - MassDensity: 500 kg/m3
AC_Pset_MaterialCustom - Embodied Energy: 13.1 (MJ/kg); Embodied Carbon: 0.64 (kgCO₂/kg); Participates in Collision Detection: yes

# Material: Dämmung, hart XPS
Pset_MaterialThermal - ThermalConductivity: 0.032; SpecificHeatCapacity: 1450 J/kg/K
Pset_MaterialCommon - MassDensity: 28 kg/m3
AC_Pset_MaterialCustom - Embodied Energy: 87.4 (MJ/kg); Embodied Carbon: 3.42 (kgCO₂/kg); Participates in Collision Detection: yes

# Material: Verputz, Zement
Pset_MaterialThermal - ThermalConductivity: 1; SpecificHeatCapacity: 1000 J/kg/K
Pset_MaterialCommon - MassDensity: 1800 kg/m3
AC_Pset_MaterialCustom - Embodied Energy: 1.34 (MJ/kg); Embodied Carbon: 0.213 (kgCO₂/kg); Participates in Collision Detection: yes

# Material: MW Kalksandstein
Pset_MaterialThermal - ThermalConductivity: 0.93; SpecificHeatCapacity: 840 J/kg/K
Pset_MaterialCommon - MassDensity: 1800 kg/m3
AC_Pset_MaterialCustom - Embodied Energy: 1.2 (MJ/kg); Embodied Carbon: 0.07 (kgCO₂/kg); Participates in Collision Detection: yes

# Material: Dämmung, weich Mineralwolle 2
Pset_MaterialThermal - ThermalConductivity: 0.04; SpecificHeatCapacity: 840 J/kg/K
Pset_MaterialCommon - MassDensity: 160 kg/m3
AC_Pset_MaterialCustom - Embodied Energy: 23.4 (MJ/kg); Embodied Carbon: 1.73 (kgCO₂/kg); Participates in Collision Detection: yes

# Material: Gipskarton
Pset_MaterialThermal - ThermalConductivity: 0.25; SpecificHeatCapacity: 1000 J/kg/K
Pset_MaterialCommon - MassDensity: 900 kg/m3
AC_Pset_MaterialCustom - Embodied Energy: 6.75 (MJ/kg); Embodied Carbon: 0.39 (kgCO₂/kg); Participates in Collision Detection: yes

# Material: Dämmung, weich Glaswolle
Pset_MaterialThermal - ThermalConductivity: 0.04; SpecificHeatCapacity: 1030 J/kg/K
Pset_MaterialCommon - MassDensity: 14 kg/m3
AC_Pset_MaterialCustom - Embodied Energy: 26 (MJ/kg); Embodied Carbon: 1.3 (kgCO₂/kg); Participates in Collision Detection: yes

# Material: Verputz, Kalkzement
Pset_MaterialThermal - ThermalConductivity: 0.8; SpecificHeatCapacity: 1000 J/kg/K
Pset_MaterialCommon - MassDensity: 1600 kg/m3
AC_Pset_MaterialCustom - Embodied Energy: 1.45 (MJ/kg); Embodied Carbon: 0.22 (kgCO₂/kg); Participates in Collision Detection: yes

# Material: Belag, Parkett
Pset_MaterialThermal - ThermalConductivity: 0.13; SpecificHeatCapacity: 1700 J/kg/K
Pset_MaterialCommon - MassDensity: 650 kg/m3
AC_Pset_MaterialCustom - Embodied Energy: 15 (MJ/kg); Embodied Carbon: 0.9 (kgCO₂/kg); Participates in Collision Detection: yes

# Material: Belag, Kunststoff
Pset_MaterialThermal - ThermalConductivity: 0.17; SpecificHeatCapacity: 900 J/kg/K
Pset_MaterialCommon - MassDensity: 1390 kg/m3
AC_Pset_MaterialCustom - Embodied Energy: 77.2 (MJ/kg); Embodied Carbon: 3.1 (kgCO₂/kg); Participates in Collision Detection: yes

# Material: Holz, Brettschichtholz
Pset_MaterialThermal - ThermalConductivity: 0.09; SpecificHeatCapacity: 1600 J/kg/K
Pset_MaterialCommon - MassDensity: 300 kg/m3
AC_Pset_MaterialCustom - Embodied Energy: 11.9 (MJ/kg); Embodied Carbon: 0.52 (kgCO₂/kg); Participates in Collision Detection: yes

# Material: Holz, Treppenstufe
Pset_MaterialThermal - ThermalConductivity: 0.09; SpecificHeatCapacity: 1600 J/kg/K
Pset_MaterialCommon - MassDensity: 300 kg/m3
AC_Pset_MaterialCustom - Embodied Energy: 11.9 (MJ/kg); Embodied Carbon: 0.52 (kgCO₂/kg); Participates in Collision Detection: yes

# Material: Belag, Fliesen weiß
Pset_MaterialThermal - ThermalConductivity: 1.3; SpecificHeatCapacity: 1000 J/kg/K
Pset_MaterialCommon - MassDensity: 1750 kg/m3
AC_Pset_MaterialCustom - Embodied Energy: 1.5 (MJ/kg); Embodied Carbon: 0.18 (kgCO₂/kg); Participates in Collision Detection: yes

# Material: Metall, Stahl verzinkt
Pset_MaterialThermal - ThermalConductivity: 50; SpecificHeatCapacity: 450 J/kg/K
Pset_MaterialCommon - MassDensity: 7800 kg/m3
AC_Pset_MaterialCustom - Embodied Energy: 20.1 (MJ/kg); Embodied Carbon: 1.46 (kgCO₂/kg); Participates in Collision Detection: yes

# Material: Holz, Spanplatte
Pset_MaterialThermal - ThermalConductivity: 0.14; SpecificHeatCapacity: 1700 J/kg/K
Pset_MaterialCommon - MassDensity: 600 kg/m3
AC_Pset_MaterialCustom - Embodied Energy: 12.1 (MJ/kg); Embodied Carbon: 0.79 (kgCO₂/kg); Participates in Collision Detection: yes

# Material: Holz, Bauholz
Pset_MaterialThermal - ThermalConductivity: 0.13; SpecificHeatCapacity: 1600 J/kg/K
Pset_MaterialCommon - MassDensity: 500 kg/m3
AC_Pset_MaterialCustom - Embodied Energy: 6.95 (MJ/kg); Embodied Carbon: 0.29 (kgCO₂/kg); Participates in Collision Detection: yes

# Material: Boden, Pflaster
Pset_MaterialThermal - ThermalConductivity: 1.3; SpecificHeatCapacity: 1000 J/kg/K
Pset_MaterialCommon - MassDensity: 1750 kg/m3
AC_Pset_MaterialCustom - Embodied Energy: 1.5 (MJ/kg); Embodied Carbon: 0.18 (kgCO₂/kg); Participates in Collision Detection: yes

# Material: Holz, Geländer
Pset_MaterialThermal - ThermalConductivity: 0.09; SpecificHeatCapacity: 1600 J/kg/K
Pset_MaterialCommon - MassDensity: 300 kg/m3
AC_Pset_MaterialCustom - Embodied Energy: 11.9 (MJ/kg); Embodied Carbon: 0.52 (kgCO₂/kg); Participates in Collision Detection: yes

# Material: Metall, Aluminium
Pset_MaterialThermal - ThermalConductivity: 160; SpecificHeatCapacity: 880 J/kg/K
Pset_MaterialCommon - MassDensity: 2800 kg/m3
AC_Pset_MaterialCustom - Embodied Energy: 155 (MJ/kg); Embodied Carbon: 9.16 (kgCO₂/kg); Participates in Collision Detection: yes

# Material: Metall, Edelstahl
Pset_MaterialThermal - ThermalConductivity: 17; SpecificHeatCapacity: 460 J/kg/K
Pset_MaterialCommon - MassDensity: 7900 kg/m3
AC_Pset_MaterialCustom - Embodied Energy: 56.7 (MJ/kg); Embodied Carbon: 6.15 (kgCO₂/kg); Participates in Collision Detection: yes

# Material: Dach, Stehfalz
Pset_MaterialThermal - ThermalConductivity: 60; SpecificHeatCapacity: 460 J/kg/K
Pset_MaterialCommon - MassDensity: 7800 kg/m3
AC_Pset_MaterialCustom - Embodied Energy: 25.1 (MJ/kg); Embodied Carbon: 1.66 (kgCO₂/kg); Participates in Collision Detection: yes

# Material: Dämmung, hart Mineralwolle
Pset_MaterialThermal - ThermalConductivity: 0.036; SpecificHeatCapacity: 840 J/kg/K
Pset_MaterialCommon - MassDensity: 115 kg/m3
AC_Pset_MaterialCustom - Embodied Energy: 21.4 (MJ/kg); Embodied Carbon: 1.69 (kgCO₂/kg); Participates in Collision Detection: yes

# Material: Beton, Stahlbeton Fertigteil
Pset_MaterialThermal - ThermalConductivity: 1.15; SpecificHeatCapacity: 1000 J/kg/K
Pset_MaterialCommon - MassDensity: 1800 kg/m3
AC_Pset_MaterialCustom - Embodied Energy: 0.74 (MJ/kg); Embodied Carbon: 0.107 (kgCO₂/kg); Participates in Collision Detection: yes
